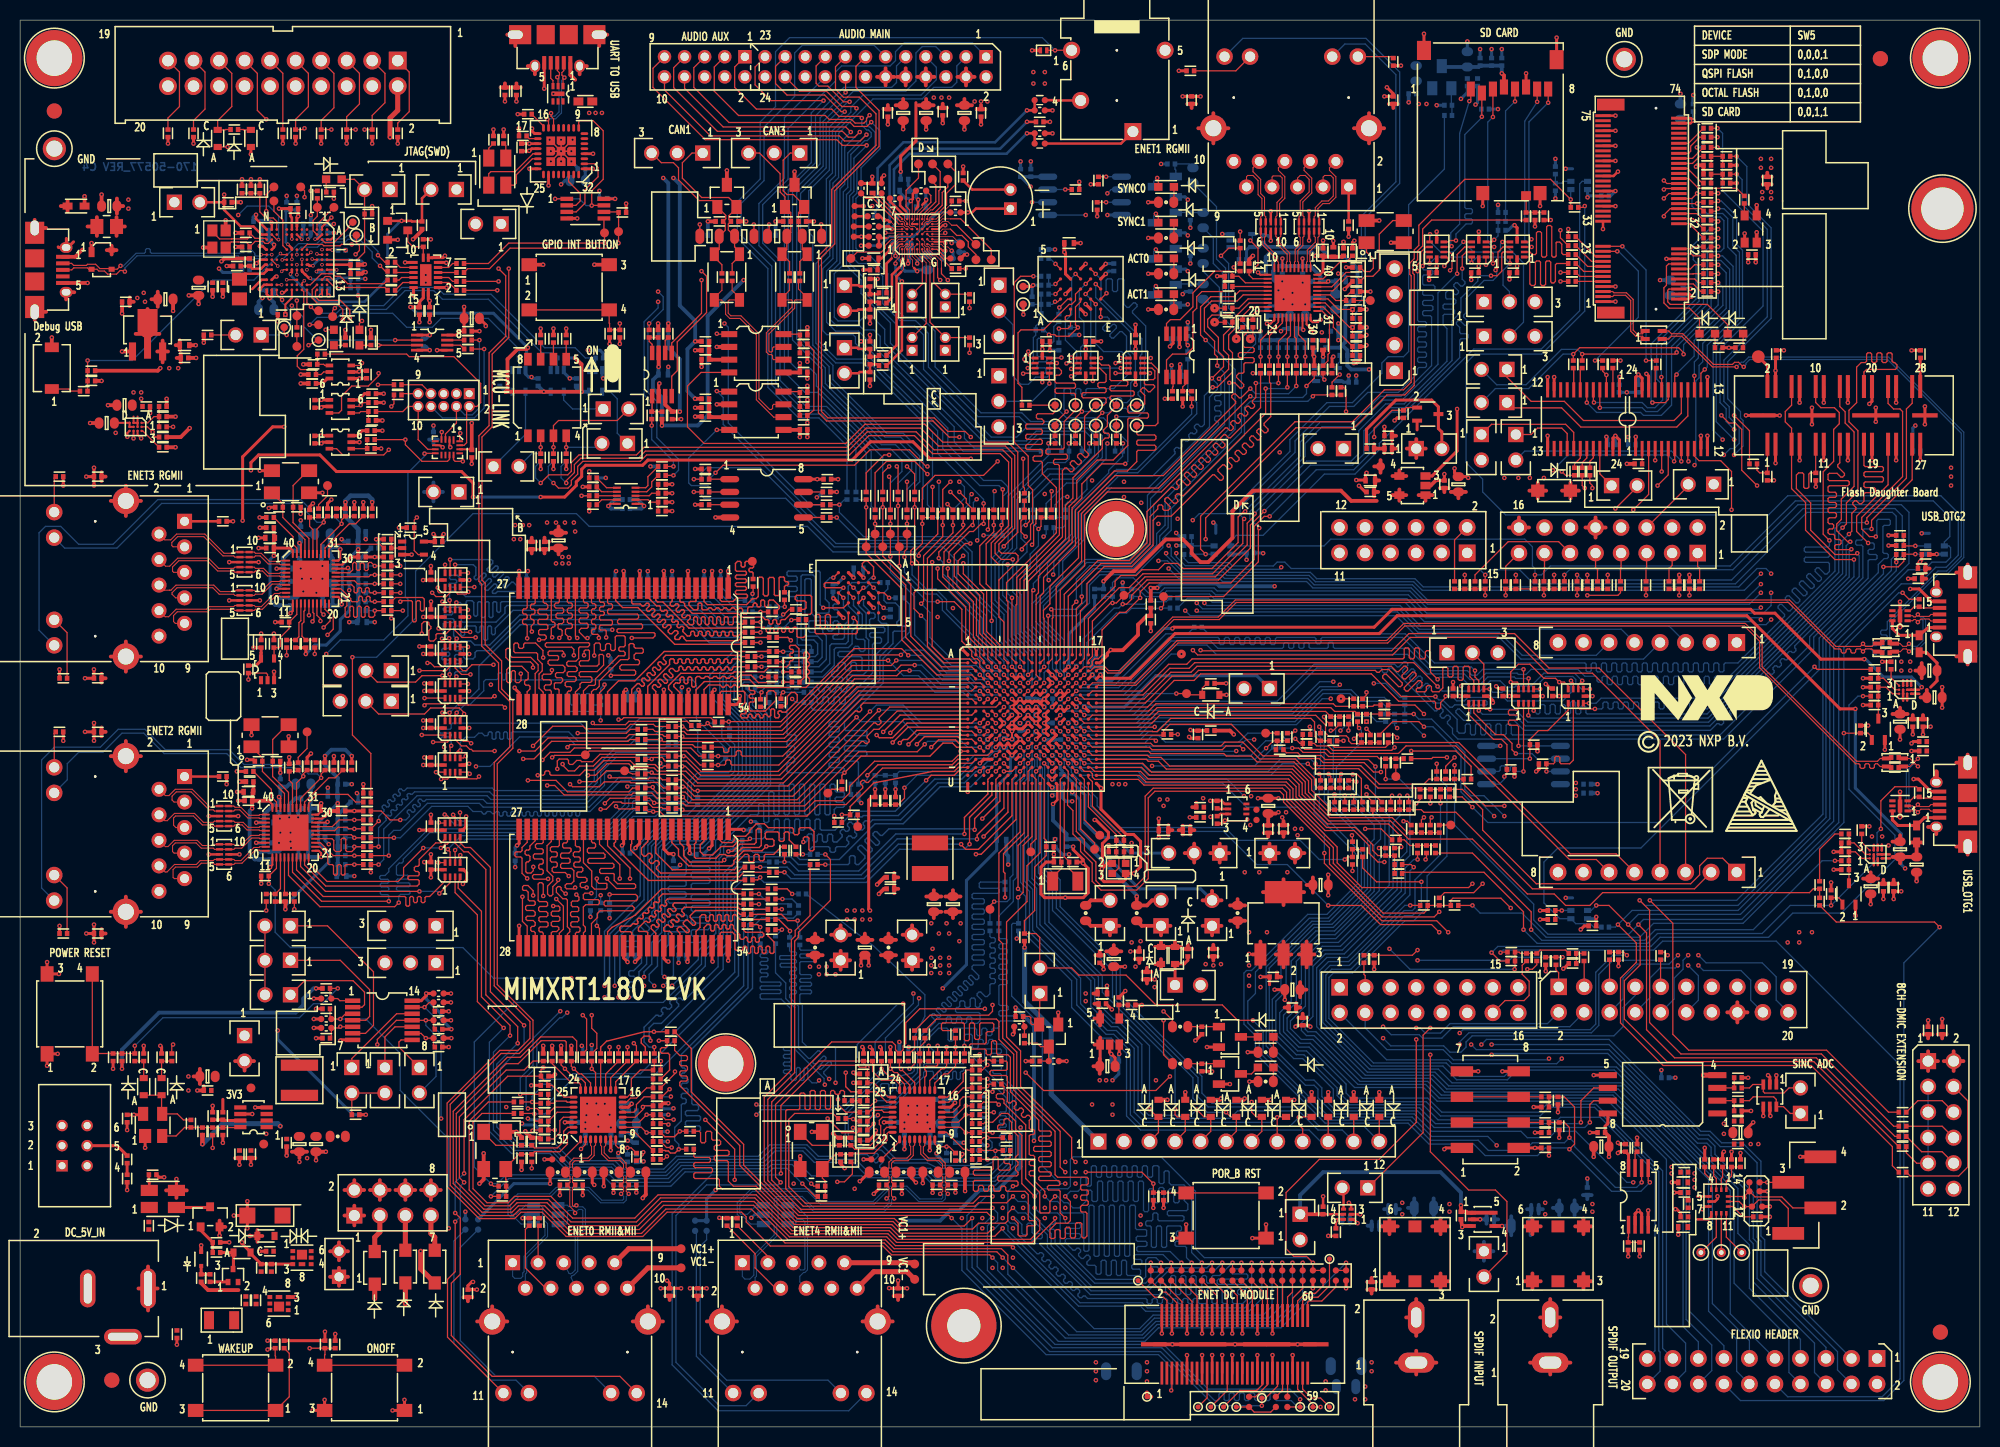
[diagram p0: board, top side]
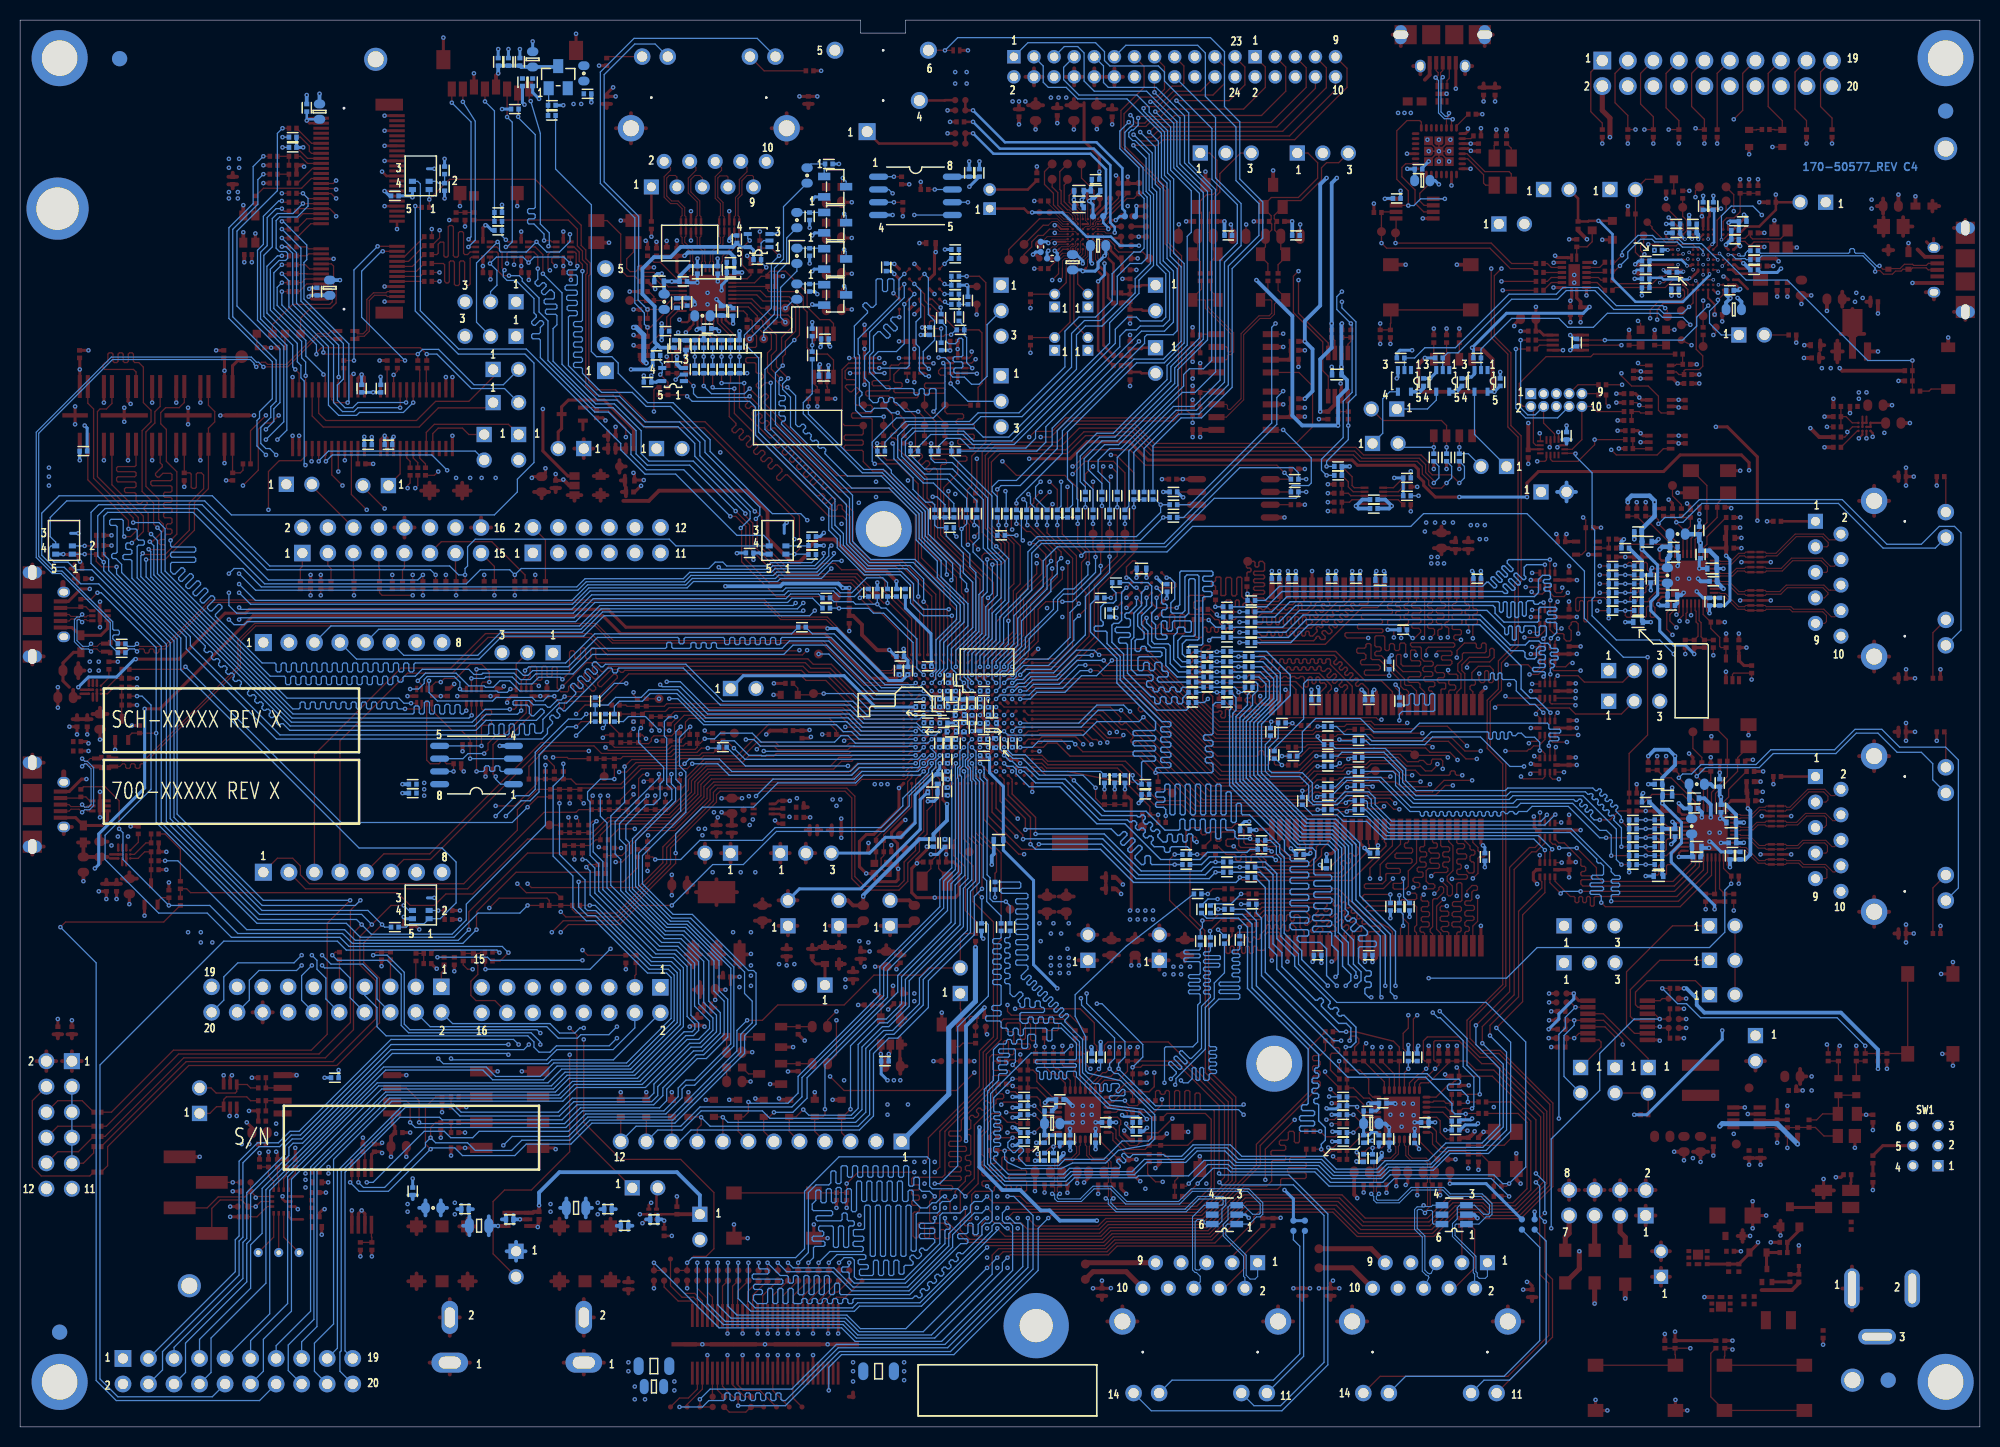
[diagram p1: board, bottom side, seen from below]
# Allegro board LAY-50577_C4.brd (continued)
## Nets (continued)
ENET1_RGMII_TX_EN: R882.1 U6.E12 U27.19
ENET1_RGMII_TXC: R881.1 U6.A14 U27.20
ENET1_RGMII_TXD0: R883.1 U6.E13 U27.18
ENET1_RGMII_TXD1: R884.1 U6.C12 U27.17
ENET1_RGMII_TXD2: U6.D13 U27.16
ENET1_RGMII_TXD3: U6.B14 U27.15
ENET1_RST_B: R2644.2 R2684.2 U410.2
ENET2_INT_B: R128.2 R517.2 R518.2 R1087.2
ENET2_MII_COL: R1169.2 R1311.1
ENET2_MII_CRS: R1309.1 R2133.2
ENET2_RGMII_RX_EN: R216.2 R516.2
ENET2_RGMII_RXC: C223.1 R219.2 R515.2
ENET2_RGMII_RXD0: R217.2 R514.2
ENET2_RGMII_RXD1: R218.2 R511.2
ENET2_RGMII_RXD2: R220.2 R512.2
ENET2_RGMII_RXD3: R221.2 R513.2
ENET2_RGMII_TXD2: R223.2 U29.16
ENET2_RGMII_TXD3: R222.2 U29.15
ENET2_RST_B: R522.2 R1018.1 U6.L16 U29.12
ENET3_INT_B: R111.2 R2697.2 U418.4(Y)
ENET3_INT_B_3V3: R570.2 R571.2 U418.2
ENET3_MII_COL: R1232.2 R1273.1
ENET3_MII_CRS: R1231.2 R1271.1
ENET3_RST_B: R114.2 R2696.2 U417.2
ENET3_RST_B_3V3: R575.2 R2695.2 U34.12 U417.4(Y)
ENET4_CARD_DET_B: J134.5 R2596.2
ENET4_CRS_DV: R250.2 R1289.1 R2614.1
ENET4_GPIO: R284.1 R2597.2 TP1061.1(PIN1)
ENET4_INT_B: R137.2 R1313.1 R2585.2 R2586.2
ENET4_RGMII_RX_EN: R274.2 R2614.2
ENET4_RGMII_RXC: R275.2 R2603.2
ENET4_RGMII_RXD0: R276.2 R2612.2
ENET4_RGMII_RXD1: R277.2 R2613.2
ENET4_RGMII_RXD2: R2605.2 R2618.2
ENET4_RGMII_RXD3: R2604.2 R2619.2
ENET4_RGMII_TX_EN: R273.2 R2610.2
ENET4_RGMII_TXC: R272.2 R2611.2
ENET4_RGMII_TXD0: R271.2 R2608.2
ENET4_RGMII_TXD1: R2576.2 R2609.2
ENET4_RGMII_TXD2: R2607.2 R2617.2
ENET4_RGMII_TXD3: R2606.2 R2616.2
ENET4_RST_B: R138.2 R295.2 R1288.1 R2587.2
ENET4_RXD0: R246.2 R1290.1 R2612.1
ENET4_RXD1: R248.2 R1291.1 R2613.1
ENET4_RXER: R252.2 R1292.1 R2615.1
ENET4_RXER_DC: J134.47 R2615.2 TP1060.1(PIN1)
ENET4_TX_REF_CLK: R244.2 R1293.1 R2611.1
ENET4_TXD0: R238.2 R1295.1 R2608.1
ENET4_TXD1: R240.2 R1296.1 R2609.1
ENET4_TXEN: R242.2 R1294.1 R2610.1
ENET4_TXER: J134.55 R2620.2 TP1062.1(PIN1)
ENET_INH: J134.49 R283.2
ENET_INH_B: J134.43 R280.2
ENET_REF_CLK: J134.4 TP1055.1(PIN1)
ETH2_CLK125_OUT: R519.2 TP25.1(TP)
EWM_OUT_B: C15.1 C569.1 R115.2 R2101.2 U361.9
FDC_ECC: J71.2 TP50.1(TP)
FLASH_RST: C573.1 R2104.2 R2158.2 U361.13
FLASH_VCC: C78.1 C82.1 C99.1 C100.1 C101.1 C102.1 C103.1 C104.1 C399.1 C471.1 C472.1 C473.1 C909.1 J71.3 J71.4 J71.27 J71.28 L2.2 R20.2 R264.1 R266.1 R270.1 R287.1 R288.1 R289.1 R290.1 R291.1 R292.1 R294.1 R1091.1 R1093.1 R2103.1 R2696.1 R2697.1 TP102.1(PIN1) U6.F9 U6.F10 U6.H12 U6.H13 U10.8 U11.B4 U11.C5 U11.D1 U11.E4 U12.8 U417.5
FLEXSPI1_A_CLK: TP67.1(PIN1) U6.A7 U69.7
FLEXSPI1_A_CLK_4: U12.6 U69.2
FLEXSPI1_A_CLK_8: R297.1 U69.4
FLEXSPI1_A_D0: TP69.1(PIN1) U6.A10 U70.8
FLEXSPI1_A_D0_4: U12.5 U70.1
FLEXSPI1_A_D0_8: U11.D3 U70.3
FLEXSPI1_A_D1: TP70.1(PIN1) U6.B9 U70.7
FLEXSPI1_A_D1_4: U12.2 U70.2
FLEXSPI1_A_D1_8: U11.D2 U70.4
FLEXSPI1_A_D2: TP71.1(PIN1) U6.A8 U71.8
FLEXSPI1_A_D2_4: R292.2 U12.3(W\P\_IO2) U71.1
FLEXSPI1_A_D2_8: U11.C4 U71.3
FLEXSPI1_A_D3: TP72.1(PIN1) U6.B8 U71.7
FLEXSPI1_A_D3_4: R291.2 U12.7 U71.2
FLEXSPI1_A_D3_8: U11.D4 U71.4
FLEXSPI1_A_D4: R117.2 TP73.1(PIN1) U11.D5
FLEXSPI1_A_D5: R119.2 TP74.1(PIN1) U11.E3
FLEXSPI1_A_D6: R121.2 TP75.1(PIN1) U11.E2
FLEXSPI1_A_D7: R123.2 TP76.1(PIN1) U11.E1
FLEXSPI1_A_DQS: R298.1 TP68.1(PIN1) U6.A6
FLEXSPI1_A_SS0: U6.D10 U69.8
FLEXSPI1_A_SS0_4: R290.2 U12.1 U69.1
FLEXSPI1_A_SS0_8: R296.1 R312.1 U69.3
FLEXSPI1_B_CLK: U6.E14 U66.7
FLEXSPI1_B_CLK_4: U10.6 U66.2
FLEXSPI1_B_CLK_8: J71.5 J71.6 U66.4
FLEXSPI1_B_D0: U6.F14 U67.8
FLEXSPI1_B_D0_4: U10.5 U67.1
FLEXSPI1_B_D0_8: J71.13 U67.3
FLEXSPI1_B_D1: U6.F16 U67.7
FLEXSPI1_B_D1_4: U10.2 U67.2
FLEXSPI1_B_D1_8: J71.14 U67.4
FLEXSPI1_B_D2: U6.G16 U68.8
FLEXSPI1_B_D2_4: R266.2 U10.3(W\P\_IO2) U68.1
FLEXSPI1_B_D2_8: J71.17 U68.3
FLEXSPI1_B_D3: U6.F17 U68.7
FLEXSPI1_B_D3_4: R264.2 U10.7 U68.2
FLEXSPI1_B_D3_8: J71.18 U68.4
FLEXSPI1_B_D4: J71.21 U6.H15
FLEXSPI1_B_D5: J71.22 U6.H14
FLEXSPI1_B_D6: J71.25 U6.G17
FLEXSPI1_B_D7: J71.26 U6.G13
FLEXSPI1_B_DQS: J71.10 R2157.2
FLEXSPI1_B_SS0: U6.F15 U66.8
FLEXSPI1_B_SS0_4: R270.2 U10.1 U66.1
FLEXSPI1_B_SS0_8: J71.9 R1091.2 U66.3
FLEXSPI2_A_CLK: R2131.2 U15.B2
FLEXSPI2_A_D0: R2123.2 U15.D3
FLEXSPI2_A_D1: R2126.2 U15.D2
FLEXSPI2_A_D2: R2127.2 U15.C4
FLEXSPI2_A_D3: R2130.2 U15.D4
FLEXSPI2_A_DQS: R333.2 U15.C3
FLEXSPI2_A_SS0: R332.2 U15.A3
FLEXSPI2_B_CLK: R2122.2 U15.B1
FLEXSPI2_B_D0: R2119.2 U15.D5
FLEXSPI2_B_D1: R2118.2 U15.E3
FLEXSPI2_B_D2: R2115.2 U15.E2
FLEXSPI2_B_D3: R2114.2 U15.E1
GPIO_AD_00: R867.1 R869.1 R1067.1 U6.N12
GPIO_AD_01: R868.1 R870.1 R1056.2 U6.R14
GPIO_AD_02: R100.1 R736.2 R871.1 R1064.1 U6.R13
GPIO_AD_03: R101.1 R733.2 R872.1 R1054.2 U6.R15
GPIO_AD_04: R102.1 R731.2 R874.1 R904.1 R1069.1 U6.P15
GPIO_AD_05: R103.1 R729.2 R873.1 R1059.2 U6.P13
GPIO_AD_06: J70.1 R104.1 R727.2 R747.1 R1066.1 U6.N13
GPIO_AD_07: R105.1 R135.1 R734.2 R749.1 R1057.2 U6.T17
GPIO_AD_08: J62.1 R106.1 R737.2 R1068.1 U6.T14
GPIO_AD_09: R107.1 R752.2 R760.1 R1058.2 U6.R16
GPIO_AD_10: R108.1 R136.1 R750.2 R1065.1 U6.R17
GPIO_AD_11: R1053.1 R1055.2 U6.P16
GPIO_AD_12: R109.1 R137.1 R730.2 R1073.1 U6.P17
GPIO_AD_13: R110.1 R138.1 R732.2 R1063.2 U6.N15
GPIO_AD_14: R112.1 R139.1 R1071.1 U6.N14
GPIO_AD_15: J70.2 R113.1 R140.1 R725.2 R1061.2 R2158.1 U6.N16
GPIO_AD_16: R116.1 R141.1 R1072.1 R2159.1 U6.N17
GPIO_AD_17: R118.1 R142.1 R1062.2 R2160.1 U6.M17
GPIO_AD_18: J70.5 R120.1 R143.1 R724.2 U6.K16
GPIO_AD_19: J70.6 R122.1 R726.2 U6.L13
GPIO_AD_21: R1049.1 R1089.1 U6.K15
GPIO_AD_22: R1051.1 R1090.1 U6.K12
GPIO_AD_30: R764.1 R1052.1 U6.L17
GPIO_AD_32: R124.1 R128.1 R144.1 U6.J17
GPIO_AD_33: R126.1 R146.1 R763.1 U6.J16
GPIO_AD_34: R148.1 R767.1 R1042.1 U6.J15
GPIO_AD_35: R130.1 R149.1 R735.1 U6.H17
GPIO_AON_00: R708.2 U6.F8
GPIO_AON_01: R710.2 U6.B7
GPIO_AON_02: R712.2 U6.B6
GPIO_AON_08: J70.4 R74.1 R723.2 U6.B1
GPIO_AON_09: J70.3 R76.1 R722.2 U6.A5
GPIO_AON_15: R79.1 R758.2 U6.B3
GPIO_AON_16: R80.1 R759.2 U6.C5
GPIO_AON_17: R1079.1 R1086.1 U6.D6
GPIO_AON_18: R1080.1 R1085.1 R1344.1 U6.E6
GPIO_AON_19: R81.1 R1084.1 R1087.1 U6.D5
GPIO_AON_20: R82.1 R1081.1 R1083.1 U6.E5
GPIO_AON_21: R83.1 R92.1 U6.F6
GPIO_AON_22: R84.1 R93.1 TP96.1(TP) U6.C3
GPIO_AON_23: R85.1 R94.1 TP97.1(TP) U6.C2
GPIO_AON_24: R86.1 R95.1 TP98.1(TP) U6.C1
GPIO_AON_25: R87.1 R96.1 R97.1 TP99.1(TP) U6.D2
GPIO_AON_26: R88.1 R98.1 TP100.1(TP) U6.C4
GPIO_AON_27: R89.1 R99.1 TP101.1(TP) U6.D3
GPIO_B1_12: R2639.1 R2643.1 U6.A11
GPIO_B1_13: R2640.1 R2644.1 U6.B11
GPIO_B2_00: R111.1 R125.1 R2641.1 U6.E9
GPIO_B2_01: R114.1 R127.1 R958.1 R2642.1 U6.E10
GPIO_B2_02: R115.1 R129.1 R1328.1 U6.C10
GPIO_B2_03: R117.1 R131.1 U6.D9
GPIO_B2_04: R119.1 R132.1 U6.C9
GPIO_B2_05: R121.1 R133.1 U6.A9
GPIO_B2_06: R123.1 R134.1 U6.E8
GPIO_BUTTON: C604.1 R2154.2 R2155.2 SW8.2 SW8.4
GPIO_EMC_B1_00: R151.1 R203.1 U6.H3
GPIO_EMC_B1_00_P: R203.2 U96.8
GPIO_EMC_B1_01: R152.1 R205.1 U6.H4
GPIO_EMC_B1_01_P: R205.2 U96.7
GPIO_EMC_B1_02: R153.1 R206.1 U6.K2
GPIO_EMC_B1_02_P: R206.2 U97.8
GPIO_EMC_B1_03: R154.1 R207.1 U6.G3
GPIO_EMC_B1_03_P: R207.2 U97.7
GPIO_EMC_B1_04: R155.1 R208.1 U6.J4
GPIO_EMC_B1_04_P: R208.2 U98.8
GPIO_EMC_B1_05: R156.1 R209.1 U6.H6
GPIO_EMC_B1_05_P: R209.2 U98.7
GPIO_EMC_B1_06: R157.1 R210.1 U6.K3
GPIO_EMC_B1_06_P: R210.2 U99.8
GPIO_EMC_B1_07: R158.1 R211.1 U6.M3
GPIO_EMC_B1_07_P: R211.2 U99.7
GPIO_EMC_B1_08: R159.1 R212.1 U6.H5
GPIO_EMC_B1_08_P: R212.2 U100.8
GPIO_EMC_B1_09: R160.1 R213.1 U6.E1
GPIO_EMC_B1_09_P: R213.2 U100.7
GPIO_EMC_B1_10: R161.1 R214.1 U6.E3
GPIO_EMC_B1_10_P: R214.2 U101.8
GPIO_EMC_B1_11: R162.1 R215.1 U6.F2
GPIO_EMC_B1_11_P: R215.2 U101.7
GPIO_EMC_B1_12: R959.1 R960.1 U6.G6
GPIO_EMC_B1_13: R163.1 R216.1 U6.F3
GPIO_EMC_B1_14: R1229.1 R1231.1 U6.G5
GPIO_EMC_B1_15: R1230.1 R1232.1 U6.G2
GPIO_EMC_B1_16: R164.1 R217.1 U6.H1
GPIO_EMC_B1_17: R165.1 R218.1 U6.E2
GPIO_EMC_B1_18: R166.1 U6.D1
GPIO_EMC_B1_19: R167.1 U6.F4
GPIO_EMC_B1_21: R168.1 R219.1 U6.K4
GPIO_EMC_B1_22: R169.1 R220.1 U6.L3
GPIO_EMC_B1_23: R170.1 R221.1 U6.F1
GPIO_EMC_B1_24: R171.1 R222.1 U6.P2
GPIO_EMC_B1_25: R172.1 R223.1 U6.N3
GPIO_EMC_B1_26: R173.1 R224.1 U6.N4
GPIO_EMC_B1_26_P: R224.2 U106.8
GPIO_EMC_B1_27: R174.1 R225.1 U6.J3
GPIO_EMC_B1_27_P: R225.2 U106.7
GPIO_EMC_B1_28: R175.1 R226.1 U6.F5
GPIO_EMC_B1_28_P: R226.2 U103.8
GPIO_EMC_B1_29: R176.1 R227.1 U6.E4
GPIO_EMC_B1_29_P: R227.2 U103.7
GPIO_EMC_B1_30_P: R177.1 R2114.1 R2116.1 U6.H2
GPIO_EMC_B1_31_P: R178.1 R2115.1 R2117.1 U6.J2
GPIO_EMC_B1_32_P: R179.1 R2118.1 R2120.1 U6.J1
GPIO_EMC_B1_33_P: R180.1 R2119.1 R2121.1 U6.K1
GPIO_EMC_B1_34_P: R181.1 R2122.1 R2124.1 U6.L2
GPIO_EMC_B1_35_P: R182.1 R2123.1 R2125.1 U6.L1
GPIO_EMC_B1_36_P: R183.1 R2126.1 R2128.1 U6.M1
GPIO_EMC_B1_37_P: R184.1 R2127.1 R2129.1 U6.N1
GPIO_EMC_B1_38_P: R185.1 R2130.1 R2132.1 U6.M2
GPIO_EMC_B1_39_P: R186.1 R332.1 U6.P1
GPIO_EMC_B1_40_P: R187.1 R333.1 R2133.1 U6.N2
GPIO_EMC_B1_41_P: R188.1 R1169.1 R2131.1 U6.R1
GPIO_EMC_B2_02: R1329.1 R1330.1 U6.P5
GPIO_EMC_B2_03: R2594.1 R2596.1 U6.T5
GPIO_EMC_B2_04: R2595.1 R2597.1 U6.R3
GPIO_EMC_B2_05: R189.1 R228.1 U6.T4
GPIO_EMC_B2_06: R190.1 R229.1 U6.T6
GPIO_EMC_B2_07: R191.1 R230.1 U6.T7
GPIO_EMC_B2_08: R192.1 R231.1 U6.U4
GPIO_EMC_B2_09: R193.1 R232.1 U6.U5
GPIO_EMC_B2_10: R194.1 R233.1 U6.U6
GPIO_EMC_B2_11: R195.1 R234.1 U6.P6
GPIO_EMC_B2_12: R196.1 R235.1 U6.R5
GPIO_EMC_B2_13: R198.1 R238.1 U6.R6
GPIO_EMC_B2_14: R200.1 R240.1 U6.N8
GPIO_EMC_B2_15: R201.1 R242.1 U6.R4
GPIO_EMC_B2_16: R202.1 R244.1 U6.R7
GPIO_EMC_B2_17: R204.1 R246.1 U6.U7
GPIO_EMC_B2_18: R248.1 TP13.1(TP) U6.P8
GPIO_EMC_B2_19: R250.1 U6.U8
GPIO_EMC_B2_20: R252.1 U6.R8
GPIO_SD_B1_00: J62.3 R64.2 R751.2 TP94.1(TP) U6.B16 U63.8
GPIO_SD_B1_01: J62.4 R757.2 TP95.1(TP) U6.D15 U63.7
GPIO_SD_B1_02: J62.6 R65.2 R755.2 U6.D14 U64.8
GPIO_SD_B1_03: J62.5 R756.2 U6.C15 U64.7
GPIO_SD_B1_04: U6.B15 U65.8
GPIO_SD_B1_05: U6.A16 U65.7
HP_DET_B: D46.1 J101.6 R2152.2
HPOUTL: C600.1 C602.1 L37.1 R2148.1 U369.B5
HPOUTL_ZOBEL: C600.2 R2150.1
HPOUTR: C601.1 C603.1 L38.1 R2149.1 U369.A5
HPOUTR_ZOBEL: C601.2 R2151.1
HW_VER_0: R828.1 R862.1 U55.E8
HW_VER_1: R827.1 R863.1 U55.A8
HW_VER_2: R826.1 R864.1 U55.F9
HW_VER_3: R825.1 R861.1 U55.B2
HW_VER_4: R824.1 R866.1 U55.M5
HW_VER_5: R823.1 R865.1 U55.H5
HW_VER_6: JP2.2 Q15.1 R829.1 U55.H9
HW_VER_7: JP4.2 R830.1 U55.N2 U58.5
I2C2_SCL_1V8: R689.1 R694.2 U126.4
I2C2_SDA_1V8: R688.1 R692.2 U126.5
I2C_SCL_ENET_ID: J134.54 R2579.1
I2C_SDA_ENET_ID: J134.52 R285.1
I3C2_PUR: J50.3 R142.2 R778.1
I3C2_SCL: J47.13 J50.1 R120.2 R776.2 R783.2 R784.1 R798.2 U46.13 U48.6
I3C2_SDA: J47.15 J50.2 R122.2 R775.2 R778.2 R782.2 R785.1 R801.2 U46.14 U48.5
IF_DETECT: J56.9 R840.2
IF_ISPEN: J56.7 R841.2
IF_RST: J56.10(B5) R835.2 U60.7
IF_SWCLK: J56.4 R831.2 U60.3
IF_SWDIO: J56.2 R833.2 U60.15
IF_TDI: J56.8 R832.2
IF_TDO_SWO: J56.6 R834.2 U60.11
IN3R: C592.2 U369.F6
INT1_COMBO: R1029.2 R1039.2 R1079.2
INT2_COMBO: R1030.2 R1040.2 R1080.2
JTAG_DACK: J37.19 R721.1
JTAG_DE: J37.17 R713.2
JTAG_NSRST: D26.C J37.15 R714.2
JTAG_NTRST: J37.3 R717.2 U6.B5
JTAG_RTCK: J37.11 R720.1
JTAG_TCK: J37.9 R719.1 U6.A2 U60.4
JTAG_TDI: J37.5 R716.2 U6.A3
JTAG_TDO: J37.13 U6.A4 U60.12
JTAG_TMS: J37.7 R715.2 U6.B2 U60.16
JTAG_VREF: J37.1 R718.2
LED_HEARTBEAT: TP46.1(PIN1) U55.C7
LED_OPT1: TP47.1(PIN1) U55.J9
LED_OPT2: TP48.1(PIN1) U55.G9
LED_SWO_ACT: TP45.1(PIN1) U55.B3
LED_USB_COMM: D29.C(CATHODE) U55.F12
LED_VCOM_ACT: D30.C(CATHODE) U55.B6
LPI2C2_SCL: R80.2 R1027.2 R1028.1 R1322.1 R2579.2 U369.F1
LPI2C2_SDA: R79.2 R285.2 R1026.2 R1032.2 R1321.1 U369.E2
LPSPI1_PCS0: R314.1 R2153.1 U6.C7
LPSPI1_SCK: R318.1 R2152.1 R2155.1 U6.B4
LPSPI1_SDI: R315.1 R1343.1 U6.C6
LPSPI1_SDO: R319.1 R1342.1 U6.E7
LPSPI6_CLK: R2168.1 R2640.2
LPSPI6_CS: R2169.1 R2639.2
LPSPI6_SDI: R2166.1 R2641.2
LPSPI6_SDO: R2635.1 R2642.2
LPUART1_RXD: R76.2 R848.1
LPUART1_TXD: R74.2 R1076.1
LPUART12_RXD: R82.2 R897.2 R1077.1 TP77.1(TP) U73.6
LPUART12_TXD: R81.2 R1078.1 TP78.1(TP) U73.5
MCU_DCDC_IN: C60.1 C61.1 C62.1 J12.2 R53.1 R54.2 R56.1 U6.L7 U6.M5 U6.M6 U6.M7 U6.M8
MCU_POWER_EN: R818.1 U55.M2
MICBIAS: C589.1 R2136.1 U369.A4
MICVDD: C582.1 R2134.2 U369.A3
NETC2_ECAT1_SEL: J72.2 U103.9 U106.9
NETC3_ECAT0_SEL: J73.2 U96.9 U97.9 U98.9 U99.9 U100.9 U101.9
NETC_ECAT_MDC: R397.2 R453.1 R504.1 R557.1 R1052.2 R1282.2 R2593.2 U121.22 U123.22
NETC_ECAT_MDIO: R396.2 R448.1 R502.1 R555.1 R1283.2 R2592.2 U6.K17 U121.23 U123.23
NVCC_BBSM: C39.1 J8.1 R31.1 R37.1 R42.1 R44.1 R47.1 U6.U11
NVCC_SD: C27.1 C28.1 R24.1 R25.1 R64.1 R65.1 R71.1 TP7.1(TP) U5.5
OCT_FLASH_RST_B: J93.2 J94.2 R293.1 R1094.1 R2103.2
OE_FLEXSPI1_A_EN: J59.2 U69.6 U70.6 U71.6
OE_FLEXSPI1_B_EN: J58.2 U66.6 U67.6 U68.6
OE_NETC2_ECAT1_EN: J65.2 U103.6 U106.6
OE_NETC3_ECAT0_EN: J63.2 U96.6 U97.6 U98.6 U99.6 U100.6 U101.6
OE_SD_SDIO_EN: J57.2 U63.6 U64.6 U65.6
ONOFF: C31.1 R31.2 SW2.2 SW2.4 U6.U10
OSC_25MHZ: R964.1 R1279.1
OTG1_DN: L16.2 R623.2 U6.E16
OTG1_DP: L16.3 R628.2 U6.E17
OTG2_DN: L19.2 R634.2 R691.1 U6.C16
OTG2_DP: L19.3 R637.2 R690.1 U6.C17
P_ENET4_VDDIO: J134.57 TP1063.1(PIN1)
PHY0_3V3: C476.1 L34.2 R1095.1 R1096.1
PHY0_AVDD33: C475.1 C478.1 R1095.2 U121.7 U121.30
PHY0_COL: R1273.2 U121.27
PHY0_CRS_DV: R1122.2 R1271.2 U121.26
PHY0_LED0_AD0/PMEB: J28.11 R1112.1 R1113.2 U121.24
PHY0_MDI0+: C176.1 J28.5 R391.2 U25.6(A6) U121.3
PHY0_MDI0-: C177.1 J28.6 R392.2 U25.4 U121.4
PHY0_MDI1+: C178.1 J28.1 R393.2 U25.1 U121.5
PHY0_MDI1-: C179.1 J28.2 R395.2 U25.3 U121.6
PHY0_RST_B: C182.1 R405.2 R408.1 R1274.2 U121.21
PHY0_RXC: R1259.2 U121.13
PHY0_RXD0: R1233.2 R1262.2 U121.9
PHY0_RXD1: R1102.2 R1103.1 R1234.2 R1263.2 U121.10
PHY0_RXD2_INTB: R1100.2 R1236.2 R1264.2 U121.11
PHY0_RXD3: R1104.1 R1105.2 R1265.2 U121.12
PHY0_RXDV: R1106.1 R1107.2 R1260.2 U121.8
PHY0_RXER/FXEN: R1108.2 R1109.1 R1235.2 R1261.2 U121.28
PHY0_TXC: R1240.2 R1266.2 U121.15
PHY0_TXD0: R1237.2 R1268.2 U121.16
PHY0_TXD1: R1238.2 R1269.2 U121.17
PHY0_TXD2: R1270.2 U121.18
PHY0_TXD3: R1272.2 U121.19
PHY0_TXEN: R1239.2 R1267.2 U121.20(TXEN)
PHY0_VDD33: C477.1 R391.1 R392.1 R393.1 R395.1 R396.1 R397.1 R408.2 R1096.2 R1100.1 R1102.1 R1105.1 R1107.1 R1108.1 R1113.1 R1117.1 R1119.2 U121.14
PHY0_XTAL1: C481.1 R1099.2 U121.31 X4.1
PHY0_XTAL2: C482.1 R964.2 R1331.2 R1332.2 U121.32 X4.3
PHY1_AVDD10: C189.1 C190.1 C191.1 C192.1 R470.2 U27.3 U27.8 U27.38
PHY1_AVDD33: C193.1 C194.1 C195.1 C196.1 R456.1 U27.11 U27.40
PHY1_CLK125_OUT: R466.2 TP24.1(TP)
PHY1_CT: C183.1 J29.1
PHY1_DVDD10: C197.1 C198.1 R468.2 U27.21
PHY1_DVDD33: C98.1 C187.1 C188.1 R434.1 R435.1 R436.1 R446.1 R450.1 R455.1 U27.29 U125.7(VCCB)
PHY1_DVDDRG: C199.1 C200.1 C523.1 R428.1 R429.1 R430.1 R431.1 R433.1 R444.1 R447.1 R451.1 R457.1 R1319.1 U27.28 U125.3
PHY1_LED0_CFG_EXT: R434.2 R437.1 U27.32
PHY1_LED1_CFGLDO0: J29.14 R435.2 R438.1 U27.33
PHY1_LED2_CFGLDO1: J29.12 R436.2 R439.1 U27.34
PHY1_RGMII_MDC: R451.2 U27.13 U125.4
PHY1_RGMII_MDIO: R447.2 U27.14 U125.5
PHY1_TRX0_N: J29.3 U26.2 U26.9 U27.2
PHY1_TRX0_P: J29.2 U26.1 U26.10(NC4) U27.1
PHY1_TRX1_N: J29.5 U26.5 U26.6 U27.5
PHY1_TRX1_P: J29.4 U26.4 U26.7 U27.4
PHY1_TRX2_N: J29.7 U27.7 U28.2 U28.9
PHY1_TRX2_P: J29.6 U27.6 U28.1 U28.10(NC4)
PHY1_TRX3_N: J29.9(TRD4-) U27.10 U28.5 U28.6
PHY1_TRX3_P: J29.8 U27.9 U28.4 U28.7
PHY1_XTALI: C185.1 U27.36 X1.3
PHY1_XTALO: C184.1 U27.37(XTAL_OUT/ EXT_CLK) X1.1
PHY2_AVDD10: C211.1 C212.1 C213.1 C214.1 R523.2 U29.3 U29.8 U29.38
PHY2_AVDD33: C215.1 C216.1 C217.1 C218.1 R509.1 U29.11 U29.40
PHY2_CT: C205.1 J30.1
PHY2_DVDD10: C219.1 C220.1 R521.2 U29.21
PHY2_DVDD33: C209.1 C210.1 R479.1 R480.1 R481.1 R501.1 R503.1 R508.1 U29.29
PHY2_DVDDRG: C221.1 C222.1 R472.1 R473.1 R474.1 R475.1 R476.1 R477.1 R510.1 U29.28
PHY2_LED0_CFG_EXT: R479.2 R492.1 U29.32
PHY2_LED1_CFGLDO0: J30.14 R480.2 R493.1 U29.33
PHY2_LED2_CFGLDO1: J30.12 R481.2 R494.1 U29.34
PHY2_RGMII_MDC: R503.2 R504.2 U29.13
PHY2_RGMII_MDIO: R501.2 R502.2 U29.14
PHY2_RGMII_TX_EN: U29.19 U103.1
PHY2_RGMII_TXC: U29.20 U103.2
PHY2_RGMII_TXD0: U29.18 U106.2
PHY2_RGMII_TXD1: U29.17 U106.1
PHY2_TRX0_N: J30.3 U29.2 U30.2 U30.9
PHY2_TRX0_P: J30.2 U29.1 U30.1 U30.10(NC4)
PHY2_TRX1_N: J30.5 U29.5 U30.5 U30.6
PHY2_TRX1_P: J30.4 U29.4 U30.4 U30.7
PHY2_TRX2_N: J30.7 U29.7 U31.2 U31.9
PHY2_TRX2_P: J30.6 U29.6 U31.1 U31.10(NC4)
PHY2_TRX3_N: J30.9(TRD4-) U29.10 U31.5 U31.6
PHY2_TRX3_P: J30.8 U29.9 U31.4 U31.7
PHY2_XTALI: C207.1 U29.36 X2.3
PHY2_XTALO: C206.1 U29.37(XTAL_OUT/ EXT_CLK) X2.1
PHY3_AVDD10: C233.1 C234.1 C235.1 C236.1 R576.2 U34.3 U34.8 U34.38
PHY3_AVDD33: C237.1 C238.1 C239.1 C240.1 R562.1 U34.11 U34.40
PHY3_CLK125_OUT: R572.2 TP26.1(TP)
PHY3_CT: C227.1 J31.1
PHY3_DVDD10: C241.1 C242.1 R574.2 U34.21
PHY3_DVDD33: C231.1 C232.1 R530.1 R531.1 R532.1 R554.1 R556.1 R561.1 U34.29
PHY3_DVDDRG: C243.1 C244.1 R524.1 R525.1 R526.1 R527.1 R529.1 R551.1 R563.1 U34.28
PHY3_LED0_CFG_EXT: R530.2 R543.1 U34.32
PHY3_LED1_CFGLDO0: J31.14 R531.2 R544.1 U34.33
PHY3_LED2_CFGLDO1: J31.12 R532.2 R545.1 U34.34
PHY3_RGMII_MDC: R556.2 R557.2 U34.13
PHY3_RGMII_MDIO: R554.2 R555.2 U34.14
PHY3_RGMII_RX_EN: R569.2 U101.2
PHY3_RGMII_RXC: C245.1 R568.2 U97.1
PHY3_RGMII_RXD0: R564.2 U100.2
PHY3_RGMII_RXD1: R566.2 U101.1
PHY3_RGMII_RXD2: R567.2 U98.1
PHY3_RGMII_RXD3: R565.2 U97.2
PHY3_RGMII_TX_EN: U34.19 U99.2
PHY3_RGMII_TXC: U34.20 U100.1
PHY3_RGMII_TXD0: U34.18 U98.2
PHY3_RGMII_TXD1: U34.17 U99.1
PHY3_RGMII_TXD2: U34.16 U96.2
PHY3_RGMII_TXD3: U34.15 U96.1
PHY3_TRX0_N: J31.3 U32.2 U32.9 U34.2
PHY3_TRX0_P: J31.2 U32.1 U32.10(NC4) U34.1
PHY3_TRX1_N: J31.5 U32.5 U32.6 U34.5
PHY3_TRX1_P: J31.4 U32.4 U32.7 U34.4
PHY3_TRX2_N: J31.7 U33.2 U33.9 U34.7
PHY3_TRX2_P: J31.6 U33.1 U33.10(NC4) U34.6
PHY3_TRX3_N: J31.9(TRD4-) U33.5 U33.6 U34.10
PHY3_TRX3_P: J31.8 U33.4 U33.7 U34.9
PHY3_XTALI: C229.1 U34.36 X3.3
PHY3_XTALO: C228.1 U34.37(XTAL_OUT/ EXT_CLK) X3.1
PHY4_3V3: C522.1 L36.2 R1284.1 R1285.1
PHY4_AVDD33: C519.1 C521.1 R1284.2 U123.7 U123.30
PHY4_COL: R1311.2 U123.27
PHY4_CRS_DV: R1289.2 R1309.2 U123.26
PHY4_LED0_AD0/PMEB: J32.12 R1170.2 R1171.1 U123.24
PHY4_MDI0+: C512.1 J32.5 R1278.2 U123.3 U124.6(A6)
PHY4_MDI0-: C514.1 J32.6 R1275.2 U123.4 U124.4
PHY4_MDI1+: C513.1 J32.1 R1277.2 U123.5 U124.1
PHY4_MDI1-: C511.1 J32.2 R1276.2 U123.6 U124.3
PHY4_RST_B: C517.1 R1281.1 R1288.2 R1312.2 U123.21
PHY4_RXC: R1297.2 U123.13
PHY4_RXD0: R1290.2 R1300.2 U123.9
PHY4_RXD1: R1174.2 R1175.1 R1291.2 R1302.2 U123.10
PHY4_RXD2_INTB: R1287.2 R1301.2 R1313.2 U123.11
PHY4_RXD3: R1180.2 R1181.1 R1303.2 U123.12
PHY4_RXDV: R1176.2 R1177.1 R1298.2 U123.8
PHY4_RXER/FXEN: R1178.1 R1179.2 R1292.2 R1299.2 U123.28
PHY4_TXC: R1293.2 R1304.2 U123.15
PHY4_TXD0: R1295.2 R1307.2 U123.16
PHY4_TXD1: R1296.2 R1306.2 U123.17
PHY4_TXD2: R1308.2 U123.18
PHY4_TXD3: R1310.2 U123.19
PHY4_TXEN: R1294.2 R1305.2 U123.20(TXEN)
PHY4_VDD33: C520.1 R1170.1 R1172.1 R1174.1 R1176.1 R1179.1 R1180.1 R1190.2 R1191.1 R1275.1 R1276.1 R1277.1 R1278.1 R1281.2 R1282.1 R1283.1 R1285.2 R1287.1 U123.14
PHY4_XTAL1: C516.1 R1280.2 U123.31 X6.1
PHY4_XTAL2: C515.1 R1279.2 R1333.2 R1334.2 U123.32 X6.3
PIO0_5-ISP_EN-LED_SWD_ACT: D39.C(CATHODE) JP3.2 R851.2 U55.A7
PMIC_ON_REQ: R15.2 R44.2 U6.U9
POR_CTL: C32.1 C562.1 R18.1 R34.2 R2098.2 SW3.2 SW3.4 U361.1
POR_PIN_RST_B: C36.1 C571.1 D26.A J88.2 J89.2 J90.2 J91.2 J92.2 R42.2 R2102.2 U6.T10 U361.11
QSPI0_OCT1_SEL_A: J75.2 U69.9 U70.9 U71.9
QSPI0_OCT1_SEL_B: R904.2 U66.9 U67.9 U68.9
RST_TGTMCU_B: C466.1 C565.1 J46.1 J62.2 R1041.2 R2099.2 SW7.2 SW7.4 U361.3
RXC_PHYAD1_1: R431.2 R443.1 R462.1 U27.27
RXC_PHYAD1_2: R475.2 R498.1 R515.1 U29.27
RXC_PHYAD1_3: R527.2 R550.1 R568.1 U34.27
RXCTL_PHYAD2_1: R432.1 R444.2 R463.1 U27.26
RXCTL_PHYAD2_2: R476.2 R499.1 R516.1 U29.26
RXCTL_PHYAD2_3: R528.1 R551.2 R569.1 U34.26
RXD0_RXDLY_1: R429.2 R441.1 R458.1 U27.25
RXD0_RXDLY_2: R473.2 R496.1 R514.1 U29.25
RXD0_RXDLY_3: R525.2 R548.1 R564.1 U34.25
RXD1_TXDLY_1: R428.2 R440.1 R460.1 U27.24
RXD1_TXDLY_2: R472.2 R495.1 R511.1 U29.24
RXD1_TXDLY_3: R524.2 R547.1 R566.1 U34.24
RXD2_PLLOFF_1: R433.2 R445.1 R459.1 U27.23
RXD2_PLLOFF_2: R477.2 R500.1 R512.1 U29.23
RXD2_PLLOFF_3: R529.2 R552.1 R567.1 U34.23
RXD3_PHYAD0_1: R430.2 R442.1 R461.1 U27.22
RXD3_PHYAD0_2: R474.2 R497.1 R513.1 U29.22
RXD3_PHYAD0_3: R526.2 R549.1 R565.1 U34.22
RXD232: U72.2 U73.3
RXLED: D37.2 U72.21
SAI1_MCLK: R86.2 R2140.1
SAI1_RX_BCLK: R88.2 R2138.2
SAI1_RX_SYNC: R89.2 R2139.2
SAI1_RXD[0]: J99.1 R87.2
SAI1_TX_BCLK: J98.1 R85.2
SAI1_TX_SYNC: J97.1 R84.2
SAI1_TXD[0]: J100.1 R83.2
SD1_CD_B: R140.2 R257.2
SD1_CLK: C95.1 R258.1 U63.4
SD1_CMD: J15.3 U63.3
SD1_D0: J15.7 U64.3
SD1_D1: J15.8 U64.4
SD1_D2: J15.1 U65.3
SD1_D3: J15.2 R260.1 U65.4
SD1_VSELECT: J135.2 R1042.2
SD_PWREN_B: R29.1 R139.2
SDIO0_SD1_SEL: J76.2 U63.9 U64.9 U65.9
SDRAM_3V3: C107.1 C108.1 C109.1 C110.1 C111.1 C112.1 C113.1 C114.1 C115.1 C118.1 C119.1 C120.1 C121.1 C122.1 C123.1 C124.1 C125.1 L9.2 R320.1 R336.1 U14.1 U14.3 U14.9 U14.14 U14.27 U14.43 U14.49 U16.1 U16.3 U16.9 U16.14 U16.27 U16.43 U16.49
SEMC_A0: R160.2 TP1065.1(TP) U14.23 U16.23
SEMC_A1: R161.2 U14.24 U16.24
SEMC_A2: R162.2 U14.25 U16.25
SEMC_A3: R959.2 U14.26 U16.26
SEMC_A4: R163.2 U14.29 U16.29
SEMC_A5: R1229.2 U14.30 U16.30
SEMC_A6: R1230.2 U14.31 U16.31
SEMC_A7: R164.2 U14.32 U16.32
SEMC_A8: R165.2 U14.33 U16.33
SEMC_A9: R166.2 U14.34 U16.34
SEMC_A10: R170.2 U14.22 U16.22
SEMC_A11: R167.2 U14.35 U16.35
SEMC_A12: U6.G1 U14.36 U16.36
SEMC_BA0: R168.2 TP1067.1(TP) U14.20 U16.20
SEMC_BA1: R169.2 U14.21 U16.21
SEMC_CAS: R171.2 U14.17 U16.17
SEMC_CKE: R174.2 R331.1 R338.1 U14.37 U16.37
SEMC_CLK: R173.2 R327.1 R337.1
SEMC_CS0: R176.2 R320.2 R336.2 U14.19 U16.19
SEMC_CSX0: R188.2 TP15.1(TP)
SEMC_D0: R151.2 TP1066.1(TP) U14.2
SEMC_D1: R152.2 U14.4
SEMC_D2: R153.2 U14.5
SEMC_D3: R154.2 U14.7
SEMC_D4: R155.2 U14.8
SEMC_D5: R156.2 U14.10
SEMC_D6: R157.2 U14.11
SEMC_D7: R158.2 U14.13
SEMC_D8: R177.2 U14.42
SEMC_D9: R178.2 U14.44
SEMC_D10: R179.2 U14.45
SEMC_D11: R180.2 U14.47
SEMC_D12: R181.2 U14.48
SEMC_D13: R182.2 U14.50
SEMC_D14: R183.2 U14.51
SEMC_D15: R184.2 U14.53
SEMC_D16: U6.N5 U16.2
SEMC_D17: U6.R2 U16.4
SEMC_D18: R1329.2 U16.5
SEMC_D19: R2594.2 U16.7
SEMC_D20: R2595.2 U16.8
SEMC_D21: R189.2 U16.10
SEMC_D22: R190.2 U16.11
SEMC_D23: R191.2 U16.13
SEMC_D24: R193.2 U16.42
SEMC_D25: R194.2 U16.44
SEMC_D26: R195.2 U16.45
SEMC_D27: R196.2 U16.47
SEMC_D28: R198.2 U16.48
SEMC_D29: R200.2 U16.50
SEMC_D30: R201.2 U16.51
SEMC_D31: R202.2 U16.53
SEMC_DM0: R159.2 U14.15
SEMC_DM1: R185.2 U14.39
SEMC_DM2: R192.2 U16.15
SEMC_DM3: R204.2 U16.39
SEMC_RAS: R172.2 U14.18 U16.18
SEMC_RDY: R187.2 TP14.1(TP)
SEMC_WE: R175.2 U14.16(W\E\) U16.16(W\E\)
SENSOR_3V3: C29.1 C76.1 C80.1 C81.1 C83.1 C84.1 C90.1 C91.1 C105.1 C106.1 C116.1 C117.1 C126.1 C272.1 C278.1 C288.1 C296.1 C297.1 C304.1 C305.1 C312.1 C317.1 C401.1 C402.1 C403.1 C404.1 C405.1 C406.1 C407.1 C408.1 C409.1 C410.1 C431.1 C432.1 C433.1 C434.1 C435.1 C436.1 C452.1 C455.1 C462.1 C463.1 C464.1 C465.1 C468.1 C469.1 C470.1 C581.1 C902.1 C908.1 C910.1 D25.A J3.1 J12.1 J23.2 J37.2 J44.16 J45.4 J45.8 J47.4 J51.1 J51.2 J57.1 J58.1 J59.1 J62.7 J63.1 J65.1 J67.1 J67.2 J69.1 J72.1 J73.1 J75.1 J76.1 J134.1 J134.3 JP6.1 L8.1 L9.1 L33.1 L34.1 L36.1 Q6.2(SOURCE) R20.1 R22.1 R26.1 R32.1 R33.1 R43.1 R51.1 R54.1 R256.1 R295.1 R313.1 R316.1 R317.1 R335.1 R339.1 R455.2 R456.2 R464.1 R469.1 R508.2 R509.2 R510.2 R517.1 R522.1 R561.2 R562.2 R563.2 R570.1 R575.1 R624.1 R627.1 R629.1 R635.1 R639.1 R640.1 R646.1 R655.1 R713.1 R715.1 R716.1 R717.1 R718.1 R772.2 R782.1 R783.1 R798.1 R800.1 R801.1 R877.1 R880.1 R887.1 R893.1 R897.1 R1026.1 R1027.1 R1033.1 R1036.1 R1038.1 R1039.1 R1040.1 R1041.1 R1044.2 R1045.1 R1047.2 R1314.1 R1315.1 R1316.1 R1338.1 R1340.1 R2101.1 R2104.1 R2113.1 R2134.1 R2154.1 R2585.1 R2695.1 TP51.1(PIN1) U6.F7 U6.J5 U6.J6 U6.K5 U6.L12 U6.M11 U6.N6 U6.N7 U13.8 U15.B4 U15.D1 U15.E4 U41.5(VIO) U42.5(VIO) U45.8(DVDD) U48.8 U63.10(VCC) U64.10(VCC) U65.10(VCC) U66.10(VCC) U67.10(VCC) U68.10(VCC) U69.10(VCC) U70.10(VCC) U71.10(VCC) U73.8(VCC) U96.10(VCC) U97.10(VCC) U98.10(VCC) U99.10(VCC) U100.10(VCC) U101.10(VCC) U103.10(VCC) U106.10(VCC) U115.1(VDD) U116.5(VDD) U117.5(VDD) U118.5(VDD) U119.5(VDD) U312.4(S2) U369.G3 U416.5 U418.5 Y3.3 Y3.4(VDD)
SINC2_EMBIT: R126.2 U45.6
SINC2_EMCLK: R124.2 U45.7
SINC2_MOD_CLK: R130.2 TP41.1(TP)
SINC_AGND: C303.2 C306.2 C307.2 C400.2 D28.1 D28.4 R770.1 U45.4
SINC_VDDA_5V: C303.1 C400.1 D28.2 D28.5(C2) L22.1 U45.1
SPDIF_BUF: R379.1 R381.2 U23.4(Y)
SPDIF_COAX_OUT: J27.2 T2.1
SPDIF_EXT_CLK: R112.2 TP18.1(TP)
SPDIF_GND_PRI: R380.2 R382.1 T2.4
SPDIF_IN: J25.1 R113.2
SPDIF_LOCK: R109.2 TP16.1(TP)
SPDIF_OUT: J26.2 R116.2
SPDIF_OUT_PRI: C169.2 R380.1 T2.6
SPDIF_SR_CLK: R110.2 TP17.1(TP)
SPDIF_VCC: C167.1 C168.1 J23.1 U22.5(VCC) U23.1 U23.5
SPI_FRM_1V8: J36.64 R2169.2
SPI_RXD_1V8: J36.40 J108.2 R2166.2 U43.14
SPI_TXD_1V8: J36.38 J108.1 R2635.2
SPK_LN: R2142.1 U369.B3
SPK_LP: R2144.1 U369.A1
SPK_RN: R2141.1 U369.C3
SPK_RP: R2143.1 U369.B2
TRG_FC0_RXD: R847.2 U55.E12
TRG_FC0_TXD: R846.2 U55.A11
TRG_FC1_RXD: R1075.2 U55.J7
TRG_FC1_TXD: R1074.2 U55.G6
TRG_RST: C567.1 R2100.2 U60.8 U361.5
TXD233: U72.30 U73.2
TXLED: D37.4(CATHODE2) U72.22
U_GPIO_0: R822.1 TP61.1(TP)
U_GPIO_1: TP53.1(TP) U55.C1(P1_9)
U_GPIO_2: TP54.1(TP) U55.H6
U_GPIO_3: TP55.1(TP) U55.M7
U_GPIO_4: R852.1 TP56.1(TP) U55.C2
U_GPIO_5: TP62.1(TP) U55.J5
USB_OTG1_ID: Q11.2 R107.2 R629.2 R632.2
USB_OTG1_OC: R625.1 R1053.2
USB_OTG1_PWR: R108.2 R630.1
USB_OTG2_ID: Q12.2 R106.2 R640.2 R643.2
USB_OTG2_OC: R104.2 R636.1
USB_OTG2_PWR: R105.2 R641.1
USB_SUSPEND_B: U72.9 U73.1 U73.7
USER_LED_CTL1: R35.2 U6.M16
USER_LED_CTL2: R36.2 U6.M14
V_TGTMCU: C387.1 C389.1 C391.1 C393.1 C394.1 C395.1 C397.1 J56.1 JP6.2 R838.1 R842.2 R849.1 R901.1 R902.1 R903.1 R2099.1 R2100.1 U56.6(VCCB) U57.6(VCCB) U58.8(VCCB) U59.6(VCCB) U60.14(VCC) U61.1 U61.7 U61.15
VLDO_3V3: C19.1 C20.1 R21.1 R40.1 U3.5
VREF: C351.1 R845.2 U55.G1 U55.H13
VSD_3V3: C30.1 C92.1 C93.1 C94.1 J15.4 Q6.3 R26.2 R805.1 R806.1
VTRG_FAULT_B: R814.2 R852.2 U52.A2
WAKE_IN_OUT: J134.51 R284.2
WAKEUP: C33.1 SW4.2 SW4.4 U6.T8
WALL_OV_BASE: Q3.1 R5.2
WALL_OV_CTL: D1.C(CATHODE) R3.2 R5.1
WALL_OVP_LED: D2.A Q3.3 R10.1
WIFI_LED1_B: D23.C(CATHODE) J36.6
WIFI_RST_B: R135.2 U43.3
WIFI_RST_B_1V8: R676.1 U43.21
WIFI_SDIO_CLK: R668.1 U63.2
WIFI_SDIO_CMD: R670.1 U63.1
WIFI_SDIO_D0: R671.1 U64.1
WIFI_SDIO_D1: R672.1 U64.2
WIFI_SDIO_D2: R673.1 U65.1
WIFI_SDIO_D3: R674.1 U65.2
WIFI_WAKE_B_1V8: R675.1 U44.3
WIFI_WAKE_B_3V3: J105.2 R136.2
WL_3V3: C283.1 C284.1 C285.1 C287.1 C289.1 C292.1 C525.1 J36.2 J36.4 J36.72 J36.74 L33.2 R662.1 R665.1 R666.2 R667.2 R705.1 R1323.1 R1324.1 U43.1 U44.23 U44.24(VCCB2) U126.7(VCCB)
WL_DEV_WAKE: R103.2 U43.10
WL_RST#: R118.2 R664.1
XTAL32M_N: C323.1 U55.M3 Y4.3
XTAL32M_P: C324.1 U55.N3 Y4.1
N99833017: J33.1(VBUS) L15.1 U38.6(VBUS)
N99833038: J33.2 L16.1 R623.1 U38.1
N99833048: J33.3 L16.4 R628.1 U38.2
N99833086: J33.4 R632.1 U38.3
N99838171: D25.C R714.1
N100054135: Q4.1 R10.2 R11.1
N100054243: C1.1 C2.1 J1.1 JP1.2 Q2.1 Q2.2 Q2.5 Q2.6 Q2.7 TVS1.2(A2)
N100054253: C4.2 D2.C Q2.3 R4.2 R8.1
N100054255: R8.2 R9.1
N100054257: R9.2 SW1.5
N100054263: F1.2 Q1.1 Q1.2 Q1.5 Q1.6 Q1.7 R1.1 R2.1
N100054299: C4.1 JP1.1 Q1.4 Q1.8(S2) Q2.4 Q2.8(S2) Q3.2(E) R1.2 R2.2 R3.1 R4.1
N100054525: D3.3 R7.2
N100054552: D3.1 R6.2
N100054568: D3.2 Q4.3
N100068040: C15.2 D5.C R19.1
N100068056: C10.1 R13.2 R15.1 R17.2 U1.8 U2.2
N100068060: C13.1 D4.C R18.2
N100068072: C5.1 C6.1 C7.1 R12.2 R13.1 U1.2(VIN)
N100068102: R14.2 R16.1 U1.7
N100068132: D4.A D5.A R17.1 U2.3
N100168474: C263.1 C264.1 R622.2 U37.B1 U37.B2 U37.C1(VINT3)
N100169105: Q11.3 R627.2 R630.2 R631.1 U37.A1
N100169932: J68.1(VBUS) L18.1 U40.6(VBUS)
N100169943: J68.2 L19.1 R634.1 U40.1
N100169951: J68.3 L19.4 R637.1 U40.2
N100169961: J68.4 R643.1 U40.3
N100171083: R635.2 R636.2 U39.A2
N100171101: C267.1 C268.1 R633.2 U39.B1 U39.B2 U39.C1(VINT3)
N100171150: Q12.3 R639.2 R641.2 R642.1 U39.A1
N100171345: R638.1 U39.A3
N100208849: C21.1 C22.1 R22.2 U4.3
N100211328: C23.1 C24.1 J4.2 U4.2(VOUT) U4.4
N100224476: L1.1 U1.3
N100310756: J5.1 Q5.1(SOURCE) R24.2 R27.1 U5.4
N100526107: TP12.1(TP) U6.G15
N100526140: C77.1 R71.2 U6.C13
N100538770: J135.1 Q5.2 R28.1
N100538772: J5.2 Q5.3 R25.2
N100728650: J15.9 R256.2 R257.1 R259.1
N100768470: C96.1 J15.5 R258.2
N100797217: R646.2 R647.2 R648.1 U41.8
N100797464: FL1.4 R649.1 U41.7
N100797616: FL1.3 R652.1 U41.6
N100798376: C274.1 R650.2 R651.1
N100979684: R21.2 R23.1 U3.4
N100999218: C203.1 C204.1 R468.1 R470.1 U27.30
N101003766: R465.1 U27.31
N101003882: C202.1 R466.1 U27.35
N101004896: R469.2 U27.12 U410.4(Y)
N101006850: J29.13 R449.1
N101006888: J29.11 R452.1
N101007093: R467.1 U27.39
N101069327: R37.2 SW4.1 SW4.3
N101094010: R327.2 U14.38
N101094248: R337.2 U16.38
N101142474: R624.2 R625.2 U37.A2
N101142476: R626.1 U37.A3
N101209734: D18.C J8.4 U6.P10
N101209737: D19.C J8.3 U6.R10
N101209778: D8.C D9.C J6.1 R41.1 R45.2
N101209809: C37.1 U6.T13 Y1.1
N101209834: C38.1 U6.U13 Y1.2
N101209892: TP8.1(TP) U6.T9
N101210175: C44.1 C45.1 L3.1 U6.J14
N101210568: D10.C J8.12 U6.R11
N101210571: D12.C J8.10 U6.R9
N101210574: D11.C J8.11 U6.N9
N101210577: D13.C J8.9 U6.M9
N101210580: D14.C J8.8 U6.P9
N101210583: D15.C J8.7 U6.N10
N101210586: D16.C J8.6 U6.M10
N101210589: D17.C J8.5 U6.L9
N101211681: R2161.1 U6.L8
N101211864: L5.1 U6.T1 U6.T2 U6.T3 U6.U2 U6.U3
N101211874: C68.1 C69.1 C70.1 C71.1 J14.2 L5.2 R59.2
N101211894: C64.1 R56.2 R57.1 U6.L5
N101213128: TP11.1(TP) U6.T15
N101213130: TP10.1(TP) U6.U15
N101213146: C73.1 D20.C TP9.1(TP) U6.J12
N101224368: C88.1 R186.2
N101241745: C270.1 C271.1 R644.2 U41.3
N101248699: R339.2 R341.2 U116.2
N101250307: C165.1 J24.2
N101250309: J24.1 T1.3
N101250379: R375.1 R376.2 U22.1
N101250387: C165.2 T1.1
N101250389: C166.1 R377.1 T1.6
N101250395: C166.2 R376.1
N101250397: R375.2 R378.1 U22.3 U22.6
N101250409: J25.2 U22.4
N101250428: J26.1 R381.1 U23.2
N101250468: J27.1 T2.3
N101293462: R343.1 R348.1 U116.1 U117.1
N101293775: R344.1 R350.1 U118.1 U119.1
N101343693: C74.1 R62.1 U6.U16 Y2.3
N101346492: C75.1 R62.2 U6.T16 Y2.1
N101370712: Q6.1 R29.2 R30.1
N101733751: D23.A R666.1
N101733753: D24.A R667.1
N101733765: J36.50 R686.2
N101733775: L21.2 R690.2
N101733777: L21.3 R691.2
N101733827: J36.5 L21.4
N101733829: J36.3 L21.1
N101733917: J36.58 R688.2
N101733919: J36.60 R689.2
N101734031: C282.1 R662.2 R663.1 R664.2
N101734037: J36.56 R663.2
N101734088: R705.2 U43.2
N101734122: C286.1 R665.2 R669.2 R679.1
N101734218: J36.54(W\_\D\I\S\A\B\L\E\2\) R679.2
N101734224: J36.23 R676.2
N101734331: J36.9 R668.2
N101734351: J36.11 R670.2
N101734355: J36.13 R671.2
N101734367: J36.15 R672.2
N101734379: J36.17 R673.2
N101734391: J36.19 R674.2
N101734410: J36.21 R675.2
N101734451: J36.36 R682.2
N101734453: J36.34 R681.2
N101734459: J36.32 R680.2
N101734471: J36.22 R678.2
N101734503: J36.20 R677.2
N101734640: J36.10 R684.2
N101734642: J36.12 R685.2
N101734644: J36.8 R683.2
N101734654: J36.14 R687.2
N101736970: R706.2 U44.2
N101753271: J78.1 U43.17
N101753274: J79.1 U43.16
N101754296: R701.2 U44.7
N101754314: R703.2 U44.8
N101754512: J80.1 U44.17
N101754515: J81.1 U44.16
N102038478: J39.6 R725.1
N102038480: J39.10 R730.1
N102038482: J39.12 R732.1
N102038508: J39.14 R734.1
N102038510: J39.16(B8) R737.1
N102038514: J39.2 R722.1
N102038516: J39.4 R723.1
N102038763: J39.8 R727.1
N102039011: J39.3 R728.1
N102039036: R728.2 R735.2 R738.1
N102040284: J44.2 R750.1
N102040286: J44.4 R752.1
N102040306: J44.10 R756.1
N102040308: J44.8 R755.1
N102040310: J44.12 R757.1
N102040312: J44.6 R751.1
N102040383: J44.18 R758.1
N102040397: J44.20 R759.1
N102051556: J44.5 R753.2
N102051558: J44.1 R746.2
N102051560: J44.3 R748.2
N102051598: J44.7 R760.2
N102051600: J44.9 R764.2
N102051892: C293.1 R746.1 R747.2 R1049.2
N102051905: C294.1 R748.1 R749.2
N102051907: C295.1 R753.1 R1051.2
N102052693: J41.12(B6) R724.1
N102052753: J41.2 R736.1
N102052757: J41.4 R733.1
N102052761: J41.6 R731.1
N102052765: J41.8 R729.1
N102052856: J41.10 R726.1
N102054567: J45.15 R869.2
N102054918: J45.3 R762.1
N102054920: J45.1 R766.1
N102054973: R765.1 R766.2 R767.2
N102055690: R761.1 R762.2 R763.2
N102055791: J45.5 R874.2
N102055814: J45.7 R873.2
N102055853: J45.9 R872.2
N102055876: J45.11 R871.2
N102055899: J45.13 R870.2
N102056178: D27.C J45.10
N102056760: J45.6 J46.2
N102196396: D6.C(CATHODE) Q7.3
N102196506: Q7.1 R35.1 R38.1
N102198352: D7.C(CATHODE) Q8.3
N102198373: Q8.1 R36.1 R39.1
N102544921: J11.2 L4.1
N102898927: R696.1 U44.20
N102898934: R697.1 U44.19
N102898941: R699.1 U44.18
N103179532: C526.1 J33.6 J33.7 J33.8 J33.9 R1325.1
N103179921: C527.1 J68.6 J68.7 J68.8 J68.9 R1326.1
N103596184: C63.1 R53.2 R55.1 U6.L6
N103598440: C65.1 C66.1 C72.1 J77.1 R58.1 U6.M4
N103602996: R655.2 R656.2 R657.1 U42.8
N103603009: FL2.4 R658.1 U42.7
N103603017: FL2.3 R661.1 U42.6
N103603047: C280.1 R659.2 R660.1
N103609194: R2156.2 U11.B1
N103609206: R299.2 U11.A5
N103609208: R303.2 U11.A2
N103609210: R308.2 U11.A3
N103609334: R289.2 R303.1 R308.1 R312.2
N103609361: R288.2 R296.2 U11.C2
N103609367: R287.2 R293.2 U11.A4
N103609386: R298.2 U11.C3
N103609426: R297.2 U11.B2
N103609440: R294.2 R299.1
N103749857: C225.1 C226.1 R521.1 R523.1 U29.30
N103749903: R518.1 U29.31
N103749907: C224.1 R519.1 U29.35
N103750002: J30.13 R505.1
N103750008: J30.11 R506.1
N103750009: R520.1 U29.39
N103753894: C247.1 C248.1 R574.1 R576.1 U34.30
N103753940: R571.1 U34.31
N103753944: C246.1 R572.1 U34.35
N103754039: J31.13 R558.1
N103754045: J31.11 R559.1
N103754046: R573.1 U34.39
N103789758: R316.2 U13.7
N103789768: R318.2 U13.6
N103789772: R319.2 U13.5
N103789774: R317.2 U13.3(W\P\)
N103789776: R313.2 R314.2 U13.1
N103789794: R315.2 U13.2
N103834887: J51.3 J51.4 R784.2
N103834897: J51.5 J51.6 R785.2
N103889850: J47.20
N103889851: J47.19
N103909102: C308.1 C309.1 R771.1 U46.8
N103909121: R777.2 U46.12
N103909127: R774.2 R779.1 U46.1
N103909137: R773.1 U46.4
N103909149: TP42.1(PIN1) U46.11
N103909150: TP43.1(PIN1) U46.10
N103909151: TP44.1(PIN1) U46.9
N103909152: R780.2 U46.2
N103909154: R781.2 U46.3
N103911488: D28.6 J49.1 R768.1
N103911494: D28.3 J49.2 R769.1
N103911836: C307.1 R768.2 U45.2
N103911844: C306.1 R769.2 U45.3
N103961253: R812.2 U55.N6
N103961260: R813.2 U55.M6
N103961264: R811.1 R850.2 U55.N8
N103961315: C326.1 R808.2 R809.1 U55.J6
N103961319: C352.1 C355.1 C356.1 L23.2 U55.M9 U55.N9
N103961455: L23.1 U55.N11
N103961642: R809.2 SW6.1
N103961796: C350.1 R844.2 U55.G2
N103962355: J53.6 J53.7 J53.8 J53.9 L25.2
N103962365: J53.1(VBUS) L24.1 U51.4(VCC)
N103962432: J53.2 R812.1 U51.3
N103962456: J53.3 R813.1 U51.2
N103962999: R815.1 U52.A3
N103963079: R816.2 R817.1 R818.2 U52.A1
N104012170: JP7.2 R821.1
N104016532: R831.1 U58.7
N104016534: R832.1 U58.6
N104016623: R835.1 R902.2 U57.4
N104016749: R833.1 R903.2 U59.4
N104016751: R834.1 R901.2 U56.4
N104017363: JP5.2 R842.1 U60.2
N104034773: R846.1 U61.14
N104034775: R847.1 U61.13
N104034777: R848.2 U61.3
N104034811: Q15.3 R849.2 U61.9
N104034835: R1078.2 U61.6
N104105294: D30.A R854.2
N104105296: D29.A R853.2
N104315925: C276.1 C277.1 R653.2 U42.3
N104599012: D31.C(CATHODE) Q19.3
N104599036: Q19.1 R875.1 R876.1
N104599080: D32.C(CATHODE) Q20.3
N104599094: Q20.1 R878.1 R879.1
N104600982: D33.C(CATHODE) Q21.3
N104600995: Q21.1 R885.1 R886.1
N104601399: D35.C(CATHODE) Q23.3
N104601413: Q23.1 R891.1 R892.1
N104649727: R804.2 U48.7(WP)
N104649749: R800.2 R803.1 U48.1
N104653681: J60.1(VBUS) L29.2 U74.6(VBUS)
N104654018: C528.1 J60.6 J60.7 J60.8 J60.9 R1327.1
N104654056: J60.4 U74.3
N105054073: J67.3 J67.5 J67.7 J67.9 R1021.1
N105054132: J67.4 R1022.2
N105054134: J67.6 R1023.2
N105054136: J67.8 R1024.2
N105054138: J67.10 R1025.2
N105070687: R1028.2 U115.5
N105070691: R1033.2 U115.7
N105070693: R1034.1 U115.9
N105070700: R1035.1 R1036.2 U115.2
N105070744: R1029.1 U115.8
N105070750: R1030.1 U115.6
N105070826: R1031.1 R1038.2 U115.3
N105070844: R1032.1 U115.4
N105164696: R1043.1 R1044.1 U117.2
N105165362: R1045.2 R1046.2 U118.2
N105165453: R1047.1 R1048.1 U119.2
N105216901: J69.3 R1067.2
N105216903: J69.5 R1064.2
N105216905: J69.7 R1069.2
N105216907: J69.9 R1066.2
N105216909: J69.11 R1068.2
N105216911: J69.13 R1065.2
N105216913: J69.15 R1073.2
N105216915: J69.17 R1071.2
N105216917: J69.19 R1072.2
N105217449: J69.4 R1056.1
N105217451: J69.6 R1054.1
N105217453: J69.8 R1059.1
N105217455: J69.10 R1057.1
N105217467: J69.12 R1058.1
N105217469: J69.14 R1055.1
N105217471: J69.16 R1063.1
N105217473: J69.18 R1061.1
N105217475: J69.20 R1062.1
N105256205: R1074.1 U61.12
N105256208: R1075.1 U61.11
N105257045: R1076.2 U61.4
N105257114: R1077.2 U61.5
N105291076: JP7.1 U55.L13
N105373803: D39.A R1088.2
N105401122: J71.1 R1093.2 R1094.2
N105406651: D41.C J1.3
N105406660: D42.C J1.5
N105406670: D43.C J1.7
N105488843: R686.1 Y3.1
N105541476: C479.1 U121.2
N105544244: R1097.2 U121.1
N105551352: C480.1 U121.29
N105554209: C170.1 J28.4
N105554214: C180.1 J28.3
N105554264: J28.9 TP1068.1(TP)
N105572670: J32.11 R1191.2
N105572737: C507.1 J32.4
N105572739: C508.1 J32.3
N105593482: J32.13 R1190.1
N105605244: C518.1 U123.2
N105605262: C510.1 U123.29
N105605885: R1286.2 U123.1
N105847330: R446.2 R448.2 U125.8
N105847333: R450.2 R453.2 U125.1
N105847380: R1319.2 U125.6
N105851215: R1321.2 R1324.2 U126.8
N105851217: R1322.2 R1323.2 U126.1
N105851251: R1320.2 U126.6
N105870078: R1316.2 SW5.5(B4)
N105870081: R1315.2 SW5.6
N105870084: R1314.2 SW5.7
N106014504: C530.1 R1339.2 U312.2
N106014760: R1338.2 U312.5 U312.6
N106191377: J102.1 U362.4(Y)
N106191386: J104.1 U366.4(Y)
N106191553: J103.1 U365.4(Y)
N106192914: C578.1 R1900.1 R2113.2 U356.3(VCC)
N106192924: C577.1 J92.1 R1900.2 R2090.2 U356.2
N106193141: J90.1 U361.2
N106193157: J91.1 U361.6
N106193171: J93.1 U361.10
N106193408: J94.1 U361.12(O)
N106193418: J88.1 U361.4
N106193455: J89.1 U361.8
N106204967: TP1024.1(TP) U369.C4
N106204969: C593.1 U369.D4
N106205008: TP1025.1(TP) U369.D5
N106205010: TP1026.1(TP) U369.E5
N106205029: C592.1 P2.1(OUT) R2136.2
N106205042: TP1027.1(TP) U369.F5
N106205065: TP1028.1(TP) U369.E6
N106205067: P2.2 R2137.1
N106205081: TP1029.1(TP) U369.E7
N106205130: J98.2 R2138.1 U369.E1
N106205151: J97.2 R2139.1 U369.D3
N106205159: J100.2 U369.D1
N106205163: J99.2 U369.D2
N106205177: R2140.2 U369.G7
N106205193: TP1030.1(TP) U369.F7(XTO)
N106205804: C594.2 C596.1 J95.1 R2141.2
N106205806: C595.2 C597.1 J96.1 R2142.2
N106205931: C596.2 C598.1 J95.2 R2143.2
N106205933: C597.2 C599.1 J96.2 R2144.2
N106205994: TP1022.1(TP) U369.E4
N106206003: TP1023.1(TP) U369.F4
N106206005: R2146.1 U369.G1
N106206024: R2145.1 U369.E3
N106206063: TP1031.1(TP) U369.G6
N106206071: C588.1 U369.C5
N106207432: J101.4 L37.2
N106207455: J101.1 L38.2
N106207457: R2147.1 U369.B4
N106348035: R2157.1 U6.E15
N106559790: J28.13 R1119.1
N106561451: J28.12 R1118.2
N106615195: R335.2 U15.A4
N106641917: J105.1 U44.21
N107062928: R464.2 R465.2 U416.2
N107431729: J28.10(VC1-) TP1069.1(TP)
N107431851: J32.10(VC1-) TP1071.1(TP)
N107431853: J32.9 TP1070.1(TP)
N107755006: J134.19 TP1056.1(PIN1)
N107755030: J134.27 TP1057.1(PIN1)
N107755069: J134.41 TP1058.1(PIN1)
N107755071: R280.1 R283.1 TP1059.1(PIN1)
N107755107: J134.56 R2586.1
N107755114: J134.58 TP1064.1(PIN1)
N107755120: C887.1 J134.59 R2584.2
N107755122: J134.60 R2587.1
N999437150: D6.A R32.2
N1021983941: D7.A R33.2
N1038045711: C169.1 R379.2
N1045989930: D31.A R877.2
N1045991261: D32.A R880.2
N1046010301: D33.A R887.2
N1046013920: D35.A R893.2

Pads without a net: J28 7 8; J32 7 8; J36 35 37 41 43 47 49 52 53 55 59 61 62 65 66 67 68 70 71 73; J39 1 5 7 9 11 13 15; J41 5 7 9 11; J45 2; J53 4; J134 7 9 13 15 23 31 35 37; SW1 1 2 4; SW5 1 8; U11 B5; U14 40; U15 A2 A5 B5 C2 C5; U16 40; U25 5; U38 4 5; U40 4 5; U44 9 10 14 15; U55 A1 A2 A6 A12 B7 B12 E1 E2 E5 E7 F1 F2 F6 G3 G5 G12 G13 H8 H12 J1 J2 J8 J12 L2 L7 M8; U60 1 5 9 10 13; U72 3 5 6 7 8 10 11 12 13 23 25 27 28 29 31 32; U74 4 5; U124 5; U362 1; U365 1; U366 1; U410 1; U416 1; U417 1; U418 1

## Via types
v1: diameter 0.457, hole 0.203, TOP to BOTTOM, 2466 vias
v2: diameter 0.457, hole 0.206, TOP to BOTTOM, 123 vias
v3: diameter 0.356, hole 0.206, TOP to BOTTOM, 6 vias
v4: diameter 0.356, hole 0.203, TOP to BOTTOM, 27 vias

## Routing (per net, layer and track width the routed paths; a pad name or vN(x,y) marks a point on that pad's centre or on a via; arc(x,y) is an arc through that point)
5V_SDA_PSW: length 120
  TOP w0.203: C365.1 9.36,99.92 U52.D1 U52.D2 U52.C2
  TOP w0.508: v1(39.86,17.48) 39.86,15.73 D43.A
  L3_INT_1 w0.508: v1(39.86,17.48) 34.14,17.48 28.43,23.19 20.43,23.19 17,26.62 11.92,26.62 8.49,30.05 8.49,38.43 18.01,47.96 18.01,91.65 13.82,95.84 12.17,95.84 9.51,98.5 v1(9.51,98.92)
5V_SYS: length 116.9
  TOP w0.081: U369.C2 88.76,117.56 88.51,117.31 88.51,116.4 88.8,116.11 88.8,115.47 88.94,115.34
  TOP w0.127: v1(87.1,116.54) 87.1,117.25 87.55,117.7 U369.A2
  TOP w0.254: v1(89.26,115.01) 88.94,115.34
  TOP w0.305: v1(190.09,69.68) R633.1 v1(189.34,68.91) ; v1(14.33,24.84) 13.82,24.84 R7.1 ; v1(186.42,52.53) R622.1 v1(187.17,53.3) ; C17.1 107.46,35.93 U3.1 ; U3.3 v1(109.36,37.11)
  TOP w0.381: J45.16 150.14,89.5 ; J45.16 148.13,89.5 ; J45.16 149.14,90.51 ; J47.10 88.12,135.2 ; J47.10 88.12,133.5 ; J47.10 87.27,134.35 ; 87.86,132.15 C300.1 87.12,131.52 ; 38.33,22.6 J1.6 ; J1.6 38.33,24.55 ; J1.6 37.36,23.57 ; J1.6 39.31,23.57 ; 139.15,92.73 U5.1 ; U5.1 139.84,92.17 ; U5.1 140.52,92.73 ; 106.9,38.05 U3.1 107.46,38.73 ; C25.1 143.86,93.04 ; C25.1 142.36,93.04 ; C25.1 143.11,92.42 ; 86.12,133.5 J47.12 ; J47.12 86.12,135.2 ; J47.12 85.27,134.35 ; J47.12 86.97,134.35 ; 150.17,93.17 D27.A ; D27.A 151.01,93.96 ; D27.A 151.01,92.38 ; D27.A 151.85,93.17 ; R653.1 v1(67.17,108.03) ; J1.4 35.79,24.55 ; J1.4 36.77,23.57 ; J1.4 34.82,23.57 ; J1.4 35.79,22.6 ; C17.1 107.42,36.64 ; C17.1 107.42,35.14 ; C17.1 106.8,35.89 ; R644.1 v1(67.16,102.31) ; 141.71,93.02 C26.1 ; C26.1 142.15,93.43 ; C26.1 141.28,93.43 ; J1.2 34.23,23.57 ; J1.2 32.28,23.57 ; J1.2 33.25,24.55 ; 40.87,22.6 J1.8 ; J1.8 41.85,23.57 ; J1.8 40.87,24.55 ; J1.8 39.9,23.57 ; C301.1 86.77,131.14 ; C301.1 86.34,131.54 ; C301.1 85.91,131.14
  L3_INT_1 w0.381: v1(87.1,116.54) 87.61,117.05 87.61,120.6 86.72,121.49 v1(84.79,121.49) ; 155.56,54.17 J70.7 ; J70.7 155.56,56.23 ; J70.7 154.53,55.2 ; J70.7 156.59,55.2
  L4_PWR_1 w0.381: 88.12,133.5 J47.10 ; J47.10 87.27,134.35 ; J47.10 88.12,135.2 ; J47.10 88.97,134.35 ; J1.6 38.33,24.55 ; J1.6 37.36,23.57 ; J1.6 39.31,23.57 ; J1.6 38.33,22.6 ; 40.87,22.6 J1.8 ; J1.8 40.87,24.55 ; J1.8 39.9,23.57 ; J1.8 41.85,23.57 ; 32.28,23.57 J1.2 ; J1.2 33.25,22.6 ; J1.2 33.25,24.55 ; J1.2 34.23,23.57 ; 86.12,133.5 J47.12 ; J47.12 86.12,135.2 ; J47.12 86.97,134.35 ; J47.12 85.27,134.35 ; 35.79,22.6 J1.4 ; J1.4 34.82,23.57 ; J1.4 35.79,24.55 ; J1.4 36.77,23.57
  BOTTOM w0.305: C580.1 86.98,116.66 v1(87.1,116.54) 87.74,115.9 87.74,115.32 88.04,115.01 v1(89.26,115.01) 89.39,115.14 C579.1 ; v1(108.69,34.5) 109.32,35.12 C18.1 109.32,37.07 v1(109.36,37.11)
  BOTTOM w0.381: v1(65,124.28) 65.64,123.65 65.64,111.58 67.17,110.05 v1(67.17,108.03) 66.4,107.26 66.4,103.08 v1(67.16,102.31)
  vias: v1(107.42,34.5) v1(108.06,34.5) v1(132.82,2.75) v1(133.84,4.02) v1(133.84,2.75) v1(147.68,94.44) v1(149.08,94.44) v1(150.22,94.44) v1(151.62,94.44) v1(172.19,28.15) v1(172.95,28.15) v1(192.13,95.46) v1(192.13,94.57) v1(192.13,93.68)
5V_USB_OTG1: length 305.6
  TOP w0.254: U37.C2 U37.D2 186.04,56.97 ; U37.D1 186.06,56.57
  TOP w0.305: U6.D17 v2(107.49,74.84) 107.83,74.5 110.47,74.5 114.92,78.95 135.24,78.95 137.01,80.72 171.81,80.72 181.08,71.45 v1(182.61,71.45)
  TOP w0.381: L15.2 189.24,58.16 ; L15.2 188.17,58.16 ; L15.2 C364.1 C361.1 ; C361.1 186.3,56.72 ; C361.1 187.05,56.1
  TOP w0.508: D41.A v1(35.29,12.78)
  L3_INT_1 w0.508: v1(35.29,12.78) 35.79,13.29 41.13,13.29 46.05,18.2 90.52,18.2 92.01,16.72 93.76,16.72 95.99,14.48 101.5,14.48 110.53,23.51 122.35,23.51 125.08,26.24 143.62,26.24 145.9,23.95 157.21,23.95 164.95,16.21 173.34,16.21 185.85,28.72 185.85,50.56 187.94,52.66 187.94,55.2 v1(187.56,55.58)
  BOTTOM w0.305: v1(182.61,71.45) 182.61,63.58 187.18,59.01 187.18,55.96 v1(187.56,55.58)
5V_USB_OTG2: length 315.8
  TOP w0.254: 188.96,73.36 U39.D2 U39.C2 ; U39.D1 188.98,72.96
  TOP w0.305: 190.1,73.61 190.73,74.25 C363.1 190.73,76.02 189.68,77.08 L18.2 ; v1(183.5,76.41) 179.18,76.41 174.61,80.98 172.57,80.98 172.19,81.36 136.51,81.36 134.73,79.58 114.79,79.58 v1(114.66,79.45) ; U6.D16 v2(106.69,74.84)
  TOP w0.381: 189.1,72.6 C362.1 189.72,73.35
  TOP w0.508: D42.A v1(38.33,12.27)
  L3_INT_1 w0.381: 189.21,72.02 v1(189.21,73.61)
  L3_INT_1 w0.508: 189.21,72.02 189.21,71.96 190.86,70.31 190.86,66.84 189.34,65.31 189.34,64.09 187.81,62.56 187.81,57.23 189.85,55.2 189.85,53.16 187.05,50.37 187.05,28.4 173.97,15.32 164.45,15.32 156.72,23.04 145.17,23.04 142.86,25.35 125.46,25.35 122.92,22.81 110.98,22.81 101.96,13.79 95.61,13.79 93.45,15.95 91.8,15.95 90.24,17.52 47.14,17.52 41.89,12.27 v1(38.33,12.27)
  BOTTOM w0.305: v1(183.5,76.41) 183.62,76.41 185.4,74.63 188.19,74.63 v1(189.21,73.61) ; v1(114.66,79.45) 113.77,79.45 108.59,74.27 107.26,74.27 v2(106.69,74.84)
GND: length 1755.2
  TOP w0.081: U369.F2 90.41,117.7 90.66,117.45 91.4,117.45 91.6,117.25 ; U369.B1 88.26,116.21 88.35,116.12 ; U369.D7 89.26,120.86 89.77,121.36 89.77,121.62 ; U369.C1 88.76,116.5 89.26,116 v1(89.26,115.78) ; 90.97,117.95 90.51,117.95 U369.F3 ; v1(88.63,122) 88.76,121.86 U369.C7
  TOP w0.178: U60.6 41.69,97.69 41.71,97.67 41.86,97.67 v1(42.04,97.49)
  TOP w0.203: U52.B3 11.69,98.74 v1(12.05,98.38) ; v1(92.06,117.81) 91.92,117.95 90.97,117.95 ; v1(58.53,91.65) 58.74,91.86 U115.10 ; v1(92.06,119.59) 91.8,119.59 91.41,119.2 U369.G5 ; U52.D3 10.67,98.9 v1(10.67,98.53) ; v1(29.93,112.58) 29.93,112.6 30.04,112.71 U55.B13 ; U55.J13 26.25,112.87 v1(26.06,112.87) ; v1(92.06,117.05) 91.8,117.05 91.6,117.25 ; U52.C3 v1(11.29,98.38) ; v1(30.97,120.35) 30.04,119.42 U55.B1 ; v2(97.89,68.44) v2(98.69,68.44) 98.69,69.24 v1(98.69,69.24) ; v4(29.49,114.98) 29.66,115.16 U55.B9
  TOP w0.254: J134.26 v1(119.61,9.29) ; U37.B3 184.44,57.92 ; U30.8 v1(21.7,60.78) ; J36.69 v1(158.74,128.99) ; U26.8 v1(128.25,118.06) ; v1(168.89,22.95) 168.89,22.68 168.64,22.43 U46.6 ; U55.M12 U55.N12 24.28,113.66 v1(23.86,113.24) ; v1(23.48,120.63) 23.48,120.22 U55.N1 ; U26.3 v1(128.25,120.98) ; J134.11 v1(116.11,7.14) ; J36.75 v1(158.74,130.49) ; U33.8 v1(23.86,82.25) ; J134.34 v1(121.61,9.29) ; J134.18 v1(117.61,9.29) ; U312.1 119.85,62 119.54,62.3 C530.2 ; U55.N5 24.48,117.16 24.13,117.51 v1(23.86,117.51) ; J134.21 v1(118.61,7.14) ; v1(25.51,114.48) 25.36,114.48 U55.M11 ; U31.3 v1(18.78,56.97) ; J134.22 v1(118.61,9.29) ; J134.30 v1(120.61,9.29) ; v1(158.98,124.92) 158.55,124.49 J36.51 ; U39.B3 187.36,74.3 ; v1(167.37,21.67) 167.63,21.93 U46.7 ; v1(90.15,122.13) 90.15,122 89.77,121.62 ; J134.40 v1(123.11,9.29) ; U32.8 v1(23.73,86.06) ; J134.39 v1(123.11,7.14) ; J134.12 v1(116.11,9.29) ; U37.D3 185.24,57.96 ; C167.2 v1(129.65,22.94) ; U32.3 v1(20.81,86.06) ; J36.7 v1(158.74,113.49) ; U33.3 v1(20.81,82.25) ; C593.2 88.83,122.71 88.83,122.2 v1(88.63,122) ; J134.46 v1(124.61,9.29) ; J134.45 v1(124.61,7.14) ; J36.1 v1(158.74,111.99) ; J36.39 v1(158.74,121.49) ; J36.18 v1(163.81,116.24) ; J134.25 v1(119.61,7.14) ; U31.8 v1(21.82,56.97) ; J134.6 v1(114.6,9.29) ; J36.63 v1(158.74,127.49) ; U55.H1 27.04,120.34 26.91,120.47 C351.2 ; U28.8 v1(124.44,118.04) ; v4(27.04,118.21) U55.H2 ; J134.29 v1(120.61,7.14) ; J36.57 v1(158.74,125.99) ; v1(133.33,21.16) U22.2 ; J134.53 v1(126.61,7.14) ; v1(130.16,19.01) R378.2 ; J134.2 v1(113.6,9.29) ; U30.3 v1(18.78,60.78) ; U39.D3 188.16,74.34 ; J36.33 v1(157.5,119.2) ; U39.C3 187.76,74.32 ; J134.33 v1(121.61,7.14) ; U28.3 v1(124.44,120.98) ; v1(88.35,115.78) 88.35,116.12 ; J36.45 v1(158.74,122.99) ; J134.17 v1(117.61,7.14) ; U37.C3 184.84,57.94
  TOP w0.279: U72.24 v1(50.68,125.2) ; U72.4 v1(57.01,126.7) ; v1(50.65,126.99) 50.69,126.99 50.9,127.2 U72.20 ; v1(50.94,129.2) 50.94,128.95 51.19,128.7 U72.17 ; U58.4 v1(40.76,107.15) ; U72.26 v1(52.58,123.54)
  TOP w0.305: v1(114.66,18.78) SW7.3 v1(116.02,20.14) ; C508.2 C507.2 69.61,20.77 v1(69.58,20.81) ; U11.C1 v1(106.02,110.74) ; v1(68.31,13.79) C509.1 v1(66.66,13.79) ; R839.2 v1(22.97,124.16) ; v1(46.34,109.55) 46.34,109.68 C394.2 ; C208.1 v1(6.46,69.17) ; C208.1 v1(7.35,68.28) ; C208.1 v1(7.35,70.05) ; v1(187.05,79.58) U40.7 v1(187.05,82.12) ; v1(177.06,101.93) J71.8 ; U45.5 v1(156.57,35) ; v1(105.52,117.81) C102.2 ; R711.1 v1(51.8,95.33) ; v2(101.89,72.44) 102.29,72.04 U6.G11 ; v2(101.89,72.44) U6.G10 ; v2(101.89,72.44) 102.29,72.84 U6.F11 ; U101.5 44.3,65.86 44.43,65.99 v1(44.68,65.99) ; v1(108.15,43.89) 108.15,43.81 108.15,43.8 C19.2 ; R738.2 v1(134.73,45.54) ; C351.2 v1(25.76,121.24) ; C2.2 v1(22.61,22.46) ; C2.2 v1(22.61,19.76) ; C2.2 v1(21.27,21.03) ; J15.6 v1(149.85,134.7) ; U97.5 v1(44.68,80.6) ; C45.2 116.44,68.54 v1(116.32,68.66) ; C530.2 v1(118.43,62.3) ; C1.2 v1(23.78,17.48) ; R719.2 v1(27.41,127.71) ; v1(133.96,107.65) 133.83,107.52 R437.2 ; v1(118.6,35.37) 118.57,35.39 R38.2 ; C28.2 133.84,93.04 133.23,93.65 v1(133.22,93.65) ; v1(23.73,87.45) C240.2 ; v1(6.46,74.5) C230.1 7.35,74.51 v1(7.35,75.39) ; C5.2 v1(29.44,26.53) ; J68.5 190.2,82.15 188.96,83.39 v1(188.07,83.39) ; R404.1 v1(65.77,13.79) ; R404.1 v1(63.73,13.79) ; R404.1 64.62,14.3 v1(64.37,14.56) ; X2.4 v1(23.02,68.84) ; v1(50.65,126.99) 50.62,126.96 C413.2 ; v1(63.61,103.84) 63.54,103.77 U126.2 ; R720.2 v1(26.14,127.71) ; v2(98.69,70.04) 98.69,70.04 U6.K7 ; v2(98.69,70.04) U6.J7 v1(99.49,70.84) U6.H7 v2(98.69,71.64) U6.G7 ; v2(98.69,70.04) 98.29,69.64 U6.K6 v1(98.69,69.24) U6.K7 ; v1(123.17,62.56) C399.2 v1(125.2,62.55) ; R543.2 v1(34.14,92.02) ; C604.2 v1(58.65,107.77) ; U6.G10 101.31,72.21 100.87,72.21 U6.G9 100.51,72.21 100.07,72.21 U6.G8 v2(99.49,72.44) U6.G7 ; U6.G10 v2(101.89,71.64) ; C36.2 102.84,56.99 v1(102.86,56.97) C37.2 102.09,56.21 101.58,55.7 101.58,53.04 101.95,52.67 v1(103.99,52.67) 105.78,52.67 106.28,53.16 106.28,55.58 v1(105.77,56.09) ; R39.2 116.96,38.45 v1(116.93,38.45) ; U14.41 60.05,73.14 v1(60.27,73.36) ; C515.2 81.64,26.15 v1(82.04,25.75) ; R765.2 v1(166.1,84.79) ; J71.20 184.26,102.07 v1(184,101.81) ; Y2.2 108.18,56.08 107.69,55.59 ; R707.1 v1(54.34,95.33) ; U6.K7 99.26,69.47 99.73,69.47 U6.K8 v2(100.29,70.04) 100.29,70.04 U6.K9 ; U65.5 v1(140.95,118.95) ; R2137.2 v1(93.83,125.43) ; C304.2 v1(156.19,29.29) ; v1(27.91,90.86) 27.91,90.88 C229.2 ; J33.5 190.12,63.23 188.88,64.47 v1(188.4,64.47) ; v1(169.53,27.38) 169.4,27.26 R780.1 R781.1 ; D46.2 v1(100.69,136.98) ; R507.1 v1(7.35,48.21) ; R507.1 v1(7.35,49.99) ; R507.1 v1(6.58,49.1) ; v1(135.74,132.41) R454.1 136.63,132.67 v1(136,133.3) ; R1171.2 84.82,37.54 v1(84.56,37.8) ; C14.2 v1(10.65,29.54) ; v1(146.54,72.08) 146.54,72.29 146.11,72.72 U66.5 ; R1035.2 v1(64.88,92.03) ; R341.1 v1(151.24,50.5) ; C263.2 v1(184.13,52.02) ; U6.D4 v1(96.29,74.84) ; v1(186.66,101.93) J71.24 ; R558.2 v1(3.92,75.39) ; U15.C1 v1(83.92,84.51) ; C75.2 v1(110.59,58.11) ; U16.28 v1(49.65,49.86) ; U6.G4 v1(97.09,72.44) ; R804.1 v1(160.89,28.78) ; C393.2 v1(45.7,109.04) ; C38.2 105.64,56.21 v1(105.77,56.09) ; U64.5 148.95,119.33 v1(148.7,119.59) ; v1(151.99,98.63) U44.13 ; R779.2 v1(170.29,27.38) ; C513.2 v1(90.79,23.3) ; C602.2 v1(102.72,131.02) ; C571.2 v1(42.87,40.46) ; v1(44.06,54.03) 44.06,54.06 44.43,54.43 44.43,55.15 44.13,55.45 U106.5 ; Q8.2 v1(118.09,37.8) ; U418.3 v1(38.95,86.8) ; C390.2 29.96,101.43 v1(29.98,101.45) 30.08,101.55 U57.2 ; R467.2 132.57,117.86 v1(132.76,118.04) ; R1192.1 v1(87.36,14.56) ; R1192.1 v1(88.25,13.79) ; R1192.1 86.49,13.79 v1(86.47,13.81) ; C267.2 v1(187.05,68.4) ; D20.A v1(120.03,72.85) ; C433.2 v1(39.73,77.67) ; v1(3.74,37.12) SW3.1 v1(2.68,35.94) ; U6.T12 v2(102.69,64.44) U6.T11 ; R1286.1 v1(83.93,26.62) ; U67.5 v1(151.5,72.72) ; C409.2 v1(107.55,108.03) ; U14.52 68.85,73.12 v1(69.09,73.36) ; C176.2 v1(53.71,23.07) ; U125.2 v1(115.37,107.47) ; R642.2 v1(183.37,71.83) ; U103.5 44.03,59.39 44.35,59.71 44.35,60.67 44.38,60.71 v1(44.38,60.75) ; C434.2 v1(40.21,73.99) ; v1(2.68,46.26) SW3.3 v1(3.87,45.08) ; C462.2 v1(191.24,40.59) ; v1(167.24,98.63) U43.11 ; C590.2 83.71,123.74 C588.2 84.79,123.77 v1(84.79,124.41) ; v1(107.8,45.54) 107.8,45.81 C72.2 ; R19.2 14.08,37.8 v1(13.95,37.92) ; v1(40.89,82.14) 40.87,82.12 C432.2 ; X3.2 v1(30.08,92.96) ; C10.2 v1(20.17,28.27) ; C472.2 v1(188.2,107.13) ; C179.2 v1(61.32,23.33) ; R544.2 v1(33.25,92.03) ; C514.2 87.73,23.2 v1(87.74,23.19) ; R1031.2 v1(64.88,92.92) ; v1(61.23,57.61) 61.23,57.65 61.65,58.07 U16.12 ; C591.2 85.71,124.28 v1(85.96,124.54) ; C388.2 v1(29.98,97.88) 30.1,98 U56.2 ; v1(161.99,21.54) U48.4 ; v2(103.49,72.44) U6.F13 ; U6.F13 v1(104.29,73.24) ; U6.F13 v1(103.49,73.24) U6.F12 ; v1(129.65,118.06) C193.2 ; v1(184.26,96.19) J71.19 ; v1(167.89,104.47) U43.13 ; C529.2 119.57,60.03 v1(119.89,60.35) ; R709.1 v1(53.07,95.33) ; v1(189.53,101.55) J71.SH4 v1(189.53,99.77) ; C528.2 v1(49.38,131.9) ; C178.2 v1(59.04,23.3) ; v1(161.82,104.79) 162.04,104.57 U43.22 ; v1(133.97,94.94) 133.87,94.84 C27.2 133.83,94.22 v1(132.95,94.22) ; C3.2 v1(15.6,8.18) ; U14.46 v1(64.05,73.36) ; C598.2 v1(84.56,103.58) ; C245.2 v1(35.29,86.57) C232.2 ; v1(142.73,95.39) 142.73,94.95 C25.2 143.96,94.57 v1(144.08,94.44) ; U15.B3 v1(84.92,82.51) ; U2.1 v1(12.44,27.78) ; R560.1 v1(6.58,94.57) ; R560.1 v1(7.35,93.68) ; R560.1 v1(7.35,95.46) ; v1(120,73.99) C73.2 ; R1325.2 188.37,68.2 v1(188.19,68.02) ; v1(49.99,20.78) 50.15,20.78 50.15,20.77 C170.2 C180.2 ; v1(122.61,18.78) SW7.1 v1(123.97,20.14) ; C309.2 165.21,21.28 164.83,21.67 v1(164.7,21.67) ; C397.2 v1(40.75,109.93) ; v1(85.14,29.49) 85.14,29.18 84.49,28.53 C510.2 ; U6.L11 v2(101.89,69.24) U6.K11 v1(101.89,70.04) U6.J11 v2(101.89,70.84) U6.H11 ; U6.U1 v1(94.29,63.2) ; R1034.2 v1(56.63,91.11) ; C288.2 v1(171.95,115.9) ; J15.SH1 v1(152.88,138.25) ; v1(68.9,46.31) 68.85,46.36 U16.52 ; C466.2 v1(113.77,21.8) ; v1(178.29,99.77) J71.SH2 v1(178.29,101.42) ; v1(83.67,45.93) 83.67,46.56 C60.2 84.44,46.56 v1(84.44,45.93) ; C308.2 v1(164.99,19.13) ; C312.2 v1(152.12,27) ; TVS1.1 v1(22.87,19) ; C578.2 v1(104.12,36.4) ; v1(98.69,74.84) U6.D7 v1(99.49,74.84) U6.D8 ; v1(180.45,55.45) R631.2 ; C563.2 v1(42.87,43.13) ; C17.2 108.95,36.73 v1(108.57,37.11) 108.41,37.26 U3.2 ; C582.2 v1(83.8,116.28) ; U6.G14 v2(105.09,71.64) ; U73.4 v1(55.43,120.26) ; C452.2 v1(40.87,60.91) ; C595.1 v1(85.32,114.25) ; R259.2 v1(152.3,120.1) ; C589.2 v1(83.7,118.44) R2151.2 ; C565.2 v1(29.23,40.59) ; U71.5 v1(106.03,103.96) ; U6.P4 U6.P3 v1(95.5,66.04) ; 81.64,28.77 C516.2 81.31,28.77 80.9,29.19 v1(80.9,29.19) ; v1(123.42,44.78) C24.2 124.32,44.03 124.31,44.02 ; v1(105.77,56.09) 105.77,56.45 104.78,57.44 v1(104.78,57.74) ; v1(101.09,68.44) U6.L10 v2(101.09,69.24) ; v1(40.87,56.97) C455.2 v1(40.21,56.21) ; U6.A17 v1(107.09,77.42) ; C594.1 v1(84.56,108.66) ; v1(151.23,121.49) J15.SH3 ; R439.2 v1(133.97,111.2) ; U6.G7 v1(98.69,72.44) ; C31.2 v1(31.35,9.25) ; U44.22 v1(157.84,98.53) ; U98.5 v1(44.68,76.91) ; U356.1 v1(103.29,41.23) ; U6.L14 v1(105.09,68.44) ; v1(153.55,45.6) 153.58,45.6 C294.2 ; v1(37.06,1.64) SW2.1 v1(38.25,2.69) ; v1(140.2,114.14) C403.2 ; R452.2 v1(137.39,135.47) ; C389.2 v1(36.05,99.14) ; R28.2 137.02,100.42 v1(136.76,100.15) ; C228.2 24.83,91.52 v1(24.75,91.43) ; U15.E5 v1(81.92,80.51) ; v1(30.97,92.28) 30.59,91.9 R545.2 ; v1(184.64,100.03) J71.SH3 v1(184.64,101.42) ; U16.6 66.45,57.94 66.62,57.78 v1(66.62,57.1) ; v1(146.87,73.7) 147.09,73.48 C405.2 ; R2146.2 93.96,116.66 v1(94.21,116.66) ; v1(187.05,60.66) U38.7 v1(187.05,63.2) ; R1327.2 v1(48.24,131.9) ; R506.2 v1(4.29,68.28) ; v1(84.94,23.19) 85.46,23.71 C512.2 ; C295.2 v1(159.04,45.85) ; R493.2 v1(31.22,66.75) ; C74.2 v1(108.32,57.89) ; U6.P7 v2(99.49,66.84) ; U69.5 v1(101.71,103.96) ; U11.E5 v1(108.02,115.74) ; C395.2 v1(44.94,95.84) ; R494.2 28.56,66.63 v1(28.94,67.01) ; Q12.1 v1(185.54,67.39) ; R16.2 v1(19.16,31.95) ; v1(117.46,132.41) C186.1 v1(115.68,132.41) ; v1(29.14,91.9) 28.81,91.57 C246.2 ; v1(55.98,23.07) C177.2 ; C105.2 v1(81.39,94.31) ; C195.2 v1(130.66,118.03) ; U70.5 v1(110.98,103.71) ; U1.6 v1(23.09,31.14) ; v1(22.59,66.39) 23.22,66.39 C206.2 ; D3.4 v1(15.55,24.67) ; C202.2 v1(134.35,112.98) ; v1(45.07,14.43) 44.94,14.43 44.56,14.05 C181.1 v1(45.45,13.66) ; U6.U17 v1(107.55,63.58) 107.55,61.47 110.06,58.96 110.8,58.96 111.49,58.26 111.49,55.75 v1(110.81,55.08) Y2.4 110,54.51 109.75,54.26 107.85,54.26 107.64,54.48 v1(107.64,55.54) 107.69,55.59 ; C603.2 v1(102.72,128.73) ; v1(191.24,73.61) C362.2 v1(191.24,71.58) ; v1(21.6,63.2) C217.2 ; U14.28 49.65,73.05 49.21,73.5 v1(49.21,73.56) ; C511.2 v1(93.07,23.33) ; U1.4 v1(23.39,31.79) ; R55.2 v1(87.1,63.45) ; v1(25.89,65.1) 25.88,65.11 C207.2 ; C463.2 v1(189.85,40.46) ; R559.2 v1(4.29,93.68) ; v1(29.11,1.64) SW2.3 v1(30.3,2.69) ; Q4.2 v1(19.84,19.05) ; C398.2 v1(39.73,109.93) ; X3.4 v1(23.85,95.16) ; R449.2 v1(115.3,134.95) ; R1097.1 v1(52.18,26.62) ; v1(171.72,100.66) J71.SH1 175.04,100.66 175.05,100.65 v1(175.08,100.65) ; C431.2 v1(40.87,85.67) ; R638.2 v1(185.28,76.15) ; U63.5 v1(145.14,118.95) ; C317.2 159.12,28.14 v1(158.98,28.27) ; C909.2 v1(23.98,78.95) ; R721.2 v1(14.71,127.71) ; v1(140.95,94.27) 141.05,94.18 C26.2 v1(141.71,94.82) ; C311.2 v1(164.35,24.34) ; v1(142.58,74.12) C404.2 ; C562.2 v1(29.23,42.62) ; C183.2 v1(132.19,118.44) ; C527.2 188.84,85.9 v1(189.04,86.1) 189.22,86.28 C468.2 ; v1(148.2,114.2) C402.2 ; U6.A1 v1(93.71,77.42) ; U99.5 v1(44.68,73.23) ; v1(102.46,107.11) C407.2 ; C524.2 v1(65.77,100.29) ; v1(124.82,43.51) C21.2 v1(125.84,42.5) ; C33.2 v1(24.62,8.58) ; U100.5 v1(44.68,69.55) ; C391.2 v1(36.18,102.82) ; U6.P14 v1(105.09,66.04) ; R23.2 v1(111.61,41.99) ; C201.2 v1(128.76,106.5) 128.63,106.63 C188.2 ; Q15.2 v1(37.57,118.14) ; C577.2 98.91,39.19 v1(98.79,39.07) ; U16.54 v1(70.45,46.41) ; C910.2 42.01,88.72 v1(42.14,88.85) ; R11.2 v1(20.81,18.37) ; C436.2 v1(40.21,66.62) ; v1(130.16,54.94) C23.2 v1(130.16,52.91) ; Q11.1 v1(182.62,50.88) ; C126.2 155.64,49.86 v1(155.28,49.5) ; v1(186.66,96.19) J71.23 ; R803.2 v1(160,16.97) ; U14.6 v1(66.45,85.17) ; C408.2 v1(110.98,109.68) ; X2.2 v1(26.72,68.73) ; v1(133.96,108.66) 133.83,108.54 R438.2 ; U14.12 v1(61.65,85.17) ; C210.2 v1(33.25,61.29) C223.2 ; v1(113.3,60.53) C58.2 v1(113.3,58.63) ; R1326.2 v1(187.86,84.41) ; C20.2 108.06,42.12 v1(108.63,41.54) ; U56.5 v1(33.76,98) ; C264.2 v1(185.4,52.53) ; C310.2 v1(164.57,23.32) ; C268.2 v1(188.32,68.91) ; C567.2 v1(29.23,39.7) ; R492.2 v1(32.11,66.75) ; C435.2 v1(40.11,70.3) ; U68.5 v1(156.46,72.72) ; v1(71.61,72.73) 71.61,72.21 71.28,71.88 U14.54 ; 107.69,55.59 107.69,58.05 108.29,58.65 108.29,59.16 107.04,60.4 v1(106.91,60.4) ; U6.C14 v2(105.09,75.64) ; R761.2 v1(165.08,84.79) ; v1(147.49,35.38) J51.8 ; C569.2 v1(42.91,38.69) ; v1(60.44,46.26) 60.44,46.26 60.44,46.28 60.05,46.67 U16.41 ; C386.2 33.83,105.1 33.77,105.04 v1(33.74,105.04) 33.68,104.98 U59.2 ; U96.5 v1(44.68,84.28) ; J15.SH2 v1(139.69,138.64) ; v1(152.64,104.47) U44.11 ; U61.2 v1(42.43,113.38) ; v1(131.81,113.23) C185.2 ; v1(167.89,98.63) U43.12 ; U61.8 41.02,116.35 41.03,116.37 42.09,116.37 v1(42.27,116.55) ; R1116.2 v1(50.86,33.99) ; v1(151.81,73.93) 152.26,73.48 C406.2 ; C63.2 v1(86.09,63.45) ; v1(83.93,121.49) R2150.2 ; Y3.2 v1(171.59,118.76) ; R837.2 v1(36.18,101.93) ; TP103.1 v1(99.82,110.7) ; v1(64.5,46.31) 64.36,46.31 64.05,46.61 U16.46 ; R1043.2 v1(185.91,88.72) ; R573.2 v1(23.84,90.5) ; J15.SH4 v1(145.53,121.49) ; C205.2 v1(20.55,63.96) ; C66.2 v1(109.92,45.8) ; v1(181.86,101.93) J71.16 ; U6.C11 102.29,75.24 v2(102.69,74.84) U6.D12 ; v1(31.86,38.43) 31.94,38.51 U361.7 ; C526.2 v1(188.19,67.26) ; C293.2 v1(151.8,45.35) ; v1(26.78,66.64) C224.2 ; R520.2 v1(21.57,65.23) ; v1(151.99,104.47) U44.12 ; C411.2 v1(49.51,130.63) ; C473.2 v1(175.49,107.13) ; C216.2 v1(21.7,62.31) ; U61.10 v1(38.3,115.88) ; C392.2 v1(23.86,124.16) ; C11.2 v1(22.97,26.09) ; C13.2 v1(12.3,37.92) ; R626.2 v1(184,59.76) ; C32.2 v1(9.25,35.64) ; v1(52.15,133.17) J60.5 ; U11.B3 v1(104.02,112.74) ; C227.2 v1(21.18,90.12) ; C12.2 v1(21.82,26.09) ; U48.2 160.69,21.22 v1(161.02,21.54) 161.34,21.22 U48.3 ; v1(179.46,101.93) J71.12 ; U6.L4 v2(96.29,68.43) ; Q7.2 v1(120.38,34.11) ; v1(177.06,96.19) J71.7 ; C184.2 v1(131.93,115.39) ; R505.2 v1(3.92,49.86) ; v1(23.73,88.47) C239.2 ; v1(179.46,96.19) J71.11 ; C599.2 v1(84.56,109.81) ; C573.2 v1(42.87,42.24) ; v1(181.86,96.19) J71.15 ; U417.3 v1(25.27,75.15) ; R27.2 v1(135.75,99.52) ; C401.2 v1(144.39,114.14) ; v1(145.08,35.38) J51.7 ; R2147.2 v1(102.47,129.87)
  TOP w0.381: TVS1.1 24.1,19 ; TVS1.1 23.62,19.59 ; TVS1.1 23.62,18.42 ; v1(140.95,94.27) 140.35,93.68 U5.2 ; SW6.2 v1(3.16,108.41) ; C68.2 85.99,54.69 v1(85.27,53.98) ; R817.2 v1(15.46,100.54) ; C271.2 v1(67.16,100.54) ; 20.42,19.9 Q4.2 19.84,20.53 ; C107.2 54.32,88.98 ; C107.2 53.57,89.6 ; C107.2 52.83,88.98 ; U41.2 v1(69.32,101.76) ; R815.2 v1(15.46,97.49) ; C305.2 v1(156.57,26.88) ; C281.2 v1(75.17,119.97) ; J134.SH4 v1(127.12,8.22) J134.SH3 v1(120.88,8.22) J134.SH2 v1(114.65,8.22) J134.SH1 ; 91.66,51.26 C70.2 90.91,50.64 ; 141.33,19.18 T1.4 ; T1.4 141.33,20.73 ; T1.4 140.51,19.95 ; T1.4 142.16,19.95 ; C69.2 93.57,51.26 ; C69.2 92.82,50.64 ; C69.2 92.07,51.26 ; C270.2 v1(67.16,101.42) ; SW8.3 v1(57.14,115.66) ; v1(121.85,32.68) 121.72,32.55 D16.A ; C277.2 v1(67.81,105.49) ; 123.41,45.73 U4.1 ; U4.1 122.64,47.02 ; U4.1 123.41,48.3 ; R1112.2 v1(52.94,37.92) ; 17.87,33.48 C9.2 18.28,33.91 ; C387.2 v1(27.92,103.84) ; v1(45.7,24.21) 46.12,24.63 X4.2 v1(46.12,27.22) ; D12.A v1(130.16,33.31) ; 23.4,26.76 C11.2 22.54,26.76 ; v1(17.76,111.75) C352.2 v1(16.78,112.6) ; C7.2 v1(26.52,27) ; X1.2 v1(136.4,117.85) ; 22.26,26.76 C12.2 21.39,26.76 ; X4.4 v1(49.38,29.36) 49.89,28.85 R1099.1 ; R811.2 20.31,116.28 v1(20.03,116) ; v1(82.91,34.24) R1173.2 ; 186.3,58.24 C361.2 187.05,58.87 ; 27.79,26.76 C6.2 ; C6.2 27.04,27.38 ; C6.2 28.54,27.38 ; 125.82,41.73 C22.2 ; C22.2 126.23,42.17 ; C22.2 126.23,41.3 ; C480.2 51.68,28.77 C481.2 50.89,28.77 50.72,28.95 50.65,28.95 50.27,29.33 v1(50.27,29.42) ; R657.2 v1(78.33,109.43) ; C296.2 v1(93.96,129.12) ; R821.2 v1(18.28,107.9) ; U13.4 v1(69.2,90.5) ; 15.55,22.8 D3.4 ; D3.4 14.53,23.53 ; D3.4 16.58,23.53 ; v1(34.37,114.91) 34.17,114.91 34.02,114.76 R827.2 ; D15.A v1(124.44,32.55) ; C276.2 v1(67.16,107.14) ; 17.89,34.13 C8.2 ; C8.2 17.27,34.88 ; C8.2 17.89,35.63 ; Y4.2 v1(18.22,117.36) ; C286.2 C282.2 166.89,125.55 v1(166.75,125.41) ; 52.18,88.49 C119.2 52.61,88.08 ; SW8.1 v1(52.04,115.66) ; v1(78.98,119.97) C279.1 ; D18.A v1(115.93,33.31) ; R648.2 v1(78.33,103.61) ; X1.4 v1(135.24,120.05) ; C275.2 v1(68.43,119.97) ; C370.2 v1(10.15,110.8) ; v1(69.32,107.47) U42.2 ; C364.2 v1(188.7,54.31) ; v1(6.71,113.84) J53.5 ; 188.59,75.26 C363.2 ; C363.2 189.21,74.51 ; C363.2 189.21,76.01 ; D19.A v1(114.15,32.55) ; v1(119.49,32.68) 119.36,32.55 D17.A ; X6.2 v1(77.62,26.93) ; C5.2 v1(30.42,27.38) ; C168.2 v1(143.49,19.89) 143.59,19.99 U23.3 ; C360.2 v1(8.74,101.68) ; C324.2 v1(21.45,118.82) ; C273.1 v1(72.24,119.97) ; C298.2 v1(90.15,129.12) ; C482.2 v1(49.89,25.58) ; C373.2 v1(17.47,107.65) ; C272.2 v1(78.33,98.5) ; C278.2 v1(78.33,104.32) ; U62.1 v1(10.14,107.02) ; C371.2 v1(17.51,106.38) ; D22.3 v1(77.06,124.92) ; C300.2 v1(87.86,129.15) ; C359.2 v1(12.93,100.89) ; C299.2 v1(91.8,129.75) ; D13.A v1(128.5,33.31) ; v1(85.45,53.04) 85.96,53.55 C71.2 ; v1(129.65,106.5) C187.2 ; C338.2 v1(8.11,122.63) ; R836.2 v1(27.92,104.73) ; C323.2 v1(21.45,117.43) ; D10.A v1(135.24,33.31) ; L25.1 v1(6.41,122.46) ; C355.2 v1(20.17,112.48) ; C326.2 v1(8.1,104.09) ; C297.2 v1(95.61,129.62) ; R1280.1 81.64,28.77 ; Q1.3 v1(27.41,12.92) ; Y4.4 v1(20.45,120.07) ; C372.2 v1(15.22,111.06) ; D21.3 v1(70.33,125.03) ; D1.A v1(18.01,18.06) ; J50.4 v1(177.13,26.88) ; U51.1 v1(7.11,117.81) ; D11.A v1(132.7,33.31) ; D14.A v1(126.78,32.55) ; C356.2 v1(19.16,112.47) ; C365.2 v1(6.97,99.9) ; C301.2 v1(86.34,129.62) ; X6.4 v1(78.78,29.36)
  L2_GND_1 w0.305: 43.92,103.33 J56.3 42.78,103.46 J56.5 41.51,103.46
  L2_GND_1 w0.381: 31.43,133.43 J37.6 ; J37.6 32.49,134.5 ; J37.6 32.49,132.36 ; J37.6 33.56,133.43 ; 191.41,23.7 192.39,23.7 ; 192.39,23.7 192.39,22.72 ; 192.39,23.7 193.36,23.7 ; 192.39,23.7 192.39,24.68 ; 188.87,23.7 189.85,23.7 ; 189.85,23.7 189.85,22.72 ; 189.85,23.7 189.85,24.68 ; 189.85,23.7 190.82,23.7 ; 6.67,29.24 SW1.6 ; SW1.6 6.67,30.74 ; SW1.6 5.92,29.99 ; SW1.6 7.42,29.99 ; 168.33,40.25 J44.14 ; J44.14 167.32,41.25 ; J44.14 168.33,42.26 ; J44.14 169.33,41.25 ; JP5.1 43.67,93.98 ; JP5.1 42.73,93.04 ; JP5.1 43.67,92.1 ; JP5.1 44.61,93.04 ; J34.2 66.32,126.77 ; J34.2 64.44,126.77 ; J34.2 65.38,127.71 ; J34.2 65.38,125.83 ; 6.73,11.72 J2.2 ; J2.2 7.68,13.77 ; J2.2 5.78,13.77 ; J2.2 6.73,15.83 ; J29.10 120.76,126.86 ; J29.10 119.83,125.94 ; J29.10 121.69,125.94 ; J29.10 120.76,125.01 ; 71.27,134.35 J48.2 ; J48.2 72.12,133.5 ; J48.2 72.97,134.35 ; J48.2 72.12,135.2 ; J44.11 166.79,43.79 ; J44.11 165.79,44.8 ; J44.11 164.78,43.79 ; J44.11 165.79,42.79 ; 31.86,71.27 J63.3 ; J63.3 32.8,72.21 ; J63.3 31.86,73.16 ; J63.3 30.92,72.21 ; J37.18 18.32,133.43 ; J37.18 17.25,134.5 ; J37.18 16.19,133.43 ; J37.18 17.25,132.36 ; TP3.1 12.68,5.99 ; TP3.1 14.01,4.65 ; TP3.1 11.35,4.65 ; TP3.1 12.68,3.32 ; 73.27,134.35 J47.24 ; J47.24 74.97,134.35 ; J47.24 74.12,135.2 ; J47.24 74.12,133.5 ; J30.10 14.75,53.29 ; J30.10 13.82,54.22 ; J30.10 13.82,52.36 ; J30.10 12.9,53.29 ; 95.27,134.35 J47.2 ; J47.2 96.12,135.2 ; J47.2 96.97,134.35 ; J47.2 96.12,133.5 ; 69.27,134.35 J48.4 ; J48.4 70.97,134.35 ; J48.4 70.12,133.5 ; J48.4 70.12,135.2 ; J45.12 155.22,89.5 ; J45.12 154.22,88.5 ; J45.12 153.21,89.5 ; J45.12 154.22,90.51 ; J47.6 92.12,135.2 ; J47.6 91.27,134.35 ; J47.6 92.12,133.5 ; J47.6 92.97,134.35 ; 142.96,86.97 J41.1 ; J41.1 145,86.97 ; J41.1 143.98,85.96 ; J41.1 143.98,87.99 ; 83.27,134.35 J47.14 ; J47.14 84.97,134.35 ; J47.14 84.12,133.5 ; J47.14 84.12,135.2 ; J45.14 151.68,90.51 ; J45.14 152.68,89.5 ; J45.14 151.68,88.5 ; J45.14 150.67,89.5 ; J35.2 75.97,126.77 ; J35.2 74.09,126.77 ; J35.2 75.03,127.71 ; J35.2 75.03,125.83 ; 24.87,133.43 25.94,133.43 ; 24.87,133.43 24.87,134.5 ; 24.87,133.43 23.81,133.43 ; 24.87,133.43 24.87,132.36 ; 97.39,98.58 J59.3 ; J59.3 96.45,99.52 ; J59.3 97.39,100.46 ; J59.3 98.33,99.52 ; TP6.1 4.74,127.21 ; TP6.1 2.08,127.21 ; TP6.1 3.41,128.54 ; TP6.1 3.41,125.87 ; J41.3 141.44,87.99 ; J41.3 141.44,85.96 ; J41.3 140.42,86.97 ; J41.3 142.46,86.97 ; 35.03,132.36 35.03,133.43 ; 35.03,133.43 35.03,134.5 ; 35.03,133.43 33.97,133.43 ; 35.03,133.43 36.1,133.43 ; J70.8 154.05,55.2 ; J70.8 151.99,55.2 ; J70.8 153.02,54.17 ; J70.8 153.02,56.23 ; 18.73,133.43 J37.16 ; J37.16 19.79,132.36 ; J37.16 20.86,133.43 ; J37.16 19.79,134.5 ; 36.81,122.2 JP3.1 ; JP3.1 37.75,123.14 ; JP3.1 35.87,123.14 ; JP3.1 36.81,124.08 ; J44.13 168.33,44.8 ; J44.13 169.33,43.79 ; J44.13 168.33,42.79 ; J44.13 167.32,43.79 ; J31.10 14.75,78.69 ; J31.10 13.82,77.76 ; J31.10 12.9,78.69 ; J31.10 13.82,79.62 ; 43.41,122.2 JP2.1 ; JP2.1 44.36,123.14 ; JP2.1 43.41,124.08 ; JP2.1 42.47,123.14 ; 8.17,8.97 J2.3 ; J2.3 10.23,9.93 ; J2.3 10.23,8.02 ; J2.3 12.29,8.97 ; J48.6 68.97,134.35 ; J48.6 68.12,135.2 ; J48.6 68.12,133.5 ; J48.6 67.27,134.35 ; 149.79,108.54 J57.3 ; J57.3 151.67,108.54 ; J57.3 150.73,107.6 ; J57.3 150.73,109.48 ; 174.94,43.79 J44.19 ; J44.19 176.95,43.79 ; J44.19 175.95,44.8 ; J44.19 175.95,42.79 ; J37.8 29.95,134.5 ; J37.8 29.95,132.36 ; J37.8 31.02,133.43 ; J37.8 28.89,133.43 ; 14.41,121.87 JP4.1 ; JP4.1 16.29,121.87 ; JP4.1 15.35,120.93 ; JP4.1 15.35,122.81 ; 22.33,132.36 J37.14 ; J37.14 23.4,133.43 ; J37.14 22.33,134.5 ; J37.14 21.27,133.43 ; 35.36,49.86 36.3,49.86 ; 36.3,49.86 37.24,49.86 ; 36.3,49.86 36.3,48.92 ; 36.3,49.86 36.3,50.8 ; J69.2 184.77,5.29 ; J69.2 185.78,4.27 ; J69.2 184.77,3.25 ; J69.2 183.75,4.27 ; J8.2 109.84,29.38 ; J8.2 109.84,27.42 ; J8.2 108.86,28.4 ; J8.2 110.81,28.4 ; J75.3 97.39,109.48 ; J75.3 96.45,108.54 ; J75.3 98.33,108.54 ; J75.3 97.39,107.6 ; J73.3 31.86,76.2 ; J73.3 30.92,75.26 ; J73.3 31.86,74.32 ; J73.3 32.8,75.26 ; 178.16,12.71 TP4.1 ; TP4.1 178.16,15.38 ; TP4.1 179.5,14.05 ; TP4.1 176.83,14.05 ; 36.3,46.18 37.24,46.18 ; 36.3,46.18 36.3,47.12 ; 36.3,46.18 36.3,45.24 ; 36.3,46.18 35.36,46.18 ; 172.4,43.79 J44.17 ; J44.17 173.41,44.8 ; J44.17 173.41,42.79 ; J44.17 174.41,43.79 ; 14.71,133.43 14.71,134.5 ; 14.71,133.43 14.71,132.36 ; 14.71,133.43 13.65,133.43 ; 14.71,133.43 15.78,133.43 ; 158.29,136.1 TP5.1 ; TP5.1 159.62,137.43 ; TP5.1 159.62,134.76 ; TP5.1 160.95,136.1 ; 116.52,43.97 J7.2 ; J7.2 117.46,43.03 ; J7.2 118.4,43.97 ; J7.2 117.46,44.91 ; 153.02,77.03 J62.8 ; J62.8 153.02,79.09 ; J62.8 151.99,78.06 ; J62.8 154.05,78.06 ; J44.15 171.87,43.79 ; J44.15 170.87,44.8 ; J44.15 169.86,43.79 ; J44.15 170.87,42.79 ; 112.9,137 J101.5 ; J101.5 114.95,137 ; J101.5 113.92,138.03 ; J101.5 113.92,135.97 ; 146.11,77.04 J58.3 ; J58.3 147.99,77.04 ; J58.3 147.05,77.98 ; J58.3 147.05,76.1 ; 3.42,29.99 SW1.3 ; SW1.3 4.17,30.74 ; SW1.3 4.92,29.99 ; SW1.3 4.17,29.24 ; J76.3 150.73,112.91 ; J76.3 151.67,111.97 ; J76.3 150.73,111.03 ; J76.3 149.79,111.97 ; 27.41,132.36 27.41,133.43 ; 27.41,133.43 26.35,133.43 ; 27.41,133.43 27.41,134.5 ; 27.41,133.43 28.48,133.43
  L3_INT_1 w0.127: v1(49.65,49.86) 49.64,49.86 49,50.5 49,55.45 v1(49.26,55.7) 48.93,56.04 48.93,58.04 49.21,58.32 v1(49.21,73.56) 49.09,73.68 49.09,83.73 v1(50.53,85.17) ; v1(44.06,54.03) 44.06,54.06 44.25,54.26 44.25,54.32 44.3,54.37 44.3,60.63 44.38,60.71 v1(44.38,60.75) 44.38,61.29 43.8,61.88 43.8,65.48 44.3,65.99 v1(44.68,65.99) 44.68,66.25 44.81,66.37 44.81,66.56 44.81,66.56 44.81,66.95 44.81,66.95 44.81,67.44 44.38,67.87 44.38,69.24 v1(44.68,69.55) ; v1(52.94,37.92) 52.94,38.18 46.79,44.33 46.79,58.95 46.89,59.06 46.89,59.06 47.05,59.21 47.05,66.68 46.74,66.98 46.74,73.76 v1(46.84,73.87) 46.72,73.99 46.72,74.42 45.94,75.2 45.94,80.39 45.74,80.6 v1(44.68,80.6)
  L3_INT_1 w0.305: v1(44.06,54.03) 44.06,34.94 47.17,31.83 v1(48.37,31.83) ; 116.95,38.43 v1(116.93,38.45) ; 116.95,38.43 118.34,38.43 123.42,43.51 v1(123.42,43.77) v1(123.42,44.78) 123.42,48.59 v1(124.06,49.23) 125.08,50.24 125.08,54.18 v1(126.09,55.2) 125.71,55.58 125.71,58.5 124.57,59.64 124.57,61.93 125.19,62.55 v1(125.2,62.55) 125.58,62.93 125.58,70.26 126.51,71.19 126.51,76.49 122.03,80.98 122.03,83.52 119.25,86.29 117.73,86.29 117.07,86.95 117.07,88.47 v1(115.17,90.38) 111.49,94.06 v1(109.84,94.06) 109.71,94.19 v1(106.66,94.19) 102.86,94.19 101.95,93.27 v1(101.95,92.84) 102.25,92.53 102.85,92.53 103.44,93.12 109.25,93.12 v1(109.84,92.53) 110.98,92.53 v1(111.55,91.96) 113.26,90.25 v1(113.26,89.87) 114.13,89.87 v1(115.03,88.97) 116.19,87.81 116.19,86.73 117.41,85.51 118.77,85.51 121.14,83.14 121.14,80.47 125.72,75.89 125.72,72.1 124.68,71.06 124.68,64.07 v1(123.17,62.56) 123.65,62.08 123.65,58.85 122.89,58.09 122.89,55.6 v1(123.3,55.2) 123.81,54.69 123.81,50.75 v1(122.28,49.23) v1(122.28,47.07) v1(122.28,45.93) v1(122.28,44.91) v1(122.28,43.89) 118.19,39.81 116.97,39.81 109.25,32.08 v1(108.69,32.08) v1(106.66,32.08) 106.08,32.08 98.02,24.03 93.77,24.03 v1(93.07,23.33) 92.56,23.83 91.32,23.83 v1(90.79,23.3) 89.28,23.3 88.5,24.08 83.97,24.08 83.59,23.7 v1(83.04,23.7) 82.63,23.29 80.52,23.29 79.05,24.77 77.53,24.77 v1(76.97,24.21) 78.75,22.43 84.18,22.43 v1(84.94,23.19) 85.05,23.29 87.64,23.29 v1(87.74,23.19) 88.12,23.19 89.39,21.92 94.09,21.92 94.52,22.35 97.19,22.35 v1(97.77,22.94) 98.36,22.35 99.22,22.35 v1(99.8,22.94) 99.8,24.69 106.18,31.07 v1(108.69,31.07) 109.59,31.07 v1(113.01,34.49) 116.95,38.43
  L5_GND_2 w0.381: 3.41,125.87 TP6.1 ; TP6.1 4.74,127.21 ; TP6.1 3.41,128.54 ; TP6.1 2.08,127.21 ; J44.15 171.87,43.79 ; J44.15 170.87,44.8 ; J44.15 170.87,42.79 ; J44.15 169.86,43.79 ; J44.19 175.95,44.8 ; J44.19 174.94,43.79 ; J44.19 176.95,43.79 ; J44.19 175.95,42.79 ; 14.41,121.87 JP4.1 ; JP4.1 16.29,121.87 ; JP4.1 15.35,120.93 ; JP4.1 15.35,122.81 ; 183.75,4.27 J69.2 ; J69.2 184.77,5.29 ; J69.2 185.78,4.27 ; J69.2 184.77,3.25 ; TP5.1 159.62,137.43 ; TP5.1 158.29,136.1 ; TP5.1 159.62,134.76 ; TP5.1 160.95,136.1 ; 188.87,23.7 189.85,23.7 ; 189.85,23.7 190.82,23.7 ; 189.85,23.7 189.85,22.72 ; 189.85,23.7 189.85,24.68 ; J31.10 13.82,79.62 ; J31.10 14.75,78.69 ; J31.10 12.9,78.69 ; J31.10 13.82,77.76 ; 65.38,125.83 J34.2 ; J34.2 64.44,126.77 ; J34.2 66.32,126.77 ; J34.2 65.38,127.71 ; J30.10 14.75,53.29 ; J30.10 13.82,52.36 ; J30.10 13.82,54.22 ; J30.10 12.9,53.29 ; 14.71,133.43 14.71,134.5 ; 14.71,133.43 15.78,133.43 ; 14.71,133.43 14.71,132.36 ; 14.71,133.43 13.65,133.43 ; 71.27,134.35 J48.2 ; J48.2 72.97,134.35 ; J48.2 72.12,133.5 ; J48.2 72.12,135.2 ; J37.8 31.02,133.43 ; J37.8 29.95,132.36 ; J37.8 28.89,133.43 ; J37.8 29.95,134.5 ; 31.86,71.27 J63.3 ; J63.3 32.8,72.21 ; J63.3 31.86,73.16 ; J63.3 30.92,72.21 ; J59.3 98.33,99.52 ; J59.3 96.45,99.52 ; J59.3 97.39,100.46 ; J59.3 97.39,98.58 ; J45.14 151.68,90.51 ; J45.14 151.68,88.5 ; J45.14 152.68,89.5 ; J45.14 150.67,89.5 ; 36.3,49.86 36.3,50.8 ; 36.3,49.86 36.3,48.92 ; 36.3,49.86 35.36,49.86 ; 36.3,49.86 37.24,49.86 ; 5.78,13.77 J2.2 ; J2.2 6.73,11.72 ; J2.2 6.73,15.83 ; J2.2 7.68,13.77 ; 192.39,22.72 192.39,23.7 ; 192.39,23.7 193.36,23.7 ; 192.39,23.7 192.39,24.68 ; 192.39,23.7 191.41,23.7 ; 21.27,133.43 J37.14 ; J37.14 22.33,134.5 ; J37.14 22.33,132.36 ; J37.14 23.4,133.43 ; 33.97,133.43 35.03,133.43 ; 35.03,133.43 36.1,133.43 ; 35.03,133.43 35.03,132.36 ; 35.03,133.43 35.03,134.5 ; J45.12 155.22,89.5 ; J45.12 154.22,88.5 ; J45.12 153.21,89.5 ; J45.12 154.22,90.51 ; 42.73,93.04 JP5.1 ; JP5.1 43.67,93.98 ; JP5.1 43.67,92.1 ; JP5.1 44.61,93.04 ; 150.73,107.6 J57.3 ; J57.3 151.67,108.54 ; J57.3 149.79,108.54 ; J57.3 150.73,109.48 ; J29.10 120.76,126.86 ; J29.10 119.83,125.94 ; J29.10 120.76,125.01 ; J29.10 121.69,125.94 ; J58.3 147.99,77.04 ; J58.3 147.05,76.1 ; J58.3 146.11,77.04 ; J58.3 147.05,77.98 ; J37.16 20.86,133.43 ; J37.16 19.79,132.36 ; J37.16 18.73,133.43 ; J37.16 19.79,134.5 ; 74.09,126.77 J35.2 ; J35.2 75.03,127.71 ; J35.2 75.97,126.77 ; J35.2 75.03,125.83 ; J75.3 98.33,108.54 ; J75.3 96.45,108.54 ; J75.3 97.39,109.48 ; J75.3 97.39,107.6 ; 172.4,43.79 J44.17 ; J44.17 173.41,42.79 ; J44.17 174.41,43.79 ; J44.17 173.41,44.8 ; 32.49,132.36 J37.6 ; J37.6 33.56,133.43 ; J37.6 31.43,133.43 ; J37.6 32.49,134.5 ; J47.24 74.97,134.35 ; J47.24 74.12,135.2 ; J47.24 73.27,134.35 ; J47.24 74.12,133.5 ; J41.1 143.98,87.99 ; J41.1 143.98,85.96 ; J41.1 142.96,86.97 ; J41.1 145,86.97 ; 178.16,12.71 TP4.1 ; TP4.1 176.83,14.05 ; TP4.1 179.5,14.05 ; TP4.1 178.16,15.38 ; J44.13 168.33,44.8 ; J44.13 167.32,43.79 ; J44.13 169.33,43.79 ; J44.13 168.33,42.79 ; 3.42,29.99 SW1.3 ; SW1.3 4.17,29.24 ; SW1.3 4.17,30.74 ; SW1.3 4.92,29.99 ; J44.11 165.79,44.8 ; J44.11 166.79,43.79 ; J44.11 165.79,42.79 ; J44.11 164.78,43.79 ; J76.3 150.73,112.91 ; J76.3 150.73,111.03 ; J76.3 151.67,111.97 ; J76.3 149.79,111.97 ; 36.81,122.2 JP3.1 ; JP3.1 36.81,124.08 ; JP3.1 35.87,123.14 ; JP3.1 37.75,123.14 ; J47.2 96.97,134.35 ; J47.2 95.27,134.35 ; J47.2 96.12,133.5 ; J47.2 96.12,135.2 ; SW1.6 6.67,30.74 ; SW1.6 7.42,29.99 ; SW1.6 5.92,29.99 ; SW1.6 6.67,29.24 ; 16.19,133.43 J37.18 ; J37.18 18.32,133.43 ; J37.18 17.25,132.36 ; J37.18 17.25,134.5 ; J44.14 168.33,42.26 ; J44.14 169.33,41.25 ; J44.14 167.32,41.25 ; J44.14 168.33,40.25 ; J73.3 31.86,76.2 ; J73.3 32.8,75.26 ; J73.3 30.92,75.26 ; J73.3 31.86,74.32 ; 12.68,3.32 TP3.1 ; TP3.1 12.68,5.99 ; TP3.1 14.01,4.65 ; TP3.1 11.35,4.65 ; J41.3 142.46,86.97 ; J41.3 141.44,85.96 ; J41.3 140.42,86.97 ; J41.3 141.44,87.99 ; 117.46,43.03 J7.2 ; J7.2 117.46,44.91 ; J7.2 116.52,43.97 ; J7.2 118.4,43.97 ; 112.9,137 J101.5 ; J101.5 114.95,137 ; J101.5 113.92,135.97 ; J101.5 113.92,138.03 ; 27.41,133.43 27.41,134.5 ; 27.41,133.43 27.41,132.36 ; 27.41,133.43 26.35,133.43 ; 27.41,133.43 28.48,133.43 ; 153.02,77.03 J62.8 ; J62.8 153.02,79.09 ; J62.8 154.05,78.06 ; J62.8 151.99,78.06 ; J2.3 12.29,8.97 ; J2.3 8.17,8.97 ; J2.3 10.23,9.93 ; J2.3 10.23,8.02 ; 83.27,134.35 J47.14 ; J47.14 84.97,134.35 ; J47.14 84.12,135.2 ; J47.14 84.12,133.5 ; JP2.1 43.41,124.08 ; JP2.1 43.41,122.2 ; JP2.1 44.36,123.14 ; JP2.1 42.47,123.14 ; 68.12,133.5 J48.6 ; J48.6 68.12,135.2 ; J48.6 68.97,134.35 ; J48.6 67.27,134.35 ; 24.87,132.36 24.87,133.43 ; 24.87,133.43 25.94,133.43 ; 24.87,133.43 24.87,134.5 ; 24.87,133.43 23.81,133.43 ; 109.84,27.42 J8.2 ; J8.2 108.86,28.4 ; J8.2 109.84,29.38 ; J8.2 110.81,28.4 ; 70.12,133.5 J48.4 ; J48.4 70.12,135.2 ; J48.4 69.27,134.35 ; J48.4 70.97,134.35 ; 36.3,46.18 36.3,47.12 ; 36.3,46.18 35.36,46.18 ; 36.3,46.18 37.24,46.18 ; 36.3,46.18 36.3,45.24 ; J47.6 92.12,135.2 ; J47.6 92.97,134.35 ; J47.6 91.27,134.35 ; J47.6 92.12,133.5 ; J70.8 154.05,55.2 ; J70.8 151.99,55.2 ; J70.8 153.02,54.17 ; J70.8 153.02,56.23
  BOTTOM w0.127: C280.2 75.16,118.58
  BOTTOM w0.254: v1(85.35,31.03) 85.34,31.03 85.19,30.88 83.76,30.88 83.55,30.67 R1178.2 ; U124.2 73.07,21.12 v1(72.75,20.81) ; R825.2 v1(31.22,119.71) ; R828.2 34.14,115.14 v1(34.37,114.91) ; v1(166.23,113.25) 166.21,113.25 166.1,113.36 C285.2 ; R823.2 v1(26.52,122.51) ; R826.2 v1(34.35,114.25)
  BOTTOM w0.305: C125.2 v1(49.26,55.7) ; v1(145.27,137.11) C94.2 ; v1(144.81,131.59) 145.01,131.79 R806.2 ; Q20.2 115.93,118.82 v1(116.19,118.57) ; R30.2 v1(140.95,131.52) ; C108.2 59.2,85.06 v1(59.3,85.16) ; R1118.1 v1(44.3,21.41) ; R879.2 v1(116.44,119.33) ; R1048.2 v1(152.76,122.25) ; C192.2 131.9,114.47 131.6,114.77 v1(131.16,114.77) ; v1(188.58,99.65) 188.33,99.4 C471.2 ; C521.2 v2(87.99,30.3) ; R2148.2 83.93,120.6 v1(83.93,121.49) ; C243.2 v1(35.29,80.09) ; U118.3 118.97,89.75 v1(118.73,89.99) ; C55.2 101.05,72.51 C54.2 101.84,72.39 v2(101.89,72.44) ; C198.2 124.29,111.55 C197.2 125.2,111.71 v2(125.71,112.22) ; v1(157.84,98.53) 157.84,98.5 157.98,98.36 C292.2 ; v1(66.62,57.1) 66.74,56.97 C121.2 ; C116.2 83.89,84.54 v1(83.92,84.51) ; C103.2 v1(99.55,125.94) ; v1(58.02,104.35) 57.91,104.46 U362.3 ; v1(146.41,137.11) C93.2 ; C204.2 128.24,112.34 127.87,111.97 v2(127.87,111.71) ; v1(36.94,80.47) 36.93,80.48 R549.2 R552.2 R547.2 R548.2 R528.2 R550.2 ; v1(96.25,28.02) 95.86,28.02 R1175.2 ; R805.2 144,132.79 v1(143.36,132.16) ; C200.2 125.71,109.3 v1(125.46,109.04) ; C350.2 28.93,118.49 v4(28.63,118.19) ; C248.2 30.09,86.67 C247.2 29.99,85.77 v2(30.08,85.68) ; C117.2 81.28,83.87 v1(81.92,84.51) ; C122.2 65.33,55.58 v1(65.68,55.93) ; C115.2 v1(64.87,85.17) ; C519.2 v2(90.53,29.67) ; C214.2 25.6,60.53 v2(25.85,60.53) 25.76,60.62 C211.2 ; C182.2 v1(56.88,38) ; C104.2 v1(100.56,125.94) ; C290.2 v1(159.87,102.96) C291.2 ; C414.2 54.21,124.03 v1(53.83,123.65) ; R338.2 v1(58.65,50.62) ; v1(104.68,62.26) 104.05,62.26 103.72,62.59 C43.2 103.69,63.18 C42.2 ; v1(124.44,118.04) 124.44,118.26 124.14,118.56 C903.2 ; U12.4 v1(108.18,120.6) ; v1(89.26,115.78) 89.26,116.03 89.9,116.66 C579.2 ; C349.2 29.56,114.91 v4(29.49,114.98) ; v1(116.19,115.01) 115.98,115.22 Q21.2 ; C114.2 v1(69.71,85.16) ; C212.2 v1(25.89,65.1) ; v2(26.9,58.24) 26.78,58.24 25.76,57.22 C218.2 ; C95.2 148.06,119.08 148.57,119.59 v1(148.7,119.59) ; v1(50.53,85.17) 50.39,85.04 C111.2 ; C57.2 C81.2 C49.2 ; U365.3 54.1,104.94 v1(54.69,104.35) 54.72,104.35 54.72,104.34 C574.2 ; Q23.2 116.11,111.64 v1(116.19,111.71) ; R382.2 v1(155.94,24.72) ; R892.2 115.94,112.99 v1(115.68,112.73) ; v1(19.79,115.27) 20.17,114.89 21.83,114.89 C358.2 ; R1109.2 51.68,30.56 50.65,30.56 v1(50.53,30.69) ; U410.3 v1(119.61,118.71) ; C213.2 v2(25.76,58.12) ; C518.2 v2(87.99,29.67) ; C64.2 v1(86.09,63.45) ; U116.3 v1(153.79,52.65) ; C106.2 79.33,92.51 v1(79.28,92.51) ; C190.2 v2(125.58,114) ; v1(107.09,77.42) 107.05,77.38 C85.2 106.66,76.27 C89.2 C87.2 ; C469.2 123.65,86.97 v1(123.68,86.95) ; Q19.2 115.91,122.41 v1(116.19,122.13) ; U366.3 50.29,104.78 50.59,104.47 v1(50.88,104.47) 50.91,104.47 51.04,104.34 C575.2 ; v1(87.1,63.45) R57.2 ; C120.2 v1(65.52,46.18) ; v1(96.25,31.78) 95.66,31.78 R1181.2 ; C585.2 90.12,122.16 v1(90.15,122.13) 90.12,122.09 C583.2 ; C289.2 v1(160.01,98.5) ; C199.2 v1(128.76,106.5) ; v1(58.53,76.79) 58.78,76.53 R331.2 ; C581.2 93.96,116.92 v1(94.21,116.66) ; R1104.2 64.03,31.65 64.95,31.65 v1(65,31.7) ; C478.2 v2(56.24,30.3) ; C118.2 73.61,59.8 73.17,60.24 v1(72.71,60.24) ; v1(92.06,117.05) 91.8,116.79 C586.2 ; v1(101.89,70.04) 101.91,70.06 C48.2 ; C123.2 60.73,57.1 v1(61.23,57.61) ; R886.2 v1(116.44,115.78) ; v1(147.43,137.11) C30.2 ; R2156.1 102.5,107.15 v1(102.46,107.11) ; C221.2 v1(33.25,54.82) ; R443.2 R432.2 R441.2 R440.2 R445.2 R442.2 v1(122.66,104.86) ; C412.2 55.49,125.29 v2(54.84,125.94) ; C110.2 v1(68.06,85.16) ; v1(115.03,88.97) 115.4,88.6 R1046.1 ; R498.2 R499.2 R496.2 R495.2 R500.2 R497.2 v1(34.9,55.2) ; C235.2 27.92,86.32 v2(27.92,85.42) C236.2 ; C410.2 v1(57.65,123.01) ; R1103.2 v1(64.45,28.4) ; v1(27.92,90.22) C233.2 ; C109.2 61.71,85.11 v1(61.65,85.17) ; v1(158.74,122.99) 158.25,122.51 C470.2 ; v1(60.44,46.26) 60.44,46.26 C124.2 ; C479.2 v2(56.24,29.67) ; R2149.2 88.25,121.62 v1(88.63,122) 88.37,122.25 88.12,122.25 87.52,122.85 C584.2 ; C475.2 v2(58.78,29.8) ; C237.2 C238.2 27.53,82.5 v2(28.17,83.14) ; C523.2 115.29,107.54 v1(115.37,107.47) ; C189.2 v2(127.62,113.87) 128.51,113.87 C191.2 ; C92.2 v1(144,137.87) ; v1(30.71,57.99) 30.33,58.37 C222.2 ; C385.2 40.39,107.53 v1(40.76,107.15) ; C580.2 88.5,115.93 v1(88.35,115.78) ; C113.2 65.77,73.53 v1(65.86,73.61) ; C112.2 60.44,73.19 v1(60.27,73.36) ; C244.2 v1(32.75,83.26) ; v1(108.57,37.11) 108.57,37.11 C18.2 ; v2(125.2,113.11) 125.2,113.62 124.69,114.13 C194.2 C196.2 ; v1(132.94,104.63) C908.2 ; U117.3 v1(189.21,88.93) ; C101.2 108.05,115.77 v1(108.02,115.74) ; R260.2 v1(147.05,131.14) ; C98.2 v1(114.57,105.65) ; C34.2 v1(104.78,57.74) ; C96.2 v1(147.05,121.61) ; R876.2 v1(113.53,125.68) ; C576.2 v1(47.73,104.98) ; R770.2 v1(163.31,35.51) ; U119.3 v1(153.78,125.21)
  BOTTOM w0.381: v2(29.48,83.01) 29.73,82.76 C241.2 30.11,81.97 C242.2 ; C346.2 29.96,112.63 29.93,112.6 v1(29.93,112.58) ; R1177.2 91.77,26.5 91.19,27.08 91.19,27.23 v1(91.19,27.23) ; 140.65,20.86 R377.2 ; R377.2 140.65,22.74 ; R377.2 141.27,21.8 ; C234.2 27.79,84.15 v2(28.04,84.41) ; v2(58.17,32.16) 58.22,32.21 C477.2 ; 75.16,118.58 75.16,119.96 v1(75.17,119.97) ; v1(59.52,27.26) 59.52,26.9 60.05,26.37 R1106.2 ; v1(87.48,38.31) C517.2 ; v1(49.99,20.78) 50.34,21.12 U25.2 ; C274.2 68.43,119.96 v1(68.43,119.97) ; v1(83.7,62.08) 83.41,62.37 C88.2 ; v1(24.11,112.35) 23.73,111.97 C353.2 ; U10.4 v1(147.28,67.77) ; C520.2 90.91,32.59 v2(90.28,31.96) ; C100.2 v1(156.95,63.96) ; C354.2 23.98,113.11 v1(23.86,113.24) ; C525.2 64.46,105.46 v1(64.5,105.49) ; C29.2 v1(138.16,131.82) ; C284.2 v1(166.48,132.54) ; C464.2 59.16,92.28 v1(58.53,91.65) 58.78,91.39 C465.2 ; v2(90.28,30.3) 90.3,30.28 91.45,30.28 C522.2 ; v1(129.65,106.5) 129.65,105.76 129.27,105.38 U416.3 ; v2(26.78,60.66) 26.78,61.93 27.41,62.56 C225.2 ; C348.2 23.23,120.38 v1(23.48,120.63) ; C220.2 27.7,56.82 C219.2 27.57,57.61 v2(26.95,57.61) ; R824.2 23.99,117.64 v1(23.86,117.51) ; C204.2 129.62,112.34 C203.2 ; C287.2 v1(163.18,114.12) ; v1(31.98,88.34) 32.24,88.09 C231.2 ; C90.2 98.12,57.01 98.32,56.81 v1(98.32,55.96) ; v2(27.67,60.66) 27.67,61.16 C226.2 ; C99.2 v1(156.95,63.07) ; v2(58.78,29.8) 59.16,30.18 C476.2 ; C209.2 v1(30.62,63.61) ; C283.2 v1(165.21,132.67)
  vias: v1(16.74,34.88) v1(16.74,33.48) v1(17.63,33.48) v1(27.79,26.37) v1(28.56,26.75) v1(52.43,89.99) v1(53.32,89.99) v1(54.21,89.99) v1(55.1,89.99) v1(55.23,89.11) v1(90.66,50.12) v1(90.79,47.58) v1(91.42,49.1) v1(92.18,50.12) v1(92.44,49.1) v1(93.45,48.34) v1(93.58,50.12) v1(93.71,20.78) v1(95.74,20.78) v1(95.74,19.76) v1(96.75,15.83) v1(97.77,21.8) v1(97.77,20.78) v1(97.77,15.83) v1(98.79,19.76) v1(98.79,16.84) v1(99.8,21.8) v1(99.8,20.78) v1(101.96,21.8) v1(101.96,20.78) v1(102.98,21.8) v1(103.99,26.37) v1(103.99,21.8) v1(105.01,25.35) v1(105.01,24.21) v1(105.01,22.94) v1(106.03,26.37) v1(107.04,6.43) v1(107.04,5.54) v1(107.04,4.65) v1(134.47,6.43) v1(134.47,5.54) v1(142.22,22.18) v1(142.22,21.41) v1(184.26,58.75) v1(185.27,58.75) v1(185.91,57.86) v1(187.18,76.15) v1(187.18,75.26) v1(188.07,76.15) v1(188.07,75.26) v2(25.89,59.13) v2(26.9,59.13) v2(28.94,84.41) v2(30.08,84.41) v2(32.39,117.1) v2(40.37,114.63) v2(40.37,113.87) v2(52.69,128.09) v2(52.81,126.95) v2(52.81,125.94) v2(53.07,132.67) v2(53.83,128.09) v2(53.83,126.95) v2(53.83,125.94) v2(54.84,126.95) v2(54.97,128.09) v2(56.34,31.02) v2(56.42,32.16) v2(57.33,32.18) v2(57.51,31.07) v2(57.54,29.87) v2(58.65,31.07) v2(88.37,31.96) v2(88.37,31.07) v2(89.26,31.96) v2(89.26,31.07) v2(89.26,30.3) v2(90.28,31.07) v2(99.49,73.24) v2(101.89,68.44) v2(102.69,66.84) v2(102.69,62.84) v2(104.29,70.04) v2(126.6,112.85) v2(126.6,111.71) v3(30.04,117.16)
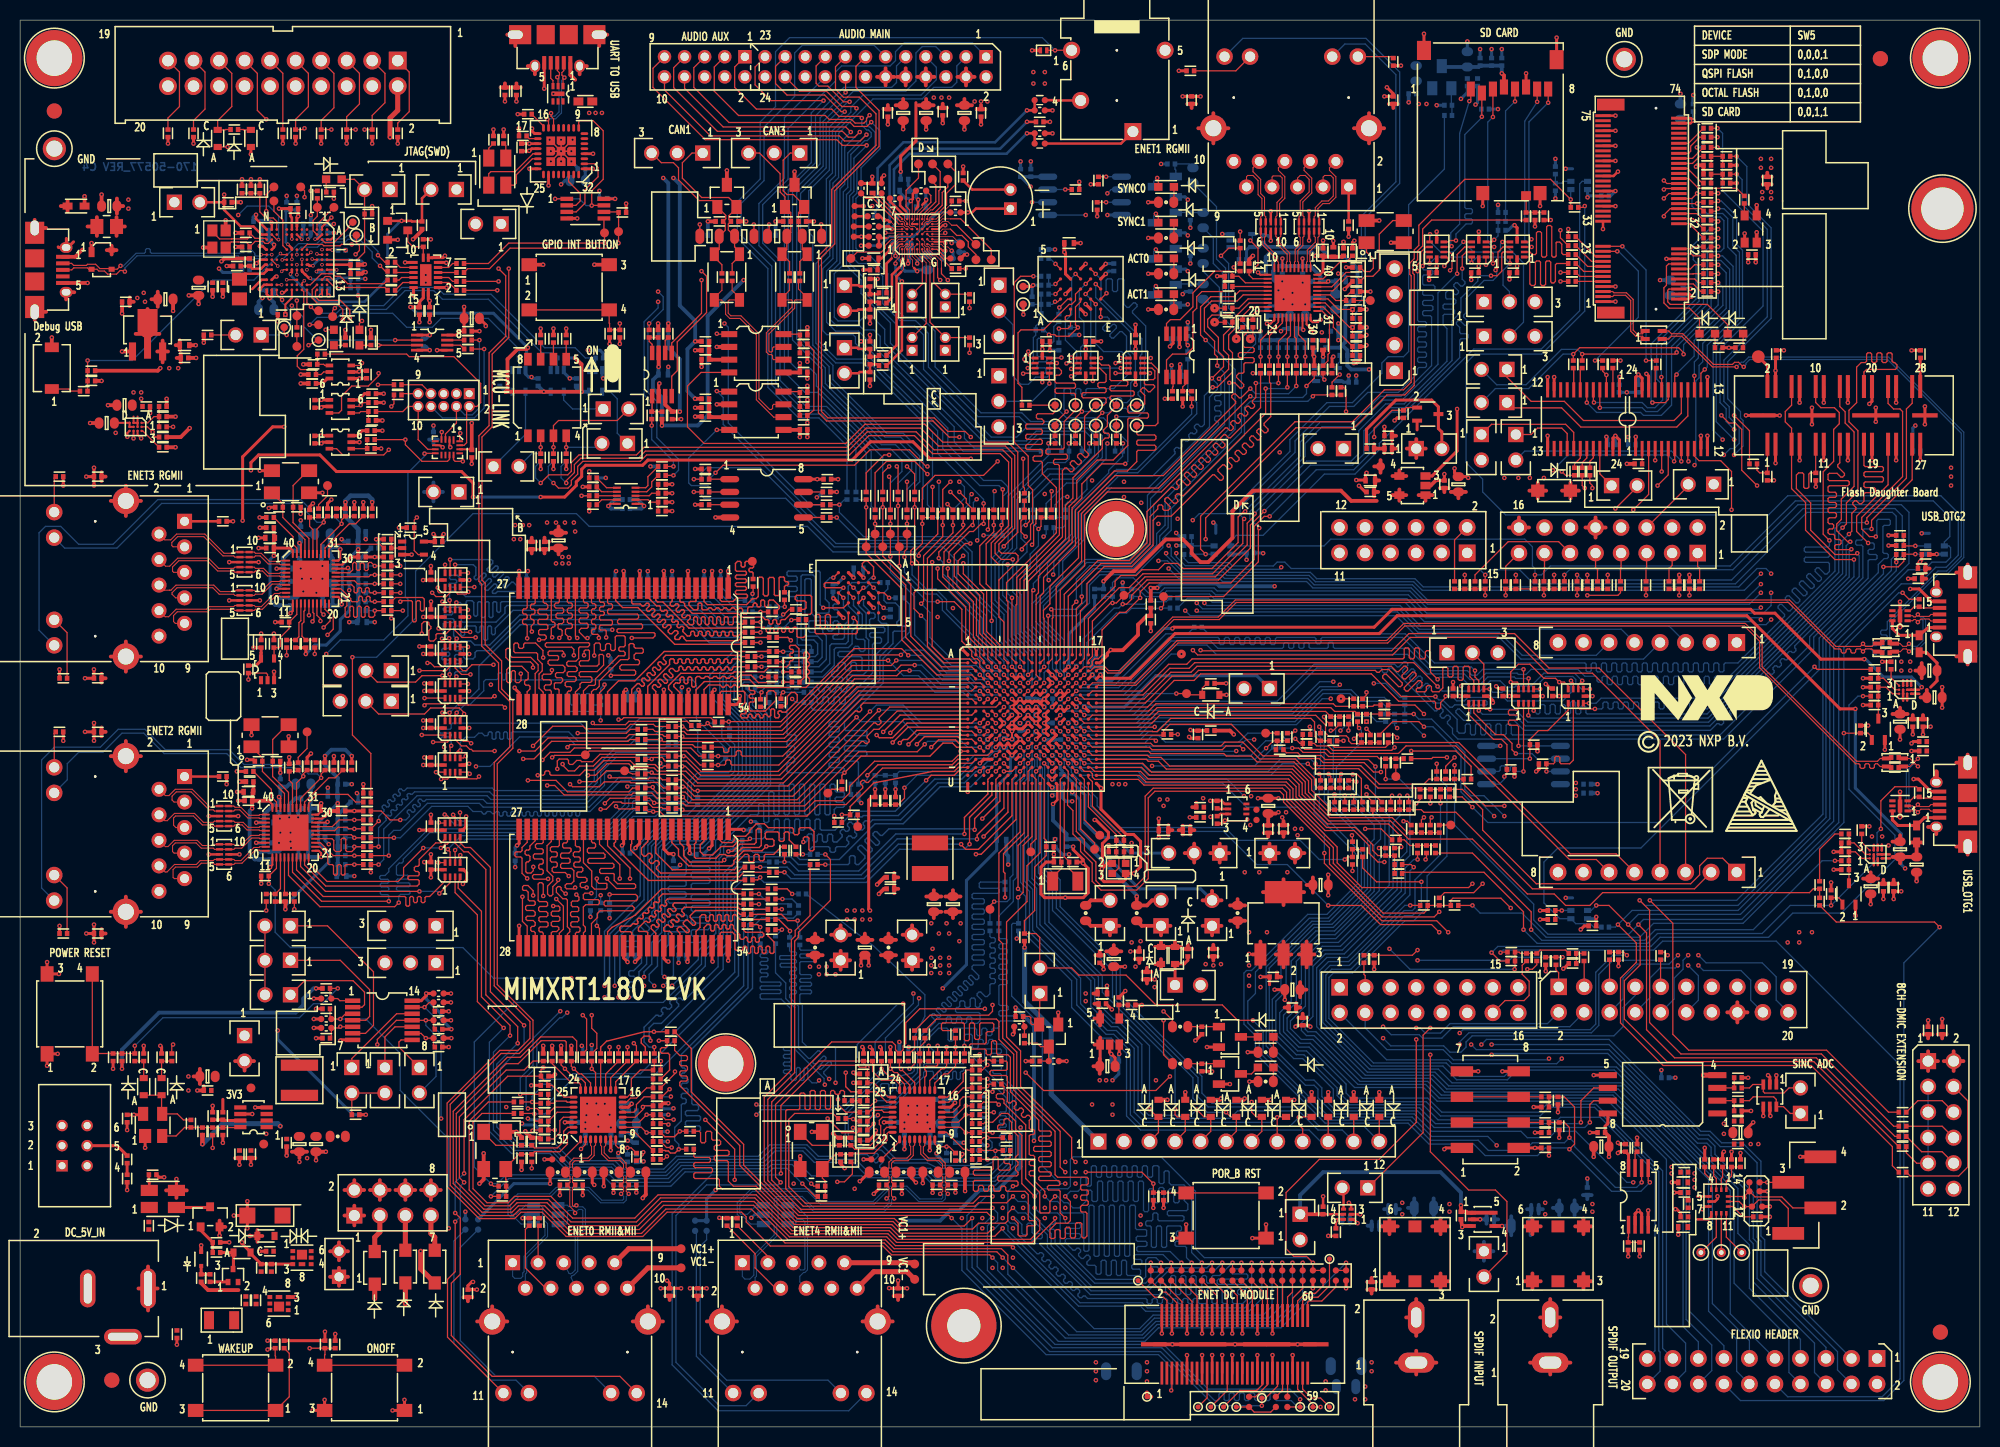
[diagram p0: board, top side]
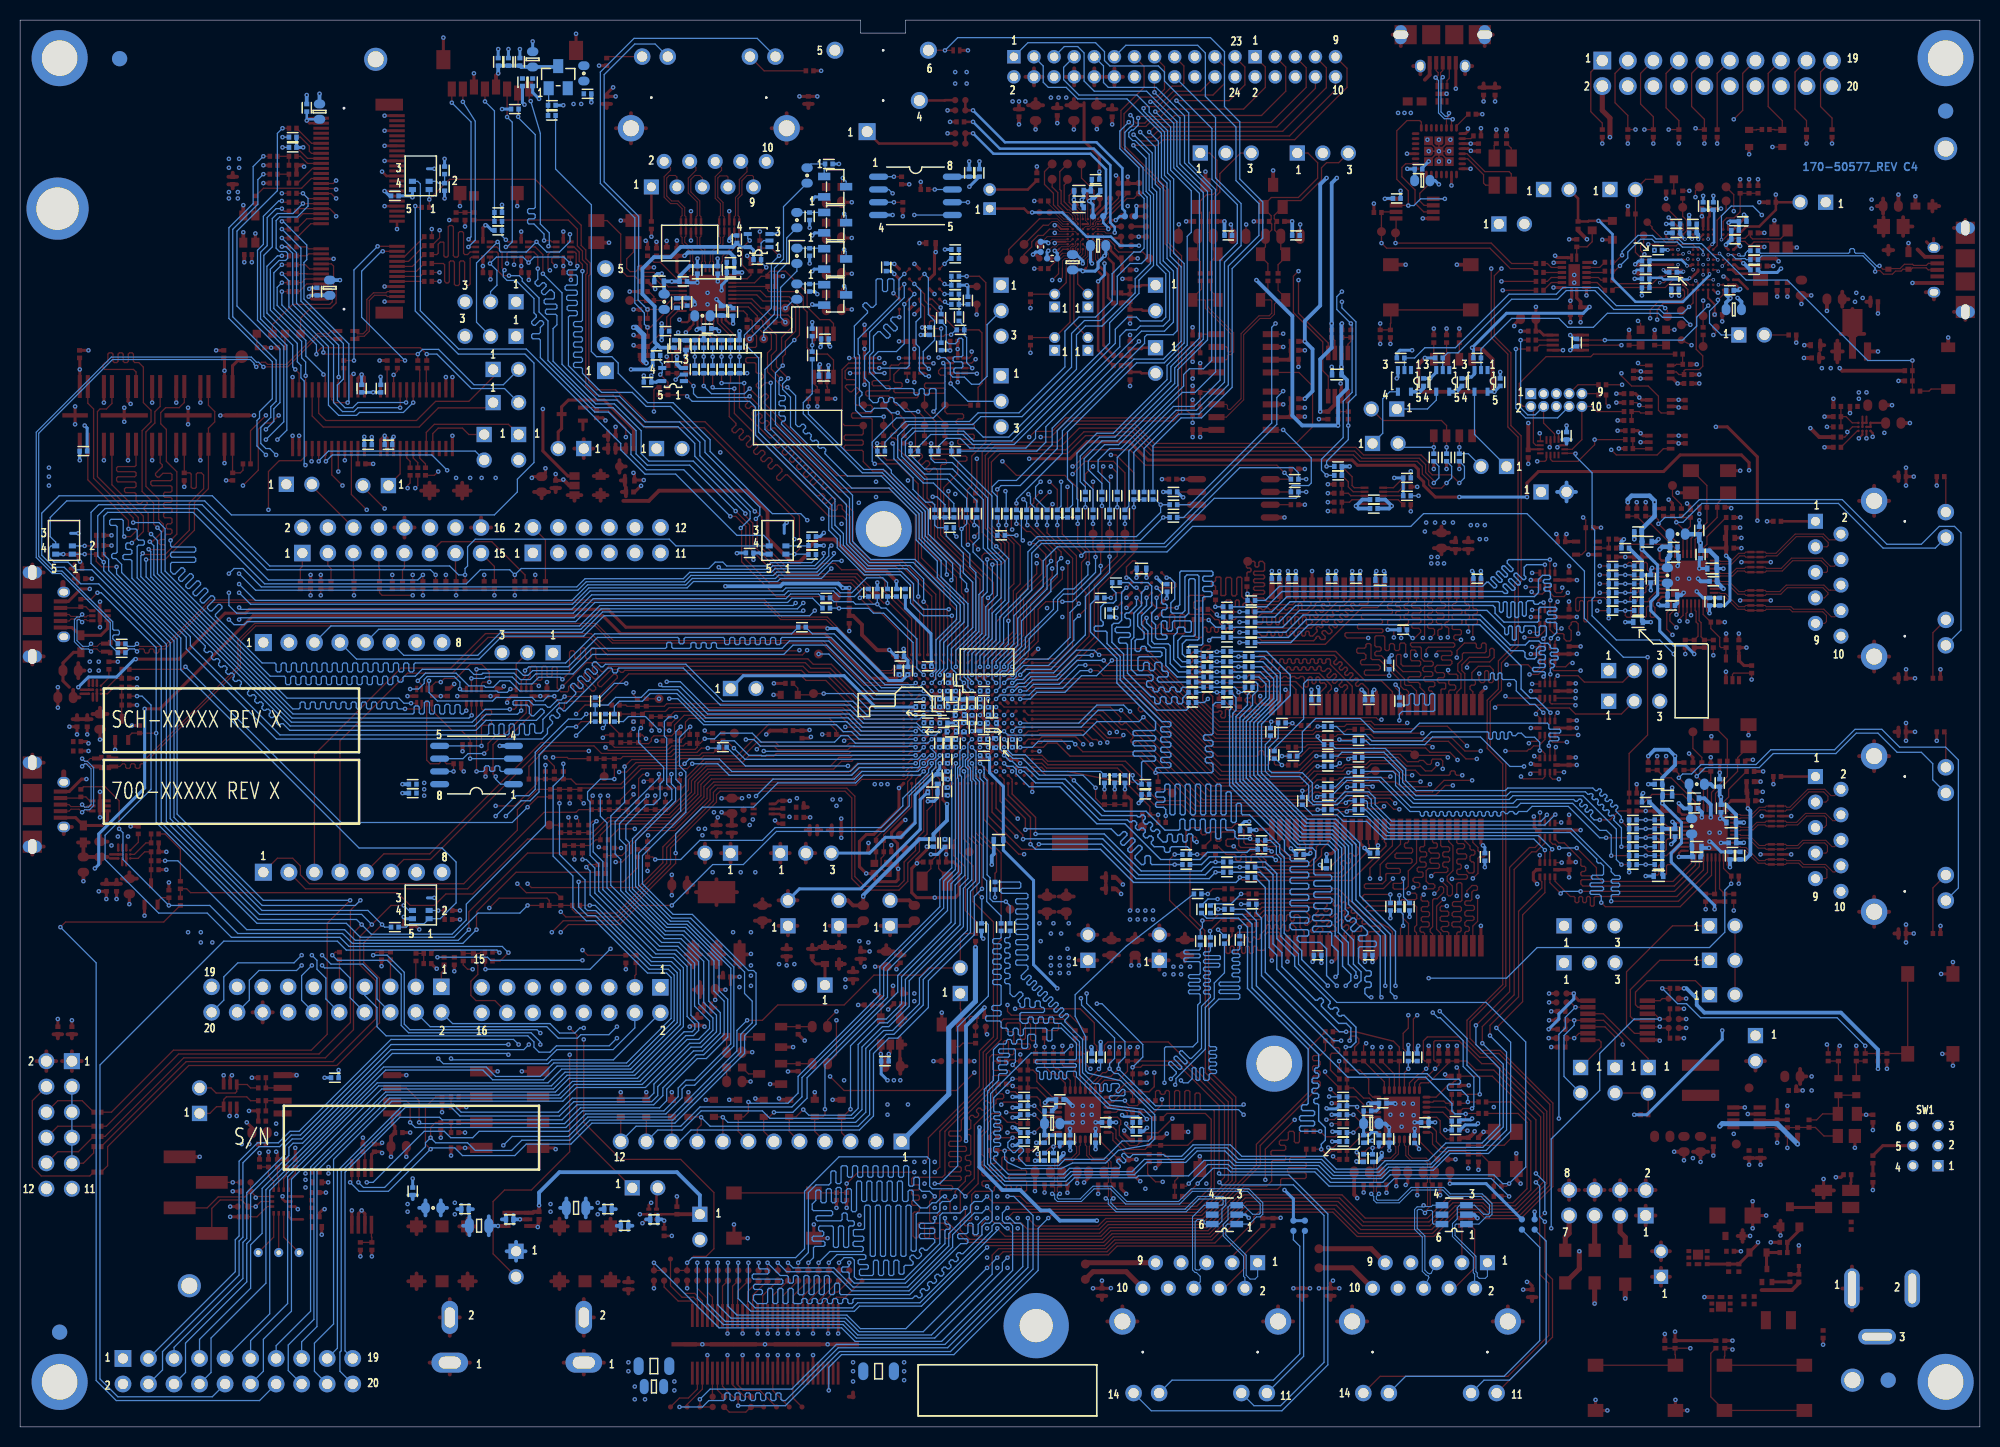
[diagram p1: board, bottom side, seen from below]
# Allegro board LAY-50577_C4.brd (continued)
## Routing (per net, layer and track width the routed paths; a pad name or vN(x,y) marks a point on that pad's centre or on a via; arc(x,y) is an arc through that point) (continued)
GND_RJ45_SHELL0: length 11.5
  TOP w0.381: J28.16 62.46,11.99 ; J28.16 63.96,10.49 ; J28.16 60.96,10.49 ; J28.15 48.47,10.49 ; J28.15 45.47,10.49 ; J28.15 46.97,11.99 ; 64.62,12.63 R404.2 ; R404.2 65.06,13.04 ; R404.2 64.19,13.04 ; 44.13,12.91 C181.2 ; C181.2 44.56,12.51 ; C181.2 44.99,12.91
GND_RJ45_SHELL1: length 14.5
  TOP w0.381: 132.72,129.24 J29.SH1 ; J29.SH1 134.22,130.74 ; J29.SH1 135.72,129.24 ; J29.SH1 134.22,127.74 ; J29.SH2 118.73,130.74 ; J29.SH2 118.73,127.74 ; J29.SH2 117.23,129.24 ; J29.SH2 120.23,129.24 ; C186.2 117,131.66 ; C186.2 116.13,131.66 ; C186.2 116.57,131.25 ; 136.2,131.66 R454.2 ; R454.2 136.63,131.25 ; R454.2 137.07,131.66
GND_RJ45_SHELL2: length 14.5
  TOP w0.381: C208.2 8.51,69.17 ; C208.2 8.1,68.73 ; C208.2 8.1,69.6 ; 10.52,49.76 J30.SH2 ; J30.SH2 12.02,51.26 ; J30.SH2 10.52,52.76 ; J30.SH2 9.02,51.26 ; R507.2 8.1,49.53 ; R507.2 8.51,49.1 ; R507.2 8.1,48.67 ; J30.SH1 12.02,66.75 ; J30.SH1 10.52,68.25 ; J30.SH1 9.02,66.75 ; J30.SH1 10.52,65.25
GND_RJ45_SHELL3: length 14.5
  TOP w0.381: 9.02,92.15 J31.SH1 ; J31.SH1 10.52,90.65 ; J31.SH1 12.02,92.15 ; J31.SH1 10.52,93.65 ; R560.2 8.51,94.57 ; R560.2 8.1,95 ; R560.2 8.1,94.13 ; 10.52,75.16 J31.SH2 ; J31.SH2 10.52,78.16 ; J31.SH2 12.02,76.66 ; J31.SH2 9.02,76.66 ; 8.1,74.07 C230.2 ; C230.2 8.51,74.5 ; C230.2 8.1,74.93
GND_RJ45_SHELL4: length 11.5
  TOP w0.381: 68.33,10.49 J32.15 ; J32.15 71.33,10.49 ; J32.15 69.83,11.99 ; 66.99,13.04 C509.2 ; C509.2 67.42,12.63 ; C509.2 67.85,13.04 ; 87.36,12.63 R1192.2 ; R1192.2 86.92,13.04 ; R1192.2 87.79,13.04 ; 83.82,10.49 J32.16 ; J32.16 85.32,11.99 ; J32.16 86.82,10.49
P3V3_SDA: length 89.6
  TOP w0.203: v1(30.69,112.58) 30.69,112.63 30.54,112.78 U55.A13 ; v4(31.05,117.12) 31.02,117.16 U55.A5 ; v1(31.22,118.82) 31.22,118.44 30.94,118.16 U55.A3 ; U55.A9 31.48,115.16 v4(31.5,115.14)
  TOP w0.254: U55.M1 25.04,119.8 v1(25,119.84) ; U55.N13 24.54,112.73 24.82,112.45 v1(24.82,112.32) 25.04,112.54 U55.M13 ; U55.N7 23.9,116.16 v1(23.54,115.8)
  TOP w0.279: U58.1 v1(40.76,108.65)
  TOP w0.305: R1088.1 31.22,122.86 v1(31.22,122.23) ; U57.1 29.99,102.2 v1(29.98,102.21) 29.95,102.18 C390.1 ; 39.73,111.97 40.12,112.35 U61.16 ; C388.1 29.34,98.65 v1(29.98,98.65) U56.1 ; R845.1 v1(25.64,110.02) ; U59.1 v1(33.76,104.33) 33.78,104.35 C386.1
  TOP w0.381: v1(39.1,118.19) 39.12,118.19 39.99,119.06 R829.2 ; 15.89,107.16 C373.1 ; C373.1 15.89,108.13 ; C373.1 15.48,107.65 ; 15.99,105.95 C371.1 ; C371.1 15.58,106.38 ; C371.1 15.99,106.81 ; 14.18,105.94 U62.3 ; U62.3 13.65,107.02 ; U62.3 14.71,107.02 ; U62.3 14.18,108.1 ; R814.1 15.98,98.5 v1(16.87,99.39) ; R851.1 v1(35.03,121.48) ; R863.2 34.14,115.65 34.19,115.7 v1(34.3,115.7) ; v1(13.95,105.36) 13.7,105.11 R808.1 ; R854.1 v1(34.91,109.17) ; v1(38.84,111.45) 38.87,111.43 C398.1 39.73,111.97 ; v1(55.23,106.38) 55.86,105.74 v1(55.86,103.01) v1(52.11,103.01) v1(48.31,103.01) 48.49,103.2 48.49,106.25 49.51,107.27 50.4,107.27 v1(50.53,107.39) ; R853.1 v1(32.37,109.17) ; v1(21.95,121.87) R830.2
  L3_INT_1 w0.381: v1(55.23,106.38) 55.73,106.38 v1(56.5,107.14)
  BOTTOM w0.127: 31.58,117.15 C347.1
  BOTTOM w0.254: v1(34.3,115.7) 33.97,116.03 R862.2 ; R864.2 v1(33.63,112.6) ; R865.2 v1(27.54,122.51)
  BOTTOM w0.305: v1(40.76,108.65) 40.39,108.28 C385.1 ; C576.1 v1(48.31,103.01) U366.5 ; R2111.1 50.39,107.26 v1(50.53,107.39) 47.1,110.82 39.47,110.82 v1(38.84,111.45) ; v4(31.05,117.12) 31.07,117.12 31.1,117.15 31.58,117.15 ; v1(56.5,107.14) 57.71,107.14 58.01,106.84 R2107.1 ; v4(31.5,115.14) 31.27,114.91 C349.1 ; R2109.1 v1(55.23,106.38)
  BOTTOM w0.381: v1(25,119.84) 24.87,119.97 C348.1 23.98,119.09 R866.2 ; R844.1 v1(28.93,120.6) ; C354.1 25.25,112.66 24.87,112.28 ; C353.1 25.25,111.89 24.87,112.28 ; C358.1 23.5,115.8 v1(23.54,115.8) ; U365.5 v1(52.11,103.01) 51.54,103.58 C575.1 ; v1(24.82,112.32) 24.87,112.28 ; U362.5 v1(55.86,103.01) 55.73,103.01 55.35,103.39 C574.1 ; R861.2 v1(31.22,118.82) ; C346.1 30.71,112.65 30.69,112.63 v1(30.69,112.58)
  vias: v1(14.84,105.36) v1(15.73,105.36)
P5V_SDA: length 16.5
  TOP w0.203: 11.29,100.55 U52.C1 U52.B1 ; U52.B2 U52.B1 ; U52.B1 11.69,100.55
  TOP w0.381: C370.1 10.9,112.4 ; C370.1 10.9,111.53 ; C370.1 11.3,111.97 ; U62.2 12.68,111.25 ; U62.2 11.5,108.77 ; U62.2 13.86,108.77 ; C372.1 13.7,112.97 ; C372.1 13.7,111.47 ; C372.1 13.07,112.22 ; R816.1 v1(14.58,102.31) ; L24.2 10.42,119.46 ; L24.2 9.59,118.53 ; L24.2 9.59,120.39 ; 9.63,120.74 C338.1 ; C338.1 9.63,122.24 ; C338.1 10.26,121.49 ; v1(20.56,115.52) R850.1
  vias: v1(10.78,122.13) v1(10.78,121.24) v1(11.28,102.95) v1(11.66,112.35) v1(12.05,102.95) v1(12.05,102.31) v1(12.3,112.85) v1(12.43,111.97)
VCC_I3C: length 5.4
  TOP w0.254: U46.5 166.87,22.93
  TOP w0.305: R773.2 v1(167.62,27.76) ; v1(173.84,23.45) R775.1 ; R776.1 v1(174.1,21.92) ; R774.1 v1(171.18,27.26) ; R777.1 v1(174.1,20.91)
  vias: v1(166.6,25.22) v1(166.6,24.59) v1(166.6,23.83)
VDD_1V8: length 272.8
  TOP w0.305: R706.1 v1(159.23,106.12) ; R2090.1 v1(99.05,41.73) ; C563.1 v1(40.41,43.13) 40.41,42.92 39.9,42.42 U361.14 ; U43.24 160.74,104.45 v1(161.02,104.73) 161.39,104.35 U43.23 ; 89.13,131.78 89.13,127.97 87.62,126.45 v1(87.62,124.91) ; v1(159.14,104.5) U44.1 ; U6.D11 v2(102.69,74.04) U6.E11 ; R2102.1 v1(42.91,39.58)
  TOP w0.381: 124.19,58.71 L2.1 ; L2.1 123.75,59.11 ; L2.1 124.62,59.11 ; 90.12,133.5 J47.8 ; J47.8 90.97,134.35 ; J47.8 90.12,135.2 ; J47.8 89.27,134.35 ; J4.1 124.31,58.04 ; J4.1 125.25,57.1 ; J4.1 124.31,56.16 ; J4.1 123.37,57.1 ; v1(113.14,83.49) v1(112.5,83.49) L7.1 ; C298.1 90.15,132.15 ; C298.1 89.4,131.52 ; C298.1 90.9,131.52 ; J11.1 119.36,58.04 ; J11.1 120.3,57.1 ; J11.1 119.36,56.16 ; J11.1 118.42,57.1 ; R1320.1 v1(64.5,109.81) ; 91.37,131.26 C299.1 ; C299.1 92.23,131.26 ; C299.1 91.8,131.67 ; v1(65.64,101.04) C524.1 64.19,101.73 U126.3
  L3_INT_1 w0.305: v1(42.91,39.58) 43.54,38.94 43.54,33.1 48.93,27.71 53.88,27.71 55.76,25.83 67.65,25.83 69.32,27.51 77.96,27.51 78.92,26.55 82.35,26.55 83.23,25.67 85.29,25.67 85.59,25.37 90.39,25.37 90.76,25 97.42,25 v1(100.88,28.46) 105.9,33.48 109.2,33.48 116.82,41.1 117.71,41.1 121.01,44.4 121.01,54.36 v1(121.85,55.2)
  L3_INT_1 w0.381: v1(63.99,124.28) 64.75,123.52 81.39,123.52 83.04,125.17 87.36,125.17 v1(87.62,124.91) ; v1(124.82,83.66) 124.82,85.8 125.33,86.31 v1(125.33,96.98)
  BOTTOM w0.305: v1(166.83,127.33) R692.1 R694.1 ; v1(40.41,43.13) 40.41,42.59 41.89,41.1 41.89,40.59 v1(42.91,39.58) ; C291.1 159.11,104.47 v1(159.14,104.5) ; R2135.1 v1(87.62,124.91) ; C290.1 v1(161.02,104.73) ; R2684.1 122.02,117.11 122.33,117.41 U410.5 123.28,117.41 C903.1
  BOTTOM w0.381: v1(63.99,124.28) 64.5,123.78 v1(64.5,109.81) 64.5,107.39 65.64,106.25 v1(65.64,101.04) ; R457.2 131.31,107.4 131.55,107.65 ; v1(134.22,105.23) 132.44,105.23 132.05,105.62 R2694.1 132.05,107.15 131.55,107.65 ; v1(99.05,41.73) 100.88,39.89 v1(100.88,28.46) ; v1(112.5,83.49) v1(113.14,83.49) 113.57,83.92 119.08,83.92 119.35,83.66 v1(124.82,83.66) ; 131.55,107.65 131.86,107.95 131.86,111.51 133.08,112.73 133.08,115.27 131.93,116.41 130.28,116.41 129.27,117.43 124.07,117.43 C903.1
  vias: v1(90.91,132.29) v1(91.67,132.29) v1(92.44,132.29) v1(100.82,134.83) v1(100.82,133.68) v1(101.96,134.83) v1(101.96,133.68)
VDD_AON_3V3: length 6.2
  TOP w0.381: R51.2 119.16,47.57 ; R51.2 118.29,47.57 ; R51.2 118.73,47.98 ; J9.1 119.54,49.86 ; J9.1 117.66,49.86 ; J9.1 118.6,48.92 ; 121.14,49.75 R52.1 ; R52.1 120.39,50.37 ; R52.1 121.89,50.37
VDD_AON_ANA: length 17.2
  TOP w0.254: U6.P12 v1(103.49,66.04)
  BOTTOM w0.305: v1(103.49,66.04) 103.49,65.48 103.69,65.28 C42.1 103.9,64.94 105.95,62.89 105.95,60.1 107.38,58.67 108.9,58.67 110.47,57.1 J11.3
VDD_AON_DIG: length 0.6
  TOP w0.305: U6.P11 v2(102.69,66.04)
VDD_AON_IN: length 25.9
  TOP w0.254: v2(104.69,63.17) U6.U14
  TOP w0.381: J9.2 118.6,53.34 ; J9.2 119.54,52.4 ; J9.2 117.66,52.4 ; R52.2 121.89,51.89 ; R52.2 121.14,52.52 ; R52.2 120.39,51.89
  BOTTOM w0.305: v2(104.69,63.17) 105.44,62.42 105.44,59.46 111.36,53.55 117.46,53.55 J9.2
VDD_BBSM_3V3: length 158.6
  TOP w0.305: R34.1 v1(10.14,35.64) ; C14.1 v1(11.32,31.06) 12.15,31.06 U2.4 ; R2098.1 v1(29.44,43.64)
  TOP w0.381: 113.52,45.58 D8.A ; D8.A 113.52,46.55 ; D8.A 112.93,46.07 ; 110.93,46.57 R43.2 ; R43.2 111.36,46.16 ; R43.2 111.79,46.57 ; R40.2 112.55,45.28 ; R40.2 111.69,45.28 ; R40.2 112.12,45.69
  L3_INT_1 w0.381: v1(99.55,29.8) 105.01,35.26 105.01,43.64 105.9,44.53 109.71,44.53 v1(110.98,45.8) ; v1(87.86,20.53) 76.91,20.53 76.02,21.41 69.07,21.41 68.31,20.65 53.96,20.65 51.03,23.57 43.29,23.57 41.89,24.97 20.17,24.97 14.08,31.06 v1(11.32,31.06) 11.32,34.46 v1(10.14,35.64)
  BOTTOM w0.381: v1(10.14,35.64) 10.14,37.54 13.82,41.23 27.41,41.23 28.17,41.99 28.17,42.62 29.19,43.64 v1(29.44,43.64) ; v1(99.55,29.8) 99.55,25.86 97.26,23.57 95.48,23.57 93.45,21.54 92.56,21.54 91.55,20.53 v1(87.86,20.53)
VDD_BBSM_ANA: length 11.2
  TOP w0.305: U6.R12 v2(102.69,65.24)
  L3_INT_1 w0.305: v2(102.69,65.24) 104.12,63.81 104.12,57.23 v1(104.37,56.97)
  BOTTOM w0.305: v1(104.37,56.97) 103.72,56.97 R47.2
VDD_BBSM_IN: length 19.3
  TOP w0.254: v1(102.77,61.98) 103.2,62.4 103.2,63.93 U6.U12
  TOP w0.381: v1(111.11,52.78) R41.2 112.12,51.89 112.63,52.4 J6.2
  BOTTOM w0.381: v1(102.77,61.98) 102.77,60.35 104.12,59.01 C34.1 105.52,58.49 111.11,52.91 v1(111.11,52.78)
VDD_COIN_3V: length 3.9
  TOP w0.305: J7.1 D9.A 114.94,46.09 115.84,46.09 116.19,46.43 R45.1
VDD_SOC_IN: length 15.5
  TOP w0.305: v2(99.49,71.64) U6.H8 v2(100.29,71.64) U6.H9 v2(101.09,71.64) U6.H10 v2(101.09,70.84) U6.J10 v2(101.09,70.04) ; v2(101.09,70.04) U6.J9 v2(100.29,70.84) U6.J8 ; v2(101.09,70.04) U6.K10
  TOP w0.381: 88.75,45.49 J14.1 ; J14.1 87.81,46.43 ; J14.1 89.69,46.43 ; 85.65,46.94 R59.1 ; R59.1 87.15,46.94 ; R59.1 86.4,46.32
  L4_PWR_1 w0.381: J14.1 89.69,46.43 ; J14.1 88.75,45.49 ; J14.1 88.75,47.37 ; J14.1 87.81,46.43
  vias: v1(90.66,46.69) v1(90.66,45.93) v1(90.66,45.16) v1(91.55,46.69) v1(91.55,45.93) v1(91.55,45.16) v1(92.44,46.69) v1(92.44,45.93) v1(92.44,45.16) v2(99.49,70.04)
VDD_USB_1P8: length 9.9
  TOP w0.305: v1(108.52,77.32) 108.18,76.99 108.18,76.79 107.43,76.04 U6.B17
  TOP w0.381: v1(108.52,77.32) 108.54,77.29 109.71,77.29 111.23,78.82 111.23,79.83 112.12,80.72 L6.2 L7.2
  BOTTOM w0.305: v1(108.52,77.32) 107.85,76.66 C85.1
VDD_USB_3P3: length 1.4
  TOP w0.305: U6.G12 v2(102.69,71.64)
  BOTTOM w0.254: L8.2 102.75,71.69 v2(102.69,71.64)
VDD_VREFH: length 20.8
  TOP w0.305: U6.H16 v2(105.89,71.64)
  BOTTOM w0.305: J10.1 123.04,74.75 113.01,74.75 109.89,71.64 v2(105.89,71.64)
VDDA_1P0: length 0.6
  TOP w0.305: U6.N11 v2(101.89,67.64)
VDDA_ADC_3P3: length 12.4
  TOP w0.254: C529.1 119.45,61 U312.3
  TOP w0.381: v1(120.76,68.91) 120.38,69.29 L3.2
  L3_INT_1 w0.381: v1(118.45,60.71) 119.36,61.62 119.36,67.52 v1(120.76,68.91)
ADC_1V8_IN: length 4.6
  TOP w0.305: v2(103.49,70.04) U6.J13 ; U6.M12 v2(103.49,67.64)
  TOP w0.381: 114.25,58.9 C58.1 ; C58.1 114.65,59.39 ; C58.1 114.25,59.87 ; 115.68,58.96 L4.2 ; L4.2 115.68,59.82 ; L4.2 115.28,59.39 ; 117.03,62.11 R1339.1 116.62,61.67
  vias: v1(108.69,63.96) v1(109.33,63.96) v1(109.96,63.96) v1(113.39,62.44) v1(113.77,61.8) v1(114.15,62.44) v1(117.71,62.56)
AUD_INT: length 46.4
  TOP w0.127: R2145.2 v1(94.09,115.27) ; v1(90.28,95.58) 90.15,95.58 88.5,97.23 84.56,97.23 83.04,95.71 69.95,95.71 v1(69.19,94.95)
  L3_INT_1 w0.127: v1(90.28,95.58) 90.28,100.28 95.1,105.11 95.1,114.25 v1(94.09,115.27)
  BOTTOM w0.127: v1(69.19,94.95) R2153.2
BOOT_MODE[0]: length 6.1
  TOP w0.127: SW5.4 v1(54.34,97.49) R707.2
  BOTTOM w0.127: R707.2 v1(54.34,97.49) 57.51,97.49 J102.2
BOOT_MODE[1]: length 11.6
  TOP w0.127: J103.2 59.42,100.15 53.57,100.15 53.07,99.65 SW5.3 v1(53.07,97.49) R709.2
  BOTTOM w0.127: R709.2 v1(53.07,97.49)
BOOT_MODE[2]: length 5.1
  TOP w0.127: R711.2 v1(51.8,97.49) SW5.2
  BOTTOM w0.127: v1(51.8,97.49) R711.2 50.9,96.85 J104.2
BT_DEV_WAKE: length 84.3
  TOP w0.127: v1(166,96.09) 165.94,96.15 U43.9 ; R1081.2 89.77,93.42 91.04,94.69 95.87,94.69 v1(97.26,96.09)
  L3_INT_1 w0.127: v1(97.26,96.09) 97.52,95.84 107.42,95.84 108.95,97.36 110.98,97.36 111.23,97.61 127.74,97.61 129.14,99.01 136.63,99.01 137.01,99.39 144.31,99.39 144.94,100.03 151.49,100.03 154.29,97.23 164.86,97.23 v1(166,96.09)
BT_DEV_WAKE_1V8: length 28.1
  TOP w0.127: U43.15 v1(166.59,104.6) ; J36.42 166.33,122.24 v1(166.86,122.76) R2168.2
  BOTTOM w0.127: v1(166.59,104.6) 166.59,105.98 166.99,106.38 166.99,108.03 170.1,111.14 170.1,115.2 169.22,116.08 168.59,116.08 168.38,116.28 168.38,116.79 168.56,116.97 169.2,116.97 169.53,117.3 169.53,120.04 169.17,120.4 167.44,120.4 166.35,121.49 166.35,122.25 v1(166.86,122.76)
BT_LED2_B: length 10.8
  TOP w0.127: D24.C 167.1,110.33 166.1,111.33 164.08,111.33 163.56,111.85 163.56,113.36 163.81,113.62 163.81,115.52 164.03,115.74 J36.16
BT_PCM_BCLK: length 72.4
  TOP w0.127: U43.7 164.64,96.16 v1(164.57,96.09)
  L3_INT_1 w0.127: v1(131.38,69.29) 131.38,70.13 131.93,70.69 131.93,78.48 126.98,83.44 126.98,92.28 130.13,95.43 133.05,95.43 133.46,95.84 142.22,95.84 142.6,96.22 J80.2 146.41,95.2 v1(152.51,95.2)
  BOTTOM w0.127: v1(131.38,69.29) 132.77,70.69 134.47,70.69 134.98,70.19 R1090.2 ; v1(164.57,96.09) 163.94,96.73 154.03,96.73 v1(152.51,95.2)
BT_PCM_BCLK_1V8: length 30.9
  TOP w0.127: v1(164.83,106.92) 164.66,106.76 v1(155.43,106.76) R701.1 ; R683.1 v1(168.95,112.98)
  BOTTOM w0.127: v1(168.95,112.98) 168.95,111.65 164.83,107.52 v1(164.83,106.92) ; v1(155.43,106.76) 154.96,107.23 153.36,107.23 149.84,103.71 146.92,103.71 J78.2
BT_PCM_RXD: length 82.1
  TOP w0.127: v1(153.4,95.07) 153.77,94.7 R699.2 ; U6.K13 v1(104.29,69.24)
  L3_INT_1 w0.127: v1(130.66,74.16) 130.66,78.56 126.26,82.96 126.26,92.71 129.74,96.18 132.66,96.18 133.08,96.6 135.74,96.6 138.16,99.01 142.6,99.01 143.87,97.74 149.71,97.74 151.62,95.84 152.63,95.84 v1(153.4,95.07)
  BOTTOM w0.127: v1(104.29,69.24) 104.69,69.63 105.4,69.63 105.8,70.04 111.09,70.04 112.38,71.33 126.47,71.33 129.31,74.16 v1(130.66,74.16)
BT_PCM_RXD_1V8: length 26.4
  TOP w0.127: U44.6 v1(155.89,101.93) ; R685.1 v1(168.95,114.76)
  BOTTOM w0.127: v1(155.89,101.93) 156.86,100.96 161.23,100.96 161.52,100.66 163.3,100.66 164.32,101.68 164.32,107.52 168.26,111.46 168.26,114.06 v1(168.95,114.76)
BT_PCM_SYNC: length 93.6
  TOP w0.127: U43.8 v1(165.29,96.09) ; U6.K14 v1(105.09,69.24)
  L3_INT_1 w0.127: J81.2 147.68,97.36 143.62,97.36 142.35,98.63 138.41,98.63 136,96.22 133.2,96.22 132.8,95.81 129.88,95.81 126.67,92.61 126.67,83.19 131.31,78.55 v1(131.31,73.86)
  BOTTOM w0.127: J81.2 149.71,97.11 164.32,97.11 165.29,96.14 v1(165.29,96.09) ; v1(131.31,73.86) 131.11,73.66 129.32,73.66 126.6,70.94 112.5,70.94 111.19,69.64 105.73,69.64 105.33,69.24 v1(105.09,69.24)
BT_PCM_SYNC_1V8: length 33
  TOP w0.127: R684.1 v1(168.95,113.87) ; R703.1 v1(154.54,106.76) 155.17,107.39 165.02,107.39 165.52,106.9 v1(165.52,106.75)
  BOTTOM w0.127: v1(154.54,106.76) 153.52,106.76 150.09,103.33 146.79,103.33 J79.2 ; v1(168.95,113.87) 169.42,113.4 169.42,111.61 165.52,107.7 v1(165.52,106.75)
BT_PCM_TXD: length 61.6
  TOP w0.127: v1(162.92,93.68) 163.99,94.75 U43.6
  L3_INT_1 w0.127: v1(162.92,93.68) 161.91,92.66 158.3,92.66 157.54,91.9 130.49,91.9 129.29,90.7 129.29,85.02 134.69,79.62 v1(134.69,73.99)
  BOTTOM w0.127: R1089.2 137.27,72.59 135.87,73.99 v1(134.69,73.99)
BT_PCM_TXD_1V8: length 15.6
  TOP w0.127: R687.1 v1(168.95,115.65) ; v1(164.82,104.73) 164.64,104.55 U43.18
  BOTTOM w0.127: v1(164.82,104.73) 164.82,104.82 166.57,106.56 166.57,108.12 169.75,111.31 169.75,114.85 v1(168.95,115.65)
BT_RST#: length 109.9
  TOP w0.127: R669.1 v1(170.8,124.67) ; R141.2 133.46,62.3 133.46,64.52 133.04,64.94 v1(132.61,64.94)
  L3_INT_1 w0.127: v1(169.53,96.73) 168.64,95.84 167.49,95.84 166.86,95.2 164.83,95.2 163.94,94.31 162.67,94.31 162.03,94.95 157.84,94.95 157.33,94.44 157.33,93.04 156.5,92.2 130.26,92.2 128.98,90.93 128.98,84.82 134.22,79.58 134.22,73.61 134.47,73.36 134.47,68.4 132.61,66.54 v1(132.61,64.94)
  BOTTOM w0.127: v1(169.53,96.73) 170.16,97.36 170.54,97.36 171.05,97.87 171.05,99.47 170.06,100.46 170.06,101.53 169.53,102.06 169.53,106.15 173.84,110.47 173.84,119.17 171.34,121.68 171.34,124.12 v1(170.8,124.67)
BT_UART10_CTS: length 55.1
  TOP w0.127: v1(155.68,93.42) 155.43,93.68 R697.2 ; R148.2 134.35,69.09 v1(133.97,69.47)
  L3_INT_1 w0.127: v1(133.97,69.47) 133.97,69.52 133.08,70.41 133.08,79.1 127.99,84.18 127.99,91.39 129.77,93.17 155.43,93.17 v1(155.68,93.42)
BT_UART10_RTS: length 60.6
  TOP w0.127: R149.2 133.97,72.84 v1(133.97,73.1) ; v1(163.34,95.07) U43.5
  L3_INT_1 w0.127: v1(133.97,73.1) 133.84,73.23 133.84,79.45 128.68,84.62 128.68,91.06 130.13,92.51 156.29,92.51 156.95,93.17 156.95,94.57 157.72,95.33 162.29,95.33 162.54,95.07 v1(163.34,95.07)
BT_UART10_RXD: length 53.8
  TOP w0.127: v1(156.44,93.42) 156.44,93.68 156.19,93.93 R696.2
  L3_INT_1 w0.127: v2(133.97,70.19) 133.46,70.7 133.46,79.2 128.3,84.36 128.3,91.13 130.03,92.87 155.89,92.87 v1(156.44,93.42)
BT_UART10_TXD: length 65.7
  TOP w0.127: R144.2 132.19,69.32 v1(132.16,69.29) ; U43.4 v1(162.69,96.19)
  L3_INT_1 w0.127: v1(132.16,69.29) 132.35,69.48 132.35,78.65 127.28,83.73 127.28,91.95 130.41,95.07 133.2,95.07 133.58,95.46 138.54,95.46 140.19,93.8 153.14,93.8 156.19,96.85 162.03,96.85 v1(162.69,96.19)
BT_UART_CTS_1V8: length 29.2
  TOP w0.127: U44.5 156.54,102.01 v1(156.6,101.94) ; R681.1 v1(168.95,119.2)
  BOTTOM w0.127: v1(156.6,101.94) 161.39,101.94 161.91,101.42 162.67,101.42 163.43,102.19 163.43,103.68 162.83,104.28 162.83,107.81 167.06,112.04 167.06,117.31 v1(168.95,119.2)
BT_UART_RTS_1V8: length 24.6
  TOP w0.127: v1(168.95,119.97) 168.83,120.09 R682.1 ; v1(162.41,101.93) 163.68,101.93 163.99,102.24 U43.19
  BOTTOM w0.127: v1(168.95,119.97) 168.83,119.97 166.48,117.62 166.48,116.16 166.76,115.88 166.76,112.25 162.29,107.77 162.29,102.06 v1(162.41,101.93)
BT_UART_RXD_1V8: length 27.5
  TOP w0.127: v1(157.19,101.42) U44.4 ; R678.1 168.93,117.43 v1(168.95,117.45)
  BOTTOM w0.127: v1(168.95,117.45) 168.54,117.45 167.87,116.79 167.87,111.71 163.81,107.65 163.81,101.93 162.92,101.04 161.78,101.04 161.4,101.42 v1(157.19,101.42)
BT_UART_TXD_1V8: length 18.2
  TOP w0.127: U43.20 163.34,104.44 v1(163.3,104.47) ; R680.1 v1(168.95,118.32)
  BOTTOM w0.127: v1(168.95,118.32) 167.49,116.86 167.49,111.84 163.3,107.65 v1(163.3,104.47)
BT_WAKE_B_3V3: length 92.9
  TOP w0.127: R677.1 v1(168.95,116.54) ; R143.2 v1(131.68,68.28)
  L3_INT_1 w0.127: v1(166.6,95.71) 166.48,95.58 162.54,95.58 161.78,96.34 156.45,96.34 153.6,93.5 134.4,93.5 133.2,94.69 130.66,94.69 127.66,91.69 127.66,83.9 132.75,78.82 132.75,69.19 131.83,68.28 v1(131.68,68.28)
  BOTTOM w0.127: v1(168.95,116.54) 169.4,116.54 170.44,115.5 170.44,110.85 167.42,107.83 167.42,106 167.06,105.64 167.06,104.41 166.73,104.08 166.73,95.84 v1(166.6,95.71)
CAN1_H: length 18.5
  TOP w0.127: R649.2 70.85,115.78 71.58,116.5 FL1.1 71.58,116.95 71.09,117.44 R650.1 70.47,119.12 70.47,119.71 C273.2 70.52,120.18 70.52,120.53 71.28,121.29 D21.2 71.28,121.57 70.5,122.34 67.82,122.34 65.89,124.27 65.89,125.81 66.86,126.77 J34.1
CAN1_L: length 17.5
  TOP w0.127: R652.2 69.83,115.65 69.08,116.4 FL1.2 69.56,117.19 R651.2 70.16,119.09 70.16,119.76 C275.1 70.21,120.23 70.21,120.57 D21.1 69.38,121.69 69.03,122.04 67.57,122.04 65.51,124.1 65.51,125.3 65,125.81 63.8,125.81 J34.3
CAN1_RX: length 10.4
  TOP w0.127: v1(69.32,99.22) U41.4
  BOTTOM w0.127: R1343.2 68.55,93.55 68.43,93.68 66.78,93.68 66.53,93.93 66.53,96.43 v1(69.32,99.22)
CAN1_TX: length 18.6
  TOP w0.127: v1(69.32,103.08) 69.37,103.03 U41.1
  BOTTOM w0.127: v1(69.32,103.08) 69.96,102.44 69.96,99.77 79.23,90.5 R1342.2
CAN3_H: length 15.3
  TOP w0.127: J35.1 76.63,126.77 75.93,126.06 75.93,123.01 76.31,122.63 76.94,122.63 78.01,121.57 D22.2 77.46,120.85 C279.2 77.46,118.85 R659.1 77.82,117.19 FL2.1 77.58,115.97 R658.2
CAN3_L: length 15
  TOP w0.127: J35.3 73.57,126.77 75.62,124.72 75.62,122.89 76.11,122.4 D22.1 76.68,120.83 C281.1 76.68,118.88 R660.2 76.29,117.19 FL2.2 76.56,115.95 R661.2
CAN3_RX: length 68.5
  TOP w0.127: U42.4 67.75,104.93 66.4,103.58 66.4,99.52 68.05,97.87 82.15,97.87 84.05,99.77 90.02,99.77 91.8,98 98.28,98 99.27,97.01 99.27,89.03 v1(97.87,87.63) ; U6.C8 v1(99.49,75.64)
  BOTTOM w0.127: v1(99.49,75.64) 99.49,76.72 97.9,78.31 97.9,80.85 96.63,82.12 96.63,86.39 v1(97.87,87.63)
CAN3_TX: length 40
  TOP w0.127: U42.1 69.37,108.74 v1(69.32,108.79)
  L3_INT_1 w0.127: v1(83.67,108.03) 83.04,108.66 69.45,108.66 v1(69.32,108.79)
  BOTTOM w0.127: v1(83.67,108.03) 92.31,99.39 92.31,97.74 95.87,94.19 97.64,94.19 98.28,93.55 98.28,93.09 97.77,92.59 R1344.2
CAN_STBY: length 110.4
  TOP w0.127: U6.L15 v1(105.89,68.44) ; v1(78.33,99.93) R647.1 78.97,101.17 78.97,107.13 R656.1
  L3_INT_1 w0.127: v1(78.33,99.93) 80.35,99.93 84.18,96.09 84.18,94.52 86.14,92.56 91.19,92.56 92.18,93.55 93.76,93.55 94.09,93.22 94.09,92.15 95.41,90.83 102.47,90.83 103.1,90.2 103.1,87.45 105.77,84.79 114.41,84.79 115.04,85.42 v1(115.04,86.95) ; v1(125.48,85.55) 125.48,82.81 129.88,78.41 129.88,73 v1(130.41,72.47)
  BOTTOM w0.127: v1(105.89,68.44) 111.52,68.44 112.27,69.19 113.09,69.19 113.77,69.88 126.98,69.88 129.57,72.47 v1(130.41,72.47) ; v1(115.04,86.95) 115.04,86.59 115.93,85.7 120.11,85.7 120.47,85.35 125.28,85.35 v1(125.48,85.55)
CCM_CLKO1_25M: length 90.3
  TOP w0.127: R1334.1 78.97,23.95 v1(78.72,24.21) ; R1332.1 47.1,23.95 v1(46.84,24.21)
  BOTTOM w0.127: v1(78.72,24.21) 76.82,26.11 74.78,26.11 74.36,25.69 65.98,25.69 64.62,24.34 59.42,24.34 58.67,25.08 48.35,25.08 47.48,24.21 v1(46.84,24.21) 45.19,25.86 45.19,38.31 49.13,42.24 63.99,42.24 67.8,46.05 67.8,47.07 69.55,48.82 69.55,56.54 70,56.99 70,57.78 70.59,58.37 R1330.2
CCM_ENET_REF_CLK_25M: length 161.9
  TOP w0.127: v1(77.83,24.21) 79.1,22.94 R1333.1 ; v1(102.63,93.12) 102.6,93.08 R1328.2 ; v1(46.84,22.94) R1331.1
  L3_INT_1 w0.127: v1(77.83,24.21) 79.15,22.89 83.62,22.89 84.42,23.69 88.26,23.69 89.62,22.33 93.83,22.33 94.95,23.45 99.04,23.45 99.29,23.7 99.29,24.74 106.13,31.57 109.4,31.57 116.92,39.1 118.25,39.1 122.79,43.64 122.79,48.85 124.44,50.5 124.44,55.07 123.3,56.21 123.3,57.74 124.06,58.5 124.06,62.69 125.08,63.71 125.08,70.69 126.12,71.73 126.12,76.13 121.63,80.61 121.63,83.28 119.01,85.9 117.57,85.9 116.68,86.79 116.68,88.1 111.26,93.53 103.04,93.53 v1(102.63,93.12)
  BOTTOM w0.127: v1(77.83,24.21) 76.31,25.73 74.91,25.73 74.56,25.38 66.17,25.38 64.75,23.95 59.04,23.95 58.27,24.72 48.62,24.72 v1(46.84,22.94)
CODEC_1V8: length 19.1
  TOP w0.081: U369.G4 91.93,118.7 v1(92.06,118.82) ; U369.G2 91.64,117.7 91.91,117.43 92.31,117.43 v1(92.69,117.05) ; 89.13,121.24 89.13,121.11 89.01,120.99 89.01,120.09 88.76,119.85 U369.C6
  TOP w0.203: U369.D6 U369.C6
  TOP w0.254: v1(89.36,122.13) 89.34,122.1 89.34,121.44 89.13,121.24
  L3_INT_1 w0.305: v1(89.36,122.13) 89.36,121.52 v1(92.06,118.82) 92.94,118.82 93.45,118.32 93.45,117.43 93.07,117.05 v1(92.69,117.05)
  BOTTOM w0.305: v1(92.69,117.05) 92.82,116.92 C586.1 ; R2135.2 88.37,123.53 88.47,123.43 C584.1 C585.1 89.17,122.32 v1(89.36,122.13) 89.36,121.56 C583.1
COEX1: length 41.5
  TOP w0.127: v1(163.56,124.03) 163.85,123.74 J36.48
  L3_INT_1 w0.127: v1(163.56,124.03) 160.89,124.03 159.38,122.52 157.32,122.52 156.57,123.27 140.44,123.27 135.24,118.06 135.24,111.71 J108.3
COEX2: length 37.9
  TOP w0.127: v1(163.56,123.14) 163.65,123.24 J36.46
  L3_INT_1 w0.127: v1(163.56,123.14) 161.02,123.14 160,122.13 157.08,122.13 156.32,122.89 140.57,122.89 135.62,117.93 135.62,113.87 J108.4
COEX3: length 32.8
  TOP w0.127: v1(163.56,122.25) 164.04,122.74 J36.44
  L3_INT_1 w0.127: v1(163.56,122.25) 162.31,121.01 153.65,121.01 153.3,121.36 151.87,121.36 151.52,121.01 140.6,121.01 137.78,118.19 137.78,116.28 J108.5
CONN_ENET_MDC: length 3.5
  TOP w0.127: R2593.1 125.61,14.53 J134.50
CONN_ENET_MDIO: length 3.7
  TOP w0.127: R2592.1 125.11,14.01 J134.48
CONN_ENET_RD0: length 4.1
  TOP w0.127: J134.36 122.11,13.08 R276.1
CONN_ENET_RD1: length 3.9
  TOP w0.127: J134.38 122.61,13.47 R277.1
CONN_ENET_RD2: length 3.9
  TOP w0.127: J134.42 123.61,13.48 R2618.1
CONN_ENET_RD3: length 3.7
  TOP w0.127: J134.44 124.11,14 R2619.1
CONN_ENET_RX_CTL: length 4.1
  TOP w0.127: J134.28 120.11,13.05 R274.1
CONN_ENET_RXC: length 4.1
  TOP w0.127: J134.32 121.11,13.06 R275.1
CONN_ENET_TD0: length 4.1
  TOP w0.127: R271.1 117.11,13 J134.16
CONN_ENET_TD1: length 4.3
  TOP w0.127: R2576.1 116.61,12.49 J134.14
CONN_ENET_TD2: length 4.3
  TOP w0.127: J134.10 115.61,12.47 R2617.1
CONN_ENET_TD3: length 4.8
  TOP w0.127: R2616.1 113.65,13.41 114.03,13.41 115.1,12.34 J134.8
CONN_ENET_TX_CTL: length 4.1
  TOP w0.127: R273.1 119.11,13.03 J134.24
CONN_ENET_TXC: length 4.1
  TOP w0.127: J134.20 118.11,13.02 R272.1
CPCA: length 3.3
  TOP w0.081: U369.B6 88.26,119.82 88.01,120.07 88.01,120.51 87.86,120.65
  TOP w0.127: C587.1 86.59,122.2
  TOP w0.254: 87.86,120.65 86.59,121.92 86.59,122.2
CPCB: length 2.3
  TOP w0.081: 88.12,120.98 88.26,120.84 U369.B7
  TOP w0.254: C587.2 87.56,121.54 88.12,120.98
CPVOUTN: length 3.4
  TOP w0.127: U369.A7 87.76,120.22 85.71,122.28 85.71,122.76
CPVOUTP: length 5.4
  TOP w0.081: U369.A6 87.42,119.7
  TOP w0.127: 83.67,122.76 84.18,122.25 84.87,122.25 87.42,119.7
DBG_OUT_3V3: length 1.8
  TOP w0.127: U72.16 52.08,129.46 C411.1
DBG_RXLED: length 1.6
  TOP w0.127: R899.2 46.63,127.25 D37.1
DBG_TXLED: length 1.5
  TOP w0.127: R898.2 48.33,127.51 D37.3
DBGIF_DETECT: length 20.9
  TOP w0.127: v1(36.94,101.55) 37.2,101.81 R840.1
  L3_INT_1 w0.127: v1(36.94,101.55) 36.56,101.17 33.64,101.17 31.22,103.58 31.22,109.3 30.54,109.98 30.54,111.28 29.37,112.45 29.37,114.51 29.31,114.56 29.07,114.81 28.89,114.81 v3(28.54,115.16)
DBGIF_ISP0_CTRL: length 16.1
  TOP w0.127: U55.C13 29.39,113.01 29.39,112.44 29.73,112.11 31.87,112.11 32.81,111.17 v1(32.81,110.33) ; R841.1 35.61,103.71 v1(35.61,103.71)
  L3_INT_1 w0.127: v1(32.81,110.33) 32.87,110.26 32.87,104.47 33.64,103.71 35.6,103.71 v1(35.61,103.71)
DBGIF_ISP1_CTRL: length 36.7
  TOP w0.127: v1(31.32,111.33) 31.1,111.11 TP57.1
  L3_INT_1 w0.127: v1(31.32,111.33) 31.32,112.94 30.04,114.22 v3(30.04,115.66)
  BOTTOM w0.127: v1(31.32,111.33) 31.57,111.58 36.18,111.58 37.98,113.39 41.48,113.39 42.14,112.73 46.85,112.73 52.19,107.39 55.23,107.39 56.24,106.38 R2107.2 57.26,106.37 U362.2
DBGIF_ISP2_CTRL: length 32.5
  TOP w0.127: TP58.1 29.32,111.08 v1(28.94,111.46) 28.54,111.85 U55.E13
  BOTTOM w0.127: v1(28.94,111.46) 29.57,110.82 31.47,110.82 31.85,111.2 36.43,111.2 38.31,113.08 41.15,113.08 42.02,112.22 46.59,112.22 51.92,106.89 52.95,106.89 R2109.2 53.45,106.37 U365.2
DBGIF_ISP3_CTRL: length 33.2
  TOP w0.127: TP59.1 v1(28.81,109.68)
  L3_INT_1 w0.127: v3(27.54,115.66) 28.05,115.15 28.05,114.57 27.79,114.32 27.79,112.98 28.43,112.35 28.43,110.06 v1(28.81,109.68)
  BOTTOM w0.127: U366.2 49.64,105.87 49.64,105.88 R2111.2 49.64,107.26 46.59,110.31 41.89,110.31 41,109.43 38.46,109.43 37.06,110.82 31.98,110.82 31.58,110.42 29.55,110.42 v1(28.81,109.68)
DBGIF_ISP4_CTRL: length 6.2
  TOP w0.127: R822.2 TP60.1 27.54,112.07 27.53,112.08 v1(27.53,112.09) ; v4(26.52,114.16) U55.G11
  L3_INT_1 w0.127: v4(26.52,114.16) 26.59,114.16 26.98,113.77 26.98,112.64 v1(27.53,112.09)
DBGIF_RESET: length 28.6
  TOP w0.127: v4(28.93,116.88) 28.71,116.66 U55.E6 ; v1(35.67,104.85) 35.67,104.6 34.65,103.58 33,103.58 31.98,102.57 31.98,101.17 31.72,100.9 U57.3
  L3_INT_1 w0.127: v4(28.93,116.88) 29.32,117.27 29.44,117.27 29.93,117.76 31.35,117.76 31.76,118.16 34.86,118.16 36.3,116.72 36.3,105.49 v1(35.67,104.85)
DBGIF_RESET_TXEN: length 17.5
  TOP w0.127: U57.5 33.76,101.55 v1(33.89,101.68) 34.14,101.93 R837.1 ; v1(32.11,110.19) 32.11,111.2 31.52,111.8 29.58,111.8 29.06,112.32 29.06,113.18 U55.C12
  L3_INT_1 w0.127: v1(33.89,101.68) 31.73,103.84 31.73,109.81 v1(32.11,110.19)
DBGIF_TCK_SWCLK: length 17.4
  TOP w0.127: U58.2 v1(37.32,108.15) ; v4(26.02,113.66) U55.L12
  L3_INT_1 w0.127: v1(27.03,111.58) 26.6,112.02 26.6,113.07 v4(26.02,113.66)
  BOTTOM w0.127: v1(37.32,108.15) 29.58,108.15 28.17,109.55 28.17,110.44 v1(27.03,111.58)
DBGIF_TDI: length 20.7
  TOP w0.127: U58.3 35.96,107.65 35.96,107.65 v1(35.67,107.65) ; v1(33,117.68) 31.98,117.68 31.84,117.54 30.21,117.54 30.07,117.68 28.56,117.68 28.04,117.16 U55.F5
  L3_INT_1 w0.127: v1(35.67,107.65) 35.67,109.55 35.29,109.93 35.29,116.16 33.76,117.68 v1(33,117.68)
DBGIF_TDO_SWO: length 38
  TOP w0.127: v4(28.04,116.19) U55.F8 ; U56.3 31.49,97.35 32.11,96.73 36.18,96.73 v1(36.68,97.23)
  L3_INT_1 w0.127: v1(36.68,97.23) 36.68,100.28 37.57,101.17 37.57,103.84 36.68,104.73 36.68,116.82 35.03,118.47 31.63,118.47 31.22,118.06 29.8,118.06 29.32,117.57 28.55,117.57 28.04,117.06 v4(28.04,116.19)
DBGIF_TMS_SWDIO: length 12.3
  TOP w0.127: U55.B11 30.36,114.48 30.82,114.48 31.43,113.87 v4(31.86,113.87) ; v1(34.02,105.87) 33.78,105.63 U59.3
  L3_INT_1 w0.127: v4(31.86,113.87) 31.86,112.98 33.38,111.46 33.38,106.5 v1(34.02,105.87)
DBGIF_TMS_SWDIO_TXEN: length 11.8
  TOP w0.127: U59.5 30.21,104.98 29.95,104.73 R836.1 29.44,105.1 29.31,105.22 27.9,105.22 27.58,105.55 27.58,106.59 28.23,107.24 28.23,112.97 U55.F13
DBGIF_VREF: length 6.5
  TOP w0.127: U55.L1 25.54,119.96 25.19,120.31 24.46,120.31 23.86,120.91 C392.1 R839.1 R838.2
DBUG_5V: length 6.4
  TOP w0.279: U72.19 v1(50.67,127.7) ; U72.1 v1(56.98,125.2)
  TOP w0.305: v1(50.67,127.7) 50.66,127.71 C413.1 ; R900.1 v1(49.64,129.24) ; R898.1 v1(48.11,129.11) ; R899.1 v1(47.1,129.11)
  BOTTOM w0.305: v1(56.98,125.2) 56.95,125.17 C412.1 56.24,124.04 C414.1
  vias: v1(56.62,130.76) v1(57.26,130.76) v1(57.89,130.76)
DBUG_RST: length 1.2
  TOP w0.127: U72.18 50.67,128.2 R900.2
DBUG_USB_DM: length 8.8
  TOP w0.119: U74.1 54.02,134.14 v1(54.16,134.28) 53.91,134.53 53.91,134.78 54.1,134.97 J60.2 ; v1(52.46,130.13) 52.58,130.01 U72.15
  BOTTOM w0.119: v1(52.46,130.13) 52.51,130.19 53.3,130.19 53.87,130.76 53.87,133.99 v1(54.16,134.28)
DBUG_USB_DP: length 8.8
  TOP w0.119: J60.3 53.45,134.98 53.66,134.77 53.66,134.53 v1(53.45,134.32) 53.52,134.24 U74.2 ; v1(52.83,130.74) 52.83,130.42 53.08,130.17 U72.14
  BOTTOM w0.119: v1(52.83,130.74) 52.83,130.57 52.97,130.43 53.19,130.43 53.62,130.86 53.62,134.14 v1(53.45,134.32)
DC_5V_IN: length 6.3
  TOP w0.381: J2.1 12.73,15.96 ; J2.1 13.68,13.77 ; J2.1 11.78,13.77 ; J2.1 12.73,11.59
DC_GPIO1: length 57.9
  TOP w0.127: J47.21 75.16,135.4 75.16,133.68 76.31,132.54 80.05,132.54 81.7,130.89 v1(82.05,130.89)
  BOTTOM w0.127: R1083.2 89.77,92.28 89.85,92.36 89.85,96.9 87.86,98.88 86.22,98.88 80.88,104.22 80.88,105.64 78.87,107.65 78.87,118.48 78.47,118.88 78.47,123.01 80.52,125.07 80.52,129.36 v1(82.05,130.89)
DC_GPIO2: length 58.4
  TOP w0.127: v1(95.87,91.9) R1086.2 ; v1(83.22,131.23) 83.21,131.23 83.04,131.4 81.77,131.4 80.24,132.92 77.55,132.92 J47.22
  BOTTOM w0.127: v1(83.22,131.23) 83.22,130.94 81.13,128.86 81.13,124.54 80.56,123.97 80.56,116.53 79.48,115.45 79.48,108.03 81.25,106.26 84.17,106.26 91.29,99.14 91.29,96.88 95.87,92.3 v1(95.87,91.9)
DC_I2S1_MCLK: length 69.7
  BOTTOM w0.127: J47.1 96.12,136.35 94.72,137.75 87.99,137.75 87.1,136.86 87.1,135.97 86.57,135.44 81.74,135.44 81.13,134.83 81.13,133.94 76.41,129.21 76.41,124.16 73.89,121.64 73.89,117.81 75.61,116.09 75.61,104.16 78.21,101.55 80.25,101.55 84.68,97.12 84.68,91.62 85.05,91.26 R95.2
DC_I2S1_RX_BCLK: length 63.3
  BOTTOM w0.127: J47.5 91.1,137.37 89.77,137.37 89.13,136.73 89.13,133.94 88.12,132.92 82.91,132.92 79.9,129.91 79.9,125.47 77.27,122.84 77.27,108.23 80.12,105.39 80.12,103.84 85.83,98.12 87.36,98.12 89.13,96.34 89.13,94.19 88.25,93.3 R98.2
DC_I2S1_RX_D0: length 61.7
  BOTTOM w0.127: R96.2 83.17,97.36 79.74,100.79 77.71,100.79 74.78,103.71 74.78,115.52 71.74,118.57 71.74,121.74 74.02,124.03 74.02,129.36 77.07,132.41 77.07,136.73 77.83,137.49 84.97,137.49 J47.11
DC_I2S1_RX_SYNC: length 59.4
  BOTTOM w0.127: R99.2 86.59,93.93 87.74,95.08 87.74,96.22 86.59,97.36 85.45,97.36 79.23,103.58 79.23,104.73 78.66,105.3 77.26,105.3 76.43,106.12 76.43,123.09 79.14,125.8 79.14,130.48 80.59,131.93 81.96,133.3 86.72,133.3 87.2,133.78 87.2,135.43 88.12,136.35 J47.9
DC_I2S1_TX_BCLK: length 56
  TOP w0.127: v1(79.94,131.98) 74.71,131.98 73.13,133.56 73.13,135.33 74.12,136.32 J47.23
  BOTTOM w0.127: R94.2 85.83,96.47 79.36,102.95 78.09,102.95 76.05,104.98 76.05,123.14 78.72,125.81 78.72,130.76 v1(79.94,131.98)
DC_I2S1_TX_D0: length 54.1
  TOP w0.127: J47.17 79.2,135.44 79.2,133.71 79.48,133.43 80.37,133.43 81.93,131.87 v1(82.53,131.87)
  BOTTOM w0.127: R92.2 89.01,93.55 89.52,94.06 89.52,96.6 87.61,98.5 86.06,98.5 80.5,104.07 80.5,105.51 77.65,108.36 77.65,122.75 80.21,125.3 80.21,129.71 82.36,131.87 v1(82.53,131.87)
DC_I2S1_TX_D1: length 49.7
  BOTTOM w0.127: J47.18 76.05,130.29 76.05,124.28 73.51,121.74 73.51,117.55 75.16,115.9 75.16,103.96 77.96,101.17 79.99,101.17 84.18,96.98 R97.2
DC_I2S1_TX_SYNC: length 49.8
  TOP w0.127: v1(82.13,132.81) 82.13,134.33 J47.16
  BOTTOM w0.127: v1(82.13,132.81) 79.6,130.27 79.6,125.68 76.85,122.94 76.85,108.17 79.8,105.22 79.8,103.65 85.71,97.74 87.1,97.74 88.72,96.13 88.72,95.26 87.36,93.9 R93.2
DC_I2S4_MCLK: length 79.7
  TOP w0.127: v1(83.75,130.26) 83.59,130.42 81.48,130.42 80.75,131.14 73.26,131.14 71.1,133.3 71.1,135.33 J48.1
  BOTTOM w0.127: R125.2 99.8,92.15 102.47,94.82 105.01,94.82 106.91,96.73 106.91,98.12 105.95,99.09 101.1,99.09 100.31,98.3 100.13,98.12 96.32,98.12 86.59,107.85 86.59,109.87 83.67,112.8 83.67,114.12 82.23,115.57 82.23,122.64 82.66,123.07 82.66,126.63 84.04,128.01 84.29,128.01 84.68,128.4 84.68,128.79 84.41,129.07 84.23,129.07 83.75,129.54 v1(83.75,130.26)
DC_I2S4_RX_BCLK: length 75.2
  TOP w0.127: v1(84.69,129.85) 84.26,129.42 82.99,129.42 82.59,129.81 70.53,129.81 67.04,133.3 67.04,135.27 J48.5
  BOTTOM w0.127: R133.2 108.95,97.99 106.89,100.05 100.54,100.05 99.68,100.92 95.61,100.92 91.04,105.49 91.04,109.04 89.64,110.44 87.99,110.44 86.34,112.09 86.34,114.76 84.18,116.92 83.55,116.92 83.17,117.3 83.17,122.25 83.67,122.76 83.67,125.3 85.58,127.21 85.58,128.96 v1(84.69,129.85)
DC_I2S4_RX_D0: length 67
  TOP w0.127: v1(82.66,128.86) 82.15,129.36 69.96,129.36 66.12,133.21 J48.8
  BOTTOM w0.127: v1(82.66,128.86) 81.74,127.94 81.74,124.01 81.26,123.52 81.26,116.03 80.24,115.01 80.24,109.93 81.13,109.04 83.42,109.04 92.94,99.52 92.94,98 93.83,97.11 R134.2
DC_I2S4_RX_SYNC: length 74.7
  TOP w0.127: J48.7 65.03,135.26 65.03,133.28 69.37,128.93 81.82,128.93 82.4,128.35 83.04,128.35 v1(83.55,128.86)
  BOTTOM w0.127: R132.2 103.62,97.61 102.85,98.38 101.45,98.38 100.49,97.41 94.93,97.41 93.96,98.38 93.96,99.11 85.58,107.49 85.58,108.54 84.94,109.17 83.93,109.17 83.55,109.55 81.26,109.55 80.63,110.19 80.63,114.89 81.58,115.84 81.58,123.21 82.05,123.68 82.05,127.36 v1(83.55,128.86)
DC_I2S4_TX_BCLK: length 82.7
  TOP w0.127: J48.3 70.08,136.35 69.07,135.33 69.07,132.92 71.48,130.51 80.12,130.51 80.51,130.11 82.73,130.11 83.09,129.75 83.96,129.75 84.22,130.01 84.22,130.23 v1(84.53,130.54)
  BOTTOM w0.127: v1(84.53,130.54) 84.22,130.23 84.22,129.63 84.48,129.37 84.54,129.37 85.07,128.84 85.07,127.13 83.27,125.33 83.27,122.79 82.86,122.38 82.86,116.33 83.42,115.78 84.56,115.78 85.83,114.51 85.83,111.79 87.52,110.1 89.1,110.1 90.38,108.82 90.38,105.46 95.31,100.54 99.42,100.54 100.21,99.75 106.56,99.75 107.68,98.63 107.68,96.47 105.14,93.93 104.12,93.93 102.09,91.9 R127.2
DC_I2S4_TX_D0: length 75.6
  TOP w0.127: J48.10 64.12,133.05 68.69,128.48 81.51,128.48 82.02,127.97 83.59,127.97 v1(84.21,128.6)
  BOTTOM w0.127: R131.2 105.65,97.51 104.4,98.76 101.2,98.76 100.21,97.77 96.09,97.77 86.03,107.83 86.03,109.23 84.82,110.44 83.93,110.44 83.55,110.06 81.39,110.06 81.01,110.44 81.01,114.76 81.91,115.66 81.91,122.9 82.35,123.35 82.35,126.77 84.18,128.6 v1(84.21,128.6)
DC_I2S4_TX_SYNC: length 86.3
  TOP w0.127: v1(84.23,127.54) 81.82,127.54 81.26,128.09 68.18,128.09 62.97,133.3 62.97,135.21 J48.9
  BOTTOM w0.127: v1(84.23,127.54) 84.23,127.51 82.96,126.24 82.96,122.95 82.53,122.52 82.53,115.78 84.05,114.25 84.05,112.85 87.35,109.55 89.01,109.55 89.89,108.67 89.89,105.24 96.63,98.5 99.17,98.5 100.06,99.39 106.21,99.39 107.3,98.31 107.3,96.6 105.01,94.31 102.72,94.31 100.82,92.41 R129.2
DC_INT: length 65
  TOP w0.127: v1(97.77,93.3) R1085.2
  BOTTOM w0.127: v1(97.77,93.3) 97.39,93.68 95.48,93.68 91.8,97.36 91.8,99.14 83.12,107.83 83.12,108.46 82.89,108.69 80.27,108.69 79.86,109.1 79.86,115.27 80.88,116.28 80.88,123.78 81.44,124.34 81.44,128.73 84.87,132.16 89.77,132.16 90.91,133.3 92.69,133.3 93.2,133.81 93.2,135.43 J47.3
DC_RESET: length 60.7
  BOTTOM w0.127: J47.7 91.17,135.3 91.17,134.06 89.64,132.54 83.87,132.54 82.66,131.33 82.66,130.83 80.83,129.01 80.83,124.79 80.22,124.18 80.22,116.82 79.18,115.78 79.18,107.86 81.15,105.89 83.91,105.89 90.79,99.01 90.79,94.31 90.28,93.8 90.28,91.77 R1084.2
DCDC_1V8_OUT: length 32.5
  TOP w0.305: v1(112.5,79.2) L6.1
  TOP w0.381: J77.2 106.53,52.4 R58.2
  L3_INT_1 w0.381: v1(112.5,79.2) 113.26,78.44 113.26,71.96 110.72,69.42 110.72,59.77 109.33,58.37 109.33,56.21 108.44,55.32 J77.2
DCDC_3V3: length 4.1
  TOP w0.305: R14.1 20.17,32.59
  TOP w0.381: J3.2 23.27,36.4 ; J3.2 22.33,35.46 ; J3.2 21.39,36.4
DCDC_3V3_PG: length 214.4
  TOP w0.305: v1(142.98,101.3) 142.98,97.12 140.49,94.63 U5.3 ; v1(94.6,96.34) 90.53,96.34 88.84,98.03 84.6,98.03 82.78,96.22 62.46,96.22 61.94,95.7 56.28,95.7 55.87,95.29 55.87,94.58 55.34,94.05 55.34,93.69 54.18,92.53 v1(51.8,92.53) ; v1(22.97,95.2) 22.97,95.96 23.73,96.73 29.83,96.73 31.48,95.07 43.92,95.07 45.07,93.93 v1(45.07,92.53)
  L3_INT_1 w0.305: v1(94.6,96.34) 95.99,96.34 98.91,99.27 127.77,99.27 130.16,101.65 142.63,101.65 v1(142.98,101.3) ; v1(22.97,95.2) 19.41,91.65 19.41,43.89 14.59,39.07 14.59,34.24 19.67,29.16 v1(24.49,29.16)
  BOTTOM w0.305: v1(45.07,92.53) v1(51.8,92.53)
DMIC_CLK: length 248.1
  TOP w0.127: v1(156.83,51.89) 158.1,51.89 v1(160,49.99) 161.19,48.8 161.19,45.98 159.62,44.4 159.62,40.59 163.86,36.35 178.47,36.35 R1021.2 ; R867.2 v1(150.73,84.79)
  BOTTOM w0.127: U116.4 156.33,51.4 v1(156.83,51.89) ; v1(160,49.99) 161.02,51.01 171.18,51.01 180.45,60.28 180.45,77.88 187.86,85.3 189.46,85.3 190.23,86.06 191.62,86.06 192.08,86.52 192.08,87.51 191.91,87.67 U117.4 191.46,88.05 192,88.6 192,90.5 190.35,92.15 176.64,92.15 170.16,85.68 152.25,85.68 151.36,84.79 v1(150.73,84.79) 150.73,85.42 150.48,85.68 150.48,87.58 149.71,88.34 130.41,88.34 129.74,87.67 U118.4 120.46,88.17 121.01,88.72 123.68,88.72 129.77,94.82 132.82,94.82 135.24,97.23 135.24,97.87 144.63,107.27 151.36,107.27 155.17,111.08 155.17,123.7 155.43,123.95 U119.4
DMIC_DATA0: length 144.5
  TOP w0.127: R1022.1 186.29,25.99 186.29,27.89 178.21,35.97 163.48,35.97 159.24,40.21 159.24,44.66 160.81,46.23 160.81,48.16 v1(158.98,49.99) ; R868.2 v1(153.65,84.79)
  BOTTOM w0.127: v1(153.65,84.79) 154.16,85.3 170.41,85.3 176.89,91.77 187.18,91.77 187.94,91.01 187.94,85.93 180.07,78.06 180.07,60.53 170.93,51.4 160.39,51.4 v1(158.98,49.99) 158.73,49.74 R343.2
DMIC_DATA1: length 170.2
  TOP w0.127: v1(162.16,52.4) 164.45,50.12 164.45,39.07 166.02,37.49 179.74,37.49 185.91,31.32 R1023.1 ; R100.2 v1(145.78,84.79)
  BOTTOM w0.127: R344.2 115.81,86.43 116.24,86.01 120.3,86.01 120.63,85.68 124.69,85.68 125.08,86.06 125.84,86.06 126.47,85.42 145.14,85.42 v1(145.78,84.79) 146.28,85.3 149.21,85.3 150.6,83.9 170.67,83.9 177.78,91.01 186.29,91.01 186.67,90.63 186.67,86.82 186.19,86.34 186.19,85.22 179.38,78.41 179.38,60.99 170.8,52.4 v1(162.16,52.4)
DMIC_DATA2: length 134.4
  TOP w0.127: R1024.1 186.42,29.92 179.23,37.11 165.26,37.11 162.13,40.24 162.13,51.41 v1(161.14,52.4) ; R348.2 v1(186.68,86.06) ; R101.2 v1(154.92,84.79)
  BOTTOM w0.127: v1(161.14,52.4) 161.65,51.89 170.92,51.89 179.69,60.66 179.69,78.21 186.68,85.21 v1(186.68,86.06) 187.27,86.66 187.27,90.66 186.54,91.39 177.4,91.39 170.29,84.28 155.43,84.28 v1(154.92,84.79)
DMIC_DATA3: length 220.9
  TOP w0.127: R102.2 v1(142.73,65.86) ; v1(161.02,49.99) 161.83,49.18 161.83,39.53 164.63,36.73 178.72,36.73 186.54,28.91 R1025.1 ; v1(155.68,121.49) 155.56,121.36 R350.2
  BOTTOM w0.127: v1(155.68,121.49) 155.68,111.05 151.4,106.76 144.76,106.76 143.87,105.87 143.87,95.96 145.52,94.31 145.52,93.04 147.81,90.76 173.97,90.76 175.88,92.66 191.12,92.66 192.85,90.93 192.85,86.75 191.65,85.55 190.61,85.55 188.96,83.9 187.18,83.9 180.96,77.68 180.96,60.15 171.3,50.5 161.52,50.5 v1(161.02,49.99) 160.06,49.03 152.02,49.03 150.6,50.45 150.6,52.02 142.73,59.9 v1(142.73,65.86)
ECAT0_RST_B: length 153.1
  TOP w0.127: v1(55.99,40.97) 56.37,40.59 56.37,37.54 55.99,37.16 R1274.1
  L3_INT_1 w0.127: v1(55.99,40.97) 56.5,41.48 62.46,41.48 66.4,37.54 66.4,35.26 68.69,32.97 73.97,32.97 79.38,27.56 85.15,27.56 86.32,26.39 91.01,26.39 91.41,26 96.51,26 106.79,36.27 110.34,36.27 116.44,42.37 117.33,42.37 119.97,45.01 119.97,54.87 120.99,55.88 120.99,63.17 122.29,64.48 122.29,69.69 125.33,72.72 125.33,75.26 120.63,79.96 120.63,83.01 118.6,85.04 117.05,85.04 115.55,86.54 115.55,87.89 115.22,88.22 113.39,88.22 111.49,86.31 106.79,86.31 105.14,87.96 105.14,91.62 v1(104.2,92.56)
  BOTTOM w0.127: v1(104.2,92.56) 103.77,92.56 102.98,91.77 R958.2
ECAT0_RX_DV: length 69
  TOP w0.127: R1260.1 61.45,26.5 62.01,27.06 v1(62.01,27.33) ; v1(44.73,64.99) 44.73,65.05 44.62,65.16 U101.4
  L3_INT_1 w0.127: v1(62.01,27.33) 62.01,27.6 60.88,28.73 60.88,30.19 60.34,30.72 60.16,30.72 59.86,30.42 59.68,30.42 59.5,30.6 59.5,30.78 59.81,31.08 59.81,31.26 58.25,32.82 54.89,32.82 54.78,32.71 54.78,31.46 54.67,31.35 54.51,31.35 54.4,31.46 54.4,32.71 54.29,32.82 54.13,32.82 54.02,32.71 54.02,31.31 53.9,31.19 53.75,31.19 53.64,31.31 53.64,32.71 53.52,32.82 53.37,32.82 53.25,32.71 53.25,31.31 53.14,31.19 52.98,31.19 52.87,31.31 52.87,32.71 52.76,32.82 52.6,32.82 52.49,32.71 52.49,31.31 52.38,31.19 52.22,31.19 52.11,31.31 52.11,32.71 52,32.82 51.7,32.82 51.34,33.17 50.55,33.17 49.76,33.96 49.18,33.96 46.59,36.55 46.59,36.88 46.97,37.26 46.97,37.52 46.79,37.7 46.61,37.7 46.04,37.13 45.87,37.13 45.73,37.26 45.73,37.44 46.3,38.01 46.3,38.19 46.18,38.31 46.02,38.31 45.44,37.73 45.26,37.73 45.14,37.85 45.14,38 45.73,38.58 45.73,38.76 45.56,38.93 45.09,38.93 44.96,39.06 44.96,59.71 45.07,59.81 45.07,59.82 45.19,59.94 45.19,61.67 44.56,62.31 44.56,64.82 v1(44.73,64.99)
ECAT0_RXCLK: length 68.1
  TOP w0.127: v1(64.62,33.61) 63.86,32.84 R1259.1 ; U97.3 43.28,79.26 43.98,78.56 v1(45.32,78.56)
  L3_INT_1 w0.127: v1(64.62,33.61) 62.46,33.61 61.47,34.6 52.33,34.6 51.4,35.52 51.4,35.7 51.54,35.84 51.54,36.02 51.36,36.2 51.18,36.2 51.04,36.06 50.86,36.06 50.68,36.24 50.68,36.42 51.33,37.07 51.33,37.25 51.15,37.43 50.97,37.43 50.33,36.78 50.15,36.78 49.97,36.96 49.97,37.14 50.42,37.6 50.42,37.78 50.24,37.96 50.06,37.96 49.61,37.5 49.43,37.5 46.49,40.44 46.49,59.08 46.59,59.18 46.59,59.18 46.74,59.34 46.74,66.53 46.37,66.89 46.37,74.34 45.6,75.11 45.6,78.28 v1(45.32,78.56)
ECAT0_RXD0: length 67.4
  TOP w0.127: U100.4 43.78,68.54 44.1,68.23 44.61,68.23 44.8,68.04 v1(44.88,68.04) ; R1262.1 64.06,26.62 v1(64.36,26.93)
  L3_INT_1 w0.127: v1(64.36,26.93) 63.2,26.93 61.35,28.78 61.35,30.3 58.53,33.12 51.9,33.12 51.51,33.51 50.65,33.51 50.35,33.81 50.35,34.5 50.22,34.62 50.04,34.62 49.75,34.34 49.59,34.34 49.48,34.45 49.48,34.61 49.87,35 49.87,35.15 49.76,35.26 49.6,35.26 49.21,34.88 49.05,34.88 48.94,34.99 48.94,35.15 49.33,35.53 49.33,35.69 49.22,35.8 49.06,35.8 48.67,35.41 48.52,35.41 48.4,35.53 48.4,35.68 48.79,36.07 48.79,36.23 48.68,36.34 48.52,36.34 48.13,35.95 47.98,35.95 47.86,36.07 47.86,36.22 48.25,36.61 48.25,36.77 48.14,36.88 47.98,36.88 47.7,36.59 47.54,36.59 47.43,36.71 47.43,36.86 47.71,37.15 47.71,37.31 45.27,39.75 45.27,59.59 45.37,59.69 45.37,59.69 45.5,59.82 45.5,62.53 45.39,62.64 45.18,62.64 45.07,62.75 45.07,62.91 45.18,63.02 45.39,63.02 45.5,63.14 45.5,63.29 45.39,63.41 45.05,63.41 44.94,63.52 44.94,63.67 45.05,63.79 45.39,63.79 45.5,63.9 45.5,64.04 45.19,64.34 45.19,64.92 45.51,65.23 45.7,65.23 45.83,65.36 45.83,66.04 45.4,66.48 45.4,69.09 45.24,69.24 45.04,69.24 44.88,69.07 v1(44.88,68.04)
ECAT0_RXD1: length 67.9
  TOP w0.127: v1(64.83,27.8) 64.32,27.8 R1263.1 ; U101.3 43.28,64.73 43.52,64.49 45.43,64.49 v1(45.66,64.72)
  L3_INT_1 w0.127: v1(45.66,64.72) 45.8,64.58 45.8,59.69 45.68,59.56 45.68,59.56 45.57,59.46 45.57,39.96 52.1,33.43 60.71,33.43 60.84,33.3 60.84,33.12 60.71,33 59.62,33 59.49,32.87 59.49,32.64 59.59,32.54 60.2,32.54 60.31,32.44 60.31,31.88 60.78,31.4 60.94,31.4 61.28,31.74 61.44,31.74 61.55,31.63 61.55,31.47 61.21,31.13 61.21,30.98 61.63,30.56 63.48,30.56 63.61,30.43 63.61,30.13 63.48,30 62.12,30 61.87,29.75 61.87,28.84 62.21,28.5 62.39,28.5 62.83,28.95 63.01,28.95 63.16,28.79 63.16,28.59 62.68,28.11 62.68,27.93 63.1,27.51 63.29,27.51 63.5,27.71 63.5,29.53 63.61,29.64 63.76,29.64 63.88,29.53 63.88,27.7 64.07,27.51 64.54,27.51 v1(64.83,27.8)
ECAT0_RXD2: length 67.7
  TOP w0.127: U98.3 43.28,75.52 43.92,74.88 v1(44.81,74.88) ; R1264.1 64.41,30.18 64.5,30.09 v1(64.5,30.09)
  L3_INT_1 w0.127: v1(64.5,30.09) 63.27,31.32 63.27,31.5 63.47,31.71 63.47,31.89 63.29,32.07 63.12,32.07 62.91,31.86 62.73,31.86 60.86,33.73 52.25,33.73 45.88,40.11 45.88,59.33 45.98,59.43 45.98,59.44 46.13,59.59 46.13,66.17 45.7,66.6 45.7,69.48 45.59,69.59 45.36,69.59 45.24,69.7 45.24,69.86 45.36,69.97 45.59,69.97 45.7,70.08 45.7,70.24 45.59,70.35 45.23,70.35 45.12,70.46 45.12,70.62 45.23,70.73 45.59,70.73 45.7,70.84 45.7,71 45.59,71.11 45.23,71.11 45.12,71.22 45.12,71.38 45.23,71.49 45.59,71.49 45.7,71.6 45.7,71.76 45.59,71.87 45.23,71.87 45.12,71.98 45.12,72.14 45.23,72.25 45.59,72.25 45.7,72.37 45.7,72.52 45.59,72.63 45.23,72.63 45.12,72.75 45.12,72.9 45.23,73.02 45.59,73.02 45.7,73.13 45.7,73.29 45.59,73.4 45.23,73.4 45.12,73.51 45.12,73.67 45.23,73.78 45.59,73.78 45.7,73.89 45.7,74.05 45.59,74.16 45.15,74.16 44.81,74.5 v1(44.81,74.88)
ECAT0_RXD3: length 64
  TOP w0.127: v1(44.78,79.11) 44.74,79.07 43.97,79.07 43.78,79.26 U97.4
  L3_INT_1 w0.127: v1(44.78,79.11) 44.78,78.44 45.3,77.92 45.3,74.91 46.07,74.13 46.07,66.67 46.44,66.3 46.44,59.46 46.29,59.31 46.29,59.31 46.18,59.21 46.18,40.24 52.3,34.11 61.37,34.11 62.61,32.87 v1(64.75,32.87)
  BOTTOM w0.127: v1(64.75,32.87) 64.72,32.84 R1265.1
ECAT0_RXER: length 94.2
  TOP w0.127: v1(50.99,29.48) 51,29.48 51.06,29.54 R1261.1
  L3_INT_1 w0.127: v1(50.99,29.48) 50.99,28.45 51.31,28.12 53.63,28.12 53.75,28.25 53.75,28.52 53.63,28.64 51.5,28.64 51.37,28.78 51.37,29.11 51.49,29.24 52.41,29.24 52.53,29.37 52.53,29.59 52.41,29.72 51.49,29.72 51.37,29.85 51.37,30.14 51.49,30.27 53.23,30.27 53.32,30.36 53.32,30.66 53.19,30.79 51.9,30.79 51.67,31.02 51.67,32.36 51.21,32.82 50.5,32.82 50.27,32.59 49.38,32.59 49.13,32.84 49.13,33.35 48.65,33.83 48.49,33.83 47.31,32.64 47.15,32.64 47.04,32.75 47.04,32.91 48.22,34.1 48.22,34.26 48.11,34.37 47.95,34.37 46.77,33.18 46.61,33.18 46.5,33.29 46.5,33.45 47.68,34.64 47.68,34.79 47.57,34.91 47.41,34.91 46.23,33.72 46.07,33.72 45.96,33.83 45.96,33.99 47.15,35.18 47.15,35.33 47.03,35.45 46.88,35.45 45.69,34.26 45.53,34.26 45.42,34.37 45.42,34.53 46.61,35.72 46.61,35.87 46.49,35.98 46.34,35.98 45.15,34.8 44.99,34.8 44.88,34.91 44.88,35.07 46.07,36.25 46.07,36.41 45.96,36.52 45.8,36.52 45.08,35.8 44.93,35.8 44.81,35.93 44.81,36.07 45.53,36.79 45.53,36.95 45.42,37.06 45.26,37.06 44.83,36.63 44.61,36.63 44.56,36.68 44.56,54.19 44.61,54.24 44.61,59.95 44.81,60.15 44.89,60.23 44.89,61.39 44.18,62.11 44.18,65.1 44.53,65.46 45.09,65.46 v1(45.36,65.73)
  BOTTOM w0.127: R960.2 61.07,68.28 60.69,67.9 55.23,67.9 54.46,68.66 49.69,68.66 46.76,65.73 v1(45.36,65.73)
ECAT0_TX_REF_CLK: length 57.6
  TOP w0.127: R1266.1 65.16,35.16 v1(65.16,35.36) ; U100.3 43.28,68.41 43.92,67.77 44.4,67.77 44.74,67.43 44.9,67.43 45.07,67.26 v1(47.21,67.26)
  L3_INT_1 w0.127: v1(47.21,67.26) 47.21,67.02 47.38,66.86 47.38,59.11 47.1,58.83 47.1,48.44 47.76,47.78 47.76,46.92 47.87,46.81 48.03,46.81 48.14,46.7 48.14,46.54 48.03,46.43 47.87,46.43 47.76,46.32 47.76,45.93 47.9,45.79 48.69,45.79 48.81,45.66 48.81,45.48 48.69,45.35 47.76,45.35 47.63,45.23 47.63,44.92 47.74,44.81 48.74,44.81 48.85,44.69 48.85,44.54 48.74,44.42 47.87,44.42 47.76,44.31 47.76,44.15 47.87,44.04 48.74,44.04 48.85,43.93 48.85,43.77 48.74,43.66 48.45,43.66 48.34,43.55 48.34,43.39 48.45,43.28 48.74,43.28 48.85,43.17 48.85,42.78 52.94,38.69 57,38.69 57.52,38.17 57.52,38.04 58.53,37.04 62.31,37.04 63.46,35.89 64.62,35.89 v1(65.16,35.36)
ECAT0_TXD0: length 56.2
  TOP w0.127: U98.4 43.78,75.53 44.05,75.26 44.38,75.26 44.96,75.85 v1(47.1,75.85) ; v1(63.76,36.4) 63.73,36.37 R1268.1
  L3_INT_1 w0.127: v1(63.76,36.4) 60.54,39.62 60.36,39.62 60.12,39.38 59.94,39.38 59.76,39.56 59.76,39.74 60,39.98 60,40.16 59.77,40.39 53.78,40.39 52.91,41.25 52.91,45.72 48.62,50.02 48.62,58.17 48.9,58.45 48.9,73 48.11,73.79 48.11,74.5 47.1,75.52 v1(47.1,75.85)
ECAT0_TXD1: length 57.5
  TOP w0.127: U99.3 43.28,72.2 43.64,71.85 44.57,71.85 44.59,71.83 47.99,71.83 v1(48.24,71.58) ; v1(61.07,38.18) 61.32,37.92 R1269.1
  L3_INT_1 w0.127: v1(61.07,38.18) 60.71,38.18 60.52,38.37 60.52,38.55 60.73,38.76 60.73,38.94 60.55,39.12 60.38,39.12 60.16,38.91 59.98,38.91 58.81,40.08 53.57,40.08 52.2,41.46 52.2,41.64 52.56,41.99 52.56,42.15 52.45,42.26 51.68,42.26 51.57,42.37 51.57,42.53 51.68,42.64 52.45,42.64 52.56,42.75 52.56,42.91 52.45,43.02 51.68,43.02 51.57,43.13 51.57,43.29 51.68,43.4 52.45,43.4 52.56,43.52 52.56,43.67 52.45,43.79 51.68,43.79 51.57,43.9 51.57,44.05 51.68,44.17 52.45,44.17 52.56,44.28 52.56,44.44 52.45,44.55 51.68,44.55 51.57,44.66 51.57,44.82 51.68,44.93 52.45,44.93 52.56,45.04 52.56,45.54 52.41,45.7 52.23,45.7 52.05,45.52 51.87,45.52 51.75,45.65 51.75,45.99 51.85,46.1 51.85,46.25 48.32,49.79 48.32,58.32 48.6,58.6 48.6,70.97 48.24,71.33 v1(48.24,71.58)
ECAT0_TXD2: length 57.6
  TOP w0.127: R1270.1 v1(60.43,37.8) ; v1(45.19,83.57) U96.4
  L3_INT_1 w0.127: v1(60.43,37.8) 58.53,39.7 53.45,39.7 51.16,41.99 51.16,46.31 48.01,49.46 48.01,58.45 48.29,58.73 48.29,70.77 47.76,71.3 47.76,71.88 48.11,72.24 48.11,73.1 47.73,73.48 47.73,74.37 46.55,75.55 46.55,82.21 v1(45.19,83.57)
ECAT0_TXD3: length 57.8
  TOP w0.127: R1272.1 v1(59.54,37.8) ; U96.3 43.28,83.14 43.54,82.88 44.38,82.88 v1(44.6,83.1)
  L3_INT_1 w0.127: v1(59.54,37.8) 59.54,38.26 59.07,38.73 58.77,38.73 58.65,38.84 58.65,39.15 58.43,39.37 53.27,39.37 50.8,41.85 50.8,46.09 47.71,49.18 47.71,58.57 47.99,58.85 47.99,70.44 47.43,71 47.43,72.19 47.68,72.45 47.68,72.92 47.35,73.25 47.35,74.25 46.25,75.35 46.25,81.65 44.8,83.1 v1(44.6,83.1)
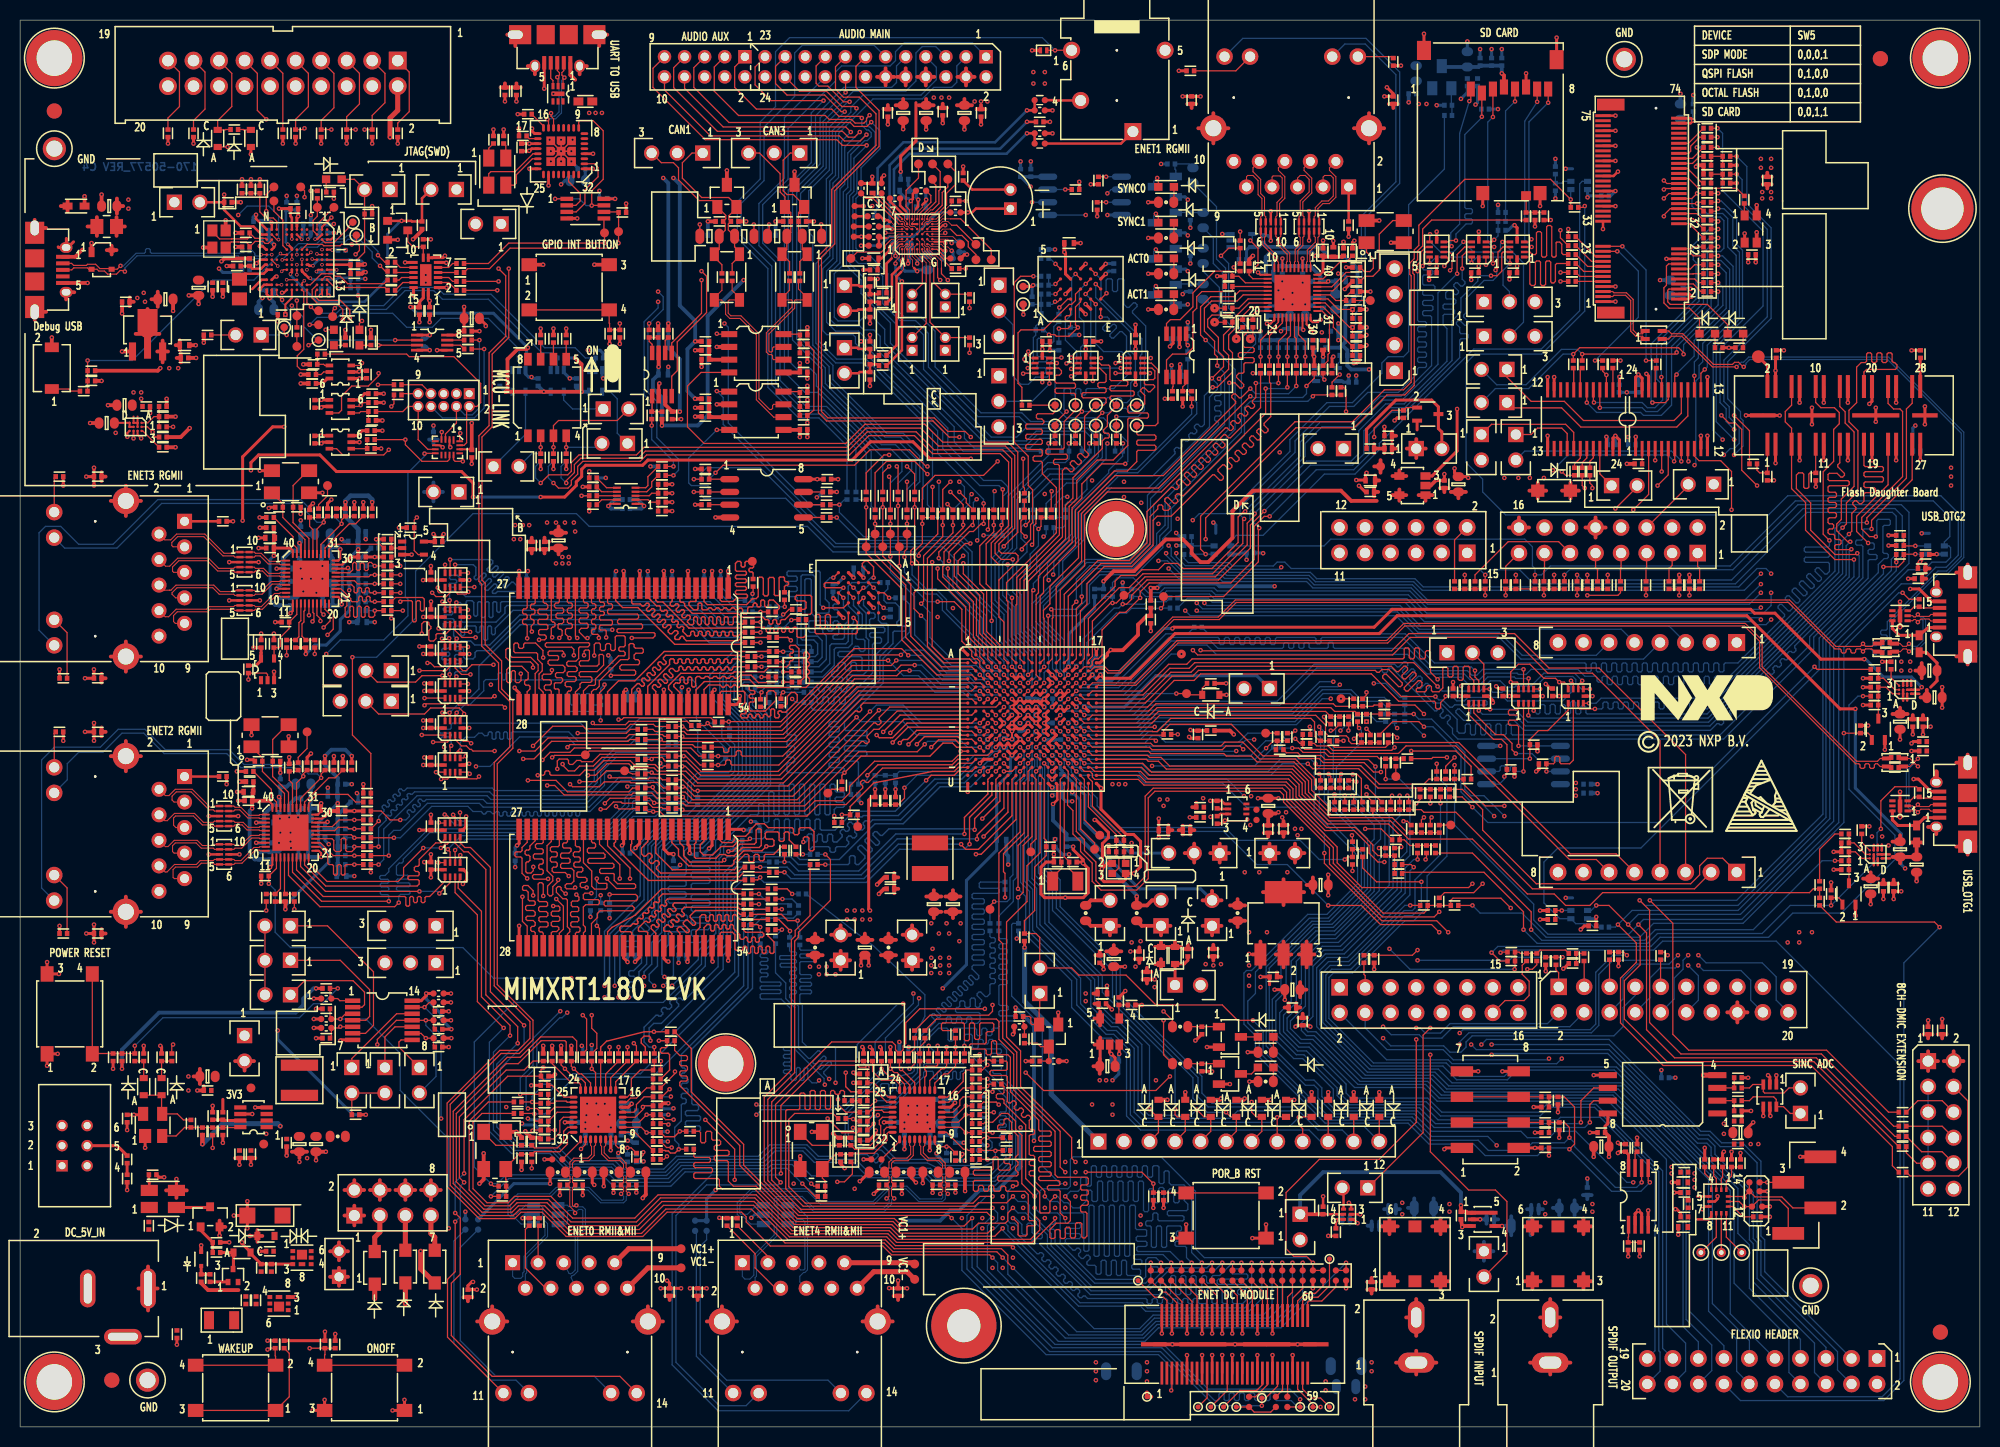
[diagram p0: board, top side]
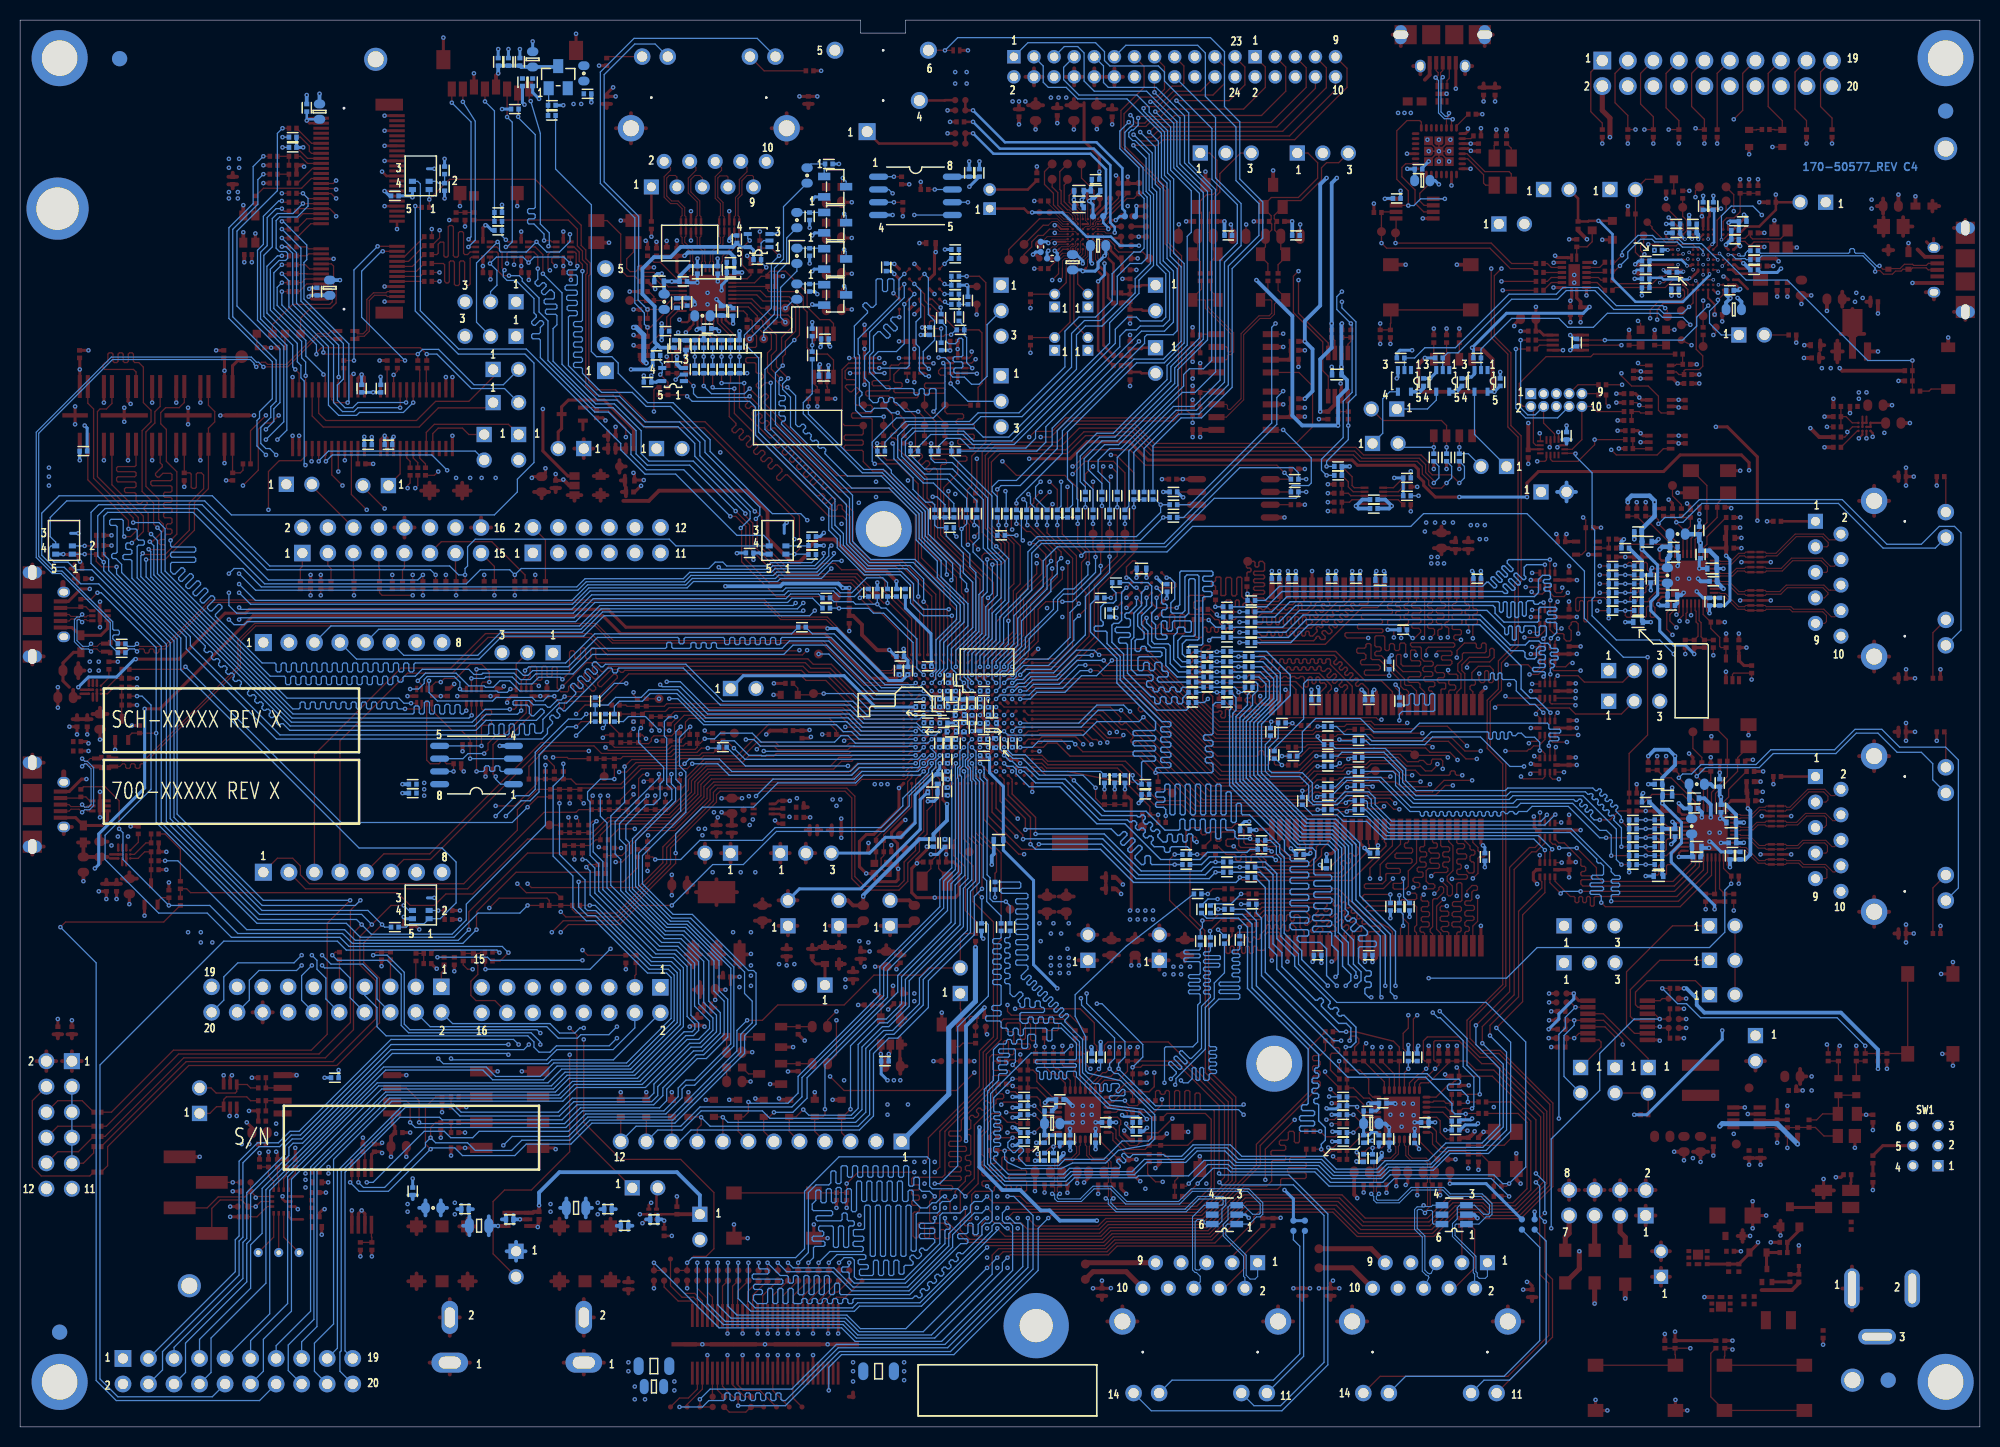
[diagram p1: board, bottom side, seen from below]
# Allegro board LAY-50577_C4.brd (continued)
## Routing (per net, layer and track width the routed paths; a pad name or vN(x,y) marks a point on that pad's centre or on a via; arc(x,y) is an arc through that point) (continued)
ECAT0_TXEN: length 57.5
  TOP w0.127: v1(47.21,72.72) 47.1,72.72 46.9,72.53 U99.4 ; R1267.1 v1(58.65,37.8)
  L3_INT_1 w0.127: v1(58.65,37.8) 58.65,38.33 57.92,39.07 53.07,39.07 50.41,41.72 50.41,42.76 50.3,42.87 49.42,42.87 49.31,42.98 49.31,43.14 49.42,43.25 50.3,43.25 50.41,43.36 50.41,43.52 50.3,43.63 49.42,43.63 49.31,43.74 49.31,43.9 49.42,44.01 50.3,44.01 50.41,44.12 50.41,44.28 50.3,44.39 49.42,44.39 49.31,44.5 49.31,44.66 49.42,44.77 50.3,44.77 50.41,44.88 50.41,45.04 50.3,45.15 49.42,45.15 49.31,45.26 49.31,45.42 49.42,45.53 50.3,45.53 50.41,45.65 50.41,45.89 50.02,46.28 49.54,46.28 49.22,45.97 49.06,45.97 48.95,46.08 48.95,46.24 49.43,46.71 49.43,46.87 49.32,46.98 49.16,46.98 48.76,46.58 48.6,46.58 48.49,46.69 48.49,46.85 48.89,47.25 48.89,47.41 47.4,48.9 47.4,58.7 47.68,58.98 47.68,70.23 47.1,70.82 47.1,72.61 v1(47.21,72.72)
ECAT1_RST_B: length 1.9
  TOP w0.127: R1312.1 88.5,37.16 89.01,37.66 R1018.2
ECAT1_RX_DV: length 99.6
  TOP w0.14: v1(93.76,27.15) 93.76,26.92 93.33,26.5 R1298.1
  L3_INT_1 w0.14: v1(93.76,27.15) 92.11,27.15 91.12,28.15 86.21,28.15 85.96,27.89 81.46,27.89 78.19,31.17 77.99,31.17 77.32,30.5 77.13,30.5 76.93,30.7 76.93,30.9 77.59,31.57 77.59,31.76 77.4,31.96 77.2,31.96 76.53,31.29 76.33,31.29 76.14,31.49 76.14,31.69 76.8,32.36 76.8,32.55 76.6,32.75 76.41,32.75 75.74,32.09 75.54,32.09 75.35,32.28 75.35,32.48 76.01,33.15 76.01,33.34 75.81,33.54 75.62,33.54 74.95,32.88 74.75,32.88 74.56,33.07 74.56,33.27 75.22,33.94 75.22,34.13 75.02,34.33 74.83,34.33 73.91,33.41 73.71,33.41 73.51,33.61 73.51,33.81 74.43,34.73 74.43,34.92 74.23,35.12 74.04,35.12 73.4,34.49 73.21,34.49 73.01,34.69 73.01,34.88 73.64,35.52 73.64,37.42 71.74,39.32 67.13,39.32 66.99,39.18 66.99,38.83 66.85,38.69 66.57,38.69 66.43,38.83 66.43,39.18 66.29,39.32 65.26,39.32 62.72,41.86 60.43,41.86 v1(59.54,42.75)
  BOTTOM w0.14: v1(59.54,42.75) 59.67,42.88 59.67,48.85 62.82,52 62.82,57.8 62.83,57.81 62.83,57.82 64.34,59.32 64.34,59.32 64.41,59.39 67.29,59.39 72.62,64.72 72.62,70.14 70.28,72.49 70.28,74.44 71.48,75.64 R2120.2
ECAT1_RXCLK: length 98.7
  TOP w0.14: R1297.1 95.48,32.84 95.99,33.35 v1(96.75,33.35)
  L3_INT_1 w0.14: v1(96.75,33.35) 96.75,32.66 96.39,32.3 95.85,32.3 95.41,31.85 95.41,30.13 95.15,29.87 91.9,29.87 91.19,29.16 85.53,29.16 85.36,29 82.72,29 82.12,29.59 82.12,30.69 78.34,34.47 78.34,37.8 72.75,43.39 61.83,43.39 60.81,44.4 58.65,44.4 v1(58.15,43.89)
  BOTTOM w0.14: v1(58.15,43.89) 58.15,49.31 61.71,52.87 61.71,58.1 64.09,60.48 66.91,60.48 71.48,65.05 71.48,69.93 68.62,72.79 68.62,74.81 70.97,77.17 R2132.2
ECAT1_RXD0: length 98
  TOP w0.14: R1300.1 v1(96.25,26.62)
  L3_INT_1 w0.14: v1(58.15,42.75) 58.78,43.39 60.69,43.39 61.45,42.62 64.13,42.62 64.27,42.48 64.27,41.75 64.41,41.61 64.69,41.61 64.83,41.75 64.83,42.48 64.97,42.62 65.25,42.62 65.39,42.48 65.39,41.75 65.53,41.61 65.81,41.61 65.95,41.75 65.95,42.48 66.09,42.62 66.37,42.62 66.51,42.48 66.51,41.75 66.65,41.61 66.92,41.61 67.06,41.75 67.06,42.48 67.2,42.62 67.48,42.62 67.62,42.48 67.62,41.75 67.76,41.61 68.04,41.61 68.18,41.75 68.18,42.23 68.32,42.37 68.6,42.37 68.74,42.23 68.74,41.75 68.88,41.61 71.35,41.61 77.32,35.64 77.32,34.42 81.39,30.36 81.39,29.37 82.48,28.27 85.71,28.27 85.91,28.48 92.2,28.48 94.53,27.46 95.41,27.46 v1(96.25,26.62)
  BOTTOM w0.14: v1(58.15,42.75) 58.65,43.26 58.65,49.03 62.08,52.46 62.08,57.96 62.2,58.08 62.2,58.08 64.08,59.96 64.08,59.96 64.22,60.1 66.98,60.1 71.86,64.98 71.86,70.01 69.62,72.25 69.62,75.05 71.23,76.66 R2116.2
ECAT1_RXD1: length 101
  TOP w0.14: v1(96.75,29.29) R1302.1
  L3_INT_1 w0.14: v1(96.75,29.29) 95.87,29.29 95.71,29.14 95.71,28.93 95.59,28.81 93.12,28.81 93.01,28.92 93.01,29.18 92.9,29.29 92.74,29.29 92.63,29.18 92.63,28.92 92.52,28.81 92.36,28.81 92.25,28.92 92.25,29.18 92.14,29.29 91.98,29.29 91.87,29.18 91.87,28.92 91.76,28.81 85.73,28.81 85.58,28.65 82.58,28.65 81.74,29.49 81.74,30.53 77.83,34.45 77.83,35.77 77.04,36.56 77.04,36.75 77.16,36.87 77.16,37.07 76.96,37.27 76.77,37.27 76.65,37.15 76.45,37.15 76.25,37.35 76.25,37.54 76.37,37.66 76.37,37.86 76.17,38.06 75.98,38.06 75.86,37.94 75.66,37.94 75.46,38.14 75.46,38.33 75.58,38.45 75.58,38.65 75.38,38.85 75.19,38.85 75.07,38.73 74.87,38.73 74.67,38.93 74.67,39.12 74.85,39.31 74.85,39.51 74.66,39.7 74.46,39.7 74.28,39.52 74.08,39.52 73.88,39.72 73.88,39.91 74.06,40.1 74.06,40.3 73.87,40.49 73.67,40.49 73.49,40.31 73.29,40.31 73.09,40.51 73.09,40.71 73.27,40.89 73.27,41.09 73.08,41.28 72.88,41.28 72.7,41.1 72.5,41.1 72.3,41.3 72.3,41.5 72.48,41.68 72.48,41.88 72.29,42.07 72.09,42.07 71.9,41.89 71.71,41.89 71.48,42.12 71.48,42.87 71.34,43 70.97,43 70.83,42.87 70.83,42.13 70.69,41.99 70.41,41.99 70.27,42.13 70.27,42.87 70.13,43 69.85,43 69.71,42.87 69.71,42.13 69.57,41.99 69.29,41.99 69.15,42.13 69.15,42.87 69.01,43 61.58,43 60.69,43.89 v1(59.16,43.89)
  BOTTOM w0.14: R2117.2 71.35,76.15 69.95,74.74 69.95,72.37 72.24,70.07 72.24,64.85 67.19,59.79 67.13,59.79 67.12,59.78 64.35,59.78 64.21,59.64 64.21,59.64 62.52,57.95 62.52,57.95 62.46,57.9 62.46,52.28 59.16,48.97 v1(59.16,43.89)
ECAT1_RXD2: length 97.6
  TOP w0.14: R1301.1 95.69,31.28 96.86,31.28 v1(96.88,31.31)
  L3_INT_1 w0.14: v1(62.08,43.89) 62.59,44.4 62.59,45.8 64.24,47.45 72.88,47.45 77.58,42.75 84.23,42.75 87.61,39.37 89.33,39.37 89.46,39.25 89.46,38.8 89.57,38.69 89.73,38.69 89.84,38.8 89.84,39.26 89.95,39.37 90.11,39.37 90.22,39.26 90.22,38.8 90.33,38.69 90.49,38.69 90.6,38.8 90.6,39.26 90.72,39.37 90.87,39.37 90.99,39.26 90.99,38.8 91.1,38.69 91.25,38.69 91.37,38.8 91.37,39.26 91.48,39.37 91.64,39.37 91.75,39.26 91.75,38.8 91.86,38.69 92.02,38.69 92.13,38.8 92.13,39.26 92.24,39.37 92.4,39.37 92.51,39.26 92.51,38.8 92.62,38.69 92.78,38.69 92.89,38.8 92.89,39.26 93,39.37 93.16,39.37 93.27,39.26 93.27,38.52 93.38,38.41 93.63,38.41 93.81,38.59 93.81,39.22 93.91,39.32 95.48,39.32 95.77,39.03 95.77,38.84 95.57,38.63 95.57,38.43 95.76,38.23 95.96,38.23 96.17,38.44 96.37,38.44 96.56,38.24 96.56,38.04 96.36,37.84 96.36,37.64 96.55,37.44 96.75,37.44 96.96,37.65 97.16,37.65 97.26,37.54 97.26,32.71 96.88,32.33 v1(96.88,31.31)
  BOTTOM w0.14: v1(62.08,43.89) 61.58,44.4 61.58,45.29 62.34,46.05 62.34,48.47 63.51,49.63 63.51,57.59 64.6,58.69 67.61,58.69 73.31,64.39 73.31,70.35 71.05,72.61 71.05,73.94 71.74,74.63 R2124.2
ECAT1_RXD3: length 101.4
  TOP w0.14: R1303.1 95.48,31.96 95.85,32.32 97.12,32.32 v1(97.37,32.07)
  L3_INT_1 w0.14: v1(97.37,32.07) 97.78,32.48 99.41,32.48 99.55,32.62 99.55,32.9 99.41,33.04 97.78,33.04 97.64,33.18 97.64,33.45 97.78,33.59 99.46,33.59 99.6,33.73 99.6,34.01 99.46,34.15 97.78,34.15 97.64,34.29 97.64,37.67 95.61,39.7 95.61,39.7 95.47,39.84 95.47,40.07 95.33,40.21 95.05,40.21 94.91,40.07 94.91,39.84 94.77,39.7 94.49,39.7 94.35,39.84 94.35,40.2 94.21,40.34 93.93,40.34 93.79,40.2 93.79,39.84 93.65,39.7 93.37,39.7 93.23,39.84 93.23,40.2 93.09,40.34 92.81,40.34 92.67,40.2 92.67,39.84 92.53,39.7 92.25,39.7 92.11,39.84 92.11,40.2 91.97,40.34 91.69,40.34 91.55,40.2 91.55,39.84 91.41,39.7 91.13,39.7 90.99,39.84 90.99,40.2 90.86,40.34 90.58,40.34 90.44,40.2 90.44,39.84 90.3,39.7 90.02,39.7 89.88,39.84 89.88,40.2 89.74,40.34 89.46,40.34 89.32,40.2 89.32,39.84 89.18,39.7 88.75,39.7 84.66,43.79 78.01,43.79 73.84,47.96 63.99,47.96 62.08,46.05 v1(62.08,44.78)
  BOTTOM w0.14: R2125.2 72.04,74.12 71.86,73.94 71.86,73.29 72.37,72.78 72.37,71.83 73.63,70.58 73.63,64.26 67.69,58.32 64.73,58.32 63.84,57.43 63.84,49.2 62.85,48.21 62.85,46.05 62.08,45.29 v1(62.08,44.78)
ECAT1_RXER: length 100.8
  TOP w0.14: R1299.1 83.28,29.27 81.76,29.27 v1(80.35,30.69)
  L3_INT_1 w0.14: v1(80.35,30.69) 79.41,30.69 79.07,31.03 79.07,31.21 79.42,31.56 79.42,31.74 79.24,31.92 79.06,31.92 78.71,31.57 78.53,31.57 78.35,31.74 78.35,31.92 78.7,32.28 78.7,32.46 78.52,32.64 78.34,32.64 77.99,32.28 77.81,32.28 77.63,32.46 77.63,32.64 77.98,33 77.98,33.18 77.8,33.36 77.62,33.36 77.27,33 77.09,33 76.91,33.18 76.91,33.36 77.26,33.72 77.26,33.9 77.08,34.08 76.9,34.08 76.55,33.72 76.37,33.72 76.19,33.9 76.19,34.08 76.54,34.43 76.54,34.61 76.37,34.79 76.19,34.79 75.83,34.44 75.65,34.44 75.47,34.62 75.47,34.8 75.83,35.15 75.83,35.33 75.65,35.51 75.47,35.51 75.11,35.16 74.93,35.16 74.15,35.94 74.15,37.8 72.12,39.83 71.05,39.83 70.91,39.97 70.91,40.96 70.77,41.1 70.49,41.1 70.35,40.96 70.35,39.97 70.21,39.83 69.94,39.83 69.8,39.97 69.8,40.96 69.66,41.1 69.38,41.1 69.24,40.96 69.24,39.97 69.1,39.83 68.82,39.83 68.68,39.97 68.68,40.96 68.54,41.1 68.26,41.1 68.12,40.96 68.12,39.97 67.98,39.83 67.7,39.83 67.56,39.97 67.56,40.96 67.42,41.1 67.14,41.1 67,40.96 67,39.97 66.86,39.83 66.58,39.83 66.44,39.97 66.44,40.96 66.3,41.1 66.02,41.1 65.88,40.96 65.88,39.97 65.74,39.83 65.39,39.83 62.97,42.24 61.07,42.24 v1(60.56,42.75)
  BOTTOM w0.14: R2121.2 71.61,75.14 70.69,74.22 70.69,72.52 72.99,70.22 72.99,64.58 67.42,59.01 64.47,59.01 63.15,57.69 63.15,51.53 62.85,51.23 62.85,51.03 63.15,50.74 63.15,50.54 62.95,50.35 62.75,50.35 62.46,50.64 62.26,50.64 62.06,50.44 62.06,50.24 62.61,49.7 62.61,49.5 62.41,49.3 62.21,49.3 61.67,49.85 61.47,49.85 60.94,49.32 60.94,49.04 61.08,48.9 61.69,48.9 61.83,48.76 61.83,48.48 61.69,48.34 60.19,48.34 60.05,48.2 60.05,47.92 60.19,47.78 61.69,47.78 61.83,47.65 61.83,46.18 61.06,45.41 60.7,45.41 60.56,45.27 60.56,44.99 60.7,44.85 61.06,44.85 61.19,44.71 61.19,44.43 61.06,44.29 60.7,44.29 60.56,44.15 60.56,43.87 60.7,43.73 61.06,43.73 61.19,43.59 61.19,43.13 60.81,42.75 v1(60.56,42.75)
ECAT1_TX_REF_CLK: length 105.9
  TOP w0.127: R1304.1 96.23,34.62 v1(96.25,34.64) ; v1(50.15,39.96) 46.79,43.31 46.79,55.68 44.81,57.66 44.25,57.66 43.78,58.13 U103.4
  BOTTOM w0.127: v1(50.15,39.96) 50.15,38.05 47.78,35.69 47.78,30 49.54,28.25 53.14,28.25 54.9,26.49 59.16,26.49 60,25.66 64.04,25.66 65.31,26.93 73.44,26.93 74.58,28.07 78.29,28.07 79.43,26.93 81.06,26.93 81.24,27.1 84.28,27.1 84.56,26.83 84.72,26.83 85.11,27.21 85.27,27.21 85.38,27.1 85.38,26.94 84.99,26.56 84.99,26.4 85.1,26.29 85.26,26.29 85.61,26.64 85.77,26.64 85.88,26.52 85.88,26.37 85.53,26.02 85.53,25.86 85.66,25.73 90.58,25.73 91.17,25.15 96.68,25.15 98.13,26.6 98.13,26.86 98.02,26.97 97.83,26.97 97.72,27.08 97.72,27.24 97.83,27.35 98.02,27.35 98.13,27.46 98.13,27.8 98.02,27.91 97.55,27.91 97.44,28.03 97.44,28.18 97.55,28.3 98.02,28.3 98.13,28.41 98.13,28.57 98.02,28.68 97.55,28.68 97.44,28.79 97.44,28.95 97.55,29.06 98.02,29.06 98.13,29.17 98.13,29.33 98.02,29.44 97.55,29.44 97.44,29.55 97.44,29.71 97.55,29.82 98.02,29.82 98.13,29.93 98.13,30.09 98.02,30.2 97.55,30.2 97.44,30.31 97.44,30.47 97.55,30.58 98.02,30.58 98.13,30.69 98.13,30.85 98.02,30.96 97.55,30.96 97.44,31.07 97.44,31.23 97.55,31.34 98.02,31.34 98.13,31.46 98.13,32.76 v1(96.25,34.64)
ECAT1_TXD0: length 105.9
  TOP w0.127: R1307.1 95.74,35.51 v1(96.25,36.02) ; v1(48.75,38.94) 48.75,39.96 45.9,42.8 45.9,51.31 43.59,53.63 43.59,54.25 43.78,54.45 U106.4
  BOTTOM w0.127: v1(96.25,36.02) 95.97,36.3 95.97,37.49 96.09,37.62 97.52,37.62 97.64,37.49 97.64,37.29 97.53,37.18 96.66,37.18 96.55,37.07 96.55,36.91 96.66,36.8 97.66,36.8 97.77,36.68 97.77,36.53 97.66,36.41 96.84,36.41 96.73,36.3 96.73,36.15 96.84,36.03 97.53,36.03 97.64,35.92 97.64,35.65 97.53,35.53 96.89,35.53 96.78,35.42 96.78,35.27 96.89,35.15 97.53,35.15 97.64,35.04 97.64,34.5 98.74,33.4 98.74,26.17 97.01,24.44 90.94,24.44 90.28,25.1 84.13,25.1 82.91,26.32 79.03,26.32 77.88,27.46 75.11,27.46 73.97,26.32 65.61,26.32 64.32,25.02 59.67,25.02 58.84,25.85 54.5,25.85 52.84,27.51 49.13,27.51 47.1,29.54 47.1,37.29 v1(48.75,38.94)
ECAT1_TXD1: length 105.9
  TOP w0.127: v1(93.96,37.92) R1306.1 ; U106.3 43.28,53.17 45.5,50.96 45.5,42.32 v1(48.11,39.7)
  BOTTOM w0.127: v1(48.11,39.7) 46.69,38.28 46.69,29.42 48.39,27.71 48.39,27.71 48.9,27.21 52.71,27.21 54.38,25.54 58.72,25.54 59.54,24.72 64.5,24.72 65.79,26.01 74.17,26.01 74.68,26.52 77.2,26.52 78.73,24.98 83.74,24.98 83.93,24.79 90.1,24.79 90.84,24.06 97.06,24.06 99.07,26.06 99.07,33.58 98.15,34.5 98.15,37.54 97.59,38.1 96.98,38.1 96.86,38.23 96.86,38.43 96.73,38.56 96.48,38.56 96.35,38.43 96.35,38.23 96.22,38.1 95.97,38.1 95.84,38.23 95.84,38.43 95.71,38.56 95.46,38.56 95.33,38.43 95.33,37.8 95.21,37.67 94.88,37.67 94.75,37.8 94.75,38.94 94.62,39.07 94.09,39.07 93.96,38.94 v1(93.96,37.92)
ECAT1_TXD2: length 99.9
  TOP w0.14: R1308.1 v1(92.18,37.8)
  L3_INT_1 w0.14: v1(64.12,44.78) 65,45.67 72.75,45.67 78.78,39.65 79.26,39.65 79.4,39.79 79.4,40.58 79.54,40.72 79.82,40.72 79.96,40.58 79.96,39.79 80.1,39.65 80.37,39.65 80.51,39.79 80.51,40.58 80.65,40.72 80.93,40.72 81.07,40.58 81.07,39.79 81.21,39.65 81.49,39.65 81.63,39.79 81.63,40.58 81.77,40.72 82.05,40.72 82.19,40.58 82.19,39.79 82.33,39.65 82.75,39.65 82.89,39.51 82.89,39.23 82.75,39.09 82.16,39.09 82.02,38.95 82.02,38.67 82.16,38.53 82.75,38.53 82.89,38.39 82.89,38.11 82.75,37.97 82.16,37.97 82.02,37.83 82.02,37.55 82.16,37.41 82.75,37.41 82.89,37.27 82.89,36.99 82.75,36.85 82.16,36.85 82.02,36.71 82.02,36.41 82.16,36.27 87.61,36.27 87.75,36.41 87.75,36.77 87.89,36.91 88.16,36.91 88.3,36.77 88.3,36.41 88.44,36.27 88.68,36.27 88.82,36.41 88.82,36.69 88.96,36.83 89.24,36.83 89.38,36.69 89.38,36.41 89.52,36.27 89.8,36.27 89.94,36.41 89.94,36.69 90.07,36.83 90.35,36.83 90.49,36.69 90.49,36.27 90.64,36.13 90.91,36.13 91.05,36.27 91.05,36.69 92.16,37.8 v1(92.18,37.8)
  BOTTOM w0.14: v1(64.12,44.78) 63.86,45.04 63.86,47.32 64.5,47.96 64.5,49.13 64.64,49.27 66.26,49.27 66.4,49.41 66.4,49.68 66.26,49.82 64.64,49.82 64.5,49.96 64.5,50.24 64.64,50.38 66.26,50.38 66.4,50.52 66.4,50.8 66.26,50.94 64.64,50.94 64.5,51.08 64.5,51.43 64.64,51.57 66.14,51.57 66.27,51.71 66.27,51.99 66.14,52.13 64.62,52.13 64.48,52.27 64.48,52.55 64.62,52.69 66.14,52.69 66.27,52.83 66.27,53.11 66.14,53.25 64.64,53.25 64.5,53.39 64.5,53.67 64.64,53.81 66.14,53.81 66.27,53.95 66.27,54.23 66.14,54.37 64.64,54.37 64.5,54.51 64.5,54.78 64.64,54.92 66.14,54.92 66.27,55.06 66.27,56.47 66.1,56.64 66.1,57.31 66.4,57.61 67.93,57.61 74.34,64.02 74.34,71.01 74.02,71.33 74.02,72.59 R2129.2
ECAT1_TXD3: length 96.8
  TOP w0.14: R1310.1 v1(91.29,37.92)
  L3_INT_1 w0.14: v1(63.1,43.89) 63.1,45.67 64.37,46.94 72.71,46.94 78.54,41.11 79.2,41.11 79.34,41.25 79.34,41.99 79.48,42.13 79.76,42.13 79.9,41.99 79.9,41.25 80.04,41.11 80.32,41.11 80.46,41.25 80.46,41.99 80.6,42.13 80.88,42.13 81.02,41.99 81.02,41.25 81.16,41.11 81.44,41.11 81.58,41.25 81.58,41.99 81.72,42.13 82,42.13 82.14,41.99 82.14,41.25 82.28,41.11 82.55,41.11 82.69,41.25 82.69,41.99 82.83,42.13 83.11,42.13 83.25,41.99 83.25,38.45 83.39,38.31 83.67,38.31 83.81,38.45 83.81,41.95 83.95,42.09 84.21,42.09 84.37,41.93 84.37,38.45 84.51,38.31 84.79,38.31 84.93,38.45 84.93,40.73 85.07,40.87 85.4,40.87 85.55,40.72 85.55,39.42 85.69,39.28 86.68,39.28 86.82,39.14 86.82,38.94 86.68,38.8 85.69,38.8 85.55,38.66 85.55,38.46 85.69,38.32 86.76,38.32 87.79,37.29 88.8,37.29 88.94,37.43 88.94,38.04 89.08,38.18 89.36,38.18 89.5,38.04 89.5,37.43 89.64,37.29 90.66,37.29 v1(91.29,37.92)
  BOTTOM w0.14: v1(63.1,43.89) 62.59,44.4 62.59,45.04 63.42,45.86 63.42,48.15 64.15,48.89 64.15,57.27 64.85,57.97 67.83,57.97 74.02,64.16 74.02,70.69 72.88,71.83 72.88,72.85 72.38,73.35 R2128.2
ECAT1_TXEN: length 105.9
  TOP w0.127: v1(90.4,37.93) R1305.1 ; v1(49.51,38.18) 49.51,39.83 46.34,43 46.34,55.47 44.58,57.23 44.15,57.23 43.28,58.1 U103.3
  BOTTOM w0.127: v1(49.51,38.18) 47.43,36.1 47.43,29.85 49.46,27.82 52.96,27.82 54.63,26.15 59,26.15 59.8,25.35 64.22,25.35 65.49,26.62 73.77,26.62 74.91,27.76 78.09,27.76 79.23,26.62 83.14,26.62 84.36,25.4 90.45,25.4 91.09,24.77 96.91,24.77 98.43,26.29 98.43,33.17 94.39,37.21 91.12,37.21 v1(90.4,37.93)
ECAT_ACT0: length 7.7
  TOP w0.127: R883.2 v2(118.85,109.93)
  BOTTOM w0.127: v2(118.85,109.93) 119.34,110.42 119.34,113.39 117.71,115.01 R885.2
ECAT_ACT1: length 2.5
  TOP w0.127: R884.2 v2(118.85,111.33)
  BOTTOM w0.127: v2(118.85,111.33) 117.96,112.22 R891.2
ECAT_LINK0: length 173.8
  TOP w0.127: R1117.2 51.83,35.54 v1(52.05,35.77) ; R1117.2 51.83,34.79 52.21,34.41 52.29,34.41 52.55,34.15 R1116.1 52.94,33.99 54.11,32.82 U121.25 ; R1117.2 48.52,34.9 44.18,30.56 v1(44.18,25.22) ; v1(68.18,30.56) 71.1,27.64 v1(71.1,24.59) ; v1(43.29,21.29) 43.8,20.78 43.8,15.19 42.91,14.3 42.91,9.1 46.97,5.03 59.68,5.03 J28.14 ; R2159.2 v1(130.79,62.94)
  L3_INT_1 w0.127: v1(71.1,24.59) 72.24,23.45 76.82,23.45 78.28,21.99 84.63,21.99 84.88,22.24 88.44,22.24 89.36,21.31 100.08,21.31 100.44,21.67 100.44,24.77 106.23,30.56 109.84,30.56 113.52,34.24 116.69,34.24 120.63,38.18 120.63,39.19 122.66,41.23 123.81,41.23 127.74,45.16 127.74,55.2 128.5,55.96 128.5,57.74 130.79,60.02 v1(130.79,62.94) ; v1(68.18,30.56) 68.18,30.81 64.88,34.11 62.97,34.11 61.96,35.13 53.96,35.13 53.32,35.77 v1(52.05,35.77)
  BOTTOM w0.127: v1(43.29,21.29) 43.29,24.34 v1(44.18,25.22)
ECAT_LINK1: length 150.7
  TOP w0.127: v1(129.27,64.98) 129.39,64.85 R2160.2 ; v1(100.06,35.26) 101.83,33.48 113.01,33.48 v1(114.41,34.88) ; U123.25 86.37,32.82 84.94,34.24 R1173.1 R1172.2 84.3,35.79 v1(84.31,35.79) 83.52,35.79 83.32,35.99 79.71,35.99 75.7,31.99 v1(75.7,25.22)
  L3_INT_1 w0.127: v1(129.27,64.98) 129.39,64.85 129.39,59.51 128.12,58.24 128.12,56.21 127.36,55.45 127.36,45.29 123.93,41.86 122.66,41.86 120.25,39.45 120.25,38.31 116.82,34.88 v1(114.41,34.88) ; v1(100.06,35.26) 99.55,35.77 99.55,36.78 95.61,40.72 89.26,40.72 v1(87.86,42.12)
  BOTTOM w0.127: v1(87.86,42.12) 87.36,42.12 83.29,38.05 83.29,36.81 v1(84.31,35.79) ; v1(75.7,25.22) 75.55,25.07 68.76,25.07 64.88,21.19 64.88,6.17 69.45,1.6 82.44,1.6 J32.14
ECAT_SYNC0: length 19.1
  TOP w0.127: v2(122.41,108.28) 122.66,108.54 R881.2
  BOTTOM w0.127: v2(122.41,108.28) 119.95,110.75 119.95,115.32 119.04,116.22 119.04,121.43 R875.2
ECAT_SYNC1: length 13.8
  TOP w0.127: R882.2 121.01,108.8 v2(121.01,108.28)
  BOTTOM w0.127: R878.2 118.73,118.32 118.73,115.78 119.64,114.86 119.64,110.42 121.01,109.04 v2(121.01,108.28)
ENET0_CRS_DV: length 38.2
  TOP w0.127: v1(50.95,32.34) R2606.1
  TOP w0.14: v1(50.95,32.34) 51.07,32.21 R1122.1
  BOTTOM w0.14: v1(50.95,32.34) 50.95,32.88 51.57,33.51 52.83,33.51 52.97,33.65 52.97,33.97 52.83,34.1 51.83,34.1 51.69,34.24 51.69,34.46 51.83,34.6 54.44,34.6 54.99,35.15 61.72,35.15 71.48,44.91 71.48,50.62 72,51.14 R234.2
ENET0_INT_B: length 107.1
  TOP w0.127: R1236.1 63.73,31.07 64.23,30.58 v1(65.02,30.58) ; U6.M13 v1(104.29,67.64)
  L3_INT_1 w0.127: v1(65.02,30.58) 65.55,30.05 75.98,30.05 79.08,26.95 82.71,26.95 83.55,26.11 85.45,26.11 85.81,25.76 90.63,25.76 91,25.39 96.92,25.39 106.79,35.26 110.34,35.26 116.69,41.61 117.46,41.61 120.58,44.73 120.58,54.61 121.6,55.63 121.6,62.51 121.77,62.69 v1(121.77,62.78)
  BOTTOM w0.127: v1(104.29,67.64) 104.29,67.43 103.89,67.03 103.89,66.66 104.12,66.43 104.48,66.43 104.69,66.22 104.69,65.88 104.93,65.64 105.26,65.64 105.67,65.23 111.23,65.23 111.99,64.47 120.08,64.47 v1(121.77,62.78)
ENET0_RST_B: length 125.6
  TOP w0.127: v1(105.9,67.64) 105.89,67.64 105.88,67.64 U6.M15 ; v1(56.88,40.97) 56.88,39.68 57.38,39.17 57.38,37.66 R405.1
  L3_INT_1 w0.127: v1(56.88,40.97) 62.29,40.97 66.02,37.24 66.02,35 68.43,32.59 73.89,32.59 79.23,27.26 84.94,27.26 86.11,26.09 90.81,26.09 91.2,25.69 96.72,25.69 106.79,35.77 110.34,35.77 116.57,41.99 117.38,41.99 120.28,44.89 120.28,54.74 121.29,55.76 121.29,62.97 122.79,64.47 v1(122.79,68.4)
  BOTTOM w0.127: v1(122.79,68.4) 122,68.4 121.34,67.75 112.02,67.75 112.01,67.74 106.01,67.74 105.91,67.64 v1(105.9,67.64)
ENET0_RXD0: length 36.2
  TOP w0.127: R2604.1 65.55,27.64 v1(65.53,27.63)
  TOP w0.14: v1(65.53,27.63) 65.16,27.26 64.7,27.26 64.5,27.46 64.23,27.46 64.18,27.51 R1233.1
  BOTTOM w0.14: v1(65.53,27.63) 65.53,28.12 65.13,28.53 65.13,29.8 65.79,30.46 65.79,32.05 65.92,32.17 66.15,32.17 66.27,32.3 66.27,32.55 66.15,32.68 65.92,32.68 65.79,32.81 65.79,33.06 65.92,33.19 66.33,33.19 66.45,33.32 66.45,33.57 66.33,33.7 65.92,33.7 65.79,33.82 65.79,34.08 65.92,34.2 66.33,34.2 66.45,34.33 66.45,34.59 66.33,34.71 65.92,34.71 65.79,34.84 65.79,35.09 65.92,35.22 66.07,35.22 66.2,35.35 66.2,35.6 66.07,35.73 65.92,35.73 65.79,35.86 65.79,37.06 72.42,43.69 72.42,50.04 73.39,51.01 76.43,51.01 R232.2
ENET0_RXD1: length 38.6
  TOP w0.127: R2605.1 v1(65.64,29.42)
  TOP w0.14: v1(65.64,29.42) 65.1,28.88 64.15,28.88 63.73,29.29 R1234.1
  BOTTOM w0.14: R233.2 76.94,50.62 73.77,50.62 72.87,49.73 72.87,43.63 66.84,37.6 66.84,32.18 66.96,32.06 67.36,32.06 67.51,31.91 67.51,31.61 67.37,31.48 66.33,31.48 66.2,31.35 66.2,31.1 66.33,30.97 67.57,30.97 67.7,30.84 67.7,30.59 67.57,30.46 66.33,30.46 66.2,30.33 66.2,30.08 66.33,29.95 67.57,29.95 67.7,29.83 67.7,29.54 67.57,29.42 v1(65.64,29.42)
ENET0_RXER: length 38.5
  TOP w0.127: v1(51.17,31.15) 51.12,31.19 R2607.1
  TOP w0.14: R1235.1 51.31,30.43 51.19,30.56 51.19,31.13 v1(51.17,31.15)
  BOTTOM w0.14: v1(51.17,31.15) 52.23,31.15 52.53,31.45 52.53,32.18 55.15,34.8 62.9,34.8 71.99,43.89 71.99,50.37 73.13,51.51 R235.2
ENET0_TX_REF_CLK: length 26.5
  TOP w0.14: v1(63.56,38.43) R2603.1 64.38,37.88 64.24,37.74 63.85,37.74 63.71,37.6 63.71,37.32 63.85,37.18 64.48,37.18 64.62,37.04 64.62,35.52 R1240.1
  BOTTOM w0.14: v1(63.56,38.43) 64.29,38.43 71.1,45.24 71.1,53.67 R231.2
ENET0_TXD0: length 28.2
  TOP w0.14: R1237.1 v1(63.1,37.8)
  BOTTOM w0.14: R228.2 71.1,56.21 69.96,55.07 69.96,48.59 68.18,46.81 68.18,45.87 64.65,42.35 64.65,42.15 64.82,41.98 64.82,41.79 64.62,41.59 64.39,41.59 64.24,41.73 63.99,41.73 63.81,41.56 63.81,41.35 63.94,41.22 63.94,41.08 63.75,40.88 63.55,40.88 63.47,40.96 63.27,40.96 62.08,39.78 62.08,38.31 62.59,37.8 v1(63.1,37.8)
ENET0_TXD1: length 26.2
  TOP w0.14: R1238.1 62.21,37.8 61.8,38.2 61.8,38.61 62.08,38.89 62.59,38.89 62.72,38.76 v1(62.72,38.43)
  BOTTOM w0.14: v1(62.72,38.43) 62.59,38.56 62.59,39.7 63.04,40.16 63.81,40.16 65.52,41.87 65.52,42.07 65.32,42.27 65.32,42.47 65.52,42.67 65.72,42.67 65.92,42.46 66.12,42.46 69.45,45.8 69.45,47.2 70.34,48.08 70.34,54.94 71.1,55.7 R229.2
ENET0_TXEN: length 30.3
  TOP w0.127: R2620.1 v1(63.06,39.32)
  TOP w0.14: R1239.1 57.77,37.8 58.35,38.38 62.11,39.32 v1(63.06,39.32)
  BOTTOM w0.14: v1(63.06,39.32) 63.73,39.32 69.96,45.54 69.96,46.94 70.72,47.7 70.72,54.31 71.61,55.2 R230.2
ENET1_INT_B: length 3.7
  TOP w0.127: R2643.2 130.54,103.96 v1(131.3,104.73)
  BOTTOM w0.127: v1(131.3,104.73) 131.11,104.92 U416.4 131.11,105.81 131.31,106 R2694.2
ENET1_RGMII_RX_EN: length 46.5
  TOP w0.127: v1(122.41,103.33) 121.49,102.41 121.31,102.41 120.92,102.8 120.74,102.8 120.56,102.62 120.56,102.44 120.95,102.05 120.95,101.87 113.75,94.67 108.95,94.67 105.31,91.04 105.31,86.49 102.47,83.64 102.47,81.9 101.82,81.25 101.82,80.53 101.89,80.47 101.89,76.43 U6.B10 ; R463.2 v1(126.98,103.58)
  BOTTOM w0.127: v1(122.41,103.33) 122.92,102.82 126.22,102.82 v1(126.98,103.58)
ENET1_RGMII_RXC: length 45.8
  TOP w0.127: U6.A12 103.09,83.63 105.62,86.16 105.62,90.91 108.13,93.42 113.26,93.42 v1(122.41,102.57) ; v1(128,103.58) 128.76,104.35 C201.1 R462.2
  BOTTOM w0.127: v1(128,103.58) 128,102.82 127.62,102.44 122.54,102.44 v1(122.41,102.57)
ENET1_RGMII_RXD0: length 45
  TOP w0.127: R458.2 v1(126.09,103.46) ; U6.B13 104.29,76.44 104.29,82.67 107.52,85.91 110.5,85.91 112.43,87.84 112.43,90.58 113.2,91.35 113.2,91.62 113.32,91.75 113.58,91.75 113.7,91.62 113.7,91.34 113.83,91.21 114.23,91.21 114.42,91.4 114.42,91.58 113.9,92.1 113.9,92.33 114.05,92.49 114.23,92.49 114.8,91.92 115.01,91.92 115.18,92.08 115.18,92.26 114.95,92.49 114.95,92.67 115.13,92.85 115.31,92.85 115.5,92.66 115.73,92.66 123.93,100.87 v1(123.93,103.33)
  BOTTOM w0.127: v1(123.93,103.33) 125.96,103.33 v1(126.09,103.46)
ENET1_RGMII_RXD1: length 46
  TOP w0.127: R460.2 v1(125.2,103.88) ; v1(122.96,103.88) 122.96,102.45 122.62,102.11 122.62,101.93 122.83,101.72 122.83,101.54 122.65,101.36 122.47,101.36 122.26,101.57 122.08,101.57 121.9,101.39 121.9,101.21 122.15,100.96 122.15,100.78 121.97,100.6 121.79,100.6 121.54,100.85 121.36,100.85 121.18,100.67 121.18,100.49 121.43,100.24 121.43,100.06 121.25,99.88 121.07,99.88 120.82,100.13 120.64,100.13 120.46,99.95 120.46,99.77 120.71,99.52 120.71,99.34 120.53,99.16 120.35,99.16 120.1,99.41 119.92,99.41 113.55,93.04 108.18,93.04 105.92,90.78 105.92,85.7 103.49,83.27 103.49,76.44 U6.B12
  BOTTOM w0.127: v1(122.96,103.88) v1(125.2,103.88)
ENET1_RGMII_RXD2: length 48
  TOP w0.127: U6.A15 105.49,81.21 106.15,81.87 106.15,83.9 107.85,85.6 110.62,85.6 112.73,87.71 112.73,90.22 113.14,90.63 114.53,90.63 118.65,94.75 118.83,94.75 119.38,94.21 119.56,94.21 119.72,94.37 119.72,94.58 119.19,95.11 119.19,95.29 119.64,95.74 119.82,95.74 120.21,95.34 120.39,95.34 120.57,95.52 120.57,95.7 120.18,96.1 120.18,96.28 120.36,96.45 120.54,96.45 120.93,96.06 121.11,96.06 121.29,96.24 121.29,96.42 120.9,96.81 120.9,96.99 121.08,97.17 121.26,97.17 121.65,96.78 121.83,96.78 122.01,96.96 122.01,97.14 121.62,97.53 121.62,97.71 121.8,97.89 121.98,97.89 122.37,97.5 122.55,97.5 122.73,97.68 122.73,97.86 122.34,98.25 122.34,98.43 122.52,98.61 122.7,98.61 123.09,98.22 123.27,98.22 123.45,98.4 123.45,98.58 123.06,98.97 123.06,99.15 123.23,99.33 123.41,99.33 123.81,98.94 123.99,98.94 124.17,99.12 124.17,99.3 123.77,99.69 123.77,99.87 124.44,100.54 124.44,103.84 124.31,103.96 R459.2
ENET1_RGMII_RXD3: length 48.6
  TOP w0.127: U6.A13 103.89,82.86 107.24,86.21 110.37,86.21 112.12,87.96 112.12,91.09 114.54,93.51 114.72,93.51 114.93,93.29 115.11,93.29 115.29,93.47 115.29,93.65 115.08,93.86 115.08,94.04 115.32,94.28 115.5,94.28 116.05,93.72 116.23,93.72 116.41,93.9 116.41,94.08 115.86,94.64 115.86,94.82 116.04,95 116.21,95 116.7,94.52 116.88,94.52 117.06,94.7 117.06,94.88 116.57,95.36 116.57,95.54 116.75,95.72 116.93,95.72 117.36,95.29 117.54,95.29 117.72,95.47 117.72,95.65 117.29,96.08 117.29,96.26 117.47,96.44 117.65,96.44 118.08,96.01 118.26,96.01 118.44,96.19 118.44,96.37 118.01,96.8 118.01,96.98 118.19,97.16 118.37,97.16 118.8,96.73 118.98,96.73 119.16,96.91 119.16,97.09 118.73,97.52 118.73,97.7 118.91,97.88 119.09,97.88 119.52,97.45 119.7,97.45 119.88,97.63 119.88,97.81 119.45,98.24 119.45,98.42 119.77,98.73 119.95,98.73 120.25,98.43 120.43,98.43 123.42,101.42 R461.2
ENET1_RGMII_TX_EN: length 54.7
  TOP w0.127: U6.E12 v1(103.49,74.04) ; U27.19 122.53,111.45 121.65,110.57 R882.1 121.26,110.18 121.09,110.02 121.09,109.51 120.25,108.66 120.25,107.27 120.63,106.89 120.63,104.98 119.76,104.11 119.76,104.11 119.11,103.46 v1(118.66,103.46)
  BOTTOM w0.127: v1(118.66,103.46) 117.84,102.63 117.84,99.77 117.61,99.55 117.43,99.55 117.21,99.78 117.03,99.78 116.85,99.6 116.85,99.42 117.07,99.19 117.07,99.01 116.89,98.83 116.71,98.83 116.64,98.91 116.46,98.91 116.28,98.73 116.28,98.55 116.35,98.47 116.35,98.29 116.18,98.11 116,98.11 115.92,98.19 115.74,98.19 115.56,98.01 115.56,97.83 115.64,97.75 115.64,97.57 115.46,97.39 115.28,97.39 115.2,97.47 115.02,97.47 114.84,97.29 114.84,97.11 114.92,97.03 114.92,96.85 112.68,94.62 109.3,94.62 105.54,90.86 105.54,88.4 103.36,86.21 103.36,84.58 100.69,81.92 100.69,79.71 102.72,77.68 102.72,75.47 103.09,75.1 103.09,74.44 v1(103.49,74.04)
ENET1_RGMII_TXC: length 52.5
  TOP w0.127: v1(105.1,82.12) 104.69,81.71 U6.A14 ; v1(120.31,103.9) 120.86,103.9 121.39,103.38 121.57,103.38 121.75,103.56 121.75,103.74 121.04,104.45 121.04,104.62 121.27,104.85 121.65,104.85 121.77,104.98 121.77,105.77 121.9,105.9 122.66,105.9 122.79,106.03 122.79,106.28 122.66,106.41 121.34,106.41 121.22,106.53 121.22,106.79 121.34,106.91 122.66,106.91 122.79,107.04 122.79,107.3 122.66,107.42 121.85,107.42 121.72,107.55 121.72,108.57 122.15,109 122.15,110.05 122.28,110.18 R881.1 122.66,110.7 123.02,111.05 U27.20
  BOTTOM w0.127: v1(105.1,82.12) 105.1,84.37 106.45,85.72 110.61,85.72 112.78,87.89 112.78,91.8 120.31,99.33 v1(120.31,103.9)
ENET1_RGMII_TXD0: length 55.8
  TOP w0.127: U27.18 122.3,111.85 120.62,110.18 R883.1 120.62,109.55 119.74,108.66 119.74,107.14 120.25,106.63 120.25,105.26 v1(119.29,104.3) ; U6.E13 v1(104.29,74.04)
  BOTTOM w0.127: v1(104.29,74.04) 103.9,74.43 103.9,75 103.49,75.41 103.49,78.18 101.45,80.22 101.45,81.82 105.96,86.32 110.36,86.32 112.17,88.14 112.17,92.71 119.24,99.78 119.24,99.96 119.12,100.09 118.98,100.09 118.85,100.22 118.85,100.47 118.98,100.6 119.36,100.6 119.49,100.72 119.49,100.98 119.36,101.11 118.98,101.11 118.85,101.23 118.85,101.49 118.98,101.61 119.36,101.61 119.49,101.74 119.49,101.99 119.36,102.12 118.98,102.12 118.85,102.25 118.85,102.5 118.98,102.63 119.36,102.63 119.49,102.76 119.49,104.1 v1(119.29,104.3)
ENET1_RGMII_TXD1: length 55
  TOP w0.127: U6.C12 103.48,74.85 103.48,74.84 v1(103.49,74.83) ; v1(118.58,104.35) 119.74,105.51 119.74,106.5 119.23,107.01 119.23,108.41 118.17,109.48 118.17,110.22 118.59,110.65 120.32,110.65 120.62,110.95 R884.1 121.27,111.33 122.19,112.26 U27.17
  BOTTOM w0.127: v1(118.58,104.35) 118.82,104.11 118.82,104.11 119.13,103.79 119.13,103.26 118.34,102.47 118.34,99.52 112.25,93.42 108.54,93.42 105.85,90.73 105.85,88.27 103.74,86.16 103.74,84.53 101.07,81.87 101.07,80.09 103.1,78.06 103.1,75.47 103.49,75.08 v1(103.49,74.83)
ENET1_RGMII_TXD2: length 55.8
  TOP w0.127: U27.16 121.7,112.66 121.09,112.04 118.55,112.04 117.84,111.33 117.84,109.04 118.85,108.03 118.85,106.76 119.12,106.5 v1(119.12,105.62) ; v1(104.3,74.84) 104.29,74.83 104.28,74.83 U6.D13
  BOTTOM w0.127: v1(104.3,74.84) 104.3,74.84 104.29,74.85 104.29,74.93 103.87,75.35 103.87,78.31 101.82,80.36 101.82,81.73 106.11,86.02 110.49,86.02 112.48,88.01 112.48,92.38 119.84,99.75 119.84,104.89 v1(119.12,105.62)
ENET1_RGMII_TXD3: length 53.2
  TOP w0.127: v1(117.96,108.16) 117.46,108.66 117.46,111.46 118.47,112.47 120.76,112.47 121.34,113.05 U27.15 ; v1(105.63,82.63) 105.63,81.98 105.09,81.44 105.09,76.44 U6.B14
  BOTTOM w0.127: v1(105.63,82.63) 105.63,84.27 106.78,85.41 110.74,85.41 113.09,87.76 113.09,88.9 113.93,89.74 113.93,92.31 120.88,99.27 120.88,105.23 v1(117.96,108.16)
ENET1_RST_B: length 4.3
  TOP w0.127: R2644.2 121.13,115.02 v1(120.76,115.39)
  BOTTOM w0.127: U410.2 121.01,118.06 121.27,117.8 R2684.2 121.27,115.91 v1(120.76,115.39)
ENET2_INT_B: length 148.7
  TOP w0.127: v1(92.57,94.06) 91.8,93.29 R1087.2 91.69,91.26 91.31,90.88 91.31,88.86 89.42,86.97 v1(89.42,86.69) ; v1(130.41,69.29) 130.66,69.29 R128.2 ; R518.2 R517.2 34.9,67.01 33.06,68.85 v1(33.06,76.6)
  L3_INT_1 w0.127: v1(92.57,94.06) 93.33,94.82 107.93,94.82 109.45,96.34 111.23,96.34 123.17,84.41 123.17,82.25 128.38,77.04 128.38,70.82 127.86,70.3 127.86,69.31 128.25,68.91 130.03,68.91 v1(130.41,69.29)
  BOTTOM w0.127: v1(33.06,76.6) 35.48,76.6 39.35,80.47 39.35,85.17 45.07,90.88 55.35,90.88 56.62,89.61 78.34,89.61 80.88,87.07 89.03,87.07 v1(89.42,86.69)
ENET2_MII_COL: length 109
  TOP w0.127: R1311.1 82.15,31.32 81.39,32.08 v1(81.39,32.59) ; R1169.2 81.01,60.8 v1(81.01,60.81)
  L3_INT_1 w0.14: v1(64.88,43.91) 65.46,44.49 65.68,44.49 66.15,44.02 66.49,44.02 66.62,44.15 66.62,44.53 66.75,44.66 67,44.66 67.13,44.53 67.13,44.03 67.26,43.91 67.51,43.91 67.64,44.03 67.64,44.53 67.76,44.66 68.02,44.66 68.15,44.53 68.15,44.03 68.27,43.91 68.53,43.91 68.65,44.03 68.65,44.53 68.78,44.66 69.03,44.66 69.16,44.53 69.16,44.03 69.29,43.91 69.54,43.91 69.67,44.03 69.67,44.53 69.8,44.66 70.05,44.66 70.18,44.53 70.18,44.03 70.3,43.91 70.56,43.91 70.69,44.03 70.69,44.53 70.81,44.66 71.07,44.66 71.19,44.53 71.19,44.03 71.32,43.91 71.57,43.91 71.7,44.03 71.7,44.53 71.83,44.66 72.08,44.66 72.21,44.53 72.21,44.03 72.34,43.91 72.95,43.91 78.85,38.01 78.85,34.45 80.7,32.59 v1(81.39,32.59)
  BOTTOM w0.14: v1(64.88,43.91) 67.48,46.51 67.48,47.39 69.22,49.13 69.22,56.72 69.67,57.17 69.67,57.91 71.05,59.28 71.05,59.28 72.68,60.91 73.35,60.91 73.48,61.04 73.48,61.93 73.61,62.05 73.86,62.05 73.99,61.93 73.99,60.28 74.12,60.15 74.37,60.15 74.5,60.28 74.5,63.07 74.62,63.2 74.88,63.2 75,63.07 75,61.04 75.13,60.91 75.39,60.91 75.51,61.04 75.51,63.83 75.64,63.96 75.89,63.96 76.02,63.83 76.02,61.04 76.15,60.91 76.4,60.91 76.53,61.04 76.53,63.83 76.66,63.96 76.91,63.96 77.04,63.83 77.04,61.04 77.16,60.91 77.42,60.91 77.54,61.04 77.54,63.83 77.67,63.96 77.93,63.96 78.05,63.83 78.05,61.04 78.18,60.91 78.43,60.91 78.56,61.04 78.56,63.83 78.69,63.96 78.94,63.96 79.07,63.83 79.07,61.04 79.2,60.91 79.45,60.91 79.58,61.04 79.58,63.83 79.7,63.96 79.96,63.96 80.08,63.83 80.08,61.04 80.21,60.91 80.47,60.91 80.59,61.04 80.59,63.83 80.72,63.96 80.97,63.96 81.1,63.83 81.1,63.31 81.23,63.19 81.9,63.19 82.02,63.06 82.02,62.8 81.9,62.68 81.23,62.68 81.1,62.55 81.1,62.3 81.23,62.17 81.9,62.17 82.02,62.04 82.02,61.79 81.9,61.66 81.23,61.66 81.01,61.44 v1(81.01,60.81)
ENET2_MII_CRS: length 94
  TOP w0.14: v1(82.15,35.26) 82.15,33.86 82.66,33.35 R1309.1
  L3_INT_1 w0.14: v1(63.99,43.89) 65.26,45.16 72.5,45.16 78.61,39.05 81.38,39.05 81.51,38.91 81.51,38.63 81.38,38.49 79.56,38.49 79.42,38.35 79.42,38.07 79.56,37.93 81.17,37.93 81.31,37.79 81.31,37.51 81.17,37.37 79.56,37.37 79.42,37.23 79.42,36.95 79.56,36.81 80.64,36.81 80.78,36.67 80.78,36.39 80.64,36.25 79.56,36.25 79.42,36.11 79.42,35.83 79.61,35.64 81.77,35.64 v1(82.15,35.26)
  BOTTOM w0.14: R2133.2 74.54,71.45 74.66,71.33 74.66,63.82 69.2,58.36 69.2,57.32 68.64,56.76 68.64,56.46 68.5,56.32 66.92,56.32 66.78,56.18 66.78,55.9 66.92,55.76 68.5,55.76 68.64,55.62 68.64,55.35 68.5,55.21 66.92,55.21 66.78,55.07 66.78,54.79 66.92,54.65 68.5,54.65 68.64,54.51 68.64,54.23 68.5,54.09 66.92,54.09 66.78,53.95 66.78,53.67 66.92,53.53 68.5,53.53 68.64,53.39 68.64,53.11 68.5,52.97 66.92,52.97 66.78,52.83 66.78,52.55 66.92,52.41 68.5,52.41 68.64,52.27 68.64,51.99 68.5,51.85 66.92,51.85 66.78,51.71 66.78,51.43 66.92,51.29 68.5,51.29 68.64,51.15 68.64,50.84 68.5,50.7 66.92,50.7 66.78,50.56 66.78,50.28 66.92,50.14 68.5,50.14 68.64,50 68.64,49.69 68.43,49.48 66.91,49.48 66.78,49.35 66.78,48.97 66.91,48.85 67.8,48.85 67.93,48.72 67.93,48.47 67.67,48.21 65.64,48.21 65,47.58 65,44.91 v1(63.99,43.89)
ENET2_RGMII_RX_EN: length 36.9
  TOP w0.127: R516.2 35.68,60.29 v1(35.68,60.29)
  BOTTOM w0.127: v1(35.68,60.29) 35.68,60.74 36.21,61.27 36.21,61.43 36.04,61.6 36.04,61.76 36.15,61.87 36.31,61.87 36.48,61.7 36.64,61.7 36.75,61.81 36.75,61.97 36.57,62.14 36.57,62.3 36.69,62.41 36.84,62.41 37.02,62.24 37.17,62.24 37.29,62.35 37.29,62.51 37.11,62.68 37.11,62.84 37.23,62.95 37.38,62.95 37.56,62.78 37.71,62.78 37.83,62.89 37.83,63.05 37.65,63.22 37.65,63.38 37.76,63.49 37.92,63.49 38.09,63.32 38.25,63.32 38.51,63.58 46.97,63.58 47.22,63.32 56.12,63.32 57.13,64.34 57.13,65.48 59.16,67.52 60.31,67.52 64.12,67.52 R216.2
ENET2_RGMII_RXC: length 33.1
  TOP w0.127: v1(37.83,60.4) 36.81,60.4 35.92,61.29 C223.1 R515.2
  BOTTOM w0.127: R219.2 58.4,65.23 58.15,64.98 58.15,63.83 56.37,62.05 46.46,62.05 46.08,62.44 40.42,62.44 40.24,62.26 40.09,62.26 39.87,62.47 39.72,62.47 39.6,62.36 39.6,62.2 39.82,61.99 39.82,61.83 39.7,61.72 39.55,61.72 39.34,61.93 39.18,61.93 39.07,61.82 39.07,61.66 39.28,61.45 39.28,61.3 39.16,61.18 39.01,61.18 38.8,61.39 38.64,61.39 38.53,61.28 38.53,61.12 38.74,60.91 38.74,60.76 38.39,60.4 v1(37.83,60.4)
ENET2_RGMII_RXD0: length 40.6
  TOP w0.127: R514.2 v1(37.19,58.63)
  BOTTOM w0.127: v1(37.19,58.63) 37.83,58.63 40.95,61.75 44.56,61.75 45.07,61.24 45.88,61.24 45.99,61.13 45.99,61.1 46.1,60.99 46.26,60.99 46.37,61.1 46.37,61.13 46.48,61.24 46.8,61.24 47.01,61.03 47.19,61.03 47.4,61.24 47.56,61.24 47.67,61.13 47.67,60.9 47.78,60.78 47.94,60.78 48.05,60.9 48.05,61.13 48.16,61.24 48.32,61.24 48.43,61.13 48.43,60.9 48.54,60.78 48.7,60.78 48.81,60.9 48.81,61.13 48.93,61.24 49.08,61.24 49.19,61.13 49.19,60.9 49.31,60.78 49.46,60.78 49.58,60.9 49.58,61.13 49.69,61.24 49.85,61.24 49.96,61.13 49.96,60.9 50.07,60.78 50.23,60.78 50.34,60.9 50.34,61.13 50.45,61.24 50.61,61.24 50.72,61.13 50.72,60.9 50.83,60.78 50.99,60.78 51.1,60.9 51.1,61.13 51.21,61.24 51.37,61.24 51.48,61.13 51.48,60.9 51.59,60.78 51.75,60.78 51.86,60.9 51.86,61.13 51.97,61.24 52.13,61.24 52.24,61.13 52.24,60.9 52.35,60.78 52.51,60.78 52.62,60.9 52.62,61.13 52.74,61.24 52.89,61.24 53,61.13 53,60.9 53.12,60.78 53.27,60.78 53.39,60.9 53.39,61.13 53.5,61.24 53.66,61.24 53.77,61.13 53.77,60.9 53.88,60.78 54.04,60.78 54.15,60.9 54.15,61.13 54.26,61.24 54.42,61.24 54.53,61.13 54.53,60.9 54.64,60.78 54.8,60.78 54.91,60.9 54.91,61.13 55.02,61.24 55.18,61.24 55.29,61.13 55.29,60.9 55.4,60.78 55.56,60.78 55.67,60.9 55.67,61.13 55.78,61.24 56.7,61.24 59.79,64.34 62.98,64.34 R217.2
ENET2_RGMII_RXD1: length 37.7
  TOP w0.127: R511.2 v1(35.67,57.74)
  BOTTOM w0.127: v1(35.67,57.74) 35.67,59.62 36.42,60.37 36.42,60.53 36.35,60.6 36.35,60.76 36.47,60.87 36.62,60.87 36.69,60.8 36.85,60.8 36.96,60.91 36.96,61.07 36.89,61.14 36.89,61.3 37.01,61.41 37.16,61.41 37.23,61.34 37.39,61.34 37.5,61.45 37.5,61.61 37.43,61.68 37.43,61.84 37.54,61.95 37.7,61.95 37.77,61.88 37.93,61.88 38.04,61.99 38.04,62.15 37.97,62.22 37.97,62.38 38.08,62.49 38.24,62.49 38.31,62.42 38.47,62.42 38.58,62.53 38.58,62.69 38.51,62.76 38.51,62.92 38.62,63.03 38.78,63.03 38.85,62.96 39.01,62.96 39.25,63.2 46.72,63.2 47.1,62.82 56.11,62.82 57.44,64.14 57.44,65.28 59.29,67.13 63.48,67.13 63.86,66.75 R218.2
ENET2_RGMII_RXD2: length 34.7
  TOP w0.127: R512.2 v1(36.68,56.85)
  BOTTOM w0.127: R220.2 64.12,63.71 63.18,64.64 62.65,64.64 62.65,64.65 59.59,64.65 56.62,61.67 46.08,61.67 45.7,62.05 40.52,62.05 37.83,59.36 37.17,59.36 36.68,58.88 v1(36.68,56.85)
ENET2_RGMII_RXD3: length 33.7
  TOP w0.127: R513.2 v1(35.67,55.96)
  BOTTOM w0.127: R221.2 59.29,66.63 57.77,65.1 57.77,63.96 56.24,62.44 46.84,62.44 46.46,62.82 39.5,62.82 36.18,59.49 36.18,56.47 v1(35.67,55.96)
ENET2_RGMII_TXD2: length 47.6
  TOP w0.127: U29.16 27.1,55.2 29.99,52.31 v1(36.68,52.31)
  BOTTOM w0.127: v1(36.68,52.31) 36.68,52.86 36.57,52.97 35.96,52.97 35.85,53.08 35.85,53.24 35.96,53.35 36.57,53.35 36.68,53.46 36.68,53.62 36.57,53.73 35.96,53.73 35.85,53.84 35.85,54 35.96,54.11 36.57,54.11 36.68,54.22 36.68,54.38 36.57,54.49 35.89,54.49 35.78,54.6 35.78,54.76 35.89,54.87 36.31,54.87 36.68,55.25 36.68,55.55 40.65,59.51 58.78,59.51 60.94,61.67 60.94,62.18 61.07,62.31 R223.2
ENET2_RGMII_TXD3: length 51.1
  TOP w0.127: v1(37.67,52.17) 37.27,51.77 29.83,51.77 26.71,54.89 U29.15
  BOTTOM w0.127: R222.2 61.12,61.42 58.85,59.15 40.76,59.15 38.13,56.51 38.13,56.26 37.98,56.12 37.73,56.12 37.45,55.83 37.45,55.01 37.56,54.9 38.55,54.9 38.66,54.79 38.66,54.63 38.55,54.52 37.56,54.52 37.45,54.41 37.45,54.25 37.56,54.14 38.68,54.14 38.79,54.03 38.79,53.87 38.68,53.76 37.56,53.76 37.45,53.64 37.45,53.49 37.56,53.37 38.68,53.37 38.79,53.26 38.79,53.11 38.68,52.99 37.86,52.99 37.67,52.81 v1(37.67,52.17)
ENET2_RST_B: length 139.1
  TOP w0.127: v1(24.75,54.05) 24.74,54.06 R522.2 25.5,55.58 U29.12 ; v1(113.01,68.28) 112.85,68.44 106.69,68.44 U6.L16 ; v1(96.75,41.99) 96.75,41.35 96.37,40.97 90.54,40.97 R1018.1
  L3_INT_1 w0.127: v1(54.84,44.66) 58.53,48.34 74.66,48.34 78.47,44.53 86.34,44.53 88.88,41.99 90.91,41.99 91.17,42.24 96.12,42.24 96.37,41.99 v1(96.75,41.99) 96.75,42.5 101.33,47.07 108.67,47.07 111.99,50.4 111.99,67.26 v1(113.01,68.28)
  BOTTOM w0.127: v1(24.75,54.05) 25.38,53.42 25.38,49.23 26.9,47.7 44.05,47.7 47.1,44.66 v1(54.84,44.66)
ENET3_INT_B: length 74.4
  TOP w0.127: R111.2 99.57,90.15 99.57,89.08 v1(100.06,88.6) ; U418.4 39.62,86.8 39.22,87.21 R2697.2 39.22,90.24 v1(39.48,90.5)
  L3_INT_1 w0.127: v1(100.06,88.6) 100.18,88.47 100.18,86.69 97.69,84.2 87.2,84.2 85.43,85.98 72.44,85.98 70.91,84.46 53.91,84.46 51.03,87.33 46.34,87.33 43.16,90.5 v1(39.48,90.5)
ENET3_INT_B_3V3: length 2
  TOP w0.127: R570.2 R571.2 U418.2
ENET3_MII_COL: length 45.1
  TOP w0.127: v1(50.53,31.68) 51.44,31.68 R1273.1
  L3_INT_1 w0.127: v1(63.7,66.06) 64.04,65.71 64.04,51.31 61.58,48.85 58.07,48.85 54.08,44.86 54.08,41.99 54.44,41.63 v1(54.44,41.23)
  BOTTOM w0.127: v1(50.53,31.68) 50.35,31.86 50.35,34.8 51.42,35.87 51.42,38.43 53.7,40.72 53.93,40.72 v1(54.44,41.23) ; R1232.2 64.01,65.74 v1(63.7,66.06)
ENET3_MII_CRS: length 42.3
  TOP w0.127: v1(49.76,33.1) R1271.1
  L3_INT_1 w0.127: v1(60.42,63.72) 60.42,62.93 62.97,60.38 62.97,50.88 61.3,49.2 57.92,49.2 53.75,45.03 v1(53.75,41.37)
  BOTTOM w0.127: v1(53.75,41.37) 51.03,38.66 51.03,35.99 49.76,34.72 v1(49.76,33.1) ; v1(60.42,63.72) 60.53,63.83 R1231.2
ENET3_RST_B: length 100.8
  TOP w0.127: U417.2 24.62,74.88 24.49,75.02 R2696.2 v1(22.71,74.37)
  L3_INT_1 w0.127: v1(22.71,74.37) 26.4,78.06 26.4,85.8 29.89,89.3 33.45,89.3 34.02,89.87 36.43,89.87 37.45,88.85 40.37,88.85 40.87,89.36 43.67,89.36 46.16,86.87 50.86,86.87 53.57,84.15 71.04,84.15 72.56,85.68 85.28,85.68 87.06,83.9 97.9,83.9 101.83,87.84 v1(101.83,88.6)
  BOTTOM w0.127: v1(101.83,88.6) 102.1,88.86 R114.2
ENET3_RST_B_3V3: length 6.7
  TOP w0.127: U417.4 25.27,77.54 R2695.2 25.77,77.56 25.89,77.68 25.89,78.56 26.77,79.45 R575.2 27.54,80.85 U34.12
ENET4_CARD_DET_B: length 88.1
  TOP w0.127: v1(92.69,20.78) 92.42,21.05 77.43,21.05 74.04,24.44 74.04,32.82 76.74,35.52 76.74,48.48 77.12,48.86 77.12,49.41 78.6,50.89 R2596.2 ; v1(114.53,3.63) 114.6,3.7 J134.5
  BOTTOM w0.127: v1(92.69,20.78) 93.71,19.76 93.71,15.57 102.09,7.19 113.26,7.19 114.53,5.92 v1(114.53,3.63)
ENET4_CRS_DV: length 69.7
  TOP w0.127: R2614.1 R1289.1 83.55,32.26 83.85,31.97 84.63,31.97 85.07,32.41 v1(85.07,32.46)
  BOTTOM w0.127: R250.2 95.56,54.23 95.43,54.1 95.43,53.73 95.56,53.6 97.29,53.6 97.42,53.47 97.42,53.22 97.29,53.09 94.85,53.09 94.72,52.97 94.72,52.68 94.85,52.56 95.82,52.56 95.94,52.43 95.94,52.18 95.82,52.05 94.85,52.05 94.72,51.92 94.72,51.67 94.85,51.54 95.82,51.54 95.94,51.41 95.94,51.16 95.82,51.03 94.85,51.03 94.72,50.91 94.72,50.65 94.85,50.53 95.82,50.53 95.94,50.4 95.94,50.14 95.82,50.02 94.85,50.02 94.72,49.89 94.72,49.64 94.85,49.51 95.82,49.51 95.94,49.38 95.94,49.13 95.82,49 94.85,49 94.72,48.87 94.72,48.62 94.85,48.49 95.82,48.49 95.94,48.37 95.94,48.11 95.82,47.99 94.85,47.99 94.72,47.86 94.72,47.6 94.85,47.48 95.82,47.48 95.94,47.35 95.94,47.1 95.82,46.97 94.85,46.97 94.72,46.84 94.72,46.59 94.85,46.46 95.82,46.46 95.94,46.33 95.94,46.08 95.82,45.95 94.85,45.95 94.72,45.83 94.72,45.57 95.38,44.91 95.38,44.66 95.25,44.52 95.09,44.52 94.68,44.93 94.52,44.93 94.41,44.82 94.41,44.66 94.82,44.25 94.82,44.09 94.71,43.98 94.55,43.98 94.14,44.39 93.98,44.39 93.87,44.28 93.87,44.13 94.28,43.71 94.28,43.55 94.17,43.44 94.01,43.44 93.6,43.86 93.44,43.86 93.33,43.74 93.33,43.59 93.74,43.17 93.74,43.02 93.63,42.9 93.47,42.9 93.06,43.32 92.9,43.32 92.79,43.2 92.79,43.05 93.2,42.63 93.2,42.48 93.09,42.36 92.93,42.36 92.52,42.78 92.36,42.78 92.25,42.67 92.25,42.51 92.66,42.09 92.66,41.94 92.55,41.83 92.39,41.83 91.98,42.24 91.82,42.24 91.71,42.13 91.71,41.97 92.13,41.56 92.13,41.4 92.01,41.29 91.86,41.29 91.44,41.7 91.28,41.7 91.17,41.59 91.17,41.43 91.59,41.02 91.59,40.86 91.47,40.75 91.32,40.75 90.95,41.11 90.8,41.11 90.68,41 90.68,40.84 91.05,40.48 91.05,40.32 89.29,38.56 89.29,35.26 88.2,34.17 87.7,34.17 87.59,34.05 87.59,33.49 87.48,33.38 87.32,33.38 87.21,33.49 87.21,34.05 87.1,34.17 86.94,34.17 86.83,34.05 86.83,33.49 86.72,33.38 86.56,33.38 86.45,33.49 86.45,34.05 86.33,34.17 85.76,34.17 85.61,34.02 85.61,33.86 85.94,33.52 85.94,33.36 85.83,33.25 85.68,33.25 85.34,33.59 85.18,33.59 85.07,33.48 85.07,33.07 85.18,32.96 86.51,32.96 86.62,32.84 86.62,32.69 86.4,32.46 v1(85.07,32.46)
ENET4_GPIO: length 105.5
  TOP w0.127: v1(127.36,2.75) TP1061.1 R284.1 ; v1(80.12,56.97) 80.63,56.47 80.63,52.4 77.45,49.23 77.45,48.72 77.07,48.34 77.07,35.26 74.4,32.59 74.4,24.51 77.56,21.35 96.18,21.35 v1(96.75,20.78)
  BOTTOM w0.127: v1(96.75,20.78) 96.5,20.78 95.99,20.27 95.48,20.27 95.23,20.02 95.23,15.95 102.98,8.21 113.77,8.21 118.22,3.76 126.35,3.76 v1(127.36,2.75) ; R2597.2 v1(80.12,56.97)
ENET4_INT_B: length 112.5
  TOP w0.127: v1(140.44,60.66) 140.32,60.53 R137.2 ; R1313.1 95.87,30.18 96.01,30.32 96.77,30.32 97.64,31.19 98.28,31.19 99.04,30.43 99.04,29.64 99.68,29.01 99.68,24.21 v1(100.95,22.94) ; v1(138.92,38.56) 138.92,30.31 135.23,26.62 129.27,26.62 125.96,23.32 125.96,17.73 126.73,16.97 128,16.97 v1(128.63,16.33) R2585.2 R2586.2
  L3_INT_1 w0.127: v1(140.44,60.66) 140.44,58.12 141.2,57.36 141.2,53.16 140.7,52.66 140.7,47.32 142.58,45.44 142.58,40.69 140.44,38.56 v1(138.92,38.56)
  BOTTOM w0.127: v1(128.63,16.33) 128.12,16.84 117.84,16.84 116.95,17.73 116.95,23.45 113.52,26.88 104.76,26.88 104.5,26.62 104.5,23.95 104.25,23.7 101.71,23.7 v1(100.95,22.94)
ENET4_RGMII_RX_EN: length 76.9
  TOP w0.127: R274.2 v1(118.6,16.33) ; R2614.2 82.03,33.35 81.9,33.48 81.7,33.48 81.57,33.35 81.57,33.23 81.44,33.1 81.19,33.1 81.06,33.23 81.06,33.35 80.94,33.48 80.77,33.48 80.64,33.35 80.64,31.75 80.51,31.63 80.26,31.63 80.13,31.75 80.13,33.35 80,33.48 79.75,33.48 79.62,33.35 79.62,31.7 79.5,31.57 79.24,31.57 79.12,31.7 79.12,33.35 78.99,33.48 78.73,33.48 78.61,33.35 78.61,31.7 78.48,31.57 78.23,31.57 78.1,31.7 78.1,33.1 77.97,33.23 77.7,33.23 77.58,33.1 77.58,31.7 77.45,31.57 76.31,31.57 76.18,31.45 76.18,23.7 77.92,21.96 95.02,21.96 95.36,22.3 98.15,22.3 v1(98.79,22.94)
  BOTTOM w0.127: v1(118.6,16.33) 118.6,16.33 118.09,15.83 114.03,15.83 112.12,13.92 106.69,13.92 102.6,18.01 102.6,19.23 100.44,21.39 100.44,22.05 100.06,22.43 99.29,22.43 v1(98.79,22.94)
ENET4_RGMII_RXC: length 76.9
  TOP w0.127: R275.2 v1(119.61,16.33) ; R2603.2 65.13,37.47 65.64,36.96 66.27,36.96 66.4,36.83 66.4,36.57 66.27,36.45 65.77,36.45 65.64,36.32 65.64,36.07 65.77,35.94 66.27,35.94 66.4,35.81 66.4,35.56 66.27,35.43 65.77,35.43 65.64,35.3 65.64,35.05 65.77,34.92 66.27,34.92 66.4,34.8 66.4,34.54 66.27,34.42 65.77,34.42 65.64,34.29 65.64,33.96 71.61,27.99 71.61,26.01 77.18,20.44 86.86,20.44 87.61,19.69 94.77,19.69 95.36,20.27 98.02,20.27 98.28,20.53 98.28,21.29 v1(98.79,21.8)
  BOTTOM w0.127: v1(119.61,16.33) 119.61,16.33 118.73,15.45 114.15,15.45 112.25,13.54 106.56,13.54 102.22,17.88 102.22,19.13 100.06,21.29 99.29,21.29 v1(98.79,21.8)
ENET4_RGMII_RXD0: length 76.9
  TOP w0.127: R276.2 v1(120.63,16.33) ; v1(98.79,20.78) 99.29,20.27 99.29,19.13 99.42,19 100.06,19 100.18,19.13 100.18,19.89 100.31,20.02 100.95,20.02 101.07,20.14 101.07,20.4 100.95,20.53 100.44,20.53 100.31,20.65 100.31,23.12 99.98,23.45 98.2,23.45 98.07,23.57 98.07,23.83 97.94,23.95 97.69,23.95 97.56,23.83 97.56,23.57 97.44,23.45 97.01,23.45 96.88,23.57 96.88,23.9 96.75,24.03 96.5,24.03 96.37,23.9 96.37,23.57 96.25,23.45 95.99,23.45 95.87,23.57 95.87,23.9 95.74,24.03 95.48,24.03 95.36,23.9 95.36,23.57 95.23,23.45 94.98,23.45 94.85,23.57 94.85,24.41 94.98,24.54 96.5,24.54 96.63,24.66 96.63,24.92 96.5,25.04 94.98,25.04 94.85,25.17 94.85,25.42 94.98,25.55 96.68,25.55 96.81,25.68 96.81,26.75 96.94,26.88 97.19,26.88 97.32,26.75 97.32,25.68 97.45,25.55 98.4,25.55 98.53,25.68 98.53,26.09 98.4,26.21 98.02,26.21 97.9,26.34 97.9,26.59 98.02,26.72 98.4,26.72 98.53,26.85 R2612.2
  BOTTOM w0.127: v1(120.63,16.33) 119.36,15.06 118.69,15.06 118.56,14.94 118.56,14.43 118.44,14.3 118.18,14.3 118.06,14.43 118.06,14.94 117.93,15.06 117.71,15.06 117.58,14.94 117.58,13.28 117.46,13.15 117.14,13.15 117.01,13.28 117.01,14.94 116.89,15.06 116.63,15.06 116.51,14.94 116.51,13.29 116.38,13.16 116.12,13.16 116,13.29 116,14.94 115.87,15.06 115.62,15.06 115.49,14.94 115.49,13.29 115.36,13.16 115.11,13.16 114.98,13.29 114.98,14.94 114.85,15.06 114.6,15.06 114.47,14.94 114.47,13.29 114.35,13.16 114.09,13.16 113.97,13.29 113.97,14.18 113.84,14.3 113.58,14.3 113.46,14.18 113.46,13.29 113.33,13.16 106.48,13.16 101.4,18.24 100.82,18.24 100.69,18.37 100.69,18.6 100.82,18.72 101.58,18.72 101.71,18.85 101.71,19.11 101.58,19.23 100.82,19.23 100.69,19.36 100.69,20.14 100.56,20.27 100.31,20.27 100.18,20.14 100.18,19.26 100.06,19.13 99.8,19.13 99.68,19.26 99.68,20.14 99.04,20.78 v1(98.79,20.78)
ENET4_RGMII_RXD1: length 77
  TOP w0.127: R277.2 v1(121.52,16.33) ; R2613.2 98.53,29.04 98.02,29.54 97.39,29.54 97.26,29.67 97.26,29.92 97.39,30.05 97.77,30.05 97.9,30.18 97.9,30.56 98.02,30.69 98.28,30.69 98.66,30.3 98.66,29.59 99.29,28.95 99.29,27.1 99.04,26.85 99.04,26.59 99.29,26.34 99.29,26.08 99.04,25.83 99.04,25.58 99.29,25.32 99.29,25.11 99.17,24.98 97.39,24.98 97.26,24.85 97.26,24.6 97.39,24.47 99.17,24.47 99.29,24.35 99.29,24.08 99.17,23.95 v1(98.79,23.95)
  BOTTOM w0.127: v1(98.79,23.95) 98.28,23.45 98.28,20.53 98.53,20.27 98.96,20.27 99.29,19.94 99.29,19.13 101.19,17.23 101.37,17.23 101.47,17.34 101.65,17.34 101.83,17.16 101.83,16.98 101.67,16.81 101.67,16.63 101.84,16.45 102.02,16.45 102.19,16.62 102.37,16.62 102.55,16.44 102.55,16.26 102.38,16.09 102.38,15.91 102.56,15.73 102.74,15.73 102.91,15.9 103.09,15.9 103.27,15.72 103.27,15.54 103.1,15.37 103.1,15.19 103.28,15.01 103.46,15.01 103.63,15.18 103.81,15.18 103.99,15 103.99,14.82 103.82,14.66 103.82,14.48 104,14.3 104.18,14.3 104.35,14.46 104.53,14.46 104.71,14.28 104.71,14.11 104.54,13.94 104.54,13.76 104.72,13.58 104.9,13.58 105.07,13.75 105.25,13.75 105.43,13.57 105.43,13.39 105.26,13.22 105.26,13.04 105.44,12.86 105.62,12.86 105.79,13.03 105.97,13.03 106.21,12.78 112.01,12.78 112.13,12.65 112.13,12.4 112.26,12.27 112.52,12.27 112.64,12.4 112.64,12.65 112.77,12.78 113.02,12.78 113.15,12.65 113.15,12.4 113.28,12.27 113.53,12.27 113.66,12.4 113.66,12.65 113.79,12.78 114.04,12.78 114.17,12.65 114.17,12.4 114.29,12.27 114.55,12.27 114.67,12.4 114.67,12.65 114.8,12.78 115.06,12.78 115.18,12.65 115.18,12.4 115.31,12.27 115.56,12.27 115.69,12.4 115.69,12.65 115.82,12.78 116.07,12.78 116.2,12.65 116.2,12.4 116.33,12.27 116.58,12.27 116.71,12.4 116.71,12.65 116.83,12.78 117.09,12.78 117.21,12.65 117.21,12.4 117.34,12.27 117.96,12.27 118.08,12.4 118.08,13.67 118.21,13.79 118.46,13.79 118.59,13.67 118.59,12.4 118.72,12.27 118.97,12.27 119.1,12.4 119.1,13.67 119.23,13.79 119.48,13.79 119.61,13.67 119.61,12.4 119.73,12.27 119.99,12.27 120.11,12.4 120.11,13.67 120.24,13.79 120.5,13.79 120.62,13.67 120.62,12.4 120.75,12.27 121.65,12.27 122.03,12.65 122.03,13.04 121.9,13.17 121.27,13.17 121.14,13.3 121.14,13.55 121.27,13.68 121.9,13.68 122.03,13.81 122.03,14.06 121.9,14.19 119.23,14.19 119.11,14.31 119.11,14.58 119.23,14.71 122.03,14.71 122.15,14.84 122.15,15.09 122.03,15.22 120.63,15.22 120.5,15.35 120.5,15.6 120.63,15.73 121.39,15.73 121.52,15.85 v1(121.52,16.33)
ENET4_RGMII_RXD2: length 77
  TOP w0.127: R2605.2 67.58,29.42 67.7,29.29 67.7,28.4 67.83,28.27 68.09,28.27 68.21,28.4 68.21,29.29 68.34,29.42 68.69,29.42 68.81,29.29 68.81,28.66 68.94,28.53 69.58,28.53 69.7,28.41 69.7,28.15 69.58,28.02 69.2,28.02 69.07,27.9 69.07,27.64 69.2,27.52 70.42,27.52 70.54,27.39 70.54,27.14 70.42,27.01 69.2,27.01 69.07,26.88 69.07,26.62 69.2,26.49 70.34,26.49 70.47,26.37 70.47,24.46 70.97,23.95 73.23,23.95 77.05,20.13 86.73,20.13 87.58,19.28 96.27,19.28 v1(96.75,19.76) ; R2618.2 v1(122.54,16.33)
  BOTTOM w0.127: v1(122.54,16.33) 122.54,12.52 121.86,11.85 112.17,11.85 111.66,12.35 105.46,12.35 98.29,19.52 98.29,20.01 98.02,20.27 97.52,20.27 97.01,19.76 v1(96.75,19.76)
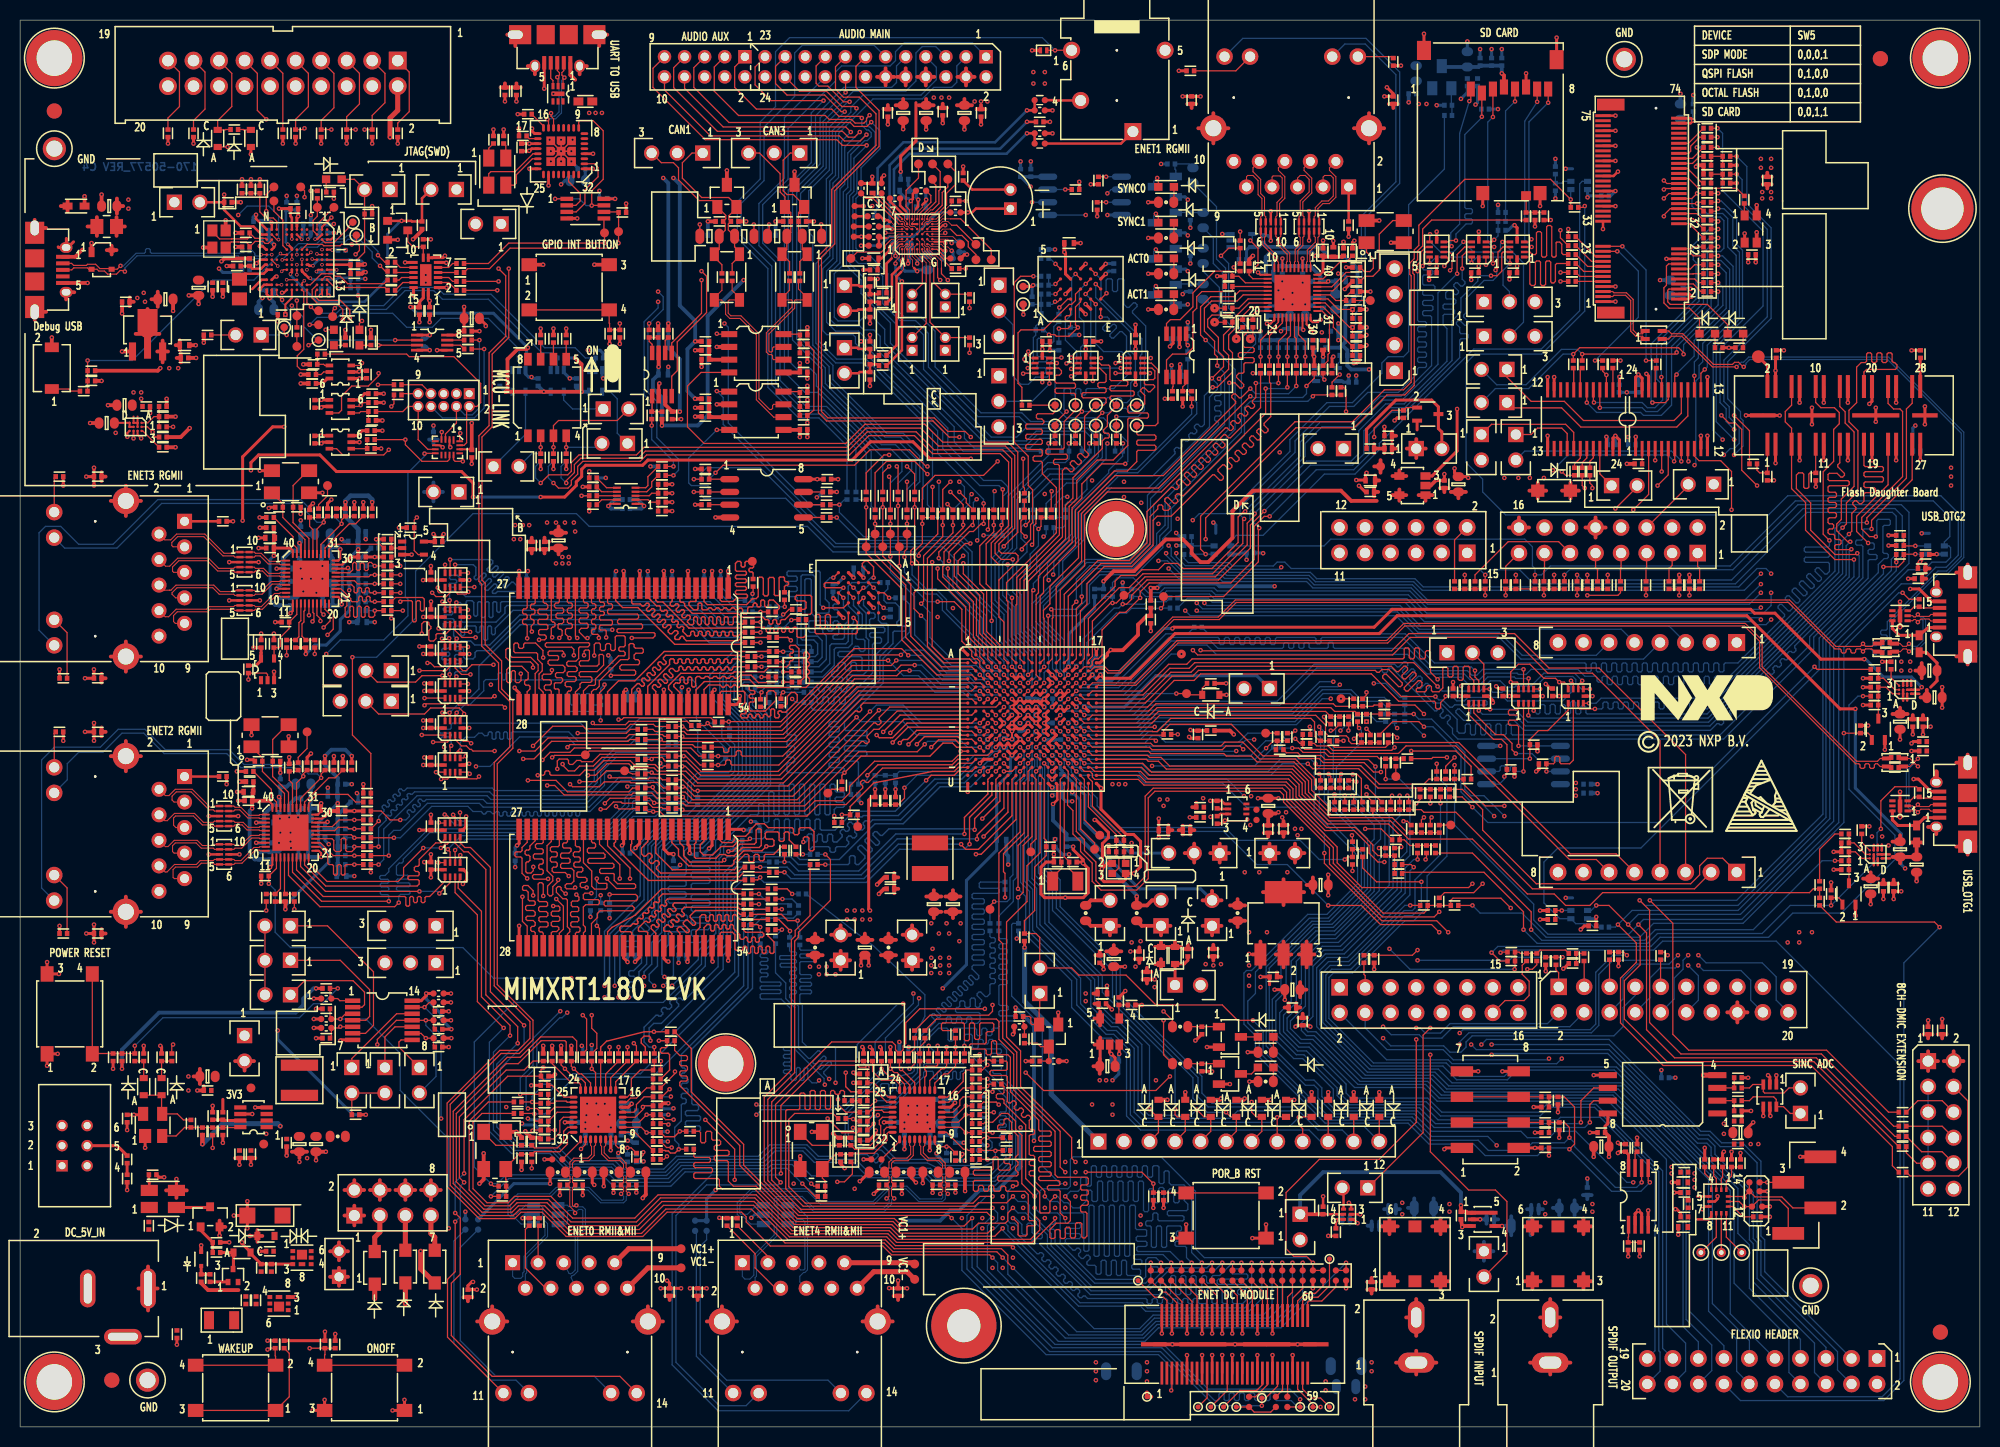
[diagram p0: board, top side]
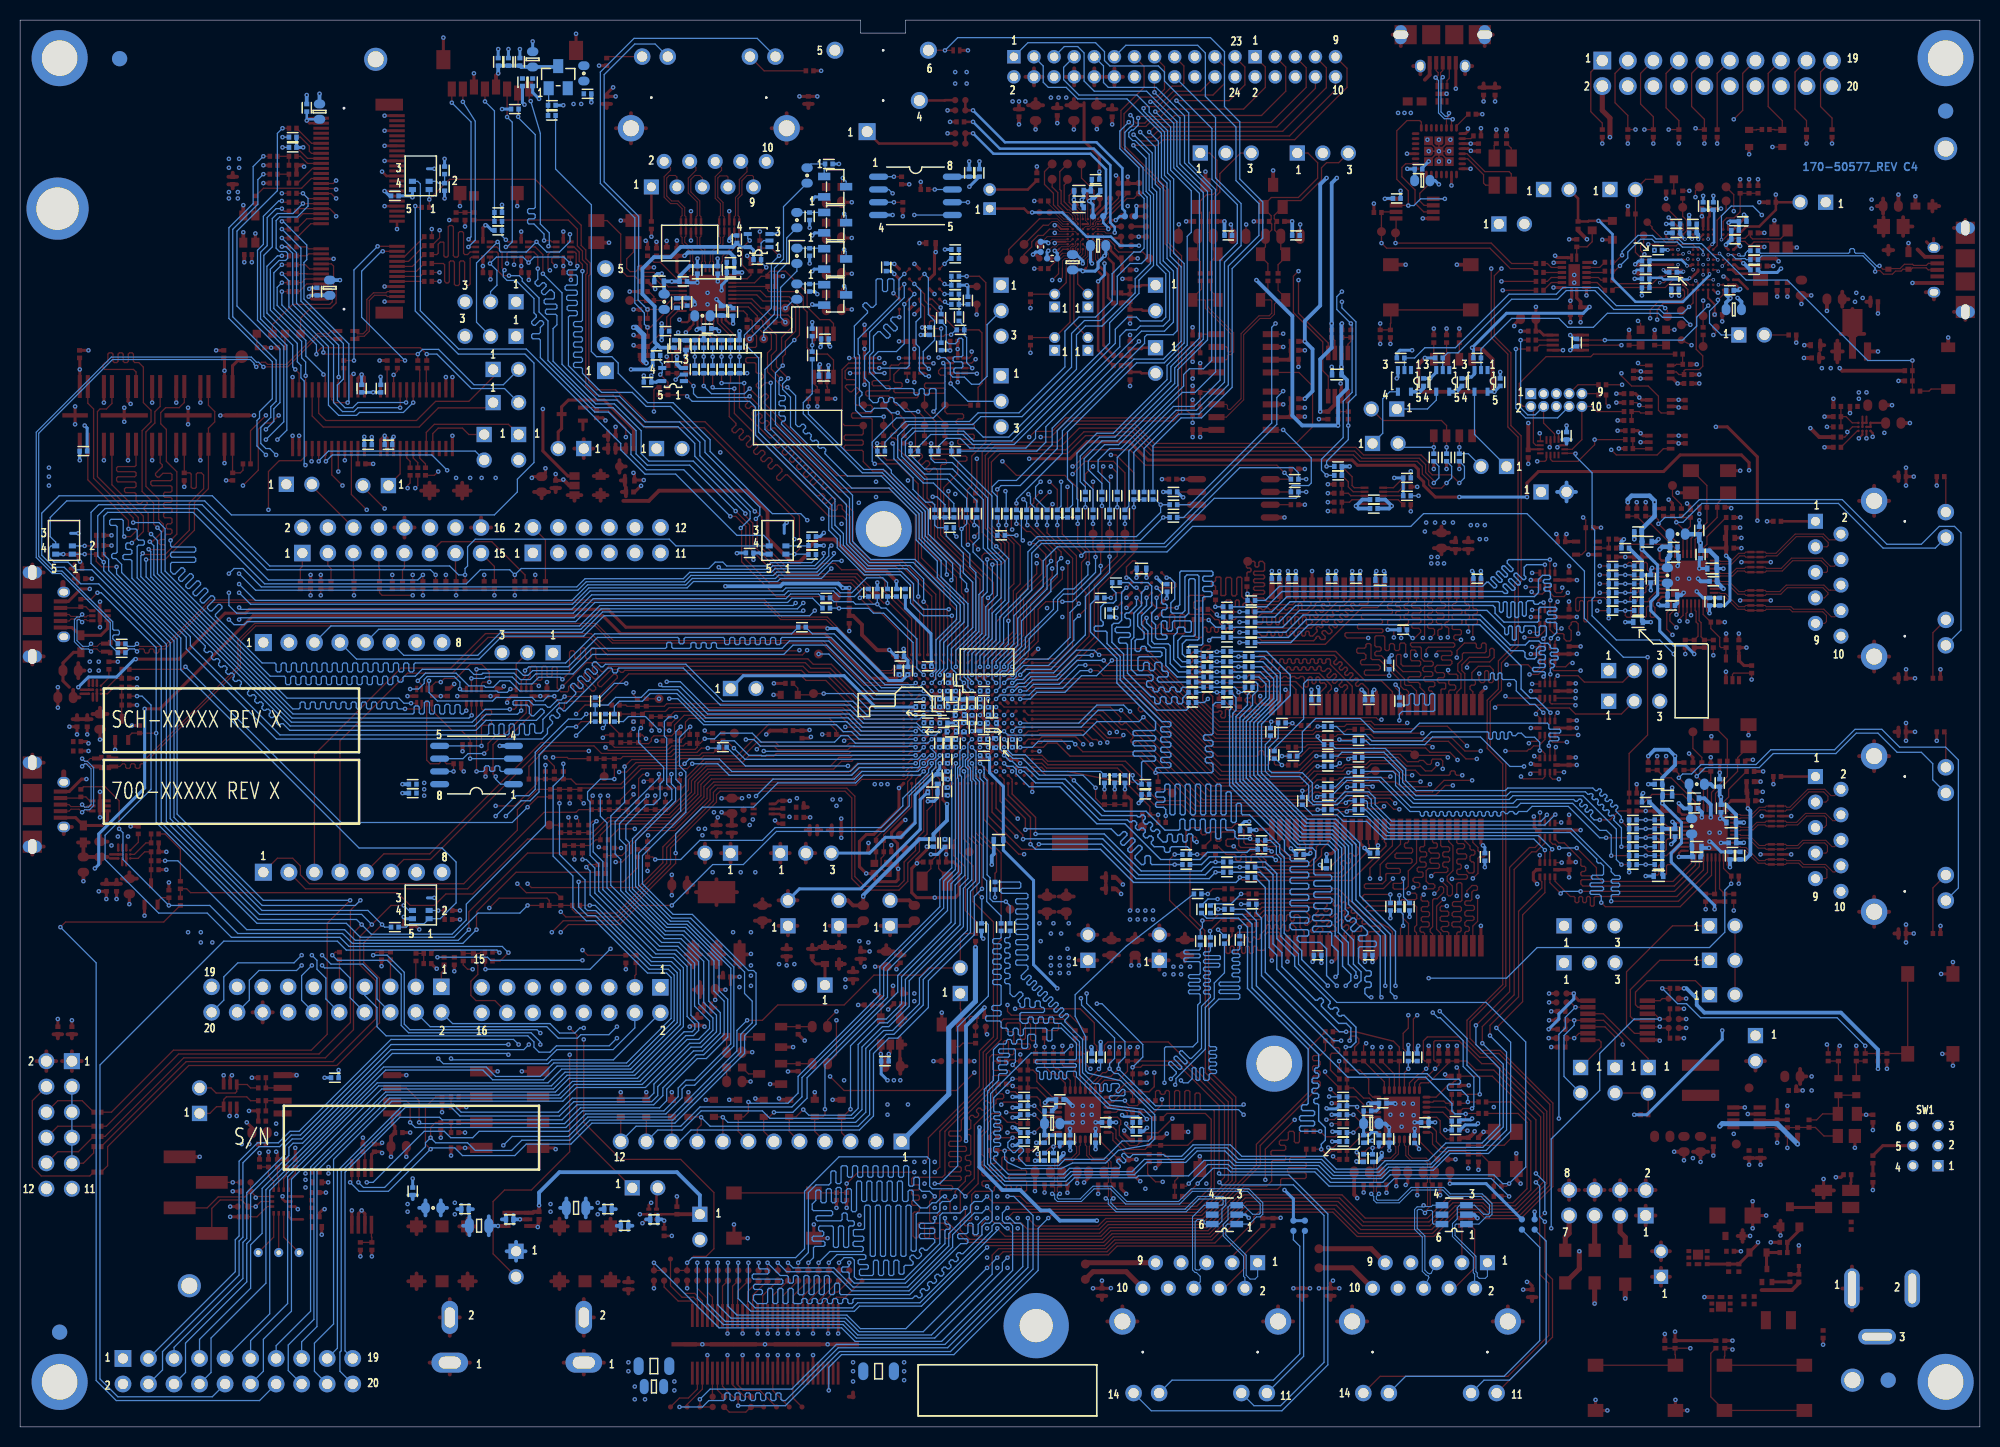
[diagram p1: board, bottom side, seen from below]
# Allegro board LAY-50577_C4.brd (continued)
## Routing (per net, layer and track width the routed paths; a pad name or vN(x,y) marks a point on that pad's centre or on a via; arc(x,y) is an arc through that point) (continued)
ENET4_RGMII_RXD3: length 77.3
  TOP w0.127: R2619.2 v1(123.55,16.33) ; v1(97.77,19.76) 96.98,18.98 87.46,18.98 86.6,19.83 76.93,19.83 73.11,23.65 69.88,23.65 69.58,23.95 69.58,24.59 69.45,24.72 67.16,24.72 67.03,24.84 67.03,25.17 67.16,25.29 68.76,25.29 68.89,25.42 68.89,25.67 68.76,25.8 67.16,25.8 67.03,25.93 67.03,26.18 67.16,26.31 68.56,26.31 68.69,26.44 68.69,26.69 68.56,26.82 67.16,26.82 67.03,26.94 R2604.2
  BOTTOM w0.127: v1(123.55,16.33) 123.55,12.78 122.28,11.51 111.99,11.51 111.48,12.02 105.31,12.02 97.77,19.56 v1(97.77,19.76)
ENET4_RGMII_TX_EN: length 94.9
  TOP w0.127: R273.2 v1(117.58,16.33) ; R2610.2 91.17,40.59 97.14,40.59 97.39,40.34 97.39,38.56 98.86,37.09 98.86,33.53 102.98,29.42 102.98,25.1 103.23,24.84 106.15,24.84 106.28,24.72 106.28,24.21 106.15,24.08 105.64,24.08 105.52,23.95 105.52,23.7 105.64,23.57 106.15,23.57 106.28,23.45 106.28,23.19 106.15,23.07 105.64,23.07 105.52,22.94 105.52,22.68 105.64,22.56 106.15,22.56 106.28,22.43 106.28,22.18 106.15,22.05 105.64,22.05 105.52,21.92 105.52,21.51 105.64,21.38 106.03,21.38 106.15,21.25 106.15,19 105.95,18.8 105.77,18.8 105.64,18.93 105.64,20.2 105.52,20.32 105.14,20.32 105.01,20.2 105.01,18.93 104.88,18.8 104.63,18.8 104.5,18.93 104.5,19.74 104.37,19.87 104.12,19.87 103.99,19.74 103.99,18.87 103.87,18.75 103.61,18.75 103.49,18.87 103.49,19.51 103.36,19.64 103.1,19.64 102.98,19.51 102.98,18.87 102.85,18.75 102.6,18.75 102.47,18.87 102.47,19.64 103.1,20.27 104.25,20.27 104.5,20.53 104.5,22.43 v1(103.99,22.94)
  BOTTOM w0.127: v1(117.58,16.33) 116.57,17.35 116.57,23.32 115.8,24.08 114.53,24.08 114.33,24.28 114.33,25.35 114.21,25.48 113.95,25.48 113.83,25.35 113.83,24.34 113.7,24.21 113.44,24.21 113.32,24.34 113.32,25.86 113.19,25.99 112.81,25.99 112.68,25.86 112.68,24.97 112.56,24.84 112.3,24.84 112.17,24.97 112.17,25.86 112.05,25.99 111.79,25.99 111.67,25.86 111.67,24.97 111.54,24.84 111.29,24.84 111.16,24.97 111.16,25.86 111.03,25.99 110.78,25.99 110.65,25.86 110.65,24.97 110.52,24.84 110.27,24.84 110.14,24.97 110.14,25.86 110.02,25.99 109.76,25.99 109.63,25.86 109.63,24.97 109.51,24.84 109.25,24.84 109.13,24.97 109.13,25.86 109,25.99 108.75,25.99 108.62,25.86 108.62,24.97 108.49,24.84 108.24,24.84 108.11,24.97 108.11,25.86 107.98,25.99 107.73,25.99 107.6,25.86 107.6,24.97 107.48,24.84 107.22,24.84 107.09,24.97 107.09,25.86 106.97,25.99 106.71,25.99 106.59,25.86 106.59,24.08 106.46,23.95 106.21,23.95 106.08,24.08 106.08,24.72 105.95,24.84 105.64,24.84 105.52,24.72 105.52,23.7 105.26,23.45 104.5,23.45 v1(103.99,22.94)
ENET4_RGMII_TXC: length 95
  TOP w0.127: v1(102.98,22.94) 102.47,22.43 102.47,21.41 102.34,21.29 101.58,21.29 101.45,21.41 101.45,23.32 100.06,24.72 100.06,30.05 97.9,32.21 97.9,32.52 97.77,32.64 97.26,32.64 97.14,32.77 97.14,33.03 97.26,33.15 97.77,33.15 97.9,33.28 97.9,33.85 R2611.2 ; R272.2 v1(116.57,16.33)
  BOTTOM w0.127: v1(102.98,22.94) 103.23,22.94 103.87,22.3 104.25,22.3 104.76,21.8 105.39,21.8 106.14,22.54 106.14,23.43 106.26,23.56 106.52,23.56 106.65,23.43 106.65,22.56 106.77,22.43 107.08,22.43 107.2,22.56 107.2,24.34 107.33,24.46 107.59,24.46 107.71,24.34 107.71,22.56 107.84,22.43 108.09,22.43 108.22,22.56 108.22,24.34 108.35,24.46 108.6,24.46 108.73,24.34 108.73,22.56 108.86,22.43 109.11,22.43 109.24,22.56 109.24,24.34 109.36,24.46 109.62,24.46 109.74,24.34 109.74,22.56 109.87,22.43 110.13,22.43 110.25,22.56 110.25,24.34 110.38,24.46 110.63,24.46 110.76,24.34 110.76,22.56 110.89,22.43 111.14,22.43 111.27,22.56 111.27,24.34 111.4,24.46 111.65,24.46 111.78,24.34 111.78,21.54 111.9,21.41 112.16,21.41 112.28,21.54 112.28,23.57 112.41,23.7 112.67,23.7 112.79,23.57 112.79,22.43 112.92,22.3 113.17,22.3 113.3,22.43 113.3,23.7 113.43,23.83 113.69,23.83 113.81,23.7 113.81,22.43 113.94,22.3 114.15,22.3 114.28,22.43 114.28,23.57 114.41,23.7 114.66,23.7 114.79,23.57 114.79,22.43 114.91,22.3 115.2,22.3 115.33,22.43 115.33,23.45 115.45,23.57 115.71,23.57 115.83,23.45 115.83,22.53 116.19,22.18 116.19,21.65 116.06,21.52 114.28,21.52 114.15,21.4 114.15,21.14 114.28,21.01 115.68,21.01 115.8,20.89 115.8,20.63 115.68,20.51 113.34,20.51 113.21,20.63 113.21,21.16 113.08,21.29 112.83,21.29 112.7,21.16 112.7,20.63 112.58,20.51 112.12,20.51 111.99,20.38 111.99,20.13 112.12,20 112.43,20 112.56,19.87 112.56,17.99 112.68,17.86 112.94,17.86 113.06,17.99 113.06,19.87 113.19,20 113.45,20 113.57,19.87 113.57,17.99 113.7,17.86 113.95,17.86 114.08,17.99 114.08,19.87 114.21,20 115.42,20 115.55,19.87 115.55,19.62 115.42,19.49 115.17,19.49 115.04,19.36 115.04,19.11 115.17,18.98 116.06,18.98 116.19,18.86 116.19,18.6 116.06,18.47 115.04,18.47 114.92,18.35 114.92,18.09 115.04,17.97 115.93,17.97 116.06,17.84 116.06,16.84 v1(116.57,16.33)
ENET4_RGMII_TXD0: length 95
  TOP w0.127: R2608.2 98.1,36.4 98.23,36.27 98.23,35.61 98.1,35.48 96.63,35.48 96.5,35.35 96.5,35.1 96.63,34.97 98.1,34.97 98.23,34.84 98.23,32.39 98.37,32.24 98.55,32.24 98.76,32.44 98.94,32.44 99.12,32.26 99.12,32.08 98.91,31.88 98.91,31.7 99.09,31.52 99.27,31.52 99.47,31.72 99.65,31.72 99.83,31.54 99.83,31.36 99.63,31.16 99.63,30.98 99.81,30.8 99.99,30.8 100.19,31 100.37,31 100.55,30.82 100.55,30.65 100.41,30.5 100.41,29.73 100.54,29.6 100.82,29.6 100.95,29.47 100.95,29.22 100.82,29.09 100.54,29.09 100.41,28.96 100.41,27.15 100.54,27.02 100.82,27.02 100.95,26.89 100.95,26.64 100.82,26.51 100.54,26.51 100.41,26.39 100.41,26.13 100.54,26.01 100.82,26.01 100.95,25.88 100.95,25.62 100.82,25.5 100.54,25.5 100.41,25.37 100.41,25.12 100.54,24.99 100.82,24.99 100.95,24.86 100.95,24.46 101.96,23.45 v1(101.96,22.94) ; R271.2 v1(115.55,16.33)
  BOTTOM w0.127: v1(101.96,22.94) 102.47,22.43 103.23,22.43 103.49,22.18 103.49,21.54 103.74,21.29 105.71,21.29 105.84,21.16 105.84,17.6 105.97,17.48 106.22,17.48 106.35,17.6 106.35,21.94 106.47,22.06 106.73,22.06 106.86,21.94 106.86,17.1 106.98,16.97 107.24,16.97 107.36,17.1 107.36,21.94 107.49,22.06 107.74,22.06 107.87,21.94 107.87,17.1 108,16.97 108.25,16.97 108.38,17.1 108.38,21.94 108.51,22.06 108.76,22.06 108.89,21.94 108.89,17.1 109.01,16.97 109.27,16.97 109.4,17.1 109.4,21.94 109.52,22.06 109.78,22.06 109.9,21.94 109.9,17.1 110.03,16.97 110.28,16.97 110.41,17.1 110.41,21.94 110.54,22.06 110.85,22.06 110.98,21.94 110.98,19.76 111.11,19.64 111.99,19.64 112.09,19.54 112.09,19.07 111.99,18.98 111.18,18.98 111.06,18.85 111.06,18.6 111.18,18.47 111.99,18.47 112.12,18.34 112.12,18.09 111.99,17.96 111.23,17.96 111.11,17.83 111.11,17.58 111.23,17.45 114.43,17.45 v1(115.55,16.33)
ENET4_RGMII_TXD1: length 94.7
  TOP w0.127: R2576.2 v1(114.53,16.33) ; v1(103.99,20.78) 103.49,21.29 103.49,23.45 103.36,23.57 102.34,23.57 102.22,23.7 102.22,23.9 102.34,24.03 103.36,24.03 103.46,24.13 103.46,24.39 103.33,24.51 101.48,24.51 101.35,24.64 101.35,24.82 101.48,24.95 102.47,24.95 102.6,25.07 102.6,25.25 102.47,25.38 101.48,25.38 101.35,25.51 101.35,25.76 101.48,25.89 102.47,25.89 102.6,26.02 102.6,26.27 102.47,26.4 101.48,26.4 101.35,26.52 101.35,26.78 101.48,26.9 102.47,26.9 102.6,27.03 102.6,27.29 102.47,27.41 100.97,27.41 100.84,27.54 100.84,27.79 100.97,27.92 102.47,27.92 102.6,28.05 102.6,28.3 102.47,28.43 101.48,28.43 101.35,28.56 101.35,28.81 101.48,28.94 102.47,28.94 102.6,29.06 102.6,29.32 102.47,29.44 101.48,29.44 101.35,29.57 101.35,30.53 98.53,33.35 98.53,36.78 98.28,37.04 97.29,37.04 97.16,37.16 97.16,38.31 97.04,38.43 96.78,38.43 96.65,38.31 96.65,37.16 96.53,37.04 96.25,37.04 96.12,37.16 96.12,37.48 95.99,37.6 94.6,37.6 94.47,37.73 94.47,37.98 94.6,38.11 95.99,38.11 96.12,38.24 96.12,39.2 96.25,39.33 96.75,39.33 96.88,39.45 96.88,40.08 96.75,40.2 95.6,40.2 95.48,40.08 95.48,38.69 95.35,38.56 95.1,38.56 94.97,38.69 94.97,40.08 94.84,40.2 94.59,40.2 94.46,40.08 94.46,38.56 94.33,38.43 94.08,38.43 93.95,38.56 93.95,40.08 93.83,40.21 91.8,40.21 91.67,40.08 91.67,39.58 91.81,39.44 R2609.2
  BOTTOM w0.127: v1(103.99,20.78) 103.99,20.39 104.12,20.26 105.39,20.26 105.52,20.13 105.52,19.88 105.39,19.75 104.12,19.75 103.99,19.62 103.99,19.37 104.12,19.24 105.39,19.24 105.52,19.12 105.52,18.86 105.39,18.73 104.12,18.73 103.99,18.61 103.99,18.37 104.78,17.58 104.96,17.58 105.16,17.79 105.34,17.79 105.52,17.61 105.52,17.43 105.32,17.22 105.32,17.04 105.6,16.76 105.78,16.76 106.11,17.09 106.29,17.09 106.47,16.91 106.47,16.73 106.14,16.4 106.14,16.22 106.28,16.08 106.92,16.08 107.05,15.95 107.05,15.32 107.18,15.19 107.43,15.19 107.56,15.32 107.56,16.46 107.69,16.59 107.94,16.59 108.07,16.46 108.07,15.19 108.19,15.06 108.45,15.06 108.58,15.19 108.58,16.46 108.7,16.59 108.96,16.59 109.08,16.46 109.08,15.19 109.21,15.06 109.46,15.06 109.59,15.19 109.59,16.46 109.72,16.59 109.96,16.59 110.09,16.46 110.09,15.19 110.22,15.06 111.36,15.06 111.49,15.19 111.49,15.57 111.36,15.7 110.72,15.7 110.6,15.83 110.6,16.03 110.72,16.16 111.49,16.16 111.61,16.28 111.61,16.54 111.49,16.66 110.98,16.66 110.85,16.79 110.85,17.02 110.98,17.15 113.72,17.15 v1(114.53,16.33)
ENET4_RGMII_TXD2: length 94.7
  TOP w0.127: v1(100.95,21.8) 100.95,21.03 101.45,20.53 101.45,19.59 100.54,18.67 87.33,18.67 86.48,19.52 76.8,19.52 73.23,23.09 63.48,23.09 61.16,20.78 54.97,20.78 52.81,22.94 49.19,22.94 48.55,22.3 46.46,22.3 45.07,23.7 45.07,30.3 45.95,31.19 R2607.2 ; R2617.2 v1(113.52,16.33)
  BOTTOM w0.127: v1(100.95,21.8) 101.45,21.29 103.23,21.29 103.49,21.03 103.49,18.24 107.04,14.68 111.74,14.68 111.99,14.94 111.99,16.59 112.25,16.84 113.01,16.84 v1(113.52,16.33)
ENET4_RGMII_TXD3: length 94.3
  TOP w0.127: v1(102.98,20.78) 102.98,20.63 100.72,18.37 87.2,18.37 86.35,19.22 76.68,19.22 73.11,22.79 63.71,22.79 61.32,20.4 54.81,20.4 52.58,22.63 49.31,22.63 48.68,22 46.25,22 44.68,23.57 44.68,30.43 46.59,32.34 R2606.2 ; R2616.2 v1(112.5,16.33)
  BOTTOM w0.127: v1(102.98,20.78) 102.98,20.3 102.85,20.17 102.6,20.17 102.47,20.04 102.47,19.79 102.6,19.66 102.85,19.66 102.98,19.53 102.98,18.24 106.91,14.3 111.99,14.3 112.5,14.81 112.5,15.28 112.63,15.41 113.14,15.41 113.26,15.53 113.26,15.79 113.14,15.92 112.63,15.92 112.5,16.04 v1(112.5,16.33)
ENET4_RST_B: length 159.2
  TOP w0.127: v1(95.99,41.61) 89.52,41.61 88.12,40.21 88.12,38.16 87.86,37.91 87.86,37.54 R1288.1 87.1,37.54 87.1,37.98 86.77,38.31 80.75,38.31 74.78,32.34 74.78,24.56 77.69,21.66 96.62,21.66 v1(96.75,21.8) ; v1(131.93,16.33) R295.2 R2587.2
  L3_INT_1 w0.127: v1(95.99,41.61) 96.25,41.35 97.14,41.35 100.31,44.53 103.43,44.53 105.59,46.69 110.72,46.69 112.38,48.34 112.38,65.52 v1(112.63,65.78)
  BOTTOM w0.127: v1(131.93,16.33) 125.46,9.86 113.26,9.86 111.92,8.51 103.31,8.51 96.25,15.57 96.25,20.02 96.5,20.27 97.01,20.27 97.26,20.53 97.26,21.29 v1(96.75,21.8) ; R138.2 122.83,65.78 v1(112.63,65.78)
ENET4_RXD0: length 53.5
  TOP w0.127: R1290.1 97.01,27.51 v1(97.04,27.48) 97.07,27.51 R2612.1
  BOTTOM w0.127: R246.2 84.94,47.83 90.02,43 90.02,40.87 88.97,38.8 88.97,35.44 88.73,35.2 85.49,34.46 82.1,31.07 82.1,28.65 82.68,28.07 85.72,27.52 86.98,26.26 90.28,26.26 91.4,25.71 95.36,25.71 96.69,26.3 97.04,26.65 v1(97.04,27.48)
ENET4_RXD1: length 67.1
  TOP w0.127: R1291.1 95.86,28.78 v1(96.25,28.78) R2613.1
  BOTTOM w0.127: v1(96.25,28.78) 96.72,28.31 96.72,27.82 96.19,27.3 96.02,27.3 95.52,27.8 95.34,27.8 95.16,27.62 95.16,27.44 95.66,26.94 95.66,26.76 94.91,26.01 91.65,26.01 91.04,26.62 87.18,26.62 85.35,28.45 82.73,28.45 82.4,28.78 82.4,30.81 83.19,31.6 86.58,32.02 89.59,35.03 89.59,38.33 91.42,40.16 92.03,40.16 92.16,40.29 92.16,40.67 92.28,40.8 92.54,40.8 92.66,40.67 92.66,40.29 92.79,40.16 93.05,40.16 93.17,40.29 93.17,40.67 93.3,40.8 93.55,40.8 93.68,40.67 93.68,40.29 93.81,40.16 94.06,40.16 94.19,40.29 94.19,40.67 94.32,40.8 94.57,40.8 94.7,40.67 94.7,40.29 94.82,40.16 95.26,40.16 95.51,40.41 95.51,41.11 95.38,41.24 93.2,41.24 93.07,41.37 93.07,41.62 93.2,41.75 93.36,41.75 93.49,41.87 93.49,42.27 93.62,42.4 93.87,42.4 94,42.27 94,41.87 94.13,41.75 94.41,41.75 94.54,41.87 94.54,42.55 94.66,42.67 94.92,42.67 95.05,42.55 95.05,41.87 95.17,41.75 95.38,41.75 95.51,41.87 95.51,42.12 95.68,42.29 95.68,42.46 95.22,42.92 95.22,43.1 95.4,43.28 95.58,43.28 96.04,42.82 96.22,42.82 96.5,43.11 96.5,43.98 96.63,44.11 96.91,44.11 97.03,44.24 97.03,44.49 96.91,44.62 96.63,44.62 96.5,44.75 96.5,45 96.63,45.13 96.91,45.13 97.03,45.25 97.03,45.51 96.91,45.63 96.63,45.63 96.5,45.76 96.5,46.02 96.63,46.14 96.91,46.14 97.03,46.27 97.03,46.52 96.91,46.65 96.63,46.65 96.5,46.78 96.5,47.03 96.63,47.16 96.91,47.16 97.03,47.29 97.03,47.54 96.91,47.67 96.63,47.67 96.5,47.79 96.5,48.05 96.63,48.17 96.91,48.17 97.03,48.3 97.03,48.56 96.91,48.68 96.63,48.68 96.5,48.81 R248.2
ENET4_RXER: length 67.9
  TOP w0.127: R1292.1 83.09,30.43 v1(82.89,30.63) 82.84,30.69 R2615.1
  BOTTOM w0.127: v1(82.89,30.63) 83.58,31.32 86.78,31.74 89.9,34.85 89.9,35.28 90.01,35.39 90.77,35.39 90.88,35.28 90.88,34.73 90.99,34.62 91.15,34.62 91.26,34.73 91.26,35.28 91.37,35.39 91.53,35.39 91.64,35.28 91.64,34.73 91.75,34.62 91.91,34.62 92.02,34.73 92.02,35.28 92.13,35.39 92.29,35.39 92.4,35.28 92.4,34.68 92.52,34.57 92.67,34.57 92.79,34.68 92.79,35.28 92.9,35.39 93.05,35.39 93.17,35.28 93.17,34.68 93.28,34.57 93.44,34.57 93.55,34.68 93.55,35.28 93.66,35.39 93.77,35.39 93.88,35.5 93.88,35.66 93.77,35.77 90.01,35.77 89.9,35.88 89.9,36.04 90.01,36.15 93.87,36.15 93.99,36.26 93.99,36.42 93.87,36.53 90.01,36.53 89.9,36.64 89.9,38.18 91.4,39.68 92.2,39.68 92.33,39.55 92.33,38.53 92.46,38.41 92.71,38.41 92.84,38.53 92.84,39.55 92.96,39.68 95.05,39.68 95.18,39.55 95.18,39.07 95.3,38.94 95.56,38.94 95.69,39.07 95.69,39.55 95.81,39.68 96.07,39.68 96.19,39.55 96.19,39.07 96.32,38.94 96.57,38.94 96.7,39.07 96.7,39.55 96.83,39.68 97.26,39.68 97.39,39.8 97.39,40.27 97.52,40.39 98.81,40.39 98.94,40.52 98.94,40.78 98.81,40.9 97.52,40.9 97.39,41.03 97.39,41.3 97.52,41.43 98.18,41.43 98.3,41.56 98.3,41.81 98.18,41.94 97.52,41.94 97.39,42.06 97.39,43.89 97.52,44.02 98.1,44.02 98.23,44.15 98.23,44.4 98.1,44.53 97.52,44.53 97.39,44.65 97.39,44.91 97.52,45.03 98.1,45.03 98.23,45.16 98.23,45.42 98.1,45.54 97.52,45.54 97.39,45.67 97.39,45.92 97.52,46.05 98.1,46.05 98.23,46.18 98.23,46.43 98.1,46.56 97.52,46.56 97.39,46.69 97.39,46.94 97.52,47.07 98.1,47.07 98.23,47.19 98.23,47.45 98.1,47.57 97.52,47.57 97.39,47.7 97.39,47.96 97.52,48.08 98.1,48.08 98.23,48.21 98.23,48.46 98.1,48.59 97.52,48.59 97.39,48.72 R252.2
ENET4_RXER_DC: length 81
  TOP w0.127: J134.47 125.11,4.05 123.93,2.87 TP1060.1 v1(123.55,2.11) ; v1(96.75,22.94) 95.48,22.94 94.81,22.27 78.12,22.27 76.49,23.9 76.49,30.61 77.07,31.19 80.89,31.19 R2615.2
  BOTTOM w0.127: v1(96.75,22.94) 96.12,22.94 94.21,21.03 94.21,15.71 102.43,7.5 113.47,7.5 118.85,2.11 v1(123.55,2.11)
ENET4_TX_REF_CLK: length 59.7
  TOP w0.127: R2611.1 96.42,34.11 v1(96.23,33.93) 96.04,33.73 R1293.1
  L3_INT_1 w0.127: v1(96.23,33.93) 95.37,33.06 95,33.06 94.89,33.17 94.89,33.52 94.78,33.63 94.62,33.63 94.51,33.52 94.51,33.17 94.4,33.06 94.24,33.06 94.13,33.17 94.13,33.52 94.01,33.63 93.86,33.63 93.74,33.52 93.74,33.17 93.63,33.06 93.48,33.06 93.36,33.17 93.36,33.52 93.25,33.63 93.09,33.63 92.98,33.52 92.98,33.17 92.87,33.06 92.71,33.06 92.6,33.17 92.6,33.52 92.49,33.63 92.33,33.63 92.22,33.52 92.22,32.19 92.11,32.08 91.95,32.08 91.84,32.19 91.84,33.52 91.73,33.63 91.57,33.63 91.46,33.52 91.46,32.17 91.37,32.08 91.19,32.08 91.08,32.2 91.08,33.52 90.97,33.63 90.81,33.63 90.7,33.52 90.7,32.85 90.59,32.74 90.43,32.74 90.32,32.85 90.32,33.52 90.2,33.63 90.05,33.63 89.93,33.52 89.93,32.55 89.82,32.44 89.67,32.44 89.55,32.55 89.55,33.52 89.44,33.63 89.28,33.63 89.17,33.52 89.17,32.55 89.06,32.44 88.9,32.44 88.79,32.55 88.79,33.52 88.68,33.63 88.52,33.63 88.41,33.52 88.41,32.55 88.3,32.44 88.14,32.44 88.03,32.55 88.03,33.52 87.92,33.63 87.76,33.63 87.65,33.52 87.65,32.55 87.54,32.44 87.38,32.44 87.27,32.55 87.27,33.52 87.16,33.63 87,33.63 86.89,33.52 86.89,32.55 86.78,32.44 86.62,32.44 86.51,32.55 86.51,33.52 86.39,33.63 86.24,33.63 86.12,33.52 86.12,32.98 86.01,32.87 85.86,32.87 85.74,32.98 85.74,33.52 85.63,33.63 85.47,33.63 85.36,33.52 85.36,33.17 85.25,33.06 85.09,33.06 84.98,33.17 84.98,33.52 84.87,33.63 84.71,33.63 84.6,33.52 84.6,33.17 84.4,32.97 82.13,32.97 81.93,33.17 81.93,33.52 81.82,33.63 81.66,33.63 81.55,33.52 81.55,33.17 81.44,33.06 81.28,33.06 81.17,33.17 81.17,33.52 81.06,33.63 80.9,33.63 80.79,33.52 80.79,33.42 80.68,33.31 80.52,33.31 80.07,33.75 v1(80.07,34.05)
  BOTTOM w0.127: v1(80.07,34.05) 79.99,34.14 79.99,34.67 77.07,37.6 77.07,41.73 76.18,42.62 76.18,44.17 75.16,45.19 R244.2
ENET4_TXD0: length 59.8
  TOP w0.127: v1(95.48,37.06) R1295.1 95.87,36.4 95.99,36.53 96.5,36.53 96.63,36.4 R2608.1
  L3_INT_1 w0.127: v1(95.48,37.06) 95.11,37.06 95,37.17 95,38.65 94.89,38.76 94.73,38.76 94.62,38.65 94.62,37.17 94.51,37.06 94.24,37.06 94.11,36.93 94.11,36.68 94.22,36.57 95.37,36.57 95.48,36.46 95.48,36.3 95.37,36.19 94.22,36.19 94.11,36.08 94.11,35.92 94.22,35.81 95.37,35.81 95.48,35.7 95.48,35.54 95.37,35.43 94.22,35.43 94.11,35.31 94.11,35.16 94.22,35.04 95.37,35.04 95.48,34.93 95.48,34.11 95.35,33.99 84.44,33.99 83.8,33.35 82.66,33.35 82.02,33.99 81.29,33.99 81.13,34.15 v1(81.13,34.24)
  BOTTOM w0.127: v1(81.13,34.24) 81.13,37.7 81.01,37.82 78.31,37.82 77.83,38.31 77.83,41.99 77.58,42.24 77.58,42.99 77.69,43.1 78.63,43.1 78.75,43.21 78.75,43.37 78.63,43.48 77.69,43.48 77.58,43.59 77.58,43.75 77.69,43.86 78.63,43.86 78.75,43.98 78.75,44.13 78.63,44.24 77.69,44.24 77.58,44.36 77.58,44.51 77.69,44.63 78.63,44.63 78.75,44.74 78.75,44.9 78.63,45.01 77.69,45.01 77.58,45.12 77.58,46.19 77.69,46.3 79.09,46.3 79.2,46.41 79.2,46.57 79.09,46.68 77.69,46.68 77.58,46.79 77.58,46.95 77.69,47.06 79.09,47.06 79.2,47.17 79.2,47.33 79.09,47.44 77.69,47.44 77.58,47.56 R238.2
ENET4_TXD1: length 60.4
  TOP w0.127: R1296.1 v1(93.07,37.8) R2609.1
  L3_INT_1 w0.127: v1(80.5,34.62) 80.63,34.75 81.36,34.75 81.79,34.32 82.15,34.32 82.73,33.73 83.67,33.73 84.26,34.32 93.61,34.32 93.73,34.45 93.73,34.75 93.62,34.86 92.32,34.86 92.21,34.97 92.21,35.13 92.32,35.24 93.62,35.24 93.73,35.35 93.73,35.51 93.62,35.62 92.32,35.62 92.21,35.73 92.21,35.89 92.32,36 93.62,36 93.73,36.11 93.73,36.27 93.62,36.38 92.27,36.38 92.16,36.49 92.16,36.65 92.27,36.76 93.62,36.76 93.73,36.87 93.73,37.09 93.61,37.21 93.2,37.21 93.07,37.34 v1(93.07,37.8)
  BOTTOM w0.127: R240.2 76.56,47.39 76.67,47.28 77.14,47.28 77.25,47.17 77.25,47.01 77.14,46.9 75.65,46.9 75.57,46.81 75.57,46.59 75.64,46.52 77.14,46.52 77.25,46.41 77.25,46.25 77.14,46.14 75.73,46.14 75.64,46.04 75.64,45.86 75.74,45.76 77.14,45.76 77.25,45.64 77.25,45.49 77.14,45.37 76.67,45.37 76.56,45.26 76.56,45.1 76.67,44.99 77.14,44.99 77.25,44.88 77.25,44.72 77.14,44.61 76.67,44.61 76.56,44.5 76.56,44.34 76.67,44.23 77.14,44.23 77.25,44.12 77.25,43.96 77.14,43.85 76.67,43.85 76.56,43.74 76.56,43.58 76.67,43.47 77.14,43.47 77.25,43.36 77.25,43.2 77.14,43.09 76.67,43.09 76.56,42.98 76.56,42.75 77.45,41.86 77.45,37.67 78.45,36.67 78.61,36.67 79.37,37.42 79.53,37.42 79.64,37.31 79.64,37.15 78.88,36.4 78.88,36.24 78.99,36.13 79.15,36.13 79.91,36.89 80.07,36.89 80.18,36.77 80.18,36.62 79.42,35.86 79.42,35.7 79.53,35.59 79.69,35.59 80.45,36.35 80.6,36.35 80.72,36.23 80.72,36.08 79.96,35.32 79.96,35.16 v1(80.5,34.62)
ENET4_TXEN: length 62.4
  TOP w0.127: v1(88.5,35.64) 89.01,36.15 89.01,37.03 89.13,37.16 R1294.1 89.52,37.8 90.02,38.31 R2610.1
  L3_INT_1 w0.127: v1(88.5,35.64) 91.57,35.64 91.7,35.51 91.7,34.85 91.57,34.72 84.1,34.72 83.98,34.85 83.98,35.11 83.85,35.23 83.6,35.23 83.47,35.11 83.47,34.85 83.34,34.72 81.87,34.72 81.46,35.13 80.15,35.13 v1(79.5,34.48)
  BOTTOM w0.127: v1(79.5,34.48) 79.26,34.24 78.8,34.24 78.38,34.66 78.38,35.65 78.27,35.77 78.11,35.77 78,35.65 78,34.59 77.89,34.48 77.73,34.48 77.62,34.59 77.62,35.65 77.51,35.77 77.35,35.77 77.24,35.65 77.24,34.59 77.13,34.48 76.82,34.48 76.69,34.61 76.69,35.05 76.58,35.17 76.06,35.17 75.95,35.28 75.95,35.44 76.06,35.55 76.58,35.55 76.69,35.66 76.69,35.82 76.58,35.93 76.06,35.93 75.95,36.04 75.95,36.2 76.06,36.31 76.58,36.31 76.69,36.42 76.69,36.58 76.58,36.69 76.06,36.69 75.95,36.8 75.95,36.96 76.06,37.07 76.58,37.07 76.69,37.18 76.69,37.34 76.58,37.45 76.06,37.45 75.95,37.56 75.95,37.72 76.06,37.83 76.58,37.83 76.69,37.94 76.69,41.61 75.72,42.57 73.77,42.57 73.64,42.7 73.64,43.01 73.75,43.12 75.59,43.12 75.7,43.23 75.7,43.39 75.59,43.5 73.75,43.5 73.64,43.61 73.64,43.77 73.75,43.88 75.59,43.88 75.7,43.99 75.7,44.15 75.59,44.26 73.75,44.26 73.64,44.38 73.64,44.68 73.75,44.8 74.3,44.8 74.41,44.91 74.41,45.07 74.3,45.18 73.75,45.18 73.64,45.29 73.64,45.45 73.75,45.56 74.3,45.56 74.41,45.67 74.41,45.83 74.3,45.94 73.75,45.94 73.64,46.05 73.64,46.21 73.75,46.32 74.29,46.32 74.4,46.43 74.4,46.59 74.29,46.7 73.75,46.7 73.64,46.81 73.64,46.97 73.75,47.08 74.29,47.08 74.4,47.19 74.4,47.35 74.29,47.46 73.75,47.46 73.64,47.57 R242.2
ENET4_TXER: length 99.1
  TOP w0.127: J134.55 127.11,3.76 128.63,2.24 TP1062.1 v1(129.39,1.98) ; v1(94.72,20.78) 93.94,19.99 87.73,19.99 86.98,20.74 77.31,20.74 71.99,26.06 71.99,28.12 66.78,33.33 66.78,37.66 R2620.2
  BOTTOM w0.127: v1(129.39,1.98) 127.11,1.98 126.47,2.62 125,2.62 124.88,2.75 124.88,3.25 124.75,3.38 124.5,3.38 124.37,3.25 124.37,2.75 124.24,2.62 123.99,2.62 123.86,2.75 123.86,3.25 123.73,3.38 123.48,3.38 123.35,3.25 123.35,2.75 123.23,2.62 122.97,2.62 122.85,2.75 122.85,3.25 122.72,3.38 122.46,3.38 122.34,3.25 122.34,2.75 122.21,2.62 121.96,2.62 121.83,2.75 121.83,3.25 121.7,3.38 121.45,3.38 121.32,3.25 121.32,2.75 121.19,2.62 120.94,2.62 120.81,2.75 120.81,3.25 120.69,3.38 120.43,3.38 120.31,3.25 120.31,2.75 120.18,2.62 119.92,2.62 119.8,2.75 119.8,3.25 119.67,3.38 119.42,3.38 119.29,3.25 119.29,2.75 119.16,2.62 118.85,2.62 113.6,7.88 102.71,7.88 94.72,15.87 v1(94.72,20.78)
ENET_INH: length 2.6
  TOP w0.127: J134.49 125.61,3.66 R283.2
ENET_INH_B: length 3.5
  TOP w0.127: R280.2 122.92,3 124.11,4.19 J134.43
ENET_REF_CLK: length 5.2
  TOP w0.127: J134.4 114.1,12.57 113.77,12.91 112.88,12.91 TP1055.1
ETH2_CLK125_OUT: length 3.4
  TOP w0.127: TP25.1 28.56,67.52 27.67,66.63 R519.2
EWM_OUT_B: length 182.7
  TOP w0.127: v1(15.22,38.05) 15.09,37.92 C15.1 ; v1(100.69,87.79) 100.84,87.94 100.84,89.67 101.07,89.89 101.07,91.13 101.2,91.26 R115.2 ; U361.9 39.89,39.16 v1(40.37,38.69) C569.1 41.13,37.93 R2101.2
  L3_INT_1 w0.127: v1(40.37,38.69) 37.83,36.15 37.83,32.72 37.06,31.96 26.01,31.96 25.38,32.59 20.68,32.59 v1(15.22,38.05) 19.92,42.75 19.92,90.25 21.95,92.28 28.04,92.28 28.92,91.39 29.32,91.39 29.44,91.52 43.92,91.52 46.46,88.98 53.83,88.98 56.19,86.62 85.78,86.62 87.56,84.84 94.01,84.84 98.28,89.11 100.31,89.11 100.82,88.6 100.82,87.91 v1(100.69,87.79)
FDC_ECC: length 3.3
  TOP w0.305: TP50.1 173.86,105.6 J71.2
FLASH_RST: length 144.8
  TOP w0.127: U361.13 v1(40.24,41.77) 40.72,42.24 C573.1 41.13,41.49 R2104.2 ; v1(133.97,62.94) 133.97,62.81 R2158.2
  L3_INT_1 w0.127: v1(133.97,62.94) 133.58,63.32 131.55,63.32 131.3,63.07 131.3,60.02 128.89,57.61 128.89,55.83 128.12,55.07 128.12,44.02 121.52,37.42 121.52,36.65 117.33,32.46 114.87,32.46 112.25,29.85 106.53,29.85 102.47,25.78 102.47,20.53 101.2,19.26 92.96,19.26 91.56,20.65 89.06,20.65 88.17,21.54 85.45,21.54 85.2,21.29 77.32,21.29 76.43,22.18 68.56,22.18 67.93,21.54 58.27,21.54 56.24,23.57 52.18,23.57 51.42,24.34 49.38,24.34 47.35,26.37 46.21,26.37 v1(41.89,30.69)
  BOTTOM w0.127: v1(41.89,30.69) 41.89,39.07 41.26,39.7 41.26,40.75 v1(40.24,41.77)
FLASH_VCC: length 245.3
  TOP w0.305: U6.H12 v2(103.49,71.64) U6.H13 v1(104.29,71.64) ; v1(178.67,93.56) R1091.1 ; U11.E4 v1(108.02,114.74) ; R290.1 v1(106.53,123.66) ; J71.28 v1(189.06,105.23) 189.06,106.36 C472.1 ; R291.1 v1(105.38,123.9) ; R2696.1 23.47,75.76 23.97,76.26 U417.5 23.97,77.03 23.98,77.04 C909.1 v1(23.23,77.56) ; v1(103.9,116.91) 104.02,116.79 104.02,114.74 U11.B4 ; v1(189.06,96.19) J71.27 ; J71.4 v1(174.66,105.11) 174.66,106.31 C473.1 ; R2697.1 v1(37.7,89.49) ; v2(101.89,73.24) U6.F10 v1(101.09,73.24) U6.F9 ; U11.D1 v1(106.02,111.74) ; R2103.1 v1(34.4,31.07) ; R292.1 v1(107.17,120.47) ; v1(100.79,113.62) 100.67,113.49 TP102.1 ; U11.C5 v1(106.02,115.74) ; J71.3 v1(174.66,95.91) ; v1(174.5,94.19) R1093.1
  TOP w0.381: R20.2 126.14,59.89 ; R20.2 125.71,60.3 ; R20.2 125.28,59.89 ; L2.2 124.19,60.27 ; L2.2 124.62,59.86 ; L2.2 123.75,59.86 ; 124.94,61.04 C399.1 124.19,60.42 ; v1(103.9,116.91) C102.1 ; R266.1 v1(150.98,67.24) ; R270.1 v1(148.69,64.72) ; v1(150.86,65.23) 151.12,65.49 R264.1
  L3_INT_1 w0.305: v1(37.7,89.49) 36.56,90.63 29.83,90.63 27.79,88.6 26.27,88.6 24.62,86.95 24.62,84.91 23.23,83.52 v1(23.23,77.56) 21.57,75.9 21.57,68.4 23.73,66.25 23.73,61.29 22.71,60.28 22.71,42.37 v1(25.63,39.45) ; v1(122.49,62.77) 122.49,62.26 123.09,61.65 123.09,59.18 122.41,58.5 122.41,54.82 121.52,53.93 121.52,44.15 117.84,40.46 116.95,40.46 109.46,32.97 106.28,32.97 97.82,24.51 90.52,24.51 90.15,24.88 85.29,24.88 84.99,25.17 81.82,25.17 80.93,26.06 77.25,26.06 76.43,26.88 69.45,26.88 67.93,25.35 55.35,25.35 53.47,27.23 48.52,27.23 41.38,34.37 39.1,34.37 38.33,33.61 38.33,31.83 37.57,31.07 v1(34.4,31.07)
  BOTTOM w0.305: U12.8 100.57,124.41 C104.1 C103.1 v1(100.55,123.42) ; v1(25.63,39.45) 25.63,38.56 33.13,31.07 v1(34.4,31.07) ; v1(108.02,114.74) 108.3,115.02 C101.1 ; R294.1 v1(102.98,117.17) ; R289.1 100.69,113.52 v1(100.79,113.62) R287.1 ; C471.1 189.08,96.21 v1(189.06,96.19)
  BOTTOM w0.381: R288.1 v1(105.38,108.67)
  vias: v1(125.2,61.17) v1(125.58,60.66) v1(125.96,61.17) v1(154.79,64.09) v1(154.79,63.45) v1(154.79,62.82)
FLEXSPI1_A_CLK: length 43.3
  TOP w0.127: U69.7 103.35,105.37 103.61,105.11 103.61,104.85 103.42,104.66 103.1,104.66 102.98,104.54 102.98,104 103.1,103.88 104.88,103.88 105.01,103.75 105.01,103.49 104.88,103.37 103.1,103.37 102.98,103.24 102.98,102.99 103.1,102.86 104.88,102.86 105.01,102.73 TP67.1 105.01,101.17 103.88,100.04 103.88,97.44 103.75,97.31 102.19,97.31 102.06,97.18 102.06,96.93 102.19,96.8 104.08,96.8 104.21,96.67 104.21,96.42 104.08,96.29 102.95,96.29 102.83,96.17 102.83,95.91 102.95,95.78 103.28,95.78 103.41,95.66 103.41,88.77 99.17,84.53 99.17,81.87 99.09,81.79 U6.A7
FLEXSPI1_A_CLK_4: length 25.7
  TOP w0.127: v1(99.93,106.25) 100.32,105.87 U69.2
  L3_INT_1 w0.127: v1(100.69,121.87) 101.83,120.73 101.83,120.05 101.71,119.93 101.07,119.93 100.95,119.8 100.95,119.54 101.07,119.42 101.71,119.42 101.83,119.29 101.83,119.04 101.71,118.91 101.07,118.91 100.95,118.78 100.95,118.53 101.07,118.4 101.71,118.4 101.83,118.27 101.83,118.02 101.71,117.89 101.07,117.89 100.95,117.77 100.95,117.51 101.07,117.39 101.71,117.39 101.83,117.26 101.83,117 101.71,116.88 101.07,116.88 100.95,116.75 100.95,116.5 101.07,116.37 101.71,116.37 101.83,116.24 101.83,111.2 99.8,109.17 99.8,106.38 v1(99.93,106.25)
  BOTTOM w0.127: U12.6 v1(100.69,121.87)
FLEXSPI1_A_CLK_8: length 13.5
  TOP w0.127: U69.4 99.85,104.87 v1(99.8,104.82)
  BOTTOM w0.127: R297.1 102.85,109.48 102.85,108.03 102.62,107.8 101.94,107.8 101.71,108.03 101.71,108.2 101.58,108.34 101.33,108.34 101.2,108.21 101.2,106.63 101.33,106.5 102.04,106.5 102.17,106.37 102.17,106.12 102.04,105.99 101.33,105.99 101.2,105.86 101.2,105.51 101.33,105.39 101.96,105.39 102.09,105.26 102.09,104.98 101.97,104.87 99.85,104.87 v1(99.8,104.82)
FLEXSPI1_A_D0: length 43.9
  TOP w0.127: U6.A10 101.49,82.67 101.83,83.01 101.83,84.53 105.01,87.71 105.01,91.26 108.87,95.12 110.17,95.12 111.11,96.06 111.11,97.06 111.23,97.19 112.88,97.19 113.01,97.32 113.01,97.57 112.88,97.7 111.23,97.7 111.11,97.82 111.11,98.08 111.23,98.21 112.88,98.21 113.01,98.33 113.01,98.59 112.88,98.71 111.23,98.71 111.11,98.84 TP69.1 112.96,99.65 113.21,99.9 113.21,105.21 112.56,105.87 U70.8
FLEXSPI1_A_D0_4: length 25.5
  TOP w0.127: U70.1 v1(109.51,106.37)
  L3_INT_1 w0.127: v1(109.51,106.37) 109.51,117.12 109.26,117.37 109.08,117.37 108.69,116.98 108.51,116.98 108.33,117.16 108.33,117.34 108.72,117.73 108.72,117.91 108.54,118.09 108.36,118.09 107.97,117.7 107.79,117.7 107.61,117.88 107.61,118.06 108,118.45 108,118.63 107.82,118.81 107.64,118.81 107.25,118.42 107.07,118.42 106.89,118.6 106.89,118.78 107.28,119.17 107.28,119.35 107.1,119.53 106.92,119.53 106.53,119.13 106.35,119.13 106.17,119.31 106.17,119.49 106.56,119.89 106.56,120.07 v1(106.03,120.6)
  BOTTOM w0.127: U12.5 v1(106.03,120.6)
FLEXSPI1_A_D0_8: length 11.9
  TOP w0.127: U70.3 v1(109.51,105.37) ; U11.D3 v1(106.02,112.74)
  BOTTOM w0.127: v1(109.51,105.37) 106.78,105.37 106.53,105.62 106.53,112.22 v1(106.02,112.74)
FLEXSPI1_A_D1: length 44.4
  TOP w0.127: U70.7 112.63,105.37 112.91,105.08 112.91,104.37 112.76,104.22 111.99,104.22 111.87,104.09 111.87,103.84 111.99,103.71 112.76,103.71 112.88,103.58 112.88,103.46 112.44,103.01 112.26,103.01 111.87,103.41 111.69,103.41 111.51,103.23 111.51,103.05 111.9,102.65 111.9,101.81 111.77,101.68 TP70.1 110.37,101.68 110.22,101.53 110.22,101.03 110.34,100.9 112.15,100.9 112.27,100.77 112.27,100.52 112.15,100.39 110.34,100.39 110.22,100.26 110.22,97.68 108.76,96.22 107.17,96.22 105.14,94.19 105.14,92.36 104.37,91.6 104.37,88.22 100.29,84.13 100.29,76.44 U6.B9
FLEXSPI1_A_D1_4: length 26
  TOP w0.127: U70.2 v1(109,105.87)
  L3_INT_1 w0.127: v1(109,105.87) 109.83,105.87 110.22,106.25 110.22,117.89 110.09,118.02 109.58,118.02 109.45,118.14 109.45,118.4 109.58,118.53 110.09,118.53 110.22,118.65 110.22,118.91 110.09,119.03 109.45,119.03 109.33,119.16 109.33,119.41 109.45,119.54 110.09,119.54 110.22,119.67 110.22,119.92 110.09,120.05 109.45,120.05 109.33,120.18 109.33,120.43 109.45,120.56 110.09,120.56 110.22,120.68 110.22,121.11 110.09,121.24 109.71,121.24 v1(108.18,122.76)
  BOTTOM w0.127: U12.2 108.57,123.14 v1(108.18,122.76)
FLEXSPI1_A_D1_8: length 12.1
  TOP w0.127: U70.4 v1(109,104.87) ; U11.D2 v1(107.03,111.73)
  BOTTOM w0.127: v1(107.03,111.73) 107.03,107.79 107.8,107.01 109.6,107.01 110.09,106.53 110.09,105.11 109.85,104.87 v1(109,104.87)
FLEXSPI1_A_D2: length 43.3
  TOP w0.127: U6.A8 99.89,84.24 104.02,88.37 104.02,91.69 104.76,92.43 104.76,94.44 107.68,97.36 107.68,98.12 107.96,98.41 108.26,98.41 108.39,98.53 108.39,98.76 108.26,98.88 107.92,98.88 107.79,99.01 107.79,99.2 108.18,99.6 108.18,100.66 109.07,101.55 TP71.1 108.44,102.31 108.44,102.47 108.57,102.59 110.72,102.59 110.85,102.72 110.85,102.97 110.72,103.1 108.57,103.1 108.44,103.23 108.44,103.48 108.57,103.61 110.09,103.61 110.22,103.74 110.22,103.99 110.09,104.12 108.57,104.12 108.44,104.24 108.44,105.54 108.31,105.67 107.61,105.67 107.41,105.87 U71.8
FLEXSPI1_A_D2_4: length 26.1
  TOP w0.127: v1(104.58,106.42) 104.63,106.37 U71.1 ; v1(108.06,121.87) 107.93,121.87 107.92,121.87 R292.2
  L3_INT_1 w0.127: v1(104.58,106.42) 104.5,106.5 104.5,114.88 105.01,115.39 105.01,118.26 105.14,118.38 105.52,118.38 105.64,118.51 105.64,118.76 105.52,118.89 105.14,118.89 105.01,119.02 105.01,119.27 105.14,119.4 105.52,119.4 105.64,119.53 105.64,119.78 105.52,119.91 105.14,119.91 105.01,120.03 105.01,121.49 105.39,121.87 105.92,121.87 106.05,122 106.05,122.51 106.17,122.63 106.43,122.63 106.56,122.51 106.56,122 106.68,121.87 106.94,121.87 107.06,122 107.06,122.51 107.19,122.63 107.44,122.63 107.57,122.51 107.57,122 107.7,121.87 v1(108.06,121.87)
  BOTTOM w0.127: v1(108.06,121.87) U12.3
FLEXSPI1_A_D2_8: length 12
  TOP w0.127: U11.C4 v1(105.02,114.74) ; v1(104.58,105.29) 104.66,105.37 U71.3
  BOTTOM w0.127: v1(105.02,114.74) 104.63,114.35 104.63,110.7 104.01,110.07 104.01,108.14 105.14,107.01 105.14,105.84 v1(104.58,105.29)
FLEXSPI1_A_D3: length 44.1
  TOP w0.127: U71.7 107.42,105.37 108.06,104.73 108.06,104.06 107.93,103.93 107.36,103.93 107.24,103.81 107.24,103.55 107.36,103.43 107.93,103.43 108.06,103.3 108.06,103.04 107.93,102.92 105.77,102.92 105.64,102.79 105.64,102.54 105.77,102.41 107.93,102.41 108.06,102.28 108.06,101.93 107.8,101.68 TP72.1 105.91,100.55 105.91,97.22 106.29,96.84 106.29,96.66 106.12,96.49 105.94,96.49 105.58,96.86 105.4,96.86 105.22,96.68 105.22,96.5 105.58,96.13 105.58,95.95 105.4,95.77 105.23,95.77 104.86,96.14 104.68,96.14 104.5,95.96 104.5,95.78 104.87,95.42 104.87,95.24 104.69,95.06 104.51,95.06 104.14,95.42 103.96,95.42 103.71,95.17 103.71,88.57 99.49,84.35 99.49,76.44 U6.B8
FLEXSPI1_A_D3_4: length 25.6
  TOP w0.127: U71.2 104.15,105.87 v1(104.12,105.84) ; R291.2 v1(103.99,123.14)
  L3_INT_1 w0.127: v1(104.12,105.84) 104.1,105.87 104.1,111.86 103.55,112.41 103.55,114.82 104.5,115.78 104.5,118.29 104.37,118.41 103.99,118.41 103.87,118.54 103.87,118.8 103.99,118.92 104.37,118.92 104.5,119.05 104.5,119.3 104.37,119.43 103.99,119.43 103.87,119.56 103.87,119.81 103.99,119.94 104.37,119.94 104.5,120.07 104.5,120.32 104.37,120.45 103.99,120.45 103.87,120.57 103.87,120.83 103.99,120.95 104.37,120.95 104.5,121.08 104.5,121.34 104.37,121.46 103.99,121.46 103.87,121.59 103.87,121.84 103.99,121.97 104.37,121.97 104.5,122.1 104.5,122.63 v1(103.99,123.14)
  BOTTOM w0.127: v1(103.99,123.14) U12.7
FLEXSPI1_A_D3_8: length 12
  TOP w0.127: U71.4 104.89,104.87 v1(104.58,104.56) ; U11.D4 v1(106.03,113.74)
  BOTTOM w0.127: v1(104.58,104.56) 104.97,104.56 105.52,105.11 105.52,107.42 105.85,107.76 105.85,109.98 105.39,110.44 105.39,113.11 v1(106.03,113.74)
FLEXSPI1_A_D4: length 22.9
  TOP w0.127: R117.2 TP73.1 107.04,100.28 v1(107.68,100.92) ; v1(107.02,114.74) U11.D5
  BOTTOM w0.127: v1(107.68,100.92) 108.31,100.92 108.77,101.37 110.02,101.37 110.34,101.04 110.85,101.04 111.49,101.68 111.49,102.44 111.23,102.69 111.23,102.95 111.49,103.2 111.49,106.63 111.61,106.76 111.61,108.28 107.55,112.35 107.55,114.2 v1(107.02,114.74)
FLEXSPI1_A_D5: length 23.5
  TOP w0.127: U11.E3 v1(107.03,113.73) ; R119.2 TP74.1 105.01,100.41 v1(105.64,101.04)
  BOTTOM w0.127: v1(107.03,113.73) 107.03,112.39 110.47,108.95 110.47,107.06 110.98,106.56 110.98,104.38 110.51,103.91 110.51,102.31 110.13,101.93 109.72,101.93 109.59,102.06 109.59,102.31 109.47,102.44 109.21,102.44 109.09,102.31 109.09,102.06 108.96,101.93 108.71,101.93 108.58,102.06 108.58,102.31 108.45,102.44 108.2,102.44 108.07,102.31 108.07,102.06 107.94,101.93 107.8,101.93 106.91,101.04 v1(105.64,101.04)
FLEXSPI1_A_D6: length 26.6
  TOP w0.127: R121.2 TP75.1 v1(109.07,100.54) ; U11.E2 v1(108.1,112.82)
  BOTTOM w0.127: v1(109.07,100.54) 111.23,100.54 111.87,101.17 111.87,106.38 111.99,106.5 111.99,109.55 110.68,110.87 110.68,111.05 111.14,111.5 111.14,111.68 110.96,111.86 110.78,111.86 110.32,111.41 110.14,111.41 109.84,111.71 109.84,114.12 109.71,114.25 109.32,114.25 109.2,114.12 109.2,113.11 109.07,112.98 108.82,112.98 108.69,113.11 108.69,114.12 108.56,114.25 108.18,114.25 108.06,114.12 108.06,112.85 v1(108.1,112.82)
FLEXSPI1_A_D7: length 26.4
  TOP w0.127: v1(104.12,101.04) 102.98,99.9 TP76.1 R123.2 ; U11.E1 v1(107.52,110.44)
  BOTTOM w0.127: v1(104.12,101.04) 103.87,101.3 103.87,103.2 103.99,103.33 104.4,103.33 104.53,103.2 104.53,102.82 104.66,102.69 104.91,102.69 105.04,102.82 105.04,103.2 105.16,103.33 105.42,103.33 105.55,103.2 105.55,102.82 105.67,102.69 105.93,102.69 106.05,102.82 106.05,103.2 106.18,103.33 108.82,103.33 110.47,104.98 110.47,106.63 110.09,107.01 110.09,108.54 109.62,109 109.44,109 108.8,108.36 108.62,108.36 108.44,108.54 108.44,108.72 109.08,109.36 109.08,109.54 108.9,109.72 108.72,109.72 108.08,109.08 107.9,109.08 107.72,109.26 107.72,109.44 108.37,110.08 108.37,110.26 108.18,110.44 v1(107.52,110.44)
FLEXSPI1_A_DQS: length 43
  TOP w0.127: U6.A6 98.29,82.11 98.15,82.25 98.15,84.03 103.1,88.98 103.1,93.48 101.71,94.87 101.71,95.97 101.58,96.1 100.92,96.1 100.79,96.23 100.79,96.48 100.92,96.61 101.58,96.61 101.71,96.73 101.71,97.14 101.58,97.26 100.18,97.26 100.06,97.39 100.06,97.64 100.18,97.77 101.58,97.77 101.71,97.9 101.71,98.15 101.58,98.28 100.18,98.28 100.06,98.41 100.06,98.66 100.18,98.79 101.58,98.79 101.71,98.91 101.71,99.17 101.58,99.3 100.18,99.3 100.06,99.42 100.06,99.68 100.18,99.8 101.73,99.8 101.86,99.93 101.86,100.11 101.66,100.31 101.25,100.31 101.12,100.44 101.12,100.69 101.25,100.82 102.75,100.82 102.98,101.04 TP68.1 R298.1
FLEXSPI1_A_SS0: length 42.7
  TOP w0.127: v1(109.96,95.84) 107.63,95.84 105.64,93.85 105.64,92.43 104.68,91.47 104.68,88.01 101.33,84.66 101.33,83.01 101.1,82.78 101.1,74.83 U6.D10 ; U69.8 v1(103.15,105.87)
  BOTTOM w0.127: v1(109.96,95.84) 110.22,96.09 110.22,98 107.8,100.41 104.12,100.41 102.98,101.55 102.98,105.69 v1(103.15,105.87)
FLEXSPI1_A_SS0_4: length 26.2
  TOP w0.127: R290.2 108.05,124.41 v1(108.06,124.41) ; U69.1 100.58,106.37 100.32,106.63 v1(100.32,107.01)
  L3_INT_1 w0.127: v1(100.32,107.01) 100.32,109.05 102.22,110.95 102.22,122.25 104.37,124.41 v1(108.06,124.41)
  BOTTOM w0.127: U12.1 v1(108.06,124.41)
FLEXSPI1_A_SS0_8: length 6
  TOP w0.127: U69.3 v1(100.26,105.37)
  BOTTOM w0.127: v1(100.26,105.37) 100.82,105.92 100.82,108.4 101.05,108.64 R296.1 101.05,109.54 R312.1
FLEXSPI1_B_CLK: length 53.6
  TOP w0.127: U66.7 145.14,74.25 144.76,74.63 v1(144.76,75.26) ; U6.E14 v1(105.09,74.04)
  BOTTOM w0.127: v1(105.09,74.04) 105.57,73.56 109.3,73.56 114.31,78.56 119.19,78.56 119.32,78.44 119.32,77.98 119.45,77.85 119.7,77.85 119.83,77.98 119.83,78.44 119.95,78.56 120.21,78.56 120.34,78.44 120.34,77.98 120.46,77.85 120.72,77.85 120.84,77.98 120.84,78.44 120.97,78.56 121.22,78.56 121.35,78.44 121.35,77.98 121.48,77.85 121.73,77.85 121.86,77.98 121.86,78.44 121.99,78.56 122.24,78.56 122.37,78.44 122.37,77.98 122.49,77.85 122.75,77.85 122.88,77.98 122.88,78.44 123,78.56 123.26,78.56 123.38,78.44 123.38,77.98 123.51,77.85 123.76,77.85 123.89,77.98 123.89,78.44 124.02,78.56 124.27,78.56 124.4,78.44 124.4,77.98 124.53,77.85 124.78,77.85 124.91,77.98 124.91,78.44 125.03,78.56 128.81,78.56 128.93,78.44 128.93,78.06 129.06,77.93 129.31,77.93 129.44,78.06 129.44,78.44 129.57,78.56 137.55,78.56 140.47,75.64 144.38,75.64 v1(144.76,75.26)
FLEXSPI1_B_CLK_4: length 11.8
  TOP w0.127: v1(148.82,67.01) 148.44,67.39 148.44,68.02 147.58,68.89 146.82,68.89 144.64,71.07 U66.2
  BOTTOM w0.127: v1(148.82,67.01) 150.43,67.01 150.93,66.5 U10.6
FLEXSPI1_B_CLK_8: length 67
  TOP w0.127: v1(146.27,71.42) 145.81,71.42 145.64,71.59 U66.4 ; J71.6 176.26,101.67 175.63,101.04 175.63,100.02 176.26,99.39 J71.5 176.26,93.37 177.65,91.98 177.65,89.23 180.57,86.31 v1(182.47,86.31)
  BOTTOM w0.127: v1(182.47,86.31) 182.47,84.6 168,70.13 150.02,70.13 148.73,71.42 v1(146.27,71.42)
FLEXSPI1_B_D0: length 54.3
  TOP w0.127: U67.8 149.59,75.39 v1(149.59,75.39) ; U6.F14 v1(105.09,73.24)
  BOTTOM w0.127: v1(149.59,75.39) 145.52,75.39 144.93,74.79 144.47,74.79 144,75.26 140.31,75.26 138.11,77.47 130.79,77.47 130.67,77.6 130.67,77.96 130.54,78.08 130.29,78.08 130.16,77.96 130.16,77.6 130.03,77.47 128.38,77.47 128.25,77.6 128.25,77.93 128.13,78.06 127.87,78.06 127.74,77.93 127.74,77.6 127.62,77.47 127.36,77.47 127.24,77.6 127.24,77.93 127.11,78.06 126.86,78.06 126.73,77.93 126.73,77.6 126.6,77.47 126.35,77.47 126.22,77.6 126.22,77.93 126.09,78.06 125.84,78.06 125.71,77.93 125.71,77.6 125.59,77.47 119.18,77.47 118.45,78.21 114.53,78.21 109.56,73.24 v1(105.09,73.24)
FLEXSPI1_B_D0_4: length 11.8
  TOP w0.127: v1(149.09,67.77) 149.09,69.7 148.97,69.82 148.22,69.82 148.09,69.95 148.09,70.21 148.22,70.33 148.97,70.33 149.09,70.46 149.09,70.71 148.97,70.84 148.22,70.84 148.09,70.97 148.09,71.22 148.22,71.35 148.96,71.35 149.09,71.48 U67.1
  BOTTOM w0.127: U10.5 v1(149.09,67.77)
FLEXSPI1_B_D0_8: length 66.7
  TOP w0.127: v1(182.21,87.34) 182.17,87.3 180.68,87.3 180.55,87.43 180.55,87.67 180.68,87.8 181.06,87.8 181.18,87.93 181.18,88.18 181.06,88.31 180.68,88.31 180.55,88.43 180.55,88.7 180.42,88.83 180.04,88.83 179.89,88.98 179.89,89.24 180.02,89.36 180.32,89.36 180.45,89.49 180.45,89.75 180.32,89.87 180.02,89.87 179.89,90 179.89,90.35 180.02,90.47 180.6,90.47 180.73,90.6 180.73,90.86 180.6,90.98 180.02,90.98 179.89,91.11 179.89,91.36 180.02,91.49 180.6,91.49 180.73,91.62 180.73,91.87 180.6,92 180.02,92 179.89,92.13 179.89,92.38 180.02,92.51 180.6,92.51 180.73,92.63 180.73,92.89 180.6,93.01 180.02,93.01 179.89,93.14 179.89,93.53 180.02,93.66 181.84,93.66 182,93.81 182,94.04 181.87,94.17 180.02,94.17 179.89,94.29 179.89,94.77 180.02,94.9 180.79,94.9 181.16,94.52 181.34,94.52 181.52,94.7 181.52,94.88 180.85,95.55 180.85,95.73 181.06,95.94 J71.13 ; U67.3 150.09,70.83 v1(150.07,70.81)
  BOTTOM w0.127: v1(150.07,70.81) 150.34,70.54 167.95,70.54 182,84.58 182,87.1 182.21,87.31 v1(182.21,87.34)
FLEXSPI1_B_D1: length 53.8
  TOP w0.127: v1(141.04,74.4) 140.33,75.11 140.33,77.09 140.18,77.24 139.95,77.24 139.82,77.12 139.82,76.56 139.7,76.43 139.37,76.43 139.24,76.56 139.24,77.4 139.11,77.52 138.86,77.52 138.73,77.4 138.73,76.56 138.61,76.43 138.35,76.43 138.23,76.56 138.23,77.4 138.1,77.52 137.84,77.52 137.72,77.4 137.72,76.56 137.59,76.43 116.62,76.43 116.08,75.9 114.28,75.9 111.61,73.23 106.69,73.23 U6.F16 ; U67.7 150.09,74.48 v1(150.1,74.49)
  BOTTOM w0.127: v1(150.1,74.49) 148.81,74.49 148.67,74.63 146.03,74.63 145.35,73.94 144.05,73.94 143.39,74.6 141.24,74.6 v1(141.04,74.4)
FLEXSPI1_B_D1_4: length 12.1
  TOP w0.127: v1(149.59,65.23) 149.59,65.23 U67.2
  BOTTOM w0.127: U10.2 147.14,65.23 147.27,65.36 147.27,65.66 147.39,65.79 147.65,65.79 147.77,65.66 147.77,65.36 147.9,65.23 148.15,65.23 148.28,65.36 148.28,65.66 148.41,65.79 148.66,65.79 148.79,65.66 148.79,65.36 148.92,65.23 v1(149.59,65.23)
FLEXSPI1_B_D1_8: length 66.9
  TOP w0.127: v1(182.1,88.09) 181.84,88.09 180.75,89.18 180.75,89.84 181.21,90.3 181.21,92.33 182.48,93.6 182.48,99.01 181.59,99.9 181.59,101.02 181.06,101.55 J71.14 ; v1(150.6,71.28) 150.59,71.29 U67.4
  BOTTOM w0.127: v1(182.1,88.09) 181.69,87.68 181.69,84.79 167.85,70.95 155.92,70.95 155.8,71.08 155.8,71.63 155.67,71.76 155.42,71.76 155.29,71.63 155.29,71.08 155.16,70.95 154.91,70.95 154.78,71.08 154.78,72.06 154.63,72.21 154.4,72.21 154.27,72.09 154.27,71.08 154.15,70.95 153.89,70.95 153.76,71.08 153.76,71.76 153.64,71.88 153.38,71.88 153.26,71.76 153.26,71.08 153.13,70.95 152.88,70.95 152.75,71.08 152.75,71.76 152.6,71.91 152.37,71.91 152.24,71.78 152.24,71.08 152.11,70.95 151.86,70.95 151.73,71.08 151.73,71.76 151.61,71.88 151.35,71.88 151.22,71.76 151.22,71.08 151.1,70.95 150.93,70.95 v1(150.6,71.28)
FLEXSPI1_B_D2: length 55.1
  TOP w0.127: v1(154.31,74.25) 154.54,74.02 U68.8 ; v1(141.84,72.72) 141.84,72.58 141.34,72.09 141.34,71.58 141.22,71.45 140.96,71.45 140.84,71.58 140.84,72.09 140.71,72.21 137.17,72.21 134.45,74.93 117.46,74.93 116.81,74.29 114.83,74.29 112.18,71.64 106.69,71.64 U6.G16
  BOTTOM w0.127: v1(154.31,74.25) 154.31,73.08 153.47,72.24 147.99,72.24 147.63,72.6 144.05,72.6 143.71,72.25 142.94,72.25 142.47,72.72 v1(141.84,72.72)
FLEXSPI1_B_D2_4: length 11.9
  TOP w0.127: v1(150.22,66.5) R266.2 150.22,67.9 150.22,68.43 151.09,69.29 152,69.29 154.04,71.34 U68.1
  BOTTOM w0.127: v1(150.22,66.5) U10.3
FLEXSPI1_B_D2_8: length 67.1
  TOP w0.127: J71.17 183.46,95.7 183.59,95.57 185.27,95.57 185.4,95.44 185.4,95.19 185.27,95.06 183.59,95.06 183.46,94.93 183.46,94.68 183.59,94.55 185.27,94.55 185.4,94.43 185.4,94.17 185.27,94.04 183.59,94.04 183.46,93.92 183.46,93.6 183.59,93.48 184.49,93.48 184.61,93.35 184.61,93.09 184.49,92.97 183.59,92.97 183.46,92.84 183.46,92.12 183.2,91.86 183.02,91.86 182.72,92.16 182.54,92.16 182.36,91.98 182.36,91.8 182.66,91.5 182.66,91.32 182.25,90.91 182.25,89.13 v1(181.97,88.85) ; v1(156.7,71.45) 156.69,71.45 155.18,71.45 155.04,71.58 U68.3
  BOTTOM w0.127: v1(156.7,71.45) 157.36,71.45 157.49,71.58 157.49,72.01 157.62,72.14 157.87,72.14 158,72.01 158,71.58 158.13,71.45 158.38,71.45 158.51,71.58 158.51,72.01 158.63,72.14 158.89,72.14 159.01,72.01 159.01,71.58 159.14,71.45 159.4,71.45 159.52,71.58 159.52,72.01 159.65,72.14 159.9,72.14 160.03,72.01 160.03,71.58 160.16,71.45 160.41,71.45 160.54,71.58 160.54,72.01 160.67,72.14 160.92,72.14 161.05,72.01 161.05,71.58 161.17,71.45 161.43,71.45 161.55,71.58 161.55,72.01 161.68,72.14 161.94,72.14 162.06,72.01 162.06,71.58 162.19,71.45 162.44,71.45 162.57,71.58 162.57,72.01 162.7,72.14 162.95,72.14 163.08,72.01 163.08,71.58 163.21,71.45 163.46,71.45 163.59,71.58 163.59,72.01 163.71,72.14 163.97,72.14 164.09,72.01 164.09,71.58 164.22,71.45 164.48,71.45 164.6,71.58 164.6,72.01 164.73,72.14 164.98,72.14 165.11,72.01 165.11,71.58 165.24,71.45 165.49,71.45 165.62,71.58 165.62,72.01 165.75,72.14 166,72.14 166.13,72.01 166.13,71.58 166.25,71.45 166.51,71.45 166.63,71.58 166.63,72.01 166.76,72.14 167.02,72.14 167.14,72.01 167.14,71.58 167.27,71.45 167.87,71.45 181.34,84.92 181.34,88.22 v1(181.97,88.85)
FLEXSPI1_B_D3: length 53.4
  TOP w0.127: U6.F17 111.73,72.84 114.38,75.49 116.31,75.49 116.87,76.05 138.67,76.05 v1(141.04,73.68) ; v1(155.43,74.25) 155.04,73.86 U68.7
  BOTTOM w0.127: v1(155.43,74.25) 154.67,75.01 151.62,75.01 150.35,73.74 148.82,73.74 148.7,73.61 147.9,73.61 147.26,74.25 146.28,74.25 145.27,73.23 141.49,73.23 v1(141.04,73.68)
FLEXSPI1_B_D3_4: length 11.8
  TOP w0.127: v1(151.87,65.23) R264.2 152.57,65.99 152.69,66.12 152.69,66.6 152.82,66.73 153.07,66.73 153.2,66.6 153.2,66.12 153.33,65.99 154.18,65.99 154.54,66.35 U68.2
  BOTTOM w0.127: U10.7 v1(151.87,65.23)
FLEXSPI1_B_D3_8: length 67.1
  TOP w0.127: v1(156.1,72.02) U68.4 ; v1(181.34,89.49) 181.72,89.87 181.72,91.95 182.86,93.09 182.86,99.14 181.97,100.03 181.97,101.17 182.73,101.93 182.73,105.46 183.19,105.92 183.6,105.92 183.73,106.05 183.73,106.76 183.85,106.89 184.11,106.89 184.23,106.76 184.23,106.05 184.36,105.92 184.61,105.92 184.74,106.05 184.74,106.76 184.87,106.89 185.12,106.89 185.25,106.76 185.25,106.05 185.38,105.92 185.63,105.92 185.76,106.05 185.76,106.76 185.88,106.89 186.14,106.89 186.27,106.76 186.27,106.05 186.39,105.92 186.52,105.92 186.75,105.69 186.75,105.39 186.59,105.23 183.72,105.23 183.46,104.98 J71.18
  BOTTOM w0.127: v1(156.1,72.02) 156.81,72.02 157.31,72.52 168.43,72.52 180.96,85.04 180.96,89.11 v1(181.34,89.49)
FLEXSPI1_B_D4: length 124.5
  TOP w0.127: v1(183.88,87.96) 182.73,89.11 182.73,90.63 185.86,93.76 J71.21 ; v1(105.89,70.84) 105.89,70.84 U6.H15
  BOTTOM w0.127: v1(105.89,70.84) 110.74,70.84 112.12,72.21 125.08,72.21 128.76,75.9 136.76,75.9 137.02,75.64 137.2,75.64 137.71,76.14 137.89,76.14 138.07,75.96 138.07,75.78 137.56,75.28 137.56,75.1 137.74,74.92 137.92,74.92 138.43,75.42 138.61,75.42 138.79,75.24 138.79,75.06 138.28,74.56 138.28,74.38 138.46,74.2 138.64,74.2 139.14,74.71 139.32,74.71 139.5,74.53 139.5,74.35 139,73.84 139,73.66 139.18,73.48 139.36,73.48 139.86,73.99 140.04,73.99 140.22,73.81 140.22,73.63 139.72,73.12 139.72,72.94 140.62,72.04 141.36,72.04 142.98,70.41 142.98,69.24 143.19,69.04 143.67,69.04 143.8,69.17 143.8,69.83 143.93,69.95 144.18,69.95 144.31,69.83 144.31,68.99 144.43,68.86 144.69,68.86 144.81,68.99 144.81,69.83 144.94,69.95 145.2,69.95 145.32,69.83 145.32,68.99 145.45,68.86 145.7,68.86 145.83,68.99 145.83,69.83 145.96,69.95 146.21,69.95 146.34,69.83 146.34,68.99 146.47,68.86 146.72,68.86 146.85,68.99 146.85,69.83 146.97,69.95 147.23,69.95 147.35,69.83 147.35,68.99 147.48,68.86 147.74,68.86 147.86,68.99 147.86,69.83 147.99,69.95 148.24,69.95 148.37,69.83 148.37,68.99 148.5,68.86 169.14,68.86 178.06,77.78 178.06,78.65 183.88,84.46 183.88,86.18 184,86.31 184.64,86.31 184.77,86.44 184.77,86.69 184.64,86.82 184,86.82 183.88,86.95 183.88,87.2 184,87.33 184.36,87.33 184.49,87.45 184.49,87.84 184.36,87.96 v1(183.88,87.96)
FLEXSPI1_B_D5: length 124.4
  TOP w0.127: U6.H14 v1(105.09,70.84) ; v1(184.64,88.6) 184,88.6 183.24,89.36 183.24,90.5 187.31,94.57 187.31,101.04 187.05,101.3 186.42,101.3 185.86,101.85 J71.22
  BOTTOM w0.127: v1(184.64,88.6) 184.74,88.7 184.74,90.19 184.87,90.32 185.96,90.32 186.09,90.19 186.09,89.84 185.96,89.72 185.48,89.72 185.35,89.59 185.35,87.05 185.48,86.92 185.76,86.92 185.88,86.79 185.88,86.54 185.76,86.41 185.48,86.41 184.89,85.83 184.89,85.02 178.47,78.59 178.47,77.42 169.5,68.46 143.06,68.46 142.53,68.99 142.53,69.5 142.02,70 142.02,70.18 142.3,70.46 142.3,70.64 142.12,70.82 141.94,70.82 141.66,70.54 141.48,70.54 141.3,70.72 141.3,70.9 141.58,71.18 141.58,71.36 141.4,71.54 141.22,71.54 140.94,71.26 140.76,71.26 136.51,75.52 136.18,75.52 136.06,75.39 136.06,75.16 135.93,75.03 135.68,75.03 135.55,75.16 135.55,75.39 135.42,75.52 129.01,75.52 125.33,71.83 112.38,71.83 110.98,70.44 105.49,70.44 v1(105.09,70.84)
FLEXSPI1_B_D6: length 122.4
  TOP w0.127: U6.G17 111.94,72.04 114.61,74.7 116.67,74.7 117.25,75.29 134.83,75.29 135.03,75.09 135.21,75.09 135.49,75.36 136.19,75.36 137.53,74.03 137.53,73.85 137.35,73.67 137.17,73.67 135.93,74.91 135.75,74.91 135.57,74.73 135.57,74.55 137.43,72.68 v1(140.82,72.68) ; J71.25 188.26,94.25 184.22,90.21 v1(184.22,89.36)
  BOTTOM w0.127: v1(140.82,72.68) 141.17,72.34 141.55,72.34 142.27,71.62 142.5,71.62 142.74,71.86 143.92,71.86 144.35,72.29 145.83,72.29 145.95,72.16 145.95,71.91 145.88,71.83 144.53,71.83 144.33,71.63 144.33,71.01 144.08,70.76 143.9,70.76 143.22,71.44 143.04,71.44 142.86,71.26 142.86,71.08 143.63,70.31 148.65,70.31 149.64,69.32 168.18,69.32 168.85,69.99 169.03,69.99 169.14,69.87 169.32,69.87 169.5,70.05 169.5,70.23 169.39,70.35 169.39,70.53 169.57,70.7 169.74,70.7 169.86,70.59 170.04,70.59 170.22,70.77 170.22,70.95 170.1,71.06 170.1,71.24 170.28,71.42 170.46,71.42 170.58,71.31 170.76,71.31 170.94,71.49 170.94,71.67 170.82,71.78 170.82,71.96 171,72.14 171.18,72.14 171.29,72.03 171.47,72.03 171.65,72.21 171.65,72.39 171.54,72.5 171.54,72.68 171.72,72.86 171.9,72.86 172.01,72.75 172.19,72.75 172.37,72.93 172.37,73.11 172.26,73.22 172.26,73.4 172.44,73.58 172.62,73.58 172.73,73.47 172.91,73.47 173.09,73.65 173.09,73.83 172.98,73.94 172.98,74.12 173.16,74.3 173.34,74.3 173.45,74.19 173.63,74.19 173.81,74.37 173.81,74.55 173.7,74.66 173.7,74.84 173.88,75.02 174.06,75.02 174.17,74.91 174.35,74.91 174.53,75.08 174.53,75.26 174.42,75.38 174.42,75.56 174.6,75.74 174.78,75.74 174.89,75.62 175.07,75.62 175.25,75.8 175.25,75.98 175.14,76.1 175.14,76.28 175.32,76.46 175.5,76.46 175.61,76.34 175.79,76.34 175.97,76.52 175.97,76.7 175.85,76.81 175.85,76.99 176.03,77.17 176.21,77.17 176.33,77.06 176.51,77.06 176.69,77.24 176.69,77.42 176.57,77.53 176.57,77.71 183.35,84.49 183.35,87.62 183.23,87.74 182.76,87.74 182.63,87.87 182.63,88.13 182.76,88.25 183.23,88.25 183.35,88.38 183.35,89.23 183.48,89.36 v1(184.22,89.36)
FLEXSPI1_B_D7: length 124.7
  TOP w0.127: U6.G13 103.89,72.04 v1(104.29,72.44) ; v1(183.75,89.99) 183.75,90.47 187.69,94.41 187.69,101.3 188.26,101.87 J71.26
  BOTTOM w0.127: v1(183.75,89.99) 181.18,89.99 180.57,89.39 180.57,85.17 170.11,74.7 168.71,74.7 168.59,74.58 168.59,73.99 168.46,73.87 168.2,73.87 168.08,73.99 168.08,74.58 167.95,74.7 167.7,74.7 167.57,74.58 167.57,73.99 167.44,73.87 167.19,73.87 167.06,73.99 167.06,74.58 166.93,74.7 166.68,74.7 166.55,74.58 166.55,73.99 166.43,73.87 166.17,73.87 166.05,73.99 166.05,74.58 165.92,74.7 165.66,74.7 165.54,74.58 165.54,73.99 165.41,73.87 165.16,73.87 165.03,73.99 165.03,74.58 164.9,74.7 164.65,74.7 164.52,74.58 164.52,73.99 164.39,73.87 164.14,73.87 164.01,73.99 164.01,74.58 163.89,74.7 163.63,74.7 163.51,74.58 163.51,73.99 163.38,73.87 163.12,73.87 163,73.99 163,74.58 162.87,74.7 162.62,74.7 162.49,74.58 162.49,73.99 162.36,73.87 162.11,73.87 161.98,73.99 161.98,74.58 161.85,74.7 161.6,74.7 161.47,74.58 161.47,73.99 161.35,73.87 161.09,73.87 160.97,73.99 160.97,74.58 160.84,74.7 160.58,74.7 160.46,74.58 160.46,73.99 160.33,73.87 160.08,73.87 159.95,73.99 159.95,74.58 159.82,74.7 159.57,74.7 159.44,74.58 159.44,73.99 159.31,73.87 159.06,73.87 158.93,73.99 158.93,74.58 158.81,74.7 158.55,74.7 158.43,74.58 158.43,73.99 158.3,73.87 158.04,73.87 157.92,73.99 157.92,74.58 157.79,74.7 157.54,74.7 157.41,74.58 157.41,74.25 157.28,74.12 157.03,74.12 156.9,74.25 156.9,74.58 156.77,74.7 155.68,74.7 155,75.39 150.35,75.39 149.84,74.88 149.08,74.88 148.95,75.01 145.85,75.01 145.22,74.37 144.25,74.37 143.69,74.93 139.99,74.93 138.04,76.88 119.02,76.88 118.09,77.8 114.76,77.8 109.8,72.84 104.69,72.84 v1(104.29,72.44)
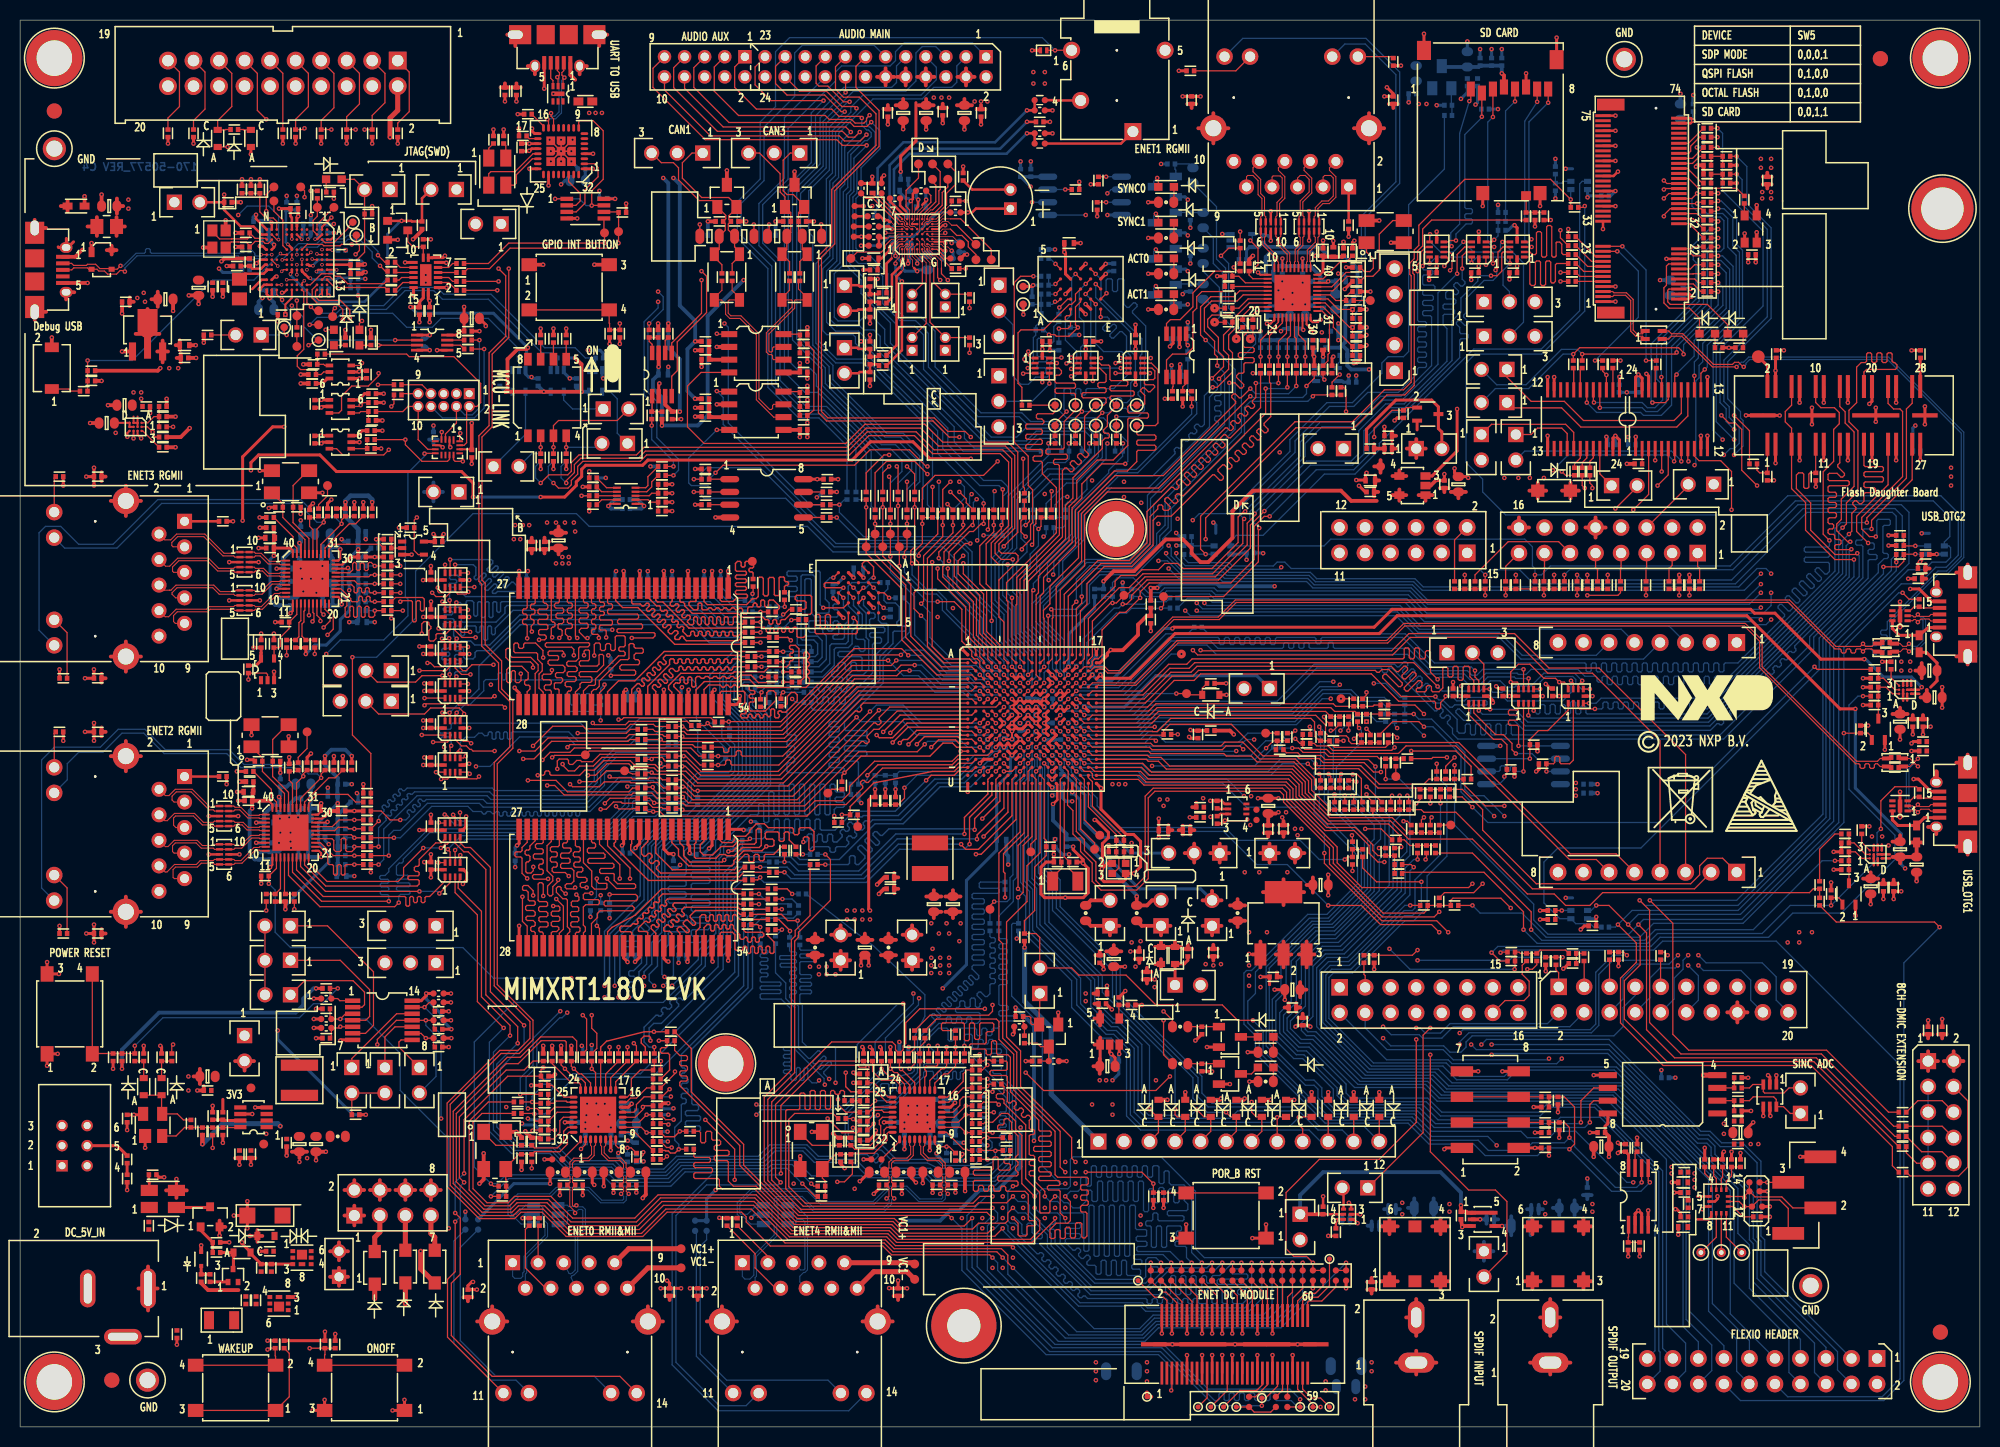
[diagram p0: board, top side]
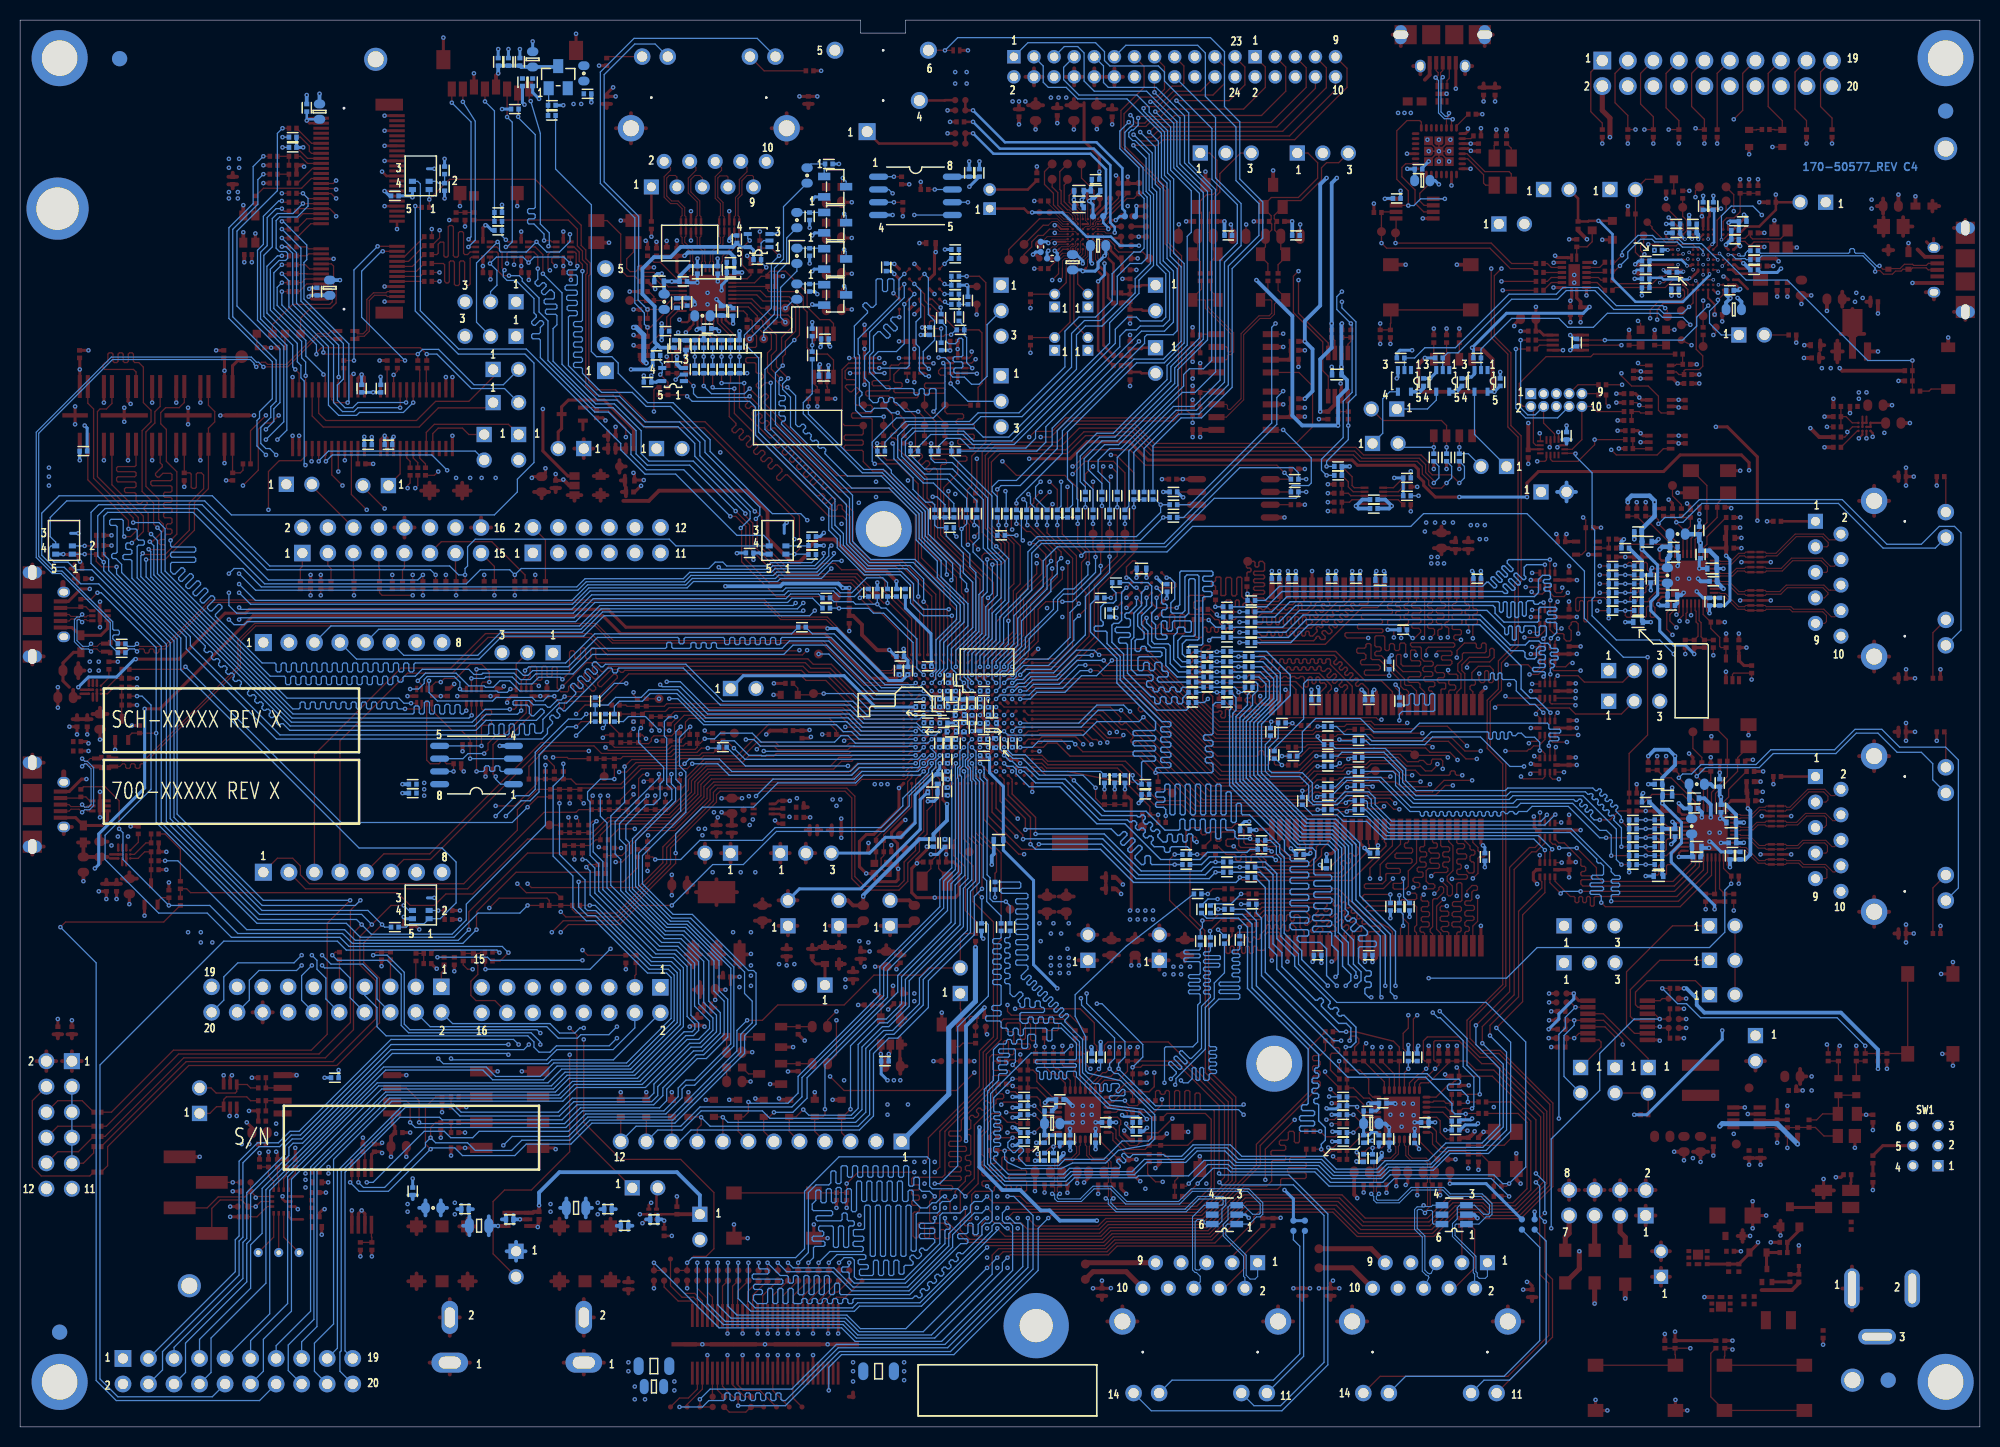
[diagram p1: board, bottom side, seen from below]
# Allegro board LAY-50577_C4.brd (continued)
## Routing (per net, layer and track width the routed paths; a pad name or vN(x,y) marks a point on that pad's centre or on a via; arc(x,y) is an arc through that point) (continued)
FLEXSPI1_B_DQS: length 132.1
  TOP w0.127: v1(180.03,88.22) 179.41,88.84 179.41,95.05 180.45,96.09 180.45,99.27 181.01,99.82 181.01,100.94 180.52,101.42 179.18,101.42 178.66,101.94 J71.10
  BOTTOM w0.127: R2157.2 118.24,78.92 137.83,78.92 140.72,76.02 155.69,76.02 155.82,75.9 155.82,75.26 155.95,75.14 156.2,75.14 156.33,75.26 156.33,75.9 156.45,76.02 156.71,76.02 156.83,75.9 156.83,75.26 156.96,75.14 157.22,75.14 157.34,75.26 157.34,75.9 157.47,76.02 157.72,76.02 157.85,75.9 157.85,75.26 157.98,75.14 158.23,75.14 158.36,75.26 158.36,75.9 158.49,76.02 158.74,76.02 158.87,75.9 158.87,75.26 158.99,75.14 159.25,75.14 159.37,75.26 159.37,75.9 159.5,76.02 159.76,76.02 159.88,75.9 159.88,75.26 160.01,75.14 160.26,75.14 160.39,75.26 160.39,75.9 160.52,76.02 160.77,76.02 160.9,75.9 160.9,75.26 161.03,75.14 161.28,75.14 161.41,75.26 161.41,75.9 161.53,76.02 161.79,76.02 161.91,75.9 161.91,75.26 162.04,75.14 162.3,75.14 162.42,75.26 162.42,75.9 162.55,76.02 162.8,76.02 162.93,75.9 162.93,75.26 163.06,75.14 163.31,75.14 163.44,75.26 163.44,75.9 163.57,76.02 163.82,76.02 163.95,75.9 163.95,75.26 164.07,75.14 164.33,75.14 164.45,75.26 164.45,75.9 164.58,76.02 164.84,76.02 164.96,75.9 164.96,75.26 165.09,75.14 165.34,75.14 165.47,75.26 165.47,75.9 165.6,76.02 165.85,76.02 165.98,75.9 165.98,75.26 166.11,75.14 166.36,75.14 166.49,75.26 166.49,75.9 166.61,76.02 166.87,76.02 166.99,75.9 166.99,75.26 167.12,75.14 167.38,75.14 167.5,75.26 167.5,75.9 167.63,76.02 167.88,76.02 168.01,75.9 168.01,75.26 168.14,75.14 168.39,75.14 168.52,75.26 168.52,75.9 168.65,76.02 168.9,76.02 169.03,75.9 169.03,75.26 169.15,75.14 169.41,75.14 169.53,75.26 169.53,75.9 169.66,76.02 170.92,76.02 175.57,80.67 175.57,80.85 174.92,81.49 174.92,81.67 175.1,81.85 175.28,81.85 175.93,81.21 176.11,81.21 176.36,81.46 176.36,81.64 175.65,82.35 175.65,82.53 175.83,82.71 176.01,82.71 176.71,82 176.89,82 177.07,82.18 177.07,82.36 176.33,83.1 176.33,83.28 176.51,83.46 176.69,83.46 177.43,82.72 177.61,82.72 177.79,82.89 177.79,83.07 177.05,83.82 177.05,84 177.23,84.18 177.41,84.18 178.15,83.43 178.33,83.43 178.51,83.61 178.51,83.79 177.76,84.54 177.76,84.72 177.94,84.9 178.12,84.9 178.87,84.15 179.05,84.15 179.23,84.33 179.23,84.51 178.61,85.13 178.61,85.31 178.79,85.49 178.97,85.49 179.59,84.87 179.77,84.87 180.03,85.13 180.03,85.91 179.9,86.04 177.65,86.04 177.53,86.16 177.53,86.42 177.65,86.54 179.9,86.54 180.03,86.67 180.03,86.93 179.9,87.05 177.65,87.05 177.53,87.18 177.53,87.43 177.65,87.56 179.9,87.56 180.03,87.69 v1(180.03,88.22)
FLEXSPI1_B_SS0: length 58.2
  TOP w0.127: U66.8 144.64,74.27 144.25,74.65 144.25,75.54 144.1,75.69 143.71,75.69 143.59,75.57 143.59,74.42 143.46,74.3 143.21,74.3 143.08,74.42 143.08,75.57 142.95,75.69 142.7,75.69 142.57,75.57 142.57,74.75 142.44,74.63 142.2,74.63 142.07,74.75 142.07,75.49 141.92,75.64 141.69,75.64 141.56,75.52 141.56,73.54 141.18,73.15 140.55,73.15 140.43,73.28 140.43,73.64 140.3,73.77 140.05,73.77 139.92,73.64 139.92,73.28 139.79,73.15 139.01,73.15 138.92,73.24 138.92,73.42 139.05,73.55 139.27,73.55 139.49,73.77 139.49,74.09 139.31,74.27 139.13,74.27 138.09,73.23 137.91,73.23 137.73,73.41 137.73,73.59 138.89,74.75 138.89,74.93 138.71,75.11 138.53,75.11 137.86,74.44 137.68,74.44 137.5,74.62 137.5,74.8 138.05,75.34 138.05,75.52 137.87,75.7 137.69,75.7 137.15,75.16 136.97,75.16 136.43,75.69 117.1,75.69 116.5,75.1 114.5,75.1 111.84,72.44 105.89,72.44 U6.F15
FLEXSPI1_B_SS0_4: length 11.7
  TOP w0.127: U66.1 144.14,70.88 146.59,68.43 147.4,68.43 147.94,67.89 R270.2 147.94,64.98 v1(147.68,64.72)
  BOTTOM w0.127: v1(147.68,64.72) 147.68,64.46 147.18,63.96 U10.1
FLEXSPI1_B_SS0_8: length 67.2
  TOP w0.127: J71.9 178.66,94.95 R1091.2 178.1,94.94 177.98,94.81 177.98,93.53 177.85,93.4 177.6,93.4 177.47,93.53 177.47,94.81 177.34,94.94 176.96,94.94 176.74,94.72 176.74,93.37 178.16,91.95 178.16,89.23 180.57,86.82 182.68,86.82 v1(182.8,86.94) ; v1(145.14,71.28) 145.14,71.29 U66.3
  BOTTOM w0.127: v1(182.8,86.94) 182.8,86.88 182.99,86.69 182.99,84.61 168.13,69.75 149.79,69.75 148.62,70.92 145.5,70.92 v1(145.14,71.28)
FLEXSPI2_A_CLK: length 19.4
  TOP w0.14: U15.B2 v1(84.92,83.51)
  BOTTOM w0.14: R2131.2 78.74,71.56 78.97,71.33 81.9,71.33 85.21,74.64 85.21,76.92 86.37,78.08 86.37,79.78 86.19,79.96 85.71,79.96 85.4,80.27 85.4,83.03 v1(84.92,83.51)
FLEXSPI2_A_D0: length 25.3
  TOP w0.14: U15.D3 v1(82.92,82.51)
  BOTTOM w0.14: v1(82.92,82.51) 82.92,81.73 83.8,80.85 83.8,79.71 83.17,79.07 83.17,78.51 83.31,78.37 83.92,78.37 84.05,78.23 84.05,77.31 83.92,77.17 83.65,77.17 83.51,77.31 83.51,77.54 83.37,77.68 83.09,77.68 82.95,77.54 82.95,77.31 82.81,77.17 81.53,77.17 81.39,77.03 81.39,76.79 81.53,76.65 83.64,76.65 83.78,76.51 83.78,75.4 83.64,75.26 83.36,75.26 83.22,75.4 83.22,75.95 83.08,76.09 82.8,76.09 82.66,75.95 82.66,75.4 82.52,75.26 82.24,75.26 82.1,75.4 82.1,75.95 81.96,76.09 81.53,76.09 81.39,75.95 81.39,75.33 81.25,75.19 80.89,75.19 80.75,75.05 80.75,74.78 80.89,74.64 81.71,74.64 81.85,74.5 81.85,74.29 81.68,74.12 R2123.2
FLEXSPI2_A_D1: length 20.8
  TOP w0.14: U15.D2 v1(82.92,83.51)
  BOTTOM w0.14: R2126.2 79.32,73.61 79.46,73.47 79.46,73.29 79.6,73.15 79.88,73.15 80.02,73.29 80.02,73.47 80.16,73.61 80.44,73.61 80.58,73.47 80.58,73.29 80.72,73.15 81,73.15 81.14,73.29 81.14,73.47 81.28,73.61 81.56,73.61 81.7,73.47 81.7,73.29 81.84,73.15 82.12,73.15 82.26,73.29 82.26,73.47 82.4,73.61 82.77,73.61 82.91,73.75 82.91,74.12 82.78,74.25 82.42,74.25 82.28,74.39 82.28,74.73 82.38,74.83 83.87,74.83 84.44,75.39 84.44,78.31 84.18,78.56 84.18,80.98 83.42,81.74 83.42,83.01 v1(82.92,83.51)
FLEXSPI2_A_D2: length 24.2
  TOP w0.14: U15.C4 v1(83.92,82.51)
  BOTTOM w0.14: v1(83.92,82.51) 83.92,81.75 84.66,81 84.93,81 85.07,80.86 85.07,80.58 84.93,80.44 84.66,80.44 84.52,80.3 84.52,79.75 84.69,79.58 85.9,79.58 86.04,79.44 86.04,79.18 85.9,79.04 84.66,79.04 84.52,78.9 84.52,78.7 84.66,78.56 85.57,78.56 85.71,78.43 85.71,78.13 85.57,77.99 84.96,77.99 84.82,77.85 84.82,75.01 82.48,72.67 82.25,72.67 82.11,72.53 82.11,72.1 81.97,71.96 81.69,71.96 81.55,72.1 81.55,72.53 81.41,72.67 81.13,72.67 80.99,72.53 80.99,72.1 80.85,71.96 80.57,71.96 80.43,72.1 80.43,72.53 80.29,72.67 80.01,72.67 79.87,72.53 79.87,72.1 79.73,71.96 79.45,71.96 79.31,72.1 79.31,72.53 R2127.2
FLEXSPI2_A_D3: length 23.1
  TOP w0.14: U15.D4 81.92,81.51 v1(79.92,81.51)
  BOTTOM w0.14: v1(79.92,81.51) 79.61,81.82 79.61,85.04 79.48,85.17 76.43,85.17 76.31,85.04 76.31,84.79 76.43,84.66 77.2,84.66 77.32,84.53 77.32,84.28 77.2,84.15 76.43,84.15 76.31,84.03 76.31,83.77 76.43,83.64 77.2,83.64 77.32,83.52 77.32,83.26 77.2,83.14 76.54,83.14 76.41,83.01 76.41,82.76 76.54,82.63 77.2,82.63 77.32,82.5 77.32,77.93 77.45,77.8 78.61,77.8 78.74,77.68 R2130.2
FLEXSPI2_A_DQS: length 2.6
  TOP w0.14: U15.C3 v1(83.92,83.51)
  BOTTOM w0.14: R333.2 84.69,84.03 84.17,83.51 v1(83.92,83.51)
FLEXSPI2_A_SS0: length 1.9
  TOP w0.14: U15.A3 85.96,83.01 v1(86.47,82.5)
  BOTTOM w0.14: R332.2 v1(86.47,82.5)
FLEXSPI2_B_CLK: length 20.8
  TOP w0.14: U15.B1 83.8,85.63 83.8,85.92 84.07,86.18 84.31,86.18 84.92,85.57 v1(84.92,84.51)
  BOTTOM w0.14: R2122.2 79.86,74.63 81.01,75.77 81.01,77.37 81.18,77.55 82.4,77.55 82.78,77.93 82.78,79.2 83.42,79.83 83.42,80.71 82.4,81.72 82.4,83.67 82.76,84.03 84.18,84.03 84.67,84.51 v1(84.92,84.51)
FLEXSPI2_B_D0: length 25.3
  TOP w0.14: v1(82.92,80.51) 83.29,80.14 83.29,79.06 83.17,78.93 79.23,78.93 79.1,79.06 79.1,80.72 79.23,80.85 79.48,80.85 79.61,80.72 79.61,79.56 79.74,79.44 79.99,79.44 80.12,79.56 80.12,80.72 80.24,80.85 80.5,80.85 80.63,80.72 80.63,79.56 80.75,79.44 81.14,79.44 81.26,79.56 81.26,79.77 81.39,79.89 81.63,79.89 81.77,79.76 81.77,79.56 81.9,79.44 82.29,79.44 82.42,79.56 U15.D5
  BOTTOM w0.14: v1(82.92,80.51) 82.92,80.03 82.4,79.52 82.4,78.18 82.15,77.93 80.75,77.93 80.56,77.74 80.56,75.96 79.74,75.14 R2119.2
FLEXSPI2_B_D1: length 22.3
  TOP w0.14: U15.E3 v1(81.92,82.51)
  BOTTOM w0.14: v1(81.92,82.51) 81.92,81.46 82.4,80.98 82.4,80.21 82.02,79.83 82.02,78.56 81.84,78.39 81.01,78.39 80.88,78.51 80.88,78.69 81.01,78.82 81.32,78.82 81.45,78.95 81.45,80.08 81.31,80.22 81.03,80.22 80.89,80.08 80.89,79.34 80.75,79.2 80.47,79.2 80.33,79.34 80.33,80.08 80.19,80.22 78.59,80.22 78.47,80.09 78.47,79.2 78.59,79.07 78.97,79.07 79.1,79.2 79.1,79.45 79.23,79.58 79.74,79.58 79.86,79.45 79.86,79.07 80.22,78.72 80.22,76.38 79.48,75.64 R2118.2
FLEXSPI2_B_D2: length 24.6
  TOP w0.14: v1(81.92,83.51) 80.14,83.51 80.01,83.64 80.01,83.88 80.14,84.01 U15.E2
  BOTTOM w0.14: R2115.2 79.36,76.15 79.8,76.6 79.8,78.25 79.36,78.69 78.21,78.69 78.09,78.82 78.09,84.28 78.21,84.41 78.59,84.41 78.72,84.28 78.72,80.98 79.1,80.6 81.26,80.6 81.41,80.75 81.41,81.19 81.27,81.33 81.02,81.33 80.88,81.47 80.88,81.75 81.02,81.89 81.27,81.89 81.41,82.03 81.41,83 v1(81.92,83.51)
FLEXSPI2_B_D3: length 22.5
  TOP w0.14: U15.E1 v1(80.92,84.51)
  BOTTOM w0.14: v1(80.92,84.51) 80.6,84.51 80.12,84.03 80.12,82.37 80.5,81.99 80.5,81.12 80.36,80.98 79.36,80.98 79.1,81.23 79.1,84.58 78.9,84.79 77.84,84.79 77.7,84.65 77.7,78.44 77.83,78.31 78.97,78.31 79.36,77.93 79.36,76.91 79.1,76.66 R2114.2
GPIO_AD_00: length 91
  TOP w0.127: v1(130.16,51.89) 133.46,51.89 135.36,49.99 140.44,49.99 v1(141.2,49.23) ; v1(147.81,82.76) R869.1 R1067.1 R867.1 ; U6.N12 v1(103.49,66.84)
  L3_INT_1 w0.127: v1(141.2,49.23) 141.2,50.5 142.22,51.51 142.22,62.82 140.44,64.59 140.44,66.25 140.95,66.75 140.95,71.12 139.68,72.39 139.68,77.93 142.6,80.85 145.9,80.85 v1(147.81,82.76)
  BOTTOM w0.127: v1(130.16,51.89) 126.09,55.96 123.04,55.96 119.74,59.26 109.07,59.26 106.53,61.8 106.53,62.82 104.27,65.08 104.27,65.26 103.89,65.64 103.89,66.28 103.49,66.68 v1(103.49,66.84)
GPIO_AD_01: length 91.6
  TOP w0.127: R868.1 R1056.2 R870.1 v1(151.62,82.76) ; U6.R14 v1(105.09,65.24) ; v1(129.77,57.1) 129.77,56.09 135.49,50.37 140.95,50.37 v1(142.09,49.23)
  L3_INT_1 w0.127: v1(142.09,49.23) 142.09,50.5 142.6,51.01 142.6,62.94 141.46,64.09 141.46,71.2 140.19,72.47 140.19,77.29 142.47,79.58 148.44,79.58 v1(151.62,82.76)
  BOTTOM w0.127: v1(129.77,57.1) 129.77,59.01 127.11,61.67 122.03,61.67 119.61,64.09 111.87,64.09 111.11,64.85 105.48,64.85 v1(105.09,65.24)
GPIO_AD_02: length 103.9
  TOP w0.127: R736.2 R1064.1 R871.1 R100.1 v1(145.78,82.76) ; U6.R13 104.29,65.24 104.29,63.49 104.22,63.43 104.22,61.87 104.76,61.34 104.76,59.01 105.52,58.24 105.52,57.26 106.67,56.11 106.67,54.3 107.55,53.42 111.11,53.42 112.25,54.56 112.25,62.59 112.92,63.26 125.35,63.26 125.71,62.9 125.71,62.18 130.28,57.61 130.28,56.01 135.54,50.75 140.7,50.75 v1(141.2,51.26)
  L3_INT_1 w0.127: v1(145.78,82.76) 143.49,82.76 139.3,78.56 139.3,72.23 140.57,70.96 140.57,67.01 140.06,66.5 140.06,64.34 141.84,62.56 141.84,51.89 v1(141.2,51.26)
GPIO_AD_03: length 83.6
  TOP w0.127: R1054.2 R872.1 R733.2 R101.1 v1(154.92,82.76) ; U6.R15 105.89,65.24 106.45,65.24 106.69,65 106.69,64.67 106.92,64.44 111.26,64.44 111.83,63.87 125.85,63.87 126.35,63.38 126.35,62.41 131.04,57.71 131.04,56.14 133.51,53.67 144.13,53.67 v1(144.51,54.05)
  L3_INT_1 w0.127: v1(144.51,54.05) 144.51,55.2 145.01,55.7 145.01,61.93 144.38,62.56 144.38,67.31 150.03,72.96 150.03,73.75 150.6,74.32 150.6,79.33 154.03,82.76 v1(154.92,82.76)
GPIO_AD_04: length 77.8
  TOP w0.127: v1(105.89,66.04) U6.P15 ; R874.1 v1(161.78,82.76) ; v1(147.68,61.8) 145.78,61.8 143.62,63.95 R731.2 R102.1 R904.1 R1069.1 140.18,64.47 139.67,63.96 135.24,63.96 133.39,65.8 129.07,65.8 v1(128.89,65.99)
  L3_INT_1 w0.127: v1(147.68,61.8) 145.52,63.96 145.52,67.16 150.45,72.09 151.75,72.09 152.51,72.85 152.51,74.63 154.29,76.41 154.29,78.69 158.35,82.76 v1(161.78,82.76)
  BOTTOM w0.127: v1(128.89,65.99) 128.42,66.46 125.42,66.46 124.19,65.23 112.38,65.23 111.61,65.99 105.94,65.99 v1(105.89,66.04)
GPIO_AD_05: length 89.8
  TOP w0.127: U6.P13 v1(104.29,66.04) ; v1(131.81,56.47) 132.05,56.71 R729.2 R103.1 132.58,57.48 R1059.2 ; v1(155.94,82.76) 158.98,82.76 159.24,83.01 R873.1
  L3_INT_1 w0.127: v1(155.94,82.76) 155.43,83.26 155.43,85.04 155.05,85.42 141.97,85.42 138.41,81.87 138.41,71.96 139.17,71.2 139.17,67.13 137.94,65.9 137.94,64.94 136.02,63.02 136.02,59.59 132.9,56.47 v1(131.81,56.47)
  BOTTOM w0.127: v1(131.81,56.47) 129.27,56.47 127.36,58.37 121.14,58.37 119.87,59.64 109.33,59.64 107.17,61.8 107.17,62.56 104.6,65.13 104.6,65.43 104.29,65.74 v1(104.29,66.04)
GPIO_AD_06: length 77
  TOP w0.127: v1(128.12,65.99) 128.62,65.5 133.19,65.5 135.11,63.58 139.17,63.58 R747.1 R727.2 R1066.1 R104.1 143.5,63.45 145.52,61.42 145.52,59.39 150.86,54.05 166.22,54.05 167.11,54.94 167.11,55.83 167.87,56.59 169.4,56.59 J70.1 ; U6.N13 v1(104.29,66.84)
  BOTTOM w0.127: v1(128.12,65.99) 125.58,65.99 124.44,64.85 112.25,64.85 111.49,65.61 105.64,65.61 105.49,65.76 105.49,66.27 105.33,66.44 104.92,66.44 104.52,66.84 v1(104.29,66.84)
GPIO_AD_07: length 62.8
  TOP w0.127: R749.1 153.77,47.45 151.24,47.45 R135.1 R734.2 149.28,47.12 149.15,47.25 R1057.2 R105.1 148.74,45.59 v1(148.7,45.54) ; v1(135.74,56.21) 135.11,56.21 134.22,57.1 134.22,57.86 132.74,59.34 129.84,59.34 126.65,62.54 126.65,63.5 125.98,64.18 112.03,64.18 111.37,64.84 U6.T17
  L3_INT_1 w0.127: v1(136.25,47.58) 135.74,48.08 v1(135.74,56.21)
  BOTTOM w0.127: v1(148.7,45.54) 138.28,45.54 v1(136.25,47.58)
GPIO_AD_08: length 112
  TOP w0.127: U6.T14 105.09,64.44 105.09,59.26 105.9,58.45 105.9,57.36 107.04,56.21 107.04,54.36 107.6,53.8 110.98,53.8 111.94,54.77 111.94,62.77 112.74,63.57 125.6,63.57 126.02,63.15 126.02,62.31 130.66,57.66 130.66,56.09 135.62,51.13 139.68,51.13 140.06,51.51 R1068.1 R737.2 141.21,51.89 R106.1 142.35,52.4 142.57,52.62 147.34,52.62 v1(148.32,51.64)
  L3_INT_1 w0.127: J62.1 162.92,70.18 152.51,70.18 149.46,67.13 149.46,66.75 148.95,66.25 148.95,65.18 149.46,64.67 149.46,60.15 148.32,59.01 v1(148.32,51.64)
GPIO_AD_09: length 36.8
  TOP w0.127: R107.1 R1058.2 R752.2 R760.1 135.1,56.85 134.6,57.36 134.6,57.91 132.87,59.65 130,59.65 126.96,62.69 126.96,63.73 126.21,64.48 112.24,64.48 111.48,65.24 106.91,65.24 106.51,65.64 U6.R16
GPIO_AD_10: length 37.9
  TOP w0.127: U6.R17 111.59,65.64 112.38,64.85 126.35,64.85 127.26,63.93 127.26,62.82 130.07,60 136.14,60 137.27,58.88 137.27,58.43 R136.1 137.73,58.42 138.29,57.86 R1065.1 R750.2 R108.1
GPIO_AD_11: length 81
  TOP w0.127: R1055.2 R1053.1 178.42,53.55 178.03,53.16 157.46,53.16 156.19,51.89 153.78,51.89 152.63,53.04 149.97,53.04 144.51,58.5 138.16,58.5 136.35,60.31 130.2,60.31 127.57,62.94 127.57,64.06 126.47,65.15 112.58,65.15 111.7,66.04 106.69,66.04 U6.P16
GPIO_AD_12: length 37.8
  TOP w0.127: U6.P17 112.06,66.44 112.25,66.25 113.26,66.25 114.05,65.46 126.6,65.46 127.87,64.19 127.87,63.07 130.31,60.63 136.53,60.63 138.02,59.14 R1073.1 R730.2 R137.1 R109.1
GPIO_AD_13: length 33.9
  TOP w0.127: U6.N15 v1(105.9,66.83) ; v1(126.57,67.55) 127.22,67.55 127.65,67.12 129.79,67.12 130.19,66.72 135.02,66.72 135.24,66.49 R1063.2 R110.1 R732.2
  BOTTOM w0.127: v1(126.57,67.55) 125.54,67.55 R138.1 125.45,68.02 125.2,68.28 123.93,68.28 122.49,66.83 121.25,66.83 121.2,66.79 120.81,66.79 120.77,66.83 v1(105.9,66.83)
GPIO_AD_14: length 23.4
  TOP w0.127: R1071.1 125.08,67.51 R112.1 ; U6.N14 v1(105.09,66.84) ; R139.1 R112.1 ; R112.1 124.71,68.28 v1(123.98,67.55)
  BOTTOM w0.127: v1(123.98,67.55) 122.87,66.44 105.71,66.44 105.31,66.84 v1(105.09,66.84)
GPIO_AD_15: length 69.6
  TOP w0.127: U6.N16 106.69,66.84 112.17,66.84 112.38,66.63 113.52,66.63 114.38,65.76 126.73,65.76 128.2,64.29 128.2,63.17 130.44,60.94 134.47,60.94 134.6,61.06 R2158.1 R140.1 R113.1 R1061.2 R725.2 139.42,61.43 139.68,61.17 142.86,61.17 150.48,53.55 166.6,53.55 J70.2
GPIO_AD_16: length 29.5
  TOP w0.127: U6.N17 112.27,67.24 112.5,67.01 119.77,67.01 120.02,66.75 122.5,66.75 123.08,66.17 126.75,66.17 128.5,64.42 128.5,63.38 130.45,61.43 R2159.1 R116.1 R1072.1 R141.1
GPIO_AD_17: length 27.6
  TOP w0.127: U6.M17 112.49,68.04 112.76,67.77 119.49,67.77 119.87,68.15 121.65,68.15 123.32,66.47 126.88,66.47 127.11,66.25 127.11,66.25 128.81,64.54 128.81,63.91 129.13,63.59 R2160.1 R142.1 R1062.2 R118.1
GPIO_AD_18: length 62.8
  TOP w0.127: U6.K16 106.7,69.23 107.26,69.23 112.66,69.23 112.7,69.19 113.16,69.19 114.48,70.51 128.43,70.51 128.8,70.14 128.8,69.31 128.84,69.27 128.84,68.7 129.26,68.28 R120.1 129.4,68.28 R143.1 130.29,68.14 130.8,67.63 135.86,67.63 136.12,67.9 R724.2 143.15,68.11 154.24,57.03 158.81,57.03 J70.5
GPIO_AD_19: length 62.9
  TOP w0.127: R726.2 127.62,67.64 127.83,67.43 129.99,67.43 130.39,67.02 137.16,67.02 137.9,67.77 142.86,67.77 154.16,56.47 156.83,56.47 J70.6 ; R726.2 R122.1 ; R726.2 127.34,68.02 v1(126.88,68.48) ; U6.L13 v1(104.29,68.44)
  BOTTOM w0.127: v1(104.29,68.44) 104.68,68.05 104.93,68.05 104.94,68.04 111.89,68.04 112.63,68.79 113.32,68.79 113.95,68.15 121.27,68.15 122.16,69.04 125.33,69.04 125.89,68.48 v1(126.88,68.48)
GPIO_AD_21: length 35.7
  TOP w0.127: U6.K15 v1(105.89,69.24)
  BOTTOM w0.127: R1049.1 R1089.1 136.5,71.84 135.74,72.6 133.2,72.6 132.44,73.36 129.57,73.36 126.78,70.56 112.62,70.56 111.29,69.24 v1(105.89,69.24)
GPIO_AD_22: length 37
  TOP w0.127: U6.K12 v1(103.49,69.24)
  BOTTOM w0.127: v1(103.49,69.24) 103.89,68.84 111.4,68.84 112.7,70.13 112.71,70.13 112.76,70.18 126.85,70.18 129.65,72.98 132.31,72.98 133.08,72.21 135.36,72.21 135.87,71.71 R1090.1 R1051.1
GPIO_AD_30: length 103.2
  TOP w0.127: U6.L17 113.7,68.84 R1052.1 113.77,68.92 113.77,69.29 114.4,69.92 120.51,69.92 123.65,66.78 127,66.78 127.23,66.55 127.23,66.55 127.27,66.51 129.25,66.51 129.66,66.11 133.72,66.11 134.66,65.17 v1(135.4,65.17) ; R764.1 163.63,47.25 v1(163.94,46.94)
  L3_INT_1 w0.127: v1(135.4,65.17) 135.06,64.83 135.06,60.05 133.26,58.24 131.55,58.24 130.41,57.1 130.41,56.09 128.89,54.56 128.89,40.9 132.24,37.54 142.73,37.54 v1(143.24,38.05)
  BOTTOM w0.127: v1(143.24,38.05) 143.24,38.31 144.15,39.22 156.34,39.22 157.08,39.96 157.08,45.04 158.48,46.43 163.43,46.43 v1(163.94,46.94)
GPIO_AD_32: length 25.6
  TOP w0.127: R144.1 R128.1 R124.1 129.9,71.2 113.26,71.2 112.5,70.44 U6.J17
GPIO_AD_33: length 29.8
  TOP w0.127: U6.J16 106.69,70.84 112.39,70.84 113.14,71.58 130.41,71.58 130.79,71.2 132.82,71.2 R126.1 R146.1 135.36,70.94 R763.1
GPIO_AD_34: length 32.1
  TOP w0.127: U6.J15 105.89,70.04 112.61,70.04 113.39,70.82 128.92,70.82 129.89,69.84 129.89,69.05 130.17,68.77 131.95,68.77 132.19,68.53 132.19,68.28 132.47,68 133.3,68 133.41,68.11 R1042.1 R148.1 R767.1
GPIO_AD_35: length 28.7
  TOP w0.127: U6.H17 112.29,71.24 113.01,71.96 130.66,71.96 130.91,71.71 R130.1 R149.1 134.61,71.71 134.73,71.83 R735.1
GPIO_AON_00: length 77.8
  TOP w0.127: v1(100.29,73.24) U6.F8 ; v1(54.34,93.93) 54.34,94.16 55.15,94.97 55.15,95.76 55.78,96.4 61.5,96.4 62.21,97.11 82.37,97.11 84.29,99.02 89.15,99.02 90.94,97.23 97.77,97.23 98.66,96.34 98.66,89.56 97.01,87.91 97.01,86.95 97.63,86.33 v1(98.77,86.33)
  BOTTOM w0.127: v1(54.34,93.93) 53.83,94.44 53.83,95.59 R708.2 ; v1(100.29,73.24) 100.69,73.64 100.69,74.25 101.07,74.63 101.07,77.17 99.29,78.95 99.29,82.56 98.77,83.09 v1(98.77,86.33)
GPIO_AON_01: length 74.3
  TOP w0.127: U6.B7 98.69,76.44 v1(98.69,82.5) ; v1(53.07,93.93) 53.57,93.42 54.51,93.42 54.84,93.75 54.84,94.19 55.48,94.82 55.48,95.58 55.99,96.09 61.7,96.09 62.34,96.73 82.53,96.73 84.45,98.64 89,98.64 90.79,96.85 97.52,96.85 98.36,96.01 98.36,89.69 96.63,87.96 96.63,86.57 97.37,85.82 v1(98.26,85.82)
  BOTTOM w0.127: v1(98.69,82.5) 98.26,82.93 v1(98.26,85.82) ; v1(53.07,93.93) 52.56,94.44 52.56,95.59 R710.2
GPIO_AON_02: length 77.7
  TOP w0.127: v1(51.8,93.93) 52.61,94.74 54.49,94.74 54.84,95.1 54.84,95.96 55.61,96.73 61.32,96.73 62.08,97.49 82.28,97.49 84.18,99.39 89.61,99.39 91.39,97.61 98.02,97.61 98.96,96.68 98.96,89.43 97.39,87.86 97.39,87.2 97.64,86.95 99.04,86.95 99.29,86.69 99.29,86.19 97.39,84.28 97.39,80.6 97.89,80.1 97.89,76.44 U6.B6
  BOTTOM w0.127: v1(51.8,93.93) 51.29,94.44 51.29,95.59 R712.2
GPIO_AON_08: length 116.8
  TOP w0.127: v1(116.69,77.29) 117.16,76.83 136.57,76.83 138.31,78.56 148.44,78.56 152,75.01 156.44,75.01 163.18,68.28 J70.4 ; R74.1 v1(92.82,89.74) 92.82,88.98 90.28,86.44 90.28,77.68 91.92,76.04 U6.B1
  L3_INT_1 w0.127: v1(116.69,77.29) 116.31,77.68 116.31,79.33 114.66,80.98 113.14,80.98 112.76,81.36 107.8,81.36 106.91,82.25 106.91,82.88 102.72,87.07 102.72,89.99 102.19,90.53 93.61,90.53 v1(92.82,89.74)
  BOTTOM w0.127: v1(92.82,89.74) R74.1
GPIO_AON_09: length 111.2
  TOP w0.127: v1(117.46,77.29) 117.52,77.23 136.47,77.23 138.18,78.95 148.7,78.95 152.13,75.52 157.11,75.52 165.72,66.91 J70.3 ; U6.A5 97.49,77.83 96.17,79.15 96.17,83.21 95.48,83.9 95.48,87.68 96.88,89.08 v1(96.88,89.74) R76.1
  L3_INT_1 w0.127: v1(96.88,89.74) 97.36,90.22 101.86,90.22 102.34,89.74 102.34,86.82 106.53,82.63 106.53,82.09 107.66,80.96 112.52,80.96 113.26,80.22 114.79,80.22 115.93,79.07 115.93,77.29 116.44,76.79 117.07,76.79 117.46,77.17 v1(117.46,77.29)
  BOTTOM w0.127: v1(96.88,89.74) R76.1
GPIO_AON_15: length 18.3
  TOP w0.127: U6.B3 95.89,76.25 95.49,76.65 95.49,77.48 94.47,78.5 94.47,81.93 91.8,84.6 91.8,85.58 91.93,85.71 91.93,87.07 94.6,89.74 v1(94.77,89.74) 94.85,89.82 R79.1
  BOTTOM w0.127: v1(94.77,89.74) 94.85,89.82 R79.1
GPIO_AON_16: length 19.5
  TOP w0.127: R80.1 v1(93.83,89.77) 93.83,89.49 91.41,87.06 v1(91.41,86.45) ; U6.C5 v1(97.09,75.64)
  BOTTOM w0.127: v1(97.09,75.64) 97.09,75.92 95.36,77.66 95.36,80.22 92.44,83.14 92.44,84.28 91.8,84.91 91.8,86.06 v1(91.41,86.45) ; v1(93.83,89.77) R80.1
GPIO_AON_17: length 20.9
  TOP w0.127: v1(92.42,86.17) 92.42,87.06 94.47,89.11 94.85,89.11 95.61,89.87 v1(95.87,89.87) R1086.1 ; U6.D6 v1(97.89,74.84)
  BOTTOM w0.127: v1(97.89,74.84) 97.89,75.01 97.49,75.41 97.49,76.05 95.74,77.8 95.74,80.47 92.82,83.39 92.82,85.68 92.44,86.06 92.44,86.16 v1(92.42,86.17) ; v1(95.87,89.87) R1086.1
GPIO_AON_18: length 20.7
  TOP w0.127: v1(96.67,80.22) 96.67,83.35 96.12,83.9 96.12,87.88 97.64,89.41 v1(97.64,89.74) 97.77,89.87 R1085.1 ; U6.E6 v1(97.89,74.04)
  BOTTOM w0.127: v1(96.67,80.22) 96.67,77.91 98.29,76.28 98.29,74.44 v1(97.89,74.04) ; R1080.1 97.64,88.85 97.64,89.73 v1(97.64,89.74) 97.64,90.38 R1085.1
GPIO_AON_19: length 23.7
  TOP w0.127: v1(89.66,81.93) 89.9,82.17 89.9,86.69 91.8,88.6 v1(91.8,89.74) R1087.1 ; U6.D5 v1(97.09,74.84)
  BOTTOM w0.127: R1084.1 R1087.1 v1(91.8,89.74) ; v1(89.66,81.93) 90.53,81.05 90.53,78.56 92.69,76.41 94.93,76.41 96.09,75.24 96.48,75.24 96.88,74.84 v1(97.09,74.84)
GPIO_AON_20: length 24.6
  TOP w0.127: v1(89.64,80.72) 88.95,81.42 88.95,83.01 89.39,83.45 89.39,86.03 88.95,86.48 88.95,87.09 89.77,87.91 v1(89.77,89.87) R1081.1 R82.1 ; U6.E5 v1(97.09,74.04)
  BOTTOM w0.127: v1(89.64,80.72) 90.15,80.22 90.15,78.29 92.67,75.77 95.15,75.77 95.89,75.03 95.89,74.68 96.13,74.44 96.69,74.44 v1(97.09,74.04) ; R1081.1 v1(89.77,89.87)
GPIO_AON_21: length 25.2
  TOP w0.127: R83.1 v1(89.01,91.52) 89.01,87.58 88.63,87.2 88.63,86.06 v1(88.75,85.93) ; U6.F6 v1(97.89,73.24)
  BOTTOM w0.127: v1(89.01,91.52) R83.1 ; v1(97.89,73.24) 97.49,73.64 97.49,75.03 97.29,75.24 96.91,75.24 96.69,75.45 96.69,75.83 94.98,77.55 94.98,78.57 92.18,81.36 92.18,82.33 91.12,83.39 90.15,83.39 88.75,84.79 v1(88.75,85.93)
GPIO_AON_22: length 23
  TOP w0.127: U6.C3 95.49,75.64 95.49,76.19 95.24,76.44 94.93,76.44 94.69,76.68 94.69,77.2 93.71,78.18 93.71,81.36 92.94,82.12 v1(91.29,82.12) ; R84.1 v1(87.36,91.65) 87.36,87.71 TP96.1 v1(87.48,85.68)
  BOTTOM w0.127: v1(91.29,82.12) 90.28,82.12 87.48,84.91 v1(87.48,85.68) ; v1(87.36,91.65) R84.1
GPIO_AON_23: length 23.4
  TOP w0.127: U6.C2 94.69,75.64 91.68,75.64 88.63,78.69 88.63,83.87 85.83,86.66 TP97.1 v1(85.83,91.52) R85.1
  BOTTOM w0.127: v1(85.83,91.52) R85.1
GPIO_AON_24: length 21.4
  TOP w0.127: R86.1 v1(85.07,89.87) TP98.1 85.07,86.82 88.12,83.77 88.12,78.57 91.45,75.24 U6.C1
  BOTTOM w0.127: v1(85.07,89.87) R86.1
GPIO_AON_25: length 26.2
  TOP w0.127: R87.1 v1(84.18,91.52) TP99.1 84.18,86.95 87.74,83.39 87.74,78.31 91.21,74.84 94.69,74.84 U6.D2
  BOTTOM w0.127: R96.1 R87.1 v1(84.18,91.52)
GPIO_AON_26: length 20.2
  TOP w0.127: R88.1 v1(88.25,89.87) TP100.1 88.25,87.37 87.99,87.12 v1(87.99,86.57) ; U6.C4 v1(96.29,75.64)
  BOTTOM w0.127: v1(87.99,86.57) 87.99,85.04 90.15,82.88 91.2,82.88 91.76,82.32 91.76,81.27 94.6,78.44 94.6,77.33 v1(96.29,75.64) ; v1(88.25,89.87) R88.1
GPIO_AON_27: length 22
  TOP w0.127: U6.D3 v1(95.49,74.84) ; R89.1 v1(86.59,89.87) TP101.1 v1(86.59,86.6)
  BOTTOM w0.127: v1(86.59,86.6) 86.59,85.04 89.01,82.63 89.01,78.82 92.44,75.39 94.94,75.39 v1(95.49,74.84) ; v1(86.59,89.87) R89.1
GPIO_B1_12: length 46.6
  TOP w0.127: U6.A11 v1(102.29,80.72) ; v1(128.63,102.57) 128.77,102.7 R2643.1 R2639.1
  BOTTOM w0.127: v1(128.63,102.57) 128.12,102.06 122.41,102.06 121.82,101.48 121.82,98.68 114.53,91.39 114.53,89.23 113.7,88.39 113.7,87.51 110.99,84.8 107.44,84.8 106.41,83.77 106.41,81.99 105.14,80.72 v1(102.29,80.72)
GPIO_B1_13: length 57.9
  TOP w0.127: R2644.1 R2640.1 120.26,117.31 v1(119.49,116.54) ; U6.B11 102.7,76.44 102.7,80.47 102.76,80.53 102.76,81.2 v1(102.6,81.37)
  BOTTOM w0.127: v1(119.49,116.54) 120.25,115.78 120.25,111.33 122.93,108.65 122.93,107.79 121.52,106.38 121.52,99.01 114.23,91.72 114.23,89.49 113.39,88.65 113.39,87.63 110.87,85.11 107.31,85.11 106.1,83.9 106.1,82.32 105.14,81.37 v1(102.6,81.37)
GPIO_B2_00: length 22.3
  TOP w0.127: v1(100.06,89.74) 100.44,90.12 100.44,91.13 100.31,91.26 R111.1 R2641.1 ; U6.E9 v1(101.09,74.04)
  BOTTOM w0.127: R125.1 100.06,90.26 v1(100.06,89.74) 99.8,89.74 99.6,89.54 99.6,88.42 100.18,87.84 100.18,87.07 99.17,86.06 99.17,83.26 99.6,82.83 99.6,79.15 101.45,77.29 101.45,74.4 v1(101.09,74.04)
GPIO_B2_01: length 22.1
  TOP w0.127: U6.E10 v1(101.89,74.04)
  BOTTOM w0.127: R127.1 R958.1 R2642.1 103.99,89.74 103.74,89.49 R114.1 102.84,88.64 101.15,86.95 101.15,84.99 100.21,84.05 100.21,79.56 102.34,77.42 102.34,75.52 102.31,75.48 102.31,75.46 102.07,75.22 102.04,75.22 101.89,75.07 v1(101.89,74.04)
GPIO_B2_02: length 19.3
  TOP w0.127: v1(101.33,89.36) 101.58,89.61 R115.1 R1328.1 ; U6.C10 v1(101.89,75.64)
  BOTTOM w0.127: v1(101.89,75.64) 101.89,77.29 99.9,79.28 99.9,85.02 100.5,85.61 100.5,86.86 101.33,87.68 v1(101.33,89.36) 100.82,89.87 R129.1
GPIO_B2_03: length 31.7
  TOP w0.127: U6.D9 v1(100.29,74.04) ; R117.1 v1(106.38,97.88)
  BOTTOM w0.127: v1(100.29,74.04) 100.29,74.23 100.69,74.63 100.69,77.04 98.91,78.82 98.91,81.61 97.77,82.76 97.77,86.06 99.17,87.46 99.17,92.28 102.22,95.33 105.01,95.33 106.4,96.72 R131.1 106.4,97.86 v1(106.38,97.88)
GPIO_B2_04: length 29.4
  TOP w0.127: v1(100.29,74.84) 100.29,74.84 U6.C9 ; R119.1 v1(104.35,97.88)
  BOTTOM w0.127: v1(104.35,97.88) 104.37,97.86 R132.1 104.37,96.34 103.99,95.96 102.25,95.96 98.73,92.44 98.73,87.45 97.39,86.11 97.39,82.5 98.61,81.28 98.61,78.62 100.29,76.93 v1(100.29,74.84)
GPIO_B2_05: length 25.4
  TOP w0.127: R121.1 v1(109.73,97.88) ; v1(100.82,83.26) 100.69,83.14 U6.A9
  BOTTOM w0.127: v1(100.82,83.26) 100.82,83.93 101.45,84.56 101.45,85.68 104.63,88.85 104.63,91.24 108.31,94.92 108.31,95.2 109.7,96.59 R133.1 109.7,97.84 v1(109.73,97.88)
GPIO_B2_06: length 28.6
  TOP w0.127: R123.1 v1(102.32,97.88) ; U6.E8 v1(99.49,74.04)
  BOTTOM w0.127: v1(102.32,97.88) 102.34,97.86 R134.1 102.34,96.69 98.3,92.65 98.3,87.45 97.01,86.16 97.01,82.25 98.28,80.98 98.28,78.44 99.89,76.82 99.89,74.44 v1(99.49,74.04)
GPIO_BUTTON: length 45.5
  TOP w0.127: v1(59.67,109.81) R2154.2 C604.1 58.65,109.81 58.61,109.85 SW8.4 SW8.2
  L3_INT_1 w0.127: v1(70.08,109.81) 68.94,109.81 68.18,109.04 60.43,109.04 v1(59.67,109.81)
  BOTTOM w0.127: v1(70.08,109.81) 70.47,109.43 70.47,99.9 78.59,91.77 R2155.2
GPIO_EMC_B1_00: length 30.5
  TOP w0.14: R151.1 72.93,82.97 v1(72.87,82.91) ; U6.H3 v1(96.29,70.84)
  L3_INT_1 w0.14: v1(96.29,70.84) 93.43,70.84 90.02,74.25 86.16,74.25 82.75,77.66 79.35,79.48 75.65,79.48 74.4,80.72 74.4,81.38 v1(72.87,82.91)
  BOTTOM w0.14: R203.1 v1(72.87,82.91)
GPIO_EMC_B1_00_P: length 39.4
  TOP w0.127: U96.8 v1(42.78,86.31)
  BOTTOM w0.14: R203.2 71.1,82.25 69.7,83.64 49.49,83.64 49.07,84.06 48.91,84.06 48.36,83.51 48.2,83.51 48.09,83.62 48.09,83.78 48.64,84.33 48.64,84.49 48.53,84.6 48.37,84.6 47.82,84.05 47.66,84.05 47.55,84.16 47.55,84.32 48.1,84.87 48.1,85.03 47.99,85.14 47.83,85.14 47.28,84.59 47.12,84.59 47.01,84.7 47.01,84.86 47.56,85.41 47.56,85.57 47.45,85.68 47.29,85.68 46.74,85.13 46.58,85.13 46.47,85.24 46.47,85.4 47.02,85.95 47.02,86.18 46.9,86.31 v1(42.78,86.31)
GPIO_EMC_B1_01: length 29.3
  TOP w0.14: R152.1 76.05,81.64 v1(76.08,81.61) ; U6.H4 v1(97.09,70.84)
  L3_INT_1 w0.14: v1(97.09,70.84) 96.68,71.25 93.91,71.25 90.4,74.75 86.39,74.75 83.17,77.98 79.7,79.81 76.08,79.81 75.16,80.72 75.16,81.1 75.67,81.61 v1(76.08,81.61)
  BOTTOM w0.14: R205.1 v1(76.08,81.61)
GPIO_EMC_B1_01_P: length 40.4
  TOP w0.127: U96.7 v1(43.28,85.8)
  BOTTOM w0.14: R205.2 70.97,81.61 69.45,83.14 47.5,83.14 47.31,82.95 47.06,82.95 46.99,83.01 46.99,83.17 47.43,83.61 47.43,83.77 47.32,83.88 47.16,83.88 46.53,83.25 46.38,83.25 46.27,83.36 46.27,83.52 46.9,84.15 46.9,84.3 46.78,84.42 46.63,84.42 46,83.79 45.84,83.79 45.73,83.9 45.73,84.06 46.36,84.69 46.36,84.84 46.24,84.96 46.09,84.96 45.46,84.33 45.3,84.33 45.19,84.44 45.19,84.6 45.35,84.75 45.35,85.55 45.09,85.8 v1(43.28,85.8)
GPIO_EMC_B1_02: length 30.1
  TOP w0.14: U6.K2 95.48,69.24 v1(95.49,69.24) ; v1(73.67,81.1) R153.1
  L3_INT_1 w0.14: v1(73.67,81.1) 73.13,80.57 73.13,79.78 73.34,79.58 74.02,79.58 74.85,78.75 76.89,78.75 76.89,78.74 78.68,78.74 82.71,76.25 85.73,73.23 89.64,73.23 92.94,69.93 94.26,69.93 94.93,69.26 95.45,69.26 95.46,69.24 v1(95.49,69.24)
  BOTTOM w0.14: R206.1 v1(73.67,81.1)
GPIO_EMC_B1_02_P: length 37.4
  TOP w0.127: U97.8 42.78,82.22 v1(42.74,82.26)
  BOTTOM w0.14: R206.2 70.47,81.1 68.94,82.63 44.33,82.63 43.92,83.04 43.92,84.33 43.51,84.75 42.86,84.75 42.73,84.62 42.73,84.44 42.84,84.33 43.33,84.33 43.44,84.22 43.44,84.06 43.33,83.95 42.74,83.95 42.65,83.86 42.65,83.66 42.75,83.57 43.25,83.57 43.36,83.45 43.36,83.3 43.25,83.19 42.84,83.19 42.73,83.07 42.73,82.27 v1(42.74,82.26)
GPIO_EMC_B1_03: length 26.6
  TOP w0.14: R154.1 76.51,81.36 76,80.85 v1(75.93,80.85) ; U6.G3 v1(96.29,72.44)
  L3_INT_1 w0.14: v1(96.29,72.44) 95.9,72.83 94.16,72.83 87.79,79.2 83.02,79.2 79.95,80.85 78.29,80.85 77.65,81.49 77.07,81.49 76.43,80.85 v1(75.93,80.85)
  BOTTOM w0.14: R207.1 75.8,80.6 75.93,80.72 v1(75.93,80.85)
GPIO_EMC_B1_03_P: length 43.1
  TOP w0.127: v1(43.41,82.04) 43.41,81.99 43.28,81.86 U97.7
  BOTTOM w0.14: v1(43.41,82.04) 43.78,82.04 43.95,81.87 44.27,81.87 44.41,82.01 44.41,82.15 44.48,82.22 44.96,82.22 45.14,82.05 45.14,80.82 45.3,80.66 45.38,80.66 45.52,80.8 45.52,82.01 45.63,82.12 45.79,82.12 45.9,82.01 45.9,80.66 46.01,80.55 46.17,80.55 46.28,80.66 46.28,82.01 46.39,82.12 46.55,82.12 46.66,82.01 46.66,80.66 46.77,80.55 46.93,80.55 47.04,80.66 47.04,82.01 47.15,82.12 47.31,82.12 47.42,82.01 47.42,81.21 47.58,81.05 47.68,81.05 47.8,81.18 47.8,82.01 47.92,82.12 68.64,82.12 70.16,80.6 R207.2
GPIO_EMC_B1_04: length 29.4
  TOP w0.14: U6.J4 v1(97.09,70.04) ; R155.1 v1(73.67,80.09)
  L3_INT_1 w0.14: v1(73.67,80.09) 74.28,80.09 75.24,79.12 78.98,79.12 82.64,77.01 85.91,73.74 89.77,73.74 93.07,70.44 U6.J4 v1(97.09,70.04)
  BOTTOM w0.14: R155.1 v1(73.67,80.09)
GPIO_EMC_B1_04_P: length 40.6
  TOP w0.127: v1(42.69,78.48) 42.78,78.39 42.78,78.18 42.78,78.18 U98.8
  BOTTOM w0.14: v1(42.69,78.48) 42.11,79.06 42.11,79.94 42.22,80.05 43.05,80.05 43.16,80.16 43.16,80.32 43.05,80.43 42.22,80.43 42.11,80.54 42.11,80.7 42.22,80.81 42.92,80.81 43.03,80.92 43.03,81.08 42.92,81.19 42.22,81.19 42.11,81.3 42.11,81.44 42.23,81.57 43.77,81.57 43.9,81.44 43.9,80.22 44.02,80.09 47.35,80.09 48.24,80.98 48.24,81.54 48.44,81.74 68.08,81.74 69.73,80.09 R208.2
GPIO_EMC_B1_05: length 27.8
  TOP w0.14: v1(76.74,80.29) 76.79,80.34 R156.1 ; U6.H6 v1(97.89,70.84)
  L3_INT_1 w0.14: v1(76.74,80.29) 79.9,80.29 83.11,78.56 87.48,78.56 94.16,71.88 96.84,71.88 v1(97.89,70.84)
  BOTTOM w0.14: v1(76.74,80.29) 76.03,79.58 R209.1
GPIO_EMC_B1_05_P: length 41.6
  TOP w0.127: v1(43.44,78.44) 43.28,78.28 U98.7
  BOTTOM w0.14: R209.2 69.37,79.58 67.7,81.26 49.05,81.26 47.28,79.49 47.28,78.96 47.17,78.84 47.01,78.84 46.9,78.96 46.9,79.6 46.79,79.71 46.63,79.71 46.52,79.6 46.52,78.39 46.41,78.28 46.25,78.28 46.14,78.39 46.14,79.6 46.03,79.71 45.87,79.71 45.76,79.6 45.76,79.18 45.63,79.05 45.5,79.05 45.38,79.17 45.38,79.6 45.27,79.71 44.35,79.71 44.22,79.58 44.22,78.85 44.11,78.74 43.95,78.74 43.84,78.85 43.84,79.58 43.72,79.71 43.26,79.71 43.14,79.58 43.14,78.74 v1(43.44,78.44)
GPIO_EMC_B1_06: length 30.7
  TOP w0.14: R157.1 v1(73.67,79.07) ; U6.K3 v1(96.29,70.04)
  L3_INT_1 w0.14: v1(96.29,70.04) 95.89,69.63 95.89,69.07 95.89,69.07 95.89,68.27 95.65,68.03 94.64,68.03 93.76,68.91 92.59,68.91 89.16,72.34 85.2,72.34 81.99,75.55 78.74,77.8 76.44,77.8 76.1,78.13 74.61,78.13 v1(73.67,79.07)
  BOTTOM w0.14: R157.1 v1(73.67,79.07)
GPIO_EMC_B1_06_P: length 38.6
  TOP w0.127: v1(42.74,74.9) 42.78,74.85 U99.8
  BOTTOM w0.14: R210.2 69.07,79.07 67.34,80.8 49.71,80.8 46.73,77.82 45.23,77.82 44.84,78.21 43.88,78.21 43.65,77.98 42.98,77.98 42.74,77.74 42.74,77.58 42.63,77.47 42.08,77.47 41.97,77.36 41.97,77.2 42.08,77.09 42.63,77.09 42.74,76.98 42.74,76.82 42.63,76.71 42.08,76.71 41.97,76.6 41.97,76.44 42.08,76.33 42.63,76.33 42.74,76.22 42.74,76.06 42.63,75.95 42.46,75.95 42.35,75.84 42.35,75.68 42.46,75.57 42.63,75.57 42.74,75.45 v1(42.74,74.9)
GPIO_EMC_B1_07: length 26.2
  TOP w0.14: v1(95.49,68.44) 95.5,68.43 U6.M3 ; v1(76.69,78.27) 76.4,78.56 R158.1
  L3_INT_1 w0.14: v1(76.69,78.27) 78.84,78.27 82.96,75.36 85.48,72.85 89.29,72.85 92.72,69.42 93.85,69.42 94.83,68.44 v1(95.49,68.44)
  BOTTOM w0.14: v1(76.69,78.27) 76.4,78.56 R158.1
GPIO_EMC_B1_07_P: length 43
  TOP w0.127: v1(43.41,74.67) 43.41,74.63 43.28,74.5 U99.7
  BOTTOM w0.14: R211.2 68.81,78.56 67.04,80.34 49.76,80.34 46.66,77.25 45.45,77.25 45.27,77.07 45.27,76.63 45.07,76.43 44.3,76.43 44.13,76.61 44.13,77.39 43.85,77.66 43.35,77.66 43.24,77.55 43.24,77.35 43.35,77.24 43.74,77.24 43.85,77.13 43.85,76.97 43.74,76.86 43.35,76.86 43.24,76.75 43.24,76.45 43.35,76.34 43.84,76.34 43.95,76.23 43.95,76.07 43.84,75.96 43.35,75.96 43.24,75.84 43.24,75.69 43.35,75.58 44.4,75.58 44.51,75.47 44.51,75.29 44.38,75.16 43.37,75.16 43.24,75.02 43.24,74.85 v1(43.41,74.67)
GPIO_EMC_B1_08: length 35.1
  TOP w0.14: R159.1 v1(73.67,78.06) ; U6.H5 v1(97.89,71.64)
  L3_INT_1 w0.14: v1(97.89,71.64) 98.28,71.25 98.28,71.01 98.29,71 98.29,70.67 98.06,70.44 98.05,70.44 98.04,70.44 97.64,70.44 97.49,70.28 97.49,69.87 97.24,69.63 96.93,69.63 96.7,69.4 96.7,68.61 96.7,68.6 96.7,68.27 96.45,68.03 96.13,68.03 95.9,67.8 95.9,67.42 95.63,67.15 94.88,67.15 93.76,68.28 92.56,68.28 89.01,71.83 85.07,71.83 81.65,75.26 78.32,77.48 76.28,77.48 76.07,77.69 75.36,77.69 74.99,77.32 74.4,77.32 v1(73.67,78.06)
  BOTTOM w0.14: R159.1 v1(73.67,78.06)
GPIO_EMC_B1_08_P: length 35.9
  TOP w0.127: v1(42.73,71.07) 42.78,71.02 U100.8
  BOTTOM w0.14: v1(42.73,71.07) 44.18,72.52 44.74,72.52 45.65,73.43 45.65,75.72 49.76,79.83 66.78,79.83 68.56,78.06 R212.2
GPIO_EMC_B1_09: length 30.4
  TOP w0.127: U6.E1 83.27,73.64 75.5,65.86 70.84,65.86 70.71,65.99 70.71,66.24 70.58,66.37 70.34,66.37 70.2,66.24 70.2,65.99 70.07,65.86 v1(69.45,65.86) R160.1
  BOTTOM w0.127: v1(69.45,65.86) 70.09,66.51 R213.1
GPIO_EMC_B1_09_P: length 37
  TOP w0.127: U100.7 43.28,70.92 v1(43.44,71.07)
  BOTTOM w0.127: R213.2 70.21,67.53 67.29,70.45 67.29,73.97 66.92,74.34 48.82,74.34 48.71,74.45 48.71,74.92 48.59,75.03 48.44,75.03 48.32,74.92 48.32,74.45 48.21,74.34 48.05,74.34 47.94,74.45 47.94,74.92 47.83,75.03 47.67,75.03 47.56,74.92 47.56,74.49 47.45,74.37 46.33,74.37 46.13,74.18 46.13,73.26 44.79,71.91 44.28,71.91 v1(43.44,71.07)
GPIO_EMC_B1_10: length 31.8
  TOP w0.127: U6.E3 95.89,73.69 95.54,74.04 83.16,74.04 75.88,66.75 71.88,66.75 71.75,66.88 71.75,67.17 71.63,67.29 71.37,67.29 71.24,67.17 71.24,66.88 71.12,66.75 v1(69.45,66.75) R161.1
  BOTTOM w0.127: R214.1 v1(69.45,66.75)
GPIO_EMC_B1_10_P: length 35.9
  TOP w0.127: U101.8 42.78,67.65 42.89,67.76 v1(42.89,67.78)
  BOTTOM w0.127: v1(42.89,67.78) 42.89,68.17 42.78,68.28 42,68.28 41.89,68.4 41.89,68.55 42,68.66 42.78,68.66 42.89,68.78 42.89,68.93 42.78,69.05 41.82,69.05 41.71,69.16 41.71,69.32 41.82,69.43 42.78,69.43 42.89,69.54 42.89,69.89 43.03,70.03 55.76,70.03 56.62,69.17 60.31,69.17 61.63,70.49 66.1,70.49 67.42,69.17 67.42,67.27 R214.2
GPIO_EMC_B1_11: length 36.1
  TOP w0.127: U6.F2 v1(95.49,72.44) ; v1(86.37,76.28) 82.78,76.28 75.8,69.29 66.4,69.29 66,69.7 v1(65.89,69.7) R162.1
  BOTTOM w0.127: v1(86.37,76.28) 87.89,74.75 89.39,74.75 91.04,73.1 93.83,73.1 94.5,72.44 v1(95.49,72.44) ; R162.1 v1(65.89,69.7)
GPIO_EMC_B1_11_P: length 27.9
  TOP w0.127: U101.7 43.28,67 43.54,67.26 43.75,67.26 v1(43.8,67.31)
  BOTTOM w0.127: v1(43.8,67.31) 43.8,68.13 44.3,68.63 45.22,68.63 45.62,69.04 45.95,69.04 46.21,68.79 46.47,68.79 46.58,68.9 46.58,69.06 46.69,69.17 46.85,69.17 46.96,69.06 46.96,68.54 47.07,68.43 47.23,68.43 47.34,68.54 47.34,69.06 47.46,69.17 47.61,69.17 47.73,69.06 47.73,68.54 47.84,68.43 47.99,68.43 48.11,68.54 48.11,69.06 48.22,69.17 48.38,69.17 48.49,69.06 48.49,68.54 48.6,68.43 48.76,68.43 48.87,68.54 48.87,69.06 48.98,69.17 54.59,69.17 55.48,68.28 60.5,68.28 61.14,68.91 63.23,68.91 64.01,69.7 R215.2
GPIO_EMC_B1_12: length 42
  TOP w0.127: v1(88.5,75.26) 87.74,75.26 87.23,74.75 82.81,74.75 76.26,68.2 63.99,68.2 63.79,68.4 v1(63.73,68.4) R959.1 ; U6.G6 v1(97.89,72.44)
  BOTTOM w0.127: R960.1 63.61,68.28 v1(63.73,68.4) ; v1(88.5,75.26) 89.52,75.26 91.27,73.5 93.94,73.5 94.61,72.84 97.49,72.84 v1(97.89,72.44)
GPIO_EMC_B1_13: length 36
  TOP w0.127: R163.1 v1(65.89,68.71) 66.07,68.53 76.05,68.53 82.78,75.26 87.1,75.26 87.65,75.81 v1(89.01,75.81) ; U6.F3 v1(95.49,73.24)
  BOTTOM w0.127: v1(89.01,75.81) 89.7,75.81 91.6,73.9 94.18,73.9 94.84,73.24 v1(95.49,73.24) ; R216.1 65.89,68.53 v1(65.89,68.71)
GPIO_EMC_B1_14: length 41.5
  TOP w0.127: U6.G5 97.09,71.64 86.53,71.64 85.48,70.6 85.48,70.42 85.66,70.24 85.66,70.06 85.48,69.88 85.3,69.88 85.12,70.06 84.94,70.06 77.3,62.41 66.94,62.41 66.17,63.17 65.76,63.17 65.66,63.07 63.4,63.07 62.95,63.52 v1(62.95,63.67) 62.29,63.67 R1229.1
  BOTTOM w0.127: R1231.1 62.37,63.67 v1(62.95,63.67)
GPIO_EMC_B1_15: length 34.5
  TOP w0.127: R1230.1 65.87,65.76 v1(65.89,65.74) 66.2,65.74 67.47,64.47 75.75,64.47 83.72,72.44 94.69,72.44 U6.G2
  BOTTOM w0.127: v1(65.89,65.74) R1232.1
GPIO_EMC_B1_16: length 34.7
  TOP w0.127: R164.1 65.82,62.56 v1(65.94,62.69) 65.94,62.66 66.5,62.11 77.63,62.11 83.74,68.21 83.92,68.21 84.12,68.01 84.3,68.01 84.48,68.19 84.48,68.37 84.27,68.57 84.27,68.75 84.94,69.42 85.45,69.42 87.27,71.24 U6.H1
  BOTTOM w0.127: v1(65.94,62.69) 65.89,62.69 65.77,62.82 R217.1
GPIO_EMC_B1_17: length 34.7
  TOP w0.127: U6.E2 94.69,73.24 83.43,73.24 75.42,65.23 67.75,65.23 66.23,66.75 v1(66.02,66.75) R165.1
  BOTTOM w0.127: v1(66.02,66.75) R165.1
GPIO_EMC_B1_18: length 29.1
  TOP w0.127: R166.1 69.88,67.64 70,67.52 70,67.24 70.13,67.11 70.38,67.11 70.51,67.24 70.51,67.52 70.64,67.64 76.23,67.64 83.03,74.44 U6.D1
GPIO_EMC_B1_19: length 39.2
  TOP w0.127: R167.1 62.97,69.42 63.19,69.21 66.06,69.21 66.35,68.91 75.93,68.91 82.78,75.77 86.67,75.77 v1(87.18,76.28) ; U6.F4 v1(96.29,73.24)
  BOTTOM w0.127: v1(96.29,73.24) 96.07,73.24 95.65,73.66 94.93,73.66 94.26,74.33 91.78,74.33 89.83,76.28 v1(87.18,76.28)
GPIO_EMC_B1_21: length 40.5
  TOP w0.127: U6.K4 v1(97.1,69.23) ; R168.1 62.34,65.11 v1(62.84,65.11) 62.91,65.11 63.07,64.95 65.94,64.95 67.11,63.78 76.38,63.78 v1(83.23,70.63)
  BOTTOM w0.127: v1(62.84,65.11) 62.72,65.23 R219.1 ; v1(97.1,69.23) 96.71,68.84 89.2,68.84 87.86,70.18 83.67,70.18 v1(83.23,70.63)
GPIO_EMC_B1_22: length 37.2
  TOP w0.127: R169.1 65.82,63.58 v1(65.94,63.71) 66.15,63.71 67.09,62.77 76.89,62.77 v1(85.45,71.33) ; v1(96.29,69.25) 96.27,69.23 96.27,69.22 U6.L3
  BOTTOM w0.127: v1(96.29,69.25) 96.28,69.25 95.89,69.64 89.42,69.64 87.74,71.33 v1(85.45,71.33) ; R220.1 v1(65.94,63.71)
GPIO_EMC_B1_23: length 37
  TOP w0.127: U6.F1 83.56,72.84 75.57,64.85 67.7,64.85 66.29,66.26 64.17,66.26 64.03,66.4 64.03,66.48 63.89,66.62 63,66.62 62.85,66.46 v1(62.84,66.46) 62.8,66.42 R170.1
  BOTTOM w0.127: R221.1 62.67,66.63 v1(62.84,66.46)
GPIO_EMC_B1_24: length 37.2
  TOP w0.127: U6.P2 94.7,66.04 93.34,66.04 92.86,65.56 85.81,65.56 84.38,64.13 84.2,64.13 83.99,64.35 83.81,64.35 83.63,64.17 83.63,63.99 83.84,63.77 83.84,63.59 82.18,61.93 79.43,61.93 78.29,60.78 64.12,60.78 63.67,61.23 v1(63,61.23) 62.52,61.23 R171.1
  BOTTOM w0.127: v1(63,61.23) 62.81,61.42 R222.1
GPIO_EMC_B1_25: length 38
  TOP w0.127: v1(90.01,67.93) 89.26,67.19 83.44,67.19 78.06,61.8 66.25,61.8 65.98,62.07 63.12,62.07 v1(63.09,62.1) 62.63,62.56 R172.1 ; U6.N3 95.52,67.6 95.51,67.6 v1(95.49,67.63)
  BOTTOM w0.127: R223.1 62.88,62.31 v1(63.09,62.1) ; v1(90.01,67.93) 90.3,68.23 93.68,68.23 94.28,67.63 v1(95.49,67.63)
GPIO_EMC_B1_26: length 35
  TOP w0.127: U6.N4 96.29,66.84 93.33,66.84 92.74,66.25 85.02,66.25 82.53,63.76 82.53,63.07 81.77,62.31 79.1,62.31 78.08,61.29 66.02,61.29 v1(65.89,61.42) 65.77,61.55 R173.1
  BOTTOM w0.127: R224.1 v1(65.89,61.42)
GPIO_EMC_B1_26_P: length 25
  TOP w0.127: U106.8 42.78,57.22 42.56,57.45 v1(42.56,57.49)
  BOTTOM w0.127: v1(42.56,57.49) 43.92,58.84 59.07,58.84 60.99,60.76 63.23,60.76 63.24,60.77 63.25,60.77 63.89,61.42 R224.2
GPIO_EMC_B1_27: length 36.2
  TOP w0.127: U6.J3 v1(95.5,70.04) ; v1(84.56,71.2) 76.66,63.3 v1(67.42,63.3) 67.04,63.3 65.94,64.39 R174.1
  BOTTOM w0.127: v1(95.5,70.04) 89.66,70.04 87.86,71.83 85.2,71.83 v1(84.56,71.2) ; R225.1 v1(67.42,63.3)
GPIO_EMC_B1_27_P: length 27.3
  TOP w0.127: v1(43.28,57.41) U106.7
  BOTTOM w0.127: v1(43.28,57.41) 44.38,58.5 59.24,58.5 60.99,60.25 63.33,60.25 63.99,60.91 66.42,60.91 R225.2
GPIO_EMC_B1_28: length 33.2
  TOP w0.127: U6.F5 v1(97.09,73.24) ; R175.1 70.28,70.18 v1(70.51,70.18) 75.7,70.18 82.96,77.45 87.71,77.45 v1(88.37,76.79)
  BOTTOM w0.127: v1(88.37,76.79) 89.79,76.79 91.91,74.66 94.44,74.66 95.1,73.99 95.74,73.99 96.1,73.64 96.69,73.64 v1(97.09,73.24) ; R226.1 70.59,70.1 v1(70.51,70.18)
GPIO_EMC_B1_28_P: length 38.4
  TOP w0.127: U103.8 42.78,60.55 42.39,60.94 v1(42.25,60.94)
  BOTTOM w0.127: v1(42.25,60.94) 43.29,59.9 58.65,59.9 60.56,61.8 60.56,62.44 60.95,62.82 63.03,62.82 63.94,61.92 66.35,61.92 66.78,62.35 66.78,63.83 67.66,64.71 70.58,64.71 71.1,65.23 71.1,67.9 70.59,68.4 R226.2
GPIO_EMC_B1_29: length 34.8
  TOP w0.127: U6.E4 v1(96.29,74.04) ; R176.1 68.18,69.8 v1(68.41,70.03) 68.78,69.66 75.61,69.66 82.78,76.83 v1(87.64,76.83)
  BOTTOM w0.127: v1(68.41,70.03) 69.05,70.03 R227.1 ; v1(87.64,76.83) 87.65,76.83 88.12,77.29 89.91,77.29 92.17,75.04 94.56,75.04 95.23,74.37 95.84,74.37 96.18,74.04 v1(96.29,74.04)
GPIO_EMC_B1_29_P: length 38.3
  TOP w0.127: v1(43.08,60.91) 43.28,60.71 U103.7
  BOTTOM w0.127: v1(43.08,60.91) 43.08,60.86 43.67,60.28 58.53,60.28 60.18,61.93 60.18,62.59 60.79,63.2 63.18,63.2 64.15,62.22 66.22,62.22 66.43,62.42 66.43,64.11 67.42,65.1 70.47,65.1 70.8,65.43 70.8,67.57 69.82,68.54 R227.2
GPIO_EMC_B1_30_P: length 31
  TOP w0.14: R177.1 v1(73.77,76.66) ; v1(85.88,69.16) 87.55,70.84 94.69,70.84 U6.H2
  L3_INT_1 w0.14: v1(73.77,76.66) 77.6,76.66 81.24,73.03 81.24,71.15 82.66,69.73 84.27,69.73 84.4,69.6 84.4,69.39 84.52,69.27 84.69,69.27 84.81,69.39 84.81,69.6 84.94,69.73 85.31,69.73 v1(85.88,69.16)
  BOTTOM w0.14: R177.1 v1(73.77,76.66) R2114.1
GPIO_EMC_B1_31_P: length 28.1
  TOP w0.14: R178.1 v1(75.92,76.15) ; v1(85.22,68.85) 85.49,68.58 86.62,68.58 86.63,68.59 86.81,68.59 88.26,70.04 94.46,70.04 94.46,70.04 94.69,70.04 U6.J2
  L3_INT_1 w0.14: v1(75.92,76.15) 77.54,76.15 80.8,72.89 80.8,70.89 82.85,68.85 83.32,68.85 83.45,68.97 83.45,69.12 83.57,69.24 83.74,69.24 83.86,69.12 83.86,68.97 83.99,68.85 v1(85.22,68.85)
  BOTTOM w0.14: R2115.1 v1(75.92,76.15) R178.1
GPIO_EMC_B1_32_P: length 30.1
  TOP w0.14: R179.1 v1(73.77,75.64) ; U6.J1 87.96,70.44 v1(86.59,69.06)
  L3_INT_1 w0.14: v1(73.77,75.64) 74.18,75.64 74.46,75.36 75.06,75.36 75.34,75.64 77.33,75.64 80.46,72.52 80.46,70.53 82.63,68.35 86.32,68.35 86.59,68.63 v1(86.59,69.06)
  BOTTOM w0.14: R2118.1 v1(73.77,75.64) R179.1
GPIO_EMC_B1_33_P: length 26.9
  TOP w0.14: R180.1 v1(75.92,75.14) ; U6.K1 88.35,69.64 v1(86.82,68.11)
  L3_INT_1 w0.14: v1(75.92,75.14) 75.93,75.15 77.26,75.15 79.98,72.43 79.98,70.4 82.61,67.77 86.48,67.77 v1(86.82,68.11)
  BOTTOM w0.14: R2121.1 v1(75.92,75.14) R2119.1
GPIO_EMC_B1_34_P: length 31.1
  TOP w0.14: v1(87.53,68.06) 87.88,68.4 88.3,68.4 89.21,69.32 93.68,69.32 93.76,69.24 94.69,69.24 U6.L2 ; R181.1 v1(73.77,74.63)
  L3_INT_1 w0.14: v1(73.77,74.63) 74.31,74.63 74.43,74.51 74.43,74.32 74.55,74.2 74.73,74.2 74.85,74.32 74.85,74.51 74.97,74.63 77.12,74.63 79.6,72.15 79.6,70.14 82.33,67.41 86.89,67.41 v1(87.53,68.06)
  BOTTOM w0.14: R2122.1 v1(73.77,74.63) R2124.1
GPIO_EMC_B1_35_P: length 27.1
  TOP w0.14: U6.L1 93.66,68.84 93.49,69 89.48,69 v1(88.4,67.92) ; R182.1 v1(75.92,74.12)
  L3_INT_1 w0.14: v1(75.92,74.12) 77.09,74.12 79.22,71.99 79.22,69.76 81.94,67.03 87.51,67.03 v1(88.4,67.92)
  BOTTOM w0.14: R2123.1 v1(75.92,74.12) R2125.1
GPIO_EMC_B1_36_P: length 31.1
  TOP w0.14: v1(73.77,73.1) 73.67,73 R183.1 ; U6.M1 93.4,68.04 93.07,68.37 91.38,68.37 v1(90.66,67.64)
  L3_INT_1 w0.14: v1(73.77,73.1) 74.28,73.61 74.59,73.61 74.71,73.49 74.71,73.3 74.84,73.18 75.01,73.18 75.13,73.3 75.13,73.49 75.25,73.61 76.97,73.61 78.78,71.8 78.78,69.52 81.67,66.63 89.64,66.63 v1(90.66,67.64)
  BOTTOM w0.14: R2126.1 74.15,73.61 73.77,73.23 v1(73.77,73.1) 73.39,73.1 73.13,73.36 R2128.1
GPIO_EMC_B1_37_P: length 26.7
  TOP w0.14: v1(93.58,67.24) U6.N1 ; v1(75.92,73.1) 75.9,73.1 75.7,72.9 R184.1
  L3_INT_1 w0.14: v1(93.58,67.24) 93.58,66.8 93.02,66.25 81.51,66.25 78.4,69.36 78.4,71.72 77.02,73.1 v1(75.92,73.1)
  BOTTOM w0.14: R2129.1 v1(75.92,73.1) R2127.1
GPIO_EMC_B1_38_P: length 28.6
  TOP w0.14: v1(75.92,77.14) 75.9,77.14 75.88,77.17 R185.1 ; U6.M2 94.69,68.44 94.13,68.44 93.57,68.44 93.32,68.68 89.97,68.68 v1(89.22,67.94)
  L3_INT_1 w0.14: v1(89.22,67.94) 89.22,68.84 87.93,70.13 82.89,70.13 81.69,71.33 81.69,73.18 77.83,77.04 76.02,77.04 v1(75.92,77.14)
  BOTTOM w0.14: R2130.1 75.95,77.17 v1(75.92,77.14) 75.9,77.14 75.88,77.17 R185.1
GPIO_EMC_B1_39_P: length 47.4
  TOP w0.14: v1(84.31,64.85) 85.35,65.89 92.74,65.89 93.29,66.44 U6.P1
  BOTTOM w0.14: v1(84.31,64.85) 84.31,64.47 83.8,63.96 R186.1 83.41,66.12 83.29,66.25 82.15,66.25 82.02,66.38 82.02,66.63 82.15,66.76 84.13,66.76 84.26,66.89 84.26,67.14 84.13,67.27 82.15,67.27 82.02,67.39 82.02,67.65 82.15,67.77 84.13,67.77 84.26,67.9 84.26,68.16 84.13,68.28 82.15,68.28 82.02,68.41 82.02,68.66 82.15,68.79 84.13,68.79 84.26,68.92 84.26,69.17 84.13,69.3 82.15,69.3 82.02,69.43 82.02,70.18 85.87,74.03 85.87,76.47 88.5,79.1 88.5,81.86 R332.1
GPIO_EMC_B1_40_P: length 66.6
  TOP w0.14: R187.1 81.77,64.85 v1(82.02,65.1) 83.67,66.75 90.53,66.75 91.83,68.05 92.77,68.05 93.18,67.64 94.69,67.64 U6.N2
  BOTTOM w0.14: R333.1 86.33,83.38 85.96,83.01 85.96,82.25 86.21,81.99 87.09,81.99 87.48,81.61 87.48,80.33 87.23,80.08 87.23,79.82 87.36,79.7 87.99,79.7 88.12,79.57 88.12,79.32 87.99,79.19 86.98,79.19 86.85,79.06 86.85,77.96 85.54,76.65 85.54,74.34 81.39,70.18 80.63,70.18 80.5,70.06 80.5,69.8 80.63,69.67 81.39,69.67 81.51,69.55 81.51,69.29 81.39,69.17 80.63,69.17 80.5,69.04 80.5,68.79 80.63,68.66 81.39,68.66 81.51,68.53 81.51,68.28 81.39,68.15 80.63,68.15 80.5,68.02 80.5,67.77 80.63,67.64 81.39,67.64 81.51,67.52 81.51,67.26 81.39,67.13 80.63,67.13 80.5,67.01 80.5,66.75 80.63,66.63 81.39,66.63 81.51,66.5 81.51,66.25 81.39,66.12 80.63,66.12 80.5,65.99 80.5,65.75 80.64,65.61 81.88,65.61 82.02,65.47 v1(82.02,65.1) 76.45,65.1 76.31,65.24 76.31,65.94 76.45,66.08 76.93,66.08 77.07,66.22 77.07,66.5 76.93,66.64 76.45,66.64 76.31,66.78 76.31,67.06 76.45,67.2 76.93,67.2 77.07,67.34 77.07,67.62 76.93,67.76 76.45,67.76 76.31,67.9 76.31,68.18 76.45,68.32 77.11,68.32 77.25,68.46 77.25,68.73 77.11,68.87 76.45,68.87 76.31,69.01 76.31,71.83 76.05,72.09 R2133.1
GPIO_EMC_B1_41_P: length 30.3
  TOP w0.127: R1169.1 81.76,60.91 v1(81.77,60.91)
  TOP w0.14: U6.R1 93.35,65.64 92.94,65.23 90.79,65.23 84.94,64.09 82.59,61.73 R188.1 v1(81.77,60.91)
  L3_INT_1 w0.14: v1(81.77,60.91) 81.26,61.42 81.26,65.74 78.09,68.91 78.09,71.17 v1(76.82,72.44)
  BOTTOM w0.14: v1(76.82,72.44) 77.17,72.09 R2131.1
GPIO_EMC_B2_02: length 31.3
  TOP w0.127: v1(97.09,66.04) U6.P5
  BOTTOM w0.127: R1330.1 R1329.1
  BOTTOM w0.14: v1(97.09,66.04) 97.09,66.04 96.79,65.74 96.2,65.74 95.89,65.43 95.89,65 94.6,63.71 91.55,63.71 87.86,60.02 85.07,60.02 81.51,56.47 77.58,56.47 76.87,57.18 72.93,57.18 72.62,57.48 R1329.1
GPIO_EMC_B2_03: length 32
  TOP w0.14: U6.T5 97.09,64.44 97.09,62.65 94.98,60.53 v1(94.98,59.43) ; R2596.1 v1(80.12,55.96)
  BOTTOM w0.14: v1(94.98,59.43) 94.89,59.51 86.44,59.51 85.79,58.86 85.61,58.86 85.23,59.24 85.05,59.24 84.87,59.06 84.87,58.88 85.5,58.25 85.5,58.07 85.32,57.89 85.14,57.89 84.43,58.6 84.25,58.6 84.07,58.42 84.07,58.24 84.78,57.53 84.78,57.35 84.6,57.17 84.42,57.17 83.73,57.87 83.55,57.87 83.37,57.69 83.37,57.51 84.05,56.82 84.05,56.59 83.42,55.96 83.22,55.96 83.08,56.1 83.08,56.71 82.94,56.85 82.66,56.85 82.52,56.71 82.52,56.1 82.38,55.96 v1(80.12,55.96) R2596.1
GPIO_EMC_B2_04: length 25.4
  TOP w0.14: U6.R3 v1(95.49,65.23) ; R2595.1 77.88,56.98 v1(77.88,56.97)
  BOTTOM w0.14: v1(95.49,65.23) 95.48,65.23 95.1,65.23 93.96,64.09 91.29,64.09 87.61,60.4 84.82,60.4 84.61,60.2 84.42,60.2 84.3,60.32 84.1,60.32 83.9,60.12 83.9,59.93 84.02,59.81 84.02,59.61 83.82,59.41 83.63,59.41 83.44,59.59 83.24,59.59 83.05,59.4 83.05,59.2 83.23,59.02 83.23,58.82 83.03,58.62 82.84,58.62 82.65,58.8 82.45,58.8 82.26,58.61 82.26,58.41 82.44,58.22 82.44,58.03 82.15,57.74 81.27,57.74 81.13,57.6 81.13,57.32 81,57.18 80.72,57.18 80.58,57.32 80.58,57.6 80.44,57.74 78.85,57.74 78.6,57.49 R2597.1 v1(77.88,56.97)
GPIO_EMC_B2_05: length 28.3
  TOP w0.14: v1(93.96,59.01) 93.96,60.66 96.29,62.99 96.29,64.2 96.29,64.2 96.29,64.44 U6.T4 ; v1(76.05,56.21) R189.1
  BOTTOM w0.14: v1(93.96,59.01) 87.13,59.01 83.45,55.32 77.45,55.32 76.56,56.21 v1(76.05,56.21) R228.1
GPIO_EMC_B2_06: length 32.5
  TOP w0.14: v1(95.21,58.49) 95.23,58.51 95.23,58.92 97.89,61.58 97.89,64.44 U6.T6 ; R190.1 v1(73.64,55.7)
  BOTTOM w0.14: R190.1 v1(73.64,55.7) 76.31,55.7 77.07,54.94 83.7,54.94 87.28,58.52 95.17,58.52 v1(95.21,58.49)
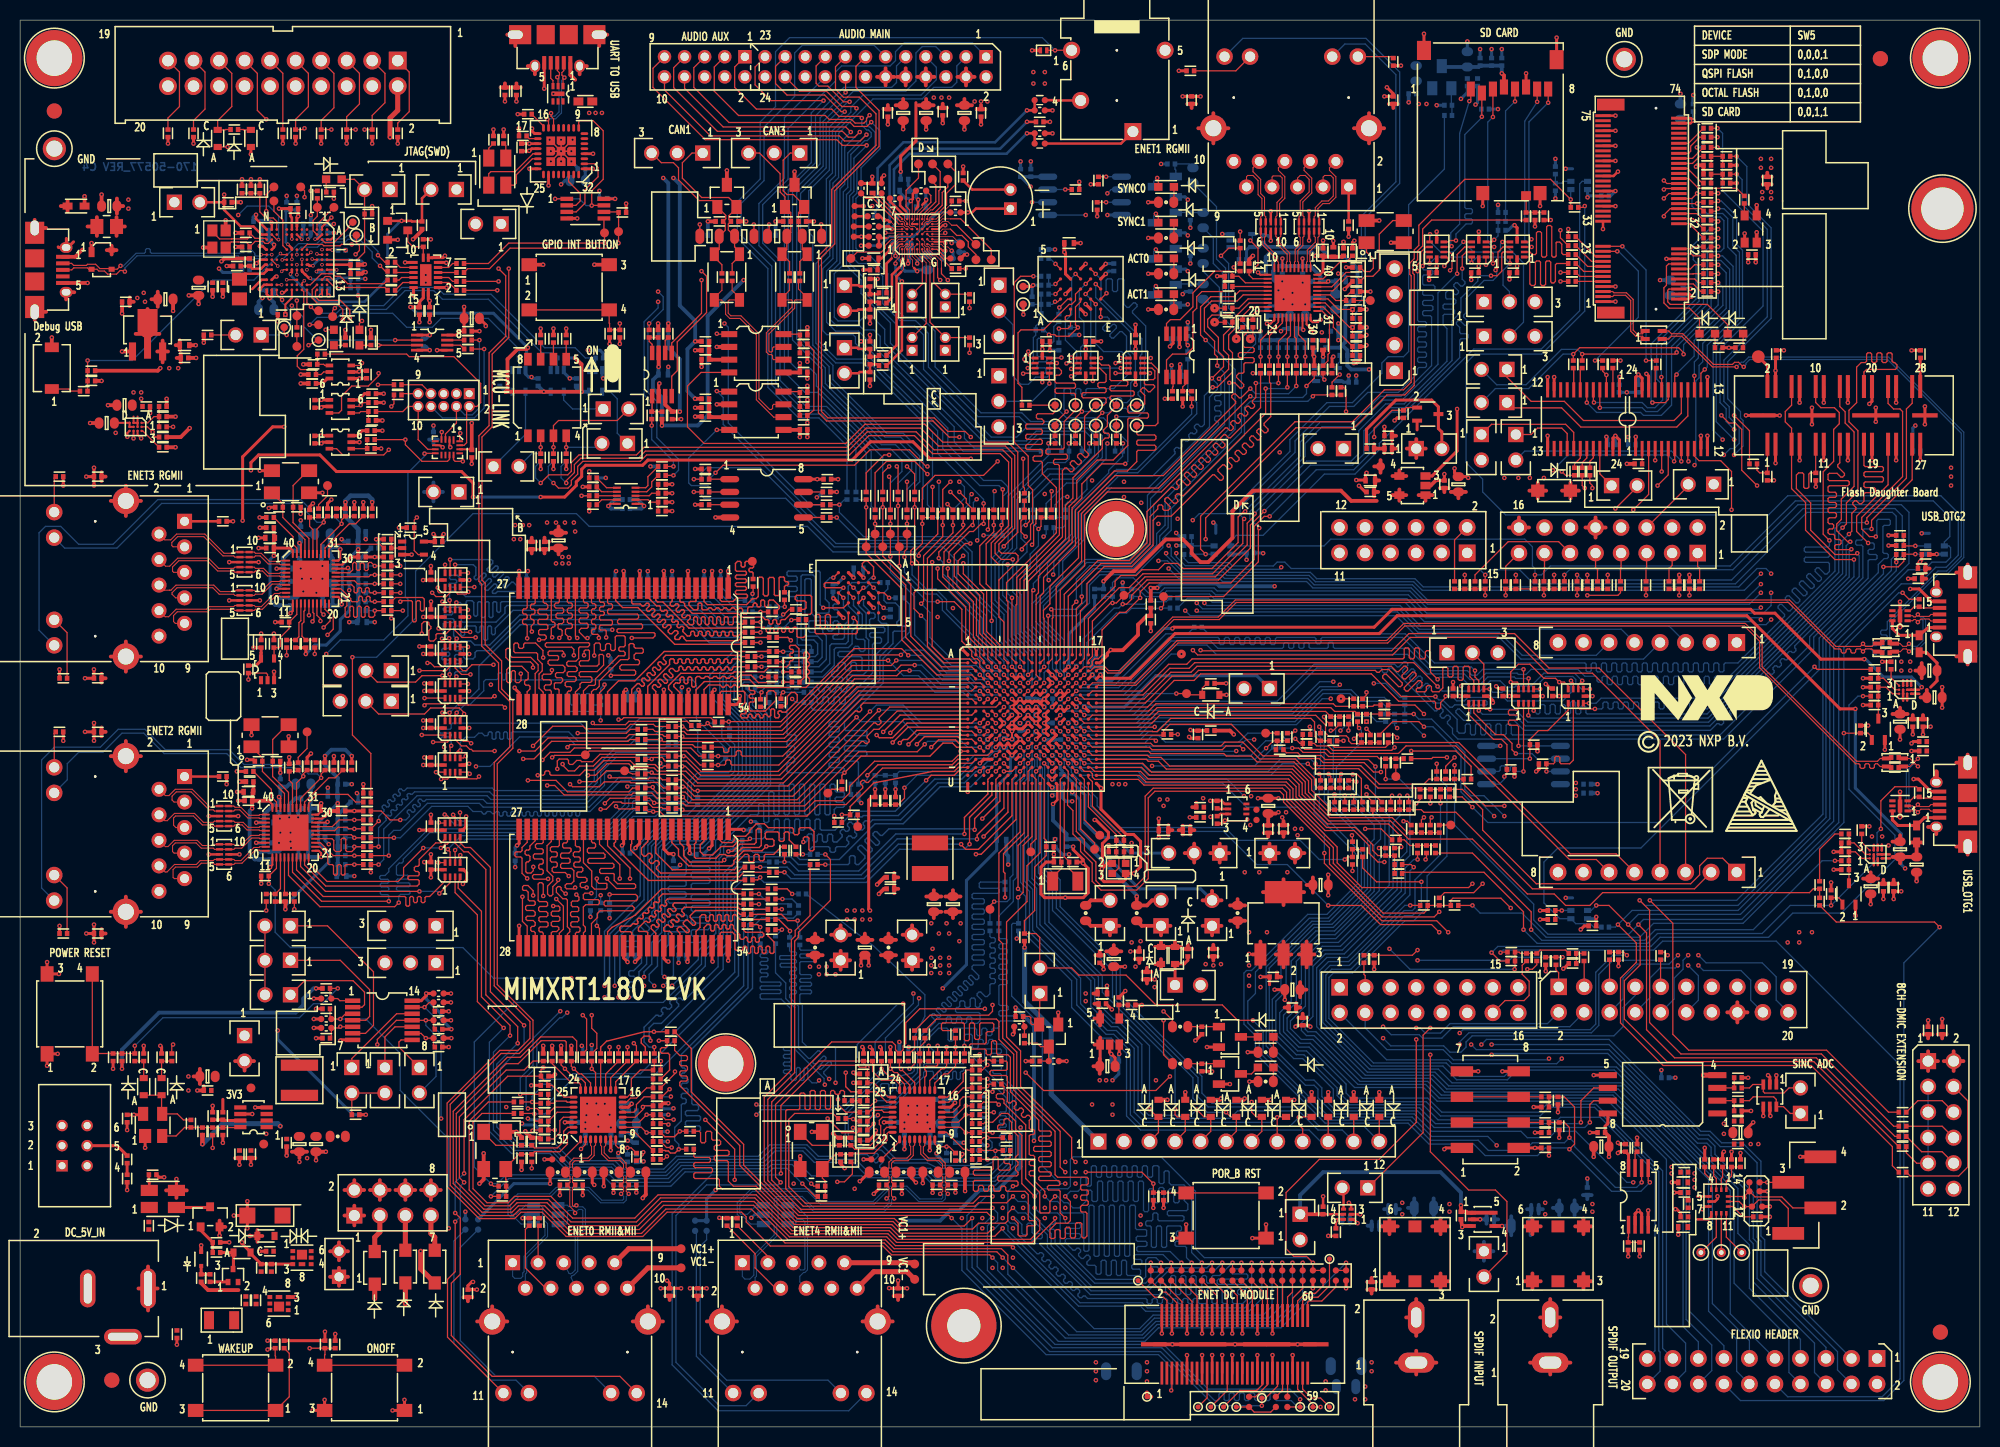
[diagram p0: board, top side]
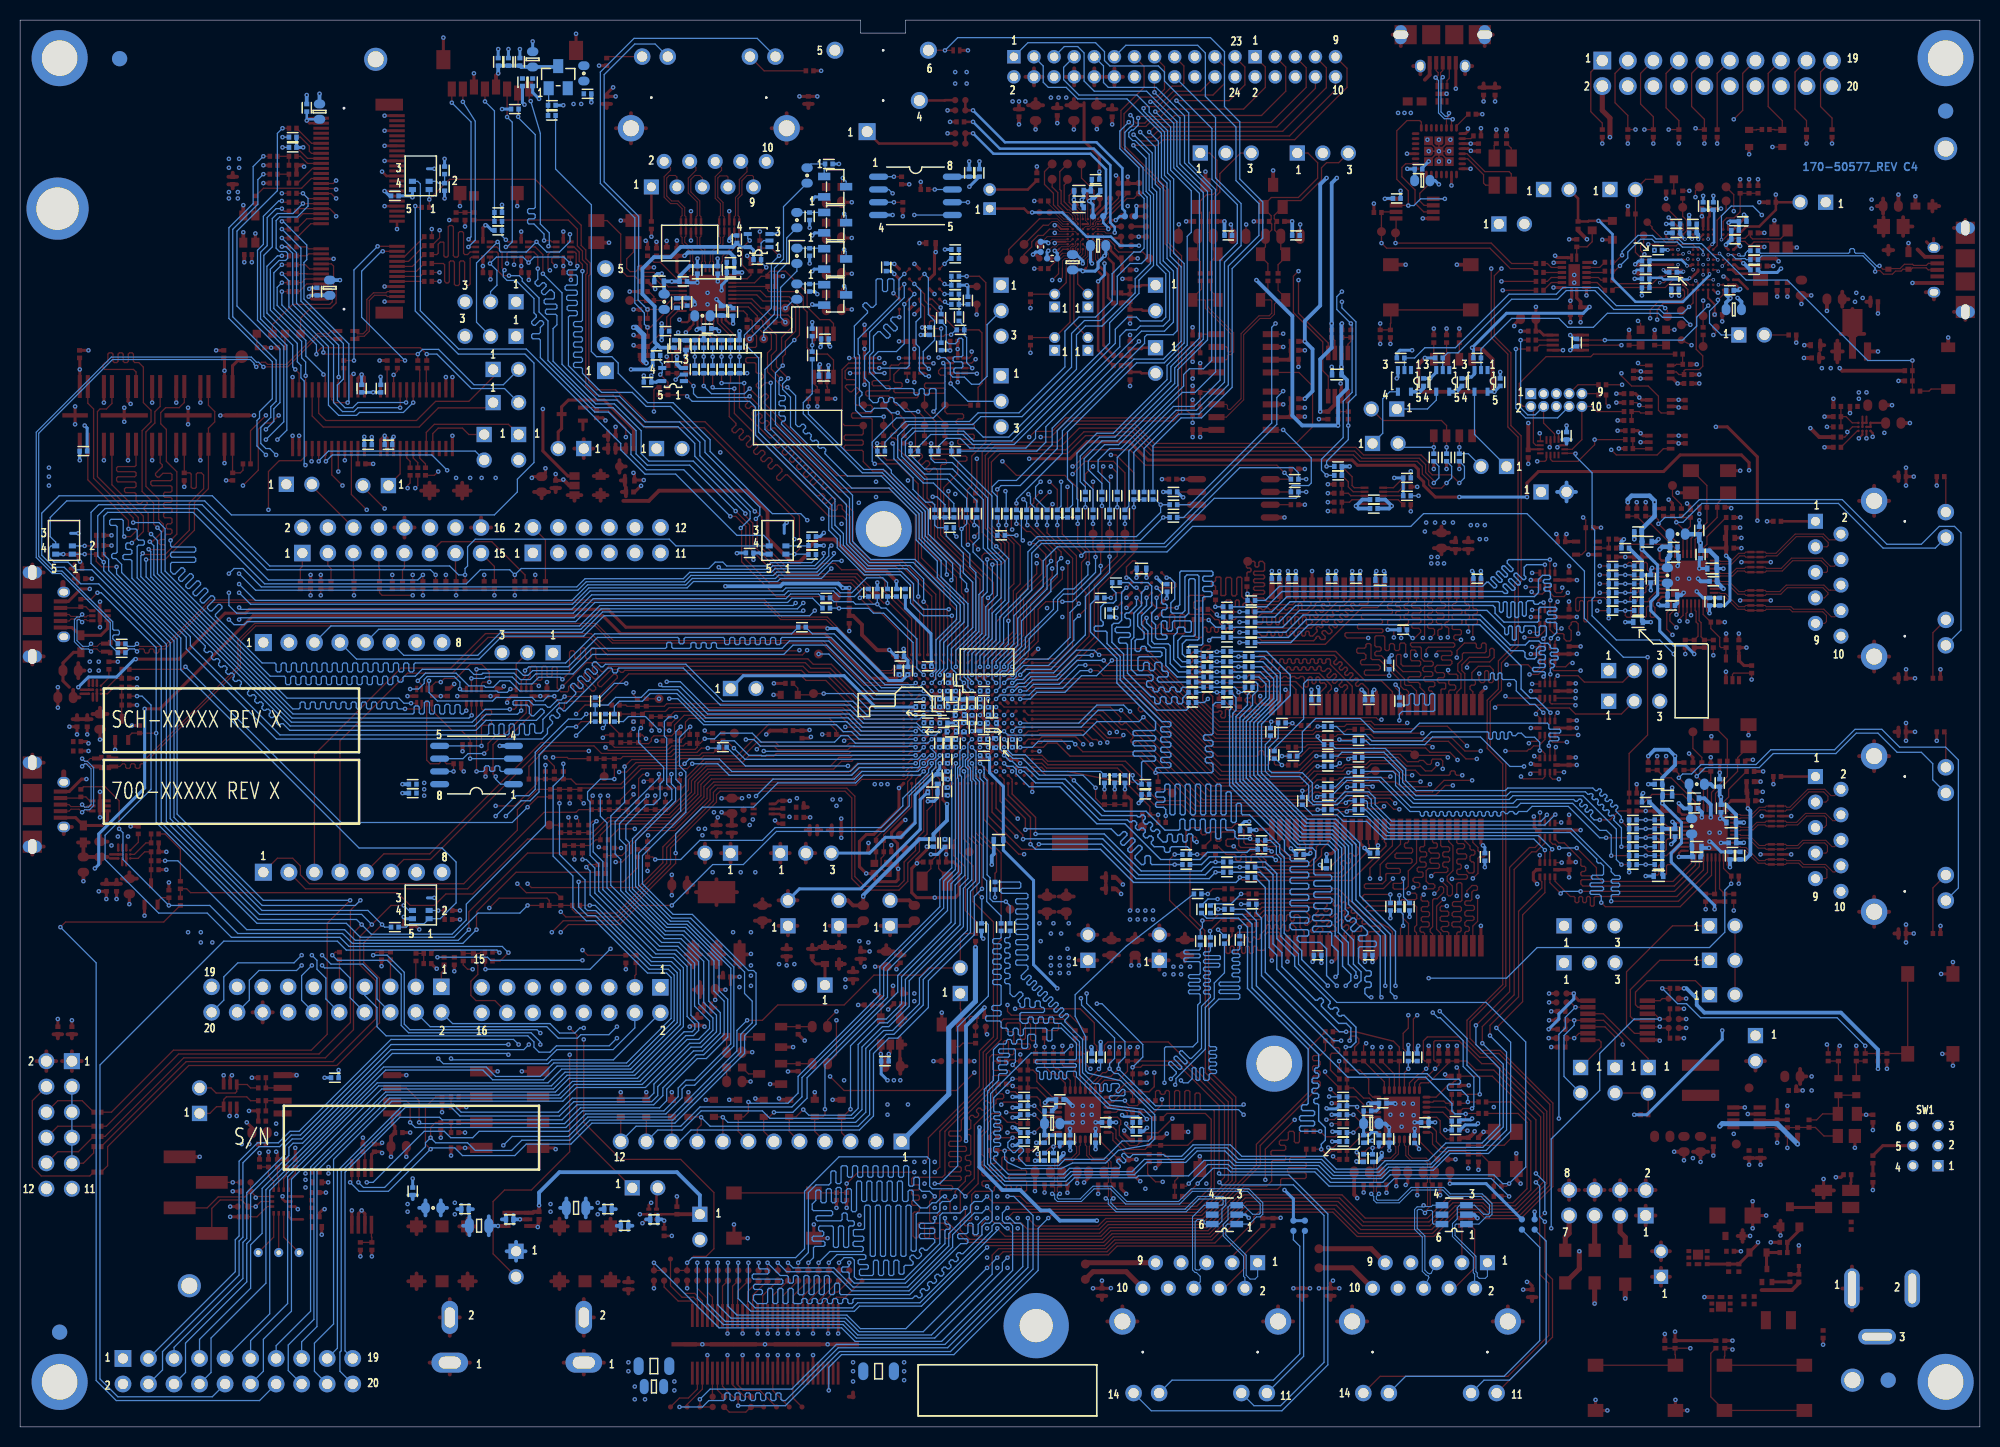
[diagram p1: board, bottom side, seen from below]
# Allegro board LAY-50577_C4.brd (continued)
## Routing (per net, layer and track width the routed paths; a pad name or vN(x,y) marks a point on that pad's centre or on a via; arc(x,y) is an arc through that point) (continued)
GPIO_EMC_B2_07: length 31.7
  TOP w0.14: U6.T7 98.69,64.44 98.69,60.82 95.36,57.48 94.09,57.48 93.63,57.94 v1(93.63,57.99) ; R191.1 v1(76.05,55.2)
  BOTTOM w0.14: v1(93.63,57.99) 87.38,57.99 83.95,54.56 76.69,54.56 v1(76.05,55.2) R191.1
GPIO_EMC_B2_08: length 31.3
  TOP w0.14: v1(94.47,57.99) 94.47,60.66 96.69,62.88 U6.U4 ; v1(73.64,54.69) 73.39,54.43 R192.1
  BOTTOM w0.14: v1(94.47,57.99) 93.96,57.48 87.51,57.48 84.21,54.18 74.02,54.18 73.64,54.56 v1(73.64,54.69) R231.1
GPIO_EMC_B2_09: length 33.9
  TOP w0.14: U6.U5 97.49,62.28 v1(95.74,60.53) ; R193.1 v1(73.51,53.04)
  L3_INT_1 w0.14: v1(95.74,60.53) 93.83,60.53 92.82,59.51 81.9,59.51 76.56,54.18 74.66,54.18 v1(73.51,53.04)
  BOTTOM w0.14: v1(73.51,53.04) 74.5,52.05 76.4,52.05 R232.1
GPIO_EMC_B2_10: length 32.5
  TOP w0.14: U6.U6 98.29,61.18 v1(95.87,58.75) ; R194.1 v1(75.85,52.53)
  L3_INT_1 w0.14: v1(75.85,52.53) 78.06,52.53 82,56.47 95.36,56.47 95.87,56.97 v1(95.87,58.75)
  BOTTOM w0.14: v1(75.85,52.53) 76.81,52.53 R233.1
GPIO_EMC_B2_11: length 35.8
  TOP w0.14: R195.1 v1(73.51,52.02) ; v1(97.89,66.84) 97.89,66.84 U6.P6
  L3_INT_1 w0.14: v1(73.51,52.02) 74.02,52.02 75.55,53.55 76.84,53.55 79.76,56.47 80.37,56.47 82.78,58.88 92.94,58.88 94.09,60.02 95.99,60.02 96.25,60.28 96.25,64.27 96.7,64.72 96.7,66.2 96.93,66.43 97.49,66.43 v1(97.89,66.84)
  BOTTOM w0.14: v1(73.51,52.02) R195.1
GPIO_EMC_B2_12: length 34.1
  TOP w0.14: R196.1 v1(75.79,51.51) ; U6.R5 v1(97.09,65.24)
  L3_INT_1 w0.14: v1(75.79,51.51) 77.76,51.51 82.2,55.96 95.61,55.96 96.37,56.72 96.37,58.68 96.5,58.81 96.75,58.81 96.88,58.93 96.88,59.19 96.75,59.32 96.5,59.32 96.37,59.44 96.37,59.66 96.88,60.17 96.88,64.09 97.09,64.3 v1(97.09,65.24)
  BOTTOM w0.14: R196.1 v1(75.79,51.51)
GPIO_EMC_B2_13: length 39.8
  TOP w0.14: v1(77.36,50.38) 76.37,50.38 75.75,51.01 R198.1 ; v1(97.89,66.04) 97.89,66.04 U6.R6
  L3_INT_1 w0.14: v1(77.36,50.38) 82.43,55.45 95.74,55.45 97.5,57.22 97.5,57.73 97.38,57.86 97.14,57.86 97.01,57.98 97.01,58.24 97.14,58.36 97.33,58.36 97.49,58.52 97.49,65.64 v1(97.89,66.04)
  BOTTOM w0.127: v1(77.36,50.38) 77.36,49.7 77.58,49.48 R238.1
GPIO_EMC_B2_14: length 39.2
  TOP w0.14: R200.1 75.5,50.5 76.6,49.39 v1(76.6,49.35) ; v1(99.49,67.64) 99.49,67.64 U6.N8
  L3_INT_1 w0.14: v1(76.6,49.35) 77.72,49.35 82.84,54.46 96.02,54.46 98.66,57.1 98.66,65.74 99.1,66.58 99.1,67.24 v1(99.49,67.64)
  BOTTOM w0.127: v1(76.6,49.35) 76.6,49.34 76.56,49.3 R240.1
GPIO_EMC_B2_15: length 35.5
  TOP w0.14: U6.R4 v1(96.29,65.24) ; v1(73.64,49.74) 73.39,49.99 R201.1
  L3_INT_1 w0.14: v1(73.64,49.74) 72.88,50.5 72.88,53.16 74.4,54.69 76.43,54.69 81.9,60.15 92.69,60.15 95.23,62.69 95.23,64.18 v1(96.29,65.24)
  BOTTOM w0.127: R242.1 v1(73.64,49.74)
GPIO_EMC_B2_16: length 37
  TOP w0.14: R202.1 v1(75.8,49.48) ; U6.R7 98.69,65.24 v1(97.89,65.24)
  L3_INT_1 w0.14: v1(97.89,65.24) 98.15,64.98 98.15,57.23 95.87,54.94 82.61,54.94 77.53,49.86 76.89,49.86 76.64,50.12 76.1,50.12 75.8,49.81 v1(75.8,49.48)
  BOTTOM w0.127: v1(75.8,49.48) 75.16,48.85 R244.1
GPIO_EMC_B2_17: length 31.4
  TOP w0.14: v1(76.82,53.04) 76.31,53.55 R204.1 ; v1(95.1,56.99) 95.63,56.99 99.09,60.46 U6.U7
  L3_INT_1 w0.14: v1(76.82,53.04) 77.91,53.04 81.86,56.99 v1(95.1,56.99)
  BOTTOM w0.14: R246.1 v1(76.82,53.04)
GPIO_EMC_B2_18: length 19.4
  TOP w0.127: v1(96.92,52.28) 96.5,51.86 TP13.1 ; U6.P8 v1(99.49,66.04)
  BOTTOM w0.127: R248.1 96.5,51.86 v1(96.92,52.28) 98.2,52.28 98.49,52.57 98.49,54.65 98.79,54.94 98.79,64.34 99.09,64.65 99.09,65.04 99.07,65.06 99.07,65.41 99.09,65.43 99.09,65.64 v1(99.49,66.04)
GPIO_EMC_B2_19: length 13
  TOP w0.127: U6.U8 99.89,59.1 97.85,57.05 97.85,55.25 98,55.1 v1(98,52.7)
  BOTTOM w0.127: v1(98,52.7) R250.1
GPIO_EMC_B2_20: length 16.6
  TOP w0.127: U6.R8 v1(99.49,65.24)
  BOTTOM w0.127: v1(99.49,65.24) 99.49,64.54 99.17,64.21 99.17,54.69 98.83,54.35 98.83,52.29 97.39,50.85 R252.1
GPIO_SD_B1_00: length 133.2
  TOP w0.127: U63.8 143.88,116.92 143.49,116.54 v1(143.49,115.27) ; v1(122.84,90.88) 122.84,90.68 122.09,89.93 122.09,87.78 118.92,84.6 111.93,84.6 110.09,82.76 TP94.1 109.07,81.99 v1(108.69,81.99) 108.51,81.99 106.69,80.18 106.69,76.67 106.29,76.27 U6.B16
  L3_INT_1 w0.127: v1(108.69,81.99) 109.82,83.12 111.5,83.12 111.87,82.76 117.07,82.76 v1(117.84,81.99)
  BOTTOM w0.127: J62.3 164.06,79.71 139.34,79.71 137.31,81.74 118.09,81.74 v1(117.84,81.99) ; v1(122.84,90.88) 122.84,90.93 128.02,96.11 132.44,96.11 133.2,96.88 133.2,99.14 135.87,101.81 137.73,101.81 141.97,106.05 141.97,109.3 141.59,109.68 141.59,110.59 141.71,110.72 142.6,110.72 142.73,110.85 142.73,111.1 142.6,111.23 141.71,111.23 141.59,111.36 141.59,111.61 141.71,111.74 142.73,111.74 142.86,111.86 142.86,112.12 142.73,112.25 141.97,112.25 141.84,112.37 141.84,112.85 142.13,113.14 142.31,113.14 142.76,112.69 142.94,112.69 143.12,112.87 143.12,113.04 142.66,113.5 142.66,113.68 142.84,113.86 143.02,113.86 143.35,113.53 143.53,113.53 143.76,113.76 143.76,113.94 143.49,114.21 v1(143.49,115.27) ; R64.2 R751.2 v1(108.69,81.99)
GPIO_SD_B1_01: length 122.6
  TOP w0.127: U63.7 143.74,117.42 142.98,116.66 v1(142.98,114.76) ; v1(113.52,81.46) 113.52,81.49 113.77,81.75 TP95.1 119.74,82.63 123.21,86.09 123.21,89.36 v1(123.29,89.45) ; U6.D15 v1(105.89,74.84)
  L3_INT_1 w0.127: v1(113.52,81.46) 115.7,81.46 v1(115.93,81.23)
  BOTTOM w0.127: J62.4 161.52,76.41 149.33,76.41 147.05,78.69 138.92,78.69 136.89,80.72 116.44,80.72 v1(115.93,81.23) ; v1(105.89,74.84) 106.15,75.1 106.15,78.06 109.07,80.98 110.09,80.98 110.57,81.46 v1(113.52,81.46) 113.54,81.49 R757.2 ; v1(142.98,114.76) 141.08,112.85 141.08,105.74 137.52,102.19 135.62,102.19 132.96,99.53 129.53,99.53 127.87,97.87 127.87,96.6 122.37,91.1 122.37,90.38 v1(123.29,89.45)
GPIO_SD_B1_02: length 126.9
  TOP w0.127: U6.D14 v1(105.09,74.84) ; v1(146.35,114.56) 146.98,114.56 147.43,115.01 147.43,116.79 147.56,116.92 U64.8 ; v1(109.71,81.87) 110.1,81.87 110.6,82.37 110.6,82.76 112.13,84.29 119.25,84.29 122.41,87.46 122.41,89.74 v1(123.81,91.14)
  L3_INT_1 w0.127: v1(117.07,81.23) 116.31,81.99 109.83,81.99 v1(109.71,81.87)
  BOTTOM w0.127: v1(117.07,81.23) 117.2,81.1 137.04,81.1 139.08,79.07 147.17,79.07 149.46,76.79 156.83,76.79 J62.6 ; v1(109.71,81.87) R65.2 ; v1(109.71,81.87) 111.87,81.87 112.12,82.12 114.03,82.12 R755.2 ; v1(109.71,81.87) 109.32,81.49 108.84,81.49 105.77,78.41 105.77,75.52 v1(105.09,74.84) ; v1(146.35,114.56) 145.32,114.56 145.04,114.28 145.04,114.02 143.36,112.35 143.36,110.95 142.47,110.06 142.47,106.12 137.78,101.42 136,101.42 133.71,99.14 133.71,96.83 132.59,95.71 128.38,95.71 v1(123.81,91.14)
GPIO_SD_B1_03: length 125
  TOP w0.127: v1(146.8,115.11) 147.05,115.36 147.05,116.92 147.55,117.42 U64.7 ; U6.C15 105.89,75.64 106.48,75.64 106.69,75.85 106.69,76.2 106.92,76.44 107.28,76.44 107.65,76.81 107.65,79.3 109.42,81.07 110.01,81.07 v1(111.45,82.5) 111.45,83.1 112.34,83.99 120.47,83.99 122.79,86.31 122.79,89.61 123.79,90.62 v1(124.33,90.62)
  L3_INT_1 w0.127: v1(111.45,82.5) 111.57,82.37 116.69,82.37 v1(117.07,81.99)
  BOTTOM w0.127: v1(124.33,90.62) 128.96,95.25 132.69,95.25 134.22,96.78 134.22,98.76 136.46,101 137.82,101 143.24,106.41 143.24,108.16 143.36,108.28 143.97,108.28 144.1,108.41 144.1,108.67 143.97,108.79 143.36,108.79 143.24,108.92 143.24,109.41 142.92,109.73 142.92,109.91 143.09,110.09 143.27,110.09 143.74,109.63 143.92,109.63 144.1,109.81 144.1,109.99 143.63,110.45 143.63,110.63 143.87,110.87 143.87,112.3 145.67,114.09 146.55,114.09 146.92,114.46 146.92,115 v1(146.8,115.11) ; v1(117.07,81.99) 117.66,81.41 137.17,81.41 139.2,79.38 159.32,79.38 J62.5 ; v1(111.45,82.5) 111.31,82.64 R756.2
GPIO_SD_B1_04: length 72.7
  TOP w0.127: U65.8 139.81,116.92 139.67,116.79 139.67,115.64 v1(139.55,115.52) ; v1(121.9,91.1) 121.74,91.1 121.19,90.56 121.19,88.02 118.6,85.42 115.68,85.42 115.17,85.93 113.9,85.93 113.26,85.3 111.61,85.3 111.04,84.72 109.52,84.72 108.95,84.15 108.95,83.64 105.89,80.59 105.89,76.44 U6.B15
  BOTTOM w0.127: v1(139.55,115.52) 139.55,115.27 139.68,115.14 140.44,115.14 140.57,115.02 140.57,114.76 140.44,114.63 139.68,114.63 139.55,114.51 139.55,113.75 139.68,113.63 140.62,113.63 140.77,113.48 140.77,113.25 140.65,113.12 139.68,113.12 139.55,112.99 139.55,112.74 139.68,112.61 140.49,112.61 140.62,112.48 140.62,112.23 140.49,112.1 139.68,112.1 139.55,111.98 139.55,111.72 139.68,111.6 140.44,111.6 140.57,111.47 140.57,111.21 140.44,111.09 139.68,111.09 139.55,110.96 139.55,110.71 139.68,110.58 140.32,110.58 140.44,110.45 140.44,105.62 137.39,102.57 135.36,102.57 132.81,100.02 129.38,100.02 127.36,98 127.36,96.64 121.9,91.17 v1(121.9,91.1)
GPIO_SD_B1_05: length 70.4
  TOP w0.127: U65.7 139.88,117.42 139.37,116.91 139.37,116 139.05,115.68 v1(139.05,115.01) ; v1(121.79,90.36) 121.66,90.23 121.66,87.93 118.64,84.9 111.73,84.9 110.34,83.52 109.36,83.52 106.29,80.45 U6.A16
  BOTTOM w0.127: v1(139.05,115.01) 139.05,110.13 139.17,110 139.81,110 139.93,109.87 139.93,109.62 139.81,109.49 139.17,109.49 139.05,109.36 139.05,109.11 139.17,108.98 139.81,108.98 139.93,108.86 139.93,108.6 139.81,108.47 139.17,108.47 139.05,108.35 139.05,108.09 139.17,107.97 139.81,107.97 139.93,107.84 139.93,107.59 139.81,107.46 139.17,107.46 139.05,107.33 139.05,107.08 139.17,106.95 139.81,106.95 139.93,106.82 139.93,106.57 139.81,106.44 139.17,106.44 139.05,106.32 139.05,106.06 139.17,105.93 139.81,105.93 139.93,105.81 139.93,105.55 139.81,105.43 139.17,105.43 139.05,105.3 139.05,104.85 137.14,102.95 134.09,102.95 132.7,101.55 130.28,101.55 126.85,98.12 126.85,96.98 121.39,91.52 121.39,90.76 v1(121.79,90.36)
HP_DET_B: length 82.5
  TOP w0.127: J101.6 102.99,137 v1(102.98,136.98) D46.1
  BOTTOM w0.127: R2152.2 82.28,97.61 79.48,100.41 77.45,100.41 74.4,103.46 74.4,115.27 71.35,118.32 71.35,121.9 73.64,124.19 73.64,129.87 75.16,131.4 75.16,136.86 76.56,138.25 101.71,138.25 v1(102.98,136.98)
HPOUTL: length 28.4
  TOP w0.081: U369.B5 88.13,119.2 87.88,119.45 87.11,119.45 86.63,119.93
  TOP w0.254: v1(100.18,131.02) C602.1 L37.1 ; 86.63,119.93 86.5,119.93 86.34,120.09 v1(85.99,120.09) 85.96,120.09 85.58,120.47 C600.1
  BOTTOM w0.254: v1(100.18,131.02) 97.01,127.84 87.9,127.84 85.32,125.27 85.32,121.24 85.07,120.98 R2148.1 85.58,120.47 85.96,120.09 v1(85.99,120.09)
HPOUTL_ZOBEL: length 1.3
  TOP w0.254: R2150.1 C600.2
HPOUTR: length 25.2
  TOP w0.081: U369.A5 86.73,119.2 v1(86.72,119.2)
  TOP w0.254: v1(100.18,128.73) C603.1 L38.1 ; C601.1 86.47,119.46 v1(86.72,119.2)
  BOTTOM w0.254: v1(100.18,128.73) 98.15,126.7 88.5,126.7 86.95,125.15 86.95,120.75 R2149.1 87.23,119.84 86.72,119.33 v1(86.72,119.2)
HPOUTR_ZOBEL: length 1.5
  TOP w0.254: C601.2 R2151.1
HW_VER_0: length 5.6
  TOP w0.254: U55.E8 28.69,115.66 28.8,115.55 v4(29.14,115.55)
  BOTTOM w0.254: v4(29.14,115.55) 29.14,115.6 29.68,116.14 32.76,116.14 R862.1 R828.1
HW_VER_1: length 3.2
  TOP w0.254: R827.1 R863.1 32.66,115.66 U55.A8
HW_VER_2: length 6.3
  TOP w0.254: U55.F9 28.04,115.02 28.08,114.98 28.08,114.97 28.35,114.7 28.36,114.7 28.74,114.32 v4(28.89,114.32)
  BOTTOM w0.254: R864.1 R826.1 32.78,114.35 31.66,114.35 31.49,114.19 29.02,114.19 v4(28.89,114.32)
HW_VER_3: length 2.6
  TOP w0.203: U55.B2 29.58,118.2 v4(29.35,118.2)
  BOTTOM w0.254: v4(29.35,118.2) 29.38,118.2 29.83,118.65 R861.1 R825.1
HW_VER_4: length 2.2
  TOP w0.254: v1(25.27,117.64) 25.27,117.39 U55.M5
  BOTTOM w0.381: v1(25.27,117.64) 24.74,118.17 R824.1 R866.1
HW_VER_5: length 5.3
  TOP w0.254: v4(26.64,117.69) 27.04,117.29 U55.H5
  BOTTOM w0.254: v4(26.64,117.69) 26.45,117.88 26.45,121.04 R823.1 R865.1
HW_VER_6: length 25.7
  TOP w0.254: U55.H9 27.04,114.9 26.9,114.76 26.9,114.74 v4(26.9,114.74) ; Q15.1 v1(37.95,120.02) 38.92,120.02 38.98,119.96 R829.1 39.99,122.25 JP2.2
  BOTTOM w0.254: v1(37.95,120.02) 37.88,120.02 36.56,118.7 36.56,114.25 34.27,111.97 29.55,111.97 26.92,114.59 26.92,114.71 v4(26.9,114.74)
HW_VER_7: length 42.2
  TOP w0.254: v1(20.31,122.63) R830.1 ; R830.1 20.3,121.87 20.3,121.11 21.95,119.46 23.22,119.46 24.02,118.66 U55.N2 ; R830.1 JP4.2 ; U58.5 v1(41.48,107.15)
  L3_INT_1 w0.254: v1(20.31,122.63) 21.22,123.54 30.78,123.54 37.45,116.88 37.45,110.95 40.49,107.9 41,107.9 41.48,107.42 v1(41.48,107.15)
I2C2_SCL_1V8: length 131.2
  TOP w0.127: U126.4 64.84,104.56 65.39,105.11 65.39,107.98 68.31,110.9 68.31,114.51 v1(67.8,115.01) ; R689.1 v1(168.89,128.35)
  L3_INT_1 w0.127: v1(67.8,115.01) 70.82,115.01 73.51,117.71 73.51,120 74.5,120.98 80.09,120.98 82.88,123.78 86.47,123.78 87.1,124.41 91.39,124.41 94.06,127.08 115.3,127.08 121.9,120.47 132.31,120.47 140.32,128.48 163.3,128.48 165.72,130.89 166.86,130.89 168.26,129.49 168.26,128.98 v1(168.89,128.35)
  BOTTOM w0.127: v1(168.89,128.35) R689.1
I2C2_SDA_1V8: length 126.4
  TOP w0.127: R688.1 v1(168.89,127.33) ; v1(67.8,114.12) 67.8,110.82 64.84,107.86 U126.5
  L3_INT_1 w0.127: v1(67.8,114.12) 70.47,114.12 73.89,117.55 73.89,119.84 74.66,120.6 80.24,120.6 83.04,123.4 86.59,123.4 87.23,124.03 91.55,124.03 94.21,126.7 115.14,126.7 121.74,120.09 132.47,120.09 140.47,128.09 163.43,128.09 165.84,130.51 166.73,130.51 167.87,129.36 167.87,128.35 v1(168.89,127.33)
  BOTTOM w0.127: v1(168.89,127.33) R688.1
I2C_SCL_ENET_ID: length 3.9
  TOP w0.127: J134.54 126.61,12.79 127.62,13.79 R2579.1
I2C_SDA_ENET_ID: length 3.7
  TOP w0.127: J134.52 126.11,12.93 126.6,13.41 R285.1
I3C2_PUR: length 97.8
  TOP w0.127: R142.2 130.41,64.75 v1(130.19,64.97) ; R778.1 v1(173.84,24.34) J50.3
  L3_INT_1 w0.127: v1(160.51,24.34) 164.06,20.78 171.68,20.78 173.08,22.18 173.08,23.57 v1(173.84,24.34)
  BOTTOM w0.127: v1(160.51,24.34) 159.87,24.34 154.79,29.42 152.79,29.42 152.15,28.78 149.97,28.78 149.33,29.42 140.44,29.42 138.72,31.14 130.74,31.14 129.14,32.74 129.14,33.61 128.75,34 127.88,34 123.98,37.9 123.98,45.78 128.53,50.32 130.28,50.32 133.76,53.8 133.76,58.32 129.77,62.31 129.77,63.58 130.19,64 v1(130.19,64.97)
I3C2_SCL: length 225
  TOP w0.127: v1(94.6,98.5) 94.04,99.06 92.31,99.06 90.96,100.41 80.37,100.41 79.74,101.04 79.74,116.41 81.06,117.73 81.06,123.02 85.46,127.42 85.46,131 83.17,133.3 83.17,135.4 J47.13 ; J50.1 175.93,21.75 175.09,22.58 172.98,22.58 R776.2 v1(171.56,21.92) 171.05,22.43 U46.13 ; U48.6 v1(161.34,24.34) ; v1(154.16,28.78) 154.16,29.8 153.66,30.3 R798.2 153.14,30.3 R784.1 R783.2 ; R120.2 129.39,69.55 v1(129.27,69.67)
  L3_INT_1 w0.127: v1(129.27,69.67) 129.19,69.75 129.19,77.55 124.19,82.55 124.19,85.3 123.04,86.44 123.04,87.12 113.19,96.98 109.07,96.98 107.55,95.46 94.77,95.46 94.01,96.22 94.01,97.92 v1(94.6,98.5) ; v1(161.34,24.34) 164.52,21.16 170.8,21.16 v1(171.56,21.92)
  BOTTOM w0.127: v1(161.34,24.34) 160.83,23.83 158.73,23.83 154.67,27.89 154.67,28.27 v1(154.16,28.78) 153.65,28.27 150.48,28.27 149.71,27.51 146.1,27.51 145.08,28.53 140.32,28.53 138.31,30.53 130.05,30.53 123.3,37.29 123.3,39.07 122.15,40.21 122.15,42.37 122.92,43.13 122.92,45.27 128.27,50.62 130.16,50.62 133.46,53.93 133.46,57.1 129.27,61.29 129.27,63.96 129.75,64.44 129.75,69.19 v1(129.27,69.67)
I3C2_SDA: length 232.2
  TOP w0.127: J50.2 176.38,21.8 175.29,22.89 172.62,22.89 R775.2 ; U46.14 171.44,22.93 v1(171.56,22.81) 171.56,22.94 R775.2 ; R122.2 128.37,69.63 v1(128.33,69.67) ; v1(162.16,24.34) 161.99,24.5 U48.5 ; R778.2 R775.2 ; R782.2 R785.1 153.01,32.84 R801.2 153.66,32.84 154.67,31.83 154.67,28.15 v1(154.16,27.64) ; J47.15 81.13,135.37 81.13,133.11 81.92,132.32 82.31,132.32 82.32,132.34 83.5,132.34 85.16,130.67 85.16,127.55 80.75,123.14 80.75,117.86 79.43,116.54 79.43,100.92 80.25,100.1 90.84,100.1 92.44,98.5 v1(93.45,98.5)
  L3_INT_1 w0.127: v1(171.56,22.81) 171.18,22.43 164.06,22.43 v1(162.16,24.34) ; v1(128.33,69.67) 128.33,70.13 128.89,70.69 128.89,77.42 123.88,82.43 123.88,85.17 122.74,86.31 122.74,87 113.06,96.68 109.28,96.68 107.75,95.15 94.65,95.15 93.71,96.09 93.71,98.25 v1(93.45,98.5)
  BOTTOM w0.127: v1(162.16,24.34) 161.27,23.45 158.35,23.45 v1(154.16,27.64) 154.03,27.76 151.75,27.76 150.98,27 145.78,27 144.63,28.15 140.19,28.15 138.11,30.23 129.85,30.23 122.92,37.16 122.92,38.94 121.77,40.08 121.77,45.16 122.03,45.42 122.53,45.42 128.11,51.01 130.03,51.01 133.08,54.05 133.08,56.85 128.76,61.17 128.76,65.15 129.39,65.79 129.39,68.61 v1(128.33,69.67)
IF_DETECT: length 1.7
  TOP w0.127: J56.9 38.83,102.82 38.08,102.82 R840.2
IF_ISPEN: length 3.3
  TOP w0.127: R841.2 39.99,103.71 40.87,102.82
IF_RST: length 9.8
  TOP w0.127: R835.2 38.08,101.04 38.59,101.55 J56.10 39.6,98.25 40.57,97.29 U60.7
IF_SWCLK: length 14.2
  TOP w0.127: R831.2 v1(45.7,108.16) ; J56.4 43.41,99.9 42.33,98.81 U60.3
  BOTTOM w0.127: v1(45.7,108.16) 45.7,101.42 44.99,100.71 44.25,100.71 J56.4
IF_SWDIO: length 24.4
  TOP w0.127: U60.15 44.18,97.69 44.43,97.94 44.43,101.3 J56.2 45.45,101.55 45.83,101.93 45.83,103.84 43.16,106.5 38.72,106.5 38.46,106.76 R833.2
IF_TDI: length 13.3
  TOP w0.127: R832.2 v1(46.17,107.27)
  BOTTOM w0.127: v1(46.17,107.27) 46.17,101.39 45.19,100.41 42.02,100.41 40.87,101.55
IF_TDO_SWO: length 14.3
  TOP w0.127: U60.11 42.73,96.29 42.53,96.09 39.99,96.09 38.33,97.74 v1(38.33,98.25) R834.2
  L3_INT_1 w0.127: J56.6 40.49,99.9 39.99,99.9 v1(38.33,98.25)
IN3R: length 2.8
  TOP w0.081: U369.F6 90.39,119.7 90.64,119.95 91.2,119.95 92.11,120.86 C592.2
INT1_COMBO: length 46.1
  TOP w0.127: v1(55.86,92.66) R1029.2
  L3_INT_1 w0.127: v1(95.23,88.22) 94.79,88.66 62.66,88.66 58.65,92.66 v1(55.86,92.66)
  BOTTOM w0.127: R1029.2 v1(55.86,92.66) ; v1(95.23,88.22) 95.37,88.36 95.37,90.9 95.73,91.26 R1079.2
INT2_COMBO: length 44.3
  TOP w0.127: R1030.2 v1(56.63,95.1)
  L3_INT_1 w0.127: v1(56.63,95.1) 56.85,95.1 62.99,88.97 95.62,88.97 v1(95.87,88.72)
  BOTTOM w0.127: R1080.2 v1(95.87,88.72) ; v1(56.63,95.1) R1030.2
JTAG_DACK: length 7.8
  TOP w0.127: 14.71,135.97 15.86,134.83 15.86,131.4 14.71,130.25 R721.1
JTAG_DE: length 7.8
  TOP w0.127: R713.2 17.25,130 18.4,131.14 18.4,134.83 J37.17
JTAG_NSRST: length 9.3
  TOP w0.127: R714.2 20.43,129.11 20.39,129.07 D26.C 19.66,129.99 21.06,131.4 21.06,134.7 J37.15
JTAG_NTRST: length 116.6
  TOP w0.127: v1(34.27,129.1) R717.2 35.03,130.51 36.3,131.78 36.3,134.7 35.03,135.97 ; U6.B5 97.09,76.44 97.09,77.77 95.87,79 95.87,82.88 93.85,84.9 v1(93.85,85.95)
  L3_INT_1 w0.127: v1(93.85,85.95) 91.74,88.05 61.31,88.05 58.6,90.76 57.89,90.76 57,91.65 48.62,91.65 45.22,95.05 44.2,95.05 43.29,95.96 43.29,97.3 43.98,98 45.52,98 46.82,99.29 46.82,105.36 47.83,106.38 47.83,110.44 46.34,111.94 46.34,115.52 46.26,115.6 46.26,115.65 39.35,122.56 39.35,124.41 35.41,128.35 35.03,128.35 v1(34.27,129.1)
JTAG_RTCK: length 7.4
  TOP w0.127: 24.87,135.97 26.14,134.7 R720.1
JTAG_TCK: length 122.9
  TOP w0.127: v1(91.29,85.42) 91.29,84.41 94.09,81.61 94.09,78.34 95.09,77.34 U6.A2 ; U60.4 41.93,98.98 v1(41.95,99) ; 27.41,135.97 28.68,134.7 28.68,131.4 27.41,130.13 R719.1 28.17,129.1 v1(28.3,129.23)
  L3_INT_1 w0.127: v1(28.3,129.23) 28.3,128.23 30.59,125.94 36.05,125.94 38.33,123.65 38.33,122.1 45.19,115.24 45.19,111.43 46.84,109.78 46.84,107.27 45.57,106 45.57,99.74 45.22,99.39 42.34,99.39 v1(41.95,99) 41.95,99 41.67,99 40.7,98.03 40.7,96.87 43.51,94.06 44.43,94.06 47.99,90.5 55.35,90.5 56.24,89.61 57.63,89.61 60.2,87.05 86.75,87.05 88.58,85.22 91.09,85.22 v1(91.29,85.42)
JTAG_TDI: length 118.5
  TOP w0.127: v1(92.31,85.42) 92.31,84.66 94.85,82.12 94.85,78.56 95.89,77.52 U6.A3 ; v1(33.38,129.1) R716.2 32.49,130.38 33.76,131.65 33.76,134.7 J37.5
  L3_INT_1 w0.127: v1(33.38,129.1) 33.38,129.1 33.38,128.36 34.78,126.95 36.18,126.95 39.02,124.11 39.02,122.46 45.95,115.52 45.95,111.71 47.53,110.14 47.53,106.76 46.4,105.63 46.4,99.33 45.48,98.42 42.69,98.42 42.36,98.09 41.73,98.09 41.38,97.74 41.38,97.23 43.87,94.74 45.02,94.74 48.49,91.26 55.73,91.26 56.62,90.38 58.32,90.38 60.95,87.75 91.13,87.75 91.93,86.95 91.93,85.8 v1(92.31,85.42)
JTAG_TDO: length 124.7
  TOP w0.127: U6.A4 96.69,77.74 95.48,78.95 95.48,82.76 93.33,84.91 93.33,86.18 v1(93.83,86.69) ; U60.12 43.13,96.25 43.29,96.09 v1(44.05,96.09) ; J37.13 23.6,134.7 23.6,131.02 v1(24.49,130.13)
  L3_INT_1 w0.127: v1(24.49,130.13) 24.62,130 34.4,130 39.73,124.67 39.73,122.76 46.84,115.65 46.84,111.97 48.14,110.67 48.14,106.15 47.22,105.23 47.22,99.27 v1(44.05,96.09) 44.05,95.84 44.53,95.35 45.42,95.35 48.75,92.03 57.26,92.03 58.15,91.14 59.04,91.14 61.82,88.36 92.17,88.36 v1(93.83,86.69)
JTAG_TMS: length 122.8
  TOP w0.127: v1(90.75,86.06) 90.75,77.66 91.98,76.43 94.47,76.43 94.86,76.04 U6.B2 ; v1(30.97,129.1) R715.2 29.95,130 31.22,131.27 31.22,134.7 J37.7 ; v1(43.8,98.88) 43.74,98.82 U60.16
  L3_INT_1 w0.127: v1(30.97,129.1) 30.96,129.1 30.96,128.1 32.62,126.44 36.08,126.44 38.72,123.81 38.72,122.25 45.57,115.39 45.57,111.58 47.22,109.93 47.22,107.01 46.02,105.81 46.02,99.58 45.32,98.88 v1(43.8,98.88) 42.73,98.88 42.24,98.39 41.6,98.39 41.08,97.87 41.08,97.03 43.67,94.44 44.68,94.44 48.24,90.88 55.61,90.88 56.5,89.99 58.02,89.99 60.57,87.44 89.66,87.44 90.75,86.35 v1(90.75,86.06)
JTAG_VREF: length 7.8
  TOP w0.127: J37.1 38.72,134.83 38.72,130.89 37.57,129.75 R718.2
LED_HEARTBEAT: length 7.2
  TOP w0.127: v4(29.06,116.23) 29.13,116.16 U55.C7 ; v1(33.38,116.69) 33.76,117.07 33.76,117.55 33.46,117.86 TP46.1
  L3_INT_1 w0.127: v4(29.06,116.23) 32.92,116.23 v1(33.38,116.69)
LED_OPT1: length 9.3
  TOP w0.127: v1(26.52,108.66) 26.27,108.92 TP47.1 ; v4(26.03,114.99) 26.19,115.16 U55.J9
  L3_INT_1 w0.127: v4(26.03,114.99) 26.03,114.33 25.51,113.81 25.51,111.99 25.96,111.53 26.36,111.53 27.29,110.61 27.29,109.43 v1(26.52,108.66)
LED_OPT2: length 9.3
  TOP w0.127: TP48.1 v1(28.7,107.65) ; U55.G9 v4(27.54,114.66)
  L3_INT_1 w0.127: v1(28.7,107.65) 28.05,108.3 28.05,112.3 27.29,113.06 27.29,114.4 v4(27.54,114.66)
LED_SWO_ACT: length 4.1
  TOP w0.127: TP45.1 32.62,119.41 32.62,119.26 31.21,117.85 30.35,117.85 U55.B3
LED_USB_COMM: length 7.1
  TOP w0.127: D29.C v1(30.4,109.18) ; v4(28.28,114.06) 28.04,113.82 U55.F12
  L3_INT_1 w0.127: v1(30.4,109.18) 30.21,109.38 30.21,111.08 28.28,113.01 v4(28.28,114.06)
LED_VCOM_ACT: length 13.9
  TOP w0.127: v1(34.02,110.06) 33.76,109.81 D30.C ; v4(29.53,116.73) 29.61,116.66 U55.B6
  L3_INT_1 w0.127: v4(29.53,116.73) 29.68,116.59 32.54,116.59 33.11,117.16 33.65,117.16 34.91,115.9 34.91,110.95 v1(34.02,110.06)
LPI2C2_SCL: length 340.3
  TOP w0.081: 91.67,115.32 91.67,116.03 91.17,116.54 90.79,116.54 90.26,117.06 U369.F1
  TOP w0.127: v1(62.85,99.65) R1322.1 ; v1(47.61,115.27) 48.32,114.56 48.32,108.54 46.67,106.89 46.67,99.65 45.65,98.63 45.65,84.15 45.93,83.87 45.93,77.7 47.61,76.02 47.61,73.31 48.72,72.19 48.72,67.67 47.17,66.12 47.17,43.89 50.73,40.34 50.73,38.66 49.54,37.47 47.73,37.47 42.49,32.22 42.49,23.92 45.68,20.73 49.21,20.73 49.84,21.36 51.92,21.36 54.34,18.95 61.96,18.95 64.38,21.37 71.78,21.37 72.24,20.91 72.24,20.4 74.64,18 85.85,18 86.72,17.12 96.48,17.12 v1(96.75,16.84) ; R80.2 93.83,91.77 v1(92.56,93.04) ; 91.67,115.32 91.67,114.76 v1(92.31,114.12) ; R1028.1 v1(65,95.58) ; R2579.2 v1(127.62,16.33)
  L3_INT_1 w0.127: v1(65,95.58) 65.77,96.34 81.9,96.34 85.99,92.26 91.52,92.26 92.31,93.04 v1(92.56,93.04) ; v1(47.61,115.27) 51.24,118.9 59.68,118.9 65.72,112.85 78.26,112.85 81.05,115.65 85.32,115.65 85.68,115.29 87.38,115.29 87.74,115.65 87.74,116.03 88.12,116.41 90.66,116.41 92.31,114.76 v1(92.31,114.12) 91.8,113.62 88.5,113.62 88.06,113.17 86.53,113.17 85.45,112.09 81.01,112.09 80.12,111.2 64.24,111.2 v1(63.48,111.97)
  BOTTOM w0.127: v1(63.48,111.97) 63.48,111.37 62.08,109.97 62.08,102.69 62.85,101.93 v1(62.85,99.65) 62.85,98.25 65,96.09 v1(65,95.58) R1028.1 ; v1(96.75,16.84) 97.26,16.33 97.26,15.57 103.99,8.84 111.78,8.84 113.13,10.19 125.03,10.19 127.62,12.78 v1(127.62,16.33)
LPI2C2_SDA: length 339.3
  TOP w0.081: 91.29,115.32 91.29,116.03 91.05,116.28 90.77,116.28 90.01,117.03 90.01,117.31 89.76,117.56 U369.E2
  TOP w0.127: R1032.2 v1(65,94.69) ; R285.2 v1(126.6,16.33) ; R1321.1 v1(62.59,109.81) ; 91.29,115.32 91.29,114.38 v1(91.55,114.12) ; R79.2 94.14,91.97 94.14,92.36 v1(93.45,93.04) ; v1(97.77,16.84) 97.19,17.43 86.85,17.43 85.97,18.3 76.12,18.3 72.75,21.68 64.25,21.68 61.83,19.26 54.46,19.26 52.05,21.67 49.71,21.67 49.08,21.03 45.8,21.03 42.79,24.04 42.79,32.1 47.86,37.16 49.66,37.16 51.03,38.53 51.03,40.46 47.48,44.02 47.48,65.99 49.03,67.54 49.03,72.32 47.91,73.43 47.91,76.23 46.27,77.87 46.27,83.96 45.95,84.28 45.95,98.5 46.97,99.52 46.97,106.76 48.62,108.41 v1(48.62,115.27)
  L3_INT_1 w0.127: v1(65,94.69) 66.27,95.96 80.72,95.96 85.64,91.05 90.75,91.05 92.23,92.53 92.94,92.53 v1(93.45,93.04) ; v1(63.48,112.98) 64.88,111.58 79.99,111.58 80.88,112.47 84.94,112.47 86.98,114.51 87.99,114.51 88.5,114 91.42,114 v1(91.55,114.12) 91.14,114.53 88.73,114.53 88.27,114.99 84.92,114.99 84.56,114.63 80.75,114.63 78.59,112.47 65.64,112.47 59.54,118.57 51.92,118.57 v1(48.62,115.27)
  BOTTOM w0.127: v1(63.48,112.98) 63.99,112.47 63.99,111.2 v1(62.59,109.81) 62.46,109.68 62.46,102.95 63.35,102.06 63.35,98.46 65.51,96.3 65.51,95.2 v1(65,94.69) R1032.2 ; v1(97.77,16.84) 98.28,16.33 98.28,15.19 104.32,9.15 111.66,9.15 113,10.49 124.82,10.49 126.6,12.27 v1(126.6,16.33)
LPSPI1_PCS0: length 46.1
  TOP w0.127: R314.1 v1(67.04,94.31) ; U6.C7 v1(98.69,75.64)
  BOTTOM w0.127: v1(98.69,75.64) 98.69,76.47 97.14,78.02 97.14,80.47 94.34,83.26 94.34,86.95 93.38,87.91 81.18,87.91 73.64,95.46 68.31,95.46 67.81,94.95 R314.1 v1(67.04,94.31)
LPSPI1_SCK: length 32.2
  TOP w0.127: U6.B4 96.29,76.44 96.29,77.63 95.15,78.77 95.15,82.45 92.94,84.66 92.94,86.82 94.04,87.91 v1(94.55,87.91) ; R318.1 v1(81.51,91.77)
  BOTTOM w0.127: R2152.1 82.03,92.29 v1(81.51,91.77) ; R318.1 v1(81.51,91.77) ; v1(81.51,91.77) 81.51,91.01 83.93,88.6 93.79,88.6 94.47,87.91 v1(94.55,87.91)
LPSPI1_SDI: length 43.1
  TOP w0.127: U6.C6 v1(97.89,75.64) ; R315.1 v1(67.04,93.04)
  BOTTOM w0.127: v1(97.89,75.64) 97.89,76.16 96.12,77.93 96.12,80.72 93.2,83.64 93.2,86.19 91.8,87.58 81.01,87.58 76.18,92.41 68.05,92.41 67.81,92.66 R315.1 v1(67.04,93.04)
LPSPI1_SDO: length 31.7
  TOP w0.127: U6.E7 v1(98.69,74.04) ; R319.1 v1(81.25,90.5)
  BOTTOM w0.127: R319.1 v1(81.25,90.5) 83.54,88.22 93.58,88.22 94.72,87.07 94.72,83.39 97.52,80.6 97.52,78.18 99.09,76.61 99.09,74.44 v1(98.69,74.04)
LPSPI6_CLK: length 52.4
  TOP w0.127: R2168.1 v1(168.95,122.76) ; R2640.2 v1(121.39,118.95)
  L3_INT_1 w0.127: v1(168.95,122.76) 167.87,122.76 165.84,124.79 160,124.79 158.86,123.65 139.93,123.65 135.24,118.95 v1(121.39,118.95)
LPSPI6_CS: length 79.6
  TOP w0.127: R2169.1 v1(168.89,129.24) ; v1(131.93,101.04) 131.93,103.2 131.69,103.45 R2639.2
  L3_INT_1 w0.127: v1(131.93,101.04) 132.14,101.25 141.64,101.25 142.09,100.79 143.74,100.79 144.13,101.17 144.13,102.19 145.01,103.08 150.73,103.08 154.21,99.6 170.21,99.6 v1(170.54,99.27)
  BOTTOM w0.127: v1(170.54,99.27) 169.75,100.05 169.75,101.32 169.14,101.93 169.14,107.27 173.42,111.55 173.42,119 169.4,123.02 169.4,128.73 v1(168.89,129.24)
LPSPI6_SDI: length 105.5
  TOP w0.127: v1(99.8,96.34) 99.8,93.55 99.93,93.42 R2641.2 ; v1(168.95,122) 168.83,121.87 R2166.1
  L3_INT_1 w0.127: v1(170.54,98.25) 170.03,97.74 154.54,97.74 151.87,100.41 144.76,100.41 144.13,99.77 141.46,99.77 140.6,100.64 133.43,100.64 132.57,99.77 129.39,99.77 128,98.38 109.45,98.38 107.42,96.34 v1(99.8,96.34)
  BOTTOM w0.127: v1(170.54,98.25) 168.76,100.03 168.76,107.52 171.38,110.14 171.38,117.1 170.8,117.68 170.8,120.47 169.27,122 v1(168.95,122)
LPSPI6_SDO: length 99.2
  TOP w0.127: R2635.1 168.7,120.98 v1(168.95,121.24)
  L3_INT_1 w0.127: v1(169.4,98.25) 168.51,99.14 153.9,99.14 152.25,100.79 144.38,100.79 143.87,100.28 141.84,100.28 141.18,100.94 133.1,100.94 132.44,100.28 129.39,100.28 127.87,98.76 109.07,98.76 v1(108.18,97.87)
  BOTTOM w0.127: v1(168.95,121.24) 169.53,121.24 170.41,120.35 170.41,117.55 171.08,116.89 171.08,110.26 168.46,107.65 168.46,99.19 v1(169.4,98.25) ; R2642.2 103.99,91.77 104.25,92.03 104.88,92.03 106.15,93.3 106.15,94.44 108.06,96.34 108.06,97.74 v1(108.18,97.87)
LPUART1_RXD: length 69.8
  TOP w0.127: R848.1 v1(47.48,113.11) ; R76.2 96.5,91.26 96.37,91.13 96.37,89.38 v1(96.29,89.3)
  L3_INT_1 w0.127: v1(47.48,113.11) 47.48,112.09 48.52,111.06 48.52,105.34 52.43,101.42 53.07,101.42 56.24,98.25 56.24,96.98 58.15,95.07 59.42,95.07 64.88,89.61 82.71,89.61 83.47,90.38 90.28,90.38 91.38,89.27 96.26,89.27 v1(96.29,89.3)
LPUART1_TXD: length 64.5
  TOP w0.127: R74.2 92.27,91.8 v1(92.27,91.83) ; R1076.1 v1(47.61,114)
  L3_INT_1 w0.127: v1(47.61,114) 47.99,113.62 47.99,112.09 48.88,111.2 48.88,105.59 52.61,101.86 53.27,101.86 56.62,98.5 56.62,97.23 58.27,95.58 59.54,95.58 65.13,89.99 82.4,89.99 83.15,90.74 91.18,90.74 v1(92.27,91.83)
LPUART12_RXD: length 76.5
  TOP w0.127: R82.2 90.79,91.48 90.79,93.55 v1(90.79,93.55) ; U73.6 59.49,120.91 R897.2 59.55,119.59 TP77.1 v1(59.54,117.81) 59.04,117.3 48.75,117.3 46.72,115.27 44.55,115.27 R1077.1
  L3_INT_1 w0.127: v1(90.79,93.55) 90.4,93.17 86.41,93.17 85.39,94.19 85.39,110.12 84.94,110.57 83.93,110.57 83.29,109.93 81.39,109.93 80.58,110.75 63.81,110.75 59.54,115.01 v1(59.54,117.81)
LPUART12_TXD: length 74.5
  TOP w0.127: U73.5 58.09,118.88 TP78.1 v1(58.15,117.81) 48.62,117.81 46.59,115.78 R1078.1
  L3_INT_1 w0.127: v1(58.15,117.81) 58.15,115.9 63.61,110.44 80.12,110.44 81.26,109.3 84.69,109.3 85.07,108.92 85.07,94.06 86.26,92.87 90.86,92.87 91.42,93.42 v1(91.42,94.06)
  BOTTOM w0.127: v1(91.42,94.06) 91.42,91.64 R81.2
MCU_DCDC_IN: length 24.8
  TOP w0.305: v2(99.5,68.44) 99.1,68.84 U6.L7 ; v2(99.5,68.44) 99.89,68.05 U6.M8 ; v2(99.5,68.44) 99.1,68.04 U6.M7 98.69,67.64 v1(98.69,67.64) U6.M6 v2(97.9,67.64) 97.87,67.67 97.86,67.67 U6.M5 v1(97.09,67.64) ; v1(85.07,63.45) R53.1 84.74,62.68 84.44,62.38 84.44,51.51 v1(84.56,51.39)
  TOP w0.381: R54.2 79.1,49.09 ; R54.2 79.85,48.47 ; R54.2 78.35,48.47 ; 83.31,48.47 C60.1 ; C60.1 84.8,48.47 ; C60.1 84.05,49.09 ; 80.7,48.97 J12.2 ; J12.2 81.64,49.91 ; J12.2 82.58,48.97
  BOTTOM w0.305: R56.1 v1(85.07,63.45)
  vias: v1(82.28,51.39) v1(82.28,50.5) v1(83.04,51.39) v1(83.04,50.5) v1(83.8,51.39) v1(83.8,50.5) v1(84.56,50.5)
MCU_POWER_EN: length 32.8
  TOP w0.127: v4(25.72,118.15) 25.55,118.15 U55.M2 ; R818.1 v1(15.22,99.52)
  L3_INT_1 w0.127: v1(15.22,99.52) 15.42,99.52 19.41,103.51 19.41,108.79 21.95,111.33 21.95,120.35 v1(21.7,120.6)
  BOTTOM w0.127: v4(25.72,118.15) 25.72,120.52 24.75,121.49 22.59,121.49 v1(21.7,120.6)
MICBIAS: length 3.4
  TOP w0.081: U369.A4 87.36,118.7 87.15,118.49 86.52,118.49 86.34,118.32 86.15,118.32
  TOP w0.254: 86.15,118.32 85.71,118.32 85.58,118.44 C589.1 R2136.1
MICVDD: length 4.5
  TOP w0.081: U369.A3 87.42,118.2 87.15,117.93 86.98,117.93 86.78,117.74
  TOP w0.254: 86.78,117.74 86.47,117.43 86.47,117.05 85.71,116.28 C582.1 85.42,115.74 85.32,115.64 R2134.2
NETC2_ECAT1_SEL: length 13.2
  TOP w0.127: U103.9 41.72,60.09 v1(41.66,60.15) ; v1(41.61,56.16) U106.9
  L3_INT_1 w0.127: J72.2 38.84,53.8 41.2,56.16 v1(41.61,56.16) 41.61,57.21 41.39,57.42 41.39,57.81 41.51,57.93 41.51,60 v1(41.66,60.15)
NETC3_ECAT0_SEL: length 33.1
  TOP w0.127: U100.9 42.28,70.81 v1(42.02,71.07) ; v1(42.02,82.12) 42.28,81.86 U97.9 ; U98.9 42.28,78.17 42.02,78.44 v1(41.98,78.44) ; U96.9 v1(42.28,85.79) ; U99.9 42.28,74.49 v1(42.02,74.75) 39.99,74.75 39.35,74.12 35.54,74.12 J73.2 ; U101.9 42.28,67.47 42.19,67.56 v1(42.19,67.65)
  L3_INT_1 w0.127: v1(42.28,85.79) 42.28,82.39 v1(42.02,82.12) 42.28,81.86 42.28,78.74 v1(41.98,78.44) 42.28,78.13 42.28,75.02 v1(42.02,74.75) 42.27,74.5 42.27,71.33 v1(42.02,71.07) 42.28,70.81 42.28,67.74 v1(42.19,67.65)
NETC_ECAT_MDC: length 396.9
  TOP w0.127: R2593.2 v1(125.58,16.33) ; R1282.2 v1(86.59,35.64) 86.98,35.26 87.28,35.26 88.51,34.03 U123.22 ; R504.1 v1(24.49,51.39) ; U121.22 56.76,34.23 55.86,35.13 55.61,35.13 v1(55.1,35.64) 54.84,35.89 R397.2 55.23,36.41 55.38,36.56 55.38,38.41 54.97,38.81 51.8,38.81 49.76,36.78 48.46,36.78 43.1,31.42 43.1,24.22 45.95,21.36 48.94,21.36 49.58,22 52.2,22 54.56,19.64 61.61,19.64 64.02,22.05 72.98,22.05 76.42,18.61 86.1,18.61 86.97,17.73 97.64,17.73 98.28,17.1 98.28,16.33 v1(98.79,15.83) ; v1(26.52,76.79) R557.1 ; R1052.2 115.18,68.91 v1(115.19,68.92)
  L3_INT_1 w0.127: v1(89.45,42.66) 94.67,42.66 98.56,46.56 100.31,46.56 101.3,47.55 108.72,47.55 111.61,50.45 111.61,67.64 112.89,68.92 v1(115.19,68.92) 115.19,70.55 114.28,71.45 114.28,78.69 112.38,80.6 105.64,80.6 102.98,83.26 102.98,84.64 v1(102.79,84.82) 100.73,84.82 99.37,83.47 87.06,83.47 85.15,85.37 72.87,85.37 71.22,83.72 53.37,83.72 50.65,86.44 45.83,86.44 43.92,88.34 37.32,88.34 36.3,89.36 34.14,89.36 33.64,88.85 30.03,88.85 27.11,85.93 27.11,82.12 27.41,81.82 27.41,77.68 v1(26.52,76.79) 27.67,75.64 27.67,66.12 24.87,63.32 24.87,56.72 26.02,55.58 26.02,52.91 v1(24.49,51.39) ; v1(73.26,31.07) 68.56,31.07 65.13,34.5 63.1,34.5 61.45,36.15 55.61,36.15 v1(55.1,35.64)
  BOTTOM w0.127: R453.1 116.19,102.82 117.07,101.93 117.07,100.82 111.2,94.95 109.2,94.95 105.24,90.98 105.24,88.52 102.85,86.13 102.85,84.88 v1(102.79,84.82) ; v1(98.79,15.83) 105.14,9.48 111.52,9.48 112.86,10.82 124.26,10.82 125.58,12.14 v1(125.58,16.33) ; v1(73.26,31.07) 73.77,31.57 82.15,31.57 85.74,35.17 86.13,35.17 v1(86.59,35.64) 86.59,36.17 86.1,36.67 86.1,38.7 89.39,41.99 89.39,42.6 v1(89.45,42.66)
NETC_ECAT_MDIO: length 391.5
  TOP w0.127: R448.1 v1(116.57,101.55) ; R502.1 v1(27.29,51.51) ; U123.23 87.99,33.54 87.99,34.11 87.23,34.88 86.47,34.88 v1(85.71,35.64) R1283.2 ; v1(29.32,76.91) R555.1 ; R2592.2 v1(124.57,16.33) ; v1(112.89,69.66) 112.87,69.64 U6.K17 ; U121.23 56.24,33.54 56.24,34.24 55.86,34.62 55.23,34.62 v1(54.21,35.64) 53.83,36.02 R396.2 54.21,36.41 54.34,36.53 54.34,38.31 54.21,38.43 51.85,38.43 49.56,36.15 48.37,36.15 43.4,31.18 43.4,24.4 46.13,21.67 48.82,21.67 49.45,22.3 52.43,22.3 54.72,20.02 61.45,20.02 63.86,22.43 73.03,22.43 76.55,18.91 86.23,18.91 87.1,18.04 98.61,18.04 v1(98.79,17.86)
  L3_INT_1 w0.127: v1(54.21,35.64) 55.1,36.53 61.7,36.53 63.35,34.88 65.39,34.88 68.18,32.08 v1(73.26,32.08) ; v1(27.29,51.51) 26.4,52.4 26.4,55.7 25.25,56.85 25.25,63.07 28.05,65.87 28.05,75.64 v1(29.32,76.91) 27.73,78.5 27.73,81.93 27.41,82.25 27.41,85.68 29.57,87.84 33.13,87.84 34.14,88.85 36.18,88.85 37.06,87.96 43.54,87.96 45.57,85.93 50.53,85.93 53.07,83.39 71.35,83.39 73.01,85.04 85.05,85.04 86.96,83.14 99.47,83.14 100.6,84.27 v1(102.34,84.27) 102.34,83.26 105.39,80.22 112.25,80.22 113.9,78.56 113.9,70.67 v1(112.89,69.66) 111.28,68.05 111.28,53.85 110.6,53.16 110.6,49.86 108.63,47.89 101.14,47.89 100.18,46.94 98.41,46.94 94.6,43.13 v1(88.88,43.13)
  BOTTOM w0.127: v1(124.57,16.33) 124.57,12.02 123.68,11.13 112.74,11.13 111.39,9.78 106.86,9.78 v1(98.79,17.86) ; v1(73.26,32.08) 73.39,31.96 82.02,31.96 v1(85.71,35.64) 85.71,36.17 85.07,36.81 85.07,38.35 88.88,42.16 v1(88.88,43.13) ; v1(116.57,101.55) 116.57,100.79 111.06,95.29 109.11,95.29 104.93,91.11 104.93,88.65 102.22,85.93 102.22,84.41 102.34,84.28 v1(102.34,84.27)
NVCC_BBSM: length 127
  TOP w0.305: U6.U11 v2(102.69,63.64) ; v1(30.33,9.48) R31.1 R37.1 ; v1(99.94,47.71) 99.94,48.33 R42.1
  L3_INT_1 w0.305: v2(102.98,58.49) 103.33,58.85 103.33,63 v2(102.69,63.64)
  L3_INT_1 w0.508: J8.1 107.3,21.29 101.17,15.17 96.37,15.17 94.06,17.48 92.22,17.48 90.81,18.89 44.95,18.89 40.37,14.3 35.16,14.3 v1(30.33,9.48)
  BOTTOM w0.305: R44.1 99.35,48.77 v1(99.17,48.59) ; v2(102.98,58.49) R47.1
  BOTTOM w0.508: v1(99.94,47.71) 99.94,42.36 102.6,39.7 102.6,33.1 J8.1
NVCC_SD: length 48.9
  TOP w0.381: TP7.1 135.36,96.21 ; TP7.1 135.36,94.96 ; TP7.1 134.74,95.58 ; 134.72,92.61 C28.1 ; C28.1 134.72,93.48 ; C28.1 135.13,93.04 ; 135.75,96.93 R24.1 ; R24.1 135.75,97.79 ; R24.1 135.34,97.36 ; 137.24,92.17 U5.5 ; U5.5 137.24,93.29 ; U5.5 136.55,92.73 ; U5.5 137.92,92.73 ; v1(107.8,84.15) 108.81,85.16 110.84,85.16 114,88.32 115.7,88.32 116.57,87.45 116.57,86.95 117.46,86.06 118.22,86.06 120.63,88.47 120.63,91.14 122.66,93.17 131.43,93.17 132.44,92.15 134.98,92.15 ; 134.82,93.7 C27.1 ; C27.1 135.23,94.19 ; C27.1 134.82,94.67 ; 134.72,96.93 R25.1 ; R25.1 134.72,97.79 ; R25.1 135.13,97.36
  L3_INT_1 w0.381: v1(109.71,84.03) 109.58,84.15 v1(107.8,84.15)
  BOTTOM w0.305: v1(107.8,84.15) R64.1 R71.1 ; R65.1 v1(109.71,84.03)
OCT_FLASH_RST_B: length 279.4
  TOP w0.127: R1094.1 172.07,99.13 v1(170.54,100.66) ; v1(99.68,87.33) 99.68,87.45 100.54,88.32 100.54,89.79 100.74,89.99 100.74,93.25 100.31,93.68 100.31,96.6 98.91,98 98.91,113.87 99.55,114.51 v1(100.82,114.51) ; R2103.2 33.01,33.22 J94.2 J93.2
  L3_INT_1 w0.127: v1(99.68,87.33) 98.28,87.33 95.46,84.51 87.36,84.51 85.55,86.31 55.86,86.31 54.46,87.71 46.84,87.71 43.41,91.14 29.7,91.14 29.57,91.01 28.68,91.01 27.79,91.9 22.08,91.9 20.68,90.5 20.68,87.2 21.32,86.57 21.32,81.87 20.43,80.98 20.43,65.99 21.06,65.36 21.06,61.93 20.3,61.17 20.3,43 30.08,33.23 J94.2 ; v1(100.82,114.51) 98.41,112.09 98.41,103.84 100.69,101.55 109.84,101.55 111.36,100.03 127.92,100.03 129.95,102.06 142.86,102.06 144.23,103.43 151.01,103.43 154.41,100.03 169.91,100.03 v1(170.54,100.66)
  BOTTOM w0.127: R293.1 v1(100.82,114.51)
OE_FLEXSPI1_A_EN: length 19.6
  TOP w0.127: U70.6 v1(112.42,104.87) ; U69.6 v1(102.41,103.84) ; U71.6 v1(106.73,104.09)
  L3_INT_1 w0.127: v1(112.42,104.87) 110.86,104.87 109.58,103.58 107.24,103.58 v1(106.73,104.09) 106.73,104.01 106.18,103.46 102.79,103.46 v1(102.41,103.84)
  BOTTOM w0.127: v1(102.41,103.84) 102.41,103.78 100.69,102.06 J59.2
OE_FLEXSPI1_B_EN: length 17.9
  TOP w0.127: v1(146.21,73.43) U66.6 145.64,75.91 J58.2 ; v1(151.24,73.43) U67.6 ; v1(156.19,73.43) U68.6
  BOTTOM w0.127: v1(146.21,73.43) 146.53,73.1 147.43,73.1 147.55,73.23 151.04,73.23 v1(151.24,73.43) 151.24,74.12 151.8,74.68 154.49,74.68 154.79,74.37 154.79,73.99 155.36,73.43 v1(156.19,73.43)
OE_NETC2_ECAT1_EN: length 18.8
  TOP w0.127: U103.6 43.78,61.13 v1(43.77,61.14) ; v1(43.8,56.9) 43.78,56.89 U106.6
  L3_INT_1 w0.127: v1(43.77,61.14) 43.77,60.98 43.8,60.95 v1(43.8,56.9) 43.8,56.34 40.11,52.65 40.11,47.45 J65.2
OE_NETC3_ECAT0_EN: length 35.7
  TOP w0.127: J63.2 35.67,70.94 40.24,70.94 40.84,71.54 43.71,71.54 44.18,71.07 v1(44.18,70.94) 43.78,70.55 U100.6 ; U97.6 v1(44.56,81.3) ; U99.6 v1(44.56,73.94) ; v1(44.34,66.75) 44.3,66.75 44.12,66.57 U101.6 ; U98.6 v1(44.56,77.62) ; U96.6 v1(44.56,84.99)
  L3_INT_1 w0.127: v1(44.34,66.75) 44.34,67.45 43.78,68.01 43.78,70.55 v1(44.18,70.94) 43.92,71.2 43.92,73.3 v1(44.56,73.94) 44.05,74.44 44.05,77.11 v1(44.56,77.62) 44.05,78.13 44.05,80.79 v1(44.56,81.3) 44.05,81.81 44.05,84.48 v1(44.56,84.99)
OE_SD_SDIO_EN: length 23.2
  TOP w0.127: U64.6 v1(147.49,117.92) ; U63.6 144.42,117.93 v1(143.62,117.93) ; v1(140.29,118.69) 140.25,118.64 U65.6
  BOTTOM w0.127: v1(140.29,118.69) 140.29,117.96 141.33,116.92 142.6,116.92 v1(143.62,117.93) 144.63,116.92 147.17,116.92 147.3,117.05 147.3,117.73 v1(147.49,117.92) 149.59,115.83 149.59,109.93 J57.2
ONOFF: length 147.2
  TOP w0.127: v1(28.81,7.83) 28.94,7.83 28.94,7.83 R31.2 ; R31.2 30.33,7.19 30.3,7.15 SW2.4 SW2.2 ; R31.2 C31.1 ; U6.U10 101.49,57.14 100.18,55.83 100.18,52.28 98.15,50.24 98.15,38.81 99.55,37.42 99.55,33.86 104.63,28.78 104.63,26.75 v1(105.01,26.37)
  L3_INT_1 w0.127: v1(28.81,7.83) 28.81,8.97 34.91,15.06 39.22,15.06 42.02,17.86 42.02,19.9 42.65,20.54 42.65,21.41 43.16,21.92 51.42,21.92 53.65,19.69 91.16,19.69 92.51,18.34 102.83,18.34 105.52,21.03 105.52,25.86 v1(105.01,26.37)
OSC_25MHZ: length 36.1
  TOP w0.127: R964.1 v1(50.91,25.73) ; R1279.1 82.81,26.22 82.81,25.17 82.02,24.39 v1(81.31,24.39)
  L3_INT_1 w0.127: v1(81.31,24.39) 80.04,25.66 76.89,25.66 76.18,26.37 69.58,26.37 67.93,24.72 55.1,24.72 54.08,25.73 v1(50.91,25.73)
OTG1_DN: length 89.9
  TOP w0.119: R623.2 185.8,66.63 L16.2 185.08,66.52 184.81,66.24 182.74,66.24 173.33,75.65 173.33,78.29 171.66,79.96 137.67,79.96 135.97,78.26 115.12,78.26 110.9,74.04 106.7,74.04 U6.E16
OTG1_DP: length 90.3
  TOP w0.119: R628.2 185.8,65.61 L16.3 185.08,65.72 184.81,66 184.62,66 184.5,65.88 184.5,65.65 184.38,65.53 184.14,65.53 184.02,65.65 184.02,65.88 183.9,66 183.67,66 183.55,65.88 183.55,65.65 183.43,65.53 183.19,65.53 183.07,65.65 183.07,65.88 182.95,66 182.64,66 173.08,75.55 173.08,78.18 171.55,79.71 137.78,79.71 136.07,78.01 115.22,78.01 111,73.8 107.25,73.8 U6.E17
OTG2_DN: length 85.9
  TOP w0.119: R634.2 185.17,77.95 L19.2 184.53,77.95 184.25,77.67 183.63,77.67 v1(183.37,77.93) 183.11,77.67 180.68,77.67 176.06,82.29 120.91,82.29 119.21,80.59 114.69,80.59 109.36,75.26 108.31,75.26 107.93,75.64 106.92,75.64 106.51,75.24 U6.C16
  BOTTOM w0.119: R691.1 184.26,77.68 183.62,77.68 v1(183.37,77.93)
OTG2_DP: length 86.1
  TOP w0.119: U6.C17 107.25,75.4 107.83,75.4 108.21,75.02 109.46,75.02 114.79,80.34 119.31,80.34 121.01,82.04 175.95,82.04 180.57,77.42 181.08,77.42 181.2,77.3 181.2,77.13 181.32,77.02 181.56,77.02 181.68,77.13 181.68,77.3 181.8,77.42 182.04,77.42 182.15,77.3 182.15,77.13 182.27,77.02 182.51,77.02 182.63,77.13 182.63,77.3 182.75,77.42 183.11,77.42 v1(183.37,77.17) 183.63,77.43 184.23,77.43 184.51,77.15 L19.3 185.17,77.15 R637.2
  BOTTOM w0.119: v1(183.37,77.17) 183.62,77.42 184.14,77.42 R690.1
P_ENET4_VDDIO: length 5
  TOP w0.127: J134.57 127.61,3.76 128.5,2.87 129.39,2.87 TP1063.1
PHY0_3V3: length 4.2
  BOTTOM w0.305: R1095.1 60.06,29.29 60.56,29.29 60.82,29.03 L34.2 C476.1 61.32,30.18 R1096.1
PHY0_AVDD33: length 5.6
  TOP w0.305: v1(54.21,30.3) 54.34,30.3 54.35,30.32 U121.30 ; U121.7 v1(58.76,27.53)
  BOTTOM w0.305: C478.1 v1(54.21,30.3)
  BOTTOM w0.381: C475.1 59.21,28.28 ; C475.1 58.78,27.87 ; C475.1 58.35,28.28 ; 59.8,27.87 R1095.2 59.37,28.28 ; 54.85,29.87 C478.1 54.85,30.74
PHY0_COL: length 2.7
  TOP w0.127: R1273.2 52.69,31.32 53.18,31.82 U121.27
PHY0_CRS_DV: length 3.5
  TOP w0.127: U121.26 54.43,32.32 54.33,32.42 53.33,32.42 53.12,32.21 R1122.2 R1271.2
PHY0_LED0_AD0/PMEB: length 46.7
  TOP w0.127: J28.11 42.53,8.93 42.53,14.68 43.29,15.45 v1(43.29,20.42) ; v1(44.18,24.34) 43.71,24.81 43.71,30.85 48.37,35.51 50.15,35.51 51.04,36.41 R1113.2 R1112.1 52.94,36.15 54.84,34.24 55.61,34.24 55.76,34.09 U121.24
  BOTTOM w0.127: v1(44.18,24.34) 43.8,23.95 43.8,20.93 v1(43.29,20.42)
PHY0_MDI0+: length 22.1
  TOP w0.107: v1(55.22,21.29) 55.22,21.42 54.7,21.94 54.7,23.84 C176.1 54.72,24.34 54.72,24.9 R391.2 54.7,25.79 54.7,26.35 55.1,26.75 56.5,26.75 56.86,27.11 56.86,27.92 56.76,28.02 U121.3
  BOTTOM w0.107: U25.6 54.36,20.18 54.46,20.29 54.46,21.44 54.57,21.54 54.96,21.54 v1(55.22,21.29) 55.57,21.64 55.88,21.64 55.99,21.54 55.99,19.76 55.23,19 55.23,15.6 54.96,15.33 54.76,15.23 54.61,15.28 J28.5
PHY0_MDI0-: length 21
  TOP w0.107: v1(55.35,22.05) 55.24,21.93 55.09,21.93 54.96,22.07 54.96,23.81 C177.1 54.97,24.34 54.97,24.92 R392.2 54.96,25.79 54.96,26.25 55.21,26.49 56.6,26.49 57.12,27.01 57.12,27.92 57.26,28.06 U121.4
  BOTTOM w0.107: U25.4 54.45,22.06 54.59,21.92 55.23,21.92 v1(55.35,22.05) 55.5,21.9 55.99,21.9 56.25,21.64 56.25,19.66 55.49,18.89 55.49,15.49 55.11,15.12 54.87,15 54.82,14.86 J28.6
PHY0_MDI1+: length 34.8
  TOP w0.107: v1(59.8,23.19) 60.05,23.45 60.05,23.82 C178.1 60.05,24.34 60.05,24.9 R393.2 60.04,25.79 60.04,26.14 59.69,26.49 58.53,26.49 57.86,27.16 57.86,27.92 57.76,28.02 U121.5
  BOTTOM w0.107: v1(59.8,23.19) 60.05,22.94 60.05,22.67 59.95,22.56 57.87,22.56 56.6,23.83 53.34,23.83 52.7,23.19 49.53,23.19 48.55,22.21 48.55,21.16 48.8,20.9 49.14,20.9 49.85,20.18 U25.1 52.12,20.18 52.22,20.08 52.22,19.06 50.15,16.98 50.15,15.45 50.01,15.31 50.01,14.98 49.82,14.79 49.21,14.79 49,14.99 J28.1
PHY0_MDI1-: length 34.9
  TOP w0.107: v1(60.56,23.19) 60.31,23.44 60.31,23.83 C179.1 60.31,24.34 60.31,24.92 R395.2 60.3,25.79 60.3,26.25 59.79,26.75 58.64,26.75 58.12,27.27 58.12,27.87 58.26,28.01 U121.6
  BOTTOM w0.107: v1(60.56,23.19) 60.44,23.07 60.44,23.06 60.31,22.93 60.31,22.56 60.05,22.3 57.77,22.3 56.5,23.57 53.45,23.57 52.81,22.93 49.63,22.93 48.8,22.11 48.8,21.27 48.91,21.16 49.38,21.16 50.29,22.06 U25.3 51.76,22.06 52,21.82 52,20.7 52.48,20.22 52.48,18.95 50.41,16.87 50.41,15.34 50.27,15.21 J28.2
PHY0_RST_B: length 5.6
  TOP w0.127: U121.21 57.26,35.25 v1(56.88,35.64) R405.2 R1274.2
  BOTTOM w0.127: R1274.2 R405.2 v1(56.88,35.64)
PHY0_RXC: length 3.9
  TOP w0.127: U121.13 61.06,31.32 61.32,31.57 61.32,32.08 62.08,32.84 R1259.2
PHY0_RXD0: length 4.7
  TOP w0.127: U121.9 61.17,29.32 R1233.2 R1262.2
PHY0_RXD1: length 5.7
  TOP w0.127: R1263.2 R1234.2 v1(62.34,29.29) 61.81,29.82 U121.10
  BOTTOM w0.127: R1263.2 R1234.2 v1(62.34,29.29)
PHY0_RXD2_INTB: length 4.9
  TOP w0.127: R1264.2 R1236.2 v1(62.34,31.07) 61.59,30.32 U121.11
  BOTTOM w0.127: v1(62.34,31.07) R1236.2
PHY0_RXD3: length 5.6
  TOP w0.127: U121.12 61.2,30.82 61.96,31.57 61.96,31.83 v1(61.97,31.84) 62.08,31.96 R1105.2
  BOTTOM w0.127: R1265.2 R1105.2 62.08,31.96 v1(61.97,31.84)
PHY0_RXDV: length 4.5
  TOP w0.127: R1260.2 60.81,27.76 60.44,27.76 v1(60.43,27.77) 59.51,27.77 59.26,28.02 U121.8
  BOTTOM w0.127: v1(60.43,27.77) 60.43,27.77 R1106.1 R1107.2
PHY0_RXER/FXEN: length 5.9
  TOP w0.127: v1(53.19,29.54) R1261.2 R1235.2 53.44,31.32 U121.28
  BOTTOM w0.127: R1235.2 R1261.2 v1(53.19,29.54)
PHY0_TXC: length 4.5
  TOP w0.127: R1240.2 R1266.2 62.34,33.73 61.32,32.72 60.74,32.72 60.34,32.32 U121.15
PHY0_TXD0: length 5.9
  TOP w0.127: U121.16 60.41,32.82 60.81,33.23 60.81,34.62 61.7,35.51 R1268.2 63.1,35.63 R1237.2
PHY0_TXD1: length 4.6
  TOP w0.127: U121.17 59.26,34.35 R1269.2 R1238.2
PHY0_TXD2: length 3.6
  TOP w0.127: U121.18 58.76,34.74 R1270.2
PHY0_TXD3: length 3.4
  TOP w0.127: U121.19 58.26,35.12 58.78,35.64 58.78,35.65 R1272.2
PHY0_TXEN: length 3.8
  TOP w0.127: R1267.2 R1239.2 57.77,33.52 U121.20
PHY0_VDD33: length 27.8
  TOP w0.305: v1(60.85,32.15) 60.52,31.82 U121.14 ; R392.1 56.93,24.29 v1(57.13,24.08) ; v1(52.74,24.21) R391.1 ; R393.1 v1(58.07,23.95)
  TOP w0.381: R395.1 62.26,23.12 61.96,22.81 v1(61.96,22.77) ; R1117.1 53.04,34.9 v1(53.22,35.08) ; v1(64.5,32.21) 63.98,32.21 R1105.1 ; R396.1 v1(53.83,37.92) ; R397.1 v1(54.84,37.92) ; R1113.1 v1(52.05,37.92)
  BOTTOM w0.305: v1(55.89,37.92) 55.89,37.9 55.99,37.8 R408.2 ; v1(52.74,24.21) 49.13,24.21 R1119.2 ; R1096.2 60.05,31.45 59.79,31.71 C477.1 ; R1108.1 51.72,29.54 51.21,30.05 50.1,30.05 v1(49.94,30.2) ; v1(64.42,29.38) 64.36,29.38 64.36,29.38 63.82,29.38 R1102.1 ; R1100.1 v1(64.5,31.07)
  BOTTOM w0.381: C477.1 60.79,32.21 v1(60.85,32.15) ; v1(62.03,26.42) 61.99,26.37 R1107.1
PHY0_XTAL1: length 11.1
  TOP w0.127: U121.31 54.48,29.82 54.08,29.42 54.08,28.4 53.45,27.76 51.17,27.76 C481.1 R1099.2 47.35,28.03 46.12,29.25 X4.1
PHY0_XTAL2: length 11.7
  TOP w0.127: U121.32 54.62,29.32 54.46,29.16 54.46,28.15 53.7,27.38 51.17,27.38 R964.2 C482.1 49.62,27.12 48.33,25.83 X4.3 48.33,24.63 48.36,24.6 R1332.2 R1331.2
PHY1_AVDD10: length 12.2
  TOP w0.203: v1(130.16,114) 130.01,113.85 U27.38 ; U27.8 v1(125.6,116.27) ; U27.3 v1(127.6,116.27)
  BOTTOM w0.305: v1(127.6,116.27) 127.62,116.25 C189.1 ; C190.1 125.58,116.25 v1(125.6,116.27)
  BOTTOM w0.381: R470.2 130.92,113.96 C192.1 v1(130.16,114) C191.1 129.39,114.51 128.38,115.52 127.62,115.52 C189.1 C190.1
PHY1_AVDD33: length 13.8
  TOP w0.203: 129.65,114.96 129.34,114.66 U27.40 ; v1(123.17,114.89) 123.4,114.66 U27.11
  TOP w0.305: 129.65,114.96 C193.1
  TOP w0.381: v1(128.89,116.54) C193.1 129.75,116.44 C195.1 131.58,116.44 R456.1
  BOTTOM w0.381: v1(128.89,116.54) 128.89,116.54 128.56,116.87 124.39,116.87 123.94,116.42 C196.1 C194.1 v1(123.17,114.89)
PHY1_CLK125_OUT: length 1.7
  TOP w0.127: TP24.1 R466.2
PHY1_CT: length 3.4
  TOP w0.254: J29.1 C183.1
PHY1_DVDD10: length 4.2
  TOP w0.203: U27.21 124.8,110.17 124.43,109.79 v1(124.06,109.79)
  BOTTOM w0.381: v1(124.06,109.79) C198.1 125.18,110.58 C197.1 126.31,110.6 R468.2
PHY1_DVDD33: length 12.6
  TOP w0.203: 128.34,109.39 128,109.73 U27.29
  TOP w0.305: U125.7 115.37,105.69 v1(115.42,105.74) ; R434.1 133.32,106.17 133.02,105.87 v1(132.7,105.87) ; R446.1 v1(115.68,101.55) ; R435.1 R436.1 ; v1(128.76,108.92) 128.34,109.34 128.34,109.39
  TOP w0.381: R435.1 v1(133.97,109.43)
  BOTTOM w0.305: R450.1 v1(116.19,109.93) ; C98.1 115.52,105.65 v1(115.42,105.74)
  BOTTOM w0.508: v1(133.97,109.43) 133.71,109.43 132.95,108.66 132.95,106.12 v1(132.7,105.87)
  vias: v1(129.52,108.92)
PHY1_DVDDRG: length 15.3
  TOP w0.203: U27.28 127.6,109.25 v1(127.68,109.17)
  TOP w0.305: v1(114.41,107.52) 114.72,107.83 U125.3 ; v1(119.11,114.51) R451.1 R447.1 ; R1319.1 v1(113.9,102.32)
  BOTTOM w0.305: v1(114.41,107.52) 114.54,107.65 C523.1
  BOTTOM w0.381: v1(123.42,109.04) R430.1 R433.1 R428.1 R429.1 R444.1 ; C199.1 128.73,108.15 ; 128.73,108.15 R431.1 R444.1 ; 128.73,108.15 R457.1 ; 126.98,109.3 127.55,109.3 v1(127.68,109.17) ; 126.98,109.3 R444.1 ; 126.98,109.3 C200.1
PHY1_LED0_CFG_EXT: length 6.6
  TOP w0.127: R434.2 R437.1 130.66,109.43 130.66,110.44 129.65,111.45 U27.32
PHY1_LED1_CFGLDO0: length 52.3
  TOP w0.127: U27.33 129.85,111.85 132.28,109.43 v2(132.58,109.43) R438.1
  BOTTOM w0.127: J29.14 121.66,138.18 133.92,138.18 137.27,134.83 137.27,123.75 133.84,120.32 133.84,111.84 133.04,111.04 133.04,111.01 132.89,110.85 132.89,109.74 v2(132.58,109.43)
PHY1_LED2_CFGLDO1: length 38.1
  TOP w0.127: U27.34 130.12,112.26 131.17,111.2 v2(132.58,111.2) R436.2
  BOTTOM w0.127: v2(132.58,111.2) 132.95,111.58 132.95,111.58 133.51,112.14 133.51,115.45 133.46,115.5 133.46,120.47 136.89,123.9 136.89,134.57 133.84,137.62 131.82,137.62 J29.12
PHY1_RGMII_MDC: length 14.7
  TOP w0.127: U27.13 121.92,113.85 121.27,114.51 R451.2 120.62,114.77 120.38,115.01 118.85,115.01 116.69,112.85 116.69,111.46 115.42,110.19 114.45,110.19 114.07,109.81 U125.4
PHY1_RGMII_MDIO: length 17.8
  TOP w0.127: U125.5 114.07,106.16 114.66,106.76 116.06,106.76 116.69,107.39 116.69,110.95 117.07,111.33 117.07,112.47 117.58,112.98 120.5,112.98 120.62,113.11 R447.2 124.1,113.49 U27.14
PHY1_TRX0_N: length 12.7
  TOP w0.107: J29.3 129.65,124.38 129.81,124.54 130.41,124.54 130.66,124.29 130.66,122.49 130.17,122 129.53,122 128.87,121.34 128.87,120.54 128.75,120.42 U26.2 U26.9 128.75,118.5 128.87,118.38 128.87,117.91 128.07,117.11 128.07,115.98 128,115.91 U27.2
PHY1_TRX0_P: length 12.7
  TOP w0.107: J29.2 130.28,125.3 130.28,125.05 130.92,124.41 130.92,122.38 130.28,121.74 129.63,121.74 129.13,121.24 129.13,120.54 129.25,120.42 U26.1 U26.10 129.25,118.5 129.13,118.38 129.13,117.8 128.33,117 128.33,115.98 128.4,115.91 U27.1
PHY1_TRX1_N: length 11.8
  TOP w0.107: U27.5 126.8,115.91 126.87,115.98 126.87,117.18 127.37,117.68 127.37,118.38 127.25,118.5 U26.6 U26.5 127.25,120.42 127.37,120.54 127.37,122.01 128.26,122.9 128.26,124.15 127.87,124.54 127.37,124.54 127.11,124.28 J29.5
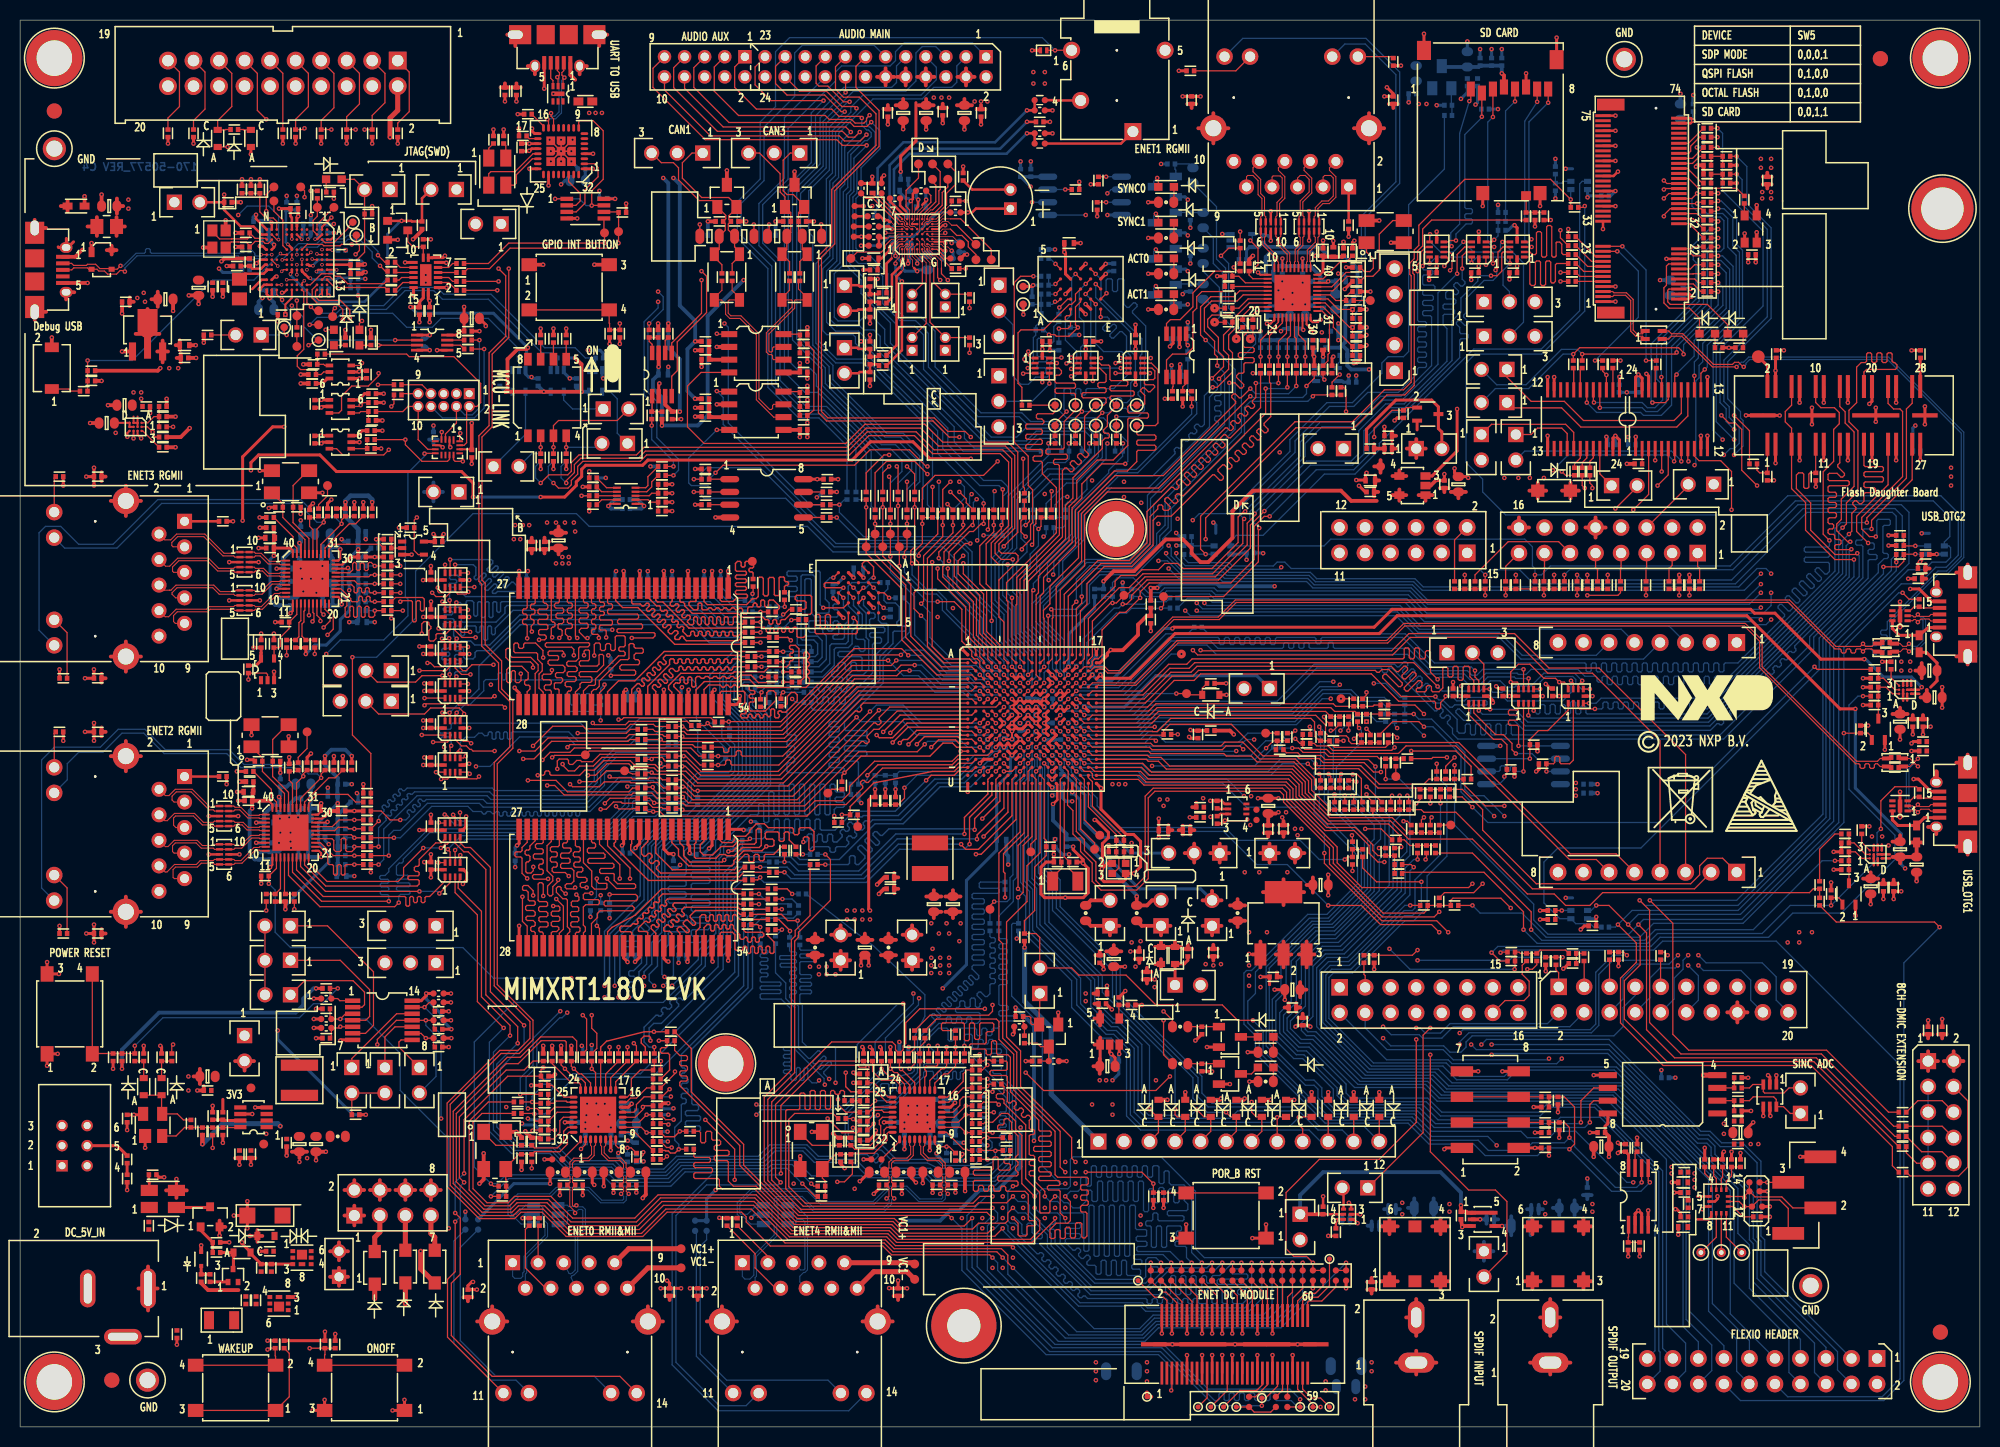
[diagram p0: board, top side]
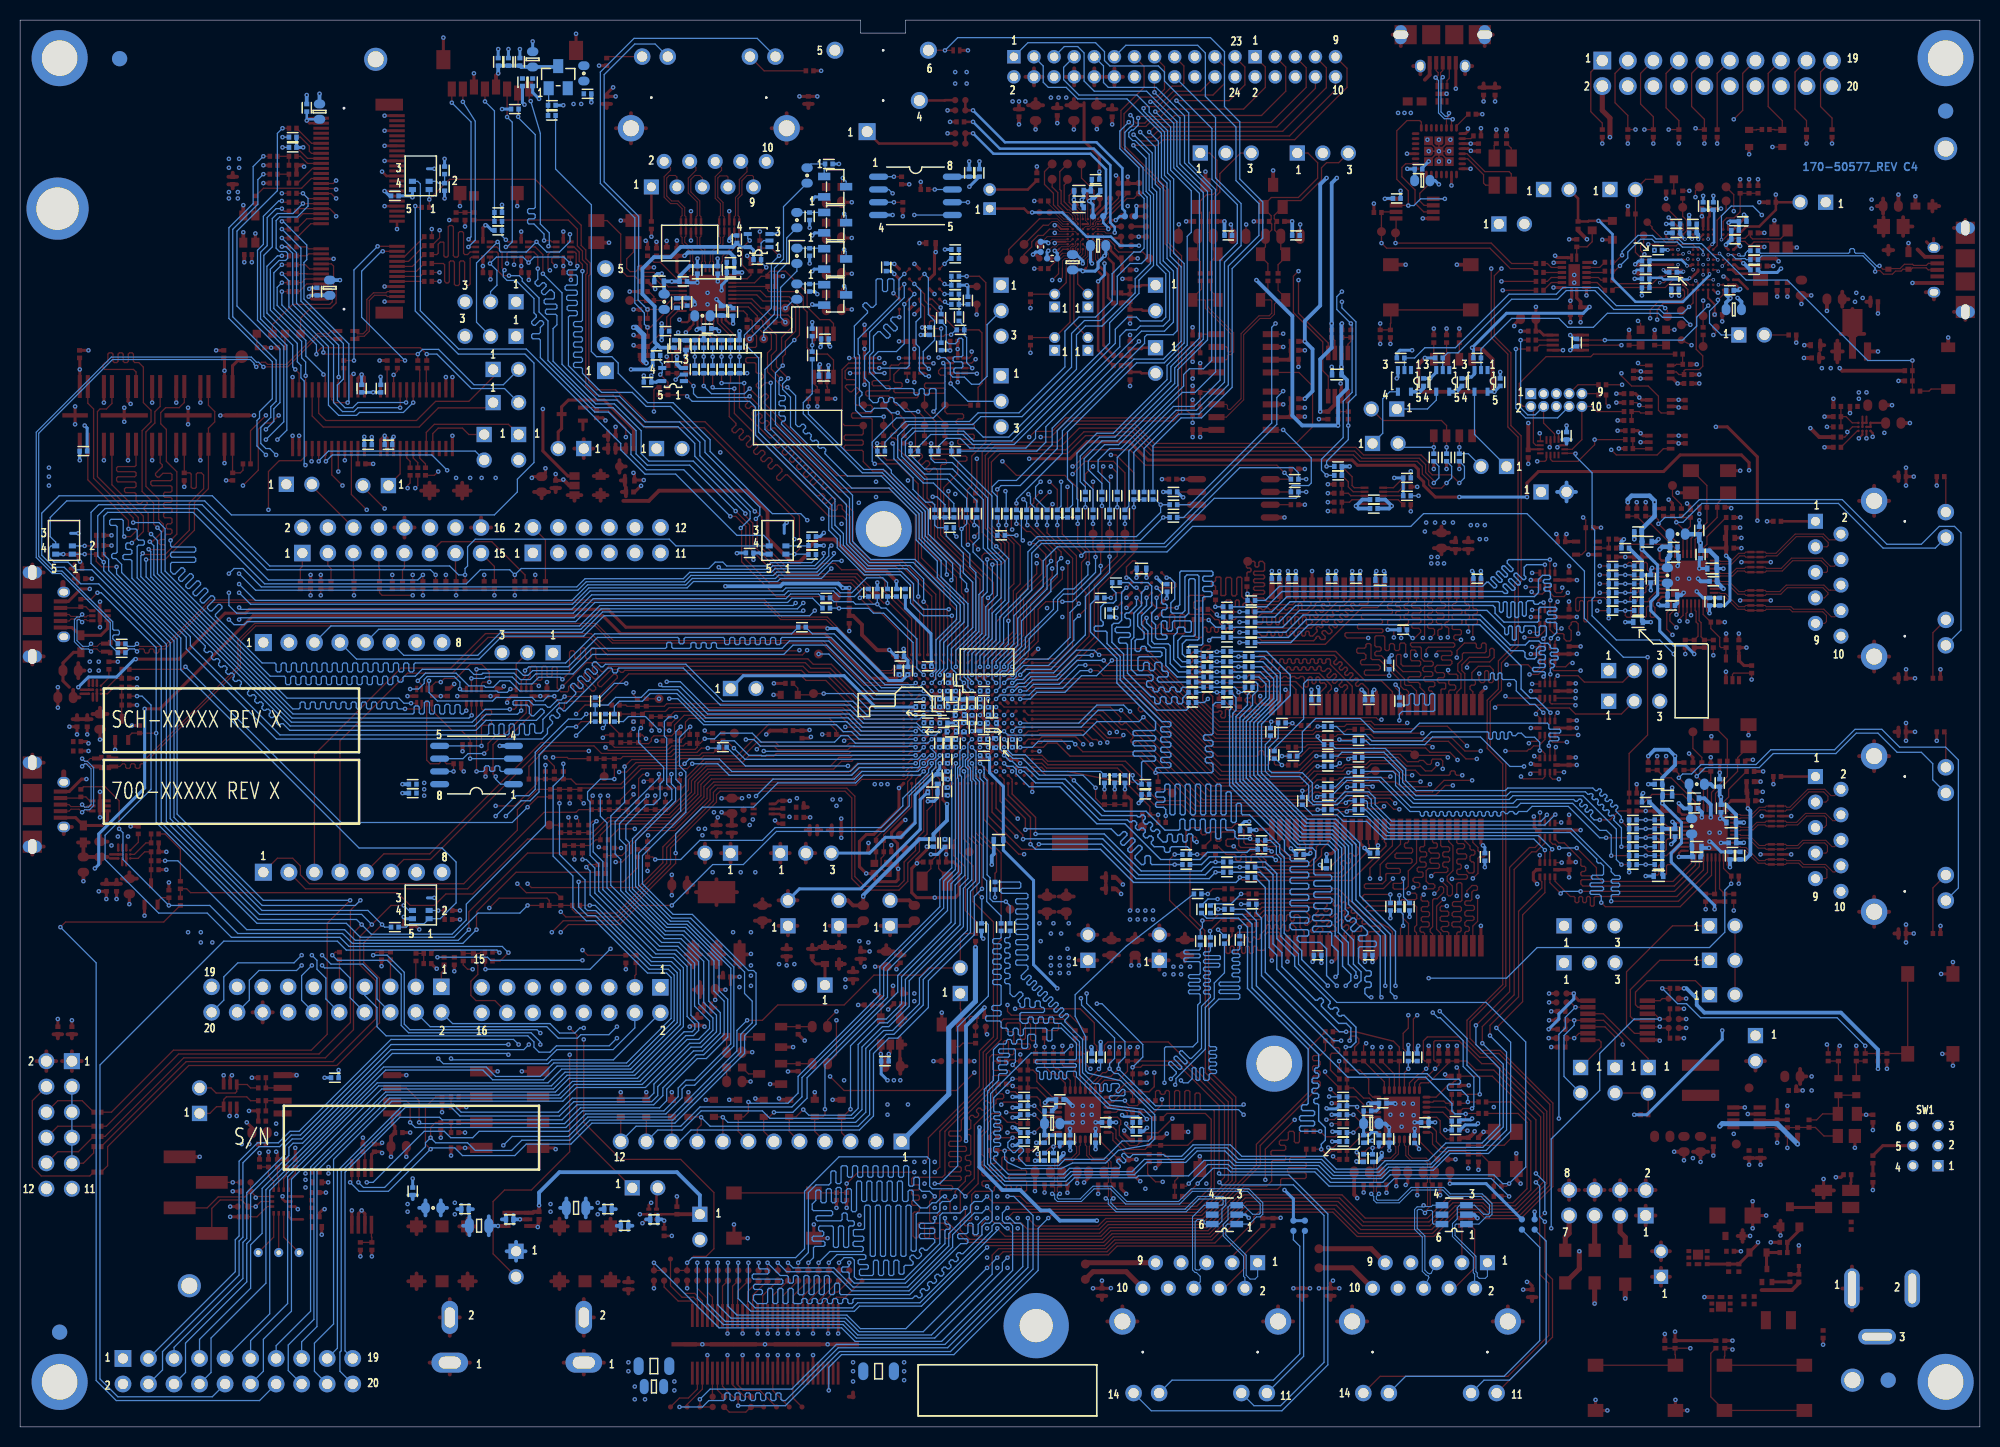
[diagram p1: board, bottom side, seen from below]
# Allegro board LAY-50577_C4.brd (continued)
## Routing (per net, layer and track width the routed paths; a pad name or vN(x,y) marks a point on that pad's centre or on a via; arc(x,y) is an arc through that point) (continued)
PHY1_TRX1_P: length 11.9
  TOP w0.107: U27.4 127.2,115.91 127.13,115.98 127.13,117.07 127.63,117.57 127.63,118.38 127.75,118.5 U26.7 U26.4 127.75,120.42 127.63,120.54 127.63,121.9 128.52,122.79 128.52,124.27 127.75,125.04 127.75,125.31 J29.4
PHY1_TRX2_N: length 11.9
  TOP w0.107: J29.7 124.57,124.38 124.67,124.49 125.38,124.49 125.58,124.29 125.58,122.37 125.06,121.86 125.06,120.54 124.94,120.42 U28.2 U28.9 124.94,118.5 125.06,118.38 125.06,117.71 126.07,116.7 126.07,115.98 126,115.91 U27.7
PHY1_TRX2_P: length 11.9
  TOP w0.107: J29.6 125.2,125.3 125.2,125.05 125.84,124.41 125.84,122.27 125.32,121.75 125.32,120.54 125.44,120.42 U28.1 U28.10 125.44,118.5 125.32,118.38 125.32,117.82 126.33,116.81 126.33,115.98 126.4,115.91 U27.6
PHY1_TRX3_N: length 12
  TOP w0.107: U27.10 124.8,115.91 124.87,115.98 124.87,116.38 123.56,117.69 123.56,118.38 123.44,118.5 U28.6 U28.5 123.44,120.42 123.56,120.54 123.56,122.24 123.18,122.62 123.18,124.02 122.66,124.54 122.15,124.54 122.03,124.41 J29.9
PHY1_TRX3_P: length 12
  TOP w0.107: U27.9 125.2,115.91 125.13,115.98 125.13,116.48 123.82,117.79 123.82,118.38 123.94,118.5 U28.7 U28.4 123.94,120.42 123.82,120.54 123.82,122.35 123.44,122.73 123.44,124.14 122.67,124.91 122.67,125.31 J29.8
PHY1_XTALI: length 14.1
  TOP w0.127: U27.36 130.61,113.05 132.05,114.49 132.94,114.49 133.32,114.11 C185.1 133.83,114.51 134.6,114.51 135.24,115.14 135.24,118.7 136.59,120.05 X1.3
PHY1_XTALO: length 9.7
  TOP w0.127: X1.1 133.97,116.91 134.64,116.24 134.64,115.31 134.31,114.97 133.75,114.97 C184.1 133.32,115.13 133.08,114.89 131.93,114.89 130.5,113.45 U27.37
PHY2_AVDD10: length 12.8
  TOP w0.203: U29.3 v1(23.49,60.13) ; U29.8 v1(23.49,58.13) ; U29.38 25.9,62.55 v1(25.76,62.69)
  BOTTOM w0.381: C214.1 24.24,60.12 C213.1 23.51,58.12 v1(23.49,58.13) ; C214.1 24.27,60.95 25.25,61.92 C211.1 v1(25.76,62.69) 25.89,62.82 C212.1 26.53,63.71 26.78,63.96 R523.2 ; C214.1 23.51,60.15 v1(23.49,60.13)
PHY2_AVDD33: length 14
  TOP w0.203: v1(24.87,55.7) 25.1,55.94 U29.11 ; 24.72,62.31 25.1,61.93 U29.40
  TOP w0.381: 23.14,62.31 C216.1 v1(23.09,61.55) ; 23.14,62.31 23.14,63.14 C217.1 23.22,63.22 R509.1 ; 23.14,62.31 24.72,62.31
  BOTTOM w0.381: v1(24.87,55.7) C215.1 C218.1 23.34,56.47 22.84,56.97 22.84,61.3 v1(23.09,61.55)
PHY2_CT: length 3.4
  TOP w0.254: J30.1 C205.1
PHY2_DVDD10: length 4.8
  TOP w0.203: v1(29.95,56.72) 29.95,57.1 29.72,57.33 U29.21
  BOTTOM w0.381: v1(29.95,56.72) C220.1 28.65,56.82 C219.1 28.68,57.77 28.68,59.01
PHY2_DVDD33: length 29.3
  TOP w0.203: U29.29 30.03,60.53 30.28,60.78
  TOP w0.305: R481.1 R480.1 v1(30.33,66.75) ; R479.1 v1(33,66.75) ; 30.28,60.78 30.33,60.78
  TOP w0.381: v1(26.4,51.51) R501.1 R503.1 ; v1(31.6,62.06) 31.61,62.05 C210.1 30.84,61.29 30.33,60.78
  BOTTOM w0.305: v1(26.4,51.51) 26.4,51.89 30.71,56.21 30.71,57.1 29.7,58.12 29.7,60.16 v1(31.6,62.06)
  BOTTOM w0.381: v1(33,66.75) 32.37,67.39 30.97,67.39 v1(30.33,66.75) 30.33,65.86 31.61,64.59 R508.1 31.57,63.92 C209.1 31.6,62.79 v1(31.6,62.06)
PHY2_DVDDRG: length 11.3
  TOP w0.203: U29.28 30.51,60.13 v1(30.59,60.21)
  BOTTOM w0.381: v1(30.59,60.21) 30.33,59.96 C222.1 30.34,59.51 R476.1 ; R510.1 31.61,60.91 R475.1 R476.1 ; R476.1 R473.1 R472.1 R477.1 R474.1 31.61,54.92 C221.1
PHY2_LED0_CFG_EXT: length 6.6
  TOP w0.127: U29.32 28.3,62.19 30.71,64.59 31.34,64.59 R492.1 R479.2
PHY2_LED1_CFGLDO0: length 51.3
  TOP w0.127: R493.1 R480.2 29.95,64.98 v1(29.95,64.59) 27.9,62.55 U29.33
  BOTTOM w0.127: J30.14 2.14,53.63 2.14,66.37 3.41,67.64 7.98,67.64 9.76,69.42 12.43,69.42 14.46,67.39 20.81,67.39 22.28,65.92 27.74,65.92 28.68,64.98 29.57,64.98 v1(29.95,64.59)
PHY2_LED2_CFGLDO1: length 35.1
  TOP w0.127: R481.2 R494.1 28.17,64.98 v1(28.17,64.75) 27.5,64.08 U29.34
  BOTTOM w0.127: v1(28.17,64.75) 27.31,65.61 21.95,65.61 20.56,67.01 14.33,67.01 12.3,69.04 10.14,69.04 8.24,67.13 5.82,67.13 4.69,66 4.69,64.4 J30.12
PHY2_RGMII_MDC: length 4.7
  TOP w0.127: R504.2 R503.2 25.9,53.56 U29.13
PHY2_RGMII_MDIO: length 4.6
  TOP w0.127: R502.2 R501.2 26.31,53.12 U29.14
PHY2_RGMII_TX_EN: length 21.8
  TOP w0.127: U103.1 42.28,58.51 41.89,58.12 41.35,58.12 39.71,56.47 39.71,55.91 39.58,55.78 39.35,55.78 39.22,55.65 39.22,55.4 39.35,55.27 39.58,55.27 39.71,55.15 39.71,54.95 39.6,54.84 38.7,54.84 38.59,54.73 38.59,54.57 38.7,54.46 39.6,54.46 39.71,54.35 39.71,54.03 39.5,53.83 30.41,53.83 28.3,55.93 U29.19
PHY2_RGMII_TXC: length 17.9
  TOP w0.127: U29.20 28.71,56.11 30.54,54.28 37.62,54.28 38.16,54.82 38.16,55.65 v1(40.11,57.61) ; v1(41.86,57.62) 41.9,57.62 42.27,57.99 42.5,57.99 42.78,58.27 U103.2
  BOTTOM w0.127: v1(41.86,57.62) 41.86,57.61 40.12,57.61 v1(40.11,57.61)
PHY2_RGMII_TXD0: length 17.9
  TOP w0.127: v1(41.72,53.09) 42.78,54.15 42.78,54.74 U106.2 ; v1(39.73,53.29) 30.38,53.29 27.9,55.77 U29.18
  BOTTOM w0.127: v1(41.72,53.09) 41.51,53.29 v1(39.73,53.29)
PHY2_RGMII_TXD1: length 21.8
  TOP w0.127: U106.1 42.27,54.73 42.27,54.31 40.75,52.78 40.4,52.78 40.29,52.67 40.29,52.29 40.18,52.17 40.02,52.17 39.91,52.29 39.91,52.67 39.8,52.78 39.64,52.78 39.53,52.67 39.53,52.29 39.41,52.17 39.26,52.17 39.14,52.29 39.14,52.67 39.03,52.78 38.88,52.78 38.76,52.67 38.76,51.93 38.65,51.82 38.49,51.82 38.38,51.93 38.38,52.67 38.27,52.78 30.16,52.78 27.5,55.44 U29.17
PHY2_TRX0_N: length 12.4
  TOP w0.107: J30.3 15.32,62.18 15.12,62.38 15.12,62.77 15.55,63.19 17.02,63.19 18.81,61.41 19.22,61.41 19.34,61.29 U30.2 U30.9 21.26,61.29 21.38,61.41 21.85,61.41 22.65,60.6 23.78,60.6 23.85,60.53 U29.2
PHY2_TRX0_P: length 12.3
  TOP w0.107: J30.2 14.45,62.83 14.81,62.83 15.44,63.45 17.13,63.45 18.91,61.66 19.22,61.66 19.34,61.78 U30.1 U30.10 21.26,61.78 21.38,61.66 21.96,61.66 22.76,60.86 23.78,60.86 23.85,60.93 U29.1
PHY2_TRX1_N: length 11.9
  TOP w0.107: U29.5 23.85,59.33 23.78,59.4 22.58,59.4 22.08,59.91 21.38,59.91 21.26,59.78 U30.6 U30.5 19.34,59.78 19.22,59.91 18.13,59.91 17.24,60.79 15.47,60.79 15.27,60.6 15.27,59.87 15.5,59.64 J30.5
PHY2_TRX1_P: length 11.9
  TOP w0.107: U29.4 23.85,59.73 23.78,59.66 22.69,59.66 22.19,60.16 21.38,60.16 21.26,60.28 U30.7 U30.4 19.34,60.28 19.22,60.16 18.24,60.16 17.35,61.05 15.36,61.05 14.64,60.33 14.41,60.33 J30.4
PHY2_TRX2_N: length 12
  TOP w0.107: U29.7 23.85,58.53 23.78,58.6 23.06,58.6 22.05,57.6 21.38,57.6 21.26,57.48 U31.9 U31.2 19.34,57.48 19.22,57.6 18.03,57.6 17.51,58.11 15.44,58.11 15.17,57.84 15.17,57.25 15.32,57.1 J30.7
PHY2_TRX2_P: length 11.9
  TOP w0.107: J30.6 14.45,57.75 14.71,57.75 15.34,58.37 17.62,58.37 18.14,57.85 19.22,57.85 19.34,57.97 U31.1 U31.10 21.26,57.97 21.38,57.85 21.94,57.85 22.95,58.86 23.78,58.86 23.85,58.93 U29.6
PHY2_TRX3_N: length 12.1
  TOP w0.107: U29.10 23.85,57.33 23.78,57.4 23.38,57.4 22.07,56.1 21.38,56.1 21.26,55.97 U31.6 U31.5 19.34,55.97 19.22,56.1 18.02,56.1 17.64,55.71 15.47,55.71 15.22,55.47 15.22,54.69 15.35,54.56 J30.9
PHY2_TRX3_P: length 12
  TOP w0.107: U29.9 23.85,57.73 23.78,57.66 23.28,57.66 21.97,56.35 21.38,56.35 21.26,56.47 U31.7 U31.4 19.34,56.47 19.22,56.35 17.92,56.35 17.54,55.97 15.36,55.97 14.61,55.22 14.43,55.22 J30.8
PHY2_XTALI: length 9.7
  TOP w0.127: X2.3 26.61,69.89 25.13,68.41 C207.1 25.13,66.24 25.13,64.72 26.71,63.14 U29.36
PHY2_XTALO: length 7.5
  TOP w0.127: X2.1 24.1,66.6 C206.1 24.11,66.24 24.11,65.23 26.31,63.04 U29.37
PHY3_AVDD10: length 12.1
  TOP w0.203: U34.3 v1(25.52,85.41) ; v1(27.79,87.96) 27.94,87.82 U34.38 ; U34.8 v1(25.52,83.41)
  BOTTOM w0.305: v1(25.52,85.41) 25.54,85.42 C236.1
  BOTTOM w0.457: R576.2 29.3,88.83 C233.1 27.92,88.09 v1(27.79,87.96) C235.1 26.9,87.19 26.18,86.47 C236.1 26.15,85.4 26.15,84.15 C234.1 26.15,84.03 v1(25.52,83.41)
PHY3_AVDD33: length 13.9
  TOP w0.203: U34.11 27.14,81.21 v1(26.9,80.98) ; U34.40 27.14,87.22 26.91,87.45
  TOP w0.305: 26.91,87.45 C240.1
  TOP w0.381: R562.1 25.25,88.57 C239.1 25.25,88.37 C240.1 v1(25.25,86.69)
  BOTTOM w0.305: v1(25.25,86.69) 24.87,86.32 24.87,82.25 25.37,81.75 C237.1 C238.1 v1(26.9,80.98)
PHY3_CLK125_OUT: length 2.7
  TOP w0.127: R572.2 29.7,91.77 30.59,92.66 TP26.1
PHY3_CT: length 3.4
  TOP w0.254: J31.1 C227.1
PHY3_DVDD10: length 4.3
  TOP w0.203: v1(32,81.87) 32,82.24 31.63,82.61 U34.21
  BOTTOM w0.381: v1(32,81.87) 31.87,81.74 C242.1 31.09,82.73 C241.1 31.06,83.94 R574.2
PHY3_DVDD33: length 29.6
  TOP w0.203: 32.4,86.15 32.06,85.81 U34.29
  TOP w0.305: v1(32.37,92.03) R531.1 R532.1 ; 32.4,86.15 32.45,86.15 32.87,86.57 C232.1 33.64,87.32 v1(33.63,87.33) ; R556.1 R554.1 v1(28.43,76.91) ; R530.1 v1(35.03,92.03)
  BOTTOM w0.305: v1(33.63,87.33) 32.06,85.76 32.06,82.81 32.75,82.12 32.75,81.23 31.86,80.34 31.86,79.2 30.46,77.8 29.32,77.8 v1(28.43,76.91)
  BOTTOM w0.457: v1(35.03,92.03) 35.03,92.28 34.65,92.66 32.87,92.66 32.37,92.15 v1(32.37,92.03) 32.37,90.63 33.64,89.35 R561.1 33.64,88.13 C231.1 33.63,88.06 v1(33.63,87.33)
PHY3_DVDDRG: length 11.6
  TOP w0.203: U34.28 32.54,85.41 v1(32.62,85.48)
  BOTTOM w0.305: v1(32.62,85.48) 32.75,85.36 C244.1
  BOTTOM w0.381: v1(32.75,80.09) C243.1 33.64,80.19 R526.1 R529.1 R524.1 R525.1 R551.1 ; C244.1 33.64,84.78 R551.1 ; R551.1 R527.1 33.64,86.18 R563.1
PHY3_LED0_CFG_EXT: length 6.6
  TOP w0.127: U34.32 30.34,87.46 32.75,89.87 33.38,89.87 R543.1 R530.2
PHY3_LED1_CFGLDO0: length 51.4
  TOP w0.127: R544.1 R531.2 31.98,90.26 v1(31.98,89.87) 29.94,87.82 U34.33
  BOTTOM w0.127: J31.14 1.89,79.29 1.89,88.98 2.52,89.61 4.04,89.61 5.82,87.84 9.25,87.84 13.7,92.28 27.91,92.28 29.69,90.5 31.35,90.5 v1(31.98,89.87)
PHY3_LED2_CFGLDO1: length 35
  TOP w0.127: R532.2 R545.1 30.21,90.26 v1(30.21,90.02) 29.54,89.35 U34.34
  BOTTOM w0.127: J31.12 4.44,87.45 9.63,87.45 14.08,91.9 27.67,91.9 29.55,90.02 v1(30.21,90.02)
PHY3_RGMII_MDC: length 4.7
  TOP w0.127: R557.2 R556.2 27.74,78.64 27.74,80.04 27.94,80.23 U34.13
PHY3_RGMII_MDIO: length 4.8
  TOP w0.127: U34.14 28.34,81.27 28.24,81.17 28.24,80.11 28.05,79.91 28.05,78.69 R554.2 R555.2
PHY3_RGMII_RX_EN: length 24.6
  TOP w0.127: R569.2 v1(37.83,84.79) ; U101.2 42.78,64.73 42.53,64.47 v1(41.89,64.47)
  L3_INT_1 w0.127: v1(41.89,64.47) 41.89,65.48 41.56,65.81 41.56,68.86 41.43,69 41.43,75.05 41.76,75.39 41.76,77.93 41.13,78.56 41.13,80.72 39.1,82.76 39.1,83.34 38.46,83.98 38.46,84.15 v1(37.83,84.79)
PHY3_RGMII_RXC: length 22
  TOP w0.127: U97.1 42.28,79.47 42.14,79.33 41.76,79.33 v1(41.64,79.45) ; v1(37.82,85.67) 36.93,85.67 R568.2 C245.1
  L3_INT_1 w0.127: v1(37.82,85.67) 37.36,85.67 37.27,85.58 37.27,84.61 37.04,84.38 35.92,84.38 35.79,84.51 35.79,84.65 35.91,84.76 36.72,84.76 36.84,84.87 36.84,85.03 36.72,85.14 35.91,85.14 35.79,85.25 35.79,85.41 35.91,85.52 36.72,85.52 36.84,85.63 36.84,85.79 36.72,85.9 35.91,85.9 35.79,86.01 35.79,86.18 35.9,86.29 37.98,86.29 38.97,85.3 38.97,84.03 39.4,83.59 39.4,82.96 41.64,80.72 v1(41.64,79.45)
PHY3_RGMII_RXD0: length 24.6
  TOP w0.127: U100.2 42.78,68.41 42.53,68.15 v1(41.09,68.15) ; R564.2 v1(37.83,83.9)
  L3_INT_1 w0.127: v1(41.09,68.15) 41.12,68.18 41.12,75.26 41.38,75.52 41.38,77.8 40.75,78.44 40.75,80.63 38.72,82.66 38.72,83.01 38.25,83.48 36.11,83.48 35.95,83.64 35.95,83.95 36.07,84.08 37.65,84.08 v1(37.83,83.9)
PHY3_RGMII_RXD1: length 22.6
  TOP w0.127: v1(41.38,65.16) U101.1 ; R566.2 v1(37.83,83.01)
  L3_INT_1 w0.127: v1(37.83,83.01) 37.81,83.02 37.42,83.02 37.29,82.9 37.29,82.72 37.42,82.59 38.25,82.59 39.48,81.36 39.48,80.47 40.43,79.51 40.43,78.32 41,77.75 41,75.64 40.71,75.35 40.71,68.43 40.62,68.35 40.62,67.96 40.71,67.87 40.71,67.81 41.26,67.26 41.26,65.29 v1(41.38,65.16)
PHY3_RGMII_RXD2: length 22.4
  TOP w0.127: U98.1 42.28,75.78 42.14,75.64 41.22,75.64 40.84,76.02 v1(40.53,76.02) ; R567.2 36.94,82.12 37.36,82.54 40.05,82.54 40.21,82.37 40.21,81.31 40.1,81.2 39.94,81.2 39.83,81.31 39.83,82.11 39.72,82.22 39.53,82.22 39.42,82.11 39.42,80.23 39.3,80.11 39.15,80.11 39.04,80.23 39.04,82.11 38.92,82.22 37.93,82.22 v1(37.83,82.12)
  L3_INT_1 w0.127: v1(37.83,82.12) 37.45,81.74 37.45,79.86 39.15,78.16 40.01,78.16 40.62,77.55 40.62,76.11 v1(40.53,76.02)
PHY3_RGMII_RXD3: length 16.2
  TOP w0.127: R565.2 v1(38.08,81.23) ; U97.2 42.78,79.33 42.4,78.95 41.49,78.95 41.38,78.83 41.38,78.44 41.15,78.21 40.8,78.21 40.67,78.34 40.67,79.26 40.87,79.46 40.87,79.64 40.67,79.84 40.67,80.01 40.54,80.14 40.19,80.14 39.96,79.91 v1(39.96,78.94)
  L3_INT_1 w0.127: v1(38.08,81.23) 38.33,80.98 38.33,80.82 37.84,80.33 37.84,80.17 37.95,80.06 38.11,80.06 38.6,80.55 38.76,80.55 38.87,80.44 38.87,80.28 38.38,79.79 38.38,79.64 38.49,79.52 38.65,79.52 39.14,80.01 39.3,80.01 39.41,79.9 39.41,79.74 38.87,79.2 38.87,79.05 38.98,78.93 39.14,78.93 39.68,79.47 39.84,79.47 39.96,79.35 v1(39.96,78.94)
PHY3_RGMII_TX_EN: length 22.6
  TOP w0.127: U99.2 42.78,72.09 42.65,71.96 42.54,71.96 42.54,71.95 40.4,71.95 40.28,71.83 40.26,71.83 v1(40.24,71.81) ; v1(30.2,79.56) 30.84,80.2 30.84,80.85 30.34,81.36 U34.19
  L3_INT_1 w0.127: v1(40.24,71.81) 40.22,71.83 39.9,71.83 38.96,72.78 38.96,76.09 37.42,77.63 37.39,77.63 37.28,77.74 37.28,77.77 37.17,77.88 37.01,77.88 36.9,77.77 36.9,77.74 36.79,77.63 36.63,77.63 36.52,77.74 36.52,77.77 36.41,77.88 36.25,77.88 36.14,77.77 36.14,77.74 36.03,77.63 35.87,77.63 35.76,77.74 35.76,77.77 35.65,77.88 35.49,77.88 35.38,77.77 35.38,77.74 35.27,77.63 35.11,77.63 35,77.74 35,77.77 34.89,77.88 34.73,77.88 34.62,77.77 34.62,77.74 34.5,77.63 34.35,77.63 34.23,77.74 34.23,77.77 34.12,77.88 33.97,77.88 33.85,77.77 33.85,77.74 33.74,77.63 33.58,77.63 33.47,77.74 33.47,77.77 33.36,77.88 33.2,77.88 33.09,77.77 33.09,77.74 32.98,77.63 32.54,77.63 30.61,79.56 v1(30.2,79.56)
PHY3_RGMII_TXC: length 22.6
  TOP w0.127: v1(39.97,68.86) 40.04,68.86 40.06,68.84 U100.1 ; v1(30.59,78.82) 31.16,79.39 31.16,81.04 30.74,81.46 U34.20
  L3_INT_1 w0.127: v1(39.97,68.86) 39.48,69.35 39.48,71.33 38.59,72.21 38.59,75.77 37.14,77.22 32.19,77.22 v1(30.59,78.82)
PHY3_RGMII_TXD0: length 22.6
  TOP w0.127: U34.18 29.94,81.09 v1(30.19,80.84) ; U98.2 42.78,75.65 42.4,75.26 v1(39.73,75.26)
  L3_INT_1 w0.127: v1(30.19,80.84) 30.6,80.84 32.44,79 32.77,79 32.88,79.11 32.88,79.44 33,79.56 33.15,79.56 33.27,79.44 33.27,79.11 33.38,79 33.54,79 33.65,79.11 33.65,79.44 33.76,79.56 33.92,79.56 34.03,79.44 34.03,79.11 34.14,79 34.3,79 34.41,79.11 34.41,79.44 34.52,79.56 34.68,79.56 34.79,79.44 34.79,79.11 34.9,79 35.06,79 35.17,79.11 35.17,79.44 35.28,79.56 35.44,79.56 35.55,79.44 35.55,79.11 35.66,79 35.82,79 35.93,79.11 35.93,79.44 36.04,79.56 36.2,79.56 36.31,79.44 36.31,79.11 36.43,79 36.58,79 36.69,79.11 36.69,79.42 36.81,79.53 36.96,79.53 37.08,79.42 37.08,79.16 39.73,76.51 v1(39.73,75.26)
PHY3_RGMII_TXD1: length 22.6
  TOP w0.127: v1(40.24,72.53) U99.1 ; v1(29.88,80.2) 29.88,80.41 29.54,80.76 U34.17
  L3_INT_1 w0.127: v1(29.88,80.2) 30.61,80.2 32.57,78.23 32.85,78.23 32.96,78.35 32.96,78.53 33.08,78.64 33.23,78.64 33.34,78.53 33.34,78.35 33.46,78.23 33.61,78.23 33.73,78.35 33.73,78.53 33.84,78.64 34,78.64 34.11,78.53 34.11,78.35 34.22,78.23 34.38,78.23 34.49,78.35 34.49,78.53 34.6,78.64 34.76,78.64 34.87,78.53 34.87,78.35 34.98,78.23 35.14,78.23 35.25,78.35 35.25,78.53 35.36,78.64 35.52,78.64 35.63,78.53 35.63,78.35 35.74,78.23 35.9,78.23 36.01,78.35 36.01,78.53 36.12,78.64 36.28,78.64 36.39,78.53 36.39,78.35 36.5,78.23 36.66,78.23 36.77,78.35 36.77,78.53 36.89,78.64 37.04,78.64 37.45,78.23 37.47,78.23 39.26,76.44 39.26,73.19 39.93,72.53 v1(40.24,72.53)
PHY3_RGMII_TXD2: length 22.6
  TOP w0.127: v1(29.1,80.16) 29.1,80.25 29.23,80.38 29.23,80.95 29.14,81.04 U34.16 ; U96.2 42.78,83.01 42.4,82.63 41.38,82.63 v1(41,83.01)
  L3_INT_1 w0.127: v1(29.1,80.16) 29.21,80.27 29.21,80.54 34.47,85.8 34.47,86.42 35.09,87.04 36.01,87.04 36.12,86.92 36.12,86.88 36.23,86.77 36.39,86.77 36.5,86.88 36.5,86.92 36.62,87.04 36.77,87.04 36.89,86.92 36.89,86.88 37,86.77 37.15,86.77 37.27,86.88 37.27,86.92 37.38,87.04 37.99,87.04 41,84.03 41,83.01 v1(41,83.01)
PHY3_RGMII_TXD3: length 22.6
  TOP w0.127: v1(41.56,83.52) 41.56,83.14 41.68,83.01 42.14,83.01 42.28,83.15 U96.1 ; v1(28.74,80.77) 28.74,80.78 U34.15
  L3_INT_1 w0.127: v1(28.74,80.77) 33.76,85.79 33.76,86.31 34.91,87.45 39.07,87.45 39.6,86.93 39.6,86.77 39.32,86.5 39.32,86.34 39.43,86.23 39.59,86.23 39.94,86.58 40.1,86.58 40.21,86.47 40.21,86.31 39.86,85.96 39.86,85.8 41.56,84.11 v1(41.56,83.52)
PHY3_TRX0_N: length 14.5
  TOP w0.107: J31.3 15.22,87.58 15.09,87.71 15.09,88.01 15.67,88.59 18.27,88.59 20.19,86.68 21.25,86.68 21.37,86.56 U32.2 U32.9 23.29,86.56 23.42,86.68 23.89,86.68 24.69,85.88 25.81,85.88 25.89,85.81 U34.2
PHY3_TRX0_P: length 14.4
  TOP w0.107: J31.2 14.4,88.27 14.99,88.27 15.57,88.85 18.38,88.85 20.3,86.94 21.25,86.94 21.37,87.06 U32.1 U32.10 23.29,87.06 23.42,86.94 23.99,86.94 24.79,86.14 25.81,86.14 25.89,86.21 U34.1
PHY3_TRX1_N: length 14
  TOP w0.107: U34.5 25.89,84.61 25.81,84.68 24.62,84.68 24.12,85.18 23.42,85.18 23.29,85.06 U32.6 U32.5 21.37,85.06 21.25,85.18 19.66,85.18 18.64,86.19 15.79,86.19 15.17,85.58 15.17,85.15 15.28,85.04 J31.5
PHY3_TRX1_P: length 14
  TOP w0.107: J31.4 14.48,85.65 14.88,85.65 15.68,86.45 18.75,86.45 19.76,85.44 21.25,85.44 21.37,85.56 U32.4 U32.7 23.29,85.56 23.42,85.44 24.22,85.44 24.72,84.94 25.81,84.94 25.89,85.01 U34.4
PHY3_TRX2_N: length 13.9
  TOP w0.107: U34.7 25.89,83.81 25.81,83.88 25.09,83.88 24.08,82.87 23.42,82.87 23.29,82.75 U33.9 U33.2 21.37,82.75 21.25,82.87 19.81,82.87 19.16,83.51 15.62,83.51 15.12,83.01 15.12,82.86 15.47,82.5 J31.7
PHY3_TRX2_P: length 13.9
  TOP w0.107: U34.6 25.89,84.21 25.81,84.14 24.98,84.14 23.97,83.13 23.42,83.13 23.29,83.25 U33.10 U33.1 21.37,83.25 21.25,83.13 19.91,83.13 19.27,83.77 15.51,83.77 15.01,83.27 14.86,83.27 14.86,83.26 14.33,83.26 J31.6
PHY3_TRX3_N: length 13.9
  TOP w0.107: U34.10 25.89,82.61 25.81,82.68 25.41,82.68 24.11,81.37 23.42,81.37 23.29,81.25 U33.6 U33.5 21.37,81.25 21.25,81.37 18.91,81.37 18.66,81.11 15.64,81.11 15.27,80.75 15.27,80.14 15.45,79.96 J31.9
PHY3_TRX3_P: length 14
  TOP w0.107: J31.8 14.43,80.62 14.78,80.62 15.53,81.37 18.55,81.37 18.81,81.63 21.25,81.63 21.37,81.75 U33.4 U33.7 23.29,81.75 23.42,81.63 24,81.63 25.31,82.94 25.81,82.94 25.89,83.01 U34.9
PHY3_XTALI: length 9.7
  TOP w0.127: X3.3 28.64,95.16 27.17,93.68 C229.1 27.16,91.51 27.16,89.99 28.74,88.42 U34.36
PHY3_XTALO: length 7.5
  TOP w0.127: U34.37 28.34,88.31 26.14,90.5 26.14,91.51 C228.1 26.14,91.88 X3.1
PHY4_3V3: length 3.9
  BOTTOM w0.381: R1284.1 L36.2 C522.1 93.07,30.18 R1285.1
PHY4_AVDD33: length 5.6
  TOP w0.305: U123.30 86.1,30.32 86.09,30.3 v1(85.96,30.3) ; U123.7 v1(90.51,27.53)
  BOTTOM w0.305: C521.1 v1(85.96,30.3)
  BOTTOM w0.381: 90.53,27.87 C519.1 ; C519.1 90.1,28.28 ; C519.1 90.96,28.28 ; 86.6,30.74 C521.1 86.6,29.87 ; 91.12,28.28 R1284.2 91.55,27.87
PHY4_COL: length 2.7
  TOP w0.14: R1311.2 84.44,31.32 84.93,31.82 U123.27
PHY4_CRS_DV: length 3.8
  TOP w0.127: U123.26 86.23,32.32 85.2,33.35 R1309.2 R1289.2
PHY4_LED0_AD0/PMEB: length 61.2
  TOP w0.127: v1(75.67,24.34) 75.16,24.84 75.16,32.08 79.49,36.41 R1170.2 R1171.1 84.82,35.38 85.71,34.5 87.1,34.5 87.51,34.09 U123.24
  BOTTOM w0.127: J32.12 72.23,2.11 69.58,2.11 65.26,6.43 65.26,21.03 68.31,24.08 75.42,24.08 v1(75.67,24.34)
PHY4_MDI0+: length 33
  TOP w0.107: U123.3 88.51,28.01 88.61,27.91 88.61,27.11 88.25,26.75 86.85,26.75 86.45,26.35 86.45,25.79 R1278.2 86.47,24.9 86.47,24.34 C512.1 86.45,23.84 86.45,22.92 86.26,22.74 v1(86.21,22.74)
  BOTTOM w0.107: J32.5 77.66,15.62 77.98,15.62 78.09,15.73 78.09,20.41 77.85,20.65 77.33,20.65 77.2,20.52 77.2,20.29 77.09,20.18 U124.6 75.7,20.18 75.42,20.47 75.42,21.67 75.04,22.05 75.04,22.67 75.31,22.94 77.82,22.94 79.09,21.67 85.85,21.67 86.47,22.29 86.47,22.63 86.36,22.74 v1(86.21,22.74)
PHY4_MDI0-: length 33.1
  TOP w0.107: v1(86.98,22.74) 86.71,23.01 86.71,23.81 C514.1 86.72,24.34 86.72,24.92 R1275.2 86.71,25.79 86.71,26.25 86.96,26.49 88.35,26.49 88.87,27.01 88.87,27.92 89.01,28.06 U123.4
  BOTTOM w0.107: v1(86.98,22.74) 86.83,22.74 86.72,22.63 86.72,22.18 85.95,21.41 78.98,21.41 77.71,22.68 75.41,22.68 75.3,22.56 75.3,22.17 75.4,22.06 U124.4 77.18,22.06 78.35,20.9 78.35,15.62 78.09,15.36 77.95,15.36 77.58,14.99 77.58,14.43 J32.6
PHY4_MDI1+: length 44.9
  TOP w0.107: v1(91.55,23.19) 91.8,23.45 91.8,23.82 C513.1 91.8,24.34 91.8,24.9 R1277.2 91.79,25.79 91.79,26.14 91.44,26.49 90.28,26.49 89.61,27.16 89.61,27.92 89.51,28.02 U123.5
  BOTTOM w0.107: J32.1 71.86,14.97 72.12,14.71 72.61,14.71 73.01,15.1 73.01,17.08 75.03,19.11 75.03,20.02 74.87,20.18 U124.1 72.71,20.18 72.58,20.32 72.56,20.32 71.98,20.9 71.61,20.9 71.35,21.16 71.35,22.3 72.75,23.7 78.47,23.7 79.73,22.44 84.89,22.44 86.41,23.95 88.25,23.95 89.52,22.68 91.67,22.68 91.8,22.81 91.8,23.09 91.69,23.19 v1(91.55,23.19)
PHY4_MDI1-: length 45
  TOP w0.107: U123.6 90.01,28.01 89.87,27.87 89.87,27.27 90.39,26.75 91.54,26.75 92.05,26.25 92.05,25.79 R1276.2 92.06,24.92 92.06,24.34 C511.1 92.06,23.83 92.06,23.44 v1(92.31,23.19)
  BOTTOM w0.107: J32.2 73.13,14.86 73.27,14.99 73.27,16.98 75.29,19 75.29,20.14 74.81,20.63 74.81,21.87 74.62,22.06 U124.3 73.27,22.06 72.37,21.16 71.72,21.16 71.61,21.27 71.61,22.2 72.86,23.44 78.36,23.44 79.62,22.18 84.99,22.18 86.51,23.7 88.14,23.7 89.41,22.43 91.78,22.43 92.06,22.7 92.06,23.09 92.17,23.19 v1(92.31,23.19)
PHY4_RST_B: length 6.2
  TOP w0.127: U123.21 89.01,34.26 v1(87.66,35.61) 87.5,35.77 87.5,36.36 R1288.2 R1312.2
  BOTTOM w0.127: v1(87.66,35.61) 87.5,35.77 87.5,36.39 R1288.2 R1312.2
PHY4_RXC: length 3.9
  TOP w0.127: U123.13 92.81,31.32 93.5,32.01 93.5,32.51 93.83,32.84 R1297.2
PHY4_RXD0: length 4.7
  TOP w0.127: U123.9 91.71,29.31 92.18,29.31 93.87,27.62 94.23,27.62 94.34,27.51 R1290.2 R1300.2
PHY4_RXD1: length 5.7
  TOP w0.127: R1291.2 R1302.2 v1(94.09,29.29) 93.56,29.82 U123.10
  BOTTOM w0.127: v1(94.09,29.29) R1302.2 R1291.2
PHY4_RXD2_INTB: length 4.9
  TOP w0.127: U123.11 93.34,30.32 v1(94.09,31.07) R1301.2 R1313.2
  BOTTOM w0.127: v1(94.09,31.07) R1301.2
PHY4_RXD3: length 5
  TOP w0.127: U123.12 92.95,30.82 v1(94.09,31.96) R1303.2
  BOTTOM w0.127: v1(94.09,31.96) R1303.2 R1180.2
PHY4_RXDV: length 4.4
  TOP w0.127: U123.8 91.01,28.17 91.3,27.89 v1(92.18,27.89) 92.44,27.89 R1298.2
  BOTTOM w0.127: R1298.2 R1177.1 v1(92.18,27.89)
PHY4_RXER/FXEN: length 7
  TOP w0.127: v1(84.94,30.18) 84.94,30.18 R1299.2 R1292.2 84.83,30.96 84.83,31.26 85.07,31.5 85.76,31.5 85.94,31.32 U123.28
  BOTTOM w0.127: R1178.1 R1179.2 84.41,29.43 84.94,29.96 v1(84.94,30.18)
PHY4_TXC: length 4.5
  TOP w0.127: R1304.2 R1293.2 93.83,33.73 92.42,32.32 U123.15
PHY4_TXD0: length 5.5
  TOP w0.127: U123.16 92.28,32.82 93.83,34.37 93.83,35.13 94.21,35.51 R1307.2 R1295.2
PHY4_TXD1: length 4.9
  TOP w0.127: R1306.2 R1296.2 93.07,35.89 92.31,35.13 91.93,35.13 91.01,34.21 U123.17
PHY4_TXD2: length 3.7
  TOP w0.127: R1308.2 92.18,35.89 91.93,35.64 91.67,35.64 90.51,34.48 U123.18
PHY4_TXD3: length 4.2
  TOP w0.127: U123.19 90.01,34.79 90.18,34.96 90.18,35.39 90.01,35.56 90.01,35.75 90.15,35.89 91.17,35.89 91.29,36.02 R1310.2
PHY4_TXEN: length 3.8
  TOP w0.127: U123.20 89.52,33.52 R1294.2 R1305.2
PHY4_VDD33: length 38.3
  TOP w0.305: R1277.1 v1(89.82,24.26) ; R1278.1 83.6,24.46 83.56,24.46 v1(83.55,24.45) ; R1283.1 85.71,37.67 v1(85.58,37.8) ; v1(93.02,32.26) 92.58,31.82 U123.14 ; v1(89.13,24.32) 88.68,24.78 R1275.1 ; v1(82.91,35.26) 83.04,35.13 R1172.1 ; v1(83.8,37.8) 83.93,37.67 R1170.1 ; R1282.1 v1(86.59,37.8)
  TOP w0.381: v1(94.02,23.47) 94.01,23.49 R1276.1
  L3_INT_1 w0.305: v1(69.2,23.57) 71.48,25.86 75.93,25.86 76.54,25.25 79.46,25.25 80.91,23.8 82,23.8 82.65,24.45 v1(83.55,24.45)
  BOTTOM w0.305: v1(96.25,30.79) 95.76,30.79 R1287.1 ; R1191.1 R1190.2 68.31,22.68 v1(69.2,23.57) ; v1(82.87,29.77) 83.22,29.42 R1179.1 ; R1174.1 95.99,29.8 v1(96.25,29.8) ; R1180.1 v1(96.25,32.84)
  BOTTOM w0.381: v1(88.42,37.8) 88.42,37.8 88.37,37.75 R1281.2 ; R1176.1 93.99,26.5 v1(94.01,26.48) ; R1285.2 91.92,31.84 C520.1 92.69,32.59 v1(93.02,32.26)
PHY4_XTAL1: length 11.4
  TOP w0.127: U123.31 86.23,29.82 85.96,29.54 85.96,28.73 84.84,27.61 83.07,27.61 R1280.2 C516.1 78.82,28.03 77.62,29.22 X6.1
PHY4_XTAL2: length 11.8
  TOP w0.127: R1333.2 R1334.2 80.11,24.47 79.82,24.76 X6.3 79.82,25.82 81.13,27.12 C515.1 R1279.2 82.77,27.23 84.97,27.23 86.26,28.53 86.26,29.19 86.39,29.32 U123.32
PIO0_5-ISP_EN-LED_SWD_ACT: length 13
  TOP w0.127: U55.A7 33.54,116.16 34.28,116.9 R851.2 34.28,123.14 JP3.2 33.25,124.16 D39.C
PMIC_ON_REQ: length 138.2
  TOP w0.127: U6.U9 100.69,58.75 99.8,57.86 99.8,53.19 v1(99.31,52.7) ; v1(19.16,27.76) R15.2
  L3_INT_1 w0.127: v1(19.16,27.76) 22.08,27.76 23.98,25.86 47.1,25.86 48.95,24.01 51.24,24.01 52.69,22.56 56.5,22.56 57.89,21.16 68.08,21.16 68.76,21.85 76.31,21.85 77.2,20.96 85.38,20.96 85.63,21.21 87.99,21.21 88.88,20.32 91.43,20.32 92.8,18.95 102.04,18.95 103.49,20.4 103.49,23.7 v1(103.99,24.21)
  BOTTOM w0.127: v1(99.31,52.7) 99.31,50.15 R44.2 98.79,50.11 98.66,49.98 98.66,42.88 101.71,39.83 101.71,25.99 103.49,24.21 v1(103.99,24.21)
POR_CTL: length 39.6
  TOP w0.127: U361.1 31.81,42.42 31.6,42.62 C562.1 30.84,42.76 R2098.2 v1(31.6,43.64) ; v1(11.41,37.92) R18.1 R34.2 C32.1 7.22,37.16 SW3.2 SW3.4
  BOTTOM w0.127: v1(31.6,43.64) 30.08,42.12 29.19,42.12 27.79,40.72 14.2,40.72 v1(11.41,37.92)
POR_PIN_RST_B: length 495.2
  TOP w0.127: v1(35.54,38.05) 35.54,38.56 37.45,40.46 U361.11 v1(40.37,40.46) C571.1 41.13,39.71 R2102.2 ; v1(122.66,40.46) 121.14,40.46 119.61,41.99 113.01,41.99 110.04,44.96 105.34,44.96 104.63,45.67 J92.2 101.45,48.72 101.08,49.09 R42.2 99.92,49.1 99.92,50.36 100.95,51.39 100.95,55.7 102.1,56.85 C36.1 102.1,58.37 101.89,58.57 101.89,64.44 U6.T10 ; D26.A v1(20.64,127.37) ; J90.2 J88.2 J91.2 ; v1(169.27,100.66) 170.03,99.9 170.67,99.9 171.3,99.27 171.3,95.2 v1(172.83,93.68)
  L3_INT_1 w0.127: v1(35.54,38.05) 35.41,37.92 31.6,37.92 30.84,38.69 30.84,43.39 29.83,44.4 25.76,44.4 J90.2 ; v1(172.83,93.68) 172.83,88.6 171.94,87.71 171.94,77.55 164.19,69.8 152.63,69.8 150.48,67.64 150.48,67.01 150.73,66.75 150.73,66.25 150.07,65.59 150.07,60.25 148.82,59.01 148.82,49.42 150.96,47.29 150.96,37.65 146.92,33.61 v1(146.92,28.02) ; J89.2 41,33.23 49.51,24.72 54.21,24.72 54.84,24.08 56.37,24.08 58.53,21.92 67.6,21.92 68.17,22.49 76.63,22.49 77.45,21.67 84.94,21.67 85.2,21.92 88.28,21.92 89.19,21.01 91.7,21.01 92.44,20.27 100.18,20.27 101.45,21.54 101.45,25.2 106.43,30.18 109.96,30.18 113.65,33.86 117.96,33.86 121.01,36.91 121.01,38.81 v1(122.66,40.46) ; v1(20.64,127.37) 24.54,131.27 41.64,131.27 53.57,119.33 60.18,119.33 66.15,113.36 75.93,113.36 81.39,118.82 81.39,119.97 83.67,122.25 87.23,122.25 87.99,123.01 93.96,123.01 101.45,115.52 101.45,111.53 99.22,109.3 99.22,104.35 101.12,102.44 110.47,102.44 112.12,100.79 128.17,100.79 129.83,102.44 142.73,102.44 144.08,103.79 151.29,103.79 154.41,100.66 v1(169.27,100.66)
  BOTTOM w0.127: v1(146.92,28.02) 146.03,28.91 140.44,28.91 138.51,30.84 130.26,30.84 123.68,37.42 123.68,39.45 v1(122.66,40.46) ; J89.2 41.38,34.88 41.38,38.94 40.37,39.96 v1(40.37,40.46)
QSPI0_OCT1_SEL_A: length 30.9
  TOP w0.127: U70.9 v1(112.5,106.37) ; U69.9 103.54,106.37 103.59,106.42 v1(103.61,106.42) ; U71.9 v1(107.55,106.37)
  L3_INT_1 w0.127: v1(112.5,106.37) 111.73,106.37 109.71,104.35 108.69,104.35 108.06,104.98 108.06,105.86 v1(107.55,106.37) 105.25,104.07 104.26,104.07 103.65,104.67 103.65,104.69 103.64,104.7 103.64,106.39 v1(103.61,106.42)
  BOTTOM w0.127: v1(103.61,106.42) 102.99,106.42 102.44,105.87 102.44,104.73 102.19,104.47 101.04,104.47 100.33,103.76 99.57,103.76 98.79,104.55 98.79,109.68 J75.2
QSPI0_OCT1_SEL_B: length 25.3
  TOP w0.127: v1(143.39,73.74) 143.61,73.96 144.01,73.96 144.14,73.83 U66.9 ; v1(142.73,66.63) 141.84,65.74 R904.2 ; U67.9 149.09,73.98 148.95,74.12 v1(148.32,74.12) 148.32,75.14 149.08,75.9 150.22,75.9 151.62,74.5 152.76,74.5 v1(153.14,74.12) 153.65,74.12 154.04,73.73 U68.9
  L3_INT_1 w0.127: v1(142.73,66.63) 142.73,73.08 v1(143.39,73.74) 143.9,74.25 148.19,74.25 v1(148.32,74.12)
RST_TGTMCU_B: length 234.6
  TOP w0.127: SW7.2 SW7.4 113.8,23.28 C466.1 R1041.2 v1(112.76,24.21) 111.61,25.35 v1(106.03,25.35) ; R2099.2 30.84,40.73 C565.1 v1(31.86,40.59) 32.38,41.12 U361.3
  L3_INT_1 w0.127: v1(106.03,25.35) 106.03,20.91 102.47,17.35 98.15,17.35 97.52,17.99 92.44,17.99 91.04,19.38 43.03,19.38 v1(42.65,19.76) ; v1(112.76,24.21) 121.9,24.21 124.82,27.13 137.78,27.13 150.6,39.96 150.6,46.81 147.81,49.61 147.81,59.26 149.08,60.53 149.08,62.82 148.19,63.71 148.19,68.4 149.21,69.42 150.98,69.42 152.13,70.56 160.76,70.56 J62.2 168.51,78.31 J46.1
  BOTTOM w0.127: v1(31.86,40.59) 34.4,40.59 37.83,37.16 37.83,33.48 42.65,28.65 v1(42.65,19.76)
RXC_PHYAD1_1: length 6.9
  TOP w0.127: R462.1 v1(127.87,106.5) 127.87,108.03 127.2,108.7 U27.27
  BOTTOM w0.127: R431.2 v1(127.87,106.5) R462.1
RXC_PHYAD1_2: length 6.9
  TOP w0.127: U29.27 31.06,59.73 31.73,60.4 v1(33.25,60.4) R515.1
  BOTTOM w0.127: R475.2 v1(33.25,60.4) R515.1
RXC_PHYAD1_3: length 10.1
  TOP w0.127: R568.1 v1(35.29,85.68) 34.93,86.03 34.75,86.03 34.64,85.92 34.64,85.33 34.52,85.22 34.37,85.22 34.26,85.33 34.26,85.84 34.11,85.99 33.95,85.99 33.84,85.88 33.84,85.35 33.73,85.24 33.57,85.24 33.46,85.35 33.46,85.91 33.33,86.03 33.22,86.03 33.09,85.91 33.09,85.29 32.81,85.01 U34.27
  BOTTOM w0.127: R527.2 v1(35.29,85.68) R568.1
RXCTL_PHYAD2_1: length 6.7
  TOP w0.127: U27.26 126.8,108.46 126.98,108.28 v1(126.98,106.5) R463.1
  BOTTOM w0.127: R444.2 v1(126.98,106.5) R463.1
RXCTL_PHYAD2_2: length 6.8
  TOP w0.127: R516.1 v1(33.25,59.51) 32.7,59.51 32.54,59.67 31.63,59.67 31.3,59.33 U29.26
  BOTTOM w0.127: R476.2 v1(33.25,59.51) R516.1
RXCTL_PHYAD2_3: length 6.7
  TOP w0.127: U34.26 34.7,84.61 34.88,84.79 v1(35.29,84.79) R569.1
  BOTTOM w0.127: R569.1 v1(35.29,84.79) R551.2
RXD0_RXDLY_1: length 6.7
  TOP w0.127: R458.1 v1(126.09,106.5) 126.09,108.28 126.4,108.59 U27.25
  BOTTOM w0.127: R429.2 v1(126.09,106.5) R458.1
RXD0_RXDLY_2: length 6.7
  TOP w0.127: U29.25 32.95,58.93 v1(33.25,58.63) R514.1
  BOTTOM w0.127: R514.1 v1(33.25,58.63) R473.2
RXD0_RXDLY_3: length 6.7
  TOP w0.127: U34.25 33.28,84.21 33.59,83.9 v1(35.29,83.9) R564.1
  BOTTOM w0.127: R564.1 v1(35.29,83.9) R525.2
RXD1_TXDLY_1: length 6.9
  TOP w0.127: R460.1 v1(125.2,106.5) 125.2,108.03 126,108.83 U27.24
  BOTTOM w0.127: R460.1 v1(125.2,106.5) R428.2
RXD1_TXDLY_2: length 10.4
  TOP w0.127: U29.24 31.04,58.53 31.21,58.36 31.21,57.44 31.4,57.25 31.83,57.25 31.94,57.37 31.94,58.46 32.05,58.58 32.29,58.58 32.4,58.46 32.4,57.37 32.51,57.25 33,57.25 33.25,57.51 v1(33.25,57.74) R511.1
  BOTTOM w0.127: R511.1 v1(33.25,57.74) R472.2
RXD1_TXDLY_3: length 8.7
  TOP w0.127: R566.1 v1(35.29,83.01) 34.85,83.01 34.74,83.12 34.74,83.41 34.63,83.52 34.47,83.52 34.36,83.41 34.36,83.12 34.25,83.01 34.09,83.01 33.98,83.12 33.98,83.41 33.86,83.52 33.71,83.52 33.59,83.41 33.59,83.12 33.48,83.01 33.33,83.01 33.23,83.11 33.23,83.57 32.99,83.81 U34.24
  BOTTOM w0.127: R524.2 v1(35.29,83.01) R566.1
RXD2_PLLOFF_1: length 7.1
  TOP w0.127: R459.1 v1(124.31,106.5) 124.31,108.59 125.6,109.87 U27.23
  BOTTOM w0.127: R459.1 v1(124.31,106.5) R433.2
RXD2_PLLOFF_2: length 7.1
  TOP w0.127: R512.1 v1(33.25,56.85) 31.17,56.85 29.89,58.13 U29.23
  BOTTOM w0.127: R512.1 v1(33.25,56.85) R477.2
RXD2_PLLOFF_3: length 8.8
  TOP w0.127: R567.1 v1(35.29,82.12) 34.94,82.12 34.83,82.23 34.83,82.54 34.71,82.65 34.56,82.65 34.45,82.54 34.45,82.23 34.33,82.12 34.18,82.12 34.06,82.23 34.06,82.54 33.95,82.65 33.79,82.65 33.68,82.54 33.68,82.23 33.57,82.12 33.03,82.12 32.9,82.25 32.9,82.43 31.92,83.41 U34.23
  BOTTOM w0.127: R529.2 v1(35.29,82.12) R567.1
RXD3_PHYAD0_1: length 7.3
  TOP w0.127: R461.1 v1(123.42,106.5) 123.42,108.16 125.2,109.93 U27.22
  BOTTOM w0.127: R461.1 v1(123.42,106.5) R430.2
RXD3_PHYAD0_2: length 11.5
  TOP w0.127: U29.22 29.83,57.73 30.61,56.95 30.61,56.09 30.74,55.96 31.07,55.96 31.18,55.85 31.18,55.03 31.3,54.92 31.45,54.92 31.56,55.03 31.56,55.85 31.68,55.96 31.83,55.96 31.95,55.85 31.95,55.03 32.06,54.92 32.22,54.92 32.33,55.03 32.33,55.85 32.44,55.96 v1(33.25,55.96) R513.1
  BOTTOM w0.127: R474.2 v1(33.25,55.96) R513.1
RXD3_PHYAD0_3: length 15.1
  TOP w0.127: U34.22 31.86,83.01 32.52,82.35 32.52,81.71 32.34,81.54 32.34,80.67 32.44,80.57 32.69,80.57 32.8,80.68 32.8,81.55 32.91,81.66 33.07,81.66 33.18,81.55 33.18,80.68 33.29,80.57 33.45,80.57 33.56,80.68 33.56,81.55 33.67,81.66 33.83,81.66 33.94,81.55 33.94,80.68 34.05,80.57 34.21,80.57 34.32,80.68 34.32,81.55 34.44,81.66 34.59,81.66 34.7,81.55 34.7,80.68 34.82,80.57 35.11,80.57 35.29,80.75 v1(35.29,81.23) R565.1
  BOTTOM w0.127: R526.2 v1(35.29,81.23) R565.1
RXD232: length 7.8
  TOP w0.127: U73.3 55.33,120.91 56.2,121.78 56.2,123.1 57.51,124.41 57.51,125.33 57.14,125.7 U72.2
RXLED: length 6.8
  TOP w0.127: D37.2 46.63,124.7 46.84,124.92 49.26,124.92 51.04,126.7 U72.21
SAI1_MCLK: length 40.7
  TOP w0.127: R86.2 85.07,94.95 86.21,96.09 89.01,96.09 v1(90.28,94.82) ; R2140.1 v1(94.09,122)
  L3_INT_1 w0.127: v1(94.09,122) 95.74,120.35 95.74,104.98 90.91,100.15 90.91,95.46 v1(90.28,94.82)
SAI1_RX_BCLK: length 23.3
  TOP w0.127: R2138.2 v1(94.47,111.33) ; R88.2 v1(88.25,94.06)
  L3_INT_1 w0.127: v1(88.25,94.06) 88.88,94.69 88.88,100.79 93.83,105.74 93.83,110.7 v1(94.47,111.33)
SAI1_RX_SYNC: length 22.3
  TOP w0.127: v1(86.47,94.57) 86.59,94.44 R89.2 ; R2139.2 v1(94.47,106.89)
  L3_INT_1 w0.127: v1(86.47,94.57) 87.4,93.64 88.59,93.64 89.52,94.57 89.52,100.54 94.47,105.49 v1(94.47,106.89)
SAI1_RXD[0]: length 21.7
  TOP w0.127: v1(86.47,96.73) 85.96,96.73 84.18,94.95 R87.2
  L3_INT_1 w0.127: v1(86.47,96.73) 86.72,96.98 86.72,101.87 90.02,105.17 90.02,110.19 J99.1
SAI1_TX_BCLK: length 21
  TOP w0.127: v1(86.47,95.58) 85.83,94.95 R85.2
  L3_INT_1 w0.127: v1(86.47,95.58) 87.36,96.47 87.36,101.42 90.66,104.73 90.66,110.06 J98.1
SAI1_TX_SYNC: length 16.2
  TOP w0.127: R84.2 87.36,95.46 v1(87.23,95.58)
  L3_INT_1 w0.127: J97.1 92.06,105.11 88.12,101.17 88.12,96.47 v1(87.23,95.58)
SAI1_TXD[0]: length 18.5
  TOP w0.127: R83.2 89.01,94.82 v1(88.25,95.58)
  L3_INT_1 w0.127: v1(88.25,95.58) 87.74,95.07 86.34,95.07 85.83,95.58 85.83,102.06 88.75,104.98 J100.1
SD1_CD_B: length 92.3
  TOP w0.127: R140.2 135.49,62.18 v1(133.97,63.71) ; R257.2 140.45,120.1 139.55,119.2 139.55,117.53 139.05,117.02 139.05,116.16 138.58,115.69 138.58,114.82 138.72,114.68 138.72,103.64 137.78,102.69 136,102.69 132.73,99.43 126.94,99.43 117.96,90.45 v1(117.96,88.34)
  L3_INT_1 w0.127: v1(117.96,88.34) 122.54,83.77 122.54,81.74 126.98,77.29 126.98,70.95 126.09,70.06 126.09,67.26 126.6,66.75 130.66,66.75 132.06,65.36 132.06,64.34 132.7,63.71 v1(133.97,63.71)
SD1_CLK: length 2.9
  TOP w0.127: U63.4 146.45,117.92 v1(146.67,118.13)
  BOTTOM w0.127: R258.1 C95.1 147.05,118.52 v1(146.67,118.13)
SD1_CMD: length 17.1
  TOP w0.127: U63.3 v1(146.67,117.42) ; J15.3 v1(146.55,130.36)
  BOTTOM w0.127: v1(146.67,117.42) 146.54,117.42 146.03,117.93 146.03,129.84 v1(146.55,130.36)
SD1_D0: length 17.1
  TOP w0.127: J15.7 v1(150.94,131.87) ; U64.3 v1(150.39,117.42)
  BOTTOM w0.127: v1(150.39,117.42) 149.71,118.1 149.71,129.94 v1(150.94,131.87)
SD1_D1: length 16.7
  TOP w0.127: J15.8 v1(152.04,131.78) ; U64.4 150.11,117.92 v1(150.38,118.19)
  BOTTOM w0.127: v1(152.04,131.78) 150.13,129.87 150.13,118.43 v1(150.38,118.19)
SD1_D2: length 17.1
  TOP w0.127: U65.3 142.36,117.42 v1(142.43,117.5) ; v1(144.2,131.94) 144.34,132.09 J15.1
  BOTTOM w0.127: v1(142.43,117.5) 142.35,117.58 142.35,118.82 143.24,119.71 143.24,128.73 v1(144.2,131.94)
SD1_D3: length 20.2
  TOP w0.127: v1(142.87,118.06) 142.22,118.06 142.08,117.92 U65.4 ; J15.2 v1(145.44,130.38)
  BOTTOM w0.127: v1(142.87,118.06) 142.87,118.71 143.87,119.71 144.38,119.71 144.51,119.84 144.51,120.09 144.38,120.22 143.87,120.22 143.74,120.35 143.74,120.6 143.87,120.73 144.38,120.73 144.51,120.86 144.51,121.11 144.38,121.24 143.87,121.24 143.74,121.36 143.74,128.6 145.44,130.3 v1(145.44,130.38) 145.4,130.42 R260.1
SD1_VSELECT: length 35.7
  TOP w0.127: R1042.2 133.1,68.86 v1(132.72,68.48)
  L3_INT_1 w0.127: v1(132.72,68.48) 132.01,67.77 131.43,67.77 130.89,68.3 130.89,73 130.18,73.71 130.18,78.54 125.96,82.76 125.96,94.18 J135.2
SD_PWREN_B: length 81.2
  TOP w0.127: R139.2 126.62,69.03 v1(126.88,69.29)
  L3_INT_1 w0.127: v1(116.68,90.23) 116.81,90.23 122.87,84.18 122.87,81.92 127.36,77.42 127.36,70.82 126.88,70.34 v1(126.88,69.29)
  BOTTOM w0.127: R29.1 141.72,125.18 138.16,121.62 138.16,107.01 137.65,106.5 136.12,106.5 135.49,105.87 135.49,104.85 132.57,101.93 130.03,101.93 126.35,98.25 126.35,97.08 120.15,90.88 117.33,90.88 v1(116.68,90.23)
SDIO0_SD1_SEL: length 15.2
  TOP w0.127: v1(144.41,115.86) 144.41,115.87 144.44,115.9 U63.9 ; U65.9 v1(140.25,115.78) ; U64.9 v1(148.25,115.78)
  BOTTOM w0.127: v1(140.25,115.78) 140.89,116.42 143.85,116.42 v1(144.41,115.86) 144.97,116.42 147.6,116.42 v1(148.25,115.78) 147.55,115.08 147.55,113.62 148.19,112.98 J76.2
SDRAM_3V3: length 43.6
  TOP w0.305: U16.1 71.93,59.47 v1(71.99,59.4) ; U14.1 v1(70.45,85.17) ; U16.27 49.65,58.07 v1(49.45,57.87) ; U14.27 v1(49.65,85.17) ; U14.3 v1(68.85,85.17) ; U14.9 v1(64.05,85.17) ; v1(66.4,46.28) 66.4,46.43 66.45,46.48 U16.49 ; U16.43 61.65,46.74 v1(61.19,46.28) ; v1(68.55,57.57) 68.55,57.57 68.85,57.87 U16.3 ; v1(59.89,57.86) 60.05,58.03 U16.14 ; U14.49 66.45,73.29 v1(66.52,73.36) ; U14.43 61.65,73.22 v1(61.52,73.36) ; U14.14 v1(60.05,85.17) ; U16.9 64.05,57.5 64.51,57.04 64.96,57.04 v1(65,57)
  TOP w0.381: 53.57,86.83 C107.1 ; C107.1 54.32,87.45 ; C107.1 52.83,87.45 ; 50.48,87.33 L9.2 ; L9.2 50.91,86.93 ; L9.2 51.34,87.33 ; 52.18,86.93 C119.1 ; C119.1 52.61,87.33 ; C119.1 51.75,87.33
  BOTTOM w0.305: v1(66.4,46.28) 66.4,46.31 66.27,46.44 C120.1 ; v1(49.65,85.17) 49.64,85.16 C111.1 ; C114.1 70.46,85.16 v1(70.45,85.17) ; v1(68.85,85.17) 68.81,85.13 C110.1 ; v1(61.52,73.36) 61.19,73.03 C112.1 ; R320.1 v1(58.92,79.33) ; C125.1 49.26,57.67 v1(49.45,57.87) ; C109.1 v1(62.46,85.16) ; C108.1 60.15,85.08 v1(60.05,85.17) ; v1(68.55,57.57) 68.05,57.06 C121.1 ; C115.1 64.12,85.1 v1(64.05,85.17) ; v1(71.99,59.4) 72.13,59.4 C118.1 ; C123.1 59.93,57.82 v1(59.89,57.86) ; R336.1 v1(56.75,50.75) ; C113.1 v1(66.52,73.36) ; C122.1 v1(65,57) ; v1(61.19,46.28) C124.1
  vias: v1(53.32,85.93) v1(53.96,86.57) v1(53.96,85.93) v1(54.59,86.57) v1(54.59,85.93)
SEMC_A0: length 70.7
  TOP w0.127: U14.23 52.85,80.23 52.98,80.1 53.09,80.1 53.22,79.98 53.22,79.72 53.09,79.59 52.98,79.59 52.85,79.47 52.85,78.67 v1(52.94,78.58) ; v1(52.94,66.63) 52.99,66.63 53.19,66.83 56.19,66.83 TP1065.1 56.62,67.26 66.27,67.26 67.67,65.86 R160.2 ; v1(53.54,54.43) 53.54,54.3 53,53.76 53,53 52.85,52.85 52.67,52.85 52.48,53.04 52.48,53.82 53,54.34 53,54.78 52.43,55.35 52.43,57.84 52.85,58.26 U16.23
  L3_INT_1 w0.127: v1(52.94,78.58) 53.24,78.88 53.24,81.68 53.12,81.8 52.66,81.8 52.46,81.6 52.46,80.74 52.33,80.61 51.92,80.61 51.8,80.48 51.8,80.23 51.92,80.1 52.33,80.1 52.46,79.97 52.46,79.72 52.33,79.59 51.92,79.59 51.8,79.47 51.8,79.21 51.92,79.09 52.33,79.09 52.46,78.96 52.46,78.34 53.07,77.73 53.07,76.08 53.7,75.44 53.7,71.81 53.14,71.25 53.14,66.83 v1(52.94,66.63) 53.17,66.4 53.17,65.94 52.94,65.71 52.94,65.33 53.14,65.12 53.14,64.69 52.9,64.45 52.9,64.18 53.14,63.94 53.14,63.44 53.03,63.33 52.86,63.33 52.75,63.22 52.75,63.06 52.86,62.95 53.03,62.95 53.14,62.83 53.14,62.68 53.03,62.57 52.86,62.57 52.75,62.45 52.75,62.3 52.86,62.18 53.03,62.18 53.14,62.07 53.14,61.91 53.03,61.8 52.86,61.8 52.75,61.69 52.75,61.53 52.86,61.42 53.03,61.42 53.14,61.31 53.14,61.15 53.03,61.04 52.86,61.04 52.75,60.93 52.75,60.77 52.86,60.66 53.03,60.66 53.14,60.55 53.14,60.39 53.03,60.28 52.86,60.28 52.75,60.17 52.75,60.01 52.86,59.9 53.03,59.9 53.14,59.79 53.14,59.63 53.03,59.52 52.86,59.52 52.75,59.41 52.75,59.25 52.86,59.14 53.03,59.14 53.14,59.02 53.14,58.87 53.03,58.76 52.86,58.76 52.75,58.64 52.75,58.49 52.86,58.37 53.03,58.37 53.14,58.26 53.14,58.1 53.03,57.99 52.86,57.99 52.75,57.88 52.75,57.72 52.86,57.61 53.03,57.61 53.14,57.5 53.14,57.34 53.03,57.23 52.86,57.23 52.75,57.12 52.75,56.96 52.86,56.85 53.03,56.85 53.14,56.74 53.14,56.58 53.03,56.47 52.86,56.47 52.75,56.36 52.75,56.2 52.97,55.98 52.97,55.35 53.54,54.78 v1(53.54,54.43)
SEMC_A1: length 67.1
  TOP w0.127: U14.24 52.05,82.1 52.18,81.97 52.31,81.97 52.51,81.77 52.51,81.51 52.38,81.39 51.66,81.39 51.53,81.26 51.53,81 51.66,80.88 52.38,80.88 52.51,80.75 52.51,80.5 52.38,80.37 51.66,80.37 51.53,80.24 51.53,79.99 51.66,79.86 52.38,79.86 52.51,79.73 52.51,79.45 52.41,79.35 51.72,79.35 51.59,79.23 51.59,78.92 51.7,78.82 52.2,78.82 52.35,78.67 52.35,78.49 52.19,78.32 v1(51.64,78.32) ; R161.2 67.54,66.75 66.73,67.57 55.15,67.57 54.72,67.13 52.74,67.13 v1(51.97,66.37) ; U16.24 52.05,58.17 51.92,58.04 51.4,58.04 51.28,57.92 51.28,57.69 51.43,57.53 51.92,57.53 52.05,57.41 52.05,57.15 51.92,57.03 51.2,57.03 51.07,56.9 51.07,56.65 51.2,56.52 51.92,56.52 52.05,56.39 52.05,56.14 51.92,56.01 51.73,56.01 51.61,55.88 51.61,55.63 51.73,55.5 51.92,55.5 52.05,55.38 52.05,55.12 51.9,54.97 51.11,54.97 50.99,54.84 50.99,54.66 51.14,54.51 52.51,54.51 v1(52.53,54.54)
  L3_INT_1 w0.127: v1(51.64,78.32) 51.67,78.29 52.08,78.29 52.22,78.15 52.22,77.79 52.13,77.7 51.56,77.7 51.43,77.57 51.43,77.24 51.56,77.12 52.48,77.12 52.61,76.99 52.61,76.45 52.43,76.27 52.43,73.97 51.97,73.51 v1(51.97,66.37) 51.97,55.43 51.85,55.3 51.85,53.69 51.97,53.56 52.14,53.56 52.23,53.65 52.23,54.23 v1(52.53,54.54)
SEMC_A2: length 53
  TOP w0.127: R162.2 63.23,69.7 63.02,69.92 60.73,69.92 60.28,69.47 56.27,69.47 56.01,69.73 52.99,69.73 v1(51.03,67.77) ; U14.25 51.25,82.01 51.12,81.88 50.91,81.88 50.78,81.75 50.78,81.5 50.91,81.37 51.1,81.37 51.23,81.25 51.23,80.99 51.1,80.87 50.91,80.87 50.78,80.74 50.78,80.48 50.91,80.36 51.01,80.36 51.14,80.23 51.14,79.98 50.86,79.7 50.86,79.21 v1(50.92,79.15) ; v1(51.06,55.73) 51.06,55.35 50.83,55.12 50.45,55.12 50.32,55.25 50.32,56.13 50.43,56.23 50.57,56.23 50.73,56.39 50.73,56.77 50.6,56.9 50.37,56.9 50.25,57.03 50.25,57.28 50.37,57.41 50.6,57.41 50.73,57.53 50.73,57.81 51.25,58.33 U16.25
  L3_INT_1 w0.127: v1(51.06,55.73) 51.06,55.73 51.06,58.1 51.2,58.24 51.2,58.6 51.03,58.77 51.03,60.06 51.2,60.23 51.2,60.57 51.03,60.74 51.03,61.2 51.2,61.36 51.2,61.7 51.03,61.87 51.03,62.82 51.2,62.99 51.2,63.33 51.03,63.5 v1(51.03,67.77) 51.03,73.84 51.5,74.31 51.5,75.96 51.06,76.41 51.06,78.51 51.49,78.95 51.49,79.61 51.37,79.73 51.05,79.73 50.92,79.61 v1(50.92,79.15)
SEMC_A3: length 49.2
  TOP w0.127: U14.26 50.45,81.53 50.33,81.4 50.12,81.4 49.99,81.28 49.99,81.02 50.12,80.89 50.33,80.89 50.45,80.77 50.45,80.51 50.33,80.39 50.12,80.39 49.99,80.26 49.99,80.01 50.12,79.88 50.33,79.88 50.45,79.75 v1(50.45,78.48) ; v1(50.45,54.58) 49.94,55.09 49.94,56.59 49.82,56.72 49.36,56.72 49.23,56.84 49.23,57.1 49.36,57.22 49.82,57.22 49.94,57.35 49.94,57.66 50.45,58.17 U16.26 ; v1(50.06,66.47) 51.14,66.47 52.89,68.23 60.48,68.23 60.66,68.4 R959.2
  L3_INT_1 w0.127: v1(50.45,54.58) 50.29,54.75 50.29,63.03 50.06,63.26 v1(50.06,66.47) 50.06,66.98 50.15,67.07 50.15,67.46 50.06,67.55 50.06,74.31 50.45,74.71 v1(50.45,78.48)
SEMC_A4: length 55.1
  TOP w0.127: U14.29 50.45,73.15 50.73,73.43 50.73,73.69 50.6,73.81 50.32,73.81 50.2,73.94 50.2,74.19 50.32,74.32 50.43,74.32 50.55,74.45 50.55,75.06 49.92,75.69 48.75,75.69 48.42,75.36 48.42,74.2 48.55,74.07 48.78,74.07 48.89,74.18 48.89,75.15 49,75.26 49.16,75.26 49.27,75.15 49.27,74.18 49.38,74.07 49.64,74.07 49.84,74.27 49.84,74.93 v1(49.82,74.96) ; U16.29 50.45,49.84 49.98,50.31 v1(49.98,52.76) ; v1(49.68,67.26) 51.24,67.26 52.53,68.56 60.28,68.56 60.62,68.9 63.9,68.9 64.09,68.71 R163.2
  L3_INT_1 w0.127: v1(49.98,52.76) 49.98,58.18 49.59,58.58 49.59,67.17 v1(49.68,67.26) 49.68,74.82 v1(49.82,74.96)
SEMC_A5: length 59.4
  TOP w0.127: U14.30 51.25,74.97 51.54,75.26 51.54,75.85 50.81,76.58 48.95,76.58 48.77,76.76 48.77,77.35 48.65,77.47 48.47,77.47 48.33,77.34 48.33,76.57 48.77,76.13 50.78,76.13 51.03,75.87 v1(51.03,75.57) ; R1229.2 60.94,63.58 60.56,63.2 54.46,63.2 53.32,64.34 v1(50.53,64.34) ; U16.30 51.25,49.18 51.12,49.3 50.93,49.3 50.81,49.43 50.81,49.69 50.93,49.81 51.12,49.81 51.25,49.94 51.25,50.19 51.05,50.39 50.46,50.39 50.33,50.52 50.33,50.7 50.46,50.83 51.12,50.83 51.25,50.96 51.25,51.21 51.07,51.39 50.43,51.39 50.3,51.51 50.3,51.77 50.43,51.9 51.12,51.9 51.25,52.02 51.25,52.23 51.12,52.35 50.68,52.35 50.55,52.48 50.55,53.22 50.37,53.39 50.08,53.39 49.99,53.48 49.99,53.75 50.12,53.88 50.53,53.88 51.05,53.36 v1(51.05,52.89)
  L3_INT_1 w0.127: v1(51.05,52.89) 51.03,52.9 51.03,54.69 50.59,55.13 50.59,64.28 v1(50.53,64.34) 50.53,73.87 51.03,74.37 v1(51.03,75.57)
SEMC_A6: length 65.3
  TOP w0.127: v1(51.5,64.85) 52.07,64.85 52.2,64.98 52.2,65.15 52.33,65.28 52.58,65.28 52.71,65.15 52.71,64.98 52.83,64.85 55.68,64.85 56.19,65.36 57.13,65.36 58.07,66.3 60.71,66.3 61.09,65.92 63.17,65.92 63.26,65.83 63.5,65.59 63.89,65.59 64.07,65.76 R1230.2 ; v1(52.05,52.84) 52.05,54 51.9,54.16 51.67,54.16 51.54,54.03 51.54,52.4 51.67,52.28 52.36,52.28 52.48,52.15 52.48,51.89 52.38,51.79 51.72,51.79 51.59,51.66 51.59,51.41 51.72,51.28 52.36,51.28 52.51,51.13 52.51,50.9 52.38,50.78 51.75,50.78 51.62,50.65 51.62,50.39 51.75,50.27 52.41,50.27 52.53,50.14 52.53,49.89 52.41,49.76 51.75,49.76 51.62,49.63 51.62,49.38 51.75,49.25 51.92,49.25 52.05,49.12 U16.31 ; U14.31 52.05,73.1 51.63,73.52 51.63,74.92 51.95,75.24 51.95,75.92 51.49,76.38 51.49,76.91 51.37,77.04 49.26,77.04 49.13,77.17 49.13,77.88 49.26,78.01 49.47,78.01 49.6,77.88 49.6,77.6 49.72,77.47 49.98,77.47 50.1,77.6 50.1,77.88 50.23,78.01 51.29,78.01 52.03,77.27 52.03,76.58 v1(52.05,76.56)
  L3_INT_1 w0.127: v1(52.05,76.56) 52.05,74.22 51.5,73.68 v1(51.5,64.85) 51.5,56.64 51.62,56.53 51.62,55.58 51.53,55.49 51.53,52.92 51.62,52.84 v1(52.05,52.84)
SEMC_A7: length 64.6
  TOP w0.127: v1(52.44,63.83) 53.19,63.83 54.13,62.89 60.81,62.89 61,63.08 62.86,63.08 63.38,62.56 R164.2 ; U14.32 52.85,73.2 52.73,73.33 52.29,73.33 52.16,73.46 52.16,73.71 52.29,73.84 52.73,73.84 52.85,73.97 52.85,74.22 52.73,74.35 52.08,74.35 51.95,74.48 51.95,74.76 52.1,74.91 52.79,74.91 52.91,75.04 v1(52.91,75.31) ; U16.32 52.85,49.17 52.98,49.29 53.39,49.29 53.6,49.51 53.6,49.67 53.47,49.8 52.98,49.8 52.85,49.93 52.85,50.18 52.98,50.31 53.57,50.31 53.7,50.44 53.7,50.69 53.57,50.82 52.98,50.82 52.85,50.94 52.85,51.2 52.98,51.32 53.6,51.32 53.7,51.43 53.7,51.71 53.58,51.83 v1(53.04,51.83)
  L3_INT_1 w0.127: v1(53.04,51.83) 53.04,50.55 52.91,50.42 52.61,50.42 52.52,50.51 52.52,51.52 52.39,51.65 51.85,51.65 51.72,51.78 51.72,52.03 51.85,52.16 52.39,52.16 52.52,52.29 52.52,52.84 52.65,52.97 53.06,52.97 53.18,53.1 53.18,53.35 53.06,53.48 52.65,53.48 52.53,53.59 52.53,53.87 52.84,54.18 52.94,54.18 53.07,54.31 53.07,54.79 52.44,55.41 v1(52.44,63.83) 52.44,64.47 52.73,64.76 52.73,64.96 52.29,65.39 52.29,65.6 52.62,65.93 52.62,66.11 52.44,66.29 52.44,66.86 52.84,67.25 52.84,67.5 52.69,67.66 52.41,67.66 52.28,67.78 52.28,68.04 52.41,68.16 52.71,68.16 52.84,68.29 52.84,68.52 52.69,68.67 52.41,68.67 52.28,68.8 52.28,69.05 52.41,69.18 52.71,69.18 52.84,69.31 52.84,69.54 52.69,69.69 52.41,69.69 52.28,69.81 52.28,70.07 52.41,70.2 52.69,70.2 52.81,70.32 52.81,70.58 52.69,70.7 52.41,70.7 52.28,70.83 52.28,71.14 52.41,71.27 52.71,71.27 52.84,71.39 52.84,71.65 52.71,71.77 52.41,71.77 52.28,71.9 52.28,72.15 52.41,72.28 53.19,72.28 53.35,72.43 53.35,72.66 53.22,72.79 52.41,72.79 52.28,72.92 52.28,73.27 52.45,73.44 53.2,73.44 53.4,73.64 53.4,73.89 53.27,74.02 52.86,74.02 52.74,74.15 52.74,74.4 52.86,74.53 53.27,74.53 53.4,74.65 53.4,75.19 53.27,75.31 v1(52.91,75.31)
SEMC_A8: length 66.1
  TOP w0.127: v1(54.08,76.79) 54.08,77.09 53.96,77.22 52.66,77.22 52.53,77.09 52.53,76.86 52.64,76.76 53.47,76.76 53.57,76.66 53.57,76.41 53.48,76.32 52.66,76.32 52.53,76.19 52.53,75.97 52.71,75.8 54.01,75.8 54.21,75.59 54.21,75.24 54.03,75.06 53.4,75.06 53.27,74.93 53.27,74.68 53.4,74.55 53.86,74.55 53.98,74.43 53.98,74.22 53.8,74.04 53.24,74.04 53.16,73.96 53.16,73.52 53.24,73.43 53.52,73.43 53.63,73.33 53.63,71.91 U14.33 ; U16.33 53.65,49.13 54.06,49.53 54.06,51.82 v1(53.35,52.53) ; R165.2 64.33,66.93 57.69,66.93 56.95,66.2 55.89,66.2 55.76,66.32 55.38,66.32 54.98,65.92 54.69,65.92 54.57,66.05 54.57,66.33 54.44,66.46 53.64,66.46 53.45,66.27 v1(53.45,65.48)
  L3_INT_1 w0.127: v1(53.35,52.53) 53.55,52.33 53.55,50.08 53.66,49.96 54.06,49.96 54.18,50.09 54.18,50.35 54.31,50.47 54.67,50.47 54.79,50.6 54.79,50.85 54.67,50.98 54.01,50.98 53.88,51.11 53.88,51.36 54.01,51.49 54.46,51.49 54.59,51.62 54.59,51.82 54.41,52 54.13,52 54.01,52.12 54.01,52.56 53.78,52.78 53.78,53.24 54.29,53.75 54.29,54.46 53.84,54.9 53.84,54.9 53.45,55.3 v1(53.45,65.48) 53.5,65.53 53.5,71.02 54.08,71.61 54.08,75.67 53.45,76.3 53.45,77.37 53.57,77.5 53.96,77.5 54.08,77.37 v1(54.08,76.79)
SEMC_A9: length 73.1
  TOP w0.127: U16.34 54.45,49.04 54.69,49.28 54.69,49.53 54.45,49.77 54.45,52.43 54.33,52.56 54.01,52.56 53.36,53.2 53.36,53.61 53.52,53.77 53.7,53.77 53.83,53.65 53.83,53.46 54.22,53.06 v1(54.29,53.06) ; v1(54.46,67.64) 54.72,67.9 66.91,67.9 67.16,67.64 R166.2 ; v1(55.1,76.79) 55.1,77.37 54.87,77.6 52.38,77.6 52.25,77.72 52.25,77.9 52.38,78.03 56.57,78.03 56.66,77.94 56.66,77.79 56.5,77.63 55.71,77.63 55.58,77.5 55.58,76.48 55.3,76.2 54.54,76.2 54.39,76.05 54.39,75.85 54.54,75.7 55.25,75.7 55.43,75.52 55.43,75.29 55.3,75.16 54.57,75.16 54.44,75.04 54.44,74.81 54.57,74.68 55.2,74.68 55.33,74.55 55.33,74.32 55.18,74.17 54.36,74.17 54.24,74.04 54.24,73.79 54.36,73.66 54.73,73.66 54.86,73.54 54.86,73.36 54.73,73.23 54.58,73.23 54.45,73.1 U14.34
  L3_INT_1 w0.127: v1(54.29,53.06) 54.36,52.99 54.36,52.5 55.28,51.59 55.28,50.42 55.36,50.33 55.58,50.33 55.71,50.46 55.71,51.87 54.74,52.83 54.74,53.95 55.06,54.27 55.06,56.73 54.63,57.17 54.63,63.27 54.25,63.66 54.25,65.01 54.46,65.23 v1(54.46,67.64) 54.46,70.69 55.1,71.33 v1(55.1,76.79)
SEMC_A10: length 64.8
  TOP w0.127: R170.2 61.25,66.63 57.89,66.63 57.03,65.76 55.66,65.76 55.18,65.28 54.55,65.28 53.98,65.85 v1(53.98,65.96) ; v1(53.65,78.51) 53.93,78.79 53.93,79.25 53.8,79.38 53.65,79.38 53.52,79.5 53.52,79.85 53.61,79.94 53.93,79.94 54.08,80.09 54.08,80.34 53.96,80.47 53.45,80.47 53.32,80.6 53.32,80.85 53.45,80.98 53.96,80.98 54.08,81.1 54.08,81.36 53.96,81.49 53.32,81.49 53.17,81.64 53.17,81.84 53.32,81.99 53.52,81.99 53.65,82.12 U14.22 ; U16.22 53.65,57.86 53.52,57.74 52.89,57.74 52.76,57.61 52.76,57.36 52.89,57.23 53.32,57.23 53.45,57.1 53.45,56.85 53.32,56.72 52.89,56.72 52.76,56.59 52.76,56.34 52.89,56.21 53.32,56.21 53.45,56.09 53.45,55.83 53.32,55.7 53.07,55.7 52.94,55.58 52.94,55.32 53.09,55.17 54.24,55.17 v1(54.59,54.82)
  L3_INT_1 w0.127: v1(53.65,78.51) 53.63,78.54 53.63,81.02 53.75,81.15 54.03,81.15 54.18,81 54.18,79.73 54.31,79.61 54.97,79.61 55.1,79.48 55.1,79.23 54.97,79.1 54.31,79.1 54.18,78.97 54.18,77.98 54.55,77.61 54.55,71.41 53.98,70.84 v1(53.98,65.96) 53.98,65.25 53.75,65.03 53.75,63.08 53.88,62.95 54.2,62.95 54.32,62.82 54.32,62.57 54.2,62.44 53.88,62.44 53.75,62.31 53.75,62.06 53.88,61.93 54.2,61.93 54.32,61.81 54.32,61.55 54.2,61.42 53.88,61.42 53.75,61.3 53.75,61.04 53.88,60.92 54.2,60.92 54.32,60.79 54.32,60.54 54.2,60.41 53.88,60.41 53.75,60.28 53.75,60.03 53.88,59.9 54.2,59.9 54.32,59.77 54.32,59.52 54.2,59.39 53.88,59.39 53.75,59.27 53.75,59.01 53.88,58.88 54.2,58.88 54.32,58.76 54.32,58.5 54.2,58.38 53.88,58.38 53.75,58.25 53.75,58 53.88,57.87 54.2,57.87 54.32,57.74 54.32,57.49 54.2,57.36 53.88,57.36 53.75,57.23 53.75,55.58 53.89,55.44 54.07,55.44 54.16,55.53 54.16,56.59 54.25,56.68 54.5,56.68 54.59,56.59 v1(54.59,54.82)
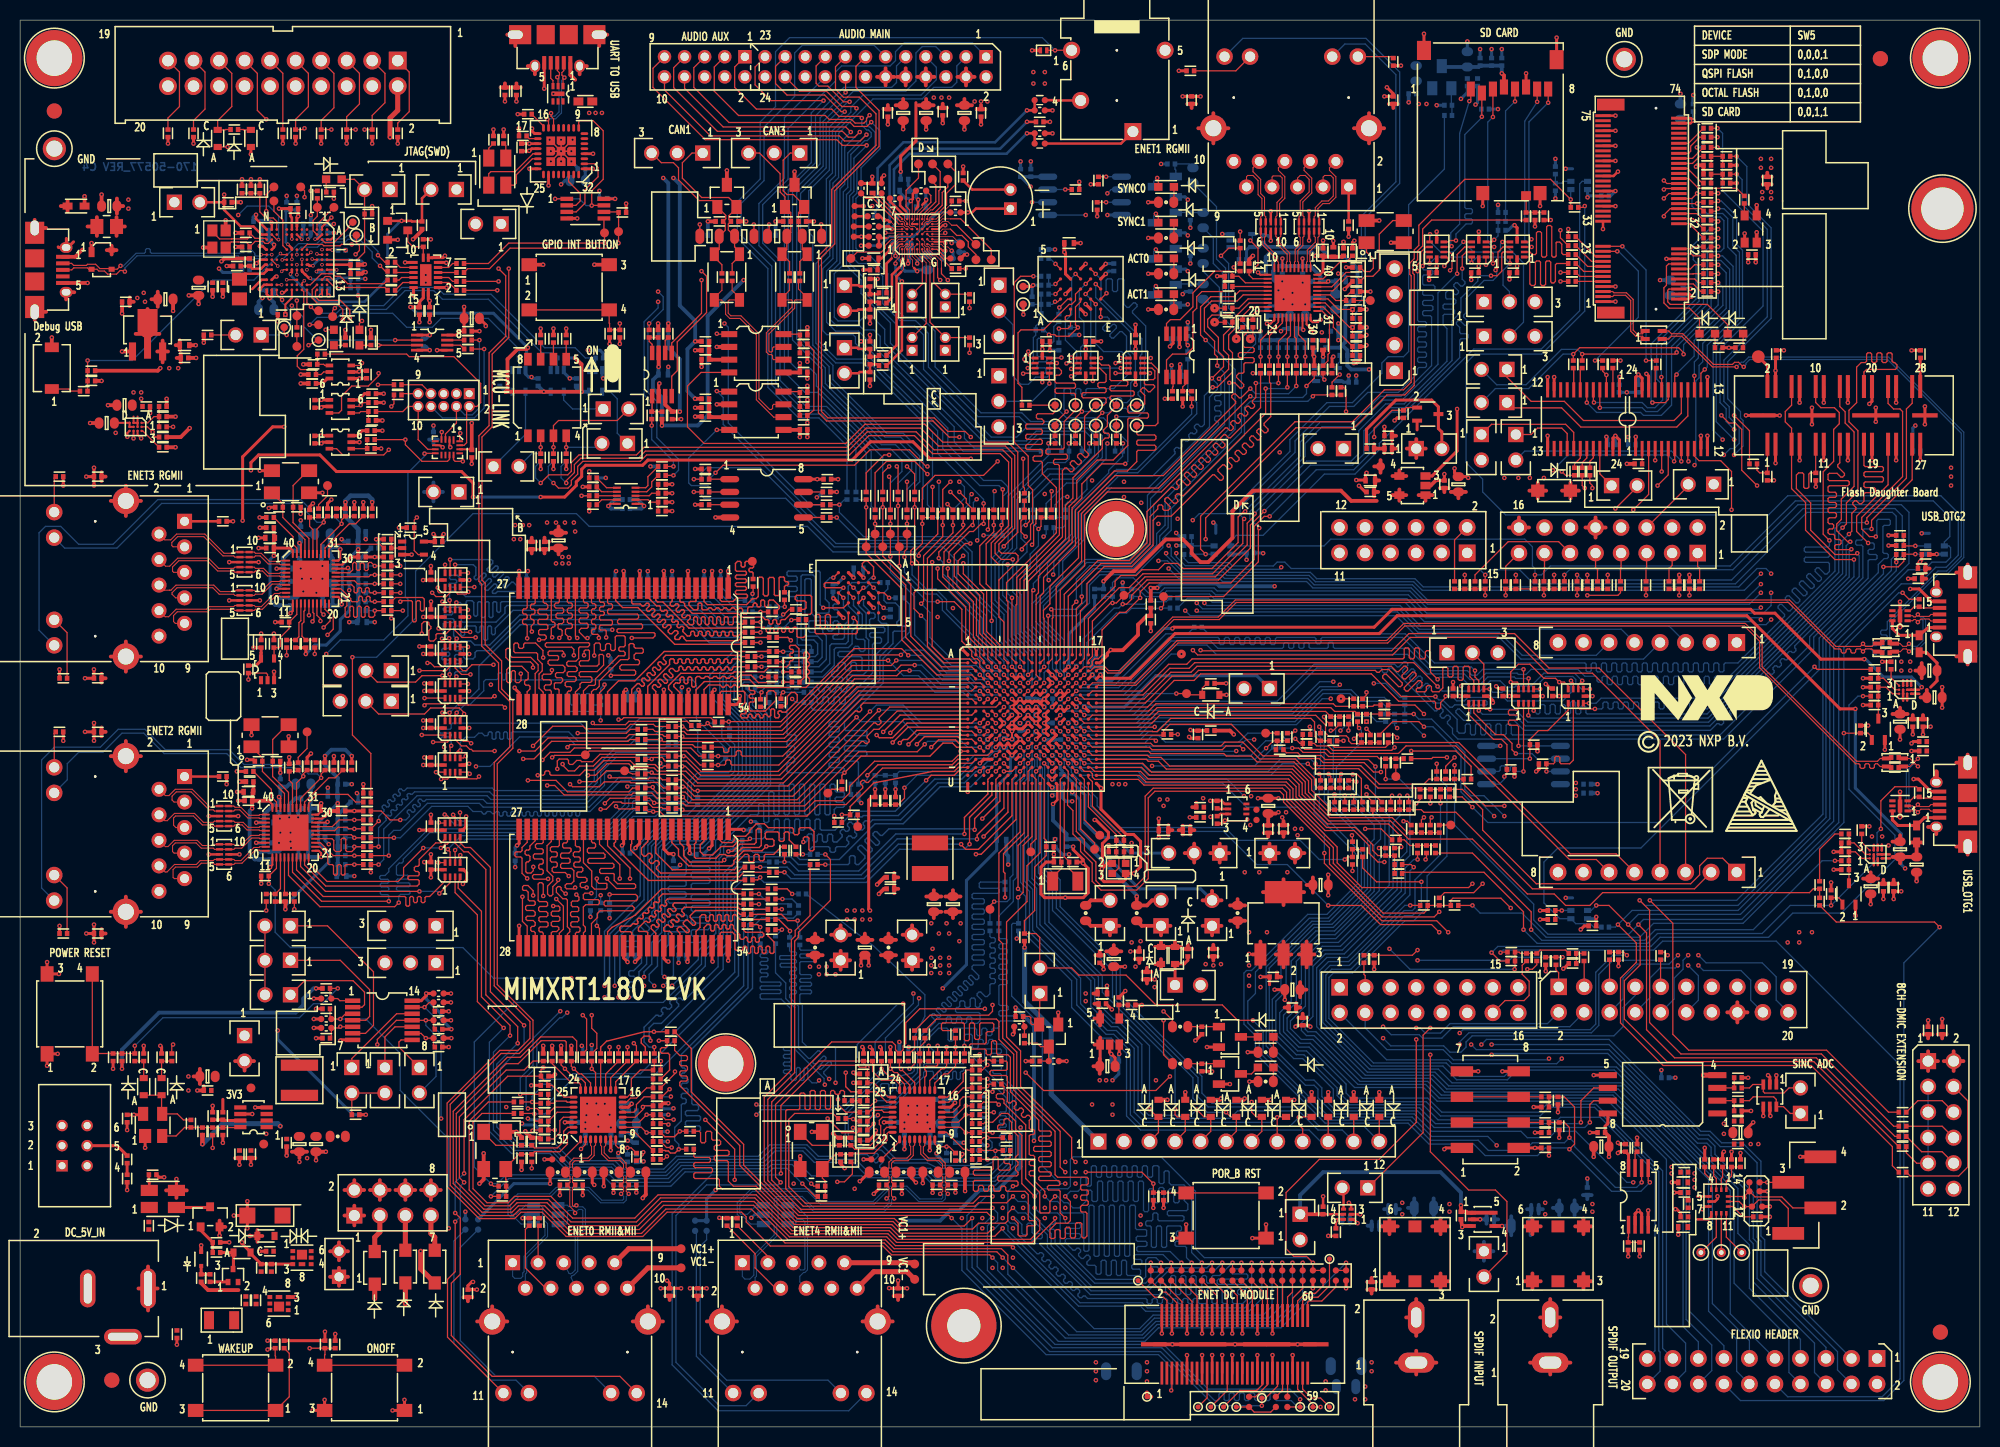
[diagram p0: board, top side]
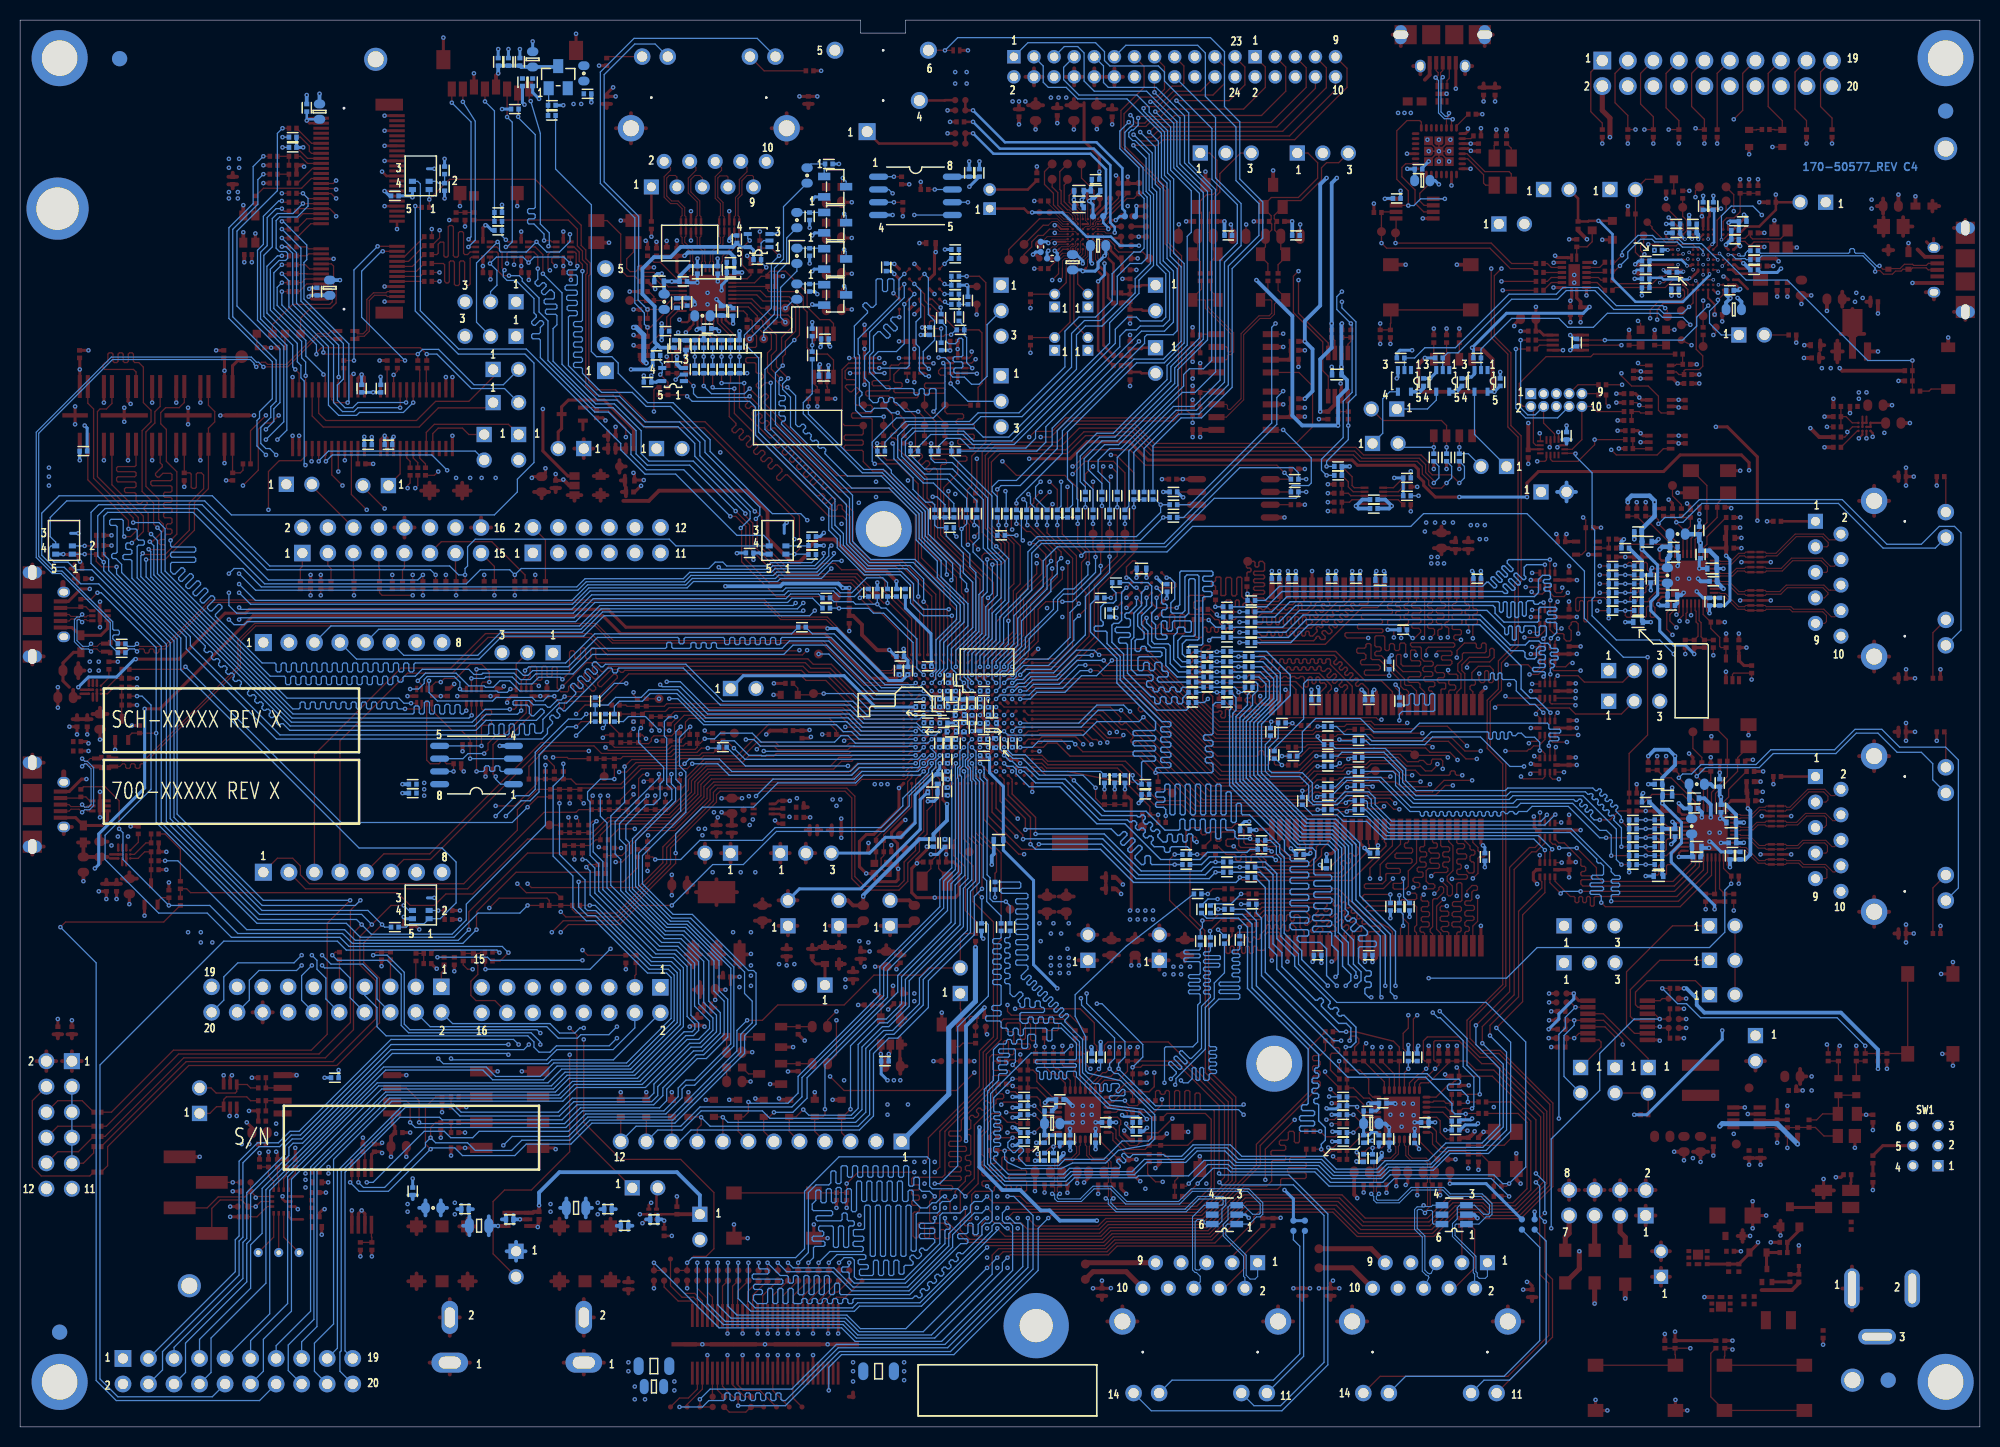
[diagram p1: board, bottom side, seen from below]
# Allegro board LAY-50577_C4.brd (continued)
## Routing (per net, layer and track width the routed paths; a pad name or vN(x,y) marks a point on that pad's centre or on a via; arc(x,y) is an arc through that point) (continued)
SEMC_A11: length 59.1
  TOP w0.127: v1(55.35,52.97) 55.61,52.71 55.61,52.45 55.48,52.33 54.97,52.33 54.84,52.2 54.84,51.89 54.97,51.77 55.45,51.77 55.58,51.64 55.58,51.39 55.48,51.28 54.9,51.28 54.77,51.16 54.77,50.9 54.9,50.78 55.46,50.78 55.58,50.65 55.58,50.39 55.46,50.27 54.92,50.27 54.79,50.14 54.79,49.89 54.92,49.76 55.58,49.76 55.71,49.63 55.71,49.36 55.58,49.23 55.38,49.23 55.25,49.1 U16.35 ; v1(55.48,69.04) 60.33,69.04 60.71,69.42 R167.2 ; v1(56.11,76.79) 56.11,77.19 56.23,77.31 56.56,77.31 56.65,77.22 56.65,76.37 56.52,76.24 55.77,76.24 55.65,76.11 55.65,75.85 55.77,75.72 57.41,75.72 57.6,75.91 57.6,76.8 57.68,76.87 57.93,76.87 58.06,76.75 58.06,75.81 57.41,75.16 55.76,75.16 55.63,75.03 55.63,74.78 55.76,74.65 56.76,74.65 56.89,74.53 56.89,74.22 56.76,74.09 55.89,74.09 55.71,73.92 55.71,73.59 55.25,73.13 U14.35
  L3_INT_1 w0.127: v1(56.11,76.79) 55.87,76.55 55.87,76.15 56,76.02 56.15,76.02 56.28,75.9 56.28,75.64 56.15,75.51 56,75.51 55.87,75.39 55.87,75.13 56,75.01 56.15,75.01 56.28,74.88 56.28,74.63 56.15,74.5 56,74.5 55.87,74.37 55.87,74.12 56,73.99 56.15,73.99 56.28,73.86 56.28,73.61 56.15,73.48 56,73.48 55.87,73.36 55.87,73.1 56,72.97 56.15,72.97 56.28,72.85 56.28,72.59 56.15,72.47 56,72.47 55.87,72.34 55.87,72.09 56,71.96 56.15,71.96 56.28,71.83 56.28,71.58 56.15,71.45 56,71.45 55.87,71.32 55.87,70.88 55.48,70.49 v1(55.48,69.04) 55.48,65.1 55.33,64.95 55.33,64.55 55.19,64.41 55.19,64.02 55.32,63.89 55.32,57.7 55.7,57.32 55.7,53.76 55.81,53.65 55.81,52.96 55.68,52.84 55.5,52.84 55.37,52.97 v1(55.35,52.97)
SEMC_A12: length 101.9
  TOP w0.127: v1(56.5,64.85) 57.26,64.85 58.4,65.99 60.56,65.99 60.97,65.59 63.07,65.59 63.13,65.52 63.4,65.26 66.25,65.26 67.42,64.09 75.95,64.09 83.11,71.25 83.29,71.25 83.38,71.16 83.56,71.16 83.74,71.34 83.74,71.52 83.65,71.61 83.65,71.79 83.9,72.04 U6.G1 ; v1(57.13,76.76) 57.13,77.85 57.28,78.01 57.61,78.01 57.74,77.88 57.74,77.38 57.87,77.26 58.12,77.26 58.25,77.38 58.25,77.8 58.4,77.96 58.63,77.96 58.76,77.83 58.76,77.38 58.88,77.26 59.09,77.26 59.21,77.38 59.21,78.61 59.34,78.73 60.08,78.73 60.2,78.61 60.2,77.75 60.08,77.63 59.7,77.63 59.57,77.5 59.57,77.32 59.7,77.19 60.05,77.19 60.2,77.04 60.2,76.84 60.1,76.74 59.54,76.74 57.26,74.45 57.26,74.4 57.25,74.39 57.25,73.9 57.13,73.79 56.6,73.79 56.05,73.24 U14.36 ; U16.36 56.05,49.17 56.24,49.35 56.24,49.74 56.04,49.94 56.04,51.74 56.27,51.97 57.51,51.97 57.64,52.09 57.64,52.35 57.51,52.47 56.17,52.47 56.04,52.6 56.04,52.96 56.19,53.11 v1(56.84,53.11)
  L3_INT_1 w0.127: v1(57.13,76.76) 57.13,71.02 56.5,70.39 v1(56.5,64.85) 56.5,55.58 56.84,55.24 56.84,53.97 57.31,53.5 57.31,50.47 57.12,50.28 56.56,50.28 56.11,50.72 56.11,51.82 56.24,51.95 56.83,51.95 56.95,52.08 56.95,52.33 56.83,52.46 56.24,52.46 56.11,52.58 56.11,52.99 56.24,53.11 v1(56.84,53.11)
SEMC_BA0: length 56.3
  TOP w0.127: v1(55.43,78.51) 55.25,78.69 U14.20 ; R168.2 60.94,64.98 60.17,65.29 TP1067.1 58.34,65.29 57.26,64.21 v1(55.66,64.21) ; v1(56.37,53.67) 55.86,53.67 55.73,53.8 55.73,54.05 55.86,54.18 56.24,54.18 56.41,54.35 56.41,54.52 56.24,54.69 55.53,54.69 55.4,54.82 55.4,55.12 55.5,55.22 55.86,55.22 55.99,55.35 55.99,55.58 55.86,55.7 55.23,55.7 55.1,55.83 55.1,56.09 55.23,56.21 55.61,56.21 55.73,56.34 55.73,56.59 55.61,56.72 55.17,56.72 55.05,56.85 55.05,57.1 55.17,57.23 55.61,57.23 55.73,57.36 55.73,57.61 55.61,57.74 55.38,57.74 55.25,57.86 U16.20
  L3_INT_1 w0.127: v1(55.43,78.51) 55.43,80.7 55.56,80.83 55.85,80.83 55.97,80.7 55.97,77.97 56.58,77.36 56.58,70.98 56.05,70.45 56.05,65.17 55.66,64.77 v1(55.66,64.21) 55.73,64.21 56.12,63.83 56.12,63.65 55.91,63.43 55.78,63.43 55.66,63.31 55.66,63.05 55.78,62.93 55.91,62.93 56.04,62.8 56.04,62.54 55.91,62.42 55.78,62.42 55.66,62.29 55.66,62.04 55.78,61.91 55.91,61.91 56.04,61.78 56.04,61.53 55.91,61.4 55.78,61.4 55.66,61.27 55.66,61.02 55.78,60.89 55.91,60.89 56.04,60.77 56.04,60.51 55.91,60.39 55.78,60.39 55.66,60.26 55.66,60 55.78,59.88 55.91,59.88 56.04,59.75 56.04,59.5 55.91,59.37 55.78,59.37 55.66,59.24 55.66,58.99 55.78,58.86 55.91,58.86 56.04,58.73 56.04,58.48 55.91,58.35 55.78,58.35 55.62,58.19 55.62,58.01 55.78,57.85 55.91,57.85 56.04,57.72 56.04,55.53 56.37,55.2 56.37,54.94 56.24,54.82 56.13,54.82 56,54.69 56,54.43 56.13,54.31 56.24,54.31 56.37,54.18 v1(56.37,53.67)
SEMC_BA1: length 55.7
  TOP w0.127: v1(54.72,63.96) 54.97,63.71 57.64,63.71 58.12,64.19 60.68,64.19 60.77,64.1 62.69,64.1 62.73,64.14 63.43,64.14 63.99,63.58 R169.2 ; v1(55.23,53.67) 55.1,53.55 54.39,53.55 54.24,53.7 54.24,53.9 54.39,54.05 54.84,54.05 55.1,54.31 55.1,55.35 54.87,55.58 53.9,55.58 53.78,55.7 53.78,55.96 53.9,56.09 54.59,56.09 54.72,56.21 54.72,56.47 54.59,56.59 53.9,56.59 53.78,56.72 53.78,56.97 53.9,57.1 54.62,57.1 54.82,57.31 54.82,57.51 54.72,57.61 54.11,57.61 53.98,57.74 53.98,57.99 54.11,58.12 54.34,58.12 54.46,58.24 54.46,59.45 U16.21 ; U14.21 54.45,82.12 54.58,82 54.82,82 54.95,81.87 54.95,81.62 54.82,81.49 54.58,81.49 54.45,81.36 54.45,81.11 54.58,80.98 54.82,80.98 54.95,80.85 54.95,80.6 54.82,80.47 54.58,80.47 54.45,80.35 54.45,80.09 54.58,79.96 54.82,79.96 54.95,79.84 54.95,79.58 54.82,79.46 54.39,79.46 54.26,79.33 54.26,78.91 v1(54.67,78.5)
  L3_INT_1 w0.127: v1(55.23,53.67) 55.37,53.81 55.37,56.99 54.95,57.41 54.95,63.73 v1(54.72,63.96) 54.72,64.98 54.97,65.23 54.97,70.61 55.57,71.21 55.57,77.23 54.67,78.13 v1(54.67,78.5)
SEMC_CAS: length 67.3
  TOP w0.127: v1(59.29,61.76) 59.55,61.5 60.96,61.5 61,61.55 R171.2 ; v1(59.67,54.56) 59.67,55.96 57.65,57.98 U16.17 ; U14.17 57.65,82.18 57.76,82.07 58.02,82.07 58.15,81.94 58.15,81.74 58.02,81.61 57.78,81.61 57.65,81.49 57.65,81.27 57.76,81.16 58.02,81.16 58.13,81.04 58.13,80.89 58.02,80.77 57.78,80.77 57.65,80.65 57.65,80.41 57.76,80.29 58.82,80.29 58.93,80.18 58.93,79.91 58.81,79.78 57.76,79.78 57.65,79.67 57.65,79.42 57.77,79.3 58.22,79.3 58.31,79.21 v1(58.31,78.56)
  L3_INT_1 w0.127: v1(59.67,54.56) 59.37,54.26 59.37,52.05 59.85,51.56 60.13,51.56 60.26,51.69 60.26,52.3 60.38,52.43 61.81,52.43 61.96,52.58 61.96,52.81 61.83,52.93 60.38,52.93 60.26,53.06 60.26,53.33 60.38,53.46 62.29,53.46 62.41,53.58 62.41,53.84 62.29,53.97 60.33,53.97 60.2,54.09 60.2,56.05 60.08,56.18 59.54,56.18 59.42,56.3 59.42,56.56 59.54,56.68 60.08,56.68 60.2,56.81 60.2,57.07 60.08,57.19 59.54,57.19 59.42,57.32 59.42,58.38 59.54,58.51 60.05,58.51 60.18,58.63 60.18,58.89 60.05,59.01 59.54,59.01 59.42,59.14 59.42,59.49 59.54,59.62 60.08,59.62 60.2,59.75 60.2,60 60.08,60.13 59.54,60.13 59.42,60.25 59.42,60.51 59.54,60.64 60.08,60.64 60.2,60.76 60.2,61.02 60.08,61.14 59.54,61.14 59.42,61.27 59.42,61.64 v1(59.29,61.76) 59.07,61.98 59.07,72.25 59.42,72.6 59.42,76.75 59.41,76.75 59.41,79.63 59.54,79.76 59.95,79.76 60.08,79.89 60.08,80.14 59.95,80.27 59.54,80.27 59.41,80.39 59.41,80.65 59.29,80.77 58.48,80.77 58.31,80.61 v1(58.31,78.56)
SEMC_CKE: length 66.4
  TOP w0.127: R174.2 63.91,64.39 63.73,64.57 62.62,64.57 62.53,64.48 60.93,64.48 60.81,64.59 58.78,64.59 v1(58.65,64.72) ; U14.37 56.85,73.15 57.08,73.38 57.31,73.38 57.63,73.7 57.63,74.23 59.75,76.36 60.46,76.36 60.59,76.48 60.59,77.83 60.71,77.96 60.97,77.96 61.09,77.83 61.09,77.63 61.22,77.5 61.88,77.5 62.01,77.37 62.01,77.12 61.88,76.99 61.27,76.99 61.09,76.81 61.09,76.48 61.22,76.36 61.47,76.36 61.63,76.2 61.63,75.97 61.5,75.85 59.85,75.85 59.67,75.67 59.67,75.47 59.82,75.31 61.12,75.31 61.25,75.18 61.25,74.93 61.12,74.81 58.83,74.81 v1(58.78,74.75) ; U16.37 56.85,50.09 57.45,50.69 57.45,51.11 57.7,51.36 60.98,51.36 61.11,51.49 61.11,51.67 60.93,51.84 58.22,51.84 58.1,51.97 58.1,52.22 58.22,52.35 61.3,52.35 61.42,52.48 61.42,52.81 61.25,52.99 v1(58.65,52.99)
  L3_INT_1 w0.127: v1(58.78,74.75) 59.04,74.5 59.04,72.98 58.65,72.6 v1(58.65,64.72) 58.65,61.65 58.91,61.39 58.91,54.09 58.65,53.84 v1(58.65,52.99)
  BOTTOM w0.127: R338.1 v1(58.65,52.99) ; R331.1 v1(58.78,74.75)
SEMC_CLK: length 53.3
  TOP w0.127: R173.2 63.94,61.55 63.84,61.65 62.95,61.65 62.53,62.07 59.91,62.07 59.8,62.18 59.04,62.18 58.32,61.47 v1(57.77,61.47)
  L3_INT_1 w0.127: v1(57.77,52.91) 57.77,52.2 57.88,52.08 58.49,52.08 58.6,51.97 58.6,51.64 58.48,51.51 57.89,51.51 57.77,51.39 57.77,50.37 58.07,50.07 59.1,50.07 59.21,50.18 59.21,50.63 59.33,50.74 59.57,50.74 59.72,50.59 59.72,50.14 59.85,50.02 60.05,50.02 60.2,50.17 60.2,50.98 60.08,51.11 59.09,51.11 58.96,51.23 58.96,52.2 58.71,52.45 58.35,52.45 58.22,52.58 58.22,53.32 57.8,53.74 57.8,55.09 58.02,55.3 58.02,55.47 57.8,55.69 57.8,55.85 58.02,56.07 58.02,56.23 57.8,56.45 57.8,56.61 58.02,56.83 58.02,56.99 57.8,57.21 57.8,57.37 58.02,57.59 58.02,57.76 57.8,57.97 57.8,58.14 58.02,58.35 58.02,58.52 57.8,58.73 57.8,58.9 58.02,59.11 58.02,59.28 57.8,59.5 57.8,59.66 58.02,59.88 58.02,60.04 57.8,60.26 57.8,60.42 58.02,60.64 58.02,60.8 57.8,61.02 57.8,61.43 v1(57.77,61.47) v1(57.77,70.31)
  BOTTOM w0.127: v1(57.77,70.31) 57.77,70.92 57.49,71.2 54.37,71.2 54.25,71.33 54.25,72.85 54.37,72.98 54.58,72.98 54.76,72.8 54.76,71.97 54.88,71.84 55.14,71.84 55.26,71.97 55.26,72.85 55.39,72.98 55.59,72.98 55.77,72.8 55.77,71.97 55.9,71.84 56.15,71.84 56.28,71.97 56.28,72.85 56.41,72.98 56.61,72.98 56.79,72.8 56.79,71.97 56.91,71.84 R327.1 ; R337.1 v1(57.77,52.91)
SEMC_CS0: length 68.7
  TOP w0.127: v1(56.98,70.06) 57.16,69.88 60.23,69.88 60.57,70.22 66.37,70.22 R176.2 ; v1(57.38,54.56) 57.38,54.28 57.58,54.09 58.33,54.09 58.39,54.03 58.39,53.65 58.26,53.52 57.16,53.52 56.88,53.8 56.88,55.32 56.05,56.15 U16.19 ; U14.19 56.05,82.14 56.18,82.01 56.39,82.01 56.52,81.88 56.52,81.63 56.39,81.5 55.75,81.5 55.62,81.38 55.62,81.12 55.75,81 56.39,81 56.52,80.87 56.52,80.61 56.39,80.49 55.75,80.49 55.62,80.36 55.62,80.11 55.75,79.98 56.39,79.98 56.52,79.85 56.52,79.6 56.39,79.47 55.83,79.47 55.64,79.29 55.64,79.09 56.23,78.5 v1(56.45,78.5)
  L3_INT_1 w0.127: v1(56.45,78.5) 56.5,78.55 56.5,80.57 56.62,80.7 57.61,80.7 57.74,80.57 57.74,80.32 57.61,80.19 57,80.19 56.88,80.06 56.88,79.81 57,79.68 57.61,79.68 57.74,79.56 57.74,79.25 57.61,79.12 57.23,79.12 57.12,79.01 57.12,77.94 57.26,77.8 57.41,77.8 57.54,77.68 57.54,77.22 57.73,77.02 57.94,77.02 58.06,76.91 58.06,76.61 57.97,76.52 57.73,76.52 57.6,76.39 57.6,76.14 57.73,76.01 57.82,76.01 57.94,75.88 57.94,75.63 57.82,75.5 57.73,75.5 57.6,75.37 57.6,75.12 57.73,74.99 57.82,74.99 57.94,74.87 57.94,74.61 57.82,74.48 57.73,74.48 57.6,74.36 57.6,71.01 56.98,70.39 v1(56.98,70.06) 57.13,69.9 57.13,60.73 57.38,60.48 57.38,60.11 57.26,59.99 57.08,59.99 56.95,59.86 56.95,59.6 57.08,59.48 57.26,59.48 57.38,59.35 57.38,59.1 57.26,58.97 57.08,58.97 56.95,58.84 56.95,58.59 57.08,58.46 57.26,58.46 57.38,58.33 57.38,58.08 57.26,57.95 57.08,57.95 56.95,57.83 56.95,57.57 57.08,57.45 57.26,57.45 57.38,57.32 57.38,57.06 57.26,56.94 57.08,56.94 56.95,56.81 56.95,56.56 57.08,56.43 57.26,56.43 57.38,56.3 v1(57.38,54.56)
  BOTTOM w0.127: v1(57.38,54.56) 57.35,54.52 57.35,52.74 R336.2 ; R320.2 57.01,79 56.51,78.5 v1(56.45,78.5)
SEMC_CSX0: length 1.2
  TOP w0.14: R188.2 83.34,59.75 TP15.1
SEMC_D0: length 19.3
  TOP w0.14: R151.2 72.93,84.98 72.82,85.09 72.63,85.09 72.52,85.2 72.52,85.36 72.63,85.47 72.87,85.47 72.98,85.58 72.98,86.01 TP1066.1 72.24,86.13 72.13,86.02 72.13,85.69 72.02,85.58 71.86,85.58 71.75,85.69 71.75,86.02 71.64,86.13 71.38,86.13 71.18,85.93 71.18,85.27 71.29,85.15 72.16,85.15 72.27,85.04 72.27,84.88 72.16,84.77 71.29,84.77 71.18,84.66 71.18,84.5 71.29,84.39 72.16,84.39 72.27,84.28 72.27,84.12 72.16,84.01 71.29,84.01 71.18,83.9 71.18,83.74 71.29,83.63 72.16,83.63 72.27,83.52 72.27,83.36 72.16,83.25 71.29,83.25 71.18,83.14 71.18,82.98 71.29,82.87 72.26,82.87 72.37,82.76 72.37,82.6 72.26,82.49 71.29,82.49 70.95,82.15 69.8,82.15 69.65,82.3 U14.2
SEMC_D1: length 20.5
  TOP w0.14: U14.4 68.05,82.15 68.37,81.83 72.28,81.83 72.88,82.43 72.89,82.43 72.9,82.43 73.24,82.43 73.44,82.63 73.44,84.45 73.55,84.56 73.82,84.56 73.95,84.43 73.95,82.85 74.1,82.7 74.33,82.7 74.45,82.83 74.45,84.41 74.58,84.53 74.93,84.53 75.04,84.42 75.04,82.83 75.14,82.73 75.47,82.73 75.52,82.78 75.52,84.48 75.61,84.57 75.96,84.57 76.05,84.48 76.05,84.23 76.17,84.12 76.35,84.12 76.46,84.01 76.46,83.85 76.35,83.74 76.17,83.74 76.05,83.63 R152.2
SEMC_D2: length 17.4
  TOP w0.14: R153.2 75.55,81.47 75.55,81.69 74.95,82.29 74.57,82.29 74.46,82.17 74.46,81.71 74.36,81.61 74.19,81.61 74.08,81.71 74.08,82.17 73.97,82.29 73.81,82.29 73.7,82.17 73.7,81.71 73.59,81.6 73.43,81.6 73.32,81.71 73.32,81.86 73.18,82 73.08,82 72.94,81.86 72.94,81.71 72.83,81.6 72.52,81.6 72.4,81.47 72.4,81.03 72.28,80.91 71.98,80.91 71.89,81 71.89,81.35 71.75,81.49 71.57,81.49 71.4,81.31 71.22,81.31 71.02,81.51 70.84,81.51 70.63,81.31 70.46,81.31 70.25,81.51 70.08,81.51 69.87,81.31 69.69,81.31 69.49,81.51 69.31,81.51 69.11,81.31 68.93,81.31 68.73,81.51 68.55,81.51 68.35,81.31 67.94,81.31 67.83,81.42 67.83,81.88 67.72,81.99 67.56,81.99 67.45,81.88 67.45,81.42 67.34,81.31 67.03,81.31 66.55,81.78 66.55,82.01 66.69,82.15 67.19,82.15 67.25,82.21 U14.5
SEMC_D3: length 22.9
  TOP w0.14: R154.2 78.06,81.36 78.2,81.5 78.2,82.06 78.06,82.2 77.31,82.2 77.12,82.39 77.12,82.62 77.26,82.76 78.62,82.76 78.76,82.62 78.76,81.02 78.6,80.86 76.62,80.86 76.1,80.34 75.77,80.34 75.66,80.23 75.66,80 75.55,79.89 75.39,79.89 75.28,80 75.28,80.23 75.16,80.35 75.01,80.35 74.9,80.23 74.9,80 74.78,79.89 74.63,79.89 74.51,80 74.51,80.23 74.4,80.34 74.15,80.34 73.9,80.59 71.85,80.59 71.85,80.6 71.81,80.6 71.46,80.95 71.38,80.95 71.37,80.96 66.88,80.96 66.12,81.71 66.12,81.92 65.97,82.07 65.77,82.07 65.65,82.19 U14.7
SEMC_D4: length 20.6
  TOP w0.14: U14.8 64.88,83.44 64.88,82.18 64.69,82 64.69,81.8 64.83,81.66 65.01,81.66 65.26,81.91 65.42,81.91 65.53,81.8 65.53,81.64 65.28,81.39 65.28,81.21 65.41,81.08 65.59,81.08 65.83,81.33 65.99,81.33 66.1,81.22 66.1,81.06 65.86,80.81 65.86,80.63 65.97,80.52 66.15,80.52 66.39,80.76 66.57,80.76 66.67,80.65 66.67,80.46 66.4,80.18 66.4,80.09 66.66,79.83 66.91,79.83 67.02,79.95 67.02,80.51 67.13,80.62 67.29,80.62 67.4,80.51 67.4,79.95 67.51,79.83 67.67,79.83 67.78,79.95 67.78,80.51 67.89,80.62 68.05,80.62 68.16,80.51 68.16,79.95 68.28,79.83 68.43,79.83 68.54,79.95 68.54,80.51 68.66,80.62 68.81,80.62 68.93,80.51 68.93,79.95 69.04,79.83 69.2,79.83 69.31,79.95 69.31,80.51 69.42,80.62 69.58,80.62 69.69,80.51 69.69,79.95 69.8,79.83 69.96,79.83 70.07,79.95 70.07,80.51 70.18,80.62 70.34,80.62 70.45,80.51 70.45,79.95 70.56,79.83 70.85,79.83 70.96,79.95 70.96,80.53 71.08,80.64 71.23,80.64 71.35,80.53 71.35,80.05 71.5,79.89 71.93,79.89 R155.2
SEMC_D5: length 22.6
  TOP w0.14: U14.10 63.25,82.27 63.43,82.1 63.95,82.1 66.52,79.52 66.54,79.52 66.57,79.49 71.71,79.49 71.79,79.57 74.02,79.57 74.25,79.34 74.25,79.18 74.36,79.07 74.52,79.07 74.63,79.18 74.63,79.42 74.74,79.53 74.9,79.53 75.01,79.42 75.01,79.18 75.12,79.07 75.28,79.07 75.39,79.18 75.39,79.44 75.5,79.56 75.66,79.56 75.77,79.44 75.77,79.18 75.88,79.07 76.04,79.07 76.15,79.18 76.15,79.47 76.26,79.58 76.42,79.58 76.53,79.47 76.53,79.18 76.65,79.07 76.8,79.07 76.91,79.18 76.91,79.47 77.03,79.58 77.18,79.58 77.3,79.47 77.3,78.68 77.41,78.56 77.96,78.56 78.21,78.82 R156.2
SEMC_D6: length 18.6
  TOP w0.14: R157.2 71.81,79.07 71.45,78.71 71.03,78.71 70.92,78.82 70.92,79.06 70.8,79.17 70.65,79.17 70.53,79.06 70.53,78.82 70.42,78.71 70.26,78.71 70.15,78.82 70.15,79.06 70.04,79.17 69.88,79.17 69.77,79.06 69.77,78.82 69.66,78.71 69.5,78.71 69.39,78.82 69.39,79.06 69.28,79.17 69.12,79.17 69.01,79.06 69.01,78.82 68.9,78.71 68.74,78.71 68.63,78.82 68.63,79.06 68.52,79.17 68.36,79.17 68.25,79.06 68.25,78.82 68.14,78.71 67.98,78.71 67.87,78.82 67.87,79.06 67.76,79.17 67.6,79.17 67.49,79.06 67.49,78.82 67.37,78.71 67.22,78.71 67.11,78.82 67.11,79.06 66.99,79.17 66.84,79.17 66.72,79.06 66.72,78.82 66.61,78.71 66.39,78.71 65.94,79.15 65.94,79.31 66.03,79.39 66.03,79.55 65.92,79.66 65.76,79.66 65.64,79.54 65.48,79.54 65.37,79.65 65.37,79.81 65.49,79.93 65.49,80.09 65.38,80.2 65.22,80.2 65.1,80.08 64.94,80.08 64.83,80.19 64.83,80.35 64.95,80.47 64.95,80.63 64.84,80.74 64.68,80.74 64.56,80.62 64.4,80.62 64.29,80.73 64.29,80.89 64.41,81.01 64.41,81.16 64.3,81.28 64.14,81.28 64.03,81.16 63.86,81.16 63.71,81.31 63.71,81.62 63.62,81.71 63.32,81.71 62.72,82.3 62.72,82.31 62.45,82.58 U14.11
SEMC_D7: length 23.1
  TOP w0.14: U14.13 60.85,82.02 60.98,81.89 61.7,81.89 61.9,81.69 62.06,81.69 62.33,81.97 62.49,81.97 62.6,81.86 62.6,81.7 62.33,81.42 62.33,81.27 62.44,81.16 62.6,81.16 62.87,81.43 63.03,81.43 63.14,81.32 63.14,81.16 62.87,80.89 62.87,80.73 62.98,80.62 63.14,80.62 63.41,80.89 63.57,80.89 63.68,80.78 63.68,80.62 63.41,80.35 63.41,80.19 63.52,80.08 63.68,80.08 63.95,80.35 64.11,80.35 64.22,80.24 64.22,80.08 63.95,79.81 63.95,79.65 64.06,79.54 64.21,79.54 64.49,79.81 64.65,79.81 64.76,79.7 64.76,79.54 64.48,79.27 64.48,79.11 64.66,78.93 64.84,78.93 65.15,79.24 65.33,79.24 65.45,79.11 65.45,78.96 65.15,78.65 65.15,78.45 65.14,78.45 65.23,78.36 65.56,78.36 65.67,78.47 65.67,78.56 65.78,78.67 65.94,78.67 66.05,78.56 66.05,78.47 66.29,78.23 71.46,78.23 71.79,78.56 R158.2
SEMC_D8: length 19.1
  TOP w0.14: R177.2 71.79,76.66 71.66,76.79 64.24,76.79 64.01,76.56 64.01,76.4 64.27,76.14 64.27,75.98 64.16,75.87 64,75.87 63.74,76.13 63.58,76.13 63.47,76.02 63.47,75.86 63.73,75.6 63.73,75.44 63.62,75.33 63.46,75.33 63.2,75.59 63.05,75.59 62.93,75.48 62.93,75.32 63.2,75.06 63.2,74.9 63.08,74.79 62.93,74.79 62.66,75.05 62.51,75.05 62.39,74.94 62.39,74.78 62.66,74.52 62.66,74.36 62.54,74.25 62.39,74.25 62.13,74.51 61.97,74.51 61.86,74.4 61.86,74.24 62.12,73.98 62.12,73.82 62.01,73.71 61.85,73.71 61.59,73.97 61.43,73.97 60.85,73.4 U14.42
SEMC_D9: length 20.5
  TOP w0.14: U14.44 62.45,73.7 64.62,75.87 64.62,76.3 64.75,76.43 64.97,76.43 65.09,76.32 65.09,76.09 65.2,75.97 65.36,75.97 65.47,76.09 65.47,76.32 65.58,76.43 65.74,76.43 65.85,76.32 65.85,76.09 65.96,75.97 66.12,75.97 66.23,76.09 66.23,76.32 66.34,76.43 66.5,76.43 66.61,76.32 66.61,76.09 66.72,75.97 66.88,75.97 66.99,76.09 66.99,76.32 67.1,76.43 67.26,76.43 67.37,76.32 67.37,76.09 67.48,75.97 67.64,75.97 67.75,76.09 67.75,76.32 67.86,76.43 68.02,76.43 68.13,76.32 68.13,76.09 68.25,75.97 68.4,75.97 68.52,76.09 68.52,76.32 68.63,76.43 68.78,76.43 68.9,76.32 68.9,76.09 69.01,75.97 69.17,75.97 69.28,76.09 69.28,76.32 69.39,76.43 69.55,76.43 69.66,76.32 69.66,76.11 69.77,76 69.93,76 70.04,76.11 70.04,76.32 70.15,76.43 70.31,76.43 70.42,76.32 70.42,76.11 70.53,76 70.69,76 70.8,76.11 70.8,76.32 70.91,76.43 71.48,76.43 71.76,76.15 R178.2
SEMC_D10: length 18.8
  TOP w0.14: R179.2 71,75.64 70.89,75.53 70.89,75.43 70.78,75.31 70.62,75.31 70.51,75.43 70.51,75.53 70.4,75.64 70.24,75.64 70.13,75.53 70.13,75.43 70.01,75.31 69.86,75.31 69.74,75.43 69.74,75.53 69.63,75.64 69.48,75.64 69.36,75.53 69.36,75.43 69.25,75.31 69.09,75.31 68.98,75.43 68.98,75.53 68.87,75.64 68.71,75.64 68.6,75.53 68.6,75.43 68.49,75.31 68.33,75.31 68.22,75.43 68.22,75.53 68.11,75.64 67.95,75.64 67.84,75.53 67.84,75.43 67.73,75.31 67.57,75.31 67.46,75.43 67.46,75.53 67.35,75.64 67.19,75.64 67.08,75.53 67.08,75.43 66.97,75.31 66.81,75.31 66.7,75.43 66.7,75.53 66.59,75.64 66.43,75.64 66.32,75.53 66.32,75.43 66.2,75.31 66.05,75.31 65.93,75.43 65.93,75.56 65.8,75.69 65.67,75.69 65.55,75.58 65.55,75.33 65.41,75.19 65.22,75.19 64.93,75.47 64.73,75.47 64.59,75.33 64.59,75.18 64.94,74.83 64.94,74.67 64.83,74.56 64.67,74.56 64.3,74.93 64.14,74.93 64.03,74.82 64.03,74.66 64.42,74.27 64.42,74.12 64.3,74 64.15,74 63.76,74.39 63.6,74.39 63.49,74.28 63.49,74.12 63.74,73.87 63.74,73.75 63.6,73.6 63.47,73.6 63.22,73.85 63.06,73.85 62.92,73.71 62.92,73.52 63.25,73.19 U14.45
SEMC_D11: length 21.1
  TOP w0.14: U14.47 64.85,73.1 64.52,73.43 64.52,73.77 64.73,73.98 64.73,73.99 65.74,75 70.91,75 71.05,75.14 74.02,75.14 74.52,75.63 76.27,75.63 76.56,75.92 76.56,76.13 76.67,76.24 76.81,76.24 76.92,76.35 76.92,76.51 76.81,76.62 76.67,76.62 76.56,76.73 76.56,76.89 76.67,77 76.83,77 76.94,77.12 76.94,77.27 76.83,77.39 76.67,77.39 76.56,77.5 76.56,77.68 76.66,77.78 77.15,77.78 77.5,77.43 R180.2
SEMC_D12: length 17.3
  TOP w0.14: U14.48 65.65,73.07 65.04,73.67 65.04,73.85 65.23,74.04 65.39,74.04 65.42,74.01 65.58,74.01 65.69,74.12 65.69,74.28 65.66,74.31 65.66,74.47 65.82,74.63 65.95,74.63 66.07,74.52 66.07,74.1 66.2,73.97 66.34,73.97 66.45,74.07 66.45,74.52 66.56,74.63 66.72,74.63 66.83,74.52 66.83,73.75 66.94,73.64 67.1,73.64 67.21,73.75 67.21,74.52 67.37,74.68 67.6,74.68 67.78,74.5 68.02,74.5 68.2,74.68 68.44,74.68 68.62,74.5 68.86,74.5 69.03,74.68 69.28,74.68 69.45,74.5 69.7,74.5 69.87,74.68 70.11,74.68 70.29,74.5 70.53,74.5 70.71,74.68 70.95,74.68 71.13,74.5 71.37,74.5 71.69,74.82 72.71,74.82 73.46,74.07 75.04,74.07 75.21,74.24 R181.2
SEMC_D13: length 20.9
  TOP w0.14: U14.50 67.25,73.34 68.08,74.17 71.56,74.17 71.76,74.37 72.59,74.37 73.38,73.59 78.19,73.59 78.54,73.94 78.54,74.46 78.43,74.57 78.43,74.57 78.31,74.68 78.31,74.84 78.43,74.95 78.43,74.95 78.54,75.06 78.54,75.22 78.43,75.33 78.43,75.33 78.31,75.44 78.31,75.6 78.43,75.71 78.43,75.71 78.54,75.83 78.54,75.98 78.43,76.09 78.43,76.09 78.31,76.21 78.31,76.36 78.43,76.48 78.43,76.48 78.54,76.59 78.54,76.86 78.3,77.11 78.11,77.11 77.98,76.98 77.98,74.56 R182.2
SEMC_D14: length 17.6
  TOP w0.14: U14.51 68.05,73.38 68.5,73.83 69.65,73.83 69.87,73.61 70.03,73.61 70.25,73.83 70.41,73.83 70.63,73.61 70.8,73.61 71.01,73.83 71.18,73.83 71.39,73.61 71.56,73.61 71.77,73.83 72.42,73.83 72.55,73.7 72.55,73.4 72.66,73.29 73,73.29 73.11,73.17 73.11,73.02 73,72.9 72.66,72.9 72.55,72.79 72.55,72.64 72.66,72.52 73,72.52 73.11,72.41 73.11,72.25 73,72.14 72.66,72.14 72.55,72.03 72.55,71.4 72.71,71.24 73.33,71.24 73.33,71.24 74,71.24 74,71.24 74.14,71.24 75.19,72.29 75.19,73.03 74.96,73.26 74.5,73.26 74.3,73.05 74.3,71.94 74.03,71.66 R183.2
SEMC_D15: length 20
  TOP w0.14: R184.2 76.09,71.71 76.33,71.96 76.33,72.68 76.74,73.09 77.08,73.09 77.32,72.85 77.32,72.27 76.18,71.13 75.82,71.13 75.69,71.26 75.53,71.26 75.42,71.15 75.42,70.99 75.55,70.86 75.55,70.7 75.42,70.56 75.18,70.56 75.07,70.68 75.07,71.34 74.96,71.45 74.8,71.45 74.69,71.34 74.69,70.82 74.55,70.68 74.48,70.68 74.23,70.92 74.08,70.92 73.96,70.81 73.96,70.68 73.85,70.56 73.7,70.56 73.58,70.68 73.58,70.81 73.47,70.92 73.31,70.92 73.2,70.81 73.2,70.68 73.09,70.56 72.93,70.56 72.82,70.68 72.82,70.81 72.71,70.92 72.55,70.92 72.44,70.81 72.44,70.68 72.33,70.56 71.84,70.56 71.69,70.72 71.69,70.86 71.8,70.97 72.13,70.97 72.24,71.08 72.24,71.24 72.13,71.35 71.8,71.35 71.69,71.46 71.69,71.66 72.12,72.09 72.12,73.08 71.99,73.21 69.79,73.21 69.65,73.07 U14.53
SEMC_D16: length 46.8
  TOP w0.14: U6.N5 v1(97.09,66.84) ; U16.2 69.65,58.37 69.87,58.16 70.06,58.16 70.07,58.15 70.83,58.15 71.08,58.39 71.08,58.65 71.2,58.78 72.19,58.78 72.6,59.19 72.6,59.36 73.26,60.02 74.05,60.02 74.45,59.63 76.8,59.63 76.94,59.49 76.94,59.07 77.08,58.93 77.36,58.93 77.5,59.07 77.5,59.49 77.64,59.63 78.61,59.63 79,59.24 79,57.46 78.87,57.33 78.61,57.33 78.49,57.46 78.49,58.59 78.36,58.72 78.06,58.72 77.93,58.59 v1(77.93,58.21)
  BOTTOM w0.14: v1(97.09,66.84) 96.5,66.25 96.28,66.25 95.67,65.64 94.88,65.64 93.71,64.47 91.01,64.47 87.38,60.84 83.9,60.84 83.77,60.71 83.59,60.71 83.4,60.89 83.22,60.89 83.04,60.71 83.04,60.53 83.23,60.35 83.23,60.17 83.05,59.99 82.87,59.99 82.69,60.18 82.51,60.18 82.33,60 82.33,59.82 82.51,59.63 82.51,59.45 82.33,59.27 82.16,59.27 81.97,59.46 81.79,59.46 81.61,59.28 81.61,59.1 81.8,58.91 81.8,58.73 81.27,58.21 80.97,58.21 80.85,58.33 80.85,58.85 80.72,58.98 80.47,58.98 80.34,58.85 80.34,58.33 80.21,58.21 79.96,58.21 79.83,58.33 79.83,58.85 79.7,58.98 79.45,58.98 79.32,58.85 79.32,58.33 79.2,58.21 79.02,58.21 78.88,58.35 78.88,58.87 78.74,59.01 78.46,59.01 78.32,58.87 78.32,58.35 78.18,58.21 v1(77.93,58.21)
SEMC_D17: length 45.5
  TOP w0.14: v1(90.15,64.34) 90.66,64.85 92.95,64.85 93.33,65.24 94.69,65.24 U6.R2 ; v1(72.61,58.53) 72.43,58.35 71.51,58.35 70.93,57.76 69.75,57.76 68.92,56.92 68,56.92 67.67,57.25 67.67,57.94 68.05,58.32 U16.4
  BOTTOM w0.14: v1(90.15,64.34) 87.08,61.27 82.96,61.27 81.08,59.39 79.73,59.39 79.61,59.51 79.61,60.35 79.48,60.48 79.22,60.48 79.1,60.35 79.1,59.51 78.97,59.39 78.72,59.39 78.59,59.51 78.59,60.35 78.46,60.48 78.21,60.48 78.08,60.35 78.08,59.51 77.95,59.39 77.7,59.39 77.57,59.51 77.57,60.35 77.45,60.48 77.19,60.48 77.07,60.35 77.07,59.26 76.94,59.13 76.68,59.13 76.56,59.26 76.56,60.35 76.43,60.48 76.18,60.48 76.05,60.35 76.05,58.65 75.92,58.52 75.67,58.52 75.54,58.65 75.54,60.35 75.41,60.48 75.16,60.48 75.03,60.35 75.03,59.51 74.91,59.39 74.25,59.39 74.12,59.26 74.12,58.75 73.91,58.53 v1(72.61,58.53)
SEMC_D18: length 17.4
  TOP w0.14: v1(70.47,57.27) 70.88,57.27 71.61,57.99 73.06,57.99 73.23,58.17 73.23,59.39 73.39,59.54 73.62,59.54 73.74,59.41 73.74,57.86 73.54,57.66 71.91,57.66 71.9,57.65 71.86,57.65 71.06,56.85 70.65,56.85 70.65,56.84 70.3,56.84 70.18,56.96 69.61,56.96 69.25,56.59 67.22,56.59 67.09,56.71 67.09,58 67.25,58.16 U16.5
  BOTTOM w0.14: R1329.2 70.69,57.48 v1(70.47,57.27)
SEMC_D19: length 16.2
  TOP w0.14: v1(70.06,56.42) 69.86,56.21 66.66,56.21 66.02,56.85 66.02,57.74 65.65,58.11 U16.7
  BOTTOM w0.14: R2594.2 77.45,55.96 76.67,56.74 70.38,56.74 v1(70.06,56.42)
SEMC_D20: length 21.4
  TOP w0.14: R2595.2 76.53,58.4 76.53,59.08 76.4,59.21 76.15,59.21 76.02,59.08 76.02,58.4 75.9,58.27 75.64,58.27 75.52,58.4 75.52,59.08 75.39,59.21 74.29,59.21 74.15,59.07 74.15,58.63 74.28,58.5 74.87,58.5 75.01,58.36 75.01,57.91 74.87,57.78 v1(74.25,57.78) 73.81,57.33 71.99,57.33 71.02,56.36 71.02,56.04 70.82,55.83 66.53,55.83 65.51,56.85 65.51,57.48 64.85,58.14 U16.8
SEMC_D21: length 19.2
  TOP w0.14: U16.10 63.25,57.1 64.9,55.45 71.08,55.45 71.35,55.73 71.35,56.21 72.12,56.97 72.39,56.97 72.52,56.85 72.52,56.37 72.64,56.24 72.9,56.24 73.02,56.37 73.02,56.85 73.15,56.97 73.4,56.97 73.53,56.85 73.53,56.47 73.66,56.34 73.91,56.34 74.04,56.47 74.04,56.85 74.17,56.97 74.99,56.97 75.74,57.73 R189.2
SEMC_D22: length 16
  TOP w0.14: U16.11 62.45,58.23 61.83,57.61 61.83,57.03 62.06,56.8 62.24,56.8 62.52,57.07 62.7,57.07 62.88,56.89 62.88,56.71 62.6,56.44 62.6,56.26 62.78,56.08 62.96,56.08 63.24,56.35 63.42,56.35 63.6,56.17 63.6,55.99 63.32,55.72 63.32,55.54 63.73,55.12 71.35,55.12 71.94,55.7 R190.2
SEMC_D23: length 17.2
  TOP w0.14: R191.2 72.02,55.2 71.56,54.74 63.44,54.74 61.04,57.13 61.04,57.13 60.76,57.41 60.76,57.81 60.76,57.81 60.76,57.94 60.85,58.03 U16.13
SEMC_D24: length 18.3
  TOP w0.14: R193.2 63.94,53.04 63.57,52.67 63.57,52.51 63.63,52.45 63.63,52.3 63.51,52.18 63.36,52.18 63.3,52.24 63.14,52.24 63.03,52.13 63.03,51.97 63.09,51.91 63.09,51.76 62.98,51.64 62.82,51.64 62.76,51.7 62.6,51.7 62.49,51.59 62.49,51.43 62.55,51.37 62.55,51.22 62.44,51.11 62.28,51.11 62.22,51.16 62.06,51.16 61.95,51.05 61.95,50.89 62.01,50.84 62.01,50.68 61.9,50.57 61.74,50.57 61.68,50.62 61.52,50.62 61.41,50.51 61.41,50.35 61.47,50.3 61.47,50.14 61.36,50.03 61.2,50.03 61.14,50.09 60.99,50.09 60.74,49.84 59.81,49.84 59.67,49.7 59.67,49.41 59.8,49.28 60.74,49.28 60.85,49.16 U16.42
SEMC_D25: length 18.6
  TOP w0.14: R194.2 64.4,52.53 64.22,52.36 64.22,52.2 64.33,52.09 64.33,51.93 64.22,51.82 64.06,51.82 63.95,51.93 63.8,51.93 63.68,51.82 63.68,51.66 63.79,51.55 63.79,51.39 63.68,51.28 63.52,51.28 63.41,51.39 63.26,51.39 63.15,51.28 63.15,51.12 63.25,51.01 63.25,50.86 63.14,50.74 62.98,50.74 62.88,50.85 62.72,50.85 62.61,50.74 62.61,50.58 62.72,50.47 62.72,50.32 62.6,50.2 62.45,50.2 62.34,50.31 62.18,50.31 61.53,49.66 61.53,49.38 61.6,49.3 62.32,49.3 62.45,49.18 U16.44
SEMC_D26: length 16.1
  TOP w0.14: U16.45 63.25,49.13 62.8,49.58 62.8,49.84 62.92,49.96 63.08,49.96 63.3,49.74 63.46,49.74 63.57,49.85 63.57,50.01 63.35,50.23 63.35,50.39 63.46,50.5 63.61,50.5 63.88,50.24 64.03,50.24 64.15,50.35 64.15,50.51 63.88,50.77 63.88,50.93 64,51.04 64.15,51.04 64.44,50.75 64.6,50.75 64.71,50.86 64.71,51.02 64.42,51.31 64.42,51.47 64.54,51.58 64.69,51.58 64.98,51.29 65.14,51.29 65.25,51.4 65.25,51.56 64.96,51.85 64.96,52 65.11,52.15 71.48,52.15 71.61,52.02 R195.2
SEMC_D27: length 16.3
  TOP w0.14: R196.2 71.63,51.51 71.43,51.72 66.1,51.72 65.84,51.46 65.84,51.3 66.09,51.05 66.09,50.9 65.98,50.78 65.82,50.78 65.57,51.03 65.41,51.03 65.3,50.92 65.3,50.76 65.55,50.52 65.55,50.36 65.44,50.25 65.28,50.25 65.03,50.49 64.87,50.49 64.76,50.38 64.76,50.23 64.99,50 64.99,49.84 64.88,49.73 64.72,49.73 64.49,49.96 64.34,49.96 64.04,49.66 64.04,49.4 64.12,49.33 64.62,49.33 64.85,49.1 U16.47
SEMC_D28: length 12.8
  TOP w0.14: R198.2 71.63,51.01 71.25,51.39 67.19,51.39 66.67,50.87 66.67,50.71 67.2,50.19 67.2,50.03 67.09,49.92 66.93,49.92 66.4,50.45 66.25,50.45 66,50.19 66,50.04 66.58,49.46 66.58,49.3 66.47,49.19 66.3,49.19 65.73,49.77 65.57,49.77 65.39,49.58 65.39,49.41 65.65,49.14 U16.48
SEMC_D29: length 14.3
  TOP w0.14: R200.2 71.63,50.5 71.15,50.98 71.01,50.98 70.89,50.87 70.89,50.43 70.78,50.32 70.63,50.32 70.51,50.43 70.51,50.87 70.4,50.98 70.24,50.98 70.13,50.87 70.13,50.43 70.02,50.32 69.86,50.32 69.75,50.43 69.75,50.87 69.64,50.98 69.48,50.98 69.37,50.87 69.37,50.43 69.26,50.32 69.1,50.32 68.99,50.43 68.99,50.87 68.88,50.98 68.72,50.98 68.61,50.87 68.61,50.43 68.5,50.32 68.34,50.32 68.23,50.43 68.23,50.87 68.12,50.98 67.85,50.98 67.65,50.78 67.65,49.71 67.25,49.32 U16.50
SEMC_D30: length 15.6
  TOP w0.14: R201.2 72,49.43 72.19,49.23 73.83,49.23 74,49.06 74,48.87 73.87,48.75 73.66,48.75 73.54,48.63 73.54,48.35 73.43,48.24 73.28,48.24 73.16,48.35 73.16,48.63 73.05,48.75 72.89,48.75 72.78,48.63 72.78,48.35 72.67,48.24 72.51,48.24 72.37,48.38 72.37,48.63 72.26,48.75 72.17,48.75 71.95,48.52 71.75,48.52 71.61,48.66 71.61,48.97 70.98,49.6 70.98,49.88 70.87,49.99 70.73,49.99 70.62,49.88 70.62,49.66 70.5,49.55 70.35,49.55 70.23,49.66 70.23,49.88 70.12,49.99 69.97,49.99 69.85,49.88 69.85,49.66 69.74,49.55 69.65,49.55 69.47,49.72 69.47,49.88 69.36,49.99 69.2,49.99 69.09,49.88 69.09,49.47 68.98,49.35 68.82,49.35 68.71,49.47 68.71,49.88 68.6,49.99 68.36,49.99 68.05,49.68 U16.51
SEMC_D31: length 15.1
  TOP w0.14: R202.2 74.41,48.87 75.02,48.27 75.02,47.25 74.89,47.12 74.71,47.12 74.6,47.23 74.6,47.72 74.49,47.83 74.33,47.83 74.22,47.72 74.22,47.23 74.11,47.12 73.95,47.12 73.84,47.23 73.84,47.72 73.72,47.83 73.57,47.83 73.45,47.72 73.45,47.23 73.34,47.12 73.19,47.12 73.07,47.23 73.07,47.72 72.96,47.83 72.8,47.83 72.69,47.72 72.69,47.23 72.58,47.12 72.42,47.12 72.31,47.23 72.31,47.72 72.2,47.83 72.04,47.83 71.93,47.72 71.93,47.54 71.82,47.42 71.25,47.42 71.13,47.55 71.13,48.97 70.87,49.23 69.78,49.23 69.65,49.1 U16.53
SEMC_DM0: length 16
  TOP w0.14: U14.15 59.25,82.24 59.95,81.54 61.47,81.54 65.13,77.88 71.63,77.88 71.81,78.06 R159.2
SEMC_DM1: length 19
  TOP w0.14: U14.39 58.45,73.16 59.54,74.25 61.17,74.25 64.09,77.17 R185.2
SEMC_DM2: length 16.2
  TOP w0.14: U16.15 59.25,58.23 59.1,58.08 59.1,57.8 62.52,54.38 72.07,54.38 R192.2
SEMC_DM3: length 18.9
  TOP w0.14: R204.2 63.84,53.55 61.23,50.94 58.88,49.71 58.45,49.28 U16.39
SEMC_RAS: length 58.9
  TOP w0.127: v1(57.59,78.51) 57.59,78.74 57.46,78.87 56.98,78.87 56.85,79 56.85,79.25 56.98,79.38 57.16,79.38 57.28,79.5 57.28,79.76 57.16,79.88 56.98,79.88 56.85,80.01 56.85,80.26 56.98,80.39 57.16,80.39 57.28,80.52 57.28,80.77 57.16,80.9 56.98,80.9 56.85,81.03 56.85,81.28 56.98,81.41 57.16,81.41 57.28,81.53 57.28,81.79 57.16,81.92 56.98,81.92 56.85,82.04 U14.18 ; v1(58.4,54.56) 58.4,54.51 59.34,53.57 61.12,53.57 61.25,53.7 61.25,53.93 61.12,54.05 59.44,54.05 59.11,54.38 59.11,54.99 59.04,55.07 57.79,55.07 57.66,55.2 57.66,55.45 57.79,55.58 58.93,55.58 59.09,55.73 59.09,55.96 58.96,56.09 56.62,56.09 56.5,56.21 56.5,56.44 56.62,56.57 58.07,56.57 58.2,56.7 58.2,56.95 58.05,57.1 56.57,57.1 56.44,57.23 56.44,57.48 56.57,57.61 57.13,57.61 57.26,57.74 57.26,57.99 57.13,58.12 56.98,58.12 56.85,58.24 U16.18 ; R172.2 58.69,62.56 v1(58.19,62.05)
  L3_INT_1 w0.127: v1(58.4,54.56) 58.4,61.19 58.19,61.41 v1(58.19,62.05) 58.19,72.76 58.64,73.22 58.64,74.13 58.25,74.53 58.25,75.14 58.38,75.26 58.99,75.26 59.11,75.39 59.11,75.67 59,75.79 58.36,75.79 58.25,75.9 58.25,76.15 58.38,76.28 58.93,76.28 59.06,76.41 59.06,77.9 58.93,78.03 58.68,78.03 58.33,77.68 58.15,77.68 57.59,78.23 v1(57.59,78.51)
SEMC_RDY: length 1.6
  TOP w0.14: R187.2 80.76,63.46 TP14.1
SEMC_WE: length 69.3
  TOP w0.127: v1(60.69,54.56) 60.69,55.6 58.45,57.84 U16.16 ; U14.16 58.45,82.03 58.58,81.91 58.82,81.91 58.95,81.78 58.95,81.53 58.82,81.4 58.58,81.4 58.45,81.27 58.45,81.02 58.58,80.89 61.41,80.89 61.54,80.76 61.54,80.53 61.39,80.38 59.6,80.38 59.44,80.23 59.44,80.04 59.57,79.91 61.8,79.91 61.93,79.78 61.93,79.53 61.82,79.42 59.5,79.42 59.39,79.31 59.39,79.15 59.5,79.04 63.06,79.04 63.18,78.93 63.18,78.72 62.97,78.51 v1(60.86,78.51) ; v1(59.54,70.39) 59.87,70.39 60.06,70.58 68.73,70.58 R175.2
  L3_INT_1 w0.127: v1(60.86,78.51) 59.72,77.37 59.72,76.88 59.72,76.87 59.72,72.47 59.54,72.29 v1(59.54,70.39) 59.54,62.51 60.69,61.37 60.69,60.93 60.81,60.8 61.65,60.8 61.78,60.68 61.78,60.42 61.65,60.3 60.81,60.3 60.69,60.17 60.69,59.91 60.81,59.79 61.65,59.79 61.78,59.66 61.78,59.41 61.65,59.28 60.81,59.28 60.69,59.15 60.69,58.9 60.81,58.77 61.65,58.77 61.78,58.64 61.78,58.39 61.65,58.26 60.81,58.26 60.69,58.14 60.69,57.03 60.81,56.9 61.19,56.9 61.32,56.77 61.32,56.52 61.19,56.39 60.81,56.39 60.69,56.27 60.69,56.01 60.81,55.89 61.19,55.89 61.32,55.76 61.32,55.5 61.19,55.38 60.81,55.38 60.69,55.25 v1(60.69,54.56)
SENSOR_3V3: length 275.2
  TOP w0.081: U369.G3 92.3,118.2 v1(92.69,117.81)
  TOP w0.203: U115.1 61.87,91.86 v1(62.08,91.65)
  TOP w0.305: R1036.1 v1(64.88,91.14) ; R715.1 v1(29.95,127.71) ; R2101.1 v1(42.65,37.8) ; C409.1 106.03,107.27 v1(106.03,107.27) U71.10 ; v1(112.25,121.87) R877.1 ; R635.1 v1(183.37,74.5) ; v1(158.98,27.26) 159.12,27.39 C317.1 160.04,27.1 U48.8 ; U15.D1 v1(82.92,84.51) ; R624.1 R627.1 v1(180.45,57.23) ; R2134.1 v1(83.93,115.14) ; U106.10 40.88,55.45 C455.1 v1(40.87,54.69) ; C406.1 153.14,72.73 v1(153.14,72.72) U68.10 ; R629.1 v1(180.19,54.18) ; U101.10 40.88,65.86 C436.1 v1(40.11,65.87) ; U97.10 40.88,80.6 C432.1 v1(40.11,80.6) ; U6.N7 v2(98.69,66.84) U6.N6 ; v1(80.92,82.46) 80.97,82.46 U15.E4 ; U6.F7 v2(98.69,73.24) ; R339.1 v1(151.24,51.39) ; 143.46,27.76 141.84,27.76 v1(141.71,27.64) ; U96.10 40.88,84.28 C431.1 40.13,84.29 40.11,84.27 v1(40.09,84.27) ; R295.1 v1(131.93,13.79) ; U65.10 v1(140.95,115.53) 140.94,115.52 C403.1 ; v1(41.13,88.85) 41.26,88.72 C910.1 40.87,88.09 40.86,88.11 U418.5 ; R33.1 v1(122.15,37.29) ; R897.1 v1(60.3,121.74) ; U15.B4 v1(84.92,81.51) ; R2104.1 v1(42.65,41.35) ; R575.1 v1(25.38,80.09) ; U69.10 101.71,106.53 v1(101.71,107.26) C407.1 ; R2585.1 v1(128.63,13.79) ; v1(128.38,39.83) 128.24,39.96 R22.1 127.04,39.96 v1(126.9,39.83) ; U66.10 v1(143.24,72.72) 142.58,72.72 C404.1 ; v2(102.69,67.64) U6.M11 U6.L12 v2(102.69,69.24) ; v1(190.7,86.85) 190.67,86.82 C468.1 ; U98.10 40.88,76.91 C433.1 v1(40.11,76.92) ; R716.1 v1(32.49,127.71) ; R317.1 v1(67.16,91.77) ; v1(40.11,69.55) C435.1 40.88,69.55 U100.10 ; R1314.1 v1(51.8,109.3) ; U103.10 40.88,59.39 C452.1 v1(39.73,59.39) ; R1315.1 v1(53.07,109.3) ; R32.1 v1(122.32,34.37) ; R316.1 v1(81.26,93.04) ; C402.1 148.95,115.01 148.95,115.02 v1(148.95,115.53) U64.10 ; R783.1 v1(150.73,29.29) ; R718.1 v1(37.57,127.71) ; R717.1 v1(35.03,127.71) ; v1(23.99,54.06) R522.1 ; R313.1 v1(67.16,95.33) ; R800.1 v1(161.14,16.97) ; C312.1 v1(150.73,27.76) 149.11,27.76 ; v1(40.21,73.24) C434.1 40.88,73.23 U99.10 ; C401.1 145.14,114.87 v1(145.14,115.53) U63.10 ; R570.1 35.44,88.34 v1(35.43,88.33) ; v1(112.25,118.32) R880.1 ; R517.1 v1(34.15,63.96) ; U6.K5 v2(97.89,70.04) U6.J5 ; R798.1 v1(153.14,28.78) ; U73.8 v1(59.2,122.21) ; R782.1 v1(150.6,31.83) ; C304.1 157.71,29.92 157.98,30.19 U45.8 ; R2695.1 v1(25.25,78.95) ; R801.1 v1(153.02,31.32) ; R1041.1 v1(112.76,21.8) ; D25.A v1(22.96,126.65) ; C408.1 110.98,107.32 v1(110.98,107.27) 110.98,106.53 U70.10 ; v1(156.83,50.75) 156.82,50.75 C126.1 ; R713.1 v1(17.25,127.71) ; R1044.2 v1(185.91,87.71) ; R256.1 v1(150.73,119.47) ; R1316.1 v1(54.34,109.3) ; v1(130.66,106.5) 130.54,106.38 R464.1 ; C105.1 v1(79.31,94.31) U13.8 ; R1033.1 v1(55.99,93.55) ; C405.1 147.54,72.72 v1(148.19,72.72) U67.10 ; v1(112.25,111.2) R893.1 ; R640.1 v1(183.88,69.8) ; v1(112.25,114.76) R887.1 ; R639.1 v1(183.37,73.61) ; U6.J6 v2(98.69,70.84) ; v1(116.39,60.66) R1340.1 ; R1038.1 v1(64.88,93.8) ; R2154.1 v1(59.67,107.77) ; R2113.1 v1(100.06,36.4)
  TOP w0.381: 111.36,47.72 R43.1 110.93,47.32 ; v1(78.34,102.21) 78.34,101.56 R646.1 ; J67.1 189.85,37.38 ; J67.1 190.82,36.4 ; J67.1 188.87,36.4 ; J67.1 189.85,35.42 ; 191.24,38.67 C462.1 ; C462.1 191.68,39.07 ; C462.1 190.81,39.07 ; 173.84,123.25 L33.1 ; L33.1 174.28,123.66 ; L33.1 173.41,123.66 ; R655.1 v1(78.33,106) ; C297.1 96.04,131.14 ; C297.1 95.18,131.14 ; C297.1 95.61,131.54 ; 191.41,36.4 J67.2 ; J67.2 192.39,35.42 ; J67.2 192.39,37.38 ; J67.2 193.36,36.4 ; L9.1 51.34,88.08 ; L9.1 50.91,88.49 ; L9.1 50.48,88.08 ; 78.35,46.94 R54.1 ; R54.1 79.85,46.94 ; R54.1 79.1,46.32 ; C296.1 94.71,131.52 ; C296.1 93.96,132.15 ; C296.1 93.21,131.52 ; J12.1 81.64,47.37 ; J12.1 80.7,46.43 ; J12.1 81.64,45.49 ; J12.1 82.58,46.43 ; C463.1 190.28,39.07 ; C463.1 189.85,38.67 ; C463.1 189.41,39.07 ; 118.73,46.41 R51.1 ; R51.1 118.29,46.82 ; R51.1 119.16,46.82 ; v1(77.58,98.5) C272.1 77.54,99.22 U41.5 ; J44.16 170.87,42.26 ; J44.16 171.87,41.25 ; J44.16 170.87,40.25 ; J44.16 169.86,41.25 ; R456.2 v1(131.68,117.93) ; C288.1 v1(172.69,115.9) ; Y3.4 v1(172.79,121.58) ; v1(158.1,26.88) C305.1 158.1,28.9 C304.1 ; 125.71,58.73 R20.1 ; R20.1 125.28,59.14 ; R20.1 126.14,59.14 ; v1(122.66,116.54) 122.28,116.16 R469.1 ; J47.4 94.97,134.35 ; J47.4 94.12,133.5 ; J47.4 94.12,135.2 ; J47.4 93.27,134.35 ; Y3.3 v1(172.79,118.88) ; R562.2 v1(23.86,89.49) ; U42.5 77.54,104.93 C278.1 v1(77.58,105.86) ; 112.55,3 TP51.1 112.12,3.43
  TOP w0.457: R509.2 v1(21.82,64.21)
  TOP w0.508: J37.2 37.57,131.02 36.81,130.25 v1(36.81,128.35)
  L3_INT_1 w0.381: 184.77,5.79 J69.1 ; J69.1 185.78,6.81 ; J69.1 183.75,6.81 ; J69.1 184.77,7.83 ; 189.85,35.42 J67.1 ; J67.1 188.87,36.4 ; J67.1 189.85,37.38 ; J67.1 190.82,36.4 ; J67.2 192.39,37.38 ; J67.2 191.41,36.4 ; J67.2 193.36,36.4 ; J67.2 192.39,35.42 ; J23.2 127.36,19.56 ; J23.2 126.42,18.62 ; J23.2 127.36,17.68 ; J23.2 128.3,18.62
  L4_PWR_1 w0.381: 96.45,104.6 J59.1 ; J59.1 97.39,105.54 ; J59.1 98.33,104.6 ; J59.1 97.39,103.66 ; 41.38,48.92 J72.1 ; J72.1 40.44,49.86 ; J72.1 42.32,49.86 ; J72.1 41.38,50.8 ; 36,72.21 J63.1 ; J63.1 37.88,72.21 ; J63.1 36.94,73.16 ; J63.1 36.94,71.27 ; 159.3,88.5 J45.8 ; J45.8 159.3,90.51 ; J45.8 158.29,89.5 ; J45.8 160.3,89.5 ; 22.33,38 J3.1 ; J3.1 23.27,38.94 ; J3.1 21.39,38.94 ; J3.1 22.33,39.88 ; 145.65,107.6 J57.1 ; J57.1 145.65,109.48 ; J57.1 146.59,108.54 ; J57.1 144.71,108.54 ; J45.4 165.38,89.5 ; J45.4 164.38,90.51 ; J45.4 164.38,88.5 ; J45.4 163.37,89.5 ; 97.39,112.68 J75.1 ; J75.1 96.45,113.62 ; J75.1 98.33,113.62 ; J75.1 97.39,114.56 ; 40.44,46.18 J65.1 ; J65.1 42.32,46.18 ; J65.1 41.38,47.12 ; J65.1 41.38,45.24 ; J76.1 145.65,112.91 ; J76.1 144.71,111.97 ; J76.1 145.65,111.03 ; J76.1 146.59,111.97 ; JP6.1 48.8,119.71 ; JP6.1 47.86,118.77 ; JP6.1 47.86,120.65 ; J58.1 141.97,77.98 ; J58.1 141.03,77.04 ; J58.1 141.97,76.1 ; J58.1 142.91,77.04 ; 154.53,78.06 J62.7 ; J62.7 156.59,78.06 ; J62.7 155.56,79.09 ; J62.7 155.56,77.03 ; 80.7,46.43 J12.1 ; J12.1 81.64,47.37 ; J12.1 82.58,46.43 ; J12.1 81.64,45.49 ; J73.1 36.94,76.2 ; J73.1 37.88,75.26 ; J73.1 36.94,74.32 ; J73.1 36,75.26
  BOTTOM w0.305: U416.5 131.57,104.08 131.68,103.96 C908.1 v1(132.19,104.63) ; C116.1 82.94,84.54 v1(82.92,84.51) ; C117.1 80.88,82.5 v1(80.92,82.46) ; C470.1 156.1,122.51 v1(155.96,122.36) U119.5 ; R510.2 33.63,62.96 v1(33.52,63.07) ; C581.1 92.82,117.93 v1(92.69,117.81) ; U118.5 121.3,86.85 121.42,86.97 C469.1 v1(122.03,86.29) ; v1(91.8,43.64) 94.16,46 94.16,54.38 97.17,57.39 C90.1 97.17,63.74 98.53,65.1 98.53,66.68 v2(98.69,66.84) ; R316.1 v1(81.26,93.04) ; R1045.1 v1(115.04,87.71) ; R335.1 86.01,80.6 v1(85.92,80.51) ; R1047.2 v1(152.76,126.19) ; R1039.1 R1040.1 v1(58.27,94.44) ; U116.5 156.65,50.57 v1(156.83,50.75) ; v1(59.2,122.21) 59.16,122.25 C410.1 ; U117.5 v1(190.7,86.85)
  BOTTOM w0.381: L34.1 60.99,28.28 60.78,28.48 v1(60.46,28.48) ; R563.2 35.66,88.1 v1(35.43,88.33) ; C464.1 61.45,92.28 v1(62.08,91.65) 61.83,91.39 C465.1 ; R508.2 v1(33,63.96) ; v1(131.17,109.81) R455.2 v1(131.17,108.16) ; R1026.1 R1027.1 v1(62.72,95.58) ; L36.1 v1(93.89,28.28)
  BOTTOM w0.457: R561.2 v1(34.39,88.34)
  vias: v1(49.13,88.34) v1(49.26,89.74) v1(49.76,88.34) v1(50.02,89.74) v1(50.65,89.74) v1(78.59,45.8) v1(79.48,45.8) v1(79.48,45.04) v1(80.24,45.8) v1(80.24,45.04) v1(81.13,45.04) v1(91.29,80.6) v1(92.82,81.49) v1(94.98,131.9) v1(95.61,131.9) v1(96.25,131.9) v1(110.48,47.32) v1(110.6,48.21) v1(111.49,48.34) v1(111.49,21.03) v1(111.49,20.14) v1(112.12,6.43) v1(112.12,5.54) v1(112.12,4.52) v1(117.96,46.05) v1(118.73,45.93) v1(119.49,46.05) v1(122.09,60.45) v1(122.41,59.9) v1(126.85,59.51) v1(127.11,58.88) v1(127.49,59.51) v1(139.17,131.65) v1(139.93,131.65) v1(164.32,25.86) v1(164.32,25.22) v1(173.34,122.89) v1(173.34,122.25) v1(174.22,122.89) v1(174.22,122.25) v1(175.88,48.21) v1(177.02,49.23) v1(177.02,48.21) v1(178.29,49.23) v2(102.69,73.24)
SINC2_EMBIT: length 80.2
  TOP w0.127: U45.6 156.57,33.73 155.3,32.46 v1(155.3,30.3) ; R126.2 133.08,69.7 v1(133.23,69.55)
  BOTTOM w0.127: v1(155.3,30.3) 155.17,30.18 140.82,30.18 139.25,31.75 131.38,31.75 130.66,32.46 130.66,33.61 127.62,36.65 126.73,36.65 124.59,38.79 124.59,42.55 125.46,43.42 125.46,46.39 128.78,49.71 130.66,49.71 134.37,53.42 134.37,58.14 134.73,58.5 134.73,59.9 132.7,61.93 131.96,61.93 131.32,62.56 131.32,63.99 130.97,64.34 130.97,65.64 133.46,68.13 133.46,69.32 v1(133.23,69.55)
SINC2_EMCLK: length 81.4
  TOP w0.127: v1(156.19,30.3) 156.19,32.08 156.57,32.46 U45.7 ; R124.2 130.29,69.94 129.74,70.49 v1(129.74,70.66)
  BOTTOM w0.127: v1(156.19,30.3) 155.68,29.8 140.7,29.8 139.05,31.45 130.94,31.45 129.52,32.87 129.52,33.73 128.75,34.51 127.88,34.51 124.29,38.1 124.29,45.65 128.65,50.02 130.54,50.02 134.07,53.55 134.07,58.52 130.16,62.44 130.16,63.45 130.66,63.96 130.66,68.53 130.89,68.76 130.89,70.21 130.44,70.66 v1(129.74,70.66)
SINC2_MOD_CLK: length 1.3
  TOP w0.127: R130.2 v2(131.43,72.46)
SINC_AGND: length 7.7
  TOP w0.305: D28.1 v1(174.75,34.99) ; v1(173.45,30.94) 173.45,30.94 D28.4 ; C400.2 171.94,29.8 v1(172.45,30.3) ; C306.2 v1(171.94,34.75) ; C303.2 C307.2 172.22,31.45 v1(172.23,31.45)
  TOP w0.508: U45.4 v1(167.49,35)
  BOTTOM w0.305: R770.1 v1(164.7,34.75)
SINC_VDDA_5V: length 1.9
  TOP w0.305: v1(173.92,34.99) 174.1,34.82 D28.2 ; D28.5 174.1,31 v1(174.16,30.94)
  vias: v1(169.53,30.18) v1(169.53,29.16)
SPDIF_BUF: length 4.6
  TOP w0.381: U23.4 v1(147.45,19.99)
  BOTTOM w0.381: 146.66,20.22 R381.2 ; R381.2 146.66,21.09 ; R381.2 147.07,20.65 ; 147.74,20.02 R379.1 ; R379.1 148.37,20.96 ; R379.1 148.37,19.08
SPDIF_COAX_OUT: length 8.9
  TOP w0.381: T2.1 151.3,14.49 ; T2.1 150.48,13.72 ; T2.1 150.48,15.27 ; T2.1 149.65,14.49 ; J27.2 152.25,12.72 ; J27.2 153.25,10.89 ; J27.2 151.24,10.89 ; J27.2 152.25,9.07
SPDIF_EXT_CLK: length 1.1
  TOP w0.127: TP18.1 124.05,69.03 R112.2
SPDIF_GND_PRI: length 6.6
  TOP w0.381: 155.56,19.18 T2.4 ; T2.4 156.38,19.95 ; T2.4 154.73,19.95 ; T2.4 155.56,20.73
  BOTTOM w0.381: R380.2 154.67,22.55 ; R380.2 155.29,21.8 ; R380.2 154.67,21.05 ; R382.1 156.37,23.07 ; R382.1 155.5,23.07 ; R382.1 155.94,22.67
  vias: v1(156.44,22.18) v1(156.44,21.41)
SPDIF_IN: length 56.2
  TOP w0.127: v1(140.32,39.7) 139.6,38.98 139.6,29.29 J25.1 ; R113.2 136.38,62.69 v1(136.51,62.82)
  L3_INT_1 w0.127: v1(136.51,62.82) 136.51,59.57 133.97,57.03 133.97,54.94 129.65,50.62 129.65,41.23 132.7,38.18 137.52,38.18 138.41,39.07 139.68,39.07 v1(140.32,39.7)
SPDIF_LOCK: length 1.1
  TOP w0.127: TP16.1 142.34,59.89 R109.2
SPDIF_OUT: length 65.2
  TOP w0.127: J26.2 147.94,17.22 147.94,22.43 146.79,23.57 144.13,23.57 140.32,27.38 v1(140.32,37.04) ; R116.2 v1(131.81,62.82)
  L3_INT_1 w0.127: v1(140.32,37.04) 132.19,37.04 128.5,40.72 128.5,54.82 129.27,55.58 129.27,57.48 131.6,59.82 131.6,62.61 v1(131.81,62.82)
SPDIF_OUT_PRI: length 6.6
  TOP w0.381: 149.65,19.95 T2.6 ; T2.6 150.48,19.18 ; T2.6 150.48,20.73 ; T2.6 151.3,19.95
  BOTTOM w0.381: 152.52,21.8 R380.1 ; R380.1 153.14,21.05 ; R380.1 153.14,22.55 ; C169.2 151.51,21.67 ; C169.2 151.1,21.24 ; C169.2 151.1,22.1
  vias: v1(151.75,22.3) v1(151.75,21.16)
SPDIF_SR_CLK: length 1
  TOP w0.127: R110.2 TP17.1
SPDIF_VCC: length 29.2
  TOP w0.254: C167.1 131.18,21.17 131.19,21.16 U22.5
  TOP w0.381: v1(143.36,22.04) C168.1 143.88,21.41 143.97,21.31 U23.1 U23.5 ; J23.1 127.37,21.17 C167.1
  BOTTOM w0.381: J23.1 127.36,23.07 129.65,25.35 141.33,25.35 143.36,23.32 v1(143.36,22.04)
SPI_FRM_1V8: length 3.1
  TOP w0.127: R2169.2 166,127.74 J36.64
SPI_RXD_1V8: length 66.6
  TOP w0.127: J36.40 166.85,121.74 v1(166.86,121.74) 166.99,121.87 R2166.2 ; v1(167.62,105.23) 167.24,104.85 U43.14
  L3_INT_1 w0.127: v1(166.86,121.74) 166.48,121.36 163.56,121.36 162.79,120.6 153.52,120.6 153.14,120.98 152,120.98 151.62,120.6 140.7,120.6 138.16,118.06 138.16,109.04 J108.2
  BOTTOM w0.127: v1(167.62,105.23) 167.87,105.49 167.87,107.65 170.75,110.52 170.75,116.59 169.91,117.43 169.91,120.25 169.4,120.75 167.85,120.75 v1(166.86,121.74)
SPI_TXD_1V8: length 44.5
  TOP w0.127: R2635.2 167.25,121.24 J36.38 164.19,121.24 163.56,120.6 v1(163.56,120.47)
  L3_INT_1 w0.127: J108.1 138.47,106.82 138.47,117.87 140.82,120.22 151.67,120.22 152.05,120.6 152.89,120.6 153.4,120.09 163.18,120.09 v1(163.56,120.47)
SPK_LN: length 6.5
  TOP w0.081: 86.72,116.28 86.72,116.79 86.85,116.92 86.85,117.35 87.45,117.95 88.01,117.95 U369.B3
  TOP w0.254: R2142.1 86.21,115.77 86.72,116.28
SPK_LP: length 6
  TOP w0.081: U369.A1 87.76,116.31 87.61,116.16 87.61,115.52 87.53,115.44
  TOP w0.254: R2144.1 86.75,112.38 86.75,114.66 87.53,115.44
SPK_RN: length 12.7
  TOP w0.081: U369.C3 88.51,117.95 88.51,117.59 88.36,117.45 88.16,117.45 88.01,117.3 88.01,116.18 87.89,116.06 87.89,115.17 87.67,114.95
  TOP w0.254: 87.67,114.95 87.2,114.48 87.2,107.63 R2141.1
SPK_RP: length 13.7
  TOP w0.081: v1(87.1,115.78) 87.1,116.01 87.48,116.39 87.48,117.32 87.61,117.45 87.88,117.45 88.13,117.7 U369.B2
  TOP w0.254: R2143.1 87.74,107.15 v1(87.74,114)
  BOTTOM w0.254: v1(87.1,115.78) 87.1,114.63 v1(87.74,114)
TRG_FC0_RXD: length 9
  TOP w0.127: U55.E12 28.88,113.66 29.98,114.76 31.1,114.76 31.35,114.51 31.86,114.51 32.59,113.77 36.21,113.77 R847.2
TRG_FC0_TXD: length 6.5
  TOP w0.127: U55.A11 31.31,113.39 36.28,113.39 R846.2
TRG_FC1_RXD: length 13.3
  TOP w0.127: U55.J7 26.1,116.16 v4(26.08,116.14) ; R1075.2 36.3,115.9 v1(35.6,116.6)
  BOTTOM w0.127: v4(26.08,116.14) 27.7,117.76 29.52,117.76 29.58,117.81 29.99,118.22 32.22,118.22 32.57,118.57 34.02,118.57 35.6,116.98 v1(35.6,116.6)
TRG_FC1_TXD: length 11.5
  TOP w0.127: R1074.2 36.34,115.01 v1(35.81,115.54)
  BOTTOM w0.127: v1(35.81,115.54) 35.03,116.32 35.03,116.92 33.76,118.19 32.62,118.19 32.35,117.92 30.11,117.92 29.79,117.59 29.66,117.47 29.59,117.4 27.95,117.4 27.54,116.99 v3(27.54,116.66)
TRG_RST: length 70.2
  TOP w0.127: R2100.2 30.97,38.82 C567.1 31.73,39.7 v1(31.86,39.83) 31.87,39.81 U361.5 ; U60.8 40.28,96.89 v1(40.24,96.85)
  L3_INT_1 w0.127: v1(30.46,76.91) 29.48,75.94 29.48,46.78 32.62,43.64 32.62,40.59 v1(31.86,39.83)
  BOTTOM w0.127: v1(40.24,96.85) 40.24,96.6 38.59,94.95 38.59,89.49 38.33,89.23 38.33,82.63 38.59,82.38 38.59,80.72 36.18,78.31 31.86,78.31 v1(30.46,76.91)
TXD233: length 4.6
  TOP w0.127: U72.30 54.58,123.92 55.73,122.76 55.73,122 55.3,121.56 U73.2
TXLED: length 4.8
  TOP w0.127: U72.22 50.97,126.2 49.38,124.62 49.38,123.78 49.18,123.57 D37.4
U_GPIO_0: length 1.1
  TOP w0.127: R822.1 TP61.1
U_GPIO_1: length 2.9
  TOP w0.127: U55.C1 29.54,119.68 TP53.1
U_GPIO_2: length 8.4
  TOP w0.127: v1(28.3,122.38) 28.3,123.01 TP54.1 ; U55.H6 v4(27.04,116.18)
  L3_INT_1 w0.127: v4(27.04,116.18) 27.04,117.18 27.54,117.68 27.54,119.33 28.3,120.09 v1(28.3,122.38)
U_GPIO_3: length 9.9
  TOP w0.127: TP55.1 24.49,122.63 v1(24.49,120.98) ; U55.M7 25.04,116.12 v4(25.63,115.52)
  L3_INT_1 w0.127: v1(24.49,120.98) 24.57,120.9 24.57,120.07 24.53,120.03 24.53,119.65 24.57,119.61 24.57,116.08 25.13,115.52 v4(25.63,115.52)
U_GPIO_4: length 3.9
  TOP w0.127: U55.C2 29.15,119.04 29.15,120.06 29.57,120.47 TP56.1 R852.1
U_GPIO_5: length 5.4
  TOP w0.127: U55.J5 26.14,117.55 26.14,120.09 25.25,120.98 TP62.1
USB_OTG1_ID: length 67.6
  TOP w0.127: R632.2 188.7,63.71 186.54,63.71 185.15,62.31 v1(185.15,59.51) ; R107.2 137.64,55.2 145.65,55.2 149.59,51.26 v1(149.59,49.48) ; v1(180.19,51.89) R629.2 180.95,52.66 181.32,52.29 Q11.2
  BOTTOM w0.127: v1(149.59,49.48) 150.95,48.12 161.94,48.12 162.92,49.1 173.34,49.1 176.13,51.89 v1(180.19,51.89) 184.77,56.47 184.77,59.13 v1(185.15,59.51)
USB_OTG1_OC: length 6
  TOP w0.127: R625.1 180.57,59.01 179.05,57.48 R1053.2
USB_OTG1_PWR: length 48.3
  TOP w0.127: R630.1 v1(180.57,56.34) ; R108.2 144.5,57.11 150.35,51.26 v1(150.35,49.48)
  BOTTOM w0.127: v1(180.57,56.34) 179.3,56.34 172.45,49.48 162.71,49.48 161.65,48.42 151.41,48.42 v1(150.35,49.48)
USB_OTG2_ID: length 75.1
  TOP w0.127: Q12.2 184.24,68.67 183.87,69.05 R640.2 183.11,69.04 v1(181.46,69.04) ; R106.2 v1(144.51,51.89) ; R643.2 187.95,82.37 v1(187.31,83.01)
  BOTTOM w0.127: v1(144.51,51.89) 145.27,51.13 149.43,51.13 151.84,48.73 161.15,48.73 162.54,50.12 171.43,50.12 181.46,60.15 v1(181.46,69.04) 181.46,77.55 186.92,83.01 v1(187.31,83.01)
USB_OTG2_OC: length 49.5
  TOP w0.127: v1(178.54,75.64) 178.8,75.39 R636.1 ; R104.2 143.48,62.7 v1(144.51,61.67)
  BOTTOM w0.127: v1(144.51,61.67) 146.03,60.15 163.05,60.15 v1(178.54,75.64)
USB_OTG2_PWR: length 65.7
  TOP w0.127: R641.1 v1(183.37,72.72) ; R105.2 147.25,46.36 v1(146.41,47.2)
  BOTTOM w0.127: v1(146.41,47.2) 147.03,47.81 162.27,47.81 163.18,48.72 173.97,48.72 176.38,51.13 181.21,51.13 186.54,56.47 186.54,58.88 181.97,63.45 181.97,71.83 182.86,72.72 v1(183.37,72.72)
USB_SUSPEND_B: length 17.7
  TOP w0.127: U73.7 56.9,121.56 v1(56.88,121.54) 56.88,123.01 58.02,124.16 58.02,128.98 57,130 55.73,130 55.58,129.85 U72.9 ; U73.1 v1(53.23,122.21)
  BOTTOM w0.127: v1(53.23,122.21) 55.65,122.21 56.32,121.54 v1(56.88,121.54)
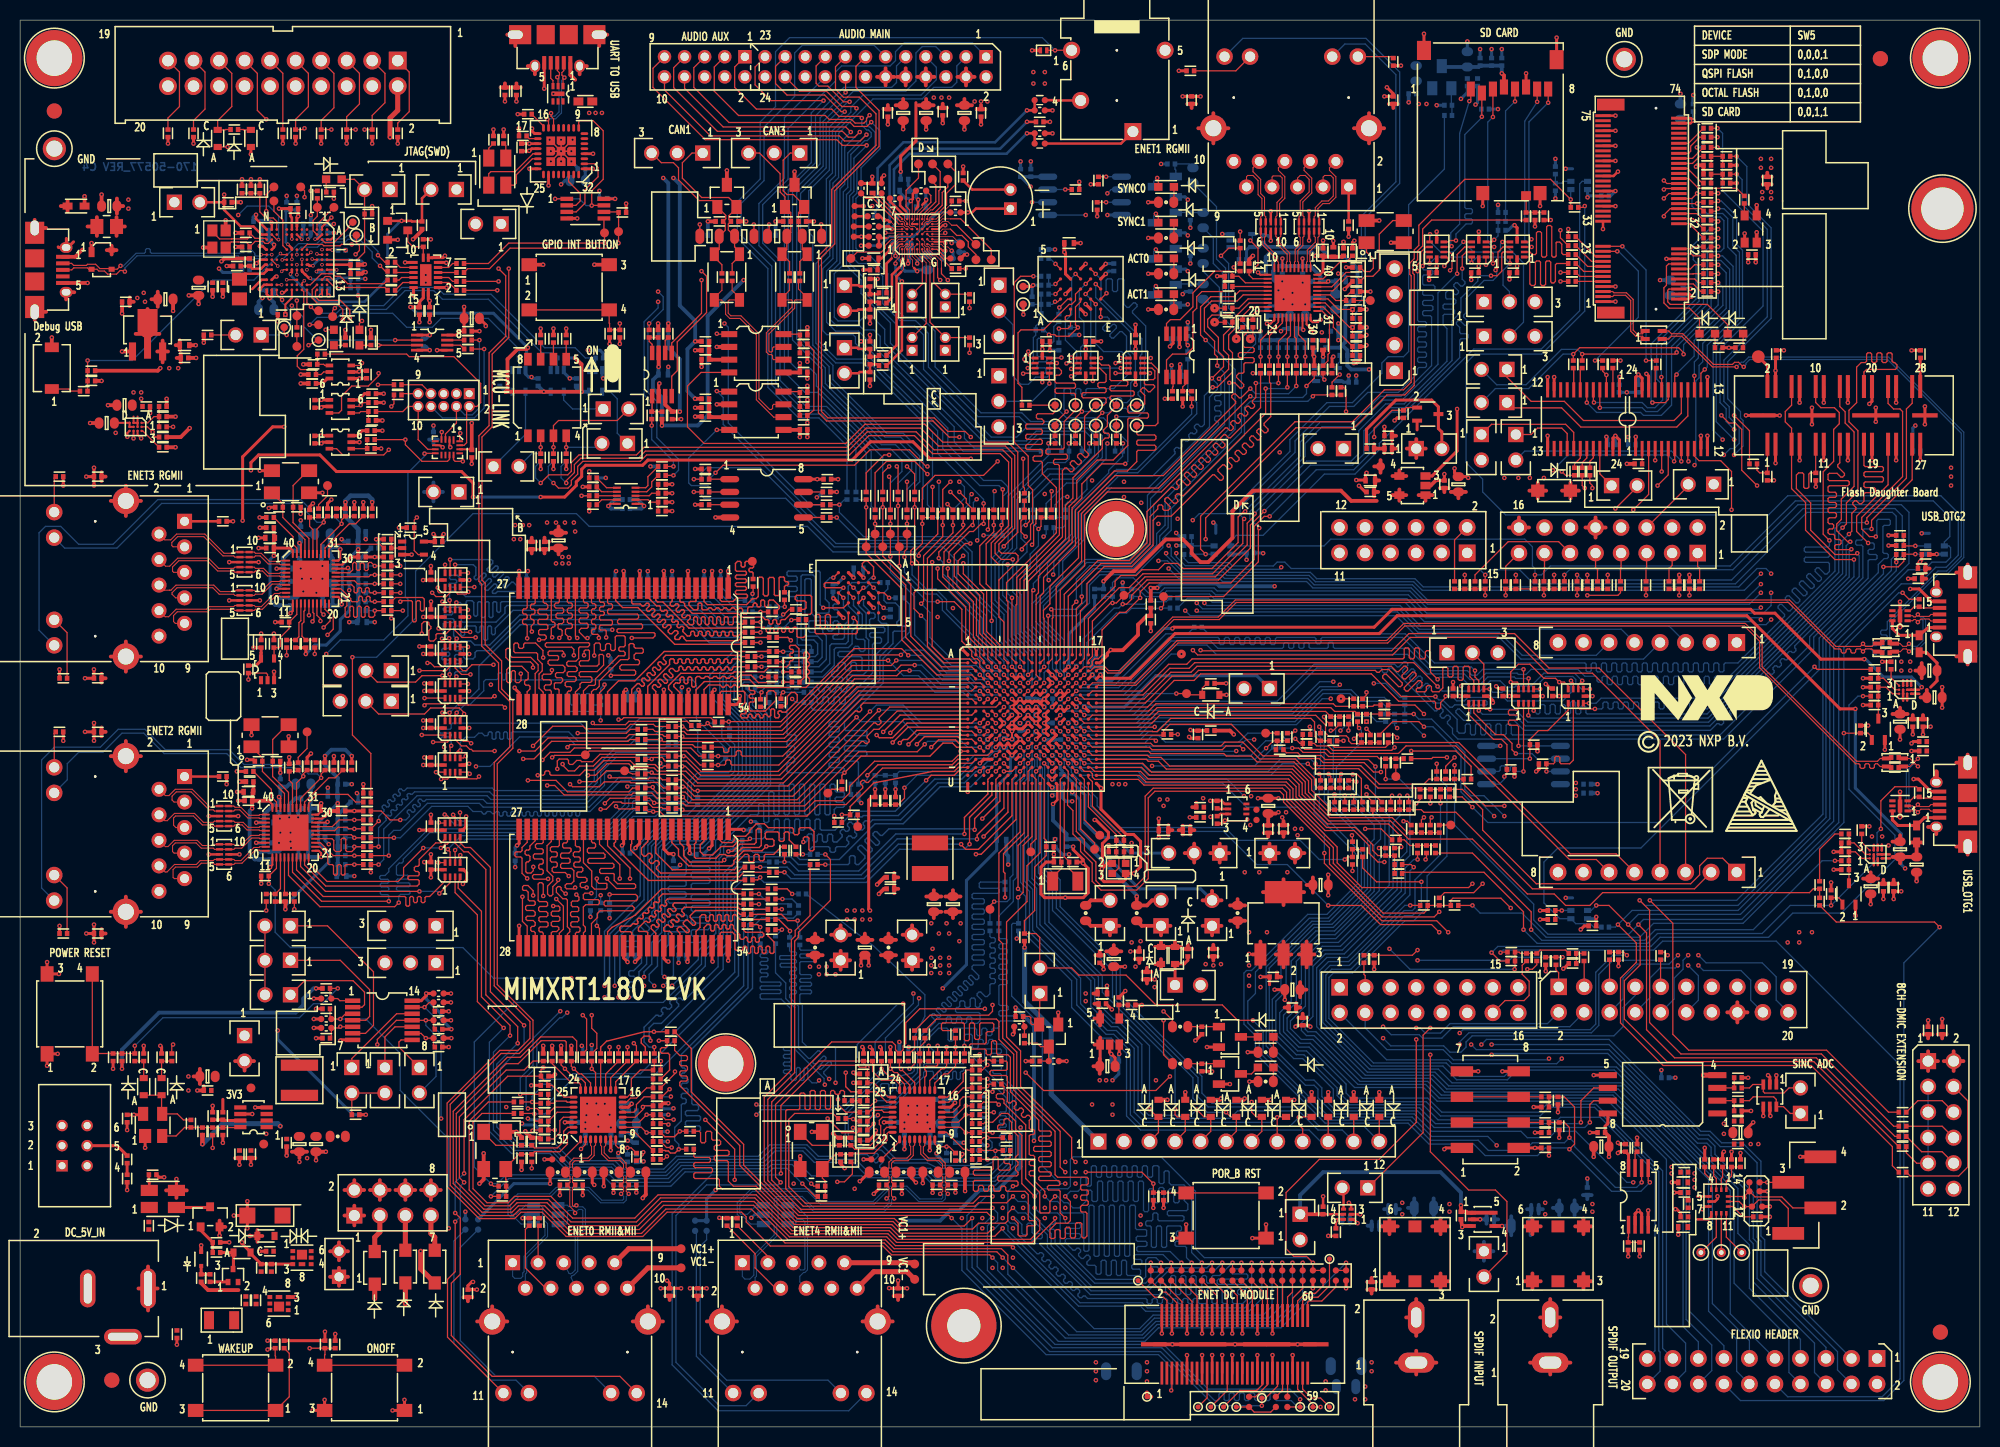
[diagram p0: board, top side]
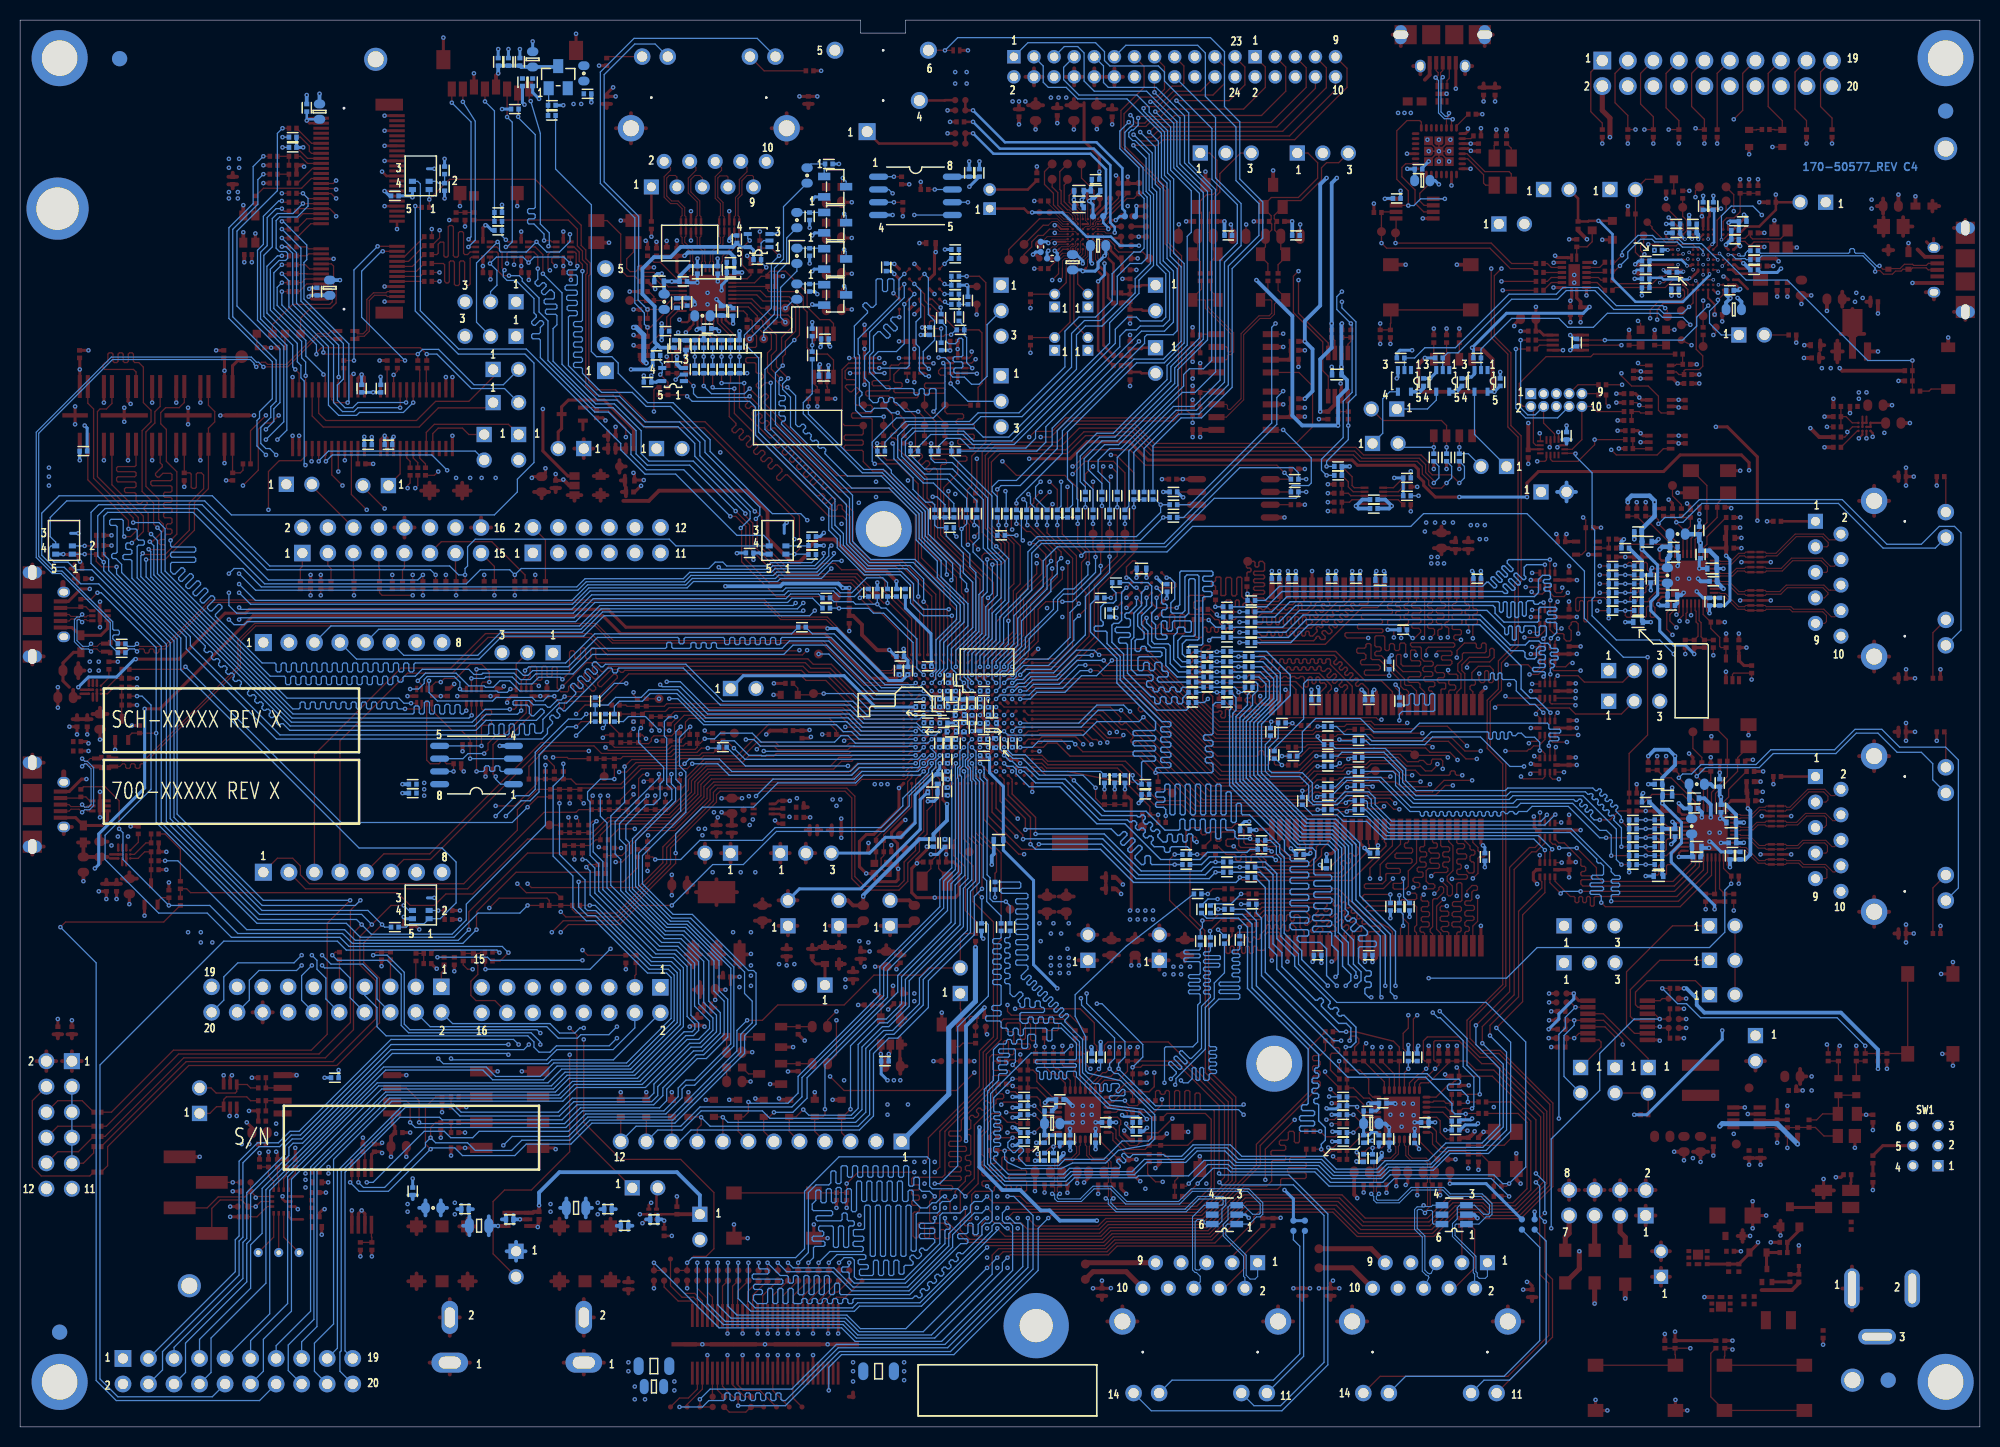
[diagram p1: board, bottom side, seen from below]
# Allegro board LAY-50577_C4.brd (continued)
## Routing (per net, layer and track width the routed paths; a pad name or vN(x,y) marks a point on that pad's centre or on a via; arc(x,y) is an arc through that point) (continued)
USER_LED_CTL1: length 51.5
  TOP w0.127: v1(113.77,40.46) 113.77,37.04 R35.2 ; v1(121.7,67.44) 121.36,67.77 120,67.77 119.61,67.39 112.63,67.39 112.38,67.64 106.69,67.64 U6.M16
  L3_INT_1 w0.127: v1(113.77,40.46) 116.44,43.13 116.44,52.78 118.09,54.43 119.08,54.43 120.68,56.04 120.68,63.38 121.7,64.39 v1(121.7,67.44)
USER_LED_CTL2: length 48
  TOP w0.127: R36.2 114.66,40.46 v1(113.77,41.35) ; U6.M14 v1(105.09,67.64)
  L3_INT_1 w0.127: v1(121.01,67.26) 121.01,64.13 120.38,63.5 120.38,56.21 118.98,54.82 117.96,54.82 116.06,52.91 116.06,43.64 v1(113.77,41.35)
  BOTTOM w0.127: v1(121.01,67.26) 120.98,67.23 105.49,67.23 v1(105.09,67.64)
V_TGTMCU: length 101
  TOP w0.203: C395.1 44.88,97.29 U60.14
  TOP w0.279: U58.8 43.4,108.65 43.8,109.04 C393.1
  TOP w0.305: v1(26.27,99.52) 25.13,99.52 22.14,96.54 v1(22.14,90.19) ; U61.15 v1(39.15,112.6) ; U61.1 40.62,112.2 v1(40.75,112.07) C397.1 ; R901.1 v1(35.92,97.36) ; R838.1 v1(22.08,124.16) ; U59.6 30.57,104.33 v1(30.08,103.84) C387.1 ; U61.7 42.29,115.88 42.32,115.85 v1(42.41,115.85) ; U56.6 33.52,98.65 v1(33.76,98.88) 34.02,99.14 C389.1 ; R2099.1 v1(29.44,41.61) ; U57.6 33.65,102.2 v1(33.89,102.44) 34.27,102.82 C391.1 ; R849.1 v1(40.87,118.18) ; v1(44.18,111.46) C394.1 44.18,109.05 C393.1 ; R2100.1 v1(29.44,38.69)
  TOP w0.381: R903.1 v1(28.17,105.74) ; v1(44.94,99.9) C395.1 ; R902.1 v1(36.05,100.15)
  L3_INT_1 w0.305: v1(29.44,41.61) 30.08,40.97 30.08,39.32 v1(29.44,38.69) 25.25,38.69 20.81,43.13 20.81,60.91 21.44,61.55 21.95,61.55 22.59,62.18 22.59,65.23 20.94,66.88 20.94,80.72 22.14,81.93 v1(22.14,90.19)
  L4_PWR_1 w0.381: 44.68,103.55 J56.1 45.41,102.82 ; 45.32,118.77 JP6.2 ; JP6.2 45.32,120.65 ; JP6.2 44.38,119.71
  BOTTOM w0.305: R842.2 v1(41.13,99.65)
VLDO_3V3: length 5.8
  TOP w0.305: R21.1 v1(109.96,43.38)
  TOP w0.381: 107.46,39.96 U3.5 ; U3.5 107.46,41.33 ; U3.5 106.9,40.65 ; R40.1 112.55,44.54 ; R40.1 111.69,44.54 ; R40.1 112.12,44.13 ; 107.2,43.62 C19.1 106.8,43.13 ; 106.9,42.12 C20.1 107.3,41.68
  vias: v1(106.03,43.13) v1(106.03,42.37) v1(112.88,44.54) v1(112.88,43.77)
VREF: length 23.8
  TOP w0.203: U55.H13 27.04,112.36 26.39,111.71 v2(26.39,110.7) ; U55.G1 27.54,119.46
  TOP w0.305: C351.1 27.66,120.48 v1(27.67,120.47) 27.54,120.35 27.54,119.46
  L3_INT_1 w0.305: v2(26.39,110.7) 24.24,110.7 22.84,112.09 22.84,121.11 23.73,122 26.14,122 v1(27.67,120.47)
VSD_3V3: length 8.3
  TOP w0.381: J15.4 147.64,134.48 v1(147.43,134.7)
  BOTTOM w0.381: v1(147.43,134.7) C30.1 C93.1 C94.1 145.14,135.33 C92.1 141.54,135.33 Q6.3
VTRG_FAULT_B: length 37.7
  TOP w0.127: R852.2 v1(28.91,123.01) ; U52.A2 12.68,99.52 v1(13.19,99.01) 13.19,98.76 13.44,98.5 R814.2
  L3_INT_1 w0.127: v1(28.91,123.01) 23.98,123.01 22.33,121.36 22.33,111.2 19.79,108.66 19.79,103.33 15.47,99.01 v1(13.19,99.01)
WAKE_IN_OUT: length 2.4
  TOP w0.127: R284.2 126.11,3.02 J134.51
WAKEUP: length 148.7
  TOP w0.127: v1(24.62,7.7) 24.75,7.83 C33.1 25.38,7.06 25.42,7.03 SW4.2 SW4.4 ; U6.T8 99.49,64.44 99.49,59.2 97.39,57.1 97.39,48.47 97.77,48.08 97.77,38.69 99.17,37.29 99.17,33.73 103.49,29.42 103.49,25.86 v1(103.99,25.35)
  L3_INT_1 w0.127: v1(24.62,7.7) 26.91,7.7 34.78,15.57 39.22,15.57 41.64,17.99 41.64,20.02 42.27,20.65 42.27,21.54 43.03,22.3 51.54,22.3 53.83,20.02 91.3,20.02 92.67,18.65 102.62,18.65 104.5,20.53 104.5,24.84 v1(103.99,25.35)
WALL_OV_BASE: length 1.8
  TOP w0.305: Q3.1 20.67,14.44 R5.2
WALL_OV_CTL: length 1.7
  TOP w0.305: R5.1 R3.2 D1.C
WALL_OVP_LED: length 3
  TOP w0.305: R10.1 21.22,17.35 D2.A 21.23,15.75 Q3.3
WIFI_LED1_B: length 10.1
  TOP w0.127: J36.6 164.07,113.24 163.94,113.11 163.94,111.97 164.19,111.71 167.87,111.71 169.89,109.69 D23.C
WIFI_RST_B: length 63.4
  TOP w0.127: U43.3 162.04,92.8 v1(160.51,91.26) ; R135.2 150.91,45.98 150.48,45.54 v1(149.97,45.54)
  L3_INT_1 w0.127: v1(149.97,45.54) 149.97,46.31 146.03,50.24 146.03,62.05 145.14,62.94 145.14,67.21 150.73,72.8 150.73,73.59 151.49,74.35 151.49,78.82 154.29,81.61 156.06,81.61 160.51,86.06 v1(160.51,91.26)
WIFI_RST_B_1V8: length 2.2
  TOP w0.127: U43.21 162.69,105.26 R676.1
WIFI_SDIO_CLK: length 17.6
  TOP w0.127: U63.2 146.41,116.92 146.55,116.78 v1(146.55,115.78) ; R668.1 v1(153.27,114)
  L3_INT_1 w0.127: v1(153.27,114) 152.51,114.76 152.51,116.03 152.13,116.41 151.49,116.41 151.36,116.28 151.36,114.89 151.24,114.76 150.98,114.76 150.85,114.89 150.85,116.28 150.73,116.41 150.47,116.41 150.35,116.28 150.35,114.89 150.22,114.76 149.97,114.76 149.84,114.89 149.84,116.28 149.71,116.41 146.68,116.41 146.55,116.28 v1(146.55,115.78)
WIFI_SDIO_CMD: length 17.1
  TOP w0.127: R670.1 v1(153.27,114.89) ; v1(145.85,115.65) 145.85,115.66 U63.1
  L3_INT_1 w0.127: v1(145.85,115.65) 145.85,116.49 146.16,116.79 147.41,116.79 147.53,116.92 147.53,117.3 147.66,117.43 147.92,117.43 148.04,117.3 148.04,116.92 148.17,116.79 148.42,116.79 148.55,116.92 148.55,118.19 148.68,118.32 148.93,118.32 149.06,118.19 149.06,116.92 149.19,116.79 151.06,116.79 151.18,116.92 151.18,117.68 151.31,117.81 151.56,117.81 151.69,117.68 151.69,116.92 151.82,116.79 152.89,116.79 153.27,116.41 v1(153.27,114.89)
WIFI_SDIO_D0: length 17.7
  TOP w0.127: U64.1 149.67,116.41 150.09,116.41 150.22,116.28 150.22,113.74 150.38,113.58 150.65,113.58 150.77,113.71 150.77,115.9 150.9,116.03 151.15,116.03 151.28,115.9 151.28,113.71 151.41,113.58 151.66,113.58 151.79,113.71 151.79,115.9 151.92,116.03 152.17,116.03 152.3,115.9 152.3,113.97 152.42,113.84 152.6,113.84 152.76,114 152.76,115.65 152.89,115.78 R671.1
WIFI_SDIO_D1: length 17.4
  TOP w0.127: R672.1 153.54,116.66 153.4,116.81 153.4,117.7 153.2,117.9 152.9,117.9 152.83,117.84 152.83,116.54 152.71,116.41 152.53,116.41 152.4,116.54 152.4,119.43 152.27,119.56 152.02,119.56 151.89,119.43 151.89,116.57 151.74,116.41 151.51,116.41 151.38,116.54 151.38,118.82 151.26,118.95 151,118.95 150.88,118.82 150.88,116.79 150.75,116.66 150.48,116.66 150.22,116.92 U64.2
WIFI_SDIO_D2: length 16.9
  TOP w0.127: U65.1 141.96,116.42 142.09,116.28 142.09,115.9 v1(141.71,115.52) ; v1(153.26,119.09) 153.26,118.33 R673.1
  L3_INT_1 w0.127: v1(153.26,119.09) 153.16,118.99 152.27,118.99 152.15,119.12 152.15,119.33 152.02,119.46 151.76,119.46 151.64,119.33 151.64,119.12 151.51,118.99 146.2,118.99 144.13,116.92 143.11,116.92 v1(141.71,115.52)
WIFI_SDIO_D3: length 17
  TOP w0.127: v1(142.28,115.1) 142.47,115.29 142.47,116.66 142.22,116.92 U65.2 ; R674.1 v1(154.04,119.2)
  L3_INT_1 w0.127: v1(142.28,115.1) 143.6,116.41 144.13,116.41 146.4,118.68 151.38,118.68 151.62,118.44 153.28,118.44 v1(154.04,119.2)
WIFI_WAKE_B_1V8: length 2.3
  TOP w0.127: R675.1 157.46,105.07 v1(157.84,104.69) U44.3
WIFI_WAKE_B_3V3: length 69.8
  TOP w0.127: R136.2 135.42,59.51 v1(133.84,59.51) ; v1(158.73,91.39) 160.89,93.55 J105.2
  L3_INT_1 w0.127: v1(158.73,91.39) 158.3,90.96 130.96,90.96 130.2,90.2 130.2,86.11 135.87,80.44 135.87,72.93 135.58,72.63 135.58,68.1 134.09,66.61 134.09,64.98 134.75,64.32 134.75,60.43 v1(133.84,59.51)
WL_3V3: length 159.9
  TOP w0.254: J36.2 165.98,112.24 166.21,112.47 v1(166.29,112.47) 166.29,112.54 166.09,112.74 J36.4 ; J36.72 166.22,129.74 v1(166.48,130) 166.24,130.24 J36.74
  TOP w0.305: v1(160.76,98.53) 160.76,98.5 160.74,98.49 U43.1 ; U44.24 159.14,98.22 v1(158.72,98.63) 158.49,98.39 U44.23 ; R662.1 v1(170.8,125.55) ; R667.2 v1(170.03,107.39) R666.2 ; R665.1 v1(170.8,123.78)
  TOP w0.381: R1323.1 v1(63.86,99.65) ; R705.1 v1(159.87,95.84) ; R1324.1 v1(63.48,109.81) ; L33.2 174.28,124.41 ; L33.2 173.84,124.81 ; L33.2 173.41,124.41 ; U126.7 v1(63.54,105.49)
  L3_INT_1 w0.381: v1(166.48,130) 163.18,126.7 158.22,126.7 155.81,124.28 138.28,124.28 133.58,119.59 121.01,119.59 115.55,125.05 95.36,125.05 93.83,123.52 87.48,123.52 86.72,122.76 83.42,122.76 80.88,120.22 80.88,119.33 80.24,118.7 76.56,118.7 v1(71.99,114.12)
  BOTTOM w0.254: C285.1 166.15,112.61 v1(166.29,112.47) ; C283.1 166.35,130.13 v1(166.48,130) C284.1
  BOTTOM w0.305: C292.1 v1(158.72,98.63) ; C289.1 v1(160.76,98.53)
  BOTTOM w0.381: v1(63.48,109.81) 63.54,109.75 v1(63.54,105.49) 63.51,105.47 C525.1 62.97,104.19 62.97,103.33 63.86,102.44 63.86,99.66 ; v1(63.86,99.65) 63.86,99.66 ; 63.86,99.66 67.43,99.66 68.41,100.64 68.41,110.54 v1(71.99,114.12) ; C287.1 C285.1
  vias: v1(173.21,126.19) v1(173.21,125.3) v1(174.22,126.19) v1(174.22,125.3)
WL_DEV_WAKE: length 91.4
  TOP w0.127: v1(170.29,91.26) 170.29,95.07 169.21,96.15 167.05,96.15 166.59,96.61 U43.10 ; R103.2 132.57,58.82 v1(132.52,58.87)
  L3_INT_1 w0.127: v1(132.52,58.87) 132.52,59.21 134.45,61.14 134.45,63.99 133.71,64.72 133.71,66.67 135.24,68.19 135.24,72.72 135.49,72.98 135.49,80.09 129.9,85.68 129.9,90.35 130.82,91.26 157.94,91.26 158.57,91.9 165.97,91.9 167.24,93.17 167.24,94.19 168,94.95 169.65,94.95 170.29,94.31 v1(170.29,91.26)
WL_RST#: length 108.4
  TOP w0.127: R118.2 132.83,64.33 v1(132.95,64.21) ; R664.1 v1(170.8,126.44)
  L3_INT_1 w0.127: v1(132.95,64.21) 133.08,64.34 133.08,66.5 134.85,68.28 134.85,72.93 135.16,73.23 135.16,79.78 129.59,85.35 129.59,90.47 130.69,91.57 157.64,91.57 158.35,92.28 162.54,92.28 165.08,94.82 167.11,94.82 167.62,95.33 169.14,95.33 v1(170.54,96.73)
  BOTTOM w0.127: v1(170.54,96.73) 171.43,97.61 171.43,100.15 171.18,100.41 171.18,101.04 169.91,102.31 169.91,106 174.22,110.31 174.22,119.33 171.81,121.74 171.81,125.43 v1(170.8,126.44)
XTAL32M_N: length 5.6
  TOP w0.127: Y4.3 21.01,117.92 21.7,117.92 22.47,117.92 22.83,117.56 C323.1 23.39,117.98 24.18,117.98 24.38,117.78 24.7,117.78 25.04,118.12 U55.M3
XTAL32M_P: length 6.6
  TOP w0.127: Y4.1 19.13,118.98 19.16,118.95 19.16,118.91 19.85,118.23 21.06,118.23 21.06,118.23 22.63,118.23 22.83,118.44 C324.1 23.37,118.28 24.41,118.28 U55.N3
N99833017: length 6.1
  TOP w0.305: J33.1 189.48,60.63 L15.1 186.84,59.85 186.29,60.4 U38.6
N99833038: length 12.4
  TOP w0.107: R623.1 187.03,66.52 L16.1 188.03,66.52 188.3,66.25 188.58,66.25 v1(188.83,66.5) ; J33.2 190.13,61.28 189.93,61.47 189.14,61.47 v1(188.83,61.17) 188.83,61.17 188.58,61.42 188.43,61.42 188.31,61.3 U38.1
  BOTTOM w0.107: v1(188.83,66.5) 188.58,66.25 188.32,66.25 187.68,65.61 187.68,61.82 188.08,61.42 188.58,61.42 v1(188.83,61.17)
N99833048: length 11.5
  TOP w0.107: R628.1 187.03,65.72 L16.4 188.03,65.72 188.3,65.99 188.58,65.99 v1(188.83,65.74) ; U38.2 188.31,61.8 188.43,61.68 188.58,61.68 v1(188.83,61.93) 189.03,61.73 189.93,61.73 190.13,61.93 J33.3
  BOTTOM w0.107: v1(188.83,65.74) 188.58,65.99 188.43,65.99 187.94,65.5 187.94,61.93 188.19,61.68 188.58,61.68 v1(188.83,61.93)
N99833086: length 3.4
  TOP w0.127: U38.3 188.06,62.3 188.46,62.7 R632.1 189.08,62.58 J33.4
N99838171: length 1.3
  TOP w0.127: R714.1 22.21,129.11 22.25,129.07 D25.C
N100054135: length 3
  TOP w0.305: R10.2 R11.1 17.96,19.57 Q4.1
N100054243: length 7.5
  TOP w0.381: JP1.2 32.62,17.48 ; JP1.2 31.73,18.37 ; JP1.2 30.84,17.48 ; JP1.2 31.73,16.59 ; J1.1 34.23,21.03 ; J1.1 33.25,20.06 ; J1.1 33.25,22.01 ; J1.1 32.28,21.03
N100054253: length 20.5
  TOP w0.305: R8.1 v1(10.65,23.57) ; Q2.3 27.13,16.2 C4.2 R4.2 22.93,17.26 D2.C 22.93,17.39 22.08,18.24 v1(22.08,18.37)
  L3_INT_1 w0.305: v1(22.08,18.37) 16.87,23.57 v1(10.65,23.57)
N100054255: length 1.2
  TOP w0.305: R9.1 R8.2
N100054257: length 4.4
  TOP w0.305: SW1.5 9.66,27.99 R9.2
N100054299: length 7.7
  TOP w0.381: 31.73,14.05 JP1.1 ; JP1.1 31.73,15.83 ; JP1.1 32.62,14.94 ; JP1.1 30.84,14.94 ; R3.1 18.01,14.3 18.7,13.62 21.72,13.62
N100054525: length 1.6
  TOP w0.254: D3.3 12.85,24.29 12.81,24.33 R7.2
N100054568: length 3.4
  TOP w0.305: Q4.3 18.83,21.84 D3.2
N100068040: length 2.7
  TOP w0.127: D5.C R19.1 C15.2
N100068056: length 8.2
  TOP w0.127: U2.2 15.52,28.95 16.37,29.8 R17.2 18.13,29.8 R13.2 R15.1 C10.1 21.87,29.79 U1.8
N100068060: length 2.6
  TOP w0.127: D4.C C13.1 R18.2
N100068072: length 9.6
  TOP w0.457: R13.1 v1(18.14,28.15)
  BOTTOM w0.508: v1(18.14,28.15) 20.17,30.18 25.63,30.18 v1(25.89,29.92)
N100068102: length 2.8
  TOP w0.305: R16.1 R14.2 20.25,30.49 U1.7
N100068132: length 6.8
  TOP w0.127: D4.A D5.A 14.08,31.21 U2.3 15.64,31.15 16.24,30.55 R17.1
N100168474: length 6.4
  TOP w0.254: U37.C1 184.84,55.9 ; U37.B2 U37.B1 184.44,55.89
  TOP w0.381: R622.2 186.42,54.45 ; R622.2 185.98,54.05 ; R622.2 186.85,54.05 ; C263.1 184.13,55.18 ; C263.1 183.38,54.56 ; C263.1 184.88,54.56 ; C264.1 185.4,54.45 ; C264.1 185.83,54.05 ; C264.1 184.97,54.05
N100169105: length 5.5
  TOP w0.127: U37.A1 183.26,56.57 182.61,57.23 R627.2 R630.2 R631.1 181.97,55.44 Q11.3
N100169932: length 6
  TOP w0.305: J68.1 189.86,79.55 L18.1 186.97,78.78 186.29,79.45 U40.6
N100169943: length 10.1
  TOP w0.107: J68.2 190.13,80.2 189.93,80.4 189.14,80.4 v1(188.83,80.09) 188.83,80.1 188.58,80.34 188.43,80.34 188.31,80.22 U40.1 ; v1(187.94,77.93) 187.69,77.68 187.33,77.68 187.06,77.95 L19.1 186.14,77.95 R634.1
  BOTTOM w0.107: v1(187.94,77.93) 188.19,77.68 188.77,77.68 189.34,78.25 189.34,80.23 189.23,80.34 189.08,80.34 v1(188.83,80.09)
N100169951: length 10.9
  TOP w0.107: R637.1 186.14,77.15 L19.4 187.08,77.15 187.35,77.42 187.69,77.42 v1(187.94,77.17) ; J68.3 190.13,80.85 189.93,80.66 189.03,80.66 v1(188.83,80.85) 188.58,80.6 188.43,80.6 188.31,80.72 U40.2
  BOTTOM w0.107: v1(188.83,80.85) 189.08,80.6 189.34,80.6 189.6,80.34 189.6,78.14 188.88,77.42 188.19,77.42 v1(187.94,77.17)
N100169961: length 3.4
  TOP w0.127: U40.3 188.06,81.22 188.46,81.62 R643.1 189.08,81.5 J68.4
N100171083: length 3.4
  TOP w0.127: U39.A2 186.54,73.36 185.4,74.5 R635.2 R636.2
N100171101: length 6.4
  TOP w0.254: U39.C1 187.76,72.29 ; U39.B2 U39.B1 187.36,72.27
  TOP w0.381: R633.2 189.77,70.43 ; R633.2 188.91,70.43 ; R633.2 189.34,70.84 ; 187.89,70.43 C268.1 ; C268.1 188.32,70.84 ; C268.1 188.75,70.43 ; C267.1 187.05,71.57 ; C267.1 187.8,70.94 ; C267.1 186.3,70.94
N100171150: length 5.5
  TOP w0.127: Q12.3 184.89,71.83 R642.1 R641.2 R639.2 185.65,73.61 186.31,72.96 U39.A1
N100171345: length 2
  TOP w0.127: U39.A3 186.16,74.56 R638.1
N100208849: length 8.8
  TOP w0.381: U4.3 128.79,47.02 ; U4.3 128.01,48.3 ; U4.3 128.01,45.73 ; U4.3 127.24,47.02 ; C22.1 127.38,41.73 ; C22.1 126.97,42.17 ; C22.1 126.97,41.3 ; C21.1 127.36,44.26 ; C21.1 127.36,42.76 ; C21.1 127.98,43.51 ; R22.2 127.62,41.12 ; R22.2 128.05,40.71 ; R22.2 127.18,40.71
N100211328: length 16.6
  TOP w0.381: 126.85,56.16 J4.2 ; J4.2 126.85,58.04 ; J4.2 127.79,57.1 ; 128.63,53.18 C23.1 ; C23.1 128.63,54.68 ; C23.1 128.01,53.93 ; U4.2 126.49,47.02 ; U4.2 125.71,48.3 ; U4.2 124.94,47.02 ; U4.2 125.71,45.73 ; 125.71,51.93 U4.4 ; U4.4 127.76,53.22 ; U4.4 125.71,54.5 ; U4.4 123.67,53.22 ; 125.48,44.78 C24.1 125.07,45.22
N100310756: length 9.2
  TOP w0.305: Q5.1 139,99.22
  TOP w0.381: 138.92,96.42 J5.1 ; J5.1 137.98,97.36 ; J5.1 139.86,97.36 ; J5.1 138.92,98.3 ; U5.4 137.24,95.19 ; U5.4 136.55,94.63 ; U5.4 137.92,94.63 ; R27.1 136.91,98.63 ; R27.1 136.5,99.06 ; R27.1 136.5,98.2 ; R24.2 136.5,97.79 ; R24.2 136.5,96.93 ; R24.2 136.91,97.36
N100526107: length 12.9
  TOP w0.127: U6.G15 v1(105.09,72.44)
  BOTTOM w0.127: v2(115.55,76.91) 114.53,76.91 110.06,72.44 v1(105.09,72.44)
N100526140: length 8.6
  TOP w0.305: U6.C13 v2(104.29,75.64)
  BOTTOM w0.305: C77.1 104.37,78.94 106.91,81.49 R71.2
N100538770: length 9.5
  TOP w0.127: Q5.2 137.92,101.44 R28.1 136.5,101.16 134.73,99.39 v1(134.73,98.5)
  L3_INT_1 w0.127: v1(134.73,98.5) 133.58,97.36 J135.1
N100538772: length 14.8
  TOP w0.305: J5.2 141.46,99.01 141.12,99.35 Q5.3 141.12,101.51 140.44,102.19 136.89,102.19 133.97,99.27 R25.2
N100728650: length 3.4
  TOP w0.127: J15.9 149.85,120.85 R257.1 R256.2 R259.1
N100768470: length 13.6
  TOP w0.127: v1(148.74,131.9) J15.5
  BOTTOM w0.127: R258.2 C96.1 147.8,130.96 v1(148.74,131.9)
N100797217: length 3.9
  TOP w0.127: R647.2 R646.2 R648.1 77.5,103.03 U41.8
N100797464: length 18.2
  TOP w0.107: U41.7 74.98,101.76 74.87,101.65 74.87,101.36 74.77,101.25 74.58,101.25 73.51,102.32 73.51,108.79 71.74,110.57 70.72,110.57 70.46,110.83 70.46,112.04 70.56,112.15 FL1.4 71.58,112.38 70.85,113.11 R649.1
N100797616: length 18.3
  TOP w0.107: U41.6 74.98,100.49 73.25,102.21 73.25,108.68 71.63,110.31 70.61,110.31 70.2,110.73 70.2,111.73 69.77,112.15 FL1.3 69.08,112.35 69.83,113.11 R652.1
N100798376: length 9.1
  TOP w0.127: R651.1 v1(67.63,119.66) ; R650.2 73.02,119.57 73.01,119.59 v1(73.01,119.66)
  L3_INT_1 w0.127: v1(73.01,119.66) 72.68,119.33 67.96,119.33 v1(67.63,119.66)
  BOTTOM w0.127: C274.1 67.63,118.62 v1(67.63,119.66)
N100979684: length 2.3
  TOP w0.127: R23.1 109.33,41.99 R21.2 109.33,40.68 U3.4
N100999218: length 1.4
  TOP w0.203: v1(129.39,110.19) 129.14,109.93 128.6,109.93 128.4,110.14 U27.30
N101003766: length 6.5
  TOP w0.127: R465.1 130.13,106.09 130.13,106.73 130.28,106.89 130.28,110.31 129.54,111.05 U27.31
N101003882: length 4.3
  TOP w0.127: C202.1 132.44,112.98 131.94,112.48 R466.1 130.92,112.09 130.36,112.66 U27.35
N101004896: length 7
  TOP w0.127: v1(122.41,118.06) 123.17,117.3 123.17,115.65 122.54,115.02 R469.2 122.28,114.63 122.66,114.26 U27.12
  BOTTOM w0.127: v1(122.41,118.06) 122.6,118.25 U410.4
N101006850: length 6.2
  TOP w0.127: J29.13 120.97,134.95 R449.1
N101006888: length 3.6
  TOP w0.127: R452.1 136.48,136.37 J29.11
N101007093: length 4.5
  TOP w0.127: U27.39 129.65,114.26 131.3,115.9 131.93,115.9 R467.1
N101069327: length 14.9
  TOP w0.127: SW4.3 SW4.1 26.78,3 26.78,7.32 R37.2
N101094010: length 3.6
  TOP w0.127: U14.38 57.65,73.07 58.15,73.56 v1(58.15,73.87)
  BOTTOM w0.127: v1(58.15,73.87) 57.77,73.48 R327.2
N101094248: length 3.8
  TOP w0.127: v1(57.39,49.87) 57.65,49.6 U16.38
  BOTTOM w0.127: v1(57.39,49.87) 57.39,51.02 R337.2
N101142474: length 3.4
  TOP w0.127: U37.A2 183.62,56.97 182.48,58.12 R624.2 R625.2
N101142476: length 2
  TOP w0.127: R626.1 183.24,58.17 U37.A3
N101209734: length 46.2
  TOP w0.127: v1(114.92,31.61) 114.92,31.07 115.13,30.85 D18.C 115.93,29.42 J8.4 ; U6.P10 v1(101.09,66.84)
  BOTTOM w0.127: v1(114.92,31.61) 114.92,36.02 107.68,43.26 107.68,44.91 102.37,50.22 102.37,54.06 101.33,55.1 101.33,64.72 101.49,64.88 101.49,65.45 101.2,65.74 101.2,66.73 v1(101.09,66.84)
N101209737: length 43.5
  TOP w0.127: v1(112.38,31.61) 113.14,30.85 D19.C 113.26,29.29 J8.3 ; U6.R10 101.09,65.24 v1(101.09,65.24)
  BOTTOM w0.127: v1(112.38,31.61) 112.38,37.92 109.71,40.59 108.82,40.59 107.3,42.12 107.3,44.78 101.96,50.12 101.96,53.93 101,54.89 101,65.14 v1(101.09,65.24)
N101209778: length 9.1
  TOP w0.381: 114.33,47.77 D9.C ; D9.C 115.5,47.77 ; D9.C 114.92,48.25 ; J6.1 111.61,49.86 R41.1 ; J6.1 114.46,49.86 ; J6.1 113.52,48.92 ; D8.C 113.52,48.25 ; D8.C 112.93,47.77 ; D8.C 114.1,47.77 ; R45.2 116.19,47.98 ; R45.2 116.62,47.57 ; R45.2 115.75,47.57
N101209809: length 11.1
  TOP w0.127: U6.T13 103.5,64.44 103.5,56.32 C37.1 103.61,55.57 102.74,54.71 Y1.1
N101209834: length 10.3
  TOP w0.127: Y1.2 105.24,54.69 104.38,55.55 C38.1 104.38,56.26 103.89,56.75 U6.U13
N101209892: length 8
  TOP w0.127: TP8.1 100.56,57.99 101.09,58.52 101.09,64.44 U6.T9
N101210175: length 2.2
  TOP w0.305: v1(116.45,69.36) 116.53,69.29 C45.1 117.74,69.29 118.1,69.29 L3.1 ; U6.J14 v2(105.09,70.04)
N101210568: length 62.4
  TOP w0.127: v1(101.89,66.04) U6.R11 ; D10.C J8.12
  BOTTOM w0.127: v1(101.89,66.04) 101.94,65.99 101.94,55.47 103.1,54.31 103.1,51.64 109.07,45.67 109.07,42.9 117.2,34.77 117.2,32.84 118.21,31.84 127.35,31.84 129.27,29.92 133.71,29.92 J8.12
N101210571: length 63.8
  TOP w0.127: U6.R9 100.29,65.24 100.29,58.86 99.29,57.86 v1(99.29,53.55) ; D12.C J8.10
  BOTTOM w0.127: v1(99.29,53.55) 100.06,52.78 100.06,48.97 104.63,44.4 104.63,41.74 107.68,38.69 108.57,38.69 110.09,37.16 110.09,30.94 111.49,29.54 128.25,29.54 129.39,28.4 J8.10
N101210574: length 66.9
  TOP w0.127: D11.C J8.11 ; U6.N9 v1(100.29,66.84)
  BOTTOM w0.127: J8.11 131.55,29.54 129.14,29.54 127.23,31.45 121.14,31.45 120.4,30.71 112.1,30.71 111.23,31.57 111.23,37.8 109.2,39.83 108.57,39.83 106.53,41.86 106.53,44.4 101.14,49.79 101.14,53.6 100.31,54.43 100.31,64.21 100.44,64.34 100.44,65.59 100.69,65.84 100.69,66.25 100.29,66.65 v1(100.29,66.84)
N101210577: length 63.9
  TOP w0.127: U6.M9 v1(100.29,67.64) ; D13.C 127.27,30.85 v1(127.23,30.81) 127.23,30.05 127.62,29.67 J8.9
  BOTTOM w0.127: v1(127.23,30.81) 126.35,29.92 111.61,29.92 110.47,31.07 110.47,37.42 108.82,39.07 108.06,39.07 105.14,41.99 105.14,44.53 100.44,49.23 100.44,53.29 99.55,54.18 99.55,64.21 99.89,64.56 99.89,65.04 99.91,65.06 99.91,65.41 99.89,65.43 99.89,67.24 v1(100.29,67.64)
N101210580: length 58.6
  TOP w0.127: U6.P9 v1(100.29,66.04) ; D14.C 125.23,30.85 125.19,30.81 v1(125.08,30.81) J8.8
  BOTTOM w0.127: v1(125.08,30.81) 124.57,30.3 111.87,30.3 110.85,31.32 110.85,37.67 109.07,39.45 108.18,39.45 105.52,42.12 105.52,44.66 100.75,49.43 100.75,53.49 99.93,54.31 99.93,64.21 100.18,64.47 100.18,65.93 v1(100.29,66.04)
N101210583: length 51.2
  TOP w0.127: U6.N10 v1(101.89,66.84) ; v1(122.54,32.34) 122.54,31.32 123,30.85 D15.C 123.55,29.42 J8.7
  BOTTOM w0.127: v1(101.89,66.84) 102.29,66.44 102.29,55.63 103.49,54.43 103.49,51.77 109.45,45.8 109.45,43.02 117.59,34.89 117.59,33.22 118.6,32.21 122.28,32.21 122.41,32.34 v1(122.54,32.34)
N101210586: length 50
  TOP w0.127: J8.6 121.01,29.42 D16.C 120.45,30.85 v1(120,31.31) ; U6.M10 v1(101.09,67.64)
  BOTTOM w0.127: v1(120,31.31) 118.1,31.31 116.69,32.72 116.69,34.75 108.69,42.75 108.69,45.42 102.72,51.39 102.72,54.18 101.63,55.27 101.63,64.52 101.71,64.6 101.71,65.59 101.49,65.81 101.49,67.24 v1(101.09,67.64)
N101210589: length 53.2
  TOP w0.127: U6.L9 v1(100.29,68.44) ; J8.5 118.47,29.42 D17.C 117.8,30.85 v1(117.07,31.57)
  BOTTOM w0.127: v1(117.07,31.57) 116.52,31.02 112.3,31.02 111.61,31.7 111.61,38.05 109.45,40.21 108.69,40.21 106.91,41.99 106.91,44.53 101.48,49.97 101.48,53.78 100.69,54.57 100.69,65.44 100.95,65.7 100.95,66.37 100.69,66.63 100.69,68.04 v1(100.29,68.44)
N101211681: length 1.4
  TOP w0.305: U6.L8 v1(100.29,69.24)
  BOTTOM w0.305: R2161.1 100.27,69.26 v1(100.29,69.24)
N101211874: length 11.7
  TOP w0.381: R59.2 87.15,48.47 ; R59.2 86.4,49.09 ; R59.2 85.65,48.47 ; C69.1 93.57,52.78 ; C69.1 92.07,52.78 ; C69.1 92.82,53.41 ; C68.1 86.97,55.12 ; C68.1 87.38,54.69 ; C68.1 86.97,54.26 ; 87.81,48.97 J14.2 ; J14.2 88.75,49.91 ; J14.2 89.69,48.97 ; 90.16,52.78 C70.1 ; C70.1 91.66,52.78 ; C70.1 90.91,53.41 ; C71.1 87.38,53.55 ; C71.1 86.97,53.98 ; C71.1 86.97,53.11
N101211894: length 14.5
  TOP w0.127: U6.L5 v1(97.09,68.44)
  BOTTOM w0.127: v1(97.09,68.44) 96.7,68.04 96.7,67.32 96.26,66.89 94.98,66.89 93.33,65.23 87.49,65.23 R57.1 C64.1 R56.2
N101213128: length 6.8
  TOP w0.127: U6.T15 105.89,64.44 105.89,60.41 TP11.1
N101213130: length 7.1
  TOP w0.127: TP10.1 106.91,58.12 105.52,59.51 105.52,64.01 U6.U15
N101213146: length 17
  TOP w0.127: v1(115.04,72.98) TP9.1 116.19,72.85 D20.C 117.62,73.52 C73.1 ; U6.J12 v1(103.49,70.84)
  BOTTOM w0.127: v1(103.49,70.84) 103.89,71.24 110.38,71.24 112.12,72.98 v1(115.04,72.98)
N101224368: length 1
  BOTTOM w0.127: R186.2 C88.1
N101241745: length 3.8
  TOP w0.381: U41.3 68.86,100.49 C271.1 C270.1 R644.2
N101248699: length 2.4
  TOP w0.127: v1(153.4,51.39) R339.2 R341.2
  BOTTOM w0.127: U116.2 153.4,51.39 v1(153.4,51.39)
N101250307: length 5.9
  TOP w0.381: 134.47,13.27 C165.1 ; C165.1 134.91,13.67 ; C165.1 134.04,13.67 ; 137.91,10.89 J24.2 ; J24.2 138.91,9.07 ; J24.2 138.91,12.72
N101250309: length 9.6
  TOP w0.381: T1.3 141.33,15.27 ; T1.3 142.16,14.49 ; T1.3 140.51,14.49 ; T1.3 141.33,13.72 ; J24.1 140.92,6.39 ; J24.1 138.91,5.22 ; J24.1 136.91,6.39 ; J24.1 138.91,7.57
N101250379: length 3.3
  TOP w0.254: v1(133.08,20.27) 132.7,20.65 U22.1
  BOTTOM w0.381: 134.07,20.02 R376.2 ; R376.2 134.48,20.45 ; R376.2 134.48,19.59 ; 132.31,20.22 R375.1 ; R375.1 132.31,21.09 ; R375.1 132.72,20.65
N101250387: length 3.7
  TOP w0.381: C165.2 134.91,14.42 ; C165.2 134.47,14.83 ; C165.2 134.04,14.42 ; T1.1 137.08,14.49 ; T1.1 135.43,14.49 ; T1.1 136.25,15.27
N101250389: length 7
  TOP w0.381: 136.25,19.18 T1.6 ; T1.6 135.43,19.95 ; T1.6 137.08,19.95 ; T1.6 136.25,20.73
  BOTTOM w0.381: 136.88,21.24 C166.1 ; C166.1 137.29,21.67 ; C166.1 136.88,22.1 ; R377.1 138.72,22.74 ; R377.1 138.72,20.86 ; R377.1 138.09,21.8
  vias: v1(137.52,22.3) v1(137.52,21.16)
N101250395: length 2.5
  BOTTOM w0.381: 135.72,21.67 C166.2 ; C166.2 136.13,21.24 ; C166.2 136.13,22.1 ; R376.1 135.64,20.02 ; R376.1 135.23,20.45 ; R376.1 135.23,19.59
N101250397: length 3.6
  TOP w0.254: R378.1 v1(130.92,20.53) 131.04,20.65 U22.6 ; U22.3 132.44,22.08 v1(132.21,22.3)
  BOTTOM w0.381: R375.2 131.56,21.09 ; R375.2 131.56,20.22 ; R375.2 131.15,20.65
N101250409: length 2.2
  TOP w0.254: J25.2 131.68,23.66 U22.4
N101250428: length 5.9
  TOP w0.381: v1(145.27,20.65) U23.2
  BOTTOM w0.381: 145.91,20.22 R381.1 ; R381.1 145.5,20.65 ; R381.1 145.91,21.09 ; J26.1 146.59,17.48 ; J26.1 144.71,17.48 ; J26.1 145.65,18.42 ; J26.1 145.65,16.54
N101250468: length 8.4
  TOP w0.381: J27.1 154.25,6.39 ; J27.1 152.25,5.22 ; J27.1 150.25,6.39 ; 155.56,13.72 T2.3 ; T2.3 156.38,14.49 ; T2.3 154.73,14.49 ; T2.3 155.56,15.27
N101293462: length 64.3
  TOP w0.127: v1(185.4,85.59) 186.87,85.59 187.43,86.14 R348.1 187.46,86.85 v1(188.58,86.85)
  BOTTOM w0.127: v1(185.4,85.59) 185.4,84.89 179.01,78.5 179.01,75.35 161.27,57.61 153.02,57.61 151.62,56.21 151.62,52.15 153.19,50.57 U116.1 154.8,50.08 156.23,50.08 156.57,49.74 R343.1 ; U117.1 v1(188.58,86.85)
N101293775: length 68.4
  TOP w0.127: v1(117.96,86.85) 117.46,87.36 117.46,90.63 126.85,100.03 132.57,100.03 135.74,103.2 137.65,103.2 138.41,103.96 138.41,114.55 138.27,114.69 138.27,115.81 138.72,116.26 138.72,117.12 139.17,117.58 139.17,119.59 143.74,124.16 152.28,124.16 v1(154.29,122.15) 154.29,121.37 R350.1
  BOTTOM w0.127: U119.1 154.29,123.12 v1(154.29,122.15) ; U118.1 v1(117.96,86.85) 116.59,86.85 R344.1
N101343693: length 10.6
  TOP w0.127: Y2.3 108.78,55.08 109.33,55.63 109.33,56.59 109.07,56.85 C74.1 109.08,57.24 R62.1 109.08,58.92 106.29,61.71 U6.U16
N101346492: length 10.3
  TOP w0.127: U6.T16 106.29,64.61 106.69,64.21 106.69,61.77 109.83,58.63 R62.2 109.83,57.24 C75.1 109.84,56.24 Y2.1
N101370712: length 2.7
  BOTTOM w0.127: R29.2 R30.1 142.41,131.58 Q6.1
N101733751: length 1.4
  TOP w0.127: D23.A 171.44,107.41 R666.1
N101733753: length 1.4
  TOP w0.127: R667.1 168.65,107.4 D24.A
N101733765: length 7.2
  TOP w0.127: R686.2 170.79,123.27 166.99,123.27 166.02,124.24 J36.50
N101733775: length 60.7
  TOP w0.119: v1(170.79,105.48) 170.79,105.49 168.38,105.49 165.33,108.54 164.31,108.54 164.03,108.26 L21.2
  BOTTOM w0.119: R690.2 186.03,77.8 186.03,80.02 190.93,84.92 191.8,84.92 193.39,86.52 193.39,98.99 185.92,106.46 171.99,106.46 171.49,105.96 171.26,105.96 v1(170.79,105.48)
N101733777: length 60.6
  TOP w0.119: v1(171.5,105.49) 171.44,105.49 170.98,105.95 170.6,105.95 170.38,105.74 168.49,105.74 165.43,108.79 164.31,108.79 164.03,109.06 L21.3
  BOTTOM w0.119: v1(171.5,105.49) 171.72,105.71 171.72,105.84 172.1,106.22 185.82,106.22 193.15,98.88 193.15,86.62 191.69,85.17 190.83,85.17 185.78,80.12 185.78,79.41 185.66,79.29 185.24,79.29 185.12,79.17 185.12,78.93 185.24,78.81 185.66,78.81 185.78,78.69 185.78,78.44 R691.2
N101733827: length 7.8
  TOP w0.119: L21.4 161.41,108.78 160.87,108.78 160.5,109.15 160.5,112.2 159.84,112.86 158.59,112.86 158.46,112.99 J36.5
N101733829: length 7.8
  TOP w0.119: J36.3 158.46,112.49 158.59,112.61 159.73,112.61 160.25,112.09 160.25,109.04 160.76,108.54 161.42,108.54 L21.1
N101733917: length 2.9
  TOP w0.127: R688.2 166.4,126.24 J36.58
N101733919: length 3.4
  TOP w0.127: J36.60 166.01,126.74 166.22,126.95 166.22,127.46 167.11,128.35 R689.2
N101734031: length 2.9
  TOP w0.127: C282.1 R663.1 R664.2 R662.2
N101734037: length 2.7
  TOP w0.127: J36.56 166.41,125.74 167.11,126.44 R663.2
N101734088: length 1.5
  TOP w0.127: U43.2 161.39,95.84 R705.2
N101734122: length 2.9
  TOP w0.127: R679.1 C286.1 R669.2 R665.2
N101734218: length 3.1
  TOP w0.127: J36.54 165.91,125.24 167.37,123.78 R679.2
N101734224: length 15.3
  TOP w0.127: v1(159.43,117.49) 159.31,117.49 159.31,117.49 J36.23 ; R676.2 v1(161.78,106.12)
  BOTTOM w0.127: v1(159.43,117.49) 161.78,115.13 v1(161.78,106.12)
N101734331: length 2.7
  TOP w0.127: J36.9 157.49,114 R668.2
N101734351: length 2.9
  TOP w0.127: R670.2 155.19,114.49 J36.11
N101734355: length 3
  TOP w0.127: R671.2 155.58,114.99 J36.13
N101734367: length 3.2
  TOP w0.127: R672.2 155.97,115.49 J36.15
N101734379: length 3.4
  TOP w0.127: R673.2 156.35,115.99 J36.17
N101734391: length 3.5
  TOP w0.127: J36.19 156.73,116.49 154.79,118.43 R674.2
N101734410: length 15.8
  TOP w0.127: R675.2 v1(156.71,106.12) ; v1(158.92,116.99) J36.21
  BOTTOM w0.127: v1(158.92,116.99) 159.04,116.99 161.02,115.01 161.02,110.43 v1(156.71,106.12)
N101734451: length 2.7
  TOP w0.127: R682.2 166.86,120.74 J36.36
N101734453: length 2.9
  TOP w0.127: J36.34 166.47,120.24 R681.2
N101734459: length 3
  TOP w0.127: J36.32 166.08,119.74 R680.2
N101734471: length 2.5
  TOP w0.127: J36.22 166.29,117.24 166.48,117.43 R678.2
N101734503: length 2.5
  TOP w0.127: R677.2 166.48,116.54 166.28,116.74 J36.20
N101734640: length 2.6
  TOP w0.127: J36.10 166.62,114.24 166.99,113.87 R684.2
N101734642: length 2.5
  TOP w0.127: R685.2 166.48,114.76 166.45,114.74 J36.12
N101734644: length 2.8
  TOP w0.127: J36.8 166.49,113.74 167.24,112.98 R683.2
N101734654: length 2.6
  TOP w0.127: J36.14 166.19,115.24 166.6,115.65 R687.2
N101736970: length 2.2
  TOP w0.127: U44.2 158.49,105.36 R706.2
N101753271: length 22.5
  TOP w0.127: J78.1 147.94,104.47 150.35,102.06 153.65,102.06 155.56,100.15 164.57,100.15 165.29,100.87 U43.17
N101753274: length 22.1
  TOP w0.127: J79.1 148.46,101.41 153.38,101.41 155.29,99.51 164.84,99.51 165.94,100.6 U43.16
N101754296: length 2.2
  TOP w0.127: U44.7 155.24,105.18 R701.2
N101754314: length 2.2
  TOP w0.127: U44.8 154.59,105.32 R703.2
N101754512: length 11.5
  TOP w0.127: J80.1 146.41,99.77 153.78,99.77 154.59,98.97 U44.17
N101754515: length 7.1
  TOP w0.127: U44.16 153.94,98.85 153.4,99.39 150.98,99.39 150.35,98.76 J81.1
N102038478: length 23.7
  TOP w0.127: v1(138.03,62.82) 138.16,62.69 R725.1
  L3_INT_1 w0.127: J39.6 137.47,42.3 137.47,56.92 137.9,57.36 137.9,58.12 137.01,59.01 137.01,61.8 v1(138.03,62.82)
N102038480: length 21.5
  TOP w0.127: R730.1 139.43,60.4 v1(139.68,60.66)
  L3_INT_1 w0.127: v1(139.68,60.66) 139.68,58.12 140.82,56.97 140.82,53.42 140.32,52.91 140.32,42.34 J39.10
N102038482: length 29.9
  TOP w0.127: R732.1 140.44,66.5 140.57,66.63 v1(141.97,66.63)
  L3_INT_1 w0.127: J39.12 142.91,42.29 142.91,64.67 141.97,65.61 v1(141.97,66.63)
N102038508: length 8.2
  TOP w0.127: R734.1 149.46,45.93 149.46,45.04 150.15,44.35 150.15,42.93 149.64,42.43 147.76,42.43 J39.14
N102038510: length 20.2
  TOP w0.127: R737.1 141.72,53.16 144.63,53.16 v1(145.52,54.05)
  L3_INT_1 w0.127: J39.16 150.22,42.35 150.22,44.27 149.21,45.29 149.21,46.05 145.52,49.74 v1(145.52,54.05)
N102038514: length 179.2
  L3_INT_1 w0.127: v1(153.4,36.65) 151.75,38.31 151.75,44.27 152.51,45.04 152.51,48.49 149.59,51.41 149.59,58.63 151.39,60.43 151.39,65.51 152,66.12 152,66.55 154.49,69.04 164.83,69.04 172.7,76.91 172.7,84.15 172.95,84.41 173.72,84.41 v1(174.22,84.91) ; v1(114.28,87.71) 113.39,87.71 111.69,86.01 106.58,86.01 104.76,87.84 104.76,90.63 103.31,92.08 98.01,92.08 v1(96.96,93.12)
  BOTTOM w0.127: J39.2 135.97,36.53 142.09,36.53 142.47,36.15 152.89,36.15 v1(153.4,36.65) ; v1(174.22,84.91) 173.72,85.42 172.83,85.42 171,83.59 139.6,83.59 138.79,84.41 129.01,84.41 128.38,85.04 120.25,85.04 119.89,85.4 115.8,85.4 114.53,86.67 114.53,87.45 v1(114.28,87.71) ; R722.1 96.88,93.04 v1(96.96,93.12)
N102038516: length 177.9
  L3_INT_1 w0.127: v1(173.21,84.91) 172.95,84.91 172.32,84.28 172.32,77.07 164.67,69.42 154.34,69.42 150.37,65.46 150.37,59.95 149.21,58.78 149.21,51.34 151.31,49.23 151.31,37.47 v1(152.13,36.65) ; v1(114.03,86.95) 113.26,86.95 112.02,85.7 106.38,85.7 104.37,87.71 104.37,90.38 102.98,91.77 97.65,91.77 95.36,94.06 v1(93.45,94.06)
  BOTTOM w0.127: v1(152.13,36.65) 152,36.53 142.6,36.53 141.59,37.54 136,37.54 133.83,39.71 J39.4 ; R723.1 93.96,92.4 93.96,93.55 v1(93.45,94.06) ; v1(173.21,84.91) 171.57,83.26 139.5,83.26 138.67,84.1 128.89,84.1 128.25,84.74 120.05,84.74 119.72,85.07 115.7,85.07 114.03,86.74 v1(114.03,86.95)
N102038763: length 23.1
  TOP w0.127: v1(140.32,62.05) R727.1
  L3_INT_1 w0.127: v1(140.32,62.05) 139.17,60.91 139.17,57.94 140.44,56.67 140.44,53.67 139.99,53.22 139.99,42.28 J39.8
N102039011: length 2.5
  TOP w0.127: J39.3 133.83,44.92 133.71,45.04 R728.1
N102039036: length 34.4
  TOP w0.127: R728.2 R738.1 138.53,46.94 v1(139.05,47.45) ; R735.2 138.79,71.83 v1(139.68,70.94)
  L3_INT_1 w0.127: v1(139.68,70.94) 140.19,70.44 140.19,67.13 139.55,66.5 139.55,61.93 138.79,61.17 138.79,56.97 138.16,56.34 138.16,53.29 138.92,52.53 138.92,47.58 v1(139.05,47.45)
N102040284: length 34.3
  TOP w0.127: v1(139.85,56.47) 139.93,56.56 R750.1
  L3_INT_1 w0.127: v1(138.92,39.7) 138.54,39.7 137.83,40.41 137.83,44.2 139.55,45.93 139.55,53.55 139.93,53.93 139.93,56.38 v1(139.85,56.47)
  BOTTOM w0.127: J44.2 151.97,40.13 142.27,40.13 141.33,39.19 139.81,39.19 139.3,39.7 v1(138.92,39.7)
N102040286: length 41.1
  TOP w0.127: R752.1 137.32,57.6 v1(137.42,57.71)
  L3_INT_1 w0.127: v1(137.42,57.71) 137.14,57.43 137.14,46.56 135.29,44.71 135.29,40.16 v1(135.62,39.83)
  BOTTOM w0.127: v1(135.62,39.83) 136.42,39.03 139.21,39.03 139.55,38.69 141.46,38.69 142.6,39.83 154.2,39.83 J44.4
N102040306: length 133.2
  L3_INT_1 w0.127: v1(165.97,46.94) 165.97,52.78 164.62,54.13 164.62,55.97 161.46,59.13 155.87,59.13 153.4,61.61 153.4,65.56 155.36,67.52 165.72,67.52 174.73,76.53 174.73,82.5 v1(174.22,83.01)
  BOTTOM w0.127: J44.10 164.57,42.58 164.57,44.66 165.46,45.54 165.46,46.43 v1(165.97,46.94) ; R756.1 111.24,83.38 111.99,82.63 113.52,82.63 114.08,83.19 118.57,83.19 118.95,82.81 138.13,82.81 139.96,80.98 173.46,80.98 174.22,81.74 v1(174.22,83.01)
N102040308: length 123.4
  L3_INT_1 w0.127: v1(173.21,80.34) 173.21,76.66 165.21,68.66 154.88,68.66 152.38,66.16 152.38,61.01 155.4,57.99 159.72,57.99 161.75,55.96 161.75,54.46 164.45,51.77 164.45,46.43 v1(164.95,45.93)
  BOTTOM w0.127: v1(164.95,45.93) 164.7,45.67 163.18,45.67 162.16,44.66 162.16,42.71 J44.8 ; R755.1 115.54,82.88 118.34,82.88 118.79,82.43 137.97,82.43 139.88,80.52 173.03,80.52 v1(173.21,80.34)
N102040310: length 124.3
  L3_INT_1 w0.127: v1(165.97,45.93) 165.46,46.43 165.46,52.53 164.32,53.67 164.32,55.74 161.3,58.75 155.72,58.75 153.02,61.45 153.02,65.72 155.2,67.9 165.59,67.9 174.22,76.53 v1(174.22,80.34)
  BOTTOM w0.127: R757.1 116.14,82.46 118.22,82.46 118.64,82.04 137.81,82.04 139.72,80.14 172.4,80.14 172.7,79.83 173.72,79.83 v1(174.22,80.34) ; J44.12 166.99,42.45 166.99,44.91 v1(165.97,45.93)
N102040312: length 134.7
  L3_INT_1 w0.127: v1(164.95,46.94) 164.95,51.77 162.08,54.64 162.08,56.17 159.88,58.37 155.56,58.37 152.71,61.22 152.71,65.95 155.04,68.28 165.46,68.28 173.72,76.53 173.72,81.03 v1(173.21,81.54)
  BOTTOM w0.127: R751.1 108.69,84.03 109.16,84.5 110.76,84.5 112.25,83.01 113.39,83.01 113.87,83.49 118.8,83.49 119.11,83.19 138.29,83.19 140.11,81.36 173.03,81.36 v1(173.21,81.54) ; J44.6 159.49,42.58 159.49,44.66 160.89,46.05 164.06,46.05 v1(164.95,46.94)
N102040383: length 159.6
  L3_INT_1 w0.127: v1(173.21,83.01) 173.72,83.52 174.48,83.52 175.11,82.88 175.11,76.37 165.88,67.13 155.51,67.13 153.78,65.4 153.78,61.77 156.03,59.51 163.14,59.51 166.81,55.85 166.81,53.62 166.48,53.29 166.48,46.43 v1(166.99,45.93) ; v1(95.18,92.32) 95.27,92.41 96.15,92.41 97.42,91.14 102.6,91.14 103.49,90.25 103.49,87.58 105.98,85.09 113.95,85.09 v1(114.28,85.42)
  BOTTOM w0.127: v1(173.21,83.01) 172.07,81.87 140.04,81.87 138.41,83.49 128.63,83.49 128,84.13 119.64,84.13 119.34,84.43 115.27,84.43 v1(114.28,85.42) ; R758.1 94.85,91.99 v1(95.18,92.32) ; J44.18 172.19,42.47 172.19,44.45 171.23,45.42 167.49,45.42 v1(166.99,45.93)
N102040397: length 163.6
  L3_INT_1 w0.127: v1(113.26,86.18) 112.48,85.4 106.18,85.4 103.87,87.71 103.87,90.38 102.8,91.44 97.55,91.44 96.17,92.82 v1(94.68,92.82) ; v1(166.99,46.94) 167.11,47.07 167.11,56.09 163.3,59.9 156.19,59.9 154.16,61.93 154.16,65.24 155.67,66.75 166.03,66.75 175.49,76.21 175.49,83.01 174.63,83.87 v1(173.21,83.87)
  BOTTOM w0.127: v1(166.99,46.94) 167.75,46.18 173.34,46.18 174.73,44.78 174.73,42.47 J44.20 ; R759.1 94.47,91.89 94.47,92.6 94.68,92.81 v1(94.68,92.82) ; v1(173.21,83.87) 171.58,82.25 140.09,82.25 138.54,83.8 128.76,83.8 128.12,84.43 119.84,84.43 119.51,84.76 115.58,84.76 114.15,86.18 v1(113.26,86.18)
N102051556: length 2.7
  TOP w0.127: R753.2 158.15,43.81 J44.5
N102051558: length 2.3
  TOP w0.127: R746.2 152.81,45.47 153.09,45.2 J44.1
N102051560: length 2.6
  TOP w0.127: J44.3 155.63,46.35 R748.2
N102051598: length 51.5
  TOP w0.127: v1(135.21,57.6) R760.2
  L3_INT_1 w0.127: v1(135.62,38.69) 134.98,39.32 134.98,45 136.76,46.78 136.76,47.96 136.25,48.47 136.25,56.57 v1(135.21,57.6)
  BOTTOM w0.127: v1(135.62,38.69) 136.38,37.92 141.64,37.92 142.27,37.29 143.36,37.29 143.87,37.8 143.87,38.31 144.48,38.92 158.58,38.92 159.49,39.83 159.49,41.73 160.71,42.95 J44.7
N102051600: length 2.7
  TOP w0.127: J44.9 163.23,43.81 R764.2
N102051892: length 43.4
  TOP w0.127: v1(138.92,62.05) 139.3,62.44 R747.2 ; v1(153.48,46.74) R746.1 C293.1
  L3_INT_1 w0.127: v1(139.68,68.79) 139.68,67.13 138.66,66.12 138.66,62.31 v1(138.92,62.05) 138.41,61.55 138.41,57.23 137.8,56.62 137.8,47.68 v1(139.05,46.43)
  BOTTOM w0.127: v1(139.05,46.43) 148.19,46.43 148.49,46.74 v1(153.48,46.74) ; v1(139.68,68.79) 138.28,70.19 R1049.2
N102051905: length 1.8
  TOP w0.127: C294.1 R749.2 154.85,47.12 R748.1
N102051907: length 74.9
  TOP w0.127: R753.1 C295.1 159.57,47.25 v1(159.87,46.94)
  L3_INT_1 w0.127: v1(143.24,39.19) 141.92,37.87 132.45,37.87 129.27,41.06 129.27,52.84 130.92,54.49 130.92,56.97 131.68,57.74 133.2,57.74 135.36,59.9 135.36,63.27 137.01,64.93 137.01,67.14 137.9,68.02 137.9,69.17 137.52,69.55 v1(137.01,69.55)
  BOTTOM w0.127: v1(143.24,39.19) 143.57,39.53 156.22,39.53 156.78,40.08 156.78,45.24 158.48,46.94 v1(159.87,46.94) ; R1051.2 136.76,69.8 v1(137.01,69.55)
N102052693: length 24.7
  TOP w0.127: R724.1 136.74,68.86 v1(137.01,68.58)
  L3_INT_1 w0.127: J41.12 132.37,88.43 132.37,84.83 136.25,80.95 136.25,72.75 136,72.5 136,69.29 136.71,68.58 v1(137.01,68.58)
N102052753: length 5.9
  TOP w0.127: J41.2 142.73,88.26 R736.1
N102052757: length 17.3
  TOP w0.127: R733.1 v1(155.94,84.79)
  L3_INT_1 w0.127: v1(155.94,84.79) 155.94,85.17 155.3,85.8 148.19,85.8 145.9,88.09 142.87,88.09 J41.4
N102052761: length 31.2
  TOP w0.127: v1(138.41,67.26) 142.86,67.26 144.37,65.74 R731.1
  L3_INT_1 w0.127: v1(138.41,67.26) 138.79,67.64 138.79,69.67 137.78,70.69 137.78,88.39 J41.6
N102052765: length 41.3
  TOP w0.127: v1(132.57,55.32) R729.1
  L3_INT_1 w0.127: J41.8 135.11,88.26 135.11,84.91 137.08,82.95 137.08,70.5 138.28,69.29 138.28,67.9 137.44,67.06 137.44,64.9 135.67,63.12 135.67,59.74 133.15,57.23 131.81,57.23 131.3,56.72 131.3,55.83 131.81,55.32 v1(132.57,55.32)
N102052856: length 34.1
  TOP w0.127: v1(136.76,67.62) 136.47,67.33 130.6,67.33 130.16,67.77 129.01,67.77 128.76,68.02 R726.1
  L3_INT_1 w0.127: v1(136.76,67.62) 137.52,68.38 137.52,68.91 137.37,69.07 136.73,69.07 136.38,69.42 136.38,72.34 136.63,72.6 136.63,81.1 132.7,85.04 132.7,88.39 J41.10
N102054567: length 3.4
  TOP w0.127: J45.15 147.81,85.63 R869.2
N102054918: length 2.9
  TOP w0.127: R762.1 164.06,85.42 164.38,85.74 J45.3
N102054920: length 2.9
  TOP w0.127: R766.1 167.11,85.42 166.92,85.62 J45.1
N102054973: length 59.6
  TOP w0.127: R766.2 R765.1 v1(166.1,82.76) ; v1(139.68,69.67) 139.17,70.18 136.56,70.18 R767.2
  L3_INT_1 w0.127: v1(146.67,60.78) 147.3,60.15 147.94,60.15 148.7,60.91 148.7,62.56 146.54,64.72 146.54,66.12 147.81,67.39 147.81,68.53 149.08,69.8 150.86,69.8 152,70.94 160.25,70.94 166.86,77.55 166.86,81.99 v1(166.1,82.76)
  BOTTOM w0.127: v1(146.67,60.78) 145.14,62.31 144.25,62.31 143.36,63.2 143.36,66.88 140.57,69.67 v1(139.68,69.67)
N102055690: length 55.6
  TOP w0.127: v1(165.08,82.76) R761.1 R762.2 ; v1(138.66,70.94) R763.2
  L3_INT_1 w0.127: v1(165.08,82.76) 163.43,81.1 158.35,81.1 156.95,79.71 156.95,74.88 153.46,71.39 151.94,71.39 150.73,70.18 149,70.18 145.9,67.08 145.9,64.72 148.32,62.31 148.32,61.42 v1(147.68,60.78)
  BOTTOM w0.127: v1(147.68,60.78) 145.65,62.82 144.38,62.82 143.74,63.45 143.74,67.13 140.44,70.44 139.17,70.44 v1(138.66,70.94)
N102055791: length 2.8
  TOP w0.127: J45.5 161.84,85.48 161.78,85.42 R874.2
N102055814: length 2.8
  TOP w0.127: R873.2 159.24,85.42 159.3,85.48 J45.7
N102055853: length 2.9
  TOP w0.127: J45.9 156.76,85.49 156.95,85.3 R872.2
N102055876: length 11.9
  TOP w0.127: J45.11 153.09,88.09 148.06,88.09 144.76,84.79 R871.2
N102055899: length 2.8
  TOP w0.127: R870.2 151.62,85.17 151.68,85.23 J45.13
N102056178: length 7.3
  TOP w0.381: J45.10 156.76,90.51 ; J45.10 156.76,88.5 ; J45.10 155.75,89.5 ; J45.10 157.76,89.5 ; D27.C 154.26,93.96 ; D27.C 153.42,93.17 ; D27.C 154.26,92.38 ; D27.C 155.1,93.17
N102056760: length 6
  TOP w0.127: J46.2 165.97,93.63 J45.6
N102196396: length 2
  TOP w0.127: D6.C 122.52,35.13 Q7.3
N102196506: length 3.1
  TOP w0.127: Q7.1 117.59,36.15 R38.1 117.58,36.15 R35.1
N102198352: length 1.7
  TOP w0.127: D7.C Q8.3
N102198373: length 3.1
  TOP w0.127: Q8.1 117.59,39.83 R39.1 117.58,39.83 R36.1
N102544921: length 4.1
  TOP w0.381: 116.43,58.96 L4.1 ; L4.1 116.84,59.39 ; L4.1 116.43,59.82 ; 116.82,56.16 J11.2 ; J11.2 116.82,58.04 ; J11.2 115.88,57.1
N102898927: length 2.1
  TOP w0.127: R696.1 156.19,96.09 156.54,96.44 U44.20
N102898934: length 2.1
  TOP w0.127: U44.19 155.89,96.42 155.43,95.96 R697.1
N102898941: length 2.1
  TOP w0.127: R699.1 154.67,95.84 155.24,96.41 U44.18
N103179532: length 16.3
  TOP w0.381: 189.84,59.7 J33.9 190.66,58.99 ; 193.78,56.95 J33.8 192.65,57.75 ; 192.65,66.1 J33.7 193.78,66.9
  TOP w0.508: J33.6 190.66,65.18
  L3_INT_1 w0.381: J33.7 193.78,66.89 ; J33.7 193.78,65.32 ; J33.7 192.65,66.1 ; 192.65,57.75 J33.8 ; J33.8 193.78,56.97 ; J33.8 193.78,58.54 ; J33.6 191.47,64.15 ; J33.6 190.66,64.86 ; J33.6 190.66,63.44 ; J33.9 191.47,59.7 ; J33.9 190.66,58.99 ; J33.9 190.66,60.41
N103179921: length 18.9
  TOP w0.381: C527.1 189.59,85.86 ; C527.1 189.59,84.99 ; C527.1 189.99,85.42 ; R1326.1 189.66,84.41 ; R1326.1 189.26,84.84 ; R1326.1 189.26,83.97 ; 193.78,85.83 J68.7 192.65,85.03 ; 193.78,75.88 J68.8 192.65,76.68
  TOP w0.508: J68.6 190.73,83.15 190.73,84.03
  L3_INT_1 w0.381: 190.66,82.36 J68.6 ; J68.6 190.66,83.79 ; J68.6 191.47,83.08 ; J68.6 189.84,83.08 ; J68.9 191.47,78.63 ; J68.9 190.66,77.91 ; J68.9 190.66,79.34 ; J68.9 189.84,78.63 ; 193.78,84.24 J68.7 ; J68.7 193.78,85.81 ; J68.7 192.65,85.03 ; 193.78,75.89 J68.8 ; J68.8 193.78,77.46 ; J68.8 192.65,76.68
N103596184: length 17.9
  TOP w0.127: R53.2 C63.1 R55.1 87.36,61.93 87.99,62.56 v1(87.99,63.6) ; U6.L6 v1(97.89,69.24)
  BOTTOM w0.127: v1(97.89,69.24) 97.76,69.24 97.5,68.97 97.5,67.5 97.49,67.49 97.49,67.47 97.25,67.23 96.93,67.23 96.22,66.53 95.26,66.53 93.58,64.85 89.24,64.85 v1(87.99,63.6)
N103598440: length 12.2
  TOP w0.305: v2(96.29,67.64) 96.29,67.64 U6.M4
  TOP w0.381: C72.1 107.86,46.94 ; C72.1 107.42,47.34 ; C72.1 106.99,46.94 ; C66.1 109.57,47.32 ; C66.1 108.07,47.32 ; C66.1 108.82,47.95 ; J77.1 106.53,49.86 R58.1 ; J77.1 108.44,48.92 ; J77.1 109.38,49.86
  L3_INT_1 w0.381: J77.1 108.44,50.8 ; J77.1 109.38,49.86 ; J77.1 108.44,48.92 ; J77.1 107.5,49.86
N103602996: length 3.4
  TOP w0.127: R655.2 R656.2 R657.1 77.5,108.74 U42.8
N103603009: length 11.5
  TOP w0.107: R658.1 77.45,113.92 77.45,113.24 78.31,112.38 FL2.4 77.13,112.15 77.07,112.09 77.07,111.33 74.51,108.77 74.51,107.08 74.62,106.97 74.77,106.97 74.87,107.08 74.87,107.37 74.98,107.47 U42.7
N103603017: length 11.6
  TOP w0.107: U42.6 74.98,106.2 74.87,106.31 74.87,106.6 74.77,106.71 74.51,106.71 74.25,106.97 74.25,108.88 76.81,111.44 76.81,112.09 76.75,112.15 FL2.3 75.81,112.35 76.56,113.11 R661.1
N103603047: length 8.9
  TOP w0.127: v1(79.7,119.67) 79.7,118.54 R659.2 ; v1(74.53,119.66) 74.53,118.66 R660.1
  L3_INT_1 w0.127: v1(74.53,119.66) 74.73,119.46 79.49,119.46 v1(79.7,119.67)
  BOTTOM w0.127: C280.1 74.41,119.54 v1(74.53,119.66)
N103609194: length 5.1
  TOP w0.127: v1(103.36,109.3) 104.25,109.3 104.52,109.57 104.52,109.95 104.39,110.07 104.12,110.07 103.99,110.2 103.99,110.45 104.12,110.58 104.39,110.58 104.52,110.71 U11.B1
  BOTTOM w0.127: R2156.2 v1(103.36,109.3)
N103609206: length 1.6
  TOP w0.127: U11.A5 v1(103.02,115.74)
  BOTTOM w0.127: v1(103.02,115.74) 102.47,116.28 R299.2
N103609208: length 1.4
  TOP w0.127: U11.A2 103.25,111.97 v1(102.98,111.97)
  BOTTOM w0.127: R303.2 102.72,111.71 v1(102.98,111.97)
N103609210: length 1.4
  TOP w0.127: U11.A3 v1(103.02,112.74)
  BOTTOM w0.127: R308.2 103.01,112.73 v1(103.02,112.74)
N103609334: length 2.8
  BOTTOM w0.127: R303.1 101.58,111.71 R312.2 ; R303.1 R308.1 ; R303.1 100.7,111.71 R289.2
N103609361: length 8
  TOP w0.127: v1(102.37,108.69) 102.95,108.69 103.1,108.54 104.37,108.54 v1(105.25,109.41) 105.25,109.44 105.01,109.68 105.01,111.46 105.52,111.97 U11.C2
  BOTTOM w0.127: v1(105.25,109.41) 105.24,109.42 R288.2 ; R296.2 101.89,109.17 v1(102.37,108.69)
N103609367: length 2.3
  TOP w0.127: U11.A4 v1(103.02,113.74)
  BOTTOM w0.127: R293.2 R287.2 102.9,113.62 v1(103.02,113.74)
N103609386: length 15.8
  TOP w0.127: U11.C3 105.01,112.73 105.01,112.09 104.63,111.71 104.38,111.71 103.6,110.92 103.59,110.92 101.83,109.17 99.59,109.17 99.29,108.88 99.29,103.84 99.68,103.45 R298.2
N103609426: length 2.1
  TOP w0.127: v1(103.4,111.39) 104.24,112.24 U11.B2
  BOTTOM w0.127: R297.2 103.36,111.35 v1(103.4,111.39)
N103609440: length 0.9
  BOTTOM w0.127: R294.2 R299.1
N103749857: length 6.4
  TOP w0.203: 29.95,61.26 29.62,60.93 U29.30
  TOP w0.381: 29.95,61.26 v1(29.95,62.05)
  BOTTOM w0.381: C225.1 28.9,61.65 C226.1 ; C226.1 29.44,61.55 v1(29.95,62.05) ; C226.1 28.8,60.65 R521.1
  BOTTOM w0.457: C225.1 28.9,63.93 R523.1
N103749903: length 6.6
  TOP w0.127: U29.31 28.71,62.08 29.57,62.94 32.62,62.94 33.38,62.18 R518.1
N103749907: length 4.7
  TOP w0.127: R519.1 27.54,65.24 C224.1 26.78,64.34 27.1,64.01 U29.35
N103750002: length 6.3
  TOP w0.127: R505.1 4.67,53.64 J30.13
N103750008: length 3.6
  TOP w0.127: R506.1 3.39,69.02 J30.11
N103750009: length 4.6
  TOP w0.127: R520.1 25,63.45 25,62.69 25.5,62.19 U29.39
N103753894: length 6.1
  TOP w0.203: v1(31.86,87.33) 31.86,86.41 31.65,86.21 U34.30
  BOTTOM w0.457: R574.1 31.1,86.41 C247.1 30.84,86.67 C248.1 ; R576.1 30.84,88.85 C248.1 ; C248.1 31.6,87.58 v1(31.86,87.33)
N103753940: length 6.3
  TOP w0.127: U34.31 30.74,87.35 31.22,87.84 35.8,87.84 R571.1
N103753944: length 4.7
  TOP w0.127: U34.35 29.14,89.29 28.81,89.61 C246.1 29.57,90.51 R572.1
N103754039: length 6.3
  TOP w0.127: R558.1 4.67,79.04 J31.13
N103754045: length 3.6
  TOP w0.127: R559.1 3.39,94.42 J31.11
N103754046: length 4.6
  TOP w0.127: R573.1 27.16,88.59 27.16,87.84 27.54,87.46 U34.39
N103789758: length 1.9
  TOP w0.127: U13.7 R316.2
N103789768: length 1.9
  TOP w0.127: U13.6 R318.2
N103789772: length 1.9
  TOP w0.127: U13.5 R319.2
N103789774: length 2.1
  TOP w0.127: U13.3 R317.2
N103789776: length 3.1
  TOP w0.127: R313.2 R314.2 U13.1
N103789794: length 2.1
  TOP w0.127: U13.2 R315.2
N103834887: length 7.9
  TOP w0.127: J51.3 J51.4 R784.2
N103834897: length 7.9
  TOP w0.127: 143.46,32.84 R785.2
N103909102: length 1.9
  TOP w0.254: 166.86,20.65 168,20.65 168.27,20.92 U46.8
N103909121: length 2.9
  TOP w0.127: R777.2 171.43,20.91 170.41,21.93 U46.12
N103909127: length 3.4
  TOP w0.127: R774.2 R779.1 170.29,24.97 169.77,24.45 U46.1
N103909137: length 2.5
  TOP w0.127: U46.4 168.27,24.58 167.62,25.22 R773.1
N103909149: length 4.5
  TOP w0.127: U46.11 169.77,18.89 TP42.1
N103909150: length 3.9
  TOP w0.127: U46.10 169.27,17.61 TP43.1
N103909151: length 4.5
  TOP w0.127: TP44.1 168.77,18.88 U46.9
N103909152: length 2.3
  TOP w0.127: U46.2 169.27,24.71 169.4,24.84 R780.2
N103909154: length 2.4
  TOP w0.127: R781.2 168.51,24.97 168.77,24.71 U46.3
N103911488: length 7.1
  TOP w0.127: J49.1 176.13,31.19 175.46,31.87 D28.6 174.73,31.88 174.73,32.59 174.48,32.84 172.45,32.84 172.07,32.46 R768.1
N103911494: length 7
  TOP w0.127: J49.2 176,33.73 175.49,33.23 173.59,33.23 173.45,33.37 D28.3 172.41,34.08 172.07,33.73 R769.1
N103911836: length 2.7
  TOP w0.127: C307.1 R768.2 U45.2
N103911844: length 2.7
  TOP w0.127: C306.1 R769.2 U45.3
N103961253: length 2.1
  TOP w0.119: U55.N6 v4(23.98,116.66)
  BOTTOM w0.119: v4(23.98,116.66) 23.84,116.51 23.47,116.51 23.35,116.63 23.35,116.79 23.09,117.05 22.84,117.05 R812.2
N103961260: length 2.4
  BOTTOM w0.119: v3(25.04,116.66) 24.7,116.66 24.28,116.24 23.75,116.24 23.72,116.27 23.35,116.27 23.24,116.16 R813.2
N103961264: length 2.9
  TOP w0.254: R850.2 21.95,115.53 R811.1 23.1,115.27 23.98,115.27 24.37,115.66 U55.N8
N103961315: length 27.3
  TOP w0.127: v4(25.91,116.77) 26.02,116.66 U55.J6 ; R809.1 6.71,103.58 6.72,103.59 C326.1 R808.2 v1(6.72,106.12)
  BOTTOM w0.127: v1(6.72,106.12) 11.16,106.12 19.16,114.12 23.26,114.12 v4(25.91,116.77)
N103961319: length 3.7
  TOP w0.254: U55.M9 U55.N9 24.54,115.06 24.24,114.76 22.37,114.76 L23.2
N103961455: length 1.8
  TOP w0.254: U55.N11 24.02,114.16 23.09,113.24
N103961642: length 2.9
  TOP w0.127: R809.2 5.06,103.08 4.85,103.29 SW6.1
N103961796: length 2.3
  TOP w0.203: U55.G2 28.01,118.19 28.02,118.19 v4(28.02,118.19)
  BOTTOM w0.381: v4(28.02,118.19) 28.02,118.67 C350.1 R844.2
N103962355: length 19.7
  TOP w0.305: 4.6,117.37 4.6,118.26 ; 4.6,117.37 J53.9 3.85,117.37 3.79,117.43 ; 4.6,117.37 4.75,117.37 5.31,117.93
  TOP w0.381: 2.58,110.97 J53.7 1.45,110.17 ; L25.2 4.72,122.02 ; L25.2 4.72,120.96 ; L25.2 4.05,121.49 ; 1.45,120.12 J53.8 2.58,119.32 ; 5.39,112.92 J53.6 4.58,112.2
  L3_INT_1 w0.381: J53.6 4.58,113.63 ; J53.6 4.58,112.2 ; J53.6 3.76,112.92 ; J53.7 1.45,111.75 ; J53.7 2.58,110.97 ; J53.7 1.45,110.18 ; J53.9 4.58,118.08 ; J53.9 3.76,117.37 ; J53.9 4.58,116.65 ; 1.45,118.53 J53.8 ; J53.8 1.45,120.1 ; J53.8 2.58,119.32
N103962365: length 6.9
  TOP w0.381: 7.64,118.53 L24.1 ; L24.1 6.71,119.46 ; L24.1 7.64,120.39 ; 6.2,117.17 5.47,116.44 J53.1 ; U51.4 9.11,117.54 ; U51.4 9.59,117.11 ; U51.4 8.63,117.11 ; U51.4 9.11,116.67
